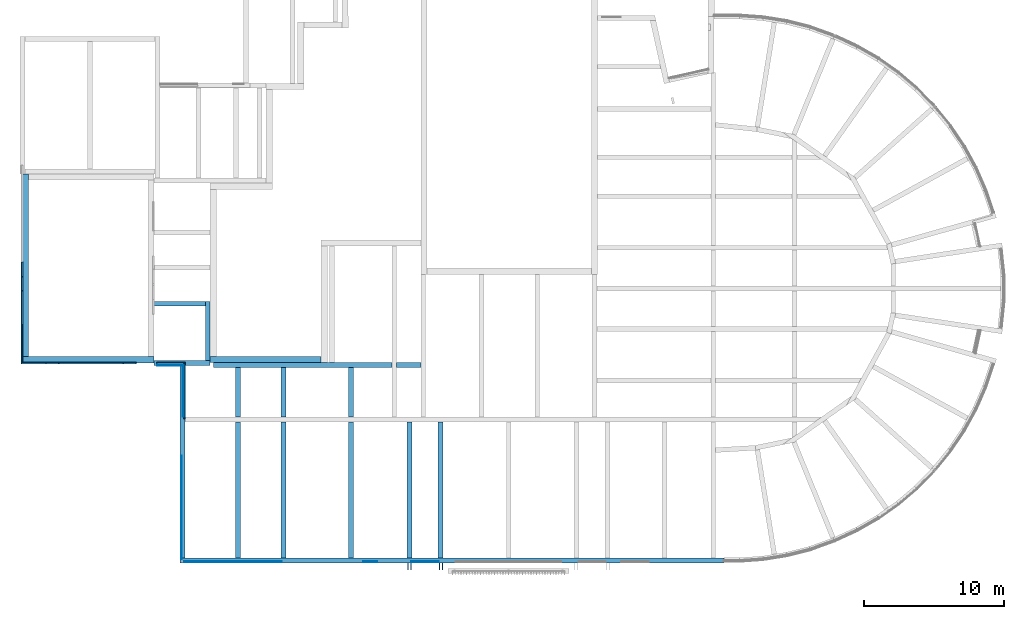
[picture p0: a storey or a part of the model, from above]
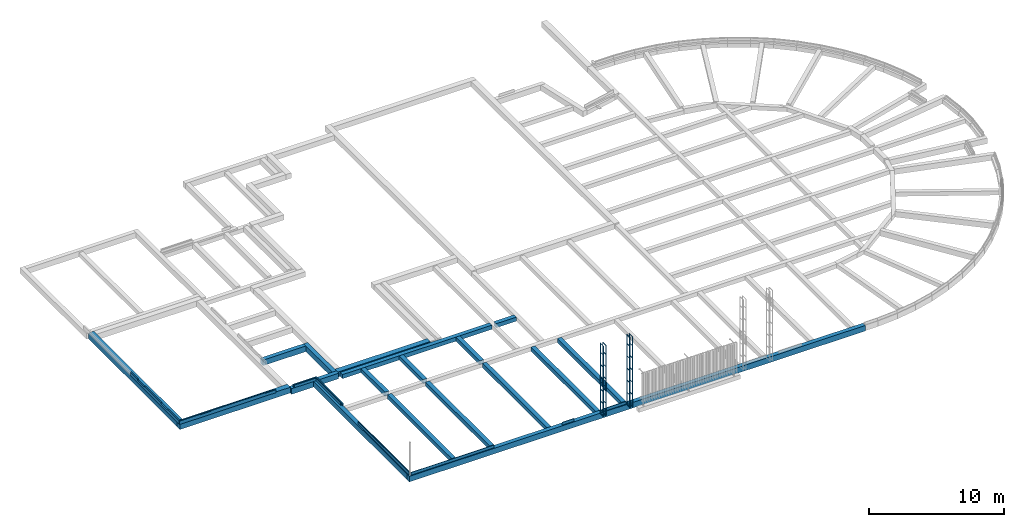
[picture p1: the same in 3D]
Properties of the parts of a building model (IFC2X3), part 1 of 13

# File
Description: ViewDefinition [CoordinationView_V2.0, QuantityTakeOffAddOnView]
File name: 6004
Time: 2023-06-22T15:44:40
Written by: The EXPRESS Data Manager Version 5.02.0100.07 : 28 Aug 2013
Made in: 21.1.70.21 - Exporter 21.1.70.21 - Alternate UI 21.1.70.21
Comment: STEP Physical File produced by: The EXPRESS Data Manager Version 5.02.0100.07 : 28 Aug 2013 * Module: EDMstepFileFactory/EDMstandAlone * Creation date: Thu Jun 22 15:44:40 2023 * Host: Erwin-HP * Database: C:\Users\hesselk\AppData\Local\Temp\bc33ba16-9f34-44f1-aad8-39bbdf71862f\c61a9778-cba0-4273-95be-3b692016d379\ifc * Database version: 5507 * Database creation date: Thu Jun 22 15:39:44 2023 * Schema: IFC2X3 * Model: DataRepository.ifc * Model creation date: Thu Jun 22 15:39:45 2023 * Header model: DataRepository.ifc_HeaderModel * Header model creation date: Thu Jun 22 15:39:45 2023 * EDMuser: sdai-user * EDMgroup: sdai-group * License ID and type: 5605 : Permanent license. Expiry date: * EDMstepFileFactory options: 020000

# IfcProject, 6004
LongName: -; Phase: -

# IfcSite, Default
RefLatitude: 42, 21, 29, 879999; RefLongitude: -71, -3, -37, -79999; RefElevation: 0 mm
Pset_ProductRequirements - Category: Project Information

# IfcBuilding, -
LongName: -
Pset_BuildingCommon - NumberOfStoreys: 6
Pset_ProductRequirements - Category: Project Information

# IfcBuildingStorey: Level:AL_Peilmaten 2.0mm (6)
In: -
Pset_ProductRequirements - Category: Levels
Name | LongName = Pset_AirSideSystemInformation, Name = Pset_ProductRequirements, Name | Elevation (mm)
ok. fundering | ok. fundering | -780
00 begane grond | 00 begane grond | -7.38712e-11
Podium | Podium | 1200
01 eerste verdieping | 01 eerste verdieping | 3070
02 tweede verdieping | 02 tweede verdieping | 6070
06 zesde verdieping | 06 zesde verdieping | 18000

# IfcSpace: Administratie voetbal 6.03:3263387, 6.03
In: 00 begane grond
LongName: Administratie voetbal; InteriorOrExteriorSpace: INTERNAL
Pset_AirSideSystemInformation - Name: Administratie voetbal
Pset_ProductRequirements - Name: Administratie voetbal; Category: Rooms
Pset_SpaceCommon - Reference: Administratie voetbal 6.03; Category: Rooms
BaseQuantities - NetFloorArea: 8.4643 m2; Height: 2438.4 mm; GrossPerimeter: 40.183 mm; GrossFloorArea: 8.4643 m2; GrossVolume: 20639.3 m3

# IfcSpace: BC A 11:6976725, 11
In: 00 begane grond
LongName: BC A; InteriorOrExteriorSpace: INTERNAL; Group: Brandveiligheid
Pset_AirSideSystemInformation - Name: BC A
Pset_ProductRequirements - Name: BC A; Category: Areas
Pset_SpaceCommon - Reference: BC A 11; Category: Areas
BaseQuantities - NetFloorArea: 449.811 m2; Height: 1200 mm; GrossPerimeter: 391.541 mm; GrossFloorArea: 449.811 m2; GrossVolume: 539773 m3

# IfcSpace: BC B 7:2298311, 7
In: 00 begane grond
LongName: BC B; InteriorOrExteriorSpace: INTERNAL; Group: Brandveiligheid
Pset_AirSideSystemInformation - Name: BC B
Pset_ProductRequirements - Name: BC B; Category: Areas
Pset_SpaceCommon - Reference: BC B 7; Category: Areas
BaseQuantities - NetFloorArea: 936.572 m2; Height: 1200 mm; GrossPerimeter: 518.34 mm; GrossFloorArea: 936.572 m2; GrossVolume: 1123886 m3

# IfcSpace: BC B 8:2298323, 8
In: 01 eerste verdieping
LongName: BC B; InteriorOrExteriorSpace: INTERNAL; Group: Brandveiligheid
Pset_AirSideSystemInformation - Name: BC B
Pset_ProductRequirements - Name: BC B; Category: Areas
Pset_SpaceCommon - Reference: BC B 8; Category: Areas
BaseQuantities - NetFloorArea: 56.1971 m2; Height: 3000 mm; GrossPerimeter: 138.341 mm; GrossFloorArea: 56.1971 m2; GrossVolume: 168591 m3

# IfcSpace: BC C 10:5124607, 10
In: 01 eerste verdieping
LongName: BC C; InteriorOrExteriorSpace: INTERNAL; Group: Brandveiligheid
Pset_AirSideSystemInformation - Name: BC C
Pset_ProductRequirements - Name: BC C; Category: Areas
Pset_SpaceCommon - Reference: BC C 10; Category: Areas
BaseQuantities - NetFloorArea: 155.31 m2; Height: 3000 mm; GrossPerimeter: 330.357 mm; GrossFloorArea: 155.31 m2; GrossVolume: 465931 m3

# IfcSpace: BC C 12:6977072, 12
In: 00 begane grond
LongName: BC C; InteriorOrExteriorSpace: INTERNAL; Group: Brandveiligheid
Pset_AirSideSystemInformation - Name: BC C
Pset_ProductRequirements - Name: BC C; Category: Areas
Pset_SpaceCommon - Reference: BC C 12; Category: Areas
BaseQuantities - NetFloorArea: 811.166 m2; Height: 1200 mm; GrossPerimeter: 441.673 mm; GrossFloorArea: 811.166 m2; GrossVolume: 973400 m3

# IfcSpace: BC D 13:6977868, 13
In: 00 begane grond
LongName: BC D; InteriorOrExteriorSpace: INTERNAL; Group: Brandveiligheid
Pset_AirSideSystemInformation - Name: BC D
Pset_ProductRequirements - Name: BC D; Category: Areas
Pset_SpaceCommon - Reference: BC D 13; Category: Areas
BaseQuantities - NetFloorArea: 117.255 m2; Height: 1200 mm; GrossPerimeter: 159.611 mm; GrossFloorArea: 117.255 m2; GrossVolume: 140705 m3

# IfcSpace: BSO 1.03:3280689, 1.03
In: 00 begane grond
LongName: BSO; InteriorOrExteriorSpace: INTERNAL
Pset_AirSideSystemInformation - Name: BSO
Pset_ProductRequirements - Name: BSO; Category: Rooms
Pset_SpaceCommon - Reference: BSO 1.03; Category: Rooms
BaseQuantities - NetFloorArea: 54.4511 m2; Height: 2438.4 mm; GrossPerimeter: 99.3768 mm; GrossFloorArea: 54.4511 m2; GrossVolume: 132774 m3

# IfcSpace: BVO 4:2298348, 4
In: 01 eerste verdieping
LongName: BVO; InteriorOrExteriorSpace: INTERNAL; Group: Brutovloeroppervlak
Pset_AirSideSystemInformation - Name: BVO
Pset_ProductRequirements - Name: BVO; Category: Areas
Pset_SpaceCommon - Reference: BVO 4; Category: Areas
BaseQuantities - NetFloorArea: 63.388 m2; Height: 3000 mm; GrossPerimeter: 143.938 mm; GrossFloorArea: 63.388 m2; GrossVolume: 190164 m3

# IfcSpace: BVO 5:2298363, 5
In: 00 begane grond
LongName: BVO; InteriorOrExteriorSpace: INTERNAL; Group: Brutovloeroppervlak
Pset_AirSideSystemInformation - Name: BVO
Pset_ProductRequirements - Name: BVO; Category: Areas
Pset_SpaceCommon - Reference: BVO 5; Category: Areas
BaseQuantities - NetFloorArea: 2433.13 m2; Height: 1200 mm; GrossPerimeter: 798.333 mm; GrossFloorArea: 2433.13 m2; GrossVolume: 2919752 m3

# IfcSpace: BVO 6:3586831, 6
In: 01 eerste verdieping
LongName: BVO; InteriorOrExteriorSpace: INTERNAL; Group: Brutovloeroppervlak
Pset_AirSideSystemInformation - Name: BVO
Pset_ProductRequirements - Name: BVO; Category: Areas
Pset_SpaceCommon - Reference: BVO 6; Category: Areas
BaseQuantities - NetFloorArea: 174.664 m2; Height: 3000 mm; GrossPerimeter: 341.474 mm; GrossFloorArea: 174.664 m2; GrossVolume: 523992 m3

# IfcSpace: Berging 11.04:3263366, 11.04
In: 00 begane grond
LongName: Berging; InteriorOrExteriorSpace: INTERNAL
Pset_AirSideSystemInformation - Name: Berging
Pset_ProductRequirements - Name: Berging; Category: Rooms
Pset_SpaceCommon - Reference: Berging 11.04; Category: Rooms
BaseQuantities - NetFloorArea: 17.4134 m2; Height: 2438.4 mm; GrossPerimeter: 57.5054 mm; GrossFloorArea: 17.4134 m2; GrossVolume: 42460.7 m3

# IfcSpace: Berging 11.05:3265393, 11.05
In: 00 begane grond
LongName: Berging; InteriorOrExteriorSpace: INTERNAL
Pset_AirSideSystemInformation - Name: Berging
Pset_ProductRequirements - Name: Berging; Category: Rooms
Pset_SpaceCommon - Reference: Berging 11.05; Category: Rooms
BaseQuantities - NetFloorArea: 8.32659 m2; Height: 2438.4 mm; GrossPerimeter: 37.8844 mm; GrossFloorArea: 8.32659 m2; GrossVolume: 20303.6 m3

# IfcSpace: Berging 11.06a:3265324, 11.06a
In: 00 begane grond
LongName: Berging; InteriorOrExteriorSpace: INTERNAL
Pset_AirSideSystemInformation - Name: Berging
Pset_ProductRequirements - Name: Berging; Category: Rooms
Pset_SpaceCommon - Reference: Berging 11.06a; Category: Rooms
BaseQuantities - NetFloorArea: 1.72208 m2; Height: 2438.4 mm; GrossPerimeter: 19.806 mm; GrossFloorArea: 1.72208 m2; GrossVolume: 4199.11 m3

# IfcSpace: Berging 11.06b:3265327, 11.06b
In: 00 begane grond
LongName: Berging; InteriorOrExteriorSpace: INTERNAL
Pset_AirSideSystemInformation - Name: Berging
Pset_ProductRequirements - Name: Berging; Category: Rooms
Pset_SpaceCommon - Reference: Berging 11.06b; Category: Rooms
BaseQuantities - NetFloorArea: 1.66091 m2; Height: 2438.4 mm; GrossPerimeter: 17.6163 mm; GrossFloorArea: 1.66091 m2; GrossVolume: 4049.96 m3

# IfcSpace: Berging 11.06c:3265330, 11.06c
In: 00 begane grond
LongName: Berging; InteriorOrExteriorSpace: INTERNAL
Pset_AirSideSystemInformation - Name: Berging
Pset_ProductRequirements - Name: Berging; Category: Rooms
Pset_SpaceCommon - Reference: Berging 11.06c; Category: Rooms
BaseQuantities - NetFloorArea: 1.66091 m2; Height: 2438.4 mm; GrossPerimeter: 17.6163 mm; GrossFloorArea: 1.66091 m2; GrossVolume: 4049.96 m3

# IfcSpace: Berging 11.06d:3265349, 11.06d
In: 00 begane grond
LongName: Berging; InteriorOrExteriorSpace: INTERNAL
Pset_AirSideSystemInformation - Name: Berging
Pset_ProductRequirements - Name: Berging; Category: Rooms
Pset_SpaceCommon - Reference: Berging 11.06d; Category: Rooms
BaseQuantities - NetFloorArea: 3.79612 m2; Height: 2438.4 mm; GrossPerimeter: 27.4507 mm; GrossFloorArea: 3.79612 m2; GrossVolume: 9256.46 m3

# IfcSpace: Berging 11.14:3268786, 11.14
In: 00 begane grond
LongName: Berging; InteriorOrExteriorSpace: INTERNAL
Pset_AirSideSystemInformation - Name: Berging
Pset_ProductRequirements - Name: Berging; Category: Rooms
Pset_SpaceCommon - Reference: Berging 11.14; Category: Rooms
BaseQuantities - NetFloorArea: 2.30979 m2; Height: 2438.4 mm; GrossPerimeter: 22.1874 mm; GrossFloorArea: 2.30979 m2; GrossVolume: 5632.2 m3

# IfcSpace: Berging 12.03:3287451, 12.03
In: 01 eerste verdieping
LongName: Berging; InteriorOrExteriorSpace: INTERNAL
Pset_AirSideSystemInformation - Name: Berging
Pset_ProductRequirements - Name: Berging; Category: Rooms
Pset_SpaceCommon - Reference: Berging 12.03; Category: Rooms
BaseQuantities - NetFloorArea: 4.04696 m2; Height: 2438.4 mm; GrossPerimeter: 30.0348 mm; GrossFloorArea: 4.04696 m2; GrossVolume: 9868.12 m3

# IfcSpace: Berging 12.04:3287454, 12.04
In: 01 eerste verdieping
LongName: Berging; InteriorOrExteriorSpace: INTERNAL
Pset_AirSideSystemInformation - Name: Berging
Pset_ProductRequirements - Name: Berging; Category: Rooms
Pset_SpaceCommon - Reference: Berging 12.04; Category: Rooms
BaseQuantities - NetFloorArea: 3.72298 m2; Height: 2438.4 mm; GrossPerimeter: 25.7972 mm; GrossFloorArea: 3.72298 m2; GrossVolume: 9078.13 m3

# IfcSpace: Berging 12.05:3287457, 12.05
In: 01 eerste verdieping
LongName: Berging; InteriorOrExteriorSpace: INTERNAL
Pset_AirSideSystemInformation - Name: Berging
Pset_ProductRequirements - Name: Berging; Category: Rooms
Pset_SpaceCommon - Reference: Berging 12.05; Category: Rooms
BaseQuantities - NetFloorArea: 3.72299 m2; Height: 2438.4 mm; GrossPerimeter: 25.7972 mm; GrossFloorArea: 3.72299 m2; GrossVolume: 9078.13 m3

# IfcSpace: Berging 4.07:3268208, 4.07
In: 00 begane grond
LongName: Berging; InteriorOrExteriorSpace: INTERNAL
Pset_AirSideSystemInformation - Name: Berging
Pset_ProductRequirements - Name: Berging; Category: Rooms
Pset_SpaceCommon - Reference: Berging 4.07; Category: Rooms
BaseQuantities - NetFloorArea: 10.9433 m2; Height: 2438.4 mm; GrossPerimeter: 43.0378 mm; GrossFloorArea: 10.9433 m2; GrossVolume: 26684.2 m3

# IfcSpace: Berging 4.08:4949645, 4.08
In: 00 begane grond
LongName: Berging; InteriorOrExteriorSpace: INTERNAL
Pset_AirSideSystemInformation - Name: Berging
Pset_ProductRequirements - Name: Berging; Category: Rooms
Pset_SpaceCommon - Reference: Berging 4.08; Category: Rooms
BaseQuantities - NetFloorArea: 2.02933 m2; Height: 2438.4 mm; GrossPerimeter: 18.7009 mm; GrossFloorArea: 2.02933 m2; GrossVolume: 4948.33 m3

# IfcSpace: Berging 5.01:3268748, 5.01
In: 00 begane grond
LongName: Berging; InteriorOrExteriorSpace: INTERNAL
Pset_AirSideSystemInformation - Name: Berging
Pset_ProductRequirements - Name: Berging; Category: Rooms
Pset_SpaceCommon - Reference: Berging 5.01; Category: Rooms
BaseQuantities - NetFloorArea: 12.0563 m2; Height: 2438.4 mm; GrossPerimeter: 50.4788 mm; GrossFloorArea: 12.0563 m2; GrossVolume: 29398 m3

# IfcSpace: Berging 7.05:3265260, 7.05
In: 00 begane grond
LongName: Berging; InteriorOrExteriorSpace: INTERNAL
Pset_AirSideSystemInformation - Name: Berging
Pset_ProductRequirements - Name: Berging; Category: Rooms
Pset_SpaceCommon - Reference: Berging 7.05; Category: Rooms
BaseQuantities - NetFloorArea: 9.78041 m2; Height: 2438.4 mm; GrossPerimeter: 46.732 mm; GrossFloorArea: 9.78041 m2; GrossVolume: 23848.6 m3

# IfcSpace: Berging 8.02b:3311547, 8.02b
In: 00 begane grond
LongName: Berging; InteriorOrExteriorSpace: INTERNAL
Pset_AirSideSystemInformation - Name: Berging
Pset_ProductRequirements - Name: Berging; Category: Rooms
Pset_SpaceCommon - Reference: Berging 8.02b; Category: Rooms
BaseQuantities - NetFloorArea: 2.63612 m2; Height: 3638.4 mm; GrossPerimeter: 21.5312 mm; GrossFloorArea: 2.63612 m2; GrossVolume: 9591.27 m3

# IfcSpace: Berging 8.02c:7828705, 8.02c
In: 00 begane grond
LongName: Berging; InteriorOrExteriorSpace: INTERNAL
Pset_AirSideSystemInformation - Name: Berging
Pset_ProductRequirements - Name: Berging; Category: Rooms
Pset_SpaceCommon - Reference: Berging 8.02c; Category: Rooms
BaseQuantities - NetFloorArea: 2.60797 m2; Height: 2438.4 mm; GrossPerimeter: 21.4609 mm; GrossFloorArea: 2.60797 m2; GrossVolume: 6359.27 m3

# IfcSpace: Berging 8.05:3380008, 8.05
In: 00 begane grond
LongName: Berging; InteriorOrExteriorSpace: INTERNAL
Pset_AirSideSystemInformation - Name: Berging
Pset_ProductRequirements - Name: Berging; Category: Rooms
Pset_SpaceCommon - Reference: Berging 8.05; Category: Rooms
BaseQuantities - NetFloorArea: 8.00827 m2; Height: 3638.4 mm; GrossPerimeter: 37.4456 mm; GrossFloorArea: 8.00827 m2; GrossVolume: 29137.3 m3

# IfcSpace: Berging 8.07:3392395, 8.07
In: 00 begane grond
LongName: Berging; InteriorOrExteriorSpace: INTERNAL
Pset_AirSideSystemInformation - Name: Berging
Pset_ProductRequirements - Name: Berging; Category: Rooms
Pset_SpaceCommon - Reference: Berging 8.07; Category: Rooms
BaseQuantities - NetFloorArea: 1.7259 m2; Height: 3638.4 mm; GrossPerimeter: 17.383 mm; GrossFloorArea: 1.7259 m2; GrossVolume: 6279.52 m3

# IfcSpace: Berging 8.08:3392398, 8.08
In: 00 begane grond
LongName: Berging; InteriorOrExteriorSpace: INTERNAL
Pset_AirSideSystemInformation - Name: Berging
Pset_ProductRequirements - Name: Berging; Category: Rooms
Pset_SpaceCommon - Reference: Berging 8.08; Category: Rooms
BaseQuantities - NetFloorArea: 4.03924 m2; Height: 3638.4 mm; GrossPerimeter: 27.6343 mm; GrossFloorArea: 4.03924 m2; GrossVolume: 14696.4 m3

# IfcSpace: Berging PSZ 14.01:11128473, 14.01
In: 00 begane grond
LongName: Berging PSZ; InteriorOrExteriorSpace: INTERNAL
Pset_AirSideSystemInformation - Name: Berging PSZ
Pset_ProductRequirements - Name: Berging PSZ; Category: Rooms
Pset_SpaceCommon - Reference: Berging PSZ 14.01; Category: Rooms
BaseQuantities - NetFloorArea: 4.39434 m2; Height: 2438.4 mm; GrossPerimeter: 28.0441 mm; GrossFloorArea: 4.39434 m2; GrossVolume: 10715.2 m3

# IfcSpace: Berging VV Jistrum 12.02:3287445, 12.02
In: 01 eerste verdieping
LongName: Berging VV Jistrum; InteriorOrExteriorSpace: INTERNAL
Pset_AirSideSystemInformation - Name: Berging VV Jistrum
Pset_ProductRequirements - Name: Berging VV Jistrum; Category: Rooms
Pset_SpaceCommon - Reference: Berging VV Jistrum 12.02; Category: Rooms
BaseQuantities - NetFloorArea: 16.7621 m2; Height: 2438.4 mm; GrossPerimeter: 62.2256 mm; GrossFloorArea: 16.7621 m2; GrossVolume: 40872.6 m3

# IfcSpace: Berging onderbouw 14.02:11859632, 14.02
In: 00 begane grond
LongName: Berging onderbouw; InteriorOrExteriorSpace: INTERNAL
Pset_AirSideSystemInformation - Name: Berging onderbouw
Pset_ProductRequirements - Name: Berging onderbouw; Category: Rooms
Pset_SpaceCommon - Reference: Berging onderbouw 14.02; Category: Rooms
BaseQuantities - NetFloorArea: 4.3973 m2; Height: 2438.4 mm; GrossPerimeter: 28.0517 mm; GrossFloorArea: 4.3973 m2; GrossVolume: 10722.4 m3

# IfcSpace: Berging voetbalvereniging 25:7525867, 25
In: 00 begane grond
LongName: Berging voetbalvereniging; InteriorOrExteriorSpace: INTERNAL; Group: Gebruiksfuncties
Pset_AirSideSystemInformation - Name: Berging voetbalvereniging
Pset_ProductRequirements - Name: Berging voetbalvereniging; Category: Areas
Pset_SpaceCommon - Reference: Berging voetbalvereniging 25; Category: Areas
BaseQuantities - NetFloorArea: 22.8241 m2; Height: 1200 mm; GrossPerimeter: 63.2824 mm; GrossFloorArea: 22.8241 m2; GrossVolume: 27389 m3

# IfcSpace: Bergingen + technische ruimtes 20:3609457, 20
In: 01 eerste verdieping
LongName: Bergingen + technische ruimtes; InteriorOrExteriorSpace: INTERNAL; Group: Gebruiksfuncties
Pset_AirSideSystemInformation - Name: Bergingen + technische ruimtes
Pset_ProductRequirements - Name: Bergingen + technische ruimtes; Category: Areas
Pset_SpaceCommon - Reference: Bergingen + technische ruimtes 20; Category: Areas
BaseQuantities - NetFloorArea: 166.087 m2; Height: 3000 mm; GrossPerimeter: 340.479 mm; GrossFloorArea: 166.087 m2; GrossVolume: 498261 m3

# IfcSpace: Bergingen 19:3606235, 19
In: 01 eerste verdieping
LongName: Bergingen; InteriorOrExteriorSpace: INTERNAL; Group: Gebruiksfuncties
Pset_AirSideSystemInformation - Name: Bergingen
Pset_ProductRequirements - Name: Bergingen; Category: Areas
Pset_SpaceCommon - Reference: Bergingen 19; Category: Areas
BaseQuantities - NetFloorArea: 54.2789 m2; Height: 3000 mm; GrossPerimeter: 153.587 mm; GrossFloorArea: 54.2789 m2; GrossVolume: 162837 m3

# IfcSpace: Bergruimte 1.04:3265390, 1.04
In: 00 begane grond
LongName: Bergruimte; InteriorOrExteriorSpace: INTERNAL
Pset_AirSideSystemInformation - Name: Bergruimte
Pset_ProductRequirements - Name: Bergruimte; Category: Rooms
Pset_SpaceCommon - Reference: Bergruimte 1.04; Category: Rooms
BaseQuantities - NetFloorArea: 5.01886 m2; Height: 2438.4 mm; GrossPerimeter: 31.8309 mm; GrossFloorArea: 5.01886 m2; GrossVolume: 12238 m3

# IfcSpace: Bergruimte 1.06:3265959, 1.06
In: 00 begane grond
LongName: Bergruimte; InteriorOrExteriorSpace: INTERNAL
Pset_AirSideSystemInformation - Name: Bergruimte
Pset_ProductRequirements - Name: Bergruimte; Category: Rooms
Pset_SpaceCommon - Reference: Bergruimte 1.06; Category: Rooms
BaseQuantities - NetFloorArea: 2.2577 m2; Height: 2438.4 mm; GrossPerimeter: 19.773 mm; GrossFloorArea: 2.2577 m2; GrossVolume: 5505.17 m3

# IfcSpace: Bergruimte muziekinstrumenten 9.01:3264976, 9.01
In: 00 begane grond
LongName: Bergruimte muziekinstrumenten; InteriorOrExteriorSpace: INTERNAL
Pset_AirSideSystemInformation - Name: Bergruimte muziekinstrumenten
Pset_ProductRequirements - Name: Bergruimte muziekinstrumenten; Category: Rooms
Pset_SpaceCommon - Reference: Bergruimte muziekinstrumenten 9.01; Category: Rooms
BaseQuantities - NetFloorArea: 20.3807 m2; Height: 2438.4 mm; GrossPerimeter: 60.1711 mm; GrossFloorArea: 20.3807 m2; GrossVolume: 49696.3 m3

# IfcSpace: Bergruimte toneelver. 10.01:3264979, 10.01
In: 00 begane grond
LongName: Bergruimte toneelver.; InteriorOrExteriorSpace: INTERNAL
Pset_AirSideSystemInformation - Name: Bergruimte toneelver.
Pset_ProductRequirements - Name: Bergruimte toneelver.; Category: Rooms
Pset_SpaceCommon - Reference: Bergruimte toneelver. 10.01; Category: Rooms
BaseQuantities - NetFloorArea: 18.8235 m2; Height: 2438.4 mm; GrossPerimeter: 57.2158 mm; GrossFloorArea: 18.8235 m2; GrossVolume: 45899.2 m3

# IfcSpace: Bestaande CV 8.06:3380005, 8.06
In: 00 begane grond
LongName: Bestaande CV; InteriorOrExteriorSpace: INTERNAL
Pset_AirSideSystemInformation - Name: Bestaande CV
Pset_ProductRequirements - Name: Bestaande CV; Category: Rooms
Pset_SpaceCommon - Reference: Bestaande CV 8.06; Category: Rooms
BaseQuantities - NetFloorArea: 5.72609 m2; Height: 3638.4 mm; GrossPerimeter: 30.5749 mm; GrossFloorArea: 5.72609 m2; GrossVolume: 20833.8 m3

# IfcSpace: Bestuurskamer / fysio 6.02:3263384, 6.02
In: 00 begane grond
LongName: Bestuurskamer / fysio; InteriorOrExteriorSpace: INTERNAL
Pset_AirSideSystemInformation - Name: Bestuurskamer / fysio
Pset_ProductRequirements - Name: Bestuurskamer / fysio; Category: Rooms
Pset_SpaceCommon - Reference: Bestuurskamer / fysio 6.02; Category: Rooms
BaseQuantities - NetFloorArea: 20.3856 m2; Height: 2438.4 mm; GrossPerimeter: 64.5981 mm; GrossFloorArea: 20.3856 m2; GrossVolume: 49708.3 m3

# IfcSpace: Bestuurskamer 7:3588425, 7
In: 00 begane grond
LongName: Bestuurskamer; InteriorOrExteriorSpace: INTERNAL; Group: Gebruiksfuncties
Pset_AirSideSystemInformation - Name: Bestuurskamer
Pset_ProductRequirements - Name: Bestuurskamer; Category: Areas
Pset_SpaceCommon - Reference: Bestuurskamer 7; Category: Areas
BaseQuantities - NetFloorArea: 47.44 m2; Height: 1200 mm; GrossPerimeter: 110.481 mm; GrossFloorArea: 47.44 m2; GrossVolume: 56928 m3

# IfcSpace: Buitenberging school 13.06:11094313, 13.06
In: 00 begane grond
LongName: Buitenberging school; InteriorOrExteriorSpace: INTERNAL
Pset_AirSideSystemInformation - Name: Buitenberging school
Pset_ProductRequirements - Name: Buitenberging school; Category: Rooms
Pset_SpaceCommon - Reference: Buitenberging school 13.06; Category: Rooms
BaseQuantities - NetFloorArea: 11.5448 m2; Height: 2438.4 mm; GrossPerimeter: 44.7064 mm; GrossFloorArea: 11.5448 m2; GrossVolume: 28150.7 m3

# IfcSpace: Centrale hal 4.01a:3309832, 4.01a
In: 00 begane grond
LongName: Centrale hal; InteriorOrExteriorSpace: INTERNAL
Pset_AirSideSystemInformation - Name: Centrale hal
Pset_ProductRequirements - Name: Centrale hal; Category: Rooms
Pset_SpaceCommon - Reference: Centrale hal 4.01a; Category: Rooms
BaseQuantities - NetFloorArea: 149.393 m2; Height: 3638.4 mm; GrossPerimeter: 235.245 mm; GrossFloorArea: 149.393 m2; GrossVolume: 543553 m3

# IfcSpace: Containerberging school 13.07:11094310, 13.07
In: 00 begane grond
LongName: Containerberging school; InteriorOrExteriorSpace: INTERNAL
Pset_AirSideSystemInformation - Name: Containerberging school
Pset_ProductRequirements - Name: Containerberging school; Category: Rooms
Pset_SpaceCommon - Reference: Containerberging school 13.07; Category: Rooms
BaseQuantities - NetFloorArea: 6.15039 m2; Height: 2438.4 mm; GrossPerimeter: 35.0148 mm; GrossFloorArea: 6.15039 m2; GrossVolume: 14997.1 m3

# IfcSpace: Directie 3.01:3269067, 3.01
In: 00 begane grond
LongName: Directie; InteriorOrExteriorSpace: INTERNAL
Pset_AirSideSystemInformation - Name: Directie
Pset_ProductRequirements - Name: Directie; Category: Rooms
Pset_SpaceCommon - Reference: Directie 3.01; Category: Rooms
BaseQuantities - NetFloorArea: 8.87652 m2; Height: 2438.4 mm; GrossPerimeter: 39.2078 mm; GrossFloorArea: 8.87652 m2; GrossVolume: 21644.5 m3

# IfcSpace: Douche 6.01a:3265178, 6.01a
In: 00 begane grond
LongName: Douche; InteriorOrExteriorSpace: INTERNAL
Pset_AirSideSystemInformation - Name: Douche
Pset_ProductRequirements - Name: Douche; Category: Rooms
Pset_SpaceCommon - Reference: Douche 6.01a; Category: Rooms
BaseQuantities - NetFloorArea: 10.0789 m2; Height: 2438.4 mm; GrossPerimeter: 50.229 mm; GrossFloorArea: 10.0789 m2; GrossVolume: 24576.4 m3

# IfcSpace: Douche 6.01b:3265175, 6.01b
In: 00 begane grond
LongName: Douche; InteriorOrExteriorSpace: INTERNAL
Pset_AirSideSystemInformation - Name: Douche
Pset_ProductRequirements - Name: Douche; Category: Rooms
Pset_SpaceCommon - Reference: Douche 6.01b; Category: Rooms
BaseQuantities - NetFloorArea: 10.0927 m2; Height: 2438.4 mm; GrossPerimeter: 50.3743 mm; GrossFloorArea: 10.0927 m2; GrossVolume: 24609.9 m3

# IfcSpace: Douche 6.01c:3264598, 6.01c
In: 00 begane grond
LongName: Douche; InteriorOrExteriorSpace: INTERNAL
Pset_AirSideSystemInformation - Name: Douche
Pset_ProductRequirements - Name: Douche; Category: Rooms
Pset_SpaceCommon - Reference: Douche 6.01c; Category: Rooms
BaseQuantities - NetFloorArea: 8.40022 m2; Height: 2438.4 mm; GrossPerimeter: 38.129 mm; GrossFloorArea: 8.40022 m2; GrossVolume: 20483.1 m3

# IfcSpace: Douche 6.01d:3264601, 6.01d
In: 00 begane grond
LongName: Douche; InteriorOrExteriorSpace: INTERNAL
Pset_AirSideSystemInformation - Name: Douche
Pset_ProductRequirements - Name: Douche; Category: Rooms
Pset_SpaceCommon - Reference: Douche 6.01d; Category: Rooms
BaseQuantities - NetFloorArea: 8.40942 m2; Height: 2438.4 mm; GrossPerimeter: 38.1579 mm; GrossFloorArea: 8.40942 m2; GrossVolume: 20505.5 m3

# IfcSpace: Entree 1.12:3392424, 1.12
In: 00 begane grond
LongName: Entree; InteriorOrExteriorSpace: INTERNAL
Pset_AirSideSystemInformation - Name: Entree
Pset_ProductRequirements - Name: Entree; Category: Rooms
Pset_SpaceCommon - Reference: Entree 1.12; Category: Rooms
BaseQuantities - NetFloorArea: 9.98155 m2; Height: 3638.4 mm; GrossPerimeter: 49.3727 mm; GrossFloorArea: 9.98155 m2; GrossVolume: 36316.9 m3

# IfcSpace: Entree 2.06:3392420, 2.06
In: 00 begane grond
LongName: Entree; InteriorOrExteriorSpace: INTERNAL
Pset_AirSideSystemInformation - Name: Entree
Pset_ProductRequirements - Name: Entree; Category: Rooms
Pset_SpaceCommon - Reference: Entree 2.06; Category: Rooms
BaseQuantities - NetFloorArea: 9.9318 m2; Height: 3638.4 mm; GrossPerimeter: 49.1059 mm; GrossFloorArea: 9.9318 m2; GrossVolume: 36135.9 m3

# IfcSpace: Entree 7.02:3302024, 7.02
In: 00 begane grond
LongName: Entree; InteriorOrExteriorSpace: INTERNAL
Pset_AirSideSystemInformation - Name: Entree
Pset_ProductRequirements - Name: Entree; Category: Rooms
Pset_SpaceCommon - Reference: Entree 7.02; Category: Rooms
BaseQuantities - NetFloorArea: 27.2496 m2; Height: 2438.4 mm; GrossPerimeter: 95.6493 mm; GrossFloorArea: 27.2496 m2; GrossVolume: 66445.4 m3

# IfcSpace: Entree 8.04:3307013, 8.04
In: 00 begane grond
LongName: Entree; InteriorOrExteriorSpace: INTERNAL
Pset_AirSideSystemInformation - Name: Entree
Pset_ProductRequirements - Name: Entree; Category: Rooms
Pset_SpaceCommon - Reference: Entree 8.04; Category: Rooms
BaseQuantities - NetFloorArea: 20.4821 m2; Height: 2438.4 mm; GrossPerimeter: 84.1245 mm; GrossFloorArea: 20.4821 m2; GrossVolume: 49943.6 m3

# IfcSpace: Expo ruimte 4.02a:4339103, 4.02a
In: 00 begane grond
LongName: Expo ruimte; InteriorOrExteriorSpace: INTERNAL
Pset_AirSideSystemInformation - Name: Expo ruimte
Pset_ProductRequirements - Name: Expo ruimte; Category: Rooms
Pset_SpaceCommon - Reference: Expo ruimte 4.02a; Category: Rooms
BaseQuantities - NetFloorArea: 1.94208 m2; Height: 2438.4 mm; GrossPerimeter: 26.6027 mm; GrossFloorArea: 1.94208 m2; GrossVolume: 4735.58 m3

# IfcSpace: Expo ruimte 4.02b:4339106, 4.02b
In: 00 begane grond
LongName: Expo ruimte; InteriorOrExteriorSpace: INTERNAL
Pset_AirSideSystemInformation - Name: Expo ruimte
Pset_ProductRequirements - Name: Expo ruimte; Category: Rooms
Pset_SpaceCommon - Reference: Expo ruimte 4.02b; Category: Rooms
BaseQuantities - NetFloorArea: 1.94125 m2; Height: 2438.4 mm; GrossPerimeter: 26.5928 mm; GrossFloorArea: 1.94125 m2; GrossVolume: 4733.55 m3

# IfcSpace: Expo ruimte 4.02d:3265968, 4.02d
In: 00 begane grond
LongName: Expo ruimte; InteriorOrExteriorSpace: INTERNAL
Pset_AirSideSystemInformation - Name: Expo ruimte
Pset_ProductRequirements - Name: Expo ruimte; Category: Rooms
Pset_SpaceCommon - Reference: Expo ruimte 4.02d; Category: Rooms
BaseQuantities - NetFloorArea: 1.79453 m2; Height: 2438.4 mm; GrossPerimeter: 24.7865 mm; GrossFloorArea: 1.79453 m2; GrossVolume: 4375.78 m3

# IfcSpace: GO Kinderdagverblijf 18:3634405, 18
In: 00 begane grond
LongName: GO Kinderdagverblijf; InteriorOrExteriorSpace: INTERNAL; Group: Gebruiksoppervlak
Pset_AirSideSystemInformation - Name: GO Kinderdagverblijf
Pset_ProductRequirements - Name: GO Kinderdagverblijf; Category: Areas
Pset_SpaceCommon - Reference: GO Kinderdagverblijf 18; Category: Areas
BaseQuantities - NetFloorArea: 86.8328 m2; Height: 1200 mm; GrossPerimeter: 136.242 mm; GrossFloorArea: 86.8328 m2; GrossVolume: 104199 m3

# IfcSpace: GO Kleedkamers 1 11:3630911, 11
In: 00 begane grond
LongName: GO Kleedkamers 1; InteriorOrExteriorSpace: INTERNAL; Group: Gebruiksoppervlak
Pset_AirSideSystemInformation - Name: GO Kleedkamers 1
Pset_ProductRequirements - Name: GO Kleedkamers 1; Category: Areas
Pset_SpaceCommon - Reference: GO Kleedkamers 1 11; Category: Areas
BaseQuantities - NetFloorArea: 48.8225 m2; Height: 1200 mm; GrossPerimeter: 94.2855 mm; GrossFloorArea: 48.8225 m2; GrossVolume: 58587 m3

# IfcSpace: GO Kleedkamers 2 14:3632022, 14
In: 00 begane grond
LongName: GO Kleedkamers 2; InteriorOrExteriorSpace: INTERNAL; Group: Gebruiksoppervlak
Pset_AirSideSystemInformation - Name: GO Kleedkamers 2
Pset_ProductRequirements - Name: GO Kleedkamers 2; Category: Areas
Pset_SpaceCommon - Reference: GO Kleedkamers 2 14; Category: Areas
BaseQuantities - NetFloorArea: 60.3817 m2; Height: 1200 mm; GrossPerimeter: 101.976 mm; GrossFloorArea: 60.3817 m2; GrossVolume: 72458 m3

# IfcSpace: GO Podium + zaal 15:3632874, 15
In: 00 begane grond
LongName: GO Podium + zaal; InteriorOrExteriorSpace: INTERNAL; Group: Gebruiksoppervlak
Pset_AirSideSystemInformation - Name: GO Podium + zaal
Pset_ProductRequirements - Name: GO Podium + zaal; Category: Areas
Pset_SpaceCommon - Reference: GO Podium + zaal 15; Category: Areas
BaseQuantities - NetFloorArea: 332.83 m2; Height: 1200 mm; GrossPerimeter: 334.996 mm; GrossFloorArea: 332.83 m2; GrossVolume: 399396 m3

# IfcSpace: GO Soosruimte 12:3631570, 12
In: 00 begane grond
LongName: GO Soosruimte; InteriorOrExteriorSpace: INTERNAL; Group: Gebruiksoppervlak
Pset_AirSideSystemInformation - Name: GO Soosruimte
Pset_ProductRequirements - Name: GO Soosruimte; Category: Areas
Pset_SpaceCommon - Reference: GO Soosruimte 12; Category: Areas
BaseQuantities - NetFloorArea: 90.2493 m2; Height: 1200 mm; GrossPerimeter: 132.764 mm; GrossFloorArea: 90.2493 m2; GrossVolume: 108299 m3

# IfcSpace: GO Sportzaal + kleedkamers 16:3633730, 16
In: 00 begane grond
LongName: GO Sportzaal + kleedkamers; InteriorOrExteriorSpace: INTERNAL; Group: Gebruiksoppervlak
Pset_AirSideSystemInformation - Name: GO Sportzaal + kleedkamers
Pset_ProductRequirements - Name: GO Sportzaal + kleedkamers; Category: Areas
Pset_SpaceCommon - Reference: GO Sportzaal + kleedkamers 16; Category: Areas
BaseQuantities - NetFloorArea: 402.83 m2; Height: 1200 mm; GrossPerimeter: 289.97 mm; GrossFloorArea: 402.83 m2; GrossVolume: 483395 m3

# IfcSpace: GO Vergaderkamer 13:3631810, 13
In: 00 begane grond
LongName: GO Vergaderkamer; InteriorOrExteriorSpace: INTERNAL; Group: Gebruiksoppervlak
Pset_AirSideSystemInformation - Name: GO Vergaderkamer
Pset_ProductRequirements - Name: GO Vergaderkamer; Category: Areas
Pset_SpaceCommon - Reference: GO Vergaderkamer 13; Category: Areas
BaseQuantities - NetFloorArea: 24.8009 m2; Height: 1200 mm; GrossPerimeter: 66.0152 mm; GrossFloorArea: 24.8009 m2; GrossVolume: 29761 m3

# IfcSpace: GO bergingen 7:3624988, 7
In: 01 eerste verdieping
LongName: GO bergingen; InteriorOrExteriorSpace: INTERNAL; Group: Gebruiksoppervlak
Pset_AirSideSystemInformation - Name: GO bergingen
Pset_ProductRequirements - Name: GO bergingen; Category: Areas
Pset_SpaceCommon - Reference: GO bergingen 7; Category: Areas
BaseQuantities - NetFloorArea: 50.2033 m2; Height: 3000 mm; GrossPerimeter: 151.056 mm; GrossFloorArea: 50.2033 m2; GrossVolume: 150610 m3

# IfcSpace: GO bergingen en technische ruimtes 8:3625776, 8
In: 01 eerste verdieping
LongName: GO bergingen en technische ruimtes; InteriorOrExteriorSpace: INTERNAL; Group: Gebruiksoppervlak
Pset_AirSideSystemInformation - Name: GO bergingen en technische ruimtes
Pset_ProductRequirements - Name: GO bergingen en technische ruimtes; Category: Areas
Pset_SpaceCommon - Reference: GO bergingen en technische ruimtes 8; Category: Areas
BaseQuantities - NetFloorArea: 156.093 m2; Height: 3000 mm; GrossPerimeter: 331.513 mm; GrossFloorArea: 156.093 m2; GrossVolume: 468279 m3

# IfcSpace: GO bestuurskamer 10:3630716, 10
In: 00 begane grond
LongName: GO bestuurskamer; InteriorOrExteriorSpace: INTERNAL; Group: Gebruiksoppervlak
Pset_AirSideSystemInformation - Name: GO bestuurskamer
Pset_ProductRequirements - Name: GO bestuurskamer; Category: Areas
Pset_SpaceCommon - Reference: GO bestuurskamer 10; Category: Areas
BaseQuantities - NetFloorArea: 64.8273 m2; Height: 1200 mm; GrossPerimeter: 151.338 mm; GrossFloorArea: 64.8273 m2; GrossVolume: 77792.8 m3

# IfcSpace: GO gang + bergingen 21:3637358, 21
In: 00 begane grond
LongName: GO gang + bergingen; InteriorOrExteriorSpace: INTERNAL; Group: Gebruiksoppervlak
Pset_AirSideSystemInformation - Name: GO gang + bergingen
Pset_ProductRequirements - Name: GO gang + bergingen; Category: Areas
Pset_SpaceCommon - Reference: GO gang + bergingen 21; Category: Areas
BaseQuantities - NetFloorArea: 142.781 m2; Height: 1200 mm; GrossPerimeter: 366.114 mm; GrossFloorArea: 142.781 m2; GrossVolume: 171337 m3

# IfcSpace: GO gang 20:3636409, 20
In: 00 begane grond
LongName: GO gang; InteriorOrExteriorSpace: INTERNAL; Group: Gebruiksoppervlak
Pset_AirSideSystemInformation - Name: GO gang
Pset_ProductRequirements - Name: GO gang; Category: Areas
Pset_SpaceCommon - Reference: GO gang 20; Category: Areas
BaseQuantities - NetFloorArea: 25.6534 m2; Height: 1200 mm; GrossPerimeter: 107.547 mm; GrossFloorArea: 25.6534 m2; GrossVolume: 30784 m3

# IfcSpace: GO school 19:3635566, 19
In: 00 begane grond
LongName: GO school; InteriorOrExteriorSpace: INTERNAL; Group: Gebruiksoppervlak
Pset_AirSideSystemInformation - Name: GO school
Pset_ProductRequirements - Name: GO school; Category: Areas
Pset_SpaceCommon - Reference: GO school 19; Category: Areas
BaseQuantities - NetFloorArea: 794.133 m2; Height: 1200 mm; GrossPerimeter: 424.925 mm; GrossFloorArea: 794.133 m2; GrossVolume: 952960 m3

# IfcSpace: GO sportkantine 5:2298405, 5
In: 00 begane grond
LongName: GO sportkantine; InteriorOrExteriorSpace: INTERNAL; Group: Gebruiksoppervlak
Pset_AirSideSystemInformation - Name: GO sportkantine
Pset_ProductRequirements - Name: GO sportkantine; Category: Areas
Pset_SpaceCommon - Reference: GO sportkantine 5; Category: Areas
BaseQuantities - NetFloorArea: 214.636 m2; Height: 1200 mm; GrossPerimeter: 204.04 mm; GrossFloorArea: 214.636 m2; GrossVolume: 257564 m3

# IfcSpace: GO technische ruimtes 17:3634043, 17
In: 00 begane grond
LongName: GO technische ruimtes; InteriorOrExteriorSpace: INTERNAL; Group: Gebruiksoppervlak
Pset_AirSideSystemInformation - Name: GO technische ruimtes
Pset_ProductRequirements - Name: GO technische ruimtes; Category: Areas
Pset_SpaceCommon - Reference: GO technische ruimtes 17; Category: Areas
BaseQuantities - NetFloorArea: 13.773 m2; Height: 1200 mm; GrossPerimeter: 52.7448 mm; GrossFloorArea: 13.773 m2; GrossVolume: 16527.6 m3

# IfcSpace: Gang + Bergingen + toilet 16:3604358, 16
In: 00 begane grond
LongName: Gang + Bergingen + toilet; InteriorOrExteriorSpace: INTERNAL; Group: Gebruiksfuncties
Pset_AirSideSystemInformation - Name: Gang + Bergingen + toilet
Pset_ProductRequirements - Name: Gang + Bergingen + toilet; Category: Areas
Pset_SpaceCommon - Reference: Gang + Bergingen + toilet 16; Category: Areas
BaseQuantities - NetFloorArea: 160.273 m2; Height: 1200 mm; GrossPerimeter: 312.356 mm; GrossFloorArea: 160.273 m2; GrossVolume: 192328 m3

# IfcSpace: Gang 1.09a:3265369, 1.09a
In: 00 begane grond
LongName: Gang; InteriorOrExteriorSpace: INTERNAL
Pset_AirSideSystemInformation - Name: Gang
Pset_ProductRequirements - Name: Gang; Category: Rooms
Pset_SpaceCommon - Reference: Gang 1.09a; Category: Rooms
BaseQuantities - NetFloorArea: 14.3951 m2; Height: 2438.4 mm; GrossPerimeter: 63.717 mm; GrossFloorArea: 14.3951 m2; GrossVolume: 35101 m3

# IfcSpace: Gang 1.09b:3265378, 1.09b
In: 00 begane grond
LongName: Gang; InteriorOrExteriorSpace: INTERNAL
Pset_AirSideSystemInformation - Name: Gang
Pset_ProductRequirements - Name: Gang; Category: Rooms
Pset_SpaceCommon - Reference: Gang 1.09b; Category: Rooms
BaseQuantities - NetFloorArea: 6.18488 m2; Height: 2438.4 mm; GrossPerimeter: 34.9854 mm; GrossFloorArea: 6.18488 m2; GrossVolume: 15081.2 m3

# IfcSpace: Gang 11.08:3263378, 11.08
In: 00 begane grond
LongName: Gang; InteriorOrExteriorSpace: INTERNAL
Pset_AirSideSystemInformation - Name: Gang
Pset_ProductRequirements - Name: Gang; Category: Rooms
Pset_SpaceCommon - Reference: Gang 11.08; Category: Rooms
BaseQuantities - NetFloorArea: 60.6761 m2; Height: 2438.4 mm; GrossPerimeter: 150.511 mm; GrossFloorArea: 60.6761 m2; GrossVolume: 147953 m3

# IfcSpace: Gang 12.01:3287448, 12.01
In: 01 eerste verdieping
LongName: Gang; InteriorOrExteriorSpace: INTERNAL
Pset_AirSideSystemInformation - Name: Gang
Pset_ProductRequirements - Name: Gang; Category: Rooms
Pset_SpaceCommon - Reference: Gang 12.01; Category: Rooms
BaseQuantities - NetFloorArea: 10.2709 m2; Height: 2438.4 mm; GrossPerimeter: 57.126 mm; GrossFloorArea: 10.2709 m2; GrossVolume: 25044.6 m3

# IfcSpace: Gang 24:3628824, 24
In: 00 begane grond
LongName: Gang; InteriorOrExteriorSpace: INTERNAL; Group: Gebruiksfuncties
Pset_AirSideSystemInformation - Name: Gang
Pset_ProductRequirements - Name: Gang; Category: Areas
Pset_SpaceCommon - Reference: Gang 24; Category: Areas
BaseQuantities - NetFloorArea: 28.2008 m2; Height: 1200 mm; GrossPerimeter: 110.242 mm; GrossFloorArea: 28.2008 m2; GrossVolume: 33840.9 m3

# IfcSpace: Gang 5.07:7151613, 5.07
In: 01 eerste verdieping
LongName: Gang; InteriorOrExteriorSpace: INTERNAL
Pset_AirSideSystemInformation - Name: Gang
Pset_ProductRequirements - Name: Gang; Category: Rooms
Pset_SpaceCommon - Reference: Gang 5.07; Category: Rooms
BaseQuantities - NetFloorArea: 9.59977 m2; Height: 2438.4 mm; GrossPerimeter: 42.5853 mm; GrossFloorArea: 9.59977 m2; GrossVolume: 23408.1 m3

# IfcSpace: Gang 5.08:7151717, 5.08
In: 01 eerste verdieping
LongName: Gang; InteriorOrExteriorSpace: INTERNAL
Pset_AirSideSystemInformation - Name: Gang
Pset_ProductRequirements - Name: Gang; Category: Rooms
Pset_SpaceCommon - Reference: Gang 5.08; Category: Rooms
BaseQuantities - NetFloorArea: 10.1216 m2; Height: 2438.4 mm; GrossPerimeter: 44.2178 mm; GrossFloorArea: 10.1216 m2; GrossVolume: 24680.5 m3

# IfcSpace: Gang 6.06:3264346, 6.06
In: 00 begane grond
LongName: Gang; InteriorOrExteriorSpace: INTERNAL
Pset_AirSideSystemInformation - Name: Gang
Pset_ProductRequirements - Name: Gang; Category: Rooms
Pset_SpaceCommon - Reference: Gang 6.06; Category: Rooms
BaseQuantities - NetFloorArea: 50.7037 m2; Height: 2438.4 mm; GrossPerimeter: 116.539 mm; GrossFloorArea: 50.7037 m2; GrossVolume: 123636 m3

# IfcSpace: Geluidskast 5.05:6102473, 5.05
In: 00 begane grond
LongName: Geluidskast; InteriorOrExteriorSpace: INTERNAL
Pset_AirSideSystemInformation - Name: Geluidskast
Pset_ProductRequirements - Name: Geluidskast; Category: Rooms
Pset_SpaceCommon - Reference: Geluidskast 5.05; Category: Rooms
BaseQuantities - NetFloorArea: 0.266119 m2; Height: 2438.4 mm; GrossPerimeter: 7.2607 mm; GrossFloorArea: 0.266119 m2; GrossVolume: 648.904 m3

# IfcSpace: Hoofdentree 11.07:3263381, 11.07
In: 00 begane grond
LongName: Hoofdentree; InteriorOrExteriorSpace: INTERNAL
Pset_AirSideSystemInformation - Name: Hoofdentree
Pset_ProductRequirements - Name: Hoofdentree; Category: Rooms
Pset_SpaceCommon - Reference: Hoofdentree 11.07; Category: Rooms
BaseQuantities - NetFloorArea: 15.4159 m2; Height: 2438.4 mm; GrossPerimeter: 48.5878 mm; GrossFloorArea: 15.4159 m2; GrossVolume: 37590.2 m3

# IfcSpace: Hoofdentree 2.04:3269089, 2.04
In: 00 begane grond
LongName: Hoofdentree; InteriorOrExteriorSpace: INTERNAL
Pset_AirSideSystemInformation - Name: Hoofdentree
Pset_ProductRequirements - Name: Hoofdentree; Category: Rooms
Pset_SpaceCommon - Reference: Hoofdentree 2.04; Category: Rooms
BaseQuantities - NetFloorArea: 14.6226 m2; Height: 2438.4 mm; GrossPerimeter: 55.8084 mm; GrossFloorArea: 14.6226 m2; GrossVolume: 35655.7 m3

# IfcSpace: IB-ruimte 3.02:3269064, 3.02
In: 00 begane grond
LongName: IB-ruimte; InteriorOrExteriorSpace: INTERNAL
Pset_AirSideSystemInformation - Name: IB-ruimte
Pset_ProductRequirements - Name: IB-ruimte; Category: Rooms
Pset_SpaceCommon - Reference: IB-ruimte 3.02; Category: Rooms
BaseQuantities - NetFloorArea: 8.78853 m2; Height: 2438.4 mm; GrossPerimeter: 39.2556 mm; GrossFloorArea: 8.78853 m2; GrossVolume: 21429.9 m3

# IfcSpace: Ingang kinderopvang 1.08:3265358, 1.08
In: 00 begane grond
LongName: Ingang kinderopvang; InteriorOrExteriorSpace: INTERNAL
Pset_AirSideSystemInformation - Name: Ingang kinderopvang
Pset_ProductRequirements - Name: Ingang kinderopvang; Category: Rooms
Pset_SpaceCommon - Reference: Ingang kinderopvang 1.08; Category: Rooms
BaseQuantities - NetFloorArea: 6.83836 m2; Height: 2438.4 mm; GrossPerimeter: 34.0845 mm; GrossFloorArea: 6.83836 m2; GrossVolume: 16674.7 m3

# IfcSpace: Instructieruimte 1.01a:3280686, 1.01a
In: 00 begane grond
LongName: Instructieruimte; InteriorOrExteriorSpace: INTERNAL
Pset_AirSideSystemInformation - Name: Instructieruimte
Pset_ProductRequirements - Name: Instructieruimte; Category: Rooms
Pset_SpaceCommon - Reference: Instructieruimte 1.01a; Category: Rooms
BaseQuantities - NetFloorArea: 53.4646 m2; Height: 2438.4 mm; GrossPerimeter: 92.9109 mm; GrossFloorArea: 53.4646 m2; GrossVolume: 130368 m3

# IfcSpace: Instructieruimte 1.01b:3280683, 1.01b
In: 00 begane grond
LongName: Instructieruimte; InteriorOrExteriorSpace: INTERNAL
Pset_AirSideSystemInformation - Name: Instructieruimte
Pset_ProductRequirements - Name: Instructieruimte; Category: Rooms
Pset_SpaceCommon - Reference: Instructieruimte 1.01b; Category: Rooms
BaseQuantities - NetFloorArea: 53.6196 m2; Height: 2438.4 mm; GrossPerimeter: 93.0502 mm; GrossFloorArea: 53.6196 m2; GrossVolume: 130746 m3

# IfcSpace: Instructieruimte 2.01:3280671, 2.01
In: 00 begane grond
LongName: Instructieruimte; InteriorOrExteriorSpace: INTERNAL
Pset_AirSideSystemInformation - Name: Instructieruimte
Pset_ProductRequirements - Name: Instructieruimte; Category: Rooms
Pset_SpaceCommon - Reference: Instructieruimte 2.01; Category: Rooms
BaseQuantities - NetFloorArea: 55.4637 m2; Height: 2438.4 mm; GrossPerimeter: 96.8524 mm; GrossFloorArea: 55.4637 m2; GrossVolume: 135243 m3

# IfcSpace: Instructieruimte 2.02a:3280674, 2.02a
In: 00 begane grond
LongName: Instructieruimte; InteriorOrExteriorSpace: INTERNAL
Pset_AirSideSystemInformation - Name: Instructieruimte
Pset_ProductRequirements - Name: Instructieruimte; Category: Rooms
Pset_SpaceCommon - Reference: Instructieruimte 2.02a; Category: Rooms
BaseQuantities - NetFloorArea: 53.4535 m2; Height: 2438.4 mm; GrossPerimeter: 92.9399 mm; GrossFloorArea: 53.4535 m2; GrossVolume: 130341 m3

# IfcSpace: Instructieruimte 2.02b:3280677, 2.02b
In: 00 begane grond
LongName: Instructieruimte; InteriorOrExteriorSpace: INTERNAL
Pset_AirSideSystemInformation - Name: Instructieruimte
Pset_ProductRequirements - Name: Instructieruimte; Category: Rooms
Pset_SpaceCommon - Reference: Instructieruimte 2.02b; Category: Rooms
BaseQuantities - NetFloorArea: 53.7708 m2; Height: 2438.4 mm; GrossPerimeter: 93.0068 mm; GrossFloorArea: 53.7708 m2; GrossVolume: 131115 m3

# IfcSpace: Keuken 11.03:3263363, 11.03
In: 00 begane grond
LongName: Keuken; InteriorOrExteriorSpace: INTERNAL
Pset_AirSideSystemInformation - Name: Keuken
Pset_ProductRequirements - Name: Keuken; Category: Rooms
Pset_SpaceCommon - Reference: Keuken 11.03; Category: Rooms
BaseQuantities - NetFloorArea: 18.4344 m2; Height: 2438.4 mm; GrossPerimeter: 58.9666 mm; GrossFloorArea: 18.4344 m2; GrossVolume: 44950.4 m3

# IfcSpace: Kinderdagverblijf 23:3628219, 23
In: 00 begane grond
LongName: Kinderdagverblijf; InteriorOrExteriorSpace: INTERNAL; Group: Gebruiksfuncties
Pset_AirSideSystemInformation - Name: Kinderdagverblijf
Pset_ProductRequirements - Name: Kinderdagverblijf; Category: Areas
Pset_SpaceCommon - Reference: Kinderdagverblijf 23; Category: Areas
BaseQuantities - NetFloorArea: 91.9164 m2; Height: 1200 mm; GrossPerimeter: 143.324 mm; GrossFloorArea: 91.9164 m2; GrossVolume: 110300 m3

# IfcSpace: Kleedkamer 6.01a:3264349, 6.01a
In: 00 begane grond
LongName: Kleedkamer; InteriorOrExteriorSpace: INTERNAL
Pset_AirSideSystemInformation - Name: Kleedkamer
Pset_ProductRequirements - Name: Kleedkamer; Category: Rooms
Pset_SpaceCommon - Reference: Kleedkamer 6.01a; Category: Rooms
BaseQuantities - NetFloorArea: 18.8076 m2; Height: 2438.4 mm; GrossPerimeter: 57.4672 mm; GrossFloorArea: 18.8076 m2; GrossVolume: 45860.3 m3

# IfcSpace: Kleedkamer 6.01b:3264352, 6.01b
In: 00 begane grond
LongName: Kleedkamer; InteriorOrExteriorSpace: INTERNAL
Pset_AirSideSystemInformation - Name: Kleedkamer
Pset_ProductRequirements - Name: Kleedkamer; Category: Rooms
Pset_SpaceCommon - Reference: Kleedkamer 6.01b; Category: Rooms
BaseQuantities - NetFloorArea: 18.8702 m2; Height: 2438.4 mm; GrossPerimeter: 57.5441 mm; GrossFloorArea: 18.8702 m2; GrossVolume: 46013.1 m3

# IfcSpace: Kleedkamer 6.01c:3264361, 6.01c
In: 00 begane grond
LongName: Kleedkamer; InteriorOrExteriorSpace: INTERNAL
Pset_AirSideSystemInformation - Name: Kleedkamer
Pset_ProductRequirements - Name: Kleedkamer; Category: Rooms
Pset_SpaceCommon - Reference: Kleedkamer 6.01c; Category: Rooms
BaseQuantities - NetFloorArea: 15.187 m2; Height: 2438.4 mm; GrossPerimeter: 69.0369 mm; GrossFloorArea: 15.187 m2; GrossVolume: 37032 m3

# IfcSpace: Kleedkamer 6.01d:3264358, 6.01d
In: 00 begane grond
LongName: Kleedkamer; InteriorOrExteriorSpace: INTERNAL
Pset_AirSideSystemInformation - Name: Kleedkamer
Pset_ProductRequirements - Name: Kleedkamer; Category: Rooms
Pset_SpaceCommon - Reference: Kleedkamer 6.01d; Category: Rooms
BaseQuantities - NetFloorArea: 15.1675 m2; Height: 2438.4 mm; GrossPerimeter: 67.8527 mm; GrossFloorArea: 15.1675 m2; GrossVolume: 36984.4 m3

# IfcSpace: Kleedkamer 8.03a:3307010, 8.03a
In: 00 begane grond
LongName: Kleedkamer; InteriorOrExteriorSpace: INTERNAL
Pset_AirSideSystemInformation - Name: Kleedkamer
Pset_ProductRequirements - Name: Kleedkamer; Category: Rooms
Pset_SpaceCommon - Reference: Kleedkamer 8.03a; Category: Rooms
BaseQuantities - NetFloorArea: 38.7485 m2; Height: 2438.4 mm; GrossPerimeter: 134.908 mm; GrossFloorArea: 38.7485 m2; GrossVolume: 94484.2 m3

# IfcSpace: Kleedkamer 8.03b:3307016, 8.03b
In: 00 begane grond
LongName: Kleedkamer; InteriorOrExteriorSpace: INTERNAL
Pset_AirSideSystemInformation - Name: Kleedkamer
Pset_ProductRequirements - Name: Kleedkamer; Category: Rooms
Pset_SpaceCommon - Reference: Kleedkamer 8.03b; Category: Rooms
BaseQuantities - NetFloorArea: 38.5325 m2; Height: 2438.4 mm; GrossPerimeter: 131.074 mm; GrossFloorArea: 38.5325 m2; GrossVolume: 93957.6 m3

# IfcSpace: Kleedkamers 1 9:3588978, 9
In: 00 begane grond
LongName: Kleedkamers 1; InteriorOrExteriorSpace: INTERNAL; Group: Gebruiksfuncties
Pset_AirSideSystemInformation - Name: Kleedkamers 1
Pset_ProductRequirements - Name: Kleedkamers 1; Category: Areas
Pset_SpaceCommon - Reference: Kleedkamers 1 9; Category: Areas
BaseQuantities - NetFloorArea: 52.4692 m2; Height: 1200 mm; GrossPerimeter: 97.7711 mm; GrossFloorArea: 52.4692 m2; GrossVolume: 62963.1 m3

# IfcSpace: Kleedkamers 2 8:3588695, 8
In: 00 begane grond
LongName: Kleedkamers 2; InteriorOrExteriorSpace: INTERNAL; Group: Gebruiksfuncties
Pset_AirSideSystemInformation - Name: Kleedkamers 2
Pset_ProductRequirements - Name: Kleedkamers 2; Category: Areas
Pset_SpaceCommon - Reference: Kleedkamers 2 8; Category: Areas
BaseQuantities - NetFloorArea: 64.4473 m2; Height: 1200 mm; GrossPerimeter: 105.355 mm; GrossFloorArea: 64.4473 m2; GrossVolume: 77336.7 m3

# IfcSpace: Koffie hoek 4.04:3268742, 4.04
In: 00 begane grond
LongName: Koffie hoek; InteriorOrExteriorSpace: INTERNAL
Pset_AirSideSystemInformation - Name: Koffie hoek
Pset_ProductRequirements - Name: Koffie hoek; Category: Rooms
Pset_SpaceCommon - Reference: Koffie hoek 4.04; Category: Rooms
BaseQuantities - NetFloorArea: 6.075 m2; Height: 2438.4 mm; GrossPerimeter: 32.4803 mm; GrossFloorArea: 6.075 m2; GrossVolume: 14813.3 m3

# IfcSpace: Leer / speelplein 1.02:3280668, 1.02
In: 00 begane grond
LongName: Leer / speelplein; InteriorOrExteriorSpace: INTERNAL
Pset_AirSideSystemInformation - Name: Leer / speelplein
Pset_ProductRequirements - Name: Leer / speelplein; Category: Rooms
Pset_SpaceCommon - Reference: Leer / speelplein 1.02; Category: Rooms
BaseQuantities - NetFloorArea: 79.1358 m2; Height: 2438.4 mm; GrossPerimeter: 144.208 mm; GrossFloorArea: 79.1358 m2; GrossVolume: 192965 m3

# IfcSpace: Leidingen 5.06:3287430, 5.06
In: 01 eerste verdieping
LongName: Leidingen; InteriorOrExteriorSpace: INTERNAL
Pset_AirSideSystemInformation - Name: Leidingen
Pset_ProductRequirements - Name: Leidingen; Category: Rooms
Pset_SpaceCommon - Reference: Leidingen 5.06; Category: Rooms
BaseQuantities - NetFloorArea: 59.0896 m2; Height: 2338.4 mm; GrossPerimeter: 189.427 mm; GrossFloorArea: 59.0896 m2; GrossVolume: 138175 m3

# IfcSpace: Lesplein 2.03:3280665, 2.03
In: 00 begane grond
LongName: Lesplein; InteriorOrExteriorSpace: INTERNAL
Pset_AirSideSystemInformation - Name: Lesplein
Pset_ProductRequirements - Name: Lesplein; Category: Rooms
Pset_SpaceCommon - Reference: Lesplein 2.03; Category: Rooms
BaseQuantities - NetFloorArea: 79.0415 m2; Height: 2438.4 mm; GrossPerimeter: 144.342 mm; GrossFloorArea: 79.0415 m2; GrossVolume: 192735 m3

# IfcSpace: MIVA toilet 11.11:3263369, 11.11
In: 00 begane grond
LongName: MIVA toilet; InteriorOrExteriorSpace: INTERNAL
Pset_AirSideSystemInformation - Name: MIVA toilet
Pset_ProductRequirements - Name: MIVA toilet; Category: Rooms
Pset_SpaceCommon - Reference: MIVA toilet 11.11; Category: Rooms
BaseQuantities - NetFloorArea: 3.56607 m2; Height: 2438.4 mm; GrossPerimeter: 25.7874 mm; GrossFloorArea: 3.56607 m2; GrossVolume: 8695.52 m3

# IfcSpace: MIVA toilet 5.04:3268745, 5.04
In: 00 begane grond
LongName: MIVA toilet; InteriorOrExteriorSpace: INTERNAL
Pset_AirSideSystemInformation - Name: MIVA toilet
Pset_ProductRequirements - Name: MIVA toilet; Category: Rooms
Pset_SpaceCommon - Reference: MIVA toilet 5.04; Category: Rooms
BaseQuantities - NetFloorArea: 3.61107 m2; Height: 2438.4 mm; GrossPerimeter: 25.9186 mm; GrossFloorArea: 3.61107 m2; GrossVolume: 8805.25 m3

# IfcSpace: MK 2.05:3269098, 2.05
In: 00 begane grond
LongName: MK; InteriorOrExteriorSpace: INTERNAL
Pset_AirSideSystemInformation - Name: MK
Pset_ProductRequirements - Name: MK; Category: Rooms
Pset_SpaceCommon - Reference: MK 2.05; Category: Rooms
BaseQuantities - NetFloorArea: 0.460591 m2; Height: 2438.4 mm; GrossPerimeter: 10.0167 mm; GrossFloorArea: 0.460591 m2; GrossVolume: 1123.1 m3

# IfcSpace: MK 6.05:4339350, 6.05
In: 00 begane grond
LongName: MK; InteriorOrExteriorSpace: INTERNAL
Pset_AirSideSystemInformation - Name: MK
Pset_ProductRequirements - Name: MK; Category: Rooms
Pset_SpaceCommon - Reference: MK 6.05; Category: Rooms
BaseQuantities - NetFloorArea: 0.772787 m2; Height: 2438.4 mm; GrossPerimeter: 14.0945 mm; GrossFloorArea: 0.772787 m2; GrossVolume: 1884.36 m3

# IfcSpace: MK 6.07:3392408, 6.07
In: 00 begane grond
LongName: MK; InteriorOrExteriorSpace: INTERNAL
Pset_AirSideSystemInformation - Name: MK
Pset_ProductRequirements - Name: MK; Category: Rooms
Pset_SpaceCommon - Reference: MK 6.07; Category: Rooms
BaseQuantities - NetFloorArea: 0.41452 m2; Height: 3638.4 mm; GrossPerimeter: 10.7662 mm; GrossFloorArea: 0.41452 m2; GrossVolume: 1508.19 m3

# IfcSpace: Mediatheek / schoolbieb 4.06:3269080, 4.06
In: 00 begane grond
LongName: Mediatheek / schoolbieb; InteriorOrExteriorSpace: INTERNAL
Pset_AirSideSystemInformation - Name: Mediatheek / schoolbieb
Pset_ProductRequirements - Name: Mediatheek / schoolbieb; Category: Rooms
Pset_SpaceCommon - Reference: Mediatheek / schoolbieb 4.06; Category: Rooms
BaseQuantities - NetFloorArea: 16.4879 m2; Height: 2438.4 mm; GrossPerimeter: 75.8586 mm; GrossFloorArea: 16.4879 m2; GrossVolume: 40204 m3

# IfcSpace: Multifuctionele zaal 1.11:3308342, 1.11
In: 00 begane grond
LongName: Multifuctionele zaal; InteriorOrExteriorSpace: INTERNAL
Pset_AirSideSystemInformation - Name: Multifuctionele zaal
Pset_ProductRequirements - Name: Multifuctionele zaal; Category: Rooms
Pset_SpaceCommon - Reference: Multifuctionele zaal 1.11; Category: Rooms
BaseQuantities - NetFloorArea: 173.008 m2; Height: 2575 mm; GrossPerimeter: 191.149 mm; GrossFloorArea: 173.008 m2; GrossVolume: 445495 m3

# IfcSpace: Multifunctionele ruimte 11.17:3264355, 11.17
In: 00 begane grond
LongName: Multifunctionele ruimte; InteriorOrExteriorSpace: INTERNAL
Pset_AirSideSystemInformation - Name: Multifunctionele ruimte
Pset_ProductRequirements - Name: Multifunctionele ruimte; Category: Rooms
Pset_SpaceCommon - Reference: Multifunctionele ruimte 11.17; Category: Rooms
BaseQuantities - NetFloorArea: 25.4351 m2; Height: 2438.4 mm; GrossPerimeter: 72.1724 mm; GrossFloorArea: 25.4351 m2; GrossVolume: 62021 m3

# IfcSpace: Muziekarchief 9.03:3265285, 9.03
In: 00 begane grond
LongName: Muziekarchief; InteriorOrExteriorSpace: INTERNAL
Pset_AirSideSystemInformation - Name: Muziekarchief
Pset_ProductRequirements - Name: Muziekarchief; Category: Rooms
Pset_SpaceCommon - Reference: Muziekarchief 9.03; Category: Rooms
BaseQuantities - NetFloorArea: 6.87558 m2; Height: 2438.4 mm; GrossPerimeter: 34.3629 mm; GrossFloorArea: 6.87558 m2; GrossVolume: 16765.4 m3

# IfcSpace: Opbergruimte slagwerk kar 9.02:3265279, 9.02
In: 00 begane grond
LongName: Opbergruimte slagwerk kar; InteriorOrExteriorSpace: INTERNAL
Pset_AirSideSystemInformation - Name: Opbergruimte slagwerk kar
Pset_ProductRequirements - Name: Opbergruimte slagwerk kar; Category: Rooms
Pset_SpaceCommon - Reference: Opbergruimte slagwerk kar 9.02; Category: Rooms
BaseQuantities - NetFloorArea: 23.3483 m2; Height: 2438.4 mm; GrossPerimeter: 67.6698 mm; GrossFloorArea: 23.3483 m2; GrossVolume: 56932.4 m3

# IfcSpace: Opslagruimte 11.13:3263390, 11.13
In: 00 begane grond
LongName: Opslagruimte; InteriorOrExteriorSpace: INTERNAL
Pset_AirSideSystemInformation - Name: Opslagruimte
Pset_ProductRequirements - Name: Opslagruimte; Category: Rooms
Pset_SpaceCommon - Reference: Opslagruimte 11.13; Category: Rooms
BaseQuantities - NetFloorArea: 21.4792 m2; Height: 2438.4 mm; GrossPerimeter: 61.6314 mm; GrossFloorArea: 21.4792 m2; GrossVolume: 52375 m3

# IfcSpace: Patchkast MFC 11.12:4339100, 11.12
In: 00 begane grond
LongName: Patchkast MFC; InteriorOrExteriorSpace: INTERNAL
Pset_AirSideSystemInformation - Name: Patchkast MFC
Pset_ProductRequirements - Name: Patchkast MFC; Category: Rooms
Pset_SpaceCommon - Reference: Patchkast MFC 11.12; Category: Rooms
BaseQuantities - NetFloorArea: 5.4 m2; Height: 2438.4 mm; GrossPerimeter: 30.5118 mm; GrossFloorArea: 5.4 m2; GrossVolume: 13167.4 m3

# IfcSpace: Podium + zaal 13:3595299, 13
In: 00 begane grond
LongName: Podium + zaal; InteriorOrExteriorSpace: INTERNAL; Group: Gebruiksfuncties
Pset_AirSideSystemInformation - Name: Podium + zaal
Pset_ProductRequirements - Name: Podium + zaal; Category: Areas
Pset_SpaceCommon - Reference: Podium + zaal 13; Category: Areas
BaseQuantities - NetFloorArea: 342.615 m2; Height: 1200 mm; GrossPerimeter: 301.347 mm; GrossFloorArea: 342.615 m2; GrossVolume: 411138 m3

# IfcSpace: Podium 11.15:3309521, 11.15
In: Podium
LongName: Podium; InteriorOrExteriorSpace: INTERNAL
Pset_AirSideSystemInformation - Name: Podium
Pset_ProductRequirements - Name: Podium; Category: Rooms
Pset_SpaceCommon - Reference: Podium 11.15; Category: Rooms
BaseQuantities - NetFloorArea: 87.615 m2; Height: 4550 mm; GrossPerimeter: 139.993 mm; GrossFloorArea: 87.615 m2; GrossVolume: 398648 m3

# IfcSpace: Podium 4.03:4339147, 4.03
In: Podium
LongName: Podium; InteriorOrExteriorSpace: INTERNAL
Pset_AirSideSystemInformation - Name: Podium
Pset_ProductRequirements - Name: Podium; Category: Rooms
Pset_SpaceCommon - Reference: Podium 4.03; Category: Rooms
BaseQuantities - NetFloorArea: 7.12285 m2; Height: 2438.4 mm; GrossPerimeter: 42.983 mm; GrossFloorArea: 7.12285 m2; GrossVolume: 17368.3 m3

# IfcSpace: RT-ruimte 3.03:3269061, 3.03
In: 00 begane grond
LongName: RT-ruimte; InteriorOrExteriorSpace: INTERNAL
Pset_AirSideSystemInformation - Name: RT-ruimte
Pset_ProductRequirements - Name: RT-ruimte; Category: Rooms
Pset_SpaceCommon - Reference: RT-ruimte 3.03; Category: Rooms
BaseQuantities - NetFloorArea: 12.9464 m2; Height: 2438.4 mm; GrossPerimeter: 47.8698 mm; GrossFloorArea: 12.9464 m2; GrossVolume: 31568.5 m3

# IfcSpace: Scheidsrechter 6.04a:3264337, 6.04a
In: 00 begane grond
LongName: Scheidsrechter; InteriorOrExteriorSpace: INTERNAL
Pset_AirSideSystemInformation - Name: Scheidsrechter
Pset_ProductRequirements - Name: Scheidsrechter; Category: Rooms
Pset_SpaceCommon - Reference: Scheidsrechter 6.04a; Category: Rooms
BaseQuantities - NetFloorArea: 7.14664 m2; Height: 2438.4 mm; GrossPerimeter: 40.8909 mm; GrossFloorArea: 7.14664 m2; GrossVolume: 17426.4 m3

# IfcSpace: Scheidsrechter 6.04b:3264340, 6.04b
In: 00 begane grond
LongName: Scheidsrechter; InteriorOrExteriorSpace: INTERNAL
Pset_AirSideSystemInformation - Name: Scheidsrechter
Pset_ProductRequirements - Name: Scheidsrechter; Category: Rooms
Pset_SpaceCommon - Reference: Scheidsrechter 6.04b; Category: Rooms
BaseQuantities - NetFloorArea: 7.20565 m2; Height: 2438.4 mm; GrossPerimeter: 40.9013 mm; GrossFloorArea: 7.20565 m2; GrossVolume: 17570.2 m3

# IfcSpace: School 12:3594566, 12
In: 00 begane grond
LongName: School; InteriorOrExteriorSpace: INTERNAL; Group: Gebruiksfuncties
Pset_AirSideSystemInformation - Name: School
Pset_ProductRequirements - Name: School; Category: Areas
Pset_SpaceCommon - Reference: School 12; Category: Areas
BaseQuantities - NetFloorArea: 806.823 m2; Height: 1200 mm; GrossPerimeter: 425.738 mm; GrossFloorArea: 806.823 m2; GrossVolume: 968187 m3

# IfcSpace: Slaapruimte 1.10a:3265384, 1.10a
In: 00 begane grond
LongName: Slaapruimte; InteriorOrExteriorSpace: INTERNAL
Pset_AirSideSystemInformation - Name: Slaapruimte
Pset_ProductRequirements - Name: Slaapruimte; Category: Rooms
Pset_SpaceCommon - Reference: Slaapruimte 1.10a; Category: Rooms
BaseQuantities - NetFloorArea: 6.63462 m2; Height: 2438.4 mm; GrossPerimeter: 34.394 mm; GrossFloorArea: 6.63462 m2; GrossVolume: 16177.8 m3

# IfcSpace: Slaapruimte 1.10b:3265381, 1.10b
In: 00 begane grond
LongName: Slaapruimte; InteriorOrExteriorSpace: INTERNAL
Pset_AirSideSystemInformation - Name: Slaapruimte
Pset_ProductRequirements - Name: Slaapruimte; Category: Rooms
Pset_SpaceCommon - Reference: Slaapruimte 1.10b; Category: Rooms
BaseQuantities - NetFloorArea: 6.63565 m2; Height: 2438.4 mm; GrossPerimeter: 34.3962 mm; GrossFloorArea: 6.63565 m2; GrossVolume: 16180.4 m3

# IfcSpace: Soosruimte 10:3589358, 10
In: 00 begane grond
LongName: Soosruimte; InteriorOrExteriorSpace: INTERNAL; Group: Gebruiksfuncties
Pset_AirSideSystemInformation - Name: Soosruimte
Pset_ProductRequirements - Name: Soosruimte; Category: Areas
Pset_SpaceCommon - Reference: Soosruimte 10; Category: Areas
BaseQuantities - NetFloorArea: 98.5341 m2; Height: 1200 mm; GrossPerimeter: 135.792 mm; GrossFloorArea: 98.5341 m2; GrossVolume: 118241 m3

# IfcSpace: Soosruimte 7.01:3265276, 7.01
In: 00 begane grond
LongName: Soosruimte; InteriorOrExteriorSpace: INTERNAL
Pset_AirSideSystemInformation - Name: Soosruimte
Pset_ProductRequirements - Name: Soosruimte; Category: Rooms
Pset_SpaceCommon - Reference: Soosruimte 7.01; Category: Rooms
BaseQuantities - NetFloorArea: 79.9105 m2; Height: 2438.4 mm; GrossPerimeter: 127.19 mm; GrossFloorArea: 79.9105 m2; GrossVolume: 194854 m3

# IfcSpace: Sportkantine / horecaruimte 11.02:3263355, 11.02
In: 00 begane grond
LongName: Sportkantine / horecaruimte; InteriorOrExteriorSpace: INTERNAL
Pset_AirSideSystemInformation - Name: Sportkantine / horecaruimte
Pset_ProductRequirements - Name: Sportkantine / horecaruimte; Category: Rooms
Pset_SpaceCommon - Reference: Sportkantine / horecaruimte 11.02; Category: Rooms
BaseQuantities - NetFloorArea: 91.4277 m2; Height: 2438.4 mm; GrossPerimeter: 132.894 mm; GrossFloorArea: 91.4277 m2; GrossVolume: 222937 m3

# IfcSpace: Sportkantine 4:2298370, 4
In: 00 begane grond
LongName: Sportkantine; InteriorOrExteriorSpace: INTERNAL; Group: Gebruiksfuncties
Pset_AirSideSystemInformation - Name: Sportkantine
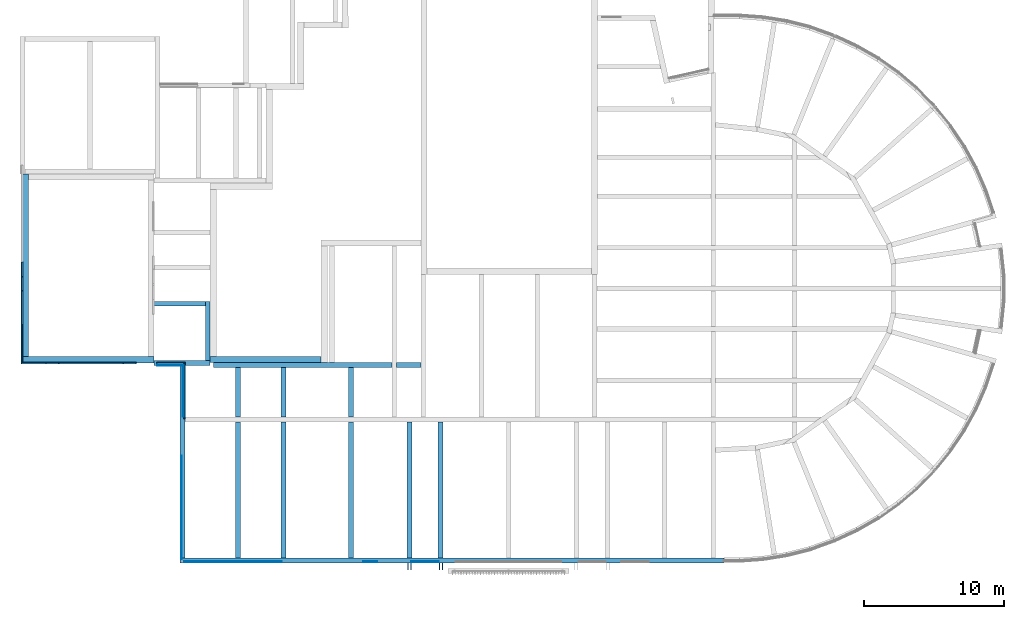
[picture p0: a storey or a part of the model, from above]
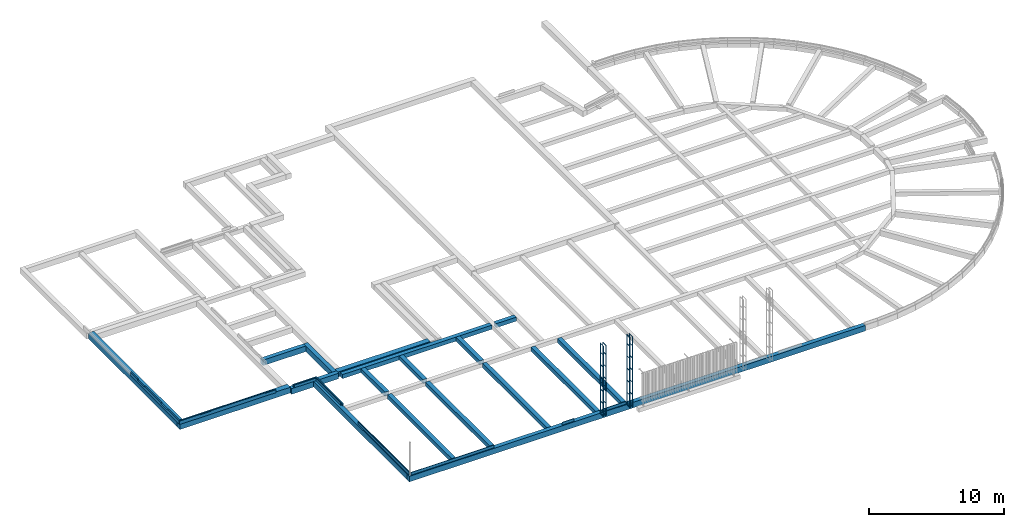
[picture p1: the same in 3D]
Properties of the parts of a building model (IFC2X3), part 2 of 13

# IfcSpace: Sportkantine 4:2298370, 4
Pset_ProductRequirements - Name: Sportkantine; Category: Areas
Pset_SpaceCommon - Reference: Sportkantine 4; Category: Areas
BaseQuantities - NetFloorArea: 222.377 m2; Height: 1200 mm; GrossPerimeter: 207.499 mm; GrossFloorArea: 222.377 m2; GrossVolume: 266853 m3

# IfcSpace: Sportzaal + kleedkamers 11:3590593, 11
In: 00 begane grond
LongName: Sportzaal + kleedkamers; InteriorOrExteriorSpace: INTERNAL; Group: Gebruiksfuncties
Pset_AirSideSystemInformation - Name: Sportzaal + kleedkamers
Pset_ProductRequirements - Name: Sportzaal + kleedkamers; Category: Areas
Pset_SpaceCommon - Reference: Sportzaal + kleedkamers 11; Category: Areas
BaseQuantities - NetFloorArea: 415.886 m2; Height: 1200 mm; GrossPerimeter: 293.277 mm; GrossFloorArea: 415.886 m2; GrossVolume: 499063 m3

# IfcSpace: Sportzaal 8.01:3311535, 8.01
In: 00 begane grond
LongName: Sportzaal; InteriorOrExteriorSpace: INTERNAL
Pset_AirSideSystemInformation - Name: Sportzaal
Pset_ProductRequirements - Name: Sportzaal; Category: Rooms
Pset_SpaceCommon - Reference: Sportzaal 8.01; Category: Rooms
BaseQuantities - NetFloorArea: 125.778 m2; Height: 3638.4 mm; GrossPerimeter: 151.56 mm; GrossFloorArea: 125.778 m2; GrossVolume: 457632 m3

# IfcSpace: Techlab / handvaardigheid 4.05:3280680, 4.05
In: 00 begane grond
LongName: Techlab / handvaardigheid; InteriorOrExteriorSpace: INTERNAL
Pset_AirSideSystemInformation - Name: Techlab / handvaardigheid
Pset_ProductRequirements - Name: Techlab / handvaardigheid; Category: Rooms
Pset_SpaceCommon - Reference: Techlab / handvaardigheid 4.05; Category: Rooms
BaseQuantities - NetFloorArea: 35.091 m2; Height: 2438.4 mm; GrossPerimeter: 78.9932 mm; GrossFloorArea: 35.091 m2; GrossVolume: 85565.8 m3

# IfcSpace: Techniek ruimte 12.06:3287460, 12.06
In: 01 eerste verdieping
LongName: Techniek ruimte; InteriorOrExteriorSpace: INTERNAL
Pset_AirSideSystemInformation - Name: Techniek ruimte
Pset_ProductRequirements - Name: Techniek ruimte; Category: Rooms
Pset_SpaceCommon - Reference: Techniek ruimte 12.06; Category: Rooms
BaseQuantities - NetFloorArea: 10.4853 m2; Height: 2438.4 mm; GrossPerimeter: 44.6161 mm; GrossFloorArea: 10.4853 m2; GrossVolume: 25567.4 m3

# IfcSpace: Techniek ruimte 5.02:3287463, 5.02
In: 01 eerste verdieping
LongName: Techniek ruimte; InteriorOrExteriorSpace: INTERNAL
Pset_AirSideSystemInformation - Name: Techniek ruimte
Pset_ProductRequirements - Name: Techniek ruimte; Category: Rooms
Pset_SpaceCommon - Reference: Techniek ruimte 5.02; Category: Rooms
BaseQuantities - NetFloorArea: 38.6152 m2; Height: 2438.4 mm; GrossPerimeter: 86.6804 mm; GrossFloorArea: 38.6152 m2; GrossVolume: 94159.2 m3

# IfcSpace: Technische ruimtes 21:3615976, 21
In: 00 begane grond
LongName: Technische ruimtes; InteriorOrExteriorSpace: INTERNAL; Group: Gebruiksfuncties
Pset_AirSideSystemInformation - Name: Technische ruimtes
Pset_ProductRequirements - Name: Technische ruimtes; Category: Areas
Pset_SpaceCommon - Reference: Technische ruimtes 21; Category: Areas
BaseQuantities - NetFloorArea: 15.4153 m2; Height: 1200 mm; GrossPerimeter: 55.2334 mm; GrossFloorArea: 15.4153 m2; GrossVolume: 18498.3 m3

# IfcSpace: Toestellen 8.02a:3311538, 8.02a
In: 00 begane grond
LongName: Toestellen; InteriorOrExteriorSpace: INTERNAL
Pset_AirSideSystemInformation - Name: Toestellen
Pset_ProductRequirements - Name: Toestellen; Category: Rooms
Pset_SpaceCommon - Reference: Toestellen 8.02a; Category: Rooms
BaseQuantities - NetFloorArea: 28.5439 m2; Height: 3638.4 mm; GrossPerimeter: 71.0781 mm; GrossFloorArea: 28.5439 m2; GrossVolume: 103854 m3

# IfcSpace: Toilet 1.05:3265387, 1.05
In: 00 begane grond
LongName: Toilet; InteriorOrExteriorSpace: INTERNAL
Pset_AirSideSystemInformation - Name: Toilet
Pset_ProductRequirements - Name: Toilet; Category: Rooms
Pset_SpaceCommon - Reference: Toilet 1.05; Category: Rooms
BaseQuantities - NetFloorArea: 7.94913 m2; Height: 2438.4 mm; GrossPerimeter: 38.2272 mm; GrossFloorArea: 7.94913 m2; GrossVolume: 19383.2 m3

# IfcSpace: Toilet 1.05a:3268751, 1.05a
In: 00 begane grond
LongName: Toilet; InteriorOrExteriorSpace: INTERNAL
Pset_AirSideSystemInformation - Name: Toilet
Pset_ProductRequirements - Name: Toilet; Category: Rooms
Pset_SpaceCommon - Reference: Toilet 1.05a; Category: Rooms
BaseQuantities - NetFloorArea: 6.78131 m2; Height: 2438.4 mm; GrossPerimeter: 42.6509 mm; GrossFloorArea: 6.78131 m2; GrossVolume: 16535.5 m3

# IfcSpace: Toilet 1.05b:3268754, 1.05b
In: 00 begane grond
LongName: Toilet; InteriorOrExteriorSpace: INTERNAL
Pset_AirSideSystemInformation - Name: Toilet
Pset_ProductRequirements - Name: Toilet; Category: Rooms
Pset_SpaceCommon - Reference: Toilet 1.05b; Category: Rooms
BaseQuantities - NetFloorArea: 6.78131 m2; Height: 2438.4 mm; GrossPerimeter: 42.6509 mm; GrossFloorArea: 6.78131 m2; GrossVolume: 16535.5 m3

# IfcSpace: Toilet 1.07:3268757, 1.07
In: 00 begane grond
LongName: Toilet; InteriorOrExteriorSpace: INTERNAL
Pset_AirSideSystemInformation - Name: Toilet
Pset_ProductRequirements - Name: Toilet; Category: Rooms
Pset_SpaceCommon - Reference: Toilet 1.07; Category: Rooms
BaseQuantities - NetFloorArea: 10.2735 m2; Height: 2438.4 mm; GrossPerimeter: 57.6444 mm; GrossFloorArea: 10.2735 m2; GrossVolume: 25050.8 m3

# IfcSpace: Toilet 11.09:3263372, 11.09
In: 00 begane grond
LongName: Toilet; InteriorOrExteriorSpace: INTERNAL
Pset_AirSideSystemInformation - Name: Toilet
Pset_ProductRequirements - Name: Toilet; Category: Rooms
Pset_SpaceCommon - Reference: Toilet 11.09; Category: Rooms
BaseQuantities - NetFloorArea: 9.12856 m2; Height: 2438.4 mm; GrossPerimeter: 56.2205 mm; GrossFloorArea: 9.12856 m2; GrossVolume: 22259.1 m3

# IfcSpace: Toilet 11.10:3263375, 11.10
In: 00 begane grond
LongName: Toilet; InteriorOrExteriorSpace: INTERNAL
Pset_AirSideSystemInformation - Name: Toilet
Pset_ProductRequirements - Name: Toilet; Category: Rooms
Pset_SpaceCommon - Reference: Toilet 11.10; Category: Rooms
BaseQuantities - NetFloorArea: 9.1477 m2; Height: 2438.4 mm; GrossPerimeter: 56.3386 mm; GrossFloorArea: 9.1477 m2; GrossVolume: 22305.8 m3

# IfcSpace: Toilet 7.03:3265249, 7.03
In: 00 begane grond
LongName: Toilet; InteriorOrExteriorSpace: INTERNAL
Pset_AirSideSystemInformation - Name: Toilet
Pset_ProductRequirements - Name: Toilet; Category: Rooms
Pset_SpaceCommon - Reference: Toilet 7.03; Category: Rooms
BaseQuantities - NetFloorArea: 8.7489 m2; Height: 2438.4 mm; GrossPerimeter: 49.5774 mm; GrossFloorArea: 8.7489 m2; GrossVolume: 21333.3 m3

# IfcSpace: Toilet 7.04:3265252, 7.04
In: 00 begane grond
LongName: Toilet; InteriorOrExteriorSpace: INTERNAL
Pset_AirSideSystemInformation - Name: Toilet
Pset_ProductRequirements - Name: Toilet; Category: Rooms
Pset_SpaceCommon - Reference: Toilet 7.04; Category: Rooms
BaseQuantities - NetFloorArea: 9.93637 m2; Height: 2438.4 mm; GrossPerimeter: 54.3033 mm; GrossFloorArea: 9.93637 m2; GrossVolume: 24228.8 m3

# IfcSpace: Trap 11.16:7568846, 11.16
In: 00 begane grond
LongName: Trap; InteriorOrExteriorSpace: INTERNAL
Pset_AirSideSystemInformation - Name: Trap
Pset_ProductRequirements - Name: Trap; Category: Rooms
Pset_SpaceCommon - Reference: Trap 11.16; Category: Rooms
BaseQuantities - NetFloorArea: 4.3432 m2; Height: 2438.4 mm; GrossPerimeter: 35.794 mm; GrossFloorArea: 4.3432 m2; GrossVolume: 10590.5 m3

# IfcSpace: VG1 3:2298416, 3
In: 00 begane grond
LongName: VG1; InteriorOrExteriorSpace: INTERNAL; Group: Verblijfsgebied
Pset_AirSideSystemInformation - Name: VG1
Pset_ProductRequirements - Name: VG1; Category: Areas
Pset_SpaceCommon - Reference: VG1 3; Category: Areas
BaseQuantities - NetFloorArea: 111.514 m2; Height: 1200 mm; GrossPerimeter: 179.93 mm; GrossFloorArea: 111.514 m2; GrossVolume: 133816 m3

# IfcSpace: VG2 7:5126295, 7
In: 00 begane grond
LongName: VG2; InteriorOrExteriorSpace: INTERNAL; Group: Verblijfsgebied
Pset_AirSideSystemInformation - Name: VG2
Pset_ProductRequirements - Name: VG2; Category: Areas
Pset_SpaceCommon - Reference: VG2 7; Category: Areas
BaseQuantities - NetFloorArea: 28.3132 m2; Height: 1200 mm; GrossPerimeter: 79.0602 mm; GrossFloorArea: 28.3132 m2; GrossVolume: 33975.9 m3

# IfcSpace: VG3 6:5125773, 6
In: 00 begane grond
LongName: VG3; InteriorOrExteriorSpace: INTERNAL; Group: Verblijfsgebied
Pset_AirSideSystemInformation - Name: VG3
Pset_ProductRequirements - Name: VG3; Category: Areas
Pset_SpaceCommon - Reference: VG3 6; Category: Areas
BaseQuantities - NetFloorArea: 64.0318 m2; Height: 1200 mm; GrossPerimeter: 117.378 mm; GrossFloorArea: 64.0318 m2; GrossVolume: 76838.2 m3

# IfcSpace: VG4 8:5127211, 8
In: 00 begane grond
LongName: VG4; InteriorOrExteriorSpace: INTERNAL; Group: Verblijfsgebied
Pset_AirSideSystemInformation - Name: VG4
Pset_ProductRequirements - Name: VG4; Category: Areas
Pset_SpaceCommon - Reference: VG4 8; Category: Areas
BaseQuantities - NetFloorArea: 109.199 m2; Height: 1200 mm; GrossPerimeter: 172.506 mm; GrossFloorArea: 109.199 m2; GrossVolume: 131039 m3

# IfcSpace: VG5 10:5129181, 10
In: 00 begane grond
LongName: VG5; InteriorOrExteriorSpace: INTERNAL; Group: Verblijfsgebied
Pset_AirSideSystemInformation - Name: VG5
Pset_ProductRequirements - Name: VG5; Category: Areas
Pset_SpaceCommon - Reference: VG5 10; Category: Areas
BaseQuantities - NetFloorArea: 305.397 m2; Height: 1200 mm; GrossPerimeter: 337.888 mm; GrossFloorArea: 305.397 m2; GrossVolume: 366477 m3

# IfcSpace: VG6 9:5128125, 9
In: 00 begane grond
LongName: VG6; InteriorOrExteriorSpace: INTERNAL; Group: Verblijfsgebied
Pset_AirSideSystemInformation - Name: VG6
Pset_ProductRequirements - Name: VG6; Category: Areas
Pset_SpaceCommon - Reference: VG6 9; Category: Areas
BaseQuantities - NetFloorArea: 258.053 m2; Height: 1200 mm; GrossPerimeter: 228.06 mm; GrossFloorArea: 258.053 m2; GrossVolume: 309664 m3

# IfcSpace: VG7 11:5132578, 11
In: 00 begane grond
LongName: VG7; InteriorOrExteriorSpace: INTERNAL; Group: Verblijfsgebied
Pset_AirSideSystemInformation - Name: VG7
Pset_ProductRequirements - Name: VG7; Category: Areas
Pset_SpaceCommon - Reference: VG7 11; Category: Areas
BaseQuantities - NetFloorArea: 661.869 m2; Height: 1200 mm; GrossPerimeter: 547.891 mm; GrossFloorArea: 661.869 m2; GrossVolume: 794243 m3

# IfcSpace: VG8 12:12788115, 12
In: 00 begane grond
LongName: VG8; InteriorOrExteriorSpace: INTERNAL; Group: Verblijfsgebied
Pset_AirSideSystemInformation - Name: VG8
Pset_ProductRequirements - Name: VG8; Category: Areas
Pset_SpaceCommon - Reference: VG8 12; Category: Areas
BaseQuantities - NetFloorArea: 68.136 m2; Height: 1200 mm; GrossPerimeter: 126.338 mm; GrossFloorArea: 68.136 m2; GrossVolume: 81763.1 m3

# IfcSpace: Verdeelkast 11.18:10293102, 11.18
In: 00 begane grond
LongName: Verdeelkast; InteriorOrExteriorSpace: INTERNAL
Pset_AirSideSystemInformation - Name: Verdeelkast
Pset_ProductRequirements - Name: Verdeelkast; Category: Rooms
Pset_SpaceCommon - Reference: Verdeelkast 11.18; Category: Rooms
BaseQuantities - NetFloorArea: 0.44 m2; Height: 2438.4 mm; GrossPerimeter: 9.84252 mm; GrossFloorArea: 0.44 m2; GrossVolume: 1072.9 m3

# IfcSpace: Vergaderkamer 17:3604592, 17
In: 00 begane grond
LongName: Vergaderkamer; InteriorOrExteriorSpace: INTERNAL; Group: Gebruiksfuncties
Pset_AirSideSystemInformation - Name: Vergaderkamer
Pset_ProductRequirements - Name: Vergaderkamer; Category: Areas
Pset_SpaceCommon - Reference: Vergaderkamer 17; Category: Areas
BaseQuantities - NetFloorArea: 28.2148 m2; Height: 1200 mm; GrossPerimeter: 70.4662 mm; GrossFloorArea: 28.2148 m2; GrossVolume: 33857.8 m3

# IfcSpace: Werkkast 5.03:3268211, 5.03
In: 00 begane grond
LongName: Werkkast; InteriorOrExteriorSpace: INTERNAL
Pset_AirSideSystemInformation - Name: Werkkast
Pset_ProductRequirements - Name: Werkkast; Category: Rooms
Pset_SpaceCommon - Reference: Werkkast 5.03; Category: Rooms
BaseQuantities - NetFloorArea: 2.4 m2; Height: 2438.4 mm; GrossPerimeter: 20.3412 mm; GrossFloorArea: 2.4 m2; GrossVolume: 5852.16 m3

# IfcSpace: toilet 8.02c:3364382, 8.02c
In: 00 begane grond
LongName: toilet; InteriorOrExteriorSpace: INTERNAL
Pset_AirSideSystemInformation - Name: toilet
Pset_ProductRequirements - Name: toilet; Category: Rooms
Pset_SpaceCommon - Reference: toilet 8.02c; Category: Rooms
BaseQuantities - NetFloorArea: 1.56538 m2; Height: 3638.4 mm; GrossPerimeter: 16.7682 mm; GrossFloorArea: 1.56538 m2; GrossVolume: 5695.49 m3

# IfcSpace: toilet 8.02d:3364379, 8.02d
In: 00 begane grond
LongName: toilet; InteriorOrExteriorSpace: INTERNAL
Pset_AirSideSystemInformation - Name: toilet
Pset_ProductRequirements - Name: toilet; Category: Rooms
Pset_SpaceCommon - Reference: toilet 8.02d; Category: Rooms
BaseQuantities - NetFloorArea: 1.58912 m2; Height: 3638.4 mm; GrossPerimeter: 16.9135 mm; GrossFloorArea: 1.58912 m2; GrossVolume: 5781.86 m3

# IfcBeam: 28_Stalen latei met bodemplaat:28_Stalen latei met bodemplaat, 28_Stalen latei met bodemplaat:28_Stalen latei met bodemplaat:9719874
In: 00 begane grond
Type - PredefinedType: BEAM; Classification: 28.10 hoofddraagconstructies; kolommen en liggers, algemeen (verzamelniveau) (Uniformat); Material: <Unnamed> (3), NLRS_h2_staal_RAL 7016
Type - Pset_BeamCommon - IsExternal: no; Reference: 28_Stalen latei met bodemplaat:28_Stalen latei met bodemplaat
Type - Pset_ManufacturerTypeInformation - Manufacturer: Halfen
Type - Pset_ProductRequirements - Category: Windows
Type - Pset_QuantityTakeOff - Reference: 28_Stalen latei met bodemplaat:28_Stalen latei met bodemplaat
Type - Pset_ReinforcementBarPitchOfBeam - Description: stalen latei; Reference: 28_Stalen latei met bodemplaat:28_Stalen latei met bodemplaat
Material: NLRS_h2_staal_RAL 7016
BaseQuantities - CrossSectionArea: 1.79345 m2; NetSurfaceArea: 3.58689 m2; NetVolume: 0.00729701 m3

# IfcBeam: NLRS_28_SF_UN_HE-profiel_gen_aly:HEA120 (24)
In: 02 tweede verdieping
Type - Pset_BeamCommon - IsExternal: no; LoadBearing: yes; Reference: NLRS_28_SF_UN_HE-profiel_gen_aly:HEA120
Type - Pset_ProductRequirements - Category: Structural Framing
Type - Pset_QuantityTakeOff - Reference: NLRS_28_SF_UN_HE-profiel_gen_aly:HEA120
Type - Pset_ReinforcementBarPitchOfBeam - Reference: NLRS_28_SF_UN_HE-profiel_gen_aly:HEA120
Classification: 28.11 hoofddraagconstructies; kolommen en liggers, kolom-/liggerconstructies (Uniformat); Material: NLRS_h3_staal_verzinkt
BaseQuantities - GrossSurfaceArea: 0 m2
Pset_QuantityTakeOff - sets with these values: 2
Name (NLRS_28_SF_UN_HE-profiel_gen_aly:HEA120:...) | GrossVolume (m3) = NetVolume (m3) | Span (mm) = Length (mm) | Slope (deg) | NetSurfaceArea (m2) | Group
2887699 | 0.0510808 | 11717.2 | 0 | 14.8686 | Model Group:Staalconstructie bestaande gymzaal:5957079
2888469 | 0.0510791 | 11600 | 0 | 14.8681 | Model Group:Staalconstructie bestaande gymzaal:5957079
5955717 | 0.00916918 | 2917.49 | 78.4092 | 2.67296 | Model Group:Staalconstructie bestaande gymzaal:5957079
5956431 | 0.00916918 | 2917.49 | 78.4092 | 2.67296 | Model Group:Staalconstructie bestaande gymzaal:5957079
5956433 | 0.00916918 | 2917.49 | 78.4092 | 2.67296 | Model Group:Staalconstructie bestaande gymzaal:5957079
5956435 | 0.00916918 | 2917.49 | 78.4092 | 2.67296 | Model Group:Staalconstructie bestaande gymzaal:5957079
5956437 | 0.00916918 | 2917.49 | 78.4092 | 2.67296 | Model Group:Staalconstructie bestaande gymzaal:5957079
5956590 | 0.00916918 | 2917.49 | 78.4092 | 2.67296 | Model Group:Staalconstructie bestaande gymzaal:5957079
5956661 | 0.00711869 | 2917.49 | 78.4092 | 2.0763 | Model Group:Staalconstructie bestaande gymzaal:5957079
5956663 | 0.00711869 | 2917.49 | 78.4092 | 2.0763 | Model Group:Staalconstructie bestaande gymzaal:5957079
5956665 | 0.00190397 | 2917.49 | 78.4092 | 0.558903 | Model Group:Staalconstructie bestaande gymzaal:5957079
5956667 | 0.00711869 | 2917.49 | 78.4092 | 2.0763 | Model Group:Staalconstructie bestaande gymzaal:5957079
5956673 | 0.00916918 | 2917.49 | 78.4092 | 2.67296 | Model Group:Staalconstructie bestaande gymzaal:5957079
5960153 | 0.00580109 | 2917.49 | 78.4092 | 1.6929 | Model Group:Staalconstructie bestaande gymzaal:5957079
5960155 | 0.00580109 | 2917.49 | 78.4092 | 1.6929 | Model Group:Staalconstructie bestaande gymzaal:5957079
5960157 | 0.00382469 | 2917.49 | 78.4092 | 1.1178 | Model Group:Staalconstructie bestaande gymzaal:5957079
5960159 | 0.00382469 | 2917.49 | 78.4092 | 1.1178 | Model Group:Staalconstructie bestaande gymzaal:5957079
5960161 | 0.00382469 | 2917.49 | 78.4092 | 1.1178 | Model Group:Staalconstructie bestaande gymzaal:5957079
5960962 | 0.00711869 | 2917.49 | 78.4092 | 2.0763 | Model Group:Staalconstructie bestaande gymzaal:5957079
5960964 | 0.00711869 | 2917.49 | 78.4092 | 2.0763 | Model Group:Staalconstructie bestaande gymzaal:5957079
10037032 | 0.00531838 | 2917.49 | 78.4092 | 1.55244
10037309 | 0.00535115 | 2917.49 | 78.4092 | 1.56198
10038488 | 0.00232728 | 2917.49 | 78.4092 | 0.68208
10038490 | 0.00239152 | 2917.49 | 78.4092 | 0.700774

# IfcBeam: NLRS_28_SF_UN_IPE-profielen_gen_aly:IPE360 (10)
In: 02 tweede verdieping
Type - Pset_BeamCommon - IsExternal: no; LoadBearing: yes; Reference: NLRS_28_SF_UN_IPE-profielen_gen_aly:IPE360
Type - Pset_ProductRequirements - Category: Structural Framing
Type - Pset_QuantityTakeOff - Reference: NLRS_28_SF_UN_IPE-profielen_gen_aly:IPE360
Type - Pset_ReinforcementBarPitchOfBeam - Reference: NLRS_28_SF_UN_IPE-profielen_gen_aly:IPE360
Classification: 28.11 hoofddraagconstructies; kolommen en liggers, kolom-/liggerconstructies (Uniformat); Material: NLRS_h3_staal_verzinkt; Group: Model Group:Staalconstructie bestaande gymzaal:5957079
BaseQuantities - GrossSurfaceArea: 0 m2
Pset_QuantityTakeOff - sets with these values: 2
Name (NLRS_28_SF_UN_IPE-profielen_gen_aly:IPE360:...) | GrossVolume (m3) = NetVolume (m3) | Span (mm) = Length (mm) | Slope (deg) | NetSurfaceArea (m2)
4942235 | 0.0419803 | 6001.65 | 0.796218 | 8.32027
4942237 | 0.0419817 | 6001.84 | 0.796026 | 8.32054
4942252 | 0.0419803 | 6001.65 | 0.796218 | 8.32027
4942254 | 0.0419817 | 6001.84 | 0.796026 | 8.32054
4942269 | 0.0419803 | 6001.65 | 0.796218 | 8.32027
4942271 | 0.0419817 | 6001.84 | 0.796026 | 8.32054
4942286 | 0.0419803 | 6001.65 | 0.796218 | 8.32027
4942288 | 0.0419817 | 6001.84 | 0.796026 | 8.32054
4942303 | 0.0419803 | 6001.65 | 0.796218 | 8.32027
4942305 | 0.0419817 | 6001.84 | 0.796026 | 8.32054

# IfcBeam: NLRS_28_SF_UN_hoeklijnen_gen_aly:L60/6 (8)
In: 02 tweede verdieping
Type - Pset_BeamCommon - IsExternal: no; LoadBearing: yes; Reference: NLRS_28_SF_UN_hoeklijnen_gen_aly:L60/6
Type - Pset_ProductRequirements - Category: Structural Framing
Type - Pset_QuantityTakeOff - Reference: NLRS_28_SF_UN_hoeklijnen_gen_aly:L60/6
Type - Pset_ReinforcementBarPitchOfBeam - Reference: NLRS_28_SF_UN_hoeklijnen_gen_aly:L60/6
Classification: 28.11 hoofddraagconstructies; kolommen en liggers, kolom-/liggerconstructies (Uniformat); Material: NLRS_h3_staal_verzinkt; Group: Model Group:Staalconstructie bestaande gymzaal:5957079
BaseQuantities - GrossSurfaceArea: 0 m2
Pset_QuantityTakeOff - sets with these values: 2
Name (NLRS_28_SF_UN_hoeklijnen_gen_aly:L60/6:...) | GrossVolume (m3) = NetVolume (m3) | Span (mm) = Length (mm) | Slope (deg) | NetSurfaceArea (m2)
7313922 | 0.00481652 | 7140.21 | 0.521592 | 1.69137
7314160 | 0.00475436 | 7085.22 | 0.52564 | 1.66956
7314191 | 0.00480529 | 7160.21 | 0.520135 | 1.68743
7314193 | 0.0047608 | 7100.21 | 0.52453 | 1.67182
7410671 | 0.00424238 | 6379.93 | 0 | 1.48992
7410950 | 0.00424238 | 6374.93 | 0 | 1.48992
7411124 | 0.004281 | 6454.42 | 0.186135 | 1.50347
7411349 | 0.004281 | 6454.42 | 0.186139 | 1.50347

# IfcBeam: NLRS_28_SF_UN_kokerprofielen_gen_aly:K100/4 (18)
In: 01 eerste verdieping
Type - Pset_BeamCommon - IsExternal: no; LoadBearing: yes; Reference: NLRS_28_SF_UN_kokerprofielen_gen_aly:K100/4
Type - Pset_ProductRequirements - Category: Structural Framing
Type - Pset_QuantityTakeOff - Reference: NLRS_28_SF_UN_kokerprofielen_gen_aly:K100/4
Type - Pset_ReinforcementBarPitchOfBeam - Reference: NLRS_28_SF_UN_kokerprofielen_gen_aly:K100/4
Classification: 28.11 hoofddraagconstructies; kolommen en liggers, kolom-/liggerconstructies (Uniformat); Material: NLRS_h3_staal_verzinkt
BaseQuantities - GrossSurfaceArea: 0 m2
Pset_BeamCommon - Slope: 0 deg
Pset_QuantityTakeOff - sets with these values: 2
Name (NLRS_28_SF_UN_kokerprofielen_gen_aly:K100/4:...) | GrossVolume (m3) = NetVolume (m3) | Span (mm) = Length (mm) | NetSurfaceArea (m2) | Group
5965918 | 0.00241167 | 1727.21 | 1.20891 | Model Group:Staalconstructie bestaande gymzaal:5957079
5966727 | 0.00592681 | 4038.13 | 2.96648 | Model Group:Staalconstructie bestaande gymzaal:5957079
5966836 | 0.00241167 | 1727.21 | 1.20891 | Model Group:Staalconstructie bestaande gymzaal:5957079
5967168 | 0.00585001 | 3900 | 2.92808 | Model Group:Staalconstructie bestaande gymzaal:5957079
5967183 | 0.00592835 | 4005 | 2.96724 | Model Group:Staalconstructie bestaande gymzaal:5957079
7314423 | 0.00585001 | 3900 | 2.92808 | Model Group:Staalconstructie bestaande gymzaal:5957079
9166374 | 0.00243542 | 1727.21 | 1.22078 | Model Group:Staalconstructie bestaande gymzaal:5957079
9166376 | 0.0059391 | 4038.13 | 2.97262 | Model Group:Staalconstructie bestaande gymzaal:5957079
9166378 | 0.00243542 | 1727.21 | 1.22078 | Model Group:Staalconstructie bestaande gymzaal:5957079
9166380 | 0.00584079 | 3900 | 2.92347 | Model Group:Staalconstructie bestaande gymzaal:5957079
9166382 | 0.00592681 | 4005 | 2.96648 | Model Group:Staalconstructie bestaande gymzaal:5957079
10037388 | 0.00784258 | 5230 | 3.92436
10037845 | 0.000494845 | 480 | 0.250494
10038066 | 0.000494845 | 480 | 0.250494
10543291 | 0.00792768 | 9120 | 3.96691
10543293 | 0.00020441 | 266.624 | 0.105277
10543295 | 0.00020441 | 266.624 | 0.105277
10544179 | 0.00617886 | 9120 | 3.0925

# IfcBeam: NLRS_28_SF_UN_ongeschaafd vuren_gen_aly:71x245, NLRS_28_SF_UN_ongeschaafd vuren_gen_aly:71x245:6499496
In: 01 eerste verdieping
Type - Pset_BeamCommon - IsExternal: no; LoadBearing: yes; Reference: NLRS_28_SF_UN_ongeschaafd vuren_gen_aly:71x245
Type - Pset_ProductRequirements - Category: Structural Framing
Type - Pset_QuantityTakeOff - Reference: NLRS_28_SF_UN_ongeschaafd vuren_gen_aly:71x245
Type - Pset_ReinforcementBarPitchOfBeam - Reference: NLRS_28_SF_UN_ongeschaafd vuren_gen_aly:71x245
Classification: 28.11 hoofddraagconstructies; kolommen en liggers, kolom-/liggerconstructies (Uniformat); Material: NLRS_h3_staal_verzinkt
BaseQuantities - GrossSurfaceArea: 0 m2; GrossVolume: 0.0241208 m3; Length: 2428.6 mm; NetSurfaceArea: 1.22604 m2; NetVolume: 0.0241208 m3
Pset_BeamCommon - Slope: 0 deg; Span: 2428.6 mm
Pset_QuantityTakeOff - sets with these values: 2

# IfcBeam: Stripstaal_staand_ITX:8x80 (6)
In: 01 eerste verdieping
Type - Pset_BeamCommon - IsExternal: no; LoadBearing: yes; Reference: Stripstaal_staand_ITX:8x80
Type - Pset_ProductRequirements - Category: Structural Framing
Type - Pset_QuantityTakeOff - Reference: Stripstaal_staand_ITX:8x80
Type - Pset_ReinforcementBarPitchOfBeam - Reference: Stripstaal_staand_ITX:8x80
Material: NLRS_h3_staal_verzinkt; Group: Model Group:Staalconstructie bestaande gymzaal:5957079
BaseQuantities - GrossSurfaceArea: 0 m2
Pset_QuantityTakeOff - sets with these values: 2
Name (Stripstaal_staand_ITX:8x80:...) | GrossVolume (m3) = NetVolume (m3) | Span (mm) = Length (mm) | Slope (deg) | NetSurfaceArea (m2)
7314494 | 0.00281202 | 4579.3 | 31.6075 | 0.774585
7314654 | 0.00284475 | 4579.3 | 31.6075 | 0.783585
7314865 | 0.00182314 | 3121.42 | 56.4034 | 0.502643
7315006 | 0.00175204 | 3121.42 | 56.4034 | 0.483091
7315172 | 0.00175204 | 3121.42 | 56.4034 | 0.483091
7315220 | 0.00192514 | 3121.42 | 56.4034 | 0.530695

# IfcBuildingElementProxy: 0.0_ALYNIA_project informatie kubus:project informatie kubus, 0.0_ALYNIA_project informatie kubus:project informatie kubus:2605124
In: 00 begane grond
Type - Classification: 0.0 (Uniformat); Material: NLRS_a_Alynia-geel_gen
Type - Pset_BuildingElementProxyCommon - Reference: 0.0_ALYNIA_project informatie kubus:project informatie kubus
Type - Pset_ProductRequirements - Category: Generic Models
Type - Pset_QuantityTakeOff - Reference: 0.0_ALYNIA_project informatie kubus:project informatie kubus
Material: NLRS_a_Alynia-geel_gen, NLRS_a_Alynia-grijs_gen, NLRS_a_Alynia_gen
Pset_BuildingElementProxyCommon - sets with these values: 2

# IfcBuildingElementProxy: 24_Vlizotrap_700x1200mm:24_Vlizotrap_700x1200mm, 24_Vlizotrap_700x1200mm:24_Vlizotrap_700x1200mm:6633618
In: 7.05
Type - Classification: 24.31 trappen en hellingen; ladders en klimijzers, ladders (Uniformat); Material: AL_31_Naaldhout (vuren)
Type - Pset_BuildingElementProxyCommon - Reference: 24_Vlizotrap_700x1200mm:24_Vlizotrap_700x1200mm
Type - Pset_ProductRequirements - Category: Generic Models
Type - Pset_QuantityTakeOff - Reference: 24_Vlizotrap_700x1200mm:24_Vlizotrap_700x1200mm
Material: AL_31_Naaldhout (vuren), AL_Spaanplaat
Pset_BuildingElementProxyCommon - sets with these values: 2

# IfcBuildingElementProxy: 30_daklichtkoepel 2:30_daklichtkoepel Houten vloer, 30_daklichtkoepel 2:30_daklichtkoepel Houten vloer:6472269
In: 01 eerste verdieping
Type - Material: Metal - Steel - 345 MPa, NLRS_n6_kunststof wit_gen, o5_glas
Type - Pset_BuildingElementProxyCommon - Reference: 30_daklichtkoepel 2:30_daklichtkoepel Houten vloer
Type - Pset_ProductRequirements - Category: Generic Models
Type - Pset_QuantityTakeOff - Reference: 30_daklichtkoepel 2:30_daklichtkoepel Houten vloer
Material: o5_glas, Default, NLRS_n6_kunststof wit_gen
Pset_BuildingElementProxyCommon - sets with these values: 2

# IfcBuildingElementProxy: 30_daklichtkoepel 2:30_daklichtkoepel Stalen dak, 30_daklichtkoepel 2:30_daklichtkoepel Stalen dak:6474987
In: 01 eerste verdieping
Type - Material: Metal - Steel - 345 MPa, o5_glas, NLRS_n6_kunststof wit_gen
Type - Pset_BuildingElementProxyCommon - Reference: 30_daklichtkoepel 2:30_daklichtkoepel Stalen dak
Type - Pset_ProductRequirements - Category: Generic Models
Type - Pset_QuantityTakeOff - Reference: 30_daklichtkoepel 2:30_daklichtkoepel Stalen dak
Material: o5_glas, Default, NLRS_n6_kunststof wit_gen
Pset_BuildingElementProxyCommon - sets with these values: 2

# IfcBuildingElementProxy: 30_daklichtkoepel 2:30_daklichtkoepel bestaande gedeelte 2, 30_daklichtkoepel 2:30_daklichtkoepel bestaande gedeelte 2:6464778
In: 01 eerste verdieping
Type - Material: Metal - Steel - 345 MPa, o5_glas, NLRS_n6_kunststof wit_gen
Type - Pset_BuildingElementProxyCommon - Reference: 30_daklichtkoepel 2:30_daklichtkoepel bestaande gedeelte 2
Type - Pset_ProductRequirements - Category: Generic Models
Type - Pset_QuantityTakeOff - Reference: 30_daklichtkoepel 2:30_daklichtkoepel bestaande gedeelte 2
Material: o5_glas, Default, NLRS_n6_kunststof wit_gen
Pset_BuildingElementProxyCommon - sets with these values: 2

# IfcBuildingElementProxy: 30_daklichtkoepel 3:30_daklichtkoepel bestaande gedeelte 2, 30_daklichtkoepel 3:30_daklichtkoepel bestaande gedeelte 2:6472470
In: 01 eerste verdieping
Type - Material: Metal - Steel - 345 MPa, NLRS_n6_kunststof wit_gen, o5_glas
Type - Pset_BuildingElementProxyCommon - Reference: 30_daklichtkoepel 3:30_daklichtkoepel bestaande gedeelte 2
Type - Pset_ProductRequirements - Category: Generic Models
Type - Pset_QuantityTakeOff - Reference: 30_daklichtkoepel 3:30_daklichtkoepel bestaande gedeelte 2
Material: o5_glas, Default, NLRS_n6_kunststof wit_gen
Pset_BuildingElementProxyCommon - sets with these values: 2

# IfcBuildingElementProxy: 30_daklichtkoepel 3:30_daklichtkoepel bestaande gedeelte 2, 30_daklichtkoepel 3:30_daklichtkoepel bestaande gedeelte 2:6472423
In: 01 eerste verdieping
Type - Material: o5_glas, NLRS_n6_kunststof wit_gen, Metal - Steel - 345 MPa
Type - Pset_BuildingElementProxyCommon - Reference: 30_daklichtkoepel 3:30_daklichtkoepel bestaande gedeelte 2
Type - Pset_ProductRequirements - Category: Generic Models
Type - Pset_QuantityTakeOff - Reference: 30_daklichtkoepel 3:30_daklichtkoepel bestaande gedeelte 2
Material: o5_glas, Default, NLRS_n6_kunststof wit_gen
Pset_BuildingElementProxyCommon - sets with these values: 2

# IfcBuildingElementProxy: 73_Keukenblok Opstelling keuken:73_Keukenblok Opstelling bnr-64, 73_Keukenblok Opstelling keuken:73_Keukenblok Opstelling bnr-64:5860218
In: 11.03
Type - Classification: 73.21 vaste keukenvoorzieningen; bijzonder, keukenmeubilering (Uniformat); Material: Wit
Type - Pset_BuildingElementProxyCommon - Reference: 73_Keukenblok Opstelling keuken:73_Keukenblok Opstelling bnr-64
Type - Pset_ManufacturerTypeInformation - Manufacturer: n.t.b.
Type - Pset_ProductRequirements - Category: Generic Models
Type - Pset_QuantityTakeOff - Reference: 73_Keukenblok Opstelling keuken:73_Keukenblok Opstelling bnr-64
Pset_BuildingElementProxyCommon - sets with these values: 2
Pset_ProvisionForVoid - Width: 700 mm; Height: 700 mm; Depth: 700 mm

# IfcBuildingElementProxy: 73_Keukenblok Opstelling koffiehoek:73_Keukenblok Opstelling bnr-64, 73_Keukenblok Opstelling koffiehoek:73_Keukenblok Opstelling bnr-64:5777965
In: 4.04
Type - Classification: 73.21 vaste keukenvoorzieningen; bijzonder, keukenmeubilering (Uniformat); Material: Wit
Type - Pset_BuildingElementProxyCommon - Reference: 73_Keukenblok Opstelling koffiehoek:73_Keukenblok Opstelling bnr-64
Type - Pset_ManufacturerTypeInformation - Manufacturer: n.t.b.
Type - Pset_ProductRequirements - Category: Generic Models
Type - Pset_QuantityTakeOff - Reference: 73_Keukenblok Opstelling koffiehoek:73_Keukenblok Opstelling bnr-64
Material: Wit, chroom
Pset_BuildingElementProxyCommon - sets with these values: 2

# IfcBuildingElementProxy: 73_Keukenblok Opstelling mf zaal:73_Keukenblok Opstelling bnr-64, 73_Keukenblok Opstelling mf zaal:73_Keukenblok Opstelling bnr-64:10152761
In: 1.11
Type - Classification: 73.21 vaste keukenvoorzieningen; bijzonder, keukenmeubilering (Uniformat); Material: Wit
Type - Pset_BuildingElementProxyCommon - Reference: 73_Keukenblok Opstelling mf zaal:73_Keukenblok Opstelling bnr-64
Type - Pset_ManufacturerTypeInformation - Manufacturer: n.t.b.
Type - Pset_ProductRequirements - Category: Generic Models
Type - Pset_QuantityTakeOff - Reference: 73_Keukenblok Opstelling mf zaal:73_Keukenblok Opstelling bnr-64
Pset_BuildingElementProxyCommon - sets with these values: 2
Pset_ProvisionForVoid - Width: 1000 mm; Height: 153 mm; Depth: 1000 mm

# IfcBuildingElementProxy: 73_Keukenblok Opstelling pantry kinderopvang:73_Keukenblok Opstelling bnr-64, 73_Keukenblok Opstelling pantry kinderopvang:73_Keukenblok Opstelling bnr-64:8039545
In: 1.03
Type - Classification: 73.21 vaste keukenvoorzieningen; bijzonder, keukenmeubilering (Uniformat); Material: Wit
Type - Pset_BuildingElementProxyCommon - Reference: 73_Keukenblok Opstelling pantry kinderopvang:73_Keukenblok Opstelling bnr-64
Type - Pset_ManufacturerTypeInformation - Manufacturer: n.t.b.
Type - Pset_ProductRequirements - Category: Generic Models
Type - Pset_QuantityTakeOff - Reference: 73_Keukenblok Opstelling pantry kinderopvang:73_Keukenblok Opstelling bnr-64
Material: Wit, chroom
Pset_BuildingElementProxyCommon - sets with these values: 2

# IfcBuildingElementProxy: 73_Keukenblok Opstelling pantry lokaal:73_Keukenblok Opstelling bnr-64, 73_Keukenblok Opstelling pantry lokaal:73_Keukenblok Opstelling bnr-64:11777534
In: 1.01a
Type - Classification: 73.21 vaste keukenvoorzieningen; bijzonder, keukenmeubilering (Uniformat); Material: Wit
Type - Pset_BuildingElementProxyCommon - Reference: 73_Keukenblok Opstelling pantry lokaal:73_Keukenblok Opstelling bnr-64
Type - Pset_ManufacturerTypeInformation - Manufacturer: n.t.b.
Type - Pset_ProductRequirements - Category: Generic Models
Type - Pset_QuantityTakeOff - Reference: 73_Keukenblok Opstelling pantry lokaal:73_Keukenblok Opstelling bnr-64
Material: Wit, chroom
Pset_BuildingElementProxyCommon - sets with these values: 2

# IfcBuildingElementProxy: 73_Keukenblok Opstelling podium zaal:73_Keukenblok Opstelling bnr-64, 73_Keukenblok Opstelling podium zaal:73_Keukenblok Opstelling bnr-64:5859547
In: 00 begane grond
Type - Classification: 73.21 vaste keukenvoorzieningen; bijzonder, keukenmeubilering (Uniformat); Material: Wit
Type - Pset_BuildingElementProxyCommon - Reference: 73_Keukenblok Opstelling podium zaal:73_Keukenblok Opstelling bnr-64
Type - Pset_ManufacturerTypeInformation - Manufacturer: n.t.b.
Type - Pset_ProductRequirements - Category: Generic Models
Type - Pset_QuantityTakeOff - Reference: 73_Keukenblok Opstelling podium zaal:73_Keukenblok Opstelling bnr-64
Pset_BuildingElementProxyCommon - sets with these values: 2
Pset_ProvisionForVoid - Width: 100 mm; Height: 300 mm; Depth: 100 mm

# IfcBuildingElementProxy: 73_Keukenblok Opstelling soosruimte:73_Keukenblok Opstelling bnr-64, 73_Keukenblok Opstelling soosruimte:73_Keukenblok Opstelling bnr-64:6635511
In: 7.01
Type - Classification: 73.21 vaste keukenvoorzieningen; bijzonder, keukenmeubilering (Uniformat); Material: Wit
Type - Pset_BuildingElementProxyCommon - Reference: 73_Keukenblok Opstelling soosruimte:73_Keukenblok Opstelling bnr-64
Type - Pset_ManufacturerTypeInformation - Manufacturer: n.t.b.
Type - Pset_ProductRequirements - Category: Generic Models
Type - Pset_QuantityTakeOff - Reference: 73_Keukenblok Opstelling soosruimte:73_Keukenblok Opstelling bnr-64
Pset_BuildingElementProxyCommon - sets with these values: 2
Pset_ProvisionForVoid - Width: 1000 mm; Height: 1000 mm; Depth: 1000 mm

# IfcBuildingElementProxy: 73_Keukenblok Opstelling sportkantine:73_Keukenblok Opstelling bnr-64, 73_Keukenblok Opstelling sportkantine:73_Keukenblok Opstelling bnr-64:4700426
In: 11.02
Type - Classification: 73.21 vaste keukenvoorzieningen; bijzonder, keukenmeubilering (Uniformat); Material: Wit
Type - Pset_BuildingElementProxyCommon - Reference: 73_Keukenblok Opstelling sportkantine:73_Keukenblok Opstelling bnr-64
Type - Pset_ManufacturerTypeInformation - Manufacturer: n.t.b.
Type - Pset_ProductRequirements - Category: Generic Models
Type - Pset_QuantityTakeOff - Reference: 73_Keukenblok Opstelling sportkantine:73_Keukenblok Opstelling bnr-64
Pset_BuildingElementProxyCommon - sets with these values: 2
Pset_ProvisionForVoid - Width: 100 mm; Height: 2135 mm; Depth: 100 mm

# IfcBuildingElementProxy: 76_Postkasten oostwoud 450mm hoog:76_Postkasten, 76_Postkasten oostwoud 450mm hoog:76_Postkasten:7653580
In: 00 begane grond
Type - Classification: 76.10 vaste opslagvoorzieningen; standaard, algemeen (verzamelniveau) (Uniformat); Material: NLRS_h2_staal_RAL 7021
Type - Pset_BuildingElementProxyCommon - Reference: 76_Postkasten oostwoud 450mm hoog:76_Postkasten
Type - Pset_ManufacturerTypeInformation - Manufacturer: Oostwoud
Type - Pset_ProductRequirements - Category: Generic Models
Type - Pset_QuantityTakeOff - Reference: 76_Postkasten oostwoud 450mm hoog:76_Postkasten
Pset_BuildingElementProxyCommon - sets with these values: 2

# IfcBuildingElementProxy: AL_85_Wasdroger:4.3 Kw, AL_85_Wasdroger:4.3 Kw:10275129
In: 5.03
Type - Classification: 85 (Uniformat); Material: NLRS_h4_aluminium RAL 9010
Type - Pset_BuildingElementProxyCommon - Reference: AL_85_Wasdroger:4.3 Kw
Type - Pset_ManufacturerTypeInformation - Manufacturer: Miele
Type - Pset_ProductRequirements - Category: Mechanical Equipment
Type - Pset_QuantityTakeOff - Reference: AL_85_Wasdroger:4.3 Kw
Material: NLRS_h4_aluminium RAL 9010, NLRS_h4_aluminium, NLRS_n6_kunststof_Zwart, NLRS_o1_glas
Pset_BuildingElementProxyCommon - sets with these values: 2

# IfcBuildingElementProxy: AL_85_Wasmachine:Miele Professional Washing Machine PW 6065 Vario, AL_85_Wasmachine:Miele Professional Washing Machine PW 6065 Vario:10273312
In: 5.03
Type - Classification: 85 (Uniformat); Material: NLRS_h4_aluminium RAL 9010
Type - Pset_BuildingElementProxyCommon - Reference: AL_85_Wasmachine:Miele Professional Washing Machine PW 6065 Vario
Type - Pset_ManufacturerTypeInformation - Manufacturer: Miele
Type - Pset_ProductRequirements - Category: Mechanical Equipment
Type - Pset_QuantityTakeOff - Reference: AL_85_Wasmachine:Miele Professional Washing Machine PW 6065 Vario
Type - Pset_ProvisionForVoid - Width: 595 mm; Height: 850 mm; Depth: 700 mm
Material: NLRS_h4_aluminium RAL 9010, NLRS_o1_glas, NLRS_n6_kunststof_Zwart, NLRS_h4_aluminium
Pset_BuildingElementProxyCommon - sets with these values: 2

# IfcBuildingElementProxy: Besvestiging luifel hoofdingang1:Besvestiging luifel hoofdingang, Besvestiging luifel hoofdingang1:Besvestiging luifel hoofdingang:9461287
In: Podium
Type - Material: NLRS_h3_staal_verzinkt
Type - Pset_BuildingElementProxyCommon - Reference: Besvestiging luifel hoofdingang1:Besvestiging luifel hoofdingang
Type - Pset_ProductRequirements - Category: Generic Models
Type - Pset_QuantityTakeOff - Reference: Besvestiging luifel hoofdingang1:Besvestiging luifel hoofdingang
Pset_BuildingElementProxyCommon - sets with these values: 2
Pset_ProvisionForVoid - Width: 250 mm; Height: 250 mm; Depth: 250 mm

# IfcBuildingElementProxy: Besvestiging luifel hoofdingang2:Besvestiging luifel hoofdingang, Besvestiging luifel hoofdingang2:Besvestiging luifel hoofdingang:9461465
In: Podium
Type - Material: NLRS_h3_staal_verzinkt
Type - Pset_BuildingElementProxyCommon - Reference: Besvestiging luifel hoofdingang2:Besvestiging luifel hoofdingang
Type - Pset_ProductRequirements - Category: Generic Models
Type - Pset_QuantityTakeOff - Reference: Besvestiging luifel hoofdingang2:Besvestiging luifel hoofdingang
Pset_BuildingElementProxyCommon - sets with these values: 2
Pset_ProvisionForVoid - Width: 250 mm; Height: 250 mm; Depth: 250 mm

# IfcBuildingElementProxy: Besvestiging luifel hoofdingang:Besvestiging luifel hoofdingang, Besvestiging luifel hoofdingang:Besvestiging luifel hoofdingang:9460495
In: Podium
Type - Material: NLRS_h3_staal_verzinkt
Type - Pset_BuildingElementProxyCommon - Reference: Besvestiging luifel hoofdingang:Besvestiging luifel hoofdingang
Type - Pset_ProductRequirements - Category: Generic Models
Type - Pset_QuantityTakeOff - Reference: Besvestiging luifel hoofdingang:Besvestiging luifel hoofdingang
Pset_BuildingElementProxyCommon - sets with these values: 2
Pset_ProvisionForVoid - Width: 250 mm; Height: 250 mm; Depth: 250 mm

# IfcBuildingElementProxy: Boekenkast rechts:Boekenkast rechts, Boekenkast rechts:Boekenkast rechts:8356335
In: 4.06
Type - Material: NLRS_i2_hout naaldhout_gen
Type - Pset_BuildingElementProxyCommon - Reference: Boekenkast rechts:Boekenkast rechts
Type - Pset_ProductRequirements - Category: Generic Models
Type - Pset_QuantityTakeOff - Reference: Boekenkast rechts:Boekenkast rechts
Material: NLRS_i2_hout naaldhout_gen, Hout RAL 8011 (boekenkast)
Pset_BuildingElementProxyCommon - sets with these values: 2
Pset_ProvisionForVoid - Width: 2999.52 mm; Height: 337.661 mm; Depth: 2999.52 mm

# IfcBuildingElementProxy: Model Text:200mm Arial, Model Text:200mm Arial:12271649
In: Podium
Type - Pset_BuildingElementProxyCommon - Reference: Model Text:200mm Arial
Type - Pset_ProductRequirements - Category: Generic Models
Type - Pset_QuantityTakeOff - Reference: Model Text:200mm Arial
Pset_BuildingElementProxyCommon - sets with these values: 2
Pset_ProvisionForVoid - Shape: Undefined; Width: 25.1141 mm; Height: 25.1141 mm; Depth: 20 mm

# IfcBuildingElementProxy: Model Text:300mm Arial (2)
In: Podium
Type - Pset_BuildingElementProxyCommon - Reference: Model Text:300mm Arial
Type - Pset_ProductRequirements - Category: Generic Models
Type - Pset_QuantityTakeOff - Reference: Model Text:300mm Arial
Pset_BuildingElementProxyCommon - sets with these values: 2
Pset_ProvisionForVoid - Shape: Undefined; Width: 37.6711 mm; Height: 37.6711 mm; Depth: 20 mm
Name (Model Text:300mm Arial:...)
12271589
12275778

# IfcBuildingElementProxy: Model Text:500mm Arial, Model Text:500mm Arial:5015402
In: 00 begane grond
Type - Pset_BuildingElementProxyCommon - Reference: Model Text:500mm Arial
Type - Pset_ProductRequirements - Category: Generic Models
Type - Pset_QuantityTakeOff - Reference: Model Text:500mm Arial
Pset_BuildingElementProxyCommon - sets with these values: 2
Pset_ProvisionForVoid - Shape: Undefined; Width: 20 mm; Depth: 20 mm

# IfcBuildingElementProxy: Model Text:800mm Arial, Model Text:800mm Arial:5015360
In: 00 begane grond
Type - Pset_BuildingElementProxyCommon - Reference: Model Text:800mm Arial
Type - Pset_ProductRequirements - Category: Generic Models
Type - Pset_QuantityTakeOff - Reference: Model Text:800mm Arial
Pset_BuildingElementProxyCommon - sets with these values: 2
Pset_ProvisionForVoid - Shape: Undefined; Width: 20 mm; Height: 799.389 mm; Depth: 20 mm

# IfcBuildingElementProxy: Tekst de Greide:Tekst de Greide, Tekst de Greide:Tekst de Greide:12272016
In: 00 begane grond
Type - Material: AL_Aluminium groen donker
Type - Pset_BuildingElementProxyCommon - Reference: Tekst de Greide:Tekst de Greide
Type - Pset_ProductRequirements - Category: Generic Models
Type - Pset_QuantityTakeOff - Reference: Tekst de Greide:Tekst de Greide
Material: AL_Aluminium groen donker, AL_Aluminium groen licht
Pset_BuildingElementProxyCommon - sets with these values: 2
Pset_ProvisionForVoid - Width: 20 mm; Depth: 20 mm

# IfcBuildingElementProxy: Tekst kinderwoud:Tekst kinderwoud, Tekst kinderwoud:Tekst kinderwoud:12277155
In: Podium
Type - Material: AL_Aluminium groen licht
Type - Pset_BuildingElementProxyCommon - Reference: Tekst kinderwoud:Tekst kinderwoud
Type - Pset_ProductRequirements - Category: Generic Models
Type - Pset_QuantityTakeOff - Reference: Tekst kinderwoud:Tekst kinderwoud
Material: AL_Aluminium groen licht, AL_Aluminium blauw, AL_Aluminium Oranje, AL_Aluminium paars
Pset_BuildingElementProxyCommon - sets with these values: 2
Pset_ProvisionForVoid - Width: 20 mm; Height: 50 mm; Depth: 20 mm

# IfcBuildingElementProxy: Tribune sportzaal:Tribune sportzaal, Tribune sportzaal:Tribune sportzaal:8394495
In: 00 begane grond
Type - Pset_BuildingElementProxyCommon - Reference: Tribune sportzaal:Tribune sportzaal
Type - Pset_ProductRequirements - Category: Generic Models
Type - Pset_QuantityTakeOff - Reference: Tribune sportzaal:Tribune sportzaal
Pset_BuildingElementProxyCommon - sets with these values: 2
Pset_ProvisionForVoid - Width: 1270 mm; Height: 18 mm; Depth: 1270 mm

# IfcColumn: Buisprofielen_ITX(c):Buis 160x5 (3)
In: 00 begane grond
Type - PredefinedType: COLUMN; Material: NLRS_h3_staal_verzinkt
Type - Pset_ColumnCommon - IsExternal: no; LoadBearing: yes; Reference: Buisprofielen_ITX(c):Buis 160x5
Type - Pset_ProductRequirements - Category: Structural Columns
Type - Pset_QuantityTakeOff - Reference: Buisprofielen_ITX(c):Buis 160x5
Type - Pset_ReinforcementBarPitchOfColumn - Reference: Buisprofielen_ITX(c):Buis 160x5
BaseQuantities - GrossSurfaceArea: 0 m2
Pset_QuantityTakeOff - sets with these values: 2
Name (Buisprofielen_ITX(c):Buis 160x5:...) | GrossVolume (m3)
3174569 | 0.00815463
3175245 | 0.00815463
9276350 | 0.00637765 | Group: Model Group:Staalconstructie bestaande gymzaal:5957079

# IfcColumn: Buisprofielen_ITX(c):Buis 20x2 (3)
In: 01 eerste verdieping
Type - PredefinedType: COLUMN; Material: NLRS_h3_staal_verzinkt
Type - Pset_ColumnCommon - IsExternal: no; LoadBearing: yes; Reference: Buisprofielen_ITX(c):Buis 20x2
Type - Pset_ProductRequirements - Category: Structural Columns
Type - Pset_QuantityTakeOff - Reference: Buisprofielen_ITX(c):Buis 20x2
Type - Pset_ReinforcementBarPitchOfColumn - Reference: Buisprofielen_ITX(c):Buis 20x2
BaseQuantities - GrossSurfaceArea: 0 m2; GrossVolume: 0.000197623 m3
Pset_QuantityTakeOff - sets with these values: 2
Name (Buisprofielen_ITX(c):Buis 20x2:...)
8382318
8382440
9829985

# IfcColumn: NLRS_28_SC_UN_HE-profielen_gen_aly:HEA160 (18)
In: 00 begane grond
Type - PredefinedType: COLUMN; Classification: 28.11 hoofddraagconstructies; kolommen en liggers, kolom-/liggerconstructies (Uniformat); Material: NLRS_h3_staal_verzinkt
Type - Pset_ColumnCommon - IsExternal: no; Reference: NLRS_28_SC_UN_HE-profielen_gen_aly:HEA160; LoadBearing: yes
Type - Pset_ProductRequirements - Category: Structural Columns
Type - Pset_QuantityTakeOff - Reference: NLRS_28_SC_UN_HE-profielen_gen_aly:HEA160
Type - Pset_ReinforcementBarPitchOfColumn - Description: HEA160; Reference: NLRS_28_SC_UN_HE-profielen_gen_aly:HEA160
BaseQuantities - GrossSurfaceArea: 0 m2
Group: Model Group:Staalconstructie bestaande gymzaal:5957079
Name (NLRS_28_SC_UN_HE-profielen_gen_aly:HEA160:...) | GrossVolume (m3)
2884652 | 0.0213083
2884815 | 0.0213083
2884839 | 0.0213083
2885079 | 0.0213083
2885110 | 0.021929
2885174 | 0.0213083
2885189 | 0.0213083
2885204 | 0.0213083
2885219 | 0.021929
2885524 | 0.0219143
2885629 | 0.0213083
2885678 | 0.0213083
2885697 | 0.0219143
2885712 | 0.0213083
2885833 | 0.0213083
2885895 | 0.0213083
2885910 | 0.0213083
2887177 | 0.0116562

# IfcCovering: 41_Cedral start-roosterprofiel35:Cedral start-roosterprofiel, 41_Cedral start-roosterprofiel35:Cedral start-roosterprofiel:11649564
In: Podium
Type - Pset_CoveringCommon - Reference: 41_Cedral start-roosterprofiel35:Cedral start-roosterprofiel
Type - Pset_ProductRequirements - Category: Generic Models
Type - Pset_QuantityTakeOff - Reference: 41_Cedral start-roosterprofiel35:Cedral start-roosterprofiel
Classification: 41.10 buitenwandafwerkingen; algemeen (verzamelniveau) (Uniformat); Material: h4_aluminium kleur Asgrijs
Pset_CoveringCommon - sets with these values: 2
BaseQuantities - GrossCeilingArea: 0.109455 m2

# IfcCovering: Akoestische panelen 16:Akoestische panelen 16, Akoestische panelen 16:Akoestische panelen 16:3886771
In: 01 eerste verdieping
Type - Pset_CoveringCommon - Reference: Akoestische panelen 16:Akoestische panelen 16
Type - Pset_ProductRequirements - Category: Ceilings
Type - Pset_QuantityTakeOff - Reference: Akoestische panelen 16:Akoestische panelen 16
Material: NLRS_m1_systeemplafond 600x600mm
Pset_CoveringCommon - sets with these values: 2
BaseQuantities - GrossCeilingArea: 74.88 m2

# IfcCovering: Akoestische panelen 17:Akoestische panelen 2, Akoestische panelen 17:Akoestische panelen 2:4307327
In: Podium
Type - Pset_CoveringCommon - Reference: Akoestische panelen 17:Akoestische panelen 2
Type - Pset_ProductRequirements - Category: Ceilings
Type - Pset_QuantityTakeOff - Reference: Akoestische panelen 17:Akoestische panelen 2
Material: NLRS_m1_systeemplafond 600x600mm
Pset_CoveringCommon - sets with these values: 2
BaseQuantities - GrossCeilingArea: 11.3551 m2

# IfcCovering: Akoestische panelen 18:Akoestische panelen 2, Akoestische panelen 18:Akoestische panelen 2:4307547
In: Podium
Type - Pset_CoveringCommon - Reference: Akoestische panelen 18:Akoestische panelen 2
Type - Pset_ProductRequirements - Category: Ceilings
Type - Pset_QuantityTakeOff - Reference: Akoestische panelen 18:Akoestische panelen 2
Material: NLRS_m1_systeemplafond 600x600mm
Pset_CoveringCommon - sets with these values: 2
BaseQuantities - GrossCeilingArea: 11.3551 m2

# IfcCovering: Akoestische panelen 19:Akoestische panelen 2, Akoestische panelen 19:Akoestische panelen 2:10289668
In: Podium
Type - Pset_CoveringCommon - Reference: Akoestische panelen 19:Akoestische panelen 2
Type - Pset_ProductRequirements - Category: Ceilings
Type - Pset_QuantityTakeOff - Reference: Akoestische panelen 19:Akoestische panelen 2
Material: NLRS_m1_systeemplafond 600x600mm
Pset_CoveringCommon - sets with these values: 2
BaseQuantities - GrossCeilingArea: 11.518 m2

# IfcCovering: Akoestische panelen 1:Akoestische panelen 2, Akoestische panelen 1:Akoestische panelen 2:6639480
In: Podium
Type - Pset_CoveringCommon - Reference: Akoestische panelen 1:Akoestische panelen 2
Type - Pset_ProductRequirements - Category: Ceilings
Type - Pset_QuantityTakeOff - Reference: Akoestische panelen 1:Akoestische panelen 2
Material: NLRS_m1_systeemplafond 600x600mm
Pset_CoveringCommon - sets with these values: 2
BaseQuantities - GrossCeilingArea: 11.3427 m2

# IfcCovering: Akoestische panelen 20:Akoestische panelen 2, Akoestische panelen 20:Akoestische panelen 2:10289678
In: Podium
Type - Pset_CoveringCommon - Reference: Akoestische panelen 20:Akoestische panelen 2
Type - Pset_ProductRequirements - Category: Ceilings
Type - Pset_QuantityTakeOff - Reference: Akoestische panelen 20:Akoestische panelen 2
Material: NLRS_m1_systeemplafond 600x600mm
Pset_CoveringCommon - sets with these values: 2
BaseQuantities - GrossCeilingArea: 11.5589 m2

# IfcCovering: Akoestische panelen 21:Akoestische panelen 2, Akoestische panelen 21:Akoestische panelen 2:10289736
In: Podium
Type - Pset_CoveringCommon - Reference: Akoestische panelen 21:Akoestische panelen 2
Type - Pset_ProductRequirements - Category: Ceilings
Type - Pset_QuantityTakeOff - Reference: Akoestische panelen 21:Akoestische panelen 2
Material: NLRS_m1_systeemplafond 600x600mm
Pset_CoveringCommon - sets with these values: 2
BaseQuantities - GrossCeilingArea: 11.5355 m2

# IfcCovering: Akoestische panelen 22:Akoestische panelen 2, Akoestische panelen 22:Akoestische panelen 2:10289746
In: Podium
Type - Pset_CoveringCommon - Reference: Akoestische panelen 22:Akoestische panelen 2
Type - Pset_ProductRequirements - Category: Ceilings
Type - Pset_QuantityTakeOff - Reference: Akoestische panelen 22:Akoestische panelen 2
Material: NLRS_m1_systeemplafond 600x600mm
Pset_CoveringCommon - sets with these values: 2
BaseQuantities - GrossCeilingArea: 11.533 m2

# IfcCovering: Akoestische panelen 23:Akoestische panelen 2, Akoestische panelen 23:Akoestische panelen 2:10289804
In: Podium
Type - Pset_CoveringCommon - Reference: Akoestische panelen 23:Akoestische panelen 2
Type - Pset_ProductRequirements - Category: Ceilings
Type - Pset_QuantityTakeOff - Reference: Akoestische panelen 23:Akoestische panelen 2
Material: NLRS_m1_systeemplafond 600x600mm
Pset_CoveringCommon - sets with these values: 2
BaseQuantities - GrossCeilingArea: 11.4686 m2

# IfcCovering: Akoestische panelen 24:Akoestische panelen 2, Akoestische panelen 24:Akoestische panelen 2:10289814
In: Podium
Type - Pset_CoveringCommon - Reference: Akoestische panelen 24:Akoestische panelen 2
Type - Pset_ProductRequirements - Category: Ceilings
Type - Pset_QuantityTakeOff - Reference: Akoestische panelen 24:Akoestische panelen 2
Material: NLRS_m1_systeemplafond 600x600mm
Pset_CoveringCommon - sets with these values: 2
BaseQuantities - GrossCeilingArea: 11.5019 m2

# IfcCovering: Akoestische panelen 2:Akoestische panelen 2, Akoestische panelen 2:Akoestische panelen 2:6639617
In: Podium
Type - Pset_CoveringCommon - Reference: Akoestische panelen 2:Akoestische panelen 2
Type - Pset_ProductRequirements - Category: Ceilings
Type - Pset_QuantityTakeOff - Reference: Akoestische panelen 2:Akoestische panelen 2
Material: NLRS_m1_systeemplafond 600x600mm
Pset_CoveringCommon - sets with these values: 2
BaseQuantities - GrossCeilingArea: 11.3427 m2

# IfcCovering: Akoestische panelen 3:Akoestische panelen 2, Akoestische panelen 3:Akoestische panelen 2:3888703
In: Podium
Type - Pset_CoveringCommon - Reference: Akoestische panelen 3:Akoestische panelen 2
Type - Pset_ProductRequirements - Category: Ceilings
Type - Pset_QuantityTakeOff - Reference: Akoestische panelen 3:Akoestische panelen 2
Material: NLRS_m1_systeemplafond 600x600mm
Pset_CoveringCommon - sets with these values: 2
BaseQuantities - GrossCeilingArea: 11.5187 m2

# IfcCovering: Akoestische panelen 4:Akoestische panelen 2, Akoestische panelen 4:Akoestische panelen 2:3974944
In: 01 eerste verdieping
Type - Pset_CoveringCommon - Reference: Akoestische panelen 4:Akoestische panelen 2
Type - Pset_ProductRequirements - Category: Ceilings
Type - Pset_QuantityTakeOff - Reference: Akoestische panelen 4:Akoestische panelen 2
Material: NLRS_m1_systeemplafond 600x600mm
Pset_CoveringCommon - sets with these values: 2
BaseQuantities - GrossCeilingArea: 14.4 m2

# IfcCovering: Akoestische panelen 5:Akoestische panelen 2, Akoestische panelen 5:Akoestische panelen 2:10289490
In: Podium
Type - Pset_CoveringCommon - Reference: Akoestische panelen 5:Akoestische panelen 2
Type - Pset_ProductRequirements - Category: Ceilings
Type - Pset_QuantityTakeOff - Reference: Akoestische panelen 5:Akoestische panelen 2
Material: NLRS_m1_systeemplafond 600x600mm
Pset_CoveringCommon - sets with these values: 2
BaseQuantities - GrossCeilingArea: 11.5187 m2

# IfcCovering: Akoestische panelen 6:Akoestische panelen 2, Akoestische panelen 6:Akoestische panelen 2:10289500
In: Podium
Type - Pset_CoveringCommon - Reference: Akoestische panelen 6:Akoestische panelen 2
Type - Pset_ProductRequirements - Category: Ceilings
Type - Pset_QuantityTakeOff - Reference: Akoestische panelen 6:Akoestische panelen 2
Material: NLRS_m1_systeemplafond 600x600mm
Pset_CoveringCommon - sets with these values: 2
BaseQuantities - GrossCeilingArea: 11.5156 m2

# IfcCovering: Akoestische panelen 7:Akoestische panelen 2, Akoestische panelen 7:Akoestische panelen 2:10289568
In: Podium
Type - Pset_CoveringCommon - Reference: Akoestische panelen 7:Akoestische panelen 2
Type - Pset_ProductRequirements - Category: Ceilings
Type - Pset_QuantityTakeOff - Reference: Akoestische panelen 7:Akoestische panelen 2
Material: NLRS_m1_systeemplafond 600x600mm
Pset_CoveringCommon - sets with these values: 2
BaseQuantities - GrossCeilingArea: 11.5426 m2

# IfcCovering: Akoestische panelen 8:Akoestische panelen 2, Akoestische panelen 8:Akoestische panelen 2:10289578
In: Podium
Type - Pset_CoveringCommon - Reference: Akoestische panelen 8:Akoestische panelen 2
Type - Pset_ProductRequirements - Category: Ceilings
Type - Pset_QuantityTakeOff - Reference: Akoestische panelen 8:Akoestische panelen 2
Material: NLRS_m1_systeemplafond 600x600mm
Pset_CoveringCommon - sets with these values: 2
BaseQuantities - GrossCeilingArea: 11.5715 m2

# IfcCovering: Akoestische panelen 9:Akoestische panelen 2, Akoestische panelen 9:Akoestische panelen 2:3979976
In: Podium
Type - Pset_CoveringCommon - Reference: Akoestische panelen 9:Akoestische panelen 2
Type - Pset_ProductRequirements - Category: Ceilings
Type - Pset_QuantityTakeOff - Reference: Akoestische panelen 9:Akoestische panelen 2
Material: NLRS_m1_systeemplafond 600x600mm
Pset_CoveringCommon - sets with these values: 2
BaseQuantities - GrossCeilingArea: 11.5203 m2

# IfcCovering: Basic Roof:47.11_2 laagse Bitumen dakbedekking (5)
Type - Pset_CoveringCommon - Reference: Basic Roof:47.11_2 laagse Bitumen dakbedekking
Type - Pset_ElementShading - Roughness: 304.8 mm
Type - Pset_ManufacturerTypeInformation - Manufacturer: -
Type - Pset_ProductRequirements - Category: Roofs
Type - Pset_QuantityTakeOff - Reference: Basic Roof:47.11_2 laagse Bitumen dakbedekking
Classification: 47.11 dakafwerkingen; afwerkingen, vlakke dakafwerkingen (Uniformat); Material: NLRS_n2_bitumen_dak bedekking 6 mm
Pset_CoveringCommon - TotalThickness: 6 mm
Name (Basic Roof:47.11_2 laagse Bitumen dakbedekking:...) | In | GrossCeilingArea (m2)
6406116 | 06 zesde verdieping | 384.771
8057000 | 01 eerste verdieping | 61.4532
9045819 | 01 eerste verdieping | 127.982
9049677 | 01 eerste verdieping | 529.668
9209427 | 01 eerste verdieping | 165.394

# IfcCovering: Basic Roof:NLRS_47_Felsdak zink (5)
In: 01 eerste verdieping
Classification: 47.12 dakafwerkingen; afwerkingen, hellende dakafwerkingen (Uniformat)
Pset_CoveringCommon - Reference: Basic Roof:NLRS_47_Felsdak zink; TotalThickness: 1 mm
Pset_ElementShading - Roughness: 304.8 mm
Pset_ProductRequirements - Category: Roofs
Pset_QuantityTakeOff - Reference: Basic Roof:NLRS_47_Felsdak zink
Name (Basic Roof:NLRS_47_Felsdak zink:...) | GrossCeilingArea (m2)
3169807 | 436.364
4229884 | 259.054
4261570 | 22.2561
4563552 | 14.0038
4563951 | 14.0057

# IfcCovering: Basic Roof:NLRS_47_Felsdak zink, Basic Roof:NLRS_47_Felsdak zink:3169802
In: 01 eerste verdieping
Type - Pset_CoveringCommon - Reference: Basic Roof:NLRS_47_Felsdak zink
Type - Pset_ElementShading - Roughness: 304.8 mm
Type - Pset_ProductRequirements - Category: Roofs
Type - Pset_QuantityTakeOff - Reference: Basic Roof:NLRS_47_Felsdak zink
Classification: 47.12 dakafwerkingen; afwerkingen, hellende dakafwerkingen (Uniformat); Material: AL_Aluminium zwart 1 mm
Pset_CoveringCommon - TotalThickness: 1 mm
BaseQuantities - GrossCeilingArea: 517.595 m2

# IfcCovering: Basic Roof:NLRS_47_PIR dakisolatie 142mm, Basic Roof:NLRS_47_PIR dakisolatie 142mm:6406103
In: 06 zesde verdieping
Type - Pset_CoveringCommon - Reference: Basic Roof:NLRS_47_PIR dakisolatie 142mm
Type - Pset_ElementShading - Roughness: 304.8 mm
Type - Pset_ProductRequirements - Category: Roofs
Type - Pset_QuantityTakeOff - Reference: Basic Roof:NLRS_47_PIR dakisolatie 142mm
Classification: 47.12 dakafwerkingen; afwerkingen, hellende dakafwerkingen (Uniformat); Material: NLRS_n7_isolatie PIR_gen 142 mm
Pset_CoveringCommon - TotalThickness: 142 mm
BaseQuantities - GrossCeilingArea: 126.335 m2

# IfcCovering: Basic Roof:NLRS_47_PIR dakisolatie 50mm, Basic Roof:NLRS_47_PIR dakisolatie 50mm:6408851
In: 06 zesde verdieping
Type - Pset_CoveringCommon - Reference: Basic Roof:NLRS_47_PIR dakisolatie 50mm
Type - Pset_ElementShading - Roughness: 304.8 mm
Type - Pset_ProductRequirements - Category: Roofs
Type - Pset_QuantityTakeOff - Reference: Basic Roof:NLRS_47_PIR dakisolatie 50mm
Classification: 47.12 dakafwerkingen; afwerkingen, hellende dakafwerkingen (Uniformat); Material: NLRS_n7_isolatie PIR_gen 50 mm
Pset_CoveringCommon - TotalThickness: 50 mm
BaseQuantities - GrossCeilingArea: 260.971 m2

# IfcCovering: Basic Roof:NLRS_47_SAB 35/1035 profiel plaat (3)
In: 01 eerste verdieping
Type - Pset_CoveringCommon - Reference: Basic Roof:NLRS_47_SAB 35/1035 profiel plaat
Type - Pset_ElementShading - Roughness: 304.8 mm
Type - Pset_ProductRequirements - Category: Roofs
Type - Pset_QuantityTakeOff - Reference: Basic Roof:NLRS_47_SAB 35/1035 profiel plaat
Classification: 47.12 dakafwerkingen; afwerkingen, hellende dakafwerkingen (Uniformat); Material: NLRS_h4_aluminium sandwichpaneel horizontaal geprofileerd zwart verticaal 1 mm, NLRS_j9_lucht_gen 33 mm, NLRS_h4_aluminium_gen 1 mm
Pset_CoveringCommon - TotalThickness: 35 mm
Name (Basic Roof:NLRS_47_SAB 35/1035 profiel plaat:...) | GrossCeilingArea (m2)
6395569 | 79.8671
6395930 | 75.0086
6396561 | 58.8512

# IfcCovering: Basic Roof:NLRS_47_Sandwichpaneel KS Slate & tile support sandwichpaneel 137mm (2)
In: 01 eerste verdieping
Type - Pset_CoveringCommon - Reference: Basic Roof:NLRS_47_Sandwichpaneel KS Slate & tile support sandwichpaneel 137mm
Type - Pset_ElementShading - Roughness: 304.8 mm
Type - Pset_ProductRequirements - Category: Roofs
Type - Pset_QuantityTakeOff - Reference: Basic Roof:NLRS_47_Sandwichpaneel KS Slate & tile support sandwichpaneel 137mm
Classification: 47.12 dakafwerkingen; afwerkingen, hellende dakafwerkingen (Uniformat); Material: NLRS_h4_aluminium sandwichpaneel horizontaal geprofileerd zwart verticaal 1 mm, NLRS_j9_lucht_gen 30 mm, NLRS_h4_aluminium_gen 5 mm, NLRS_n7_isolatie PIR_gen 127 mm, NLRS_h4_aluminium_gen 5 mm
Pset_CoveringCommon - TotalThickness: 168 mm
Name (Basic Roof:NLRS_47_Sandwichpaneel KS Slate & tile support sandwichpaneel 137mm:...) | GrossCeilingArea (m2)
6396330 | 18.1767
6396416 | 30.1922

# IfcCovering: Basic Roof:NLRS_47_Trampeziumplaat 106R/750, Basic Roof:NLRS_47_Trampeziumplaat 106R/750:6406087
In: 02 tweede verdieping
Classification: 47.12 dakafwerkingen; afwerkingen, hellende dakafwerkingen (Uniformat)
Pset_CoveringCommon - Reference: Basic Roof:NLRS_47_Trampeziumplaat 106R/750; TotalThickness: 108 mm
Pset_ElementShading - Roughness: 304.8 mm
Pset_ProductRequirements - Category: Roofs
Pset_QuantityTakeOff - Reference: Basic Roof:NLRS_47_Trampeziumplaat 106R/750
BaseQuantities - GrossCeilingArea: 129.094 m2

# IfcCovering: Basic Roof:NLRS_47_Trespa 10mm RAL 9002, Basic Roof:NLRS_47_Trespa 10mm RAL 9002:9820310
In: 01 eerste verdieping
Classification: 47.12 dakafwerkingen; afwerkingen, hellende dakafwerkingen (Uniformat)
Pset_CoveringCommon - Reference: Basic Roof:NLRS_47_Trespa 10mm RAL 9002; TotalThickness: 10 mm
Pset_ElementShading - Roughness: 304.8 mm
Pset_ProductRequirements - Category: Roofs
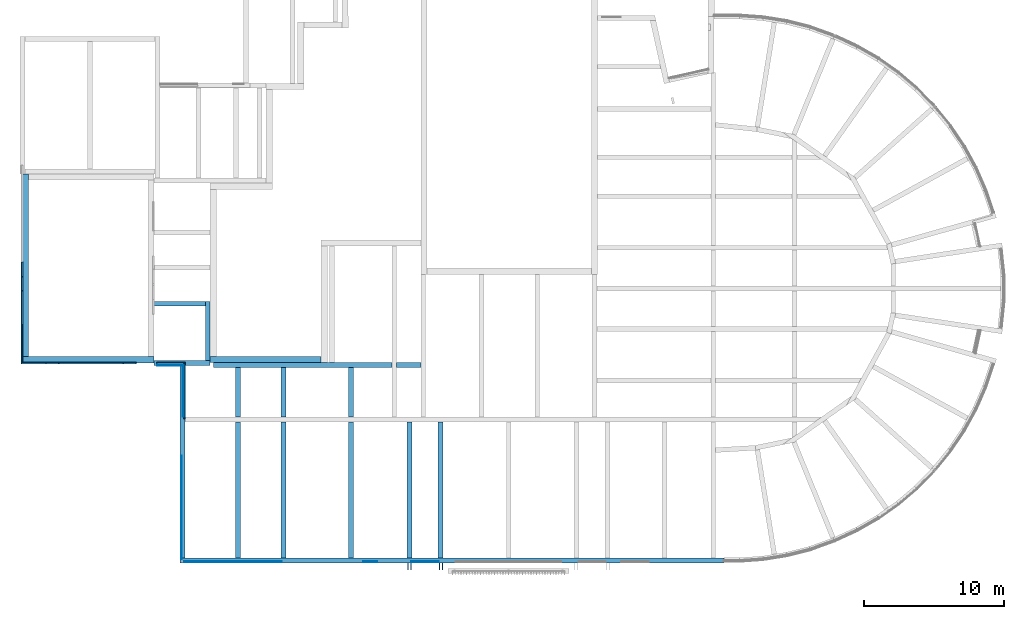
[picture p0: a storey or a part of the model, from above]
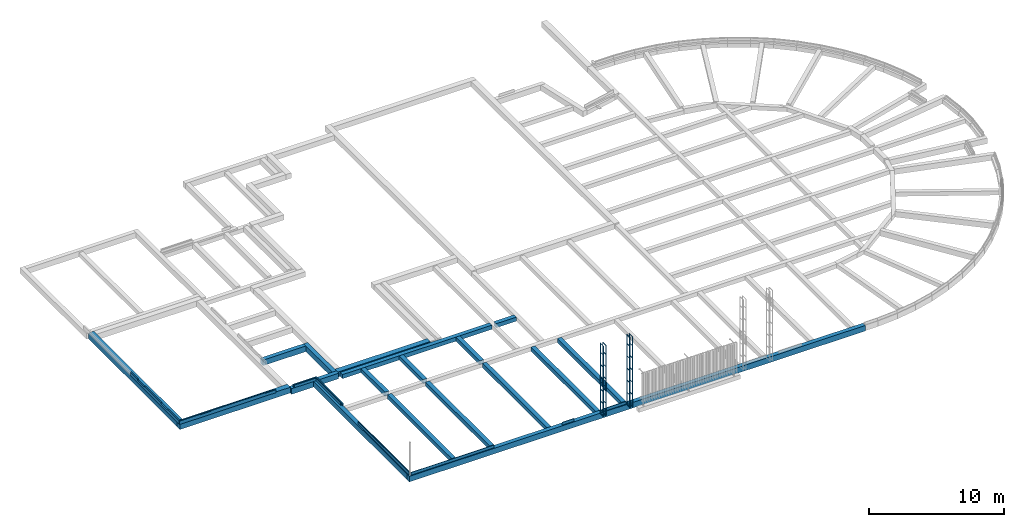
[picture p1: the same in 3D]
Properties of the parts of a building model (IFC2X3), part 3 of 13

# IfcCovering: Basic Roof:NLRS_47_Trespa 10mm RAL 9002, Basic Roof:NLRS_47_Trespa 10mm RAL 9002:9820310
Pset_QuantityTakeOff - Reference: Basic Roof:NLRS_47_Trespa 10mm RAL 9002
BaseQuantities - GrossCeilingArea: 1.60701 m2

# IfcCovering: Basic Roof:NLRS_47_Trespa 10mm zwart (4)
Classification: 47.12 dakafwerkingen; afwerkingen, hellende dakafwerkingen (Uniformat)
Pset_CoveringCommon - Reference: Basic Roof:NLRS_47_Trespa 10mm zwart; TotalThickness: 10 mm
Pset_ElementShading - Roughness: 304.8 mm
Pset_ProductRequirements - Category: Roofs
Pset_QuantityTakeOff - Reference: Basic Roof:NLRS_47_Trespa 10mm zwart
Name (Basic Roof:NLRS_47_Trespa 10mm zwart:...) | In | GrossCeilingArea (m2)
5301534 | Podium | 4.05061
5301710 | Podium | 3.74253
9926886 | 01 eerste verdieping | 18.1915
9927130 | 01 eerste verdieping | 4.18523

# IfcCovering: Basic Roof:NLRS_47_Trespa 8mm zwart (2)
In: Podium
Type - Pset_CoveringCommon - Reference: Basic Roof:NLRS_47_Trespa 8mm zwart
Type - Pset_ElementShading - Roughness: 304.8 mm
Type - Pset_ProductRequirements - Category: Roofs
Type - Pset_QuantityTakeOff - Reference: Basic Roof:NLRS_47_Trespa 8mm zwart
Classification: 47.12 dakafwerkingen; afwerkingen, hellende dakafwerkingen (Uniformat); Material: NLRS_i4_hout_multiplex zwart 8 mm
Pset_CoveringCommon - TotalThickness: 8 mm
Name (Basic Roof:NLRS_47_Trespa 8mm zwart:...) | GrossCeilingArea (m2)
11328492 | 2.85896
11861726 | 2.84297

# IfcCovering: Basic Roof:NLRS_47_multiplex betimmering (2)
In: 01 eerste verdieping
Classification: 47.12 dakafwerkingen; afwerkingen, hellende dakafwerkingen (Uniformat)
Pset_CoveringCommon - Reference: Basic Roof:NLRS_47_multiplex betimmering; TotalThickness: 15 mm
Pset_ElementShading - Roughness: 304.8 mm
Pset_ProductRequirements - Category: Roofs
Pset_QuantityTakeOff - Reference: Basic Roof:NLRS_47_multiplex betimmering
BaseQuantities - GrossCeilingArea: 0.919465 m2
Name (Basic Roof:NLRS_47_multiplex betimmering:...)
11079969
11080229

# IfcCovering: Basic Roof:NLRS_47_multiplex betimmering zwart (2)
In: 00 begane grond
Classification: 47.12 dakafwerkingen; afwerkingen, hellende dakafwerkingen (Uniformat)
Pset_CoveringCommon - Reference: Basic Roof:NLRS_47_multiplex betimmering zwart; TotalThickness: 15 mm
Pset_ElementShading - Roughness: 304.8 mm
Pset_ProductRequirements - Category: Roofs
Pset_QuantityTakeOff - Reference: Basic Roof:NLRS_47_multiplex betimmering zwart
Name (Basic Roof:NLRS_47_multiplex betimmering zwart:...) | GrossCeilingArea (m2)
5954974 | 14.6582
9448588 | 0.658753

# IfcCovering: Compound Ceiling:NLRS_45_CEI_systeemplafond 600x600mm_dikte 20mm_gen_aly (51)
Type - PredefinedType: CEILING
Type - Pset_CoveringCommon - Reference: Compound Ceiling:NLRS_45_CEI_systeemplafond 600x600mm_dikte 20mm_gen_aly; TotalThickness: 20 mm
Type - Pset_ElementShading - Roughness: 304.8 mm
Type - Pset_ManufacturerTypeInformation - Manufacturer: -
Type - Pset_ProductRequirements - Category: Ceilings
Type - Pset_QuantityTakeOff - Reference: Compound Ceiling:NLRS_45_CEI_systeemplafond 600x600mm_dikte 20mm_gen_aly
Classification: 45.12 plafondafwerkingen; verlaagd, systeem plafonds (Uniformat); Material: NLRS_m1_systeemplafond 600x600mm 20 mm
Name (Compound Ceiling:NLRS_45_CEI_systeemplafond 600x600mm_dikte 20mm_gen_aly:...) | In | GrossCeilingArea (m2)
3858190 | Podium | 74.9655
3858349 | Podium | 75.0407
3858448 | Podium | 13.8117
3858461 | Podium | 12.7497
3858473 | Podium | 8.63294
3858481 | Podium | 8.67007
3858489 | Podium | 12.8174
3858934 | Podium | 6.63617
3858942 | Podium | 6.63565
3858950 | Podium | 5.91798
3858958 | 1.05 | 8.21485
3858966 | Podium | 5.01886
3859373 | Podium | 62.0194
3859401 | 11.09 | 9.62896
3859422 | Podium | 5.69505
3859430 | 11.10 | 9.43756
3859461 | Podium | 37.2551
3861127 | Podium | 14.6376
3861307 | Podium | 48.7279
3861732 | 7.04 | 9.72567
3861750 | 7.03 | 8.53842
3862888 | Podium | 26.6771
3872182 | Podium | 7.78759
3872579 | Podium | 19.8687
3873401 | 6.04a | 2.44712
3873516 | 6.04a | 4.52615
3873549 | 6.04b | 4.54242
3873585 | 6.04b | 2.42747
3873759 | Podium | 22.4664
3874030 | Podium | 0.976261
3874069 | Podium | 0.978733
3874108 | Podium | 22.4853
4320151 | 1.07 | 1.3442
5705845 | Podium | 8.78382
6635153 | Podium | 9.59424
9110546 | Podium | 13.4923
9113377 | 11.12 | 5.4
9113524 | 4.04 | 6.075
9113541 | 01 eerste verdieping | 1.725
9113622 | 01 eerste verdieping | 1.725
9826110 | 7.01 | 10.0573
10195599 | 5.04 | 3.825
10195736 | 1.07 | 1.3442
10195754 | 1.07 | 1.3442
10195772 | 1.05a | 1.27182
10195821 | 1.05b | 1.3442
10195839 | 1.05b | 1.3442
10195857 | 1.05a | 1.3442
10195875 | 1.05a | 4.29264
10195968 | 1.05b | 4.29264
10195988 | 1.07 | 6.53796

# IfcCovering: Compound Ceiling:NLRS_45_CEI_systeemplafond afwasbaar (2)
In: Podium
Type - PredefinedType: CEILING
Type - Pset_CoveringCommon - Reference: Compound Ceiling:NLRS_45_CEI_systeemplafond afwasbaar; TotalThickness: 20 mm
Type - Pset_ElementShading - Roughness: 304.8 mm
Type - Pset_ManufacturerTypeInformation - Manufacturer: -
Type - Pset_ProductRequirements - Category: Ceilings
Type - Pset_QuantityTakeOff - Reference: Compound Ceiling:NLRS_45_CEI_systeemplafond afwasbaar
Classification: 45.12 plafondafwerkingen; verlaagd, systeem plafonds (Uniformat); Material: NLRS_m1_systeemplafond 600x600mm 20 mm
Name (Compound Ceiling:NLRS_45_CEI_systeemplafond afwasbaar:...) | GrossCeilingArea (m2)
3869390 | 18.4344
3869422 | 17.1753

# IfcCovering: Compound Ceiling:NLRS_45_CEI_systeemplafond nieuwe platen in oude constructie (5)
Type - PredefinedType: CEILING
Type - Pset_CoveringCommon - Reference: Compound Ceiling:NLRS_45_CEI_systeemplafond nieuwe platen in oude constructie; TotalThickness: 20 mm
Type - Pset_ElementShading - Roughness: 304.8 mm
Type - Pset_ManufacturerTypeInformation - Manufacturer: -
Type - Pset_ProductRequirements - Category: Ceilings
Type - Pset_QuantityTakeOff - Reference: Compound Ceiling:NLRS_45_CEI_systeemplafond nieuwe platen in oude constructie
Classification: 45.12 plafondafwerkingen; verlaagd, systeem plafonds (Uniformat); Material: NLRS_m1_systeemplafond 600x600mm 20 mm
Name (Compound Ceiling:NLRS_45_CEI_systeemplafond nieuwe platen in oude constructie:...) | In | GrossCeilingArea (m2)
3874270 | Podium | 22.2557
3874522 | 00 begane grond | 27.8113
3874661 | 00 begane grond | 27.7444
3874796 | 00 begane grond | 1.24707
3874866 | 00 begane grond | 1.24172

# IfcCovering: Floor:43_Afwerkvloer_70mm (7)
In: 00 begane grond
Type - PredefinedType: FLOORING; Material: q2_afwerkvloer 1 70 mm
Type - Pset_CoveringCommon - Reference: Floor:43_Afwerkvloer_70mm
Type - Pset_ElementShading - Roughness: 304.8 mm
Type - Pset_ProductRequirements - Category: Floors
Type - Pset_QuantityTakeOff - Reference: Floor:43_Afwerkvloer_70mm
Classification: 43.21 vloerafwerkingen; niet verhoogd, afwerklagen (Uniformat)
Pset_CoveringCommon - TotalThickness: 70 mm
Name (Floor:43_Afwerkvloer_70mm:...) | GrossCeilingArea (m2)
3905027 | 27.8951
3907459 | 14.8835
3925866 | 6.71347
3947953 | 14.5981
4093567 | 12.6719
4094048 | 8.94412
4094265 | 9.07887

# IfcCovering: Floor:43_Hetrogoen vinyl B1_70mm (33)
In: 00 begane grond
Type - PredefinedType: FLOORING; Material: q2_afwerkvloer 1 70 mm
Type - Pset_CoveringCommon - Reference: Floor:43_Hetrogoen vinyl B1_70mm
Type - Pset_ElementShading - Roughness: 304.8 mm
Type - Pset_ProductRequirements - Category: Floors
Type - Pset_QuantityTakeOff - Reference: Floor:43_Hetrogoen vinyl B1_70mm
Classification: 43.21 vloerafwerkingen; niet verhoogd, afwerklagen (Uniformat)
Pset_CoveringCommon - TotalThickness: 70 mm
Name (Floor:43_Hetrogoen vinyl B1_70mm:...) | GrossCeilingArea (m2)
3917730 | 23.2444
3918045 | 6.74186
3918445 | 18.7927
3918693:2 | 20.7896
3919345 | 90.8387
3920700 | 6.96919
3922586 | 8.53562
3924069 | 173.849
3926161 | 19.4047
3927070 | 19.8948
3927872 | 56.315
3929858 | 88.1734
3931588 | 88.2505
3933047 | 53.3859
3934635 | 52.7582
3938110 | 52.8486
3939611 | 53.3801
3940922 | 54.6675
3942620 | 2.13273
3952934 | 1.75481
3952986 | 1.75481
3953002 | 1.78523
4324143 | 3.9284
5618342 | 34.5996
5706723 | 1.92973
9111800 | 3.81063
10065086 | 5.5034
10220732 | 10.984
10221283 | 7.29124
10221446 | 7.29124
10221478 | 11.0468
10221673 | 12.1597
10221909 | 2.5034

# IfcCovering: Floor:43_Hetrogoen vinyl B1_70mm, Floor:43_Hetrogoen vinyl B1_70mm:3918693
In: 00 begane grond
Type - PredefinedType: FLOORING
Type - Pset_CoveringCommon - Reference: Floor:43_Hetrogoen vinyl B1_70mm
Type - Pset_ElementShading - Roughness: 304.8 mm
Type - Pset_ProductRequirements - Category: Floors
Type - Pset_QuantityTakeOff - Reference: Floor:43_Hetrogoen vinyl B1_70mm
Classification: 43.21 vloerafwerkingen; niet verhoogd, afwerklagen (Uniformat); Material: q2_afwerkvloer 1 70 mm
Pset_CoveringCommon - TotalThickness: 70 mm
BaseQuantities - GrossCeilingArea: 20.7896 m2

# IfcCovering: Floor:43_Hetrogoen vinyl B1_70mm (mf zaal), Floor:43_Hetrogoen vinyl B1_70mm (mf zaal):3921060
In: 00 begane grond
Type - PredefinedType: FLOORING; Material: q2_afwerkvloer 2 70 mm
Type - Pset_CoveringCommon - Reference: Floor:43_Hetrogoen vinyl B1_70mm (mf zaal)
Type - Pset_ElementShading - Roughness: 304.8 mm
Type - Pset_ProductRequirements - Category: Floors
Type - Pset_QuantityTakeOff - Reference: Floor:43_Hetrogoen vinyl B1_70mm (mf zaal)
Classification: 43.21 vloerafwerkingen; niet verhoogd, afwerklagen (Uniformat)
Pset_CoveringCommon - TotalThickness: 70 mm
BaseQuantities - GrossCeilingArea: 162.103 m2

# IfcCovering: Floor:43_Projecttapijt tegels 600x600 (5)
In: 00 begane grond
Type - PredefinedType: FLOORING; Material: NLRS_n6_tapijt vinyl_gen 5 mm
Type - Pset_CoveringCommon - Reference: Floor:43_Projecttapijt tegels 600x600
Type - Pset_ElementShading - Roughness: 304.8 mm
Type - Pset_ProductRequirements - Category: Floors
Type - Pset_QuantityTakeOff - Reference: Floor:43_Projecttapijt tegels 600x600
Classification: 43.21 vloerafwerkingen; niet verhoogd, afwerklagen (Uniformat)
Pset_CoveringCommon - TotalThickness: 5 mm
Name (Floor:43_Projecttapijt tegels 600x600:...) | GrossCeilingArea (m2)
3952262 | 8.67417
3952386 | 8.63294
3952411 | 12.9764
3993366 | 28.7828
3994990 | 25.4659

# IfcCovering: Floor:43_Schoonlooptapeit_5mm (6)
In: 00 begane grond
Type - PredefinedType: FLOORING; Material: NLRS_n6_schoonloop tapijt 5 mm
Type - Pset_CoveringCommon - Reference: Floor:43_Schoonlooptapeit_5mm
Type - Pset_ElementShading - Roughness: 304.8 mm
Type - Pset_ProductRequirements - Category: Floors
Type - Pset_QuantityTakeOff - Reference: Floor:43_Schoonlooptapeit_5mm
Classification: 43.21 vloerafwerkingen; niet verhoogd, afwerklagen (Uniformat)
Pset_CoveringCommon - TotalThickness: 5 mm
Name (Floor:43_Schoonlooptapeit_5mm:...) | GrossCeilingArea (m2)
4839853 | 9.82891
4839945 | 13.0438
4839990 | 26.7256
4840048 | 6.61015
4840126 | 14.6428
7762050 | 9.87836

# IfcCovering: Floor:43_Vloercoating_70mm (2)
In: 00 begane grond
Type - PredefinedType: FLOORING; Material: q2_afwerkvloer 4 70 mm
Type - Pset_CoveringCommon - Reference: Floor:43_Vloercoating_70mm
Type - Pset_ElementShading - Roughness: 304.8 mm
Type - Pset_ProductRequirements - Category: Floors
Type - Pset_QuantityTakeOff - Reference: Floor:43_Vloercoating_70mm
Classification: 43.21 vloerafwerkingen; niet verhoogd, afwerklagen (Uniformat)
Pset_CoveringCommon - TotalThickness: 70 mm
Name (Floor:43_Vloercoating_70mm:...) | GrossCeilingArea (m2)
3942896 | 17.5279
3943158 | 89.7726

# IfcCovering: Floor:43_gietvloer 5mm (8)
In: 00 begane grond
Type - PredefinedType: FLOORING; Material: q2_afwerkvloer 1 5 mm
Type - Pset_CoveringCommon - Reference: Floor:43_gietvloer 5mm
Type - Pset_ElementShading - Roughness: 304.8 mm
Type - Pset_ProductRequirements - Category: Floors
Type - Pset_QuantityTakeOff - Reference: Floor:43_gietvloer 5mm
Classification: 43.21 vloerafwerkingen; niet verhoogd, afwerklagen (Uniformat)
Pset_CoveringCommon - TotalThickness: 5 mm
Name (Floor:43_gietvloer 5mm:...) | GrossCeilingArea (m2)
3987020 | 23.6722
3988129 | 23.6568
3989864 | 7.05188
3991108 | 7.04685
3995848 | 29.3337
3997051 | 29.4073
3998646 | 107.136
4002562 | 7.83979

# IfcCovering: Floor:43_gietvloer polyurethaan_70mm (6)
In: 00 begane grond
Type - PredefinedType: FLOORING; Material: q2_afwerkvloer 3 70 mm
Type - Pset_CoveringCommon - Reference: Floor:43_gietvloer polyurethaan_70mm
Type - Pset_ElementShading - Roughness: 304.8 mm
Type - Pset_ProductRequirements - Category: Floors
Type - Pset_QuantityTakeOff - Reference: Floor:43_gietvloer polyurethaan_70mm
Classification: 43.21 vloerafwerkingen; niet verhoogd, afwerklagen (Uniformat)
Pset_CoveringCommon - TotalThickness: 70 mm
Name (Floor:43_gietvloer polyurethaan_70mm:...) | GrossCeilingArea (m2)
3905738 | 10.05
3906682 | 8.87427
3908043 | 121.453
3911452 | 8.51485
3918939 | 18.4344
3922890 | 50.2042

# IfcCovering: Floor:43_vloercoating 5mm (2)
In: 00 begane grond
Type - PredefinedType: FLOORING; Material: q2_afwerkvloer 1 5 mm
Type - Pset_CoveringCommon - Reference: Floor:43_vloercoating 5mm
Type - Pset_ElementShading - Roughness: 304.8 mm
Type - Pset_ProductRequirements - Category: Floors
Type - Pset_QuantityTakeOff - Reference: Floor:43_vloercoating 5mm
Classification: 43.21 vloerafwerkingen; niet verhoogd, afwerklagen (Uniformat)
Pset_CoveringCommon - TotalThickness: 5 mm
Name (Floor:43_vloercoating 5mm:...) | GrossCeilingArea (m2)
3992279 | 21.5049
3998245 | 1.8234

# IfcCovering: Floor:NLRS_44_FL_Multiplex 15mm (2)
In: 01 eerste verdieping
Classification: 44.10 trap- en hellingafwerkingen; trapafwerkingen, algemeen (verzamelniveau) (Uniformat)
Pset_CoveringCommon - Reference: Floor:NLRS_44_FL_Multiplex 15mm; TotalThickness: 15 mm
Pset_ElementShading - Roughness: 304.8 mm
Pset_ProductRequirements - Category: Floors
Pset_QuantityTakeOff - Reference: Floor:NLRS_44_FL_Multiplex 15mm
Name (Floor:NLRS_44_FL_Multiplex 15mm:...) | GrossCeilingArea (m2)
3252953 | 3.11912
4238366 | 6.87227

# IfcCovering: Floor:NLRS_44_FL_Multiplex 15mm (5)
In: 01 eerste verdieping
Type - PredefinedType: FLOORING; Material: NLRS_i4_hout_multiplex 15 mm
Type - Pset_CoveringCommon - Reference: Floor:NLRS_44_FL_Multiplex 15mm
Type - Pset_ElementShading - Roughness: 304.8 mm
Type - Pset_ProductRequirements - Category: Floors
Type - Pset_QuantityTakeOff - Reference: Floor:NLRS_44_FL_Multiplex 15mm
Classification: 44.10 trap- en hellingafwerkingen; trapafwerkingen, algemeen (verzamelniveau) (Uniformat)
Pset_CoveringCommon - TotalThickness: 15 mm
Name (Floor:NLRS_44_FL_Multiplex 15mm:...) | GrossCeilingArea (m2)
3274864 | 1.72984
3844577 | 3.233
8373971 | 0.136652
8374502 | 0.140919
9436673 | 0.53031

# IfcCovering: Floor:NLRS_44_FL_Multiplex 18mm (8)
In: 01 eerste verdieping
Type - PredefinedType: FLOORING; Material: NLRS_i4_hout_multiplex 18 mm
Type - Pset_CoveringCommon - Reference: Floor:NLRS_44_FL_Multiplex 18mm
Type - Pset_ElementShading - Roughness: 304.8 mm
Type - Pset_ProductRequirements - Category: Floors
Type - Pset_QuantityTakeOff - Reference: Floor:NLRS_44_FL_Multiplex 18mm
Classification: 44.10 trap- en hellingafwerkingen; trapafwerkingen, algemeen (verzamelniveau) (Uniformat)
Pset_CoveringCommon - TotalThickness: 18 mm
Name (Floor:NLRS_44_FL_Multiplex 18mm:...) | GrossCeilingArea (m2)
5817794 | 53.7134
5819258 | 39.2992
5846797 | 223.215
5847413 | 156.596
6677478 | 184.131
6802168 | 66.9458
9830065 | 6.58086
11246285 | 1.77289

# IfcCovering: Floor:NLRS_44_FL_Multiplex 9mm, Floor:NLRS_44_FL_Multiplex 9mm:6408877
In: 02 tweede verdieping
Type - PredefinedType: FLOORING; Material: NLRS_i4_hout_multiplex 9 mm
Type - Pset_CoveringCommon - Reference: Floor:NLRS_44_FL_Multiplex 9mm
Type - Pset_ElementShading - Roughness: 304.8 mm
Type - Pset_ProductRequirements - Category: Floors
Type - Pset_QuantityTakeOff - Reference: Floor:NLRS_44_FL_Multiplex 9mm
Classification: 44.10 trap- en hellingafwerkingen; trapafwerkingen, algemeen (verzamelniveau) (Uniformat)
Pset_CoveringCommon - TotalThickness: 9 mm
BaseQuantities - GrossCeilingArea: 19.3599 m2

# IfcCovering: Floor:NLRS_44_FL_verlaagd plafond (5)
In: 01 eerste verdieping
Type - PredefinedType: FLOORING; Material: NLRS_f7_gipsplaat_gen 15 mm
Type - Pset_CoveringCommon - Reference: Floor:NLRS_44_FL_verlaagd plafond
Type - Pset_ElementShading - Roughness: 304.8 mm
Type - Pset_ProductRequirements - Category: Floors
Type - Pset_QuantityTakeOff - Reference: Floor:NLRS_44_FL_verlaagd plafond
Classification: 44.10 trap- en hellingafwerkingen; trapafwerkingen, algemeen (verzamelniveau) (Uniformat)
Pset_CoveringCommon - TotalThickness: 15 mm
Name (Floor:NLRS_44_FL_verlaagd plafond:...) | GrossCeilingArea (m2)
3428090 | 27.9762
3428342 | 27.717
3429007 | 20.2078
3429101 | 4.03924
3429154 | 1.7259

# IfcCovering: Floor:NLRS_44_Plaat 10 mm RAL 7035 (4)
Type - PredefinedType: FLOORING; Material: n6_kunststof_RAL 7035 10 mm
Type - Pset_CoveringCommon - Reference: Floor:NLRS_44_Plaat 10 mm RAL 7035
Type - Pset_ElementShading - Roughness: 304.8 mm
Type - Pset_ProductRequirements - Category: Floors
Type - Pset_QuantityTakeOff - Reference: Floor:NLRS_44_Plaat 10 mm RAL 7035
Classification: 44.10 trap- en hellingafwerkingen; trapafwerkingen, algemeen (verzamelniveau) (Uniformat)
Pset_CoveringCommon - TotalThickness: 10 mm
Name (Floor:NLRS_44_Plaat 10 mm RAL 7035:...) | In | GrossCeilingArea (m2)
4435871 | 01 eerste verdieping | 16.088
6307561 | 00 begane grond | 1.28133
6335302 | 01 eerste verdieping | 3.68522
9442170 | 01 eerste verdieping | 6.54939

# IfcCovering: Floor:NLRS_44_Plaat 10 mm RAL 9002 (39)
Type - PredefinedType: FLOORING; Material: ZZ_00_Kleur_RAL 9002 10 mm
Type - Pset_CoveringCommon - Reference: Floor:NLRS_44_Plaat 10 mm RAL 9002
Type - Pset_ElementShading - Roughness: 304.8 mm
Type - Pset_ProductRequirements - Category: Floors
Type - Pset_QuantityTakeOff - Reference: Floor:NLRS_44_Plaat 10 mm RAL 9002
Classification: 44.10 trap- en hellingafwerkingen; trapafwerkingen, algemeen (verzamelniveau) (Uniformat)
Pset_CoveringCommon - TotalThickness: 10 mm
Name (Floor:NLRS_44_Plaat 10 mm RAL 9002:...) | In | GrossCeilingArea (m2)
7748674 | 01 eerste verdieping | 0.322402
7762111 | 01 eerste verdieping | 0.313472
7832819 | Podium | 1.18783
7833537 | Podium | 1.25561
7833990 | Podium | 1.22614
7834505 | Podium | 1.22936
7835059 | Podium | 1.23477
7835178 | Podium | 1.22303
7836127 | Podium | 0.689823
7836244 | Podium | 0.694027
7836808 | Podium | 1.28113
7836965 | Podium | 1.24367
7837637 | Podium | 1.24679
7837736 | Podium | 1.26065
7838338 | Podium | 1.27647
7838465 | Podium | 0.969391
7854835 | Podium | 0.201
7854917 | Podium | 0.201
7856443 | Podium | 0.1996
7856685 | Podium | 0.686682
7856739 | Podium | 0.827987
7859606 | Podium | 0.86525
9571445 | 00 begane grond | 0.2016
9571700 | 00 begane grond | 0.168911
9572123 | 00 begane grond | 0.204
9573307 | 00 begane grond | 0.216
9577171 | 00 begane grond | 0.45386
9578702 | 00 begane grond | 0.488213
9578943 | 00 begane grond | 1.90514
9579114 | 00 begane grond | 0.216
9579184 | 00 begane grond | 0.216
9833132 | 00 begane grond | 0.667479
9833256 | 00 begane grond | 0.275986
9833335 | 00 begane grond | 0.0877505
11025637 | 00 begane grond | 2.16562
11026540 | 00 begane grond | 1.98415
11027186 | 00 begane grond | 1.99118
11027776 | 00 begane grond | 1.41229
11029161 | 00 begane grond | 2.20156

# IfcCovering: Floor:NLRS_44_Plaat 10 mm RAL 9003 (26)
Type - PredefinedType: FLOORING; Material: NLRS_i4_hout_multiplex 10 mm
Type - Pset_CoveringCommon - Reference: Floor:NLRS_44_Plaat 10 mm RAL 9003
Type - Pset_ElementShading - Roughness: 304.8 mm
Type - Pset_ProductRequirements - Category: Floors
Type - Pset_QuantityTakeOff - Reference: Floor:NLRS_44_Plaat 10 mm RAL 9003
Classification: 44.10 trap- en hellingafwerkingen; trapafwerkingen, algemeen (verzamelniveau) (Uniformat)
Pset_CoveringCommon - TotalThickness: 10 mm
Name (Floor:NLRS_44_Plaat 10 mm RAL 9003:...) | In | GrossCeilingArea (m2)
4608790 | 00 begane grond | 0.213925
4620762 | 00 begane grond | 0.209463
4620908 | 00 begane grond | 0.198984
5012282 | 00 begane grond | 0.206761
5012416 | 00 begane grond | 0.206761
5012455 | 00 begane grond | 0.181545
5012559 | 00 begane grond | 0.18143
6367186 | Podium | 0.327747 | Group: Model Group:Bekleding kozijnen bestaande gebouw:5749187
6367260 | Podium | 0.332936 | Group: Model Group:Bekleding kozijnen bestaande gebouw:5749187
6400344 | 01 eerste verdieping | 3.90149
7796199 | 00 begane grond | 0.212
7797048 | 00 begane grond | 0.212
7797065 | 00 begane grond | 0.214
7797107 | 00 begane grond | 0.20564
7797135 | 00 begane grond | 0.20564
7797152 | 00 begane grond | 0.20758
9247839 | 00 begane grond | 0.217229
9248015 | 00 begane grond | 0.217887
10061748 | 00 begane grond | 0.213925
10358851 | 00 begane grond | 0.205766
10358915 | 00 begane grond | 0.205766
10358935 | 00 begane grond | 0.205766
10358955 | 00 begane grond | 0.205766
10359009 | 00 begane grond | 0.205766
10359049 | 00 begane grond | 0.205766
10359069 | 00 begane grond | 0.205766

# IfcCovering: Floor:NLRS_44_Plaat 10 mm wit (4)
In: 00 begane grond
Type - PredefinedType: FLOORING; Material: NLRS_i4_hout_multiplex wit 2 10 mm
Type - Pset_CoveringCommon - Reference: Floor:NLRS_44_Plaat 10 mm wit
Type - Pset_ElementShading - Roughness: 304.8 mm
Type - Pset_ProductRequirements - Category: Floors
Type - Pset_QuantityTakeOff - Reference: Floor:NLRS_44_Plaat 10 mm wit
Classification: 44.10 trap- en hellingafwerkingen; trapafwerkingen, algemeen (verzamelniveau) (Uniformat)
Pset_CoveringCommon - TotalThickness: 10 mm
Name (Floor:NLRS_44_Plaat 10 mm wit:...) | GrossCeilingArea (m2)
8944424 | 0.333154
8944531 | 0.505641
8944546 | 0.506199
9113817 | 0.896497

# IfcCovering: Floor:NLRS_44_Plaat 10 mm zwart (3)
Type - PredefinedType: FLOORING; Material: NLRS_i4_hout_multiplex zwart 10 mm
Type - Pset_CoveringCommon - Reference: Floor:NLRS_44_Plaat 10 mm zwart
Type - Pset_ElementShading - Roughness: 304.8 mm
Type - Pset_ProductRequirements - Category: Floors
Type - Pset_QuantityTakeOff - Reference: Floor:NLRS_44_Plaat 10 mm zwart
Classification: 44.10 trap- en hellingafwerkingen; trapafwerkingen, algemeen (verzamelniveau) (Uniformat)
Pset_CoveringCommon - TotalThickness: 10 mm
Name (Floor:NLRS_44_Plaat 10 mm zwart:...) | In | GrossCeilingArea (m2)
6616190 | Podium | 0.121249
9442464 | 01 eerste verdieping | 0.0511961
9442637 | 01 eerste verdieping | 0.553482

# IfcCovering: Floor:NLRS_44_Plaat 15 mm RAL 9002 (11)
Type - PredefinedType: FLOORING; Material: AL_Multiplex RAL 9002 15 mm
Type - Pset_CoveringCommon - Reference: Floor:NLRS_44_Plaat 15 mm RAL 9002
Type - Pset_ElementShading - Roughness: 304.8 mm
Type - Pset_ProductRequirements - Category: Floors
Type - Pset_QuantityTakeOff - Reference: Floor:NLRS_44_Plaat 15 mm RAL 9002
Classification: 44.10 trap- en hellingafwerkingen; trapafwerkingen, algemeen (verzamelniveau) (Uniformat)
Pset_CoveringCommon - TotalThickness: 15 mm
Name (Floor:NLRS_44_Plaat 15 mm RAL 9002:...) | In | GrossCeilingArea (m2)
7855292 | Podium | 0.4617
7859667 | Podium | 0.861976
7885062 | Podium | 2.34
8116690 | 01 eerste verdieping | 0.09108
11028181 | 00 begane grond | 1.98404
11028741 | 00 begane grond | 1.99532
11306457 | Podium | 0.32571 | Group: Model Group:Bekleding kozijnen bestaande gebouw:5749187
11352607 | Podium | 0.24605
11364375 | Podium | 0.334488
11366327 | Podium | 0.4503
11753618 | Podium | 0.759249

# IfcCovering: Floor:NLRS_44_Plaat 18 mm RAL 9002 (63)
Type - PredefinedType: FLOORING; Material: AL_Multiplex RAL 9002 18 mm
Type - Pset_CoveringCommon - Reference: Floor:NLRS_44_Plaat 18 mm RAL 9002
Type - Pset_ElementShading - Roughness: 304.8 mm
Type - Pset_ProductRequirements - Category: Floors
Type - Pset_QuantityTakeOff - Reference: Floor:NLRS_44_Plaat 18 mm RAL 9002
Classification: 44.10 trap- en hellingafwerkingen; trapafwerkingen, algemeen (verzamelniveau) (Uniformat)
Pset_CoveringCommon - TotalThickness: 18 mm
Name (Floor:NLRS_44_Plaat 18 mm RAL 9002:...) | In | GrossCeilingArea (m2)
7884988 | 00 begane grond | 2.36201
7930463 | Podium | 0.082256
7930470 | 00 begane grond | 0.075272
7930487 | Podium | 0.082256
7930494 | 00 begane grond | 0.075272
8116522 | 01 eerste verdieping | 0.09108
8116704 | 02 tweede verdieping | 0.09108
8116720 | 01 eerste verdieping | 0.09108
8116736 | 02 tweede verdieping | 0.09108
8116771 | 01 eerste verdieping | 0.102258
8116785 | 01 eerste verdieping | 0.097704
8116799 | 01 eerste verdieping | 0.097704
8116813 | 01 eerste verdieping | 0.097704
8116829 | 02 tweede verdieping | 0.097704
9114374 | 00 begane grond | 0.122958
9114688 | Podium | 0.11484
9114717 | 00 begane grond | 0.122958
9114725 | Podium | 0.11484
9114742 | 00 begane grond | 0.122958
9114750 | Podium | 0.11484
9114767 | 00 begane grond | 0.122958
9114775 | Podium | 0.11484
9114792 | 00 begane grond | 0.122958
9114800 | Podium | 0.11484
9114817 | 00 begane grond | 0.122958
9114825 | Podium | 0.11484
9114842 | 00 begane grond | 0.122958
9114850 | Podium | 0.11339
9115375 | 00 begane grond | 0.1242
9115383 | Podium | 0.12006
9312990 | Podium | 0.080316
9312997 | 00 begane grond | 0.080316
9313256 | Podium | 0.080316
9313263 | 00 begane grond | 0.080316
9313310 | Podium | 0.080316
9313317 | 00 begane grond | 0.080316
9313340 | Podium | 0.080316
9313347 | 00 begane grond | 0.080316
9453582 | 00 begane grond | 0.080316
9453623 | Podium | 0.080316
9490887 | 00 begane grond | 1.68593
9491247 | 01 eerste verdieping | 1.68593
10236017 | Podium | 0.510044
10239952 | Podium | 0.142
10269610 | 00 begane grond | 0.080316
10269923 | Podium | 0.073332
10269977 | 00 begane grond | 0.080316
10269984 | Podium | 0.073332
10270004 | 00 begane grond | 0.080316
10270011 | Podium | 0.073332
10270031 | 00 begane grond | 0.080316
10270038 | Podium | 0.073332
11306474 | Podium | 0.369038 | Group: Model Group:Bekleding kozijnen bestaande gebouw:5749187
11757832 | Podium | 0.0525
11757950 | 00 begane grond | 0.0525
11758069 | Podium | 0.0525
11758077 | 00 begane grond | 0.0525
12000224 | 00 begane grond | 0.075272
12000360 | Podium | 0.073332
12000451 | 00 begane grond | 0.075272
12000458 | Podium | 0.073332
12000481 | 00 begane grond | 0.075272
12000488 | Podium | 0.073332

# IfcCovering: Floor:NLRS_90_FL_bestrating n.t.b._gen_aly (2)
In: 01 eerste verdieping
Type - PredefinedType: FLOORING; Material: NLRS_f2_beton 300x300x60mm 60 mm
Type - Pset_CoveringCommon - Reference: Floor:NLRS_90_FL_bestrating n.t.b._gen_aly
Type - Pset_ElementShading - Roughness: 304.8 mm
Type - Pset_ManufacturerTypeInformation - Manufacturer: n.t.b.
Type - Pset_ProductRequirements - Category: Floors
Type - Pset_QuantityTakeOff - Reference: Floor:NLRS_90_FL_bestrating n.t.b._gen_aly
Classification: 90.41 terrein; terreinafwerkingen, verhardingen (Uniformat)
Pset_CoveringCommon - TotalThickness: 60 mm
Name (Floor:NLRS_90_FL_bestrating n.t.b._gen_aly:...) | GrossCeilingArea (m2)
4297587 | 36.3191
11614567 | 35.4837

# IfcCovering: Noodoverstort1:Noodoverstort, Noodoverstort1:Noodoverstort:9084768
In: 01 eerste verdieping
Type - Pset_CoveringCommon - Reference: Noodoverstort1:Noodoverstort
Type - Pset_ProductRequirements - Category: Generic Models
Type - Pset_QuantityTakeOff - Reference: Noodoverstort1:Noodoverstort
Pset_OpeningElementCommon - Reference: Noodoverstort1:Noodoverstort; sets with these values: 2
BaseQuantities - GrossCeilingArea: 0.002496 m2

# IfcCovering: Noodoverstort:Noodoverstort, Noodoverstort:Noodoverstort:9070054
In: 01 eerste verdieping
Type - Pset_CoveringCommon - Reference: Noodoverstort:Noodoverstort
Type - Pset_ProductRequirements - Category: Generic Models
Type - Pset_QuantityTakeOff - Reference: Noodoverstort:Noodoverstort
Pset_OpeningElementCommon - Reference: Noodoverstort:Noodoverstort; sets with these values: 2
BaseQuantities - GrossCeilingArea: 0.003456 m2

# IfcCurtainWall: Curtain Wall:NLRS_31_WIN_UN_houten kozijn vrij indeelbaar_gen_aly (154)
Type - Pset_CurtainWallCommon - IsExternal: no; Reference: Curtain Wall:NLRS_31_WIN_UN_houten kozijn vrij indeelbaar_gen_aly
Type - Pset_ProductRequirements - Category: Walls
Type - Pset_QuantityTakeOff - Reference: Curtain Wall:NLRS_31_WIN_UN_houten kozijn vrij indeelbaar_gen_aly
Classification: 31.0 (Uniformat)
Name (Curtain Wall:NLRS_31_WIN_UN_houten kozijn vrij indeelbaar_gen_aly:...) | In | IsExternal
2856746 | 00 begane grond | yes
2857171 | 00 begane grond | yes
2858313 | 00 begane grond | yes
2866799 | 00 begane grond | yes
2891817 | 01 eerste verdieping | yes
2980526 | 00 begane grond | yes
2980927 | 00 begane grond | yes
3004378 | 00 begane grond | yes
3006408 | 00 begane grond | yes
3019233 | 00 begane grond | yes
3019450 | 00 begane grond | yes
3019648 | 00 begane grond | yes
3019873 | 00 begane grond | yes
3020063 | 00 begane grond | yes
3020230 | 00 begane grond | yes
3020396 | 00 begane grond | yes
3020539 | 00 begane grond | yes
3020684 | 00 begane grond | yes
3020862 | 00 begane grond | yes
3025916 | 00 begane grond | yes
3036824 | 00 begane grond | yes
3079279 | 00 begane grond | yes
3103290 | 00 begane grond | yes
3105530 | 00 begane grond | yes
3105696 | 00 begane grond | yes
3105743 | 00 begane grond | yes
3131747 | 00 begane grond | yes
3136057 | 00 begane grond | yes
3136069 | 00 begane grond | yes
3216644 | 00 begane grond | Pset_OpeningElementCommon - Reference: Curtain Wall:NLRS_31_WIN_UN_houten kozijn vrij indeelbaar_gen_aly; sets with these values: 2
3216982 | 00 begane grond | yes
3217027 | 00 begane grond | Pset_OpeningElementCommon - Reference: Curtain Wall:NLRS_31_WIN_UN_houten kozijn vrij indeelbaar_gen_aly; sets with these values: 2
3260280 | 00 begane grond | Pset_OpeningElementCommon - Reference: Curtain Wall:NLRS_31_WIN_UN_houten kozijn vrij indeelbaar_gen_aly; sets with these values: 2
3260365 | 00 begane grond | yes
3261838 | 00 begane grond | yes
3424598 | 00 begane grond | Pset_OpeningElementCommon - Reference: Curtain Wall:NLRS_31_WIN_UN_houten kozijn vrij indeelbaar_gen_aly; sets with these values: 2
3650433 | 00 begane grond | Pset_OpeningElementCommon - Reference: Curtain Wall:NLRS_31_WIN_UN_houten kozijn vrij indeelbaar_gen_aly; sets with these values: 2
3668606 | 00 begane grond | yes
3668914 | 00 begane grond | yes
3720113 | 00 begane grond | yes
3720844 | 00 begane grond | yes
3720863 | 00 begane grond | yes
3721530 | 00 begane grond | yes
3721847 | 00 begane grond | yes
3722660 | 00 begane grond | Pset_OpeningElementCommon - Reference: Curtain Wall:NLRS_31_WIN_UN_houten kozijn vrij indeelbaar_gen_aly; sets with these values: 2
3722994 | 00 begane grond | Pset_OpeningElementCommon - Reference: Curtain Wall:NLRS_31_WIN_UN_houten kozijn vrij indeelbaar_gen_aly; sets with these values: 2
4093376 | 00 begane grond | yes
4200605 | 00 begane grond | yes
4201023 | 00 begane grond | yes
4221986 | 00 begane grond | yes
4257201 | 00 begane grond | yes
4259318 | 00 begane grond | yes
4259324 | 00 begane grond | Pset_OpeningElementCommon - Reference: Curtain Wall:NLRS_31_WIN_UN_houten kozijn vrij indeelbaar_gen_aly; sets with these values: 2
4259451 | 00 begane grond | yes
4285052 | 00 begane grond | yes
4438363 | 00 begane grond | yes
5009692 | Podium | yes
5202859 | 00 begane grond | yes
5203702 | 00 begane grond | yes
5206282 | 00 begane grond | yes
5254164 | 00 begane grond | yes
5459099 | 00 begane grond | yes
5565097 | 00 begane grond | yes
5565103 | 00 begane grond | yes
5565109 | 00 begane grond | yes
5565115 | 00 begane grond | yes
5567078 | 00 begane grond | yes
5567084 | 00 begane grond | yes
5567090 | 00 begane grond | yes
5567096 | 00 begane grond | yes
5567102 | 00 begane grond | yes
5567297 | 00 begane grond | yes
5567303 | 00 begane grond | yes
5567309 | 00 begane grond | yes
5567315 | 00 begane grond | yes
5567321 | 00 begane grond | yes
5567900 | 00 begane grond | yes
5567906 | 00 begane grond | yes
5567912 | 00 begane grond | yes
5567918 | 00 begane grond | yes
5567924 | 00 begane grond | yes
5580906 | 00 begane grond | yes
5587930 | 00 begane grond | yes
5598049 | 00 begane grond | yes
5634988 | 00 begane grond | yes
5637602 | 00 begane grond | yes
5638064 | 00 begane grond | yes
5649325 | 00 begane grond | yes
5649483 | 00 begane grond | yes
5762127 | 00 begane grond | yes
5762139 | 00 begane grond | yes
5837562 | 00 begane grond | yes
5837724 | 00 begane grond | yes
5882744 | 00 begane grond | yes
5903065 | 00 begane grond | yes
5973729 | 00 begane grond | yes
6267160 | 00 begane grond | yes
6660026 | 00 begane grond | Pset_OpeningElementCommon - Reference: Curtain Wall:NLRS_31_WIN_UN_houten kozijn vrij indeelbaar_gen_aly; sets with these values: 2
6971452 | 01 eerste verdieping | yes
6971458 | 01 eerste verdieping | yes
6971464 | 01 eerste verdieping | yes
6971470 | 01 eerste verdieping | yes
6971490 | 01 eerste verdieping | yes
6988575 | 00 begane grond | Pset_OpeningElementCommon - Reference: Curtain Wall:NLRS_31_WIN_UN_houten kozijn vrij indeelbaar_gen_aly; sets with these values: 2
7514267 | 00 begane grond | yes
7626448 | 00 begane grond | yes
7630317 | 00 begane grond | yes
7632402 | 00 begane grond | yes
7634411 | 00 begane grond | yes
7635237 | 00 begane grond | yes
7718453 | 00 begane grond | yes
7718458 | 00 begane grond | yes
7759056 | 00 begane grond | yes
8179644 | 00 begane grond | Pset_OpeningElementCommon - Reference: Curtain Wall:NLRS_31_WIN_UN_houten kozijn vrij indeelbaar_gen_aly; sets with these values: 2
8264865 | 00 begane grond | Pset_OpeningElementCommon - Reference: Curtain Wall:NLRS_31_WIN_UN_houten kozijn vrij indeelbaar_gen_aly; sets with these values: 2
8264871 | 00 begane grond | Pset_OpeningElementCommon - Reference: Curtain Wall:NLRS_31_WIN_UN_houten kozijn vrij indeelbaar_gen_aly; sets with these values: 2
8264877 | 00 begane grond | Pset_OpeningElementCommon - Reference: Curtain Wall:NLRS_31_WIN_UN_houten kozijn vrij indeelbaar_gen_aly; sets with these values: 2
8264883 | 00 begane grond | Pset_OpeningElementCommon - Reference: Curtain Wall:NLRS_31_WIN_UN_houten kozijn vrij indeelbaar_gen_aly; sets with these values: 2
8264889 | 00 begane grond | Pset_OpeningElementCommon - Reference: Curtain Wall:NLRS_31_WIN_UN_houten kozijn vrij indeelbaar_gen_aly; sets with these values: 2
8264895 | 00 begane grond | Pset_OpeningElementCommon - Reference: Curtain Wall:NLRS_31_WIN_UN_houten kozijn vrij indeelbaar_gen_aly; sets with these values: 2
8264901 | 00 begane grond | Pset_OpeningElementCommon - Reference: Curtain Wall:NLRS_31_WIN_UN_houten kozijn vrij indeelbaar_gen_aly; sets with these values: 2
8265070 | 00 begane grond | Pset_OpeningElementCommon - Reference: Curtain Wall:NLRS_31_WIN_UN_houten kozijn vrij indeelbaar_gen_aly; sets with these values: 2
8645763 | 00 begane grond | Pset_OpeningElementCommon - Reference: Curtain Wall:NLRS_31_WIN_UN_houten kozijn vrij indeelbaar_gen_aly; sets with these values: 2
8646239 | 00 begane grond | Pset_OpeningElementCommon - Reference: Curtain Wall:NLRS_31_WIN_UN_houten kozijn vrij indeelbaar_gen_aly; sets with these values: 2
9046940 | 01 eerste verdieping | yes
9046985 | 01 eerste verdieping | yes
9244746 | 00 begane grond | yes
9282400 | 00 begane grond | Pset_OpeningElementCommon - Reference: Curtain Wall:NLRS_31_WIN_UN_houten kozijn vrij indeelbaar_gen_aly; sets with these values: 2
9452506 | 00 begane grond | yes
9485727 | 00 begane grond | yes
9487585 | 00 begane grond | yes
9488149 | 00 begane grond | yes
9558935 | 00 begane grond | yes
10222387 | 00 begane grond | yes
10229151 | 00 begane grond | yes
10238744 | 00 begane grond | yes
10266481 | 00 begane grond | yes
10266779 | 00 begane grond | yes
10267011 | 00 begane grond | yes
10267232 | 00 begane grond | yes
11363911 | 00 begane grond | Pset_OpeningElementCommon - Reference: Curtain Wall:NLRS_31_WIN_UN_houten kozijn vrij indeelbaar_gen_aly; sets with these values: 2
11757021 | 00 begane grond | Pset_OpeningElementCommon - Reference: Curtain Wall:NLRS_31_WIN_UN_houten kozijn vrij indeelbaar_gen_aly; sets with these values: 2
11757348 | 00 begane grond | Pset_OpeningElementCommon - Reference: Curtain Wall:NLRS_31_WIN_UN_houten kozijn vrij indeelbaar_gen_aly; sets with these values: 2
11777785 | 00 begane grond | Pset_OpeningElementCommon - Reference: Curtain Wall:NLRS_31_WIN_UN_houten kozijn vrij indeelbaar_gen_aly; sets with these values: 2
11778002 | 00 begane grond | Pset_OpeningElementCommon - Reference: Curtain Wall:NLRS_31_WIN_UN_houten kozijn vrij indeelbaar_gen_aly; sets with these values: 2
11778042 | 00 begane grond | Pset_OpeningElementCommon - Reference: Curtain Wall:NLRS_31_WIN_UN_houten kozijn vrij indeelbaar_gen_aly; sets with these values: 2
11895753 | 00 begane grond | yes
12122988 | 00 begane grond | yes
12231324 | 00 begane grond | Pset_OpeningElementCommon - Reference: Curtain Wall:NLRS_31_WIN_UN_houten kozijn vrij indeelbaar_gen_aly; sets with these values: 2
12231375 | 00 begane grond | Pset_OpeningElementCommon - Reference: Curtain Wall:NLRS_31_WIN_UN_houten kozijn vrij indeelbaar_gen_aly; sets with these values: 2
12231421 | 00 begane grond | Pset_OpeningElementCommon - Reference: Curtain Wall:NLRS_31_WIN_UN_houten kozijn vrij indeelbaar_gen_aly; sets with these values: 2
12231425 | 00 begane grond | Pset_OpeningElementCommon - Reference: Curtain Wall:NLRS_31_WIN_UN_houten kozijn vrij indeelbaar_gen_aly; sets with these values: 2
12734606 | 00 begane grond | yes
12738026 | 00 begane grond | yes

# IfcDistributionPort (3)
Description: Flow; FlowDirection: SOURCEANDSINK
Name
Port_10273312
2 x Port_10275129

# IfcDoor: 31_Overheaddeur_2laags_volglas_3500 br x3500 hg_VL_MB:MB_Overheaddeur_Basis, 31_Overheaddeur_2laags_volglas_3500 br x3500 hg_VL_MB:MB_Overheaddeur_Basis:10124073
In: 00 begane grond
Type - ParameterTakesPrecedence: no; Sizeable: no; Material: 31_Glas, AL_31_KozijnHout hardhout Antraciet (2)
Type - Pset_ConcreteElementGeneral - FireRating: Geen brandwerendheid
Type - Pset_DoorCommon - IsExternal: no; Reference: 31_Overheaddeur_2laags_volglas_3500 br x3500 hg_VL_MB:MB_Overheaddeur_Basis; FireRating: Geen brandwerendheid
Type - Pset_ManufacturerTypeInformation - Manufacturer: Overheaddeur fabr:
Type - Pset_ProductRequirements - Category: Doors
Type - Pset_QuantityTakeOff - Reference: 31_Overheaddeur_2laags_volglas_3500 br x3500 hg_VL_MB:MB_Overheaddeur_Basis
OverallHeight: 2400 mm; OverallWidth: 2625 mm; Material: AL_31_KozijnHout hardhout Antraciet, MB_Hulpstaal_deuren, MB_RubberAfdichtingen
BaseQuantities - Height: 2625 mm; Width: 2400 mm; Area: 10.9446 m2

# IfcDoor: AL_32.i_Binnenkozijn-enkeledeur_Linksdraaiend in de wand:Merk a.sp, AL_32.i_Binnenkozijn-enkeledeur_Linksdraaiend in de wand:Merk a.sp:2999823
In: 00 begane grond
Type - OperationType: SINGLE_SWING_LEFT; ParameterTakesPrecedence: no; Sizeable: no; Classification: 32.31.21 (Uniformat); Material: AL_31_KozijnHout hardhout RAL 9005 (2), 31_Glas
Type - AL_32.i_Binnenkozijn-enkeledeur_Linksdraaiend in de wand:Merk a.sp:2999823 - PanelOperation: SWINGING
Type - Pset_DoorCommon - IsExternal: no; Reference: AL_32.i_Binnenkozijn-enkeledeur_Linksdraaiend in de wand:Merk a.sp
Type - Pset_ProductRequirements - Category: Doors
Type - Pset_QuantityTakeOff - Reference: AL_32.i_Binnenkozijn-enkeledeur_Linksdraaiend in de wand:Merk a.sp
OverallHeight: 2462 mm; OverallWidth: 1034 mm; Material: AL_31_KozijnHout hardhout RAL 9005
BaseQuantities - Height: 2392 mm; Width: 1034 mm; Area: 3.49322 m2

# IfcDoor: AL_32.i_Binnenkozijn-enkeledeur_Linksdraaiend in de wand:Merk a.sp, AL_32.i_Binnenkozijn-enkeledeur_Linksdraaiend in de wand:Merk a.sp:9671885
In: 00 begane grond
Type - OperationType: SINGLE_SWING_LEFT; ParameterTakesPrecedence: no; Sizeable: no; Classification: 32.31.21 (Uniformat); Material: AL_31_KozijnHout hardhout RAL 9005 (2), 31_Glas
Type - AL_32.i_Binnenkozijn-enkeledeur_Linksdraaiend in de wand:Merk a.sp:9671885 - PanelOperation: SWINGING
Type - Pset_DoorCommon - IsExternal: no; Reference: AL_32.i_Binnenkozijn-enkeledeur_Linksdraaiend in de wand:Merk a.sp
Type - Pset_ProductRequirements - Category: Doors
Type - Pset_QuantityTakeOff - Reference: AL_32.i_Binnenkozijn-enkeledeur_Linksdraaiend in de wand:Merk a.sp
OverallHeight: 2462 mm; OverallWidth: 1034 mm; Material: AL_31_KozijnHout hardhout RAL 9005
Pset_DoorCommon - IsExternal: yes
BaseQuantities - Height: 2392 mm; Width: 1034 mm; Area: 3.49322 m2

# IfcDoor: AL_32.i_Binnenkozijn-enkeledeur_Linksdraaiend met raampje:Merk a.sp, AL_32.i_Binnenkozijn-enkeledeur_Linksdraaiend met raampje:Merk a.sp:3080090
In: 00 begane grond
Type - OperationType: SINGLE_SWING_LEFT; ParameterTakesPrecedence: no; Sizeable: no; Classification: 32.31.21 (Uniformat); Material: 31_Glas, <Unnamed> (2), NLRS_i3_hout_Loofhout (hardhout) RAL 9002
Type - AL_32.i_Binnenkozijn-enkeledeur_Linksdraaiend met raampje:Merk a.sp:3080090 - PanelOperation: SWINGING
Type - Pset_DoorCommon - IsExternal: no; Reference: AL_32.i_Binnenkozijn-enkeledeur_Linksdraaiend met raampje:Merk a.sp
Type - Pset_ProductRequirements - Category: Doors
Type - Pset_QuantityTakeOff - Reference: AL_32.i_Binnenkozijn-enkeledeur_Linksdraaiend met raampje:Merk a.sp
OverallHeight: 2462 mm; OverallWidth: 1034 mm; Material: NLRS_i3_hout_Loofhout (hardhout) RAL 9002
BaseQuantities - Height: 2392 mm; Width: 1034 mm; Area: 3.5215 m2

# IfcDoor: AL_32.i_Binnenkozijn-enkeledeur_Linksdraaiend:Merk a.sp (23)
Type - OperationType: SINGLE_SWING_LEFT; ParameterTakesPrecedence: no; Sizeable: no; Classification: 32.31.21 (Uniformat); Material: 31_Glas, <Unnamed> (2), NLRS_i3_hout_Loofhout (hardhout) RAL 9002
Type - AL_32.i_Binnenkozijn-enkeledeur_Linksdraaiend:Merk a.sp:2992293 - PanelOperation: SWINGING
Type - Pset_DoorCommon - IsExternal: no; Reference: AL_32.i_Binnenkozijn-enkeledeur_Linksdraaiend:Merk a.sp
Type - Pset_ProductRequirements - Category: Doors
Type - Pset_QuantityTakeOff - Reference: AL_32.i_Binnenkozijn-enkeledeur_Linksdraaiend:Merk a.sp
OverallHeight: 2462 mm; OverallWidth: 1034 mm; Material: NLRS_i3_hout_Loofhout (hardhout) RAL 9002
BaseQuantities - Height: 2392 mm; Width: 1034 mm; Area: 3.49322 m2
Name (AL_32.i_Binnenkozijn-enkeledeur_Linksdraaiend:Merk a.sp:...) | In
2992293 | 00 begane grond
2992812 | 00 begane grond
3081175 | 00 begane grond
4226510 | 00 begane grond
4315871 | 00 begane grond
4315874 | 00 begane grond
5635728 | 00 begane grond
5636404 | 00 begane grond
5642232 | 00 begane grond
5644603 | 00 begane grond
5644685 | 00 begane grond
5743232 | 01 eerste verdieping
5855144 | 00 begane grond
5904195 | 00 begane grond
6068655 | 00 begane grond
8052795 | 01 eerste verdieping
8052840 | 01 eerste verdieping
8052867 | 01 eerste verdieping | Pset_OpeningElementCommon - Reference: AL_32.i_Binnenkozijn-enkeledeur_Linksdraaiend:Merk a.sp; sets with these values: 2
10064377 | 00 begane grond | Pset_OpeningElementCommon - Reference: AL_32.i_Binnenkozijn-enkeledeur_Linksdraaiend:Merk a.sp; sets with these values: 2
10064475 | 00 begane grond
10064669 | 00 begane grond
10065633 | 00 begane grond
12236962 | 00 begane grond

# IfcDoor: AL_32.i_Binnenkozijn-enkeledeur_Linksdraaiend:Merk a.sp, AL_32.i_Binnenkozijn-enkeledeur_Linksdraaiend:Merk a.sp:5633986
In: 00 begane grond
Type - OperationType: SINGLE_SWING_LEFT; ParameterTakesPrecedence: no; Sizeable: no; Classification: 32.31.21 (Uniformat); Material: <Unnamed> (2), 31_Glas, NLRS_i3_hout_Loofhout (hardhout) RAL 9002
Type - AL_32.i_Binnenkozijn-enkeledeur_Linksdraaiend:Merk a.sp:5633986 - PanelOperation: SWINGING
Type - Pset_DoorCommon - IsExternal: no; Reference: AL_32.i_Binnenkozijn-enkeledeur_Linksdraaiend:Merk a.sp
Type - Pset_ProductRequirements - Category: Doors
Type - Pset_QuantityTakeOff - Reference: AL_32.i_Binnenkozijn-enkeledeur_Linksdraaiend:Merk a.sp
OverallHeight: 2462 mm; OverallWidth: 1034 mm; Material: NLRS_i3_hout_Loofhout (hardhout) RAL 9002
BaseQuantities - Height: 2392 mm; Width: 1034 mm; Area: 3.49322 m2

# IfcDoor: AL_32.i_Binnenkozijn-enkeledeur_Linksdraaiend:Merk a.sp, AL_32.i_Binnenkozijn-enkeledeur_Linksdraaiend:Merk a.sp:5922921
In: 00 begane grond
Type - OperationType: SINGLE_SWING_LEFT; ParameterTakesPrecedence: no; Sizeable: no; Classification: 32.31.21 (Uniformat); Material: <Unnamed> (2), 31_Glas, NLRS_i3_hout_Loofhout (hardhout) RAL 9002
Type - AL_32.i_Binnenkozijn-enkeledeur_Linksdraaiend:Merk a.sp:5922921 - PanelOperation: SWINGING
Type - Pset_DoorCommon - IsExternal: no; Reference: AL_32.i_Binnenkozijn-enkeledeur_Linksdraaiend:Merk a.sp
Type - Pset_ProductRequirements - Category: Doors
Type - Pset_QuantityTakeOff - Reference: AL_32.i_Binnenkozijn-enkeledeur_Linksdraaiend:Merk a.sp
OverallHeight: 2462 mm; OverallWidth: 1034 mm; Material: NLRS_i3_hout_Loofhout (hardhout) RAL 9002
BaseQuantities - Height: 2392 mm; Width: 1034 mm; Area: 3.49322 m2

# IfcDoor: AL_32.i_Binnenkozijn-enkeledeur_Linksdraaiend:Merk a.sp (2000mm hoog) (4)
In: 01 eerste verdieping
Type - OperationType: SINGLE_SWING_LEFT; ParameterTakesPrecedence: no; Sizeable: no; Classification: 32.31.21 (Uniformat); Material: <Unnamed> (2), 31_Glas, NLRS_i3_hout_Loofhout (hardhout) RAL 9002
Type - AL_32.i_Binnenkozijn-enkeledeur_Linksdraaiend:Merk a.sp (2000mm hoog):11066509 - PanelOperation: SWINGING
Type - Pset_DoorCommon - IsExternal: no; Reference: AL_32.i_Binnenkozijn-enkeledeur_Linksdraaiend:Merk a.sp (2000mm hoog)
Type - Pset_ProductRequirements - Category: Doors
Type - Pset_QuantityTakeOff - Reference: AL_32.i_Binnenkozijn-enkeledeur_Linksdraaiend:Merk a.sp (2000mm hoog)
OverallHeight: 2142 mm; OverallWidth: 1034 mm; Material: NLRS_i3_hout_Loofhout (hardhout) RAL 9002
BaseQuantities - Height: 2092 mm; Width: 1034 mm; Area: 3.08822 m2
Name (AL_32.i_Binnenkozijn-enkeledeur_Linksdraaiend:Merk a.sp (2000mm hoog):...)
11066509 | Pset_OpeningElementCommon - Reference: AL_32.i_Binnenkozijn-enkeledeur_Linksdraaiend:Merk a.sp (2000mm hoog); sets with these values: 2
11066515
11066517
11066521

# IfcDoor: AL_32.i_Binnenkozijn-enkeledeur_Linksdraaiend:Merk a.sp (2000mm hoog) (2)
In: 00 begane grond
Type - OperationType: SINGLE_SWING_LEFT; ParameterTakesPrecedence: no; Sizeable: no; Classification: 32.31.21 (Uniformat); Material: <Unnamed> (2), 31_Glas, NLRS_i3_hout_Loofhout (hardhout) RAL 9002
Type - AL_32.i_Binnenkozijn-enkeledeur_Linksdraaiend:Merk a.sp (2000mm hoog):2858009 - PanelOperation: SWINGING
Type - Pset_DoorCommon - IsExternal: no; Reference: AL_32.i_Binnenkozijn-enkeledeur_Linksdraaiend:Merk a.sp (2000mm hoog)
Type - Pset_ProductRequirements - Category: Doors
Type - Pset_QuantityTakeOff - Reference: AL_32.i_Binnenkozijn-enkeledeur_Linksdraaiend:Merk a.sp (2000mm hoog)
OverallHeight: 2142 mm; OverallWidth: 1034 mm; Material: NLRS_i3_hout_Loofhout (hardhout) RAL 9002
Pset_OpeningElementCommon - Reference: AL_32.i_Binnenkozijn-enkeledeur_Linksdraaiend:Merk a.sp (2000mm hoog); sets with these values: 2
BaseQuantities - Height: 2092 mm; Width: 1034 mm; Area: 3.08822 m2
Name (AL_32.i_Binnenkozijn-enkeledeur_Linksdraaiend:Merk a.sp (2000mm hoog):...)
2858009
7472237

# IfcDoor: AL_32.i_Binnenkozijn-enkeledeur_Linksdraaiend:Merk a.sp (2100mm hoog) (2)
In: 00 begane grond
Type - OperationType: SINGLE_SWING_LEFT; ParameterTakesPrecedence: no; Sizeable: no; Classification: 32.31.21 (Uniformat); Material: <Unnamed> (2), 31_Glas, NLRS_i3_hout_Loofhout (hardhout) RAL 9002
Type - AL_32.i_Binnenkozijn-enkeledeur_Linksdraaiend:Merk a.sp (2100mm hoog):3366255 - PanelOperation: SWINGING
Type - Pset_DoorCommon - IsExternal: no; Reference: AL_32.i_Binnenkozijn-enkeledeur_Linksdraaiend:Merk a.sp (2100mm hoog)
Type - Pset_ProductRequirements - Category: Doors
Type - Pset_QuantityTakeOff - Reference: AL_32.i_Binnenkozijn-enkeledeur_Linksdraaiend:Merk a.sp (2100mm hoog)
OverallHeight: 2242 mm; OverallWidth: 1034 mm; Material: NLRS_i3_hout_Loofhout (hardhout) RAL 9002
Pset_DoorCommon - IsExternal: yes
BaseQuantities - Height: 2192 mm; Width: 1034 mm; Area: 3.22322 m2
Name (AL_32.i_Binnenkozijn-enkeledeur_Linksdraaiend:Merk a.sp (2100mm hoog):...)
3366255
3366338

# IfcDoor: AL_32.i_Binnenkozijn-enkeledeur_Linksdraaiend:Merk a.sp (2100mm hoog), AL_32.i_Binnenkozijn-enkeledeur_Linksdraaiend:Merk a.sp (2100mm hoog):6942819
In: 00 begane grond
Type - OperationType: SINGLE_SWING_LEFT; ParameterTakesPrecedence: no; Sizeable: no; Classification: 32.31.21 (Uniformat); Material: <Unnamed> (2), 31_Glas, NLRS_i3_hout_Loofhout (hardhout) RAL 9002
Type - AL_32.i_Binnenkozijn-enkeledeur_Linksdraaiend:Merk a.sp (2100mm hoog):6942819 - PanelOperation: SWINGING
Type - Pset_DoorCommon - IsExternal: no; Reference: AL_32.i_Binnenkozijn-enkeledeur_Linksdraaiend:Merk a.sp (2100mm hoog)
Type - Pset_ProductRequirements - Category: Doors
Type - Pset_QuantityTakeOff - Reference: AL_32.i_Binnenkozijn-enkeledeur_Linksdraaiend:Merk a.sp (2100mm hoog)
OverallHeight: 2242 mm; OverallWidth: 1034 mm; Material: NLRS_i3_hout_Loofhout (hardhout) RAL 9002
Pset_DoorCommon - IsExternal: yes
BaseQuantities - Height: 2192 mm; Width: 1034 mm; Area: 3.22322 m2

# IfcDoor: AL_32.i_Binnenkozijn-enkeledeur_Linksdraaiend:Merk a.sp brandwerend, AL_32.i_Binnenkozijn-enkeledeur_Linksdraaiend:Merk a.sp brandwerend:3068143
In: 01 eerste verdieping
Type - OperationType: SINGLE_SWING_LEFT; ParameterTakesPrecedence: no; Sizeable: no; Classification: 32.31.21 (Uniformat); Material: <Unnamed> (2), 31_Glas, NLRS_i3_hout_Loofhout (hardhout) RAL 9002
Type - AL_32.i_Binnenkozijn-enkeledeur_Linksdraaiend:Merk a.sp brandwerend:3068143 - PanelOperation: SWINGING
Type - Pset_DoorCommon - IsExternal: no; Reference: AL_32.i_Binnenkozijn-enkeledeur_Linksdraaiend:Merk a.sp brandwerend
Type - Pset_ProductRequirements - Category: Doors
Type - Pset_QuantityTakeOff - Reference: AL_32.i_Binnenkozijn-enkeledeur_Linksdraaiend:Merk a.sp brandwerend
OverallHeight: 2462 mm; OverallWidth: 1018 mm; Material: NLRS_i3_hout_Loofhout (hardhout) RAL 9002
BaseQuantities - Height: 2392 mm; Width: 1018 mm; Area: 3.4504 m2

# IfcDoor: AL_32.i_Binnenkozijn-enkeledeur_Linksdraaiend:Merk a.sp zwart, AL_32.i_Binnenkozijn-enkeledeur_Linksdraaiend:Merk a.sp zwart:5705137
In: 00 begane grond
Type - OperationType: SINGLE_SWING_LEFT; ParameterTakesPrecedence: no; Sizeable: no; Classification: 32.31.21 (Uniformat); Material: AL_31_KozijnHout hardhout RAL 9005 (2), 31_Glas
Type - AL_32.i_Binnenkozijn-enkeledeur_Linksdraaiend:Merk a.sp zwart:5705137 - PanelOperation: SWINGING
Type - Pset_DoorCommon - IsExternal: no; Reference: AL_32.i_Binnenkozijn-enkeledeur_Linksdraaiend:Merk a.sp zwart
Type - Pset_ProductRequirements - Category: Doors
Type - Pset_QuantityTakeOff - Reference: AL_32.i_Binnenkozijn-enkeledeur_Linksdraaiend:Merk a.sp zwart
OverallHeight: 2462 mm; OverallWidth: 1034 mm; Material: AL_31_KozijnHout hardhout RAL 9005
BaseQuantities - Height: 2392 mm; Width: 1034 mm; Area: 3.49322 m2

# IfcDoor: AL_32.i_Binnenkozijn-enkeledeur_Linksdraaiend:Merk d.sp, AL_32.i_Binnenkozijn-enkeledeur_Linksdraaiend:Merk d.sp:6664101
In: 00 begane grond
Type - OperationType: SINGLE_SWING_LEFT; ParameterTakesPrecedence: no; Sizeable: no; Classification: 32.31.21 (Uniformat); Material: <Unnamed> (2), 31_Glas, NLRS_i3_hout_Loofhout (hardhout) RAL 9002
Type - AL_32.i_Binnenkozijn-enkeledeur_Linksdraaiend:Merk d.sp:6664101 - PanelOperation: SWINGING
Type - Pset_DoorCommon - IsExternal: no; Reference: AL_32.i_Binnenkozijn-enkeledeur_Linksdraaiend:Merk d.sp
Type - Pset_ProductRequirements - Category: Doors
Type - Pset_QuantityTakeOff - Reference: AL_32.i_Binnenkozijn-enkeledeur_Linksdraaiend:Merk d.sp
OverallHeight: 2442 mm; OverallWidth: 884 mm; Material: NLRS_i3_hout_Loofhout (hardhout) RAL 9002
BaseQuantities - Height: 2392 mm; Width: 884 mm; Area: 3.09182 m2

# IfcDoor: AL_32.i_Binnenkozijn-enkeledeur_Linksdraaiend:Merk e.sp (2000mm hoog) (2)
In: 00 begane grond
Type - OperationType: SINGLE_SWING_LEFT; ParameterTakesPrecedence: no; Sizeable: no; Classification: 32.31.21 (Uniformat); Material: <Unnamed> (2), 31_Glas, NLRS_i3_hout_Loofhout (hardhout) RAL 9002
Type - AL_32.i_Binnenkozijn-enkeledeur_Linksdraaiend:Merk e.sp (2000mm hoog):5721811 - PanelOperation: SWINGING
Type - Pset_DoorCommon - IsExternal: no; Reference: AL_32.i_Binnenkozijn-enkeledeur_Linksdraaiend:Merk e.sp (2000mm hoog)
Type - Pset_ProductRequirements - Category: Doors
Type - Pset_QuantityTakeOff - Reference: AL_32.i_Binnenkozijn-enkeledeur_Linksdraaiend:Merk e.sp (2000mm hoog)
OverallHeight: 2127 mm; OverallWidth: 834 mm; Material: NLRS_i3_hout_Loofhout (hardhout) RAL 9002
BaseQuantities - Height: 2077 mm; Width: 834 mm; Area: 2.59577 m2
Name (AL_32.i_Binnenkozijn-enkeledeur_Linksdraaiend:Merk e.sp (2000mm hoog):...)
5721811 | Pset_OpeningElementCommon - Reference: AL_32.i_Binnenkozijn-enkeledeur_Linksdraaiend:Merk e.sp (2000mm hoog); sets with these values: 2
5722053 | Pset_DoorCommon - IsExternal: yes

# IfcDoor: AL_32.i_Binnenkozijn-enkeledeur_Linksdraaiend:Merk f.sp (2100mm hoog), AL_32.i_Binnenkozijn-enkeledeur_Linksdraaiend:Merk f.sp (2100mm hoog):3414985
In: 00 begane grond
Type - OperationType: SINGLE_SWING_LEFT; ParameterTakesPrecedence: no; Sizeable: no; Classification: 32.31.21 (Uniformat); Material: <Unnamed> (2), 31_Glas, NLRS_i3_hout_Loofhout (hardhout) RAL 9002
Type - AL_32.i_Binnenkozijn-enkeledeur_Linksdraaiend:Merk f.sp (2100mm hoog):3414985 - PanelOperation: SWINGING
Type - Pset_DoorCommon - IsExternal: no; Reference: AL_32.i_Binnenkozijn-enkeledeur_Linksdraaiend:Merk f.sp (2100mm hoog)
Type - Pset_ProductRequirements - Category: Doors
Type - Pset_QuantityTakeOff - Reference: AL_32.i_Binnenkozijn-enkeledeur_Linksdraaiend:Merk f.sp (2100mm hoog)
OverallHeight: 2227 mm; OverallWidth: 784 mm; Material: NLRS_i3_hout_Loofhout (hardhout) RAL 9002
Pset_OpeningElementCommon - Reference: AL_32.i_Binnenkozijn-enkeledeur_Linksdraaiend:Merk f.sp (2100mm hoog); sets with these values: 2
BaseQuantities - Height: 2177 mm; Width: 784 mm; Area: 2.58772 m2

# IfcDoor: AL_32.i_Binnenkozijn-enkeledeur_Linksdraaiend:Merk g.sp (2100mm hoog), AL_32.i_Binnenkozijn-enkeledeur_Linksdraaiend:Merk g.sp (2100mm hoog):5143078
In: 00 begane grond
Type - OperationType: SINGLE_SWING_LEFT; ParameterTakesPrecedence: no; Sizeable: no; Classification: 32.31.21 (Uniformat); Material: <Unnamed> (2), 31_Glas, NLRS_i3_hout_Loofhout (hardhout) RAL 9002
Type - AL_32.i_Binnenkozijn-enkeledeur_Linksdraaiend:Merk g.sp (2100mm hoog):5143078 - PanelOperation: SWINGING
Type - Pset_DoorCommon - IsExternal: no; Reference: AL_32.i_Binnenkozijn-enkeledeur_Linksdraaiend:Merk g.sp (2100mm hoog)
Type - Pset_ProductRequirements - Category: Doors
Type - Pset_QuantityTakeOff - Reference: AL_32.i_Binnenkozijn-enkeledeur_Linksdraaiend:Merk g.sp (2100mm hoog)
OverallHeight: 2242 mm; OverallWidth: 734 mm; Material: NLRS_i3_hout_Loofhout (hardhout) RAL 9002
Pset_OpeningElementCommon - Reference: AL_32.i_Binnenkozijn-enkeledeur_Linksdraaiend:Merk g.sp (2100mm hoog); sets with these values: 2
BaseQuantities - Height: 2192 mm; Width: 734 mm; Area: 2.48042 m2

# IfcDoor: AL_32.i_Binnenkozijn-enkeledeur_Rechtsdraaiend met raampje:Merk a, AL_32.i_Binnenkozijn-enkeledeur_Rechtsdraaiend met raampje:Merk a:8159988
In: 00 begane grond
Type - OperationType: SINGLE_SWING_RIGHT; ParameterTakesPrecedence: no; Sizeable: no; Classification: 32 (Uniformat); Material: <Unnamed> (2), 31_Glas, NLRS_i3_hout_Loofhout (hardhout) RAL 9002
Type - AL_32.i_Binnenkozijn-enkeledeur_Rechtsdraaiend met raampje:Merk a:8159988 - PanelOperation: SWINGING
Type - Pset_DoorCommon - IsExternal: no; Reference: AL_32.i_Binnenkozijn-enkeledeur_Rechtsdraaiend met raampje:Merk a
Type - Pset_ProductRequirements - Category: Doors
Type - Pset_QuantityTakeOff - Reference: AL_32.i_Binnenkozijn-enkeledeur_Rechtsdraaiend met raampje:Merk a
OverallHeight: 2462 mm; OverallWidth: 1034 mm; Material: NLRS_i3_hout_Loofhout (hardhout) RAL 9002
Pset_OpeningElementCommon - Reference: AL_32.i_Binnenkozijn-enkeledeur_Rechtsdraaiend met raampje:Merk a; sets with these values: 2
BaseQuantities - Height: 2392 mm; Width: 1034 mm; Area: 3.5215 m2

# IfcDoor: AL_32.i_Binnenkozijn-enkeledeur_Rechtsdraaiend:Merk a (17)
Type - OperationType: SINGLE_SWING_RIGHT; ParameterTakesPrecedence: no; Sizeable: no; Classification: 32 (Uniformat); Material: 31_Glas, <Unnamed> (2), NLRS_i3_hout_Loofhout (hardhout) RAL 9002
Type - AL_32.i_Binnenkozijn-enkeledeur_Rechtsdraaiend:Merk a:2992568 - PanelOperation: SWINGING
Type - Pset_DoorCommon - IsExternal: no; Reference: AL_32.i_Binnenkozijn-enkeledeur_Rechtsdraaiend:Merk a
Type - Pset_ProductRequirements - Category: Doors
Type - Pset_QuantityTakeOff - Reference: AL_32.i_Binnenkozijn-enkeledeur_Rechtsdraaiend:Merk a
OverallHeight: 2462 mm; OverallWidth: 1034 mm; Material: NLRS_i3_hout_Loofhout (hardhout) RAL 9002
BaseQuantities - Height: 2392 mm; Width: 1034 mm; Area: 3.49322 m2
Name (AL_32.i_Binnenkozijn-enkeledeur_Rechtsdraaiend:Merk a:...) | In
2992568 | 00 begane grond
4286790 | 00 begane grond
4315872 | 00 begane grond
4315873 | 00 begane grond
4315877 | 00 begane grond
4547295 | 00 begane grond
5635857 | 00 begane grond
5636405 | 00 begane grond
5642233 | 00 begane grond
5642234 | 00 begane grond
5644760 | 00 begane grond
5743084 | 01 eerste verdieping
5904196 | 00 begane grond
5928374 | 01 eerste verdieping
7798983 | 01 eerste verdieping
10270975 | 00 begane grond
12236946 | 00 begane grond

# IfcDoor: AL_32.i_Binnenkozijn-enkeledeur_Rechtsdraaiend:Merk a, AL_32.i_Binnenkozijn-enkeledeur_Rechtsdraaiend:Merk a:3146553
In: 00 begane grond
Type - OperationType: SINGLE_SWING_RIGHT; ParameterTakesPrecedence: no; Sizeable: no; Classification: 32 (Uniformat); Material: <Unnamed> (2), 31_Glas, NLRS_i3_hout_Loofhout (hardhout) RAL 9002
Type - AL_32.i_Binnenkozijn-enkeledeur_Rechtsdraaiend:Merk a:3146553 - PanelOperation: SWINGING
Type - Pset_DoorCommon - IsExternal: no; Reference: AL_32.i_Binnenkozijn-enkeledeur_Rechtsdraaiend:Merk a
Type - Pset_ProductRequirements - Category: Doors
Type - Pset_QuantityTakeOff - Reference: AL_32.i_Binnenkozijn-enkeledeur_Rechtsdraaiend:Merk a
OverallHeight: 2462 mm; OverallWidth: 1034 mm; Material: NLRS_i3_hout_Loofhout (hardhout) RAL 9002
BaseQuantities - Height: 2392 mm; Width: 1034 mm; Area: 3.49322 m2

# IfcDoor: AL_32.i_Binnenkozijn-enkeledeur_Rechtsdraaiend:Merk a, AL_32.i_Binnenkozijn-enkeledeur_Rechtsdraaiend:Merk a:5923011
In: 00 begane grond
Type - OperationType: SINGLE_SWING_RIGHT; ParameterTakesPrecedence: no; Sizeable: no; Classification: 32 (Uniformat); Material: <Unnamed> (2), 31_Glas, NLRS_i3_hout_Loofhout (hardhout) RAL 9002
Type - AL_32.i_Binnenkozijn-enkeledeur_Rechtsdraaiend:Merk a:5923011 - PanelOperation: SWINGING
Type - Pset_DoorCommon - IsExternal: no; Reference: AL_32.i_Binnenkozijn-enkeledeur_Rechtsdraaiend:Merk a
Type - Pset_ProductRequirements - Category: Doors
Type - Pset_QuantityTakeOff - Reference: AL_32.i_Binnenkozijn-enkeledeur_Rechtsdraaiend:Merk a
OverallHeight: 2462 mm; OverallWidth: 1034 mm; Material: NLRS_i3_hout_Loofhout (hardhout) RAL 9002
BaseQuantities - Height: 2392 mm; Width: 1034 mm; Area: 3.49322 m2

# IfcDoor: AL_32.i_Binnenkozijn-enkeledeur_Rechtsdraaiend:Merk a (2000mm hoog), AL_32.i_Binnenkozijn-enkeledeur_Rechtsdraaiend:Merk a (2000mm hoog):10295106
In: 00 begane grond
Type - OperationType: SINGLE_SWING_RIGHT; ParameterTakesPrecedence: no; Sizeable: no; Classification: 32 (Uniformat); Material: <Unnamed> (2), 31_Glas, NLRS_i3_hout_Loofhout (hardhout) RAL 9002
Type - AL_32.i_Binnenkozijn-enkeledeur_Rechtsdraaiend:Merk a (2000mm hoog):10295106 - PanelOperation: SWINGING
Type - Pset_DoorCommon - IsExternal: no; Reference: AL_32.i_Binnenkozijn-enkeledeur_Rechtsdraaiend:Merk a (2000mm hoog)
Type - Pset_ProductRequirements - Category: Doors
Type - Pset_QuantityTakeOff - Reference: AL_32.i_Binnenkozijn-enkeledeur_Rechtsdraaiend:Merk a (2000mm hoog)
OverallHeight: 2142 mm; OverallWidth: 1034 mm; Material: NLRS_i3_hout_Loofhout (hardhout) RAL 9002
Pset_DoorCommon - IsExternal: yes
BaseQuantities - Height: 2092 mm; Width: 1034 mm; Area: 3.08822 m2

# IfcDoor: AL_32.i_Binnenkozijn-enkeledeur_Rechtsdraaiend:Merk a (2000mm hoog) (5)
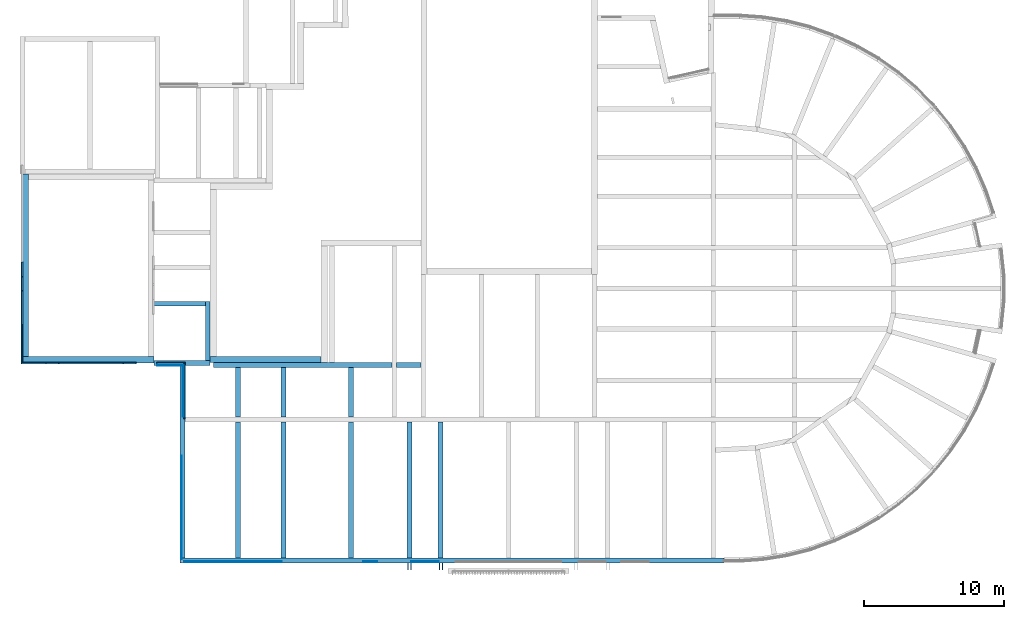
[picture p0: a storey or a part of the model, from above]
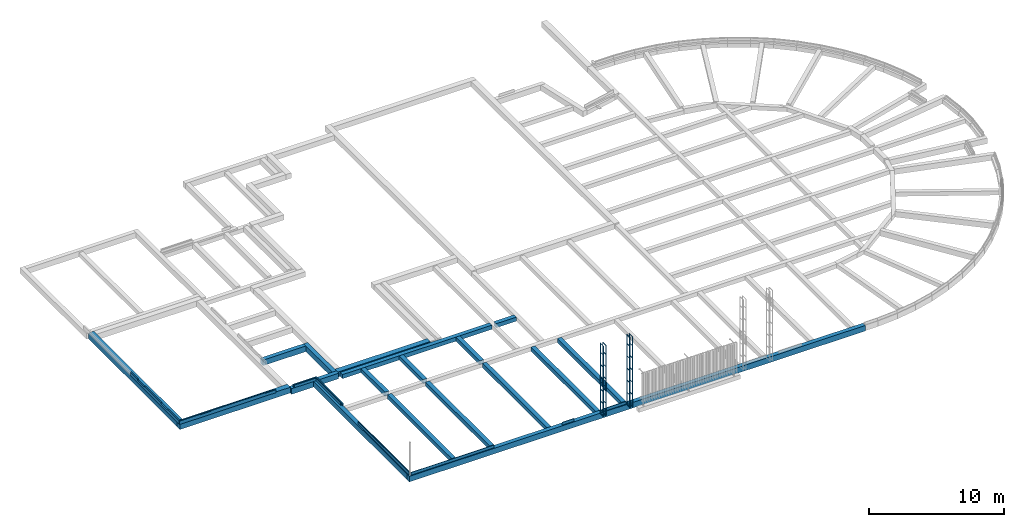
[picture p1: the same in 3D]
Properties of the parts of a building model (IFC2X3), part 4 of 13

# IfcDoor: AL_32.i_Binnenkozijn-enkeledeur_Rechtsdraaiend:Merk a (2000mm hoog) (5)
In: 01 eerste verdieping
Type - OperationType: SINGLE_SWING_RIGHT; ParameterTakesPrecedence: no; Sizeable: no; Classification: 32 (Uniformat); Material: <Unnamed> (2), 31_Glas, NLRS_i3_hout_Loofhout (hardhout) RAL 9002
Type - AL_32.i_Binnenkozijn-enkeledeur_Rechtsdraaiend:Merk a (2000mm hoog):11066411 - PanelOperation: SWINGING
Type - Pset_DoorCommon - IsExternal: no; Reference: AL_32.i_Binnenkozijn-enkeledeur_Rechtsdraaiend:Merk a (2000mm hoog)
Type - Pset_ProductRequirements - Category: Doors
Type - Pset_QuantityTakeOff - Reference: AL_32.i_Binnenkozijn-enkeledeur_Rechtsdraaiend:Merk a (2000mm hoog)
OverallHeight: 2142 mm; OverallWidth: 1034 mm; Material: NLRS_i3_hout_Loofhout (hardhout) RAL 9002
BaseQuantities - Height: 2092 mm; Width: 1034 mm; Area: 3.08822 m2
Name (AL_32.i_Binnenkozijn-enkeledeur_Rechtsdraaiend:Merk a (2000mm hoog):...)
11066411
11066472
11066474
11066478
11066505

# IfcDoor: AL_32.i_Binnenkozijn-enkeledeur_Rechtsdraaiend:Merk a (2000mm hoog) (3)
In: 00 begane grond
Type - OperationType: SINGLE_SWING_RIGHT; ParameterTakesPrecedence: no; Sizeable: no; Classification: 32 (Uniformat); Material: <Unnamed> (2), 31_Glas, NLRS_i3_hout_Loofhout (hardhout) RAL 9002
Type - AL_32.i_Binnenkozijn-enkeledeur_Rechtsdraaiend:Merk a (2000mm hoog):2858045 - PanelOperation: SWINGING
Type - Pset_DoorCommon - IsExternal: no; Reference: AL_32.i_Binnenkozijn-enkeledeur_Rechtsdraaiend:Merk a (2000mm hoog)
Type - Pset_ProductRequirements - Category: Doors
Type - Pset_QuantityTakeOff - Reference: AL_32.i_Binnenkozijn-enkeledeur_Rechtsdraaiend:Merk a (2000mm hoog)
OverallHeight: 2142 mm; OverallWidth: 1034 mm; Material: NLRS_i3_hout_Loofhout (hardhout) RAL 9002
BaseQuantities - Height: 2092 mm; Width: 1034 mm; Area: 3.08822 m2
Name (AL_32.i_Binnenkozijn-enkeledeur_Rechtsdraaiend:Merk a (2000mm hoog):...) | Reference | sets with these values
2858045 | AL_32.i_Binnenkozijn-enkeledeur_Rechtsdraaiend:Merk a (2000mm hoog) | 2
7472318 | AL_32.i_Binnenkozijn-enkeledeur_Rechtsdraaiend:Merk a (2000mm hoog) | 2
7473260 | Pset_DoorCommon - IsExternal: yes

# IfcDoor: AL_32.i_Binnenkozijn-enkeledeur_Rechtsdraaiend:Merk a (2100mm hog) (3)
In: 00 begane grond
Type - OperationType: SINGLE_SWING_RIGHT; ParameterTakesPrecedence: no; Sizeable: no; Classification: 32 (Uniformat); Material: <Unnamed> (2), 31_Glas, NLRS_i3_hout_Loofhout (hardhout) RAL 9002
Type - AL_32.i_Binnenkozijn-enkeledeur_Rechtsdraaiend:Merk a (2100mm hog):2858938 - PanelOperation: SWINGING
Type - Pset_DoorCommon - IsExternal: no; Reference: AL_32.i_Binnenkozijn-enkeledeur_Rechtsdraaiend:Merk a (2100mm hog)
Type - Pset_ProductRequirements - Category: Doors
Type - Pset_QuantityTakeOff - Reference: AL_32.i_Binnenkozijn-enkeledeur_Rechtsdraaiend:Merk a (2100mm hog)
OverallHeight: 2242 mm; OverallWidth: 1034 mm; Material: NLRS_i3_hout_Loofhout (hardhout) RAL 9002
Pset_DoorCommon - IsExternal: yes
BaseQuantities - Height: 2192 mm; Width: 1034 mm; Area: 3.22322 m2
Name (AL_32.i_Binnenkozijn-enkeledeur_Rechtsdraaiend:Merk a (2100mm hog):...)
2858938
3304326
3364924

# IfcDoor: AL_32.i_Binnenkozijn-enkeledeur_Rechtsdraaiend:Merk a (2100mm hog), AL_32.i_Binnenkozijn-enkeledeur_Rechtsdraaiend:Merk a (2100mm hog):6942818
In: 00 begane grond
Type - OperationType: SINGLE_SWING_RIGHT; ParameterTakesPrecedence: no; Sizeable: no; Classification: 32 (Uniformat); Material: <Unnamed> (2), 31_Glas, NLRS_i3_hout_Loofhout (hardhout) RAL 9002
Type - AL_32.i_Binnenkozijn-enkeledeur_Rechtsdraaiend:Merk a (2100mm hog):6942818 - PanelOperation: SWINGING
Type - Pset_DoorCommon - IsExternal: no; Reference: AL_32.i_Binnenkozijn-enkeledeur_Rechtsdraaiend:Merk a (2100mm hog)
Type - Pset_ProductRequirements - Category: Doors
Type - Pset_QuantityTakeOff - Reference: AL_32.i_Binnenkozijn-enkeledeur_Rechtsdraaiend:Merk a (2100mm hog)
OverallHeight: 2242 mm; OverallWidth: 1034 mm; Material: NLRS_i3_hout_Loofhout (hardhout) RAL 9002
Pset_DoorCommon - IsExternal: yes
BaseQuantities - Height: 2192 mm; Width: 1034 mm; Area: 3.22322 m2

# IfcDoor: AL_32.i_Binnenkozijn-enkeledeur_Rechtsdraaiend:Merk a (2100mm hoog) brandwerend, AL_32.i_Binnenkozijn-enkeledeur_Rechtsdraaiend:Merk a (2100mm hoog) brandwerend:4329975
In: 01 eerste verdieping
Type - OperationType: SINGLE_SWING_LEFT; ParameterTakesPrecedence: no; Sizeable: no; Classification: 32 (Uniformat); Material: <Unnamed> (2), 31_Glas, NLRS_i3_hout_Loofhout (hardhout) RAL 9002
Type - AL_32.i_Binnenkozijn-enkeledeur_Rechtsdraaiend:Merk a (2100mm hoog) brandwerend:4329975 - PanelOperation: SWINGING
Type - Pset_DoorCommon - IsExternal: no; Reference: AL_32.i_Binnenkozijn-enkeledeur_Rechtsdraaiend:Merk a (2100mm hoog) brandwerend
Type - Pset_ProductRequirements - Category: Doors
Type - Pset_QuantityTakeOff - Reference: AL_32.i_Binnenkozijn-enkeledeur_Rechtsdraaiend:Merk a (2100mm hoog) brandwerend
OverallHeight: 2242 mm; OverallWidth: 1018 mm; Material: NLRS_i3_hout_Loofhout (hardhout) RAL 9002
BaseQuantities - Height: 2192 mm; Width: 1018 mm; Area: 3.1836 m2

# IfcDoor: AL_32.i_Binnenkozijn-enkeledeur_Rechtsdraaiend:Merk b (2)
In: 00 begane grond
Type - OperationType: SINGLE_SWING_RIGHT; ParameterTakesPrecedence: no; Sizeable: no; Classification: 32 (Uniformat); Material: <Unnamed> (2), 31_Glas, NLRS_i3_hout_Loofhout (hardhout) RAL 9002
Type - AL_32.i_Binnenkozijn-enkeledeur_Rechtsdraaiend:Merk b:8032625 - PanelOperation: SWINGING
Type - Pset_DoorCommon - IsExternal: no; Reference: AL_32.i_Binnenkozijn-enkeledeur_Rechtsdraaiend:Merk b
Type - Pset_ProductRequirements - Category: Doors
Type - Pset_QuantityTakeOff - Reference: AL_32.i_Binnenkozijn-enkeledeur_Rechtsdraaiend:Merk b
OverallHeight: 2462 mm; OverallWidth: 984 mm; Material: NLRS_i3_hout_Loofhout (hardhout) RAL 9002
BaseQuantities - Height: 2392 mm; Width: 984 mm; Area: 3.35942 m2
Name (AL_32.i_Binnenkozijn-enkeledeur_Rechtsdraaiend:Merk b:...)
8032625
8032679

# IfcDoor: AL_32.i_Binnenkozijn-enkeledeur_Rechtsdraaiend:Merk b (2000mm hoog), AL_32.i_Binnenkozijn-enkeledeur_Rechtsdraaiend:Merk b (2000mm hoog):4998107
In: 00 begane grond
Type - OperationType: SINGLE_SWING_RIGHT; ParameterTakesPrecedence: no; Sizeable: no; Classification: 32 (Uniformat); Material: <Unnamed> (2), 31_Glas, NLRS_i3_hout_Loofhout (hardhout) RAL 9002
Type - AL_32.i_Binnenkozijn-enkeledeur_Rechtsdraaiend:Merk b (2000mm hoog):4998107 - PanelOperation: SWINGING
Type - Pset_DoorCommon - IsExternal: no; Reference: AL_32.i_Binnenkozijn-enkeledeur_Rechtsdraaiend:Merk b (2000mm hoog)
Type - Pset_ProductRequirements - Category: Doors
Type - Pset_QuantityTakeOff - Reference: AL_32.i_Binnenkozijn-enkeledeur_Rechtsdraaiend:Merk b (2000mm hoog)
OverallHeight: 2147 mm; OverallWidth: 984 mm; Material: NLRS_i3_hout_Loofhout (hardhout) RAL 9002
Pset_DoorCommon - IsExternal: yes
BaseQuantities - Height: 2077 mm; Width: 984 mm; Area: 2.94992 m2

# IfcDoor: AL_32.i_Binnenkozijn-enkeledeur_Rechtsdraaiend:Merk e (2000mm hoog), AL_32.i_Binnenkozijn-enkeledeur_Rechtsdraaiend:Merk e (2000mm hoog):2853173
In: 00 begane grond
Type - OperationType: SINGLE_SWING_RIGHT; ParameterTakesPrecedence: no; Sizeable: no; Classification: 32 (Uniformat); Material: <Unnamed> (2), 31_Glas, NLRS_i3_hout_Loofhout (hardhout) RAL 9002
Type - AL_32.i_Binnenkozijn-enkeledeur_Rechtsdraaiend:Merk e (2000mm hoog):2853173 - PanelOperation: SWINGING
Type - Pset_DoorCommon - IsExternal: no; Reference: AL_32.i_Binnenkozijn-enkeledeur_Rechtsdraaiend:Merk e (2000mm hoog)
Type - Pset_ProductRequirements - Category: Doors
Type - Pset_QuantityTakeOff - Reference: AL_32.i_Binnenkozijn-enkeledeur_Rechtsdraaiend:Merk e (2000mm hoog)
OverallHeight: 2127 mm; OverallWidth: 834 mm; Material: NLRS_i3_hout_Loofhout (hardhout) RAL 9002
Pset_DoorCommon - IsExternal: yes
BaseQuantities - Height: 2077 mm; Width: 834 mm; Area: 2.59577 m2

# IfcDoor: AL_32.i_Binnenkozijn-enkeledeur_Rechtsdraaiend:Merk e (2100mm hoog), AL_32.i_Binnenkozijn-enkeledeur_Rechtsdraaiend:Merk e (2100mm hoog):6942820
In: 00 begane grond
Type - OperationType: SINGLE_SWING_RIGHT; ParameterTakesPrecedence: no; Sizeable: no; Classification: 32 (Uniformat); Material: 31_Glas, <Unnamed> (2), NLRS_i3_hout_Loofhout (hardhout) RAL 9002
Type - AL_32.i_Binnenkozijn-enkeledeur_Rechtsdraaiend:Merk e (2100mm hoog):6942820 - PanelOperation: SWINGING
Type - Pset_DoorCommon - IsExternal: no; Reference: AL_32.i_Binnenkozijn-enkeledeur_Rechtsdraaiend:Merk e (2100mm hoog)
Type - Pset_ProductRequirements - Category: Doors
Type - Pset_QuantityTakeOff - Reference: AL_32.i_Binnenkozijn-enkeledeur_Rechtsdraaiend:Merk e (2100mm hoog)
OverallHeight: 2227 mm; OverallWidth: 834 mm; Material: NLRS_i3_hout_Loofhout (hardhout) RAL 9002
Pset_DoorCommon - IsExternal: yes
BaseQuantities - Height: 2177 mm; Width: 834 mm; Area: 2.71077 m2

# IfcDoor: AL_32.i_Binnenkozijn-enkeledeur_Rechtsdraaiend:Merk f (2100mm hoog), AL_32.i_Binnenkozijn-enkeledeur_Rechtsdraaiend:Merk f (2100mm hoog):3303502
In: 00 begane grond
Type - OperationType: SINGLE_SWING_RIGHT; ParameterTakesPrecedence: no; Sizeable: no; Classification: 32 (Uniformat); Material: 31_Glas, <Unnamed> (2), NLRS_i3_hout_Loofhout (hardhout) RAL 9002
Type - AL_32.i_Binnenkozijn-enkeledeur_Rechtsdraaiend:Merk f (2100mm hoog):3303502 - PanelOperation: SWINGING
Type - Pset_DoorCommon - IsExternal: no; Reference: AL_32.i_Binnenkozijn-enkeledeur_Rechtsdraaiend:Merk f (2100mm hoog)
Type - Pset_ProductRequirements - Category: Doors
Type - Pset_QuantityTakeOff - Reference: AL_32.i_Binnenkozijn-enkeledeur_Rechtsdraaiend:Merk f (2100mm hoog)
OverallHeight: 2227 mm; OverallWidth: 784 mm; Material: NLRS_i3_hout_Loofhout (hardhout) RAL 9002
Pset_OpeningElementCommon - Reference: AL_32.i_Binnenkozijn-enkeledeur_Rechtsdraaiend:Merk f (2100mm hoog); sets with these values: 2
BaseQuantities - Height: 2177 mm; Width: 784 mm; Area: 2.58772 m2

# IfcDoor: AL_32.i_Binnenkozijn-enkeledeur_Rechtsdraaiend:Merk g (2000mm hoog), AL_32.i_Binnenkozijn-enkeledeur_Rechtsdraaiend:Merk g (2000mm hoog):3262618
In: 00 begane grond
Type - OperationType: SINGLE_SWING_RIGHT; ParameterTakesPrecedence: no; Sizeable: no; Classification: 32 (Uniformat); Material: <Unnamed> (2), 31_Glas, NLRS_i3_hout_Loofhout (hardhout) RAL 9002
Type - AL_32.i_Binnenkozijn-enkeledeur_Rechtsdraaiend:Merk g (2000mm hoog):3262618 - PanelOperation: SWINGING
Type - Pset_DoorCommon - IsExternal: no; Reference: AL_32.i_Binnenkozijn-enkeledeur_Rechtsdraaiend:Merk g (2000mm hoog)
Type - Pset_ProductRequirements - Category: Doors
Type - Pset_QuantityTakeOff - Reference: AL_32.i_Binnenkozijn-enkeledeur_Rechtsdraaiend:Merk g (2000mm hoog)
OverallHeight: 2127 mm; OverallWidth: 734 mm; Material: NLRS_i3_hout_Loofhout (hardhout) RAL 9002
Pset_DoorCommon - IsExternal: yes
BaseQuantities - Height: 2077 mm; Width: 734 mm; Area: 2.35967 m2

# IfcDoor: AL_32.i_Binnenkozijn-enkeledeur_Rechtsdraaiend:Merk g (2100mm hoog), AL_32.i_Binnenkozijn-enkeledeur_Rechtsdraaiend:Merk g (2100mm hoog):5142247
In: 00 begane grond
Type - OperationType: SINGLE_SWING_RIGHT; ParameterTakesPrecedence: no; Sizeable: no; Classification: 32 (Uniformat); Material: 31_Glas, <Unnamed> (2), NLRS_i3_hout_Loofhout (hardhout) RAL 9002
Type - AL_32.i_Binnenkozijn-enkeledeur_Rechtsdraaiend:Merk g (2100mm hoog):5142247 - PanelOperation: SWINGING
Type - Pset_DoorCommon - IsExternal: no; Reference: AL_32.i_Binnenkozijn-enkeledeur_Rechtsdraaiend:Merk g (2100mm hoog)
Type - Pset_ProductRequirements - Category: Doors
Type - Pset_QuantityTakeOff - Reference: AL_32.i_Binnenkozijn-enkeledeur_Rechtsdraaiend:Merk g (2100mm hoog)
OverallHeight: 2242 mm; OverallWidth: 734 mm; Material: NLRS_i3_hout_Loofhout (hardhout) RAL 9002
Pset_DoorCommon - IsExternal: yes
BaseQuantities - Height: 2192 mm; Width: 734 mm; Area: 2.48042 m2

# IfcDoor: AL_32.i_Binnenkozijn-enkeledeur_Rechtsdraaiend:Merk g zwart, AL_32.i_Binnenkozijn-enkeledeur_Rechtsdraaiend:Merk g zwart:2999632
In: 00 begane grond
Type - OperationType: SINGLE_SWING_RIGHT; ParameterTakesPrecedence: no; Sizeable: no; Classification: 32 (Uniformat); Material: AL_31_KozijnHout hardhout RAL 9005 (2), 31_Glas
Type - AL_32.i_Binnenkozijn-enkeledeur_Rechtsdraaiend:Merk g zwart:2999632 - PanelOperation: SWINGING
Type - Pset_DoorCommon - IsExternal: no; Reference: AL_32.i_Binnenkozijn-enkeledeur_Rechtsdraaiend:Merk g zwart
Type - Pset_ProductRequirements - Category: Doors
Type - Pset_QuantityTakeOff - Reference: AL_32.i_Binnenkozijn-enkeledeur_Rechtsdraaiend:Merk g zwart
OverallHeight: 2442 mm; OverallWidth: 734 mm; Material: AL_31_KozijnHout hardhout RAL 9005
BaseQuantities - Height: 2392 mm; Width: 734 mm; Area: 2.69042 m2

# IfcDoor: AL_32.i_Binnenkozijn-enkeledeur_Rechtsdraaiend:Merk h, AL_32.i_Binnenkozijn-enkeledeur_Rechtsdraaiend:Merk h:10125875
In: 00 begane grond
Type - OperationType: SINGLE_SWING_RIGHT; ParameterTakesPrecedence: no; Sizeable: no; Classification: 32 (Uniformat); Material: <Unnamed> (2), 31_Glas, NLRS_i3_hout_Loofhout (hardhout) RAL 9002
Type - AL_32.i_Binnenkozijn-enkeledeur_Rechtsdraaiend:Merk h:10125875 - PanelOperation: SWINGING
Type - Pset_DoorCommon - IsExternal: no; Reference: AL_32.i_Binnenkozijn-enkeledeur_Rechtsdraaiend:Merk h
Type - Pset_ProductRequirements - Category: Doors
Type - Pset_QuantityTakeOff - Reference: AL_32.i_Binnenkozijn-enkeledeur_Rechtsdraaiend:Merk h
OverallHeight: 2462 mm; OverallWidth: 1234 mm; Material: NLRS_i3_hout_Loofhout (hardhout) RAL 9002
Pset_DoorCommon - IsExternal: yes
BaseQuantities - Height: 2392 mm; Width: 1234 mm; Area: 4.02842 m2

# IfcDoor: AL_32_Binnendeur-schuifdeur in de wand met raampje:2392x2000, AL_32_Binnendeur-schuifdeur in de wand met raampje:2392x2000:10686886
In: 00 begane grond
Type - ParameterTakesPrecedence: no; Sizeable: no; Classification: 32 (Uniformat); Material: <Unnamed> (3), NLRS_f7_gipsplaat_gen, 31_Glas, AL_Aluminium RAL 9002, NLRS_h4_aluminium
Type - Pset_DoorCommon - IsExternal: no; Reference: AL_32_Binnendeur-schuifdeur in de wand met raampje:2392x2000
Type - Pset_ProductRequirements - Category: Doors
Type - Pset_QuantityTakeOff - Reference: AL_32_Binnendeur-schuifdeur in de wand met raampje:2392x2000
OverallHeight: 2452 mm; OverallWidth: 2000 mm; Material: NLRS_h4_aluminium, NLRS_i3_hout_Loofhout (hardhout) RAL 9002, ZZ_Default Wall, NLRS_f7_gipsplaat_gen, AL_Aluminium RAL 9002
BaseQuantities - Height: 2382 mm; Width: 2000 mm; Area: 11.828 m2

# IfcDoor: AL_32_Binnendeur-schuifdeur in de wand:2700x3400 (3)
In: 00 begane grond
Type - ParameterTakesPrecedence: no; Sizeable: no; Classification: 32 (Uniformat); Material: <Unnamed> (3), AL_Aluminium RAL 9002, NLRS_f7_gipsplaat_gen, 31_Glas, NLRS_h4_aluminium
Type - Pset_DoorCommon - IsExternal: no; Reference: AL_32_Binnendeur-schuifdeur in de wand:2700x3400
Type - Pset_ProductRequirements - Category: Doors
Type - Pset_QuantityTakeOff - Reference: AL_32_Binnendeur-schuifdeur in de wand:2700x3400
OverallHeight: 2760 mm; OverallWidth: 3400 mm; Material: NLRS_h4_aluminium, NLRS_i3_hout_Loofhout (hardhout) RAL 9002, ZZ_Default Wall, NLRS_f7_gipsplaat_gen, AL_Aluminium RAL 9002
BaseQuantities - Height: 2690 mm; Width: 3400 mm; Area: 19.7916 m2
Name (AL_32_Binnendeur-schuifdeur in de wand:2700x3400:...)
10578640
10600282
10600332

# IfcDoor: AL_32_Binnendeur-schuifdeur in de wand:2700x3400.sp, AL_32_Binnendeur-schuifdeur in de wand:2700x3400.sp:10599847
In: 00 begane grond
Type - ParameterTakesPrecedence: no; Sizeable: no; Classification: 32 (Uniformat); Material: NLRS_f7_gipsplaat_gen, <Unnamed> (3), 31_Glas, AL_Aluminium RAL 9002, NLRS_h4_aluminium
Type - Pset_DoorCommon - IsExternal: no; Reference: AL_32_Binnendeur-schuifdeur in de wand:2700x3400.sp
Type - Pset_ProductRequirements - Category: Doors
Type - Pset_QuantityTakeOff - Reference: AL_32_Binnendeur-schuifdeur in de wand:2700x3400.sp
OverallHeight: 2740 mm; OverallWidth: 3400 mm; Material: NLRS_h4_aluminium, NLRS_i3_hout_Loofhout (hardhout) RAL 9002, ZZ_Default Wall, NLRS_f7_gipsplaat_gen, AL_Aluminium RAL 9002
BaseQuantities - Height: 2690 mm; Width: 3400 mm; Area: 19.7916 m2

# IfcDoor: Bevestiging deur in bestaande wand:Bevestiging deur in bestaande wand, Bevestiging deur in bestaande wand:Bevestiging deur in bestaande wand:5703005
In: Podium
Type - ParameterTakesPrecedence: no; Sizeable: no; Material: AL_31_Naaldhout (vuren)
Type - Pset_DoorCommon - IsExternal: no; Reference: Bevestiging deur in bestaande wand:Bevestiging deur in bestaande wand
Type - Pset_ProductRequirements - Category: Doors
Type - Pset_QuantityTakeOff - Reference: Bevestiging deur in bestaande wand:Bevestiging deur in bestaande wand
OverallHeight: 38 mm; OverallWidth: 320 mm
BaseQuantities - Area: 0.01216 m2

# IfcDoor: skygate-Enkele panelen en deuren (enkele richting draaibaar):Enkel taatsdeur model 1850mm, skygate-Enkele panelen en deuren (enkele richting draaibaar):Enkel taatsdeur model 1850mm:7799846
In: 00 begane grond
Type - OperationType: DOUBLE_SWING_RIGHT; ParameterTakesPrecedence: no; Sizeable: no; Material: ZZ_00_Kleur_RAL 9002, <Unnamed>, ZZ_massa_lichtrood_transparant
Type - skygate-Enkele panelen en deuren (enkele richting draaibaar):Enkel taatsdeur model 1850mm:7799846 - PanelOperation: DOUBLE_ACTING
Type - Pset_DoorCommon - IsExternal: no; Reference: skygate-Enkele panelen en deuren (enkele richting draaibaar):Enkel taatsdeur model 1850mm
Type - Pset_ProductRequirements - Category: Doors
Type - Pset_QuantityTakeOff - Reference: skygate-Enkele panelen en deuren (enkele richting draaibaar):Enkel taatsdeur model 1850mm
OverallHeight: 2776 mm; OverallWidth: 1862 mm; Material: ZZ_00_Kleur_RAL 9002, ZZ_massa_lichtrood_transparant
Pset_OpeningElementCommon - Reference: skygate-Enkele panelen en deuren (enkele richting draaibaar):Enkel taatsdeur model 1850mm; sets with these values: 2
BaseQuantities - Height: 2694 mm; Width: 1850 mm; Area: 14.7824 m2

# IfcDoor: skygate-Enkele panelen en deuren:Vast paneel model 2315, skygate-Enkele panelen en deuren:Vast paneel model 2315:3148724
In: 00 begane grond
Type - OperationType: DOUBLE_SWING_LEFT; ParameterTakesPrecedence: no; Sizeable: no; Material: ZZ_massa_lichtrood_transparant, <Unnamed>, Skygate Matzwart
Type - skygate-Enkele panelen en deuren:Vast paneel model 2315:3148724 - PanelOperation: DOUBLE_ACTING
Type - Pset_DoorCommon - IsExternal: no; Reference: skygate-Enkele panelen en deuren:Vast paneel model 2315
Type - Pset_ProductRequirements - Category: Doors
Type - Pset_QuantityTakeOff - Reference: skygate-Enkele panelen en deuren:Vast paneel model 2315
OverallHeight: 2776 mm; OverallWidth: 1012 mm; Material: Skygate Matzwart, ZZ_massa_lichtrood_transparant
BaseQuantities - Height: 2694 mm; Width: 1000 mm; Area: 13.0163 m2

# IfcDoor: skygate-Enkele panelen en deuren:Vast paneel model 2315 RAL 9002, skygate-Enkele panelen en deuren:Vast paneel model 2315 RAL 9002:4325212
In: 00 begane grond
Type - OperationType: DOUBLE_SWING_LEFT; ParameterTakesPrecedence: no; Sizeable: no; Material: ZZ_massa_lichtrood_transparant, NLRS_h2_staal_RAL 7021, <Unnamed>
Type - skygate-Enkele panelen en deuren:Vast paneel model 2315 RAL 9002:4325212 - PanelOperation: DOUBLE_ACTING
Type - Pset_DoorCommon - IsExternal: no; Reference: skygate-Enkele panelen en deuren:Vast paneel model 2315 RAL 9002
Type - Pset_ProductRequirements - Category: Doors
Type - Pset_QuantityTakeOff - Reference: skygate-Enkele panelen en deuren:Vast paneel model 2315 RAL 9002
OverallHeight: 2776 mm; OverallWidth: 1012 mm; Material: NLRS_h2_staal_RAL 7021, ZZ_massa_lichtrood_transparant
BaseQuantities - Height: 2694 mm; Width: 1000 mm; Area: 13.0163 m2

# IfcFlowTerminal: 52.12_HWA_hoek_ITX1:52.12_HWA_zink 2 (8)
Type - Classification: 52.12 afvoeren; regenwater, afvoerinstallatie; buiten het gebouw (Uniformat); Material: h7_zink
Type - Pset_ManufacturerTypeInformation - Manufacturer: -
Type - Pset_ProductRequirements - Category: Generic Models
Type - Pset_QuantityTakeOff - Reference: 52.12_HWA_hoek_ITX1:52.12_HWA_zink 2
Classification: - (Default Classification); 52.12 afvoeren; regenwater, afvoerinstallatie; buiten het gebouw (Uniformat)
Pset_DistributionFlowElementCommon - Reference: 52.12_HWA_hoek_ITX1:52.12_HWA_zink 2; sets with these values: 3
Pset_ManufacturerTypeInformation - sets with these values: 2
Pset_ProductRequirements - sets with these values: 2
Name (52.12_HWA_hoek_ITX1:52.12_HWA_zink 2:...) | In
9053115 | 00 begane grond
9054313 | 00 begane grond
9054345 | 00 begane grond
9084551 | 4.06
9671428 | 5.01
9671646 | 5.01
9673631 | 00 begane grond
9788743 | 4.07

# IfcFlowTerminal: 74.11_VWN_douchekraan met glijstang en kop:74.11_VWN_douchekraan met glijstang en kop (2)
Type - Classification: 74.11 vaste sanitaire voorzieningen; standaard, sanitaire toestellen; normaal (Uniformat); Material: Color RGB 200-200-200
Type - Pset_ProductRequirements - Category: Plumbing Fixtures
Type - Pset_QuantityTakeOff - Reference: 74.11_VWN_douchekraan met glijstang en kop:74.11_VWN_douchekraan met glijstang en kop
Pset_DistributionFlowElementCommon - Reference: 74.11_VWN_douchekraan met glijstang en kop:74.11_VWN_douchekraan met glijstang en kop; sets with these values: 3
Pset_ProductRequirements - sets with these values: 2
Name (74.11_VWN_douchekraan met glijstang en kop:74.11_VWN_douchekraan met glijstang en kop:...) | In
9037832 | 6.04b
9037948 | 6.04a

# IfcFlowTerminal: 74.11_VWN_douchekraan zonder glijstang:74.11_VWN_douchekraan zonder glijstang (2)
In: 00 begane grond
Type - Classification: 74.11 vaste sanitaire voorzieningen; standaard, sanitaire toestellen; normaal (Uniformat); Material: Color RGB 200-200-200
Type - Pset_ProductRequirements - Category: Plumbing Fixtures
Type - Pset_QuantityTakeOff - Reference: 74.11_VWN_douchekraan zonder glijstang:74.11_VWN_douchekraan zonder glijstang
Pset_DistributionFlowElementCommon - Reference: 74.11_VWN_douchekraan zonder glijstang:74.11_VWN_douchekraan zonder glijstang; sets with these values: 3
Pset_ProductRequirements - sets with these values: 2
Name (74.11_VWN_douchekraan zonder glijstang:74.11_VWN_douchekraan zonder glijstang:...)
9777958
9778110

# IfcFlowTerminal: AL_74_Stortgootsteen Sphinx:AL_74_Stortgootsteen Sphinx (3)
Type - Classification: (74.1) (Uniformat); Material: <Unnamed>, AL_Chroom
Type - Pset_ManufacturerTypeInformation - Manufacturer: Sphinx
Type - Pset_ProductRequirements - Category: Plumbing Fixtures
Type - Pset_QuantityTakeOff - Reference: AL_74_Stortgootsteen Sphinx:AL_74_Stortgootsteen Sphinx
Material: AL_Chroom, AL_Sanitair porselein
Pset_DistributionFlowElementCommon - Reference: AL_74_Stortgootsteen Sphinx:AL_74_Stortgootsteen Sphinx; sets with these values: 3
Pset_ManufacturerTypeInformation - sets with these values: 2
Pset_ProductRequirements - sets with these values: 2
Name (AL_74_Stortgootsteen Sphinx:AL_74_Stortgootsteen Sphinx:...) | In
7446648 | 00 begane grond
7446658 | 11.14
10065822 | 5.03

# IfcFlowTerminal: AL_74_zwevend_Miva-toilet_ITX:470mm x 370mm (2)
Type - Material: Métal - Aluminium brossé, Porcelaine - Blanche
Type - Pset_ManufacturerTypeInformation - Manufacturer: Revit
Type - Pset_ProductRequirements - Category: Plumbing Fixtures
Type - Pset_QuantityTakeOff - Reference: AL_74_zwevend_Miva-toilet_ITX:470mm x 370mm
Material: Porcelaine - Blanche, Métal - Aluminium brossé
Pset_DistributionFlowElementCommon - Reference: AL_74_zwevend_Miva-toilet_ITX:470mm x 370mm
Name (AL_74_zwevend_Miva-toilet_ITX:470mm x 370mm:...) | In | Pset_DistributionFlowElementCommon, sets with these values
4839725 | 11.11 | 2
10061754 | 5.04 | 3 | Pset_ManufacturerTypeInformation - sets with these values: 2; Pset_ProductRequirements - sets with these values: 2

# IfcFlowTerminal: NL_74_urinoir:NL_74_urinoir (3)
In: 7.04
Type - Pset_ProductRequirements - Category: Plumbing Fixtures
Type - Pset_QuantityTakeOff - Reference: NL_74_urinoir:NL_74_urinoir
Pset_DistributionFlowElementCommon - Reference: NL_74_urinoir:NL_74_urinoir; sets with these values: 3
Pset_ProductRequirements - sets with these values: 2
Name (NL_74_urinoir:NL_74_urinoir:...)
4993700
4993881
4993927

# IfcFurnishingElement: AL_Vaste bank kleedruimte:Vaste bank kleedruimte (13)
Type - Pset_FurnitureTypeCommon - Description: Vaste bank kleedkamer
Type - Pset_ProductRequirements - Category: Furniture
Type - Pset_QuantityTakeOff - Reference: AL_Vaste bank kleedruimte:Vaste bank kleedruimte
Name (AL_Vaste bank kleedruimte:Vaste bank kleedruimte:...) | In
4611050 | 6.01d
4611234 | 6.01c
4611294 | 6.01c
4611414 | 6.01d
4611541 | 6.01a
4611679 | 6.01b
4611751 | 6.01b
4611880 | 6.01a
4612009 | 8.03a
4612224 | 8.03a
4612377 | 8.03a
4612597 | 8.03b
4612866 | 8.03b

# IfcFurnishingElement: Kapstokken1:Kapstokken, Kapstokken1:Kapstokken:12743738
In: 1.12
Type - Pset_ProductRequirements - Category: Furniture
Type - Pset_QuantityTakeOff - Reference: Kapstokken1:Kapstokken

# IfcFurnishingElement: Kapstokken3:Kapstokken, Kapstokken3:Kapstokken:12284143
In: 1.09a
Type - Pset_ProductRequirements - Category: Furniture
Type - Pset_QuantityTakeOff - Reference: Kapstokken3:Kapstokken

# IfcFurnishingElement: Kapstokken4:Kapstokken, Kapstokken4:Kapstokken:12684255
In: 2.06
Type - Pset_ProductRequirements - Category: Furniture
Type - Pset_QuantityTakeOff - Reference: Kapstokken4:Kapstokken

# IfcFurnishingElement: Kapstokken:Kapstokken, Kapstokken:Kapstokken:12279805
In: 2.04
Type - Pset_ProductRequirements - Category: Furniture
Type - Pset_QuantityTakeOff - Reference: Kapstokken:Kapstokken

# IfcFurnishingElement: NLRS_74_PF_UN_fontein_gen_rsf:fontein (2)
Type - Classification: 74.10 vaste sanitaire voorzieningen; standaard, algemeen (verzamelniveau) (Uniformat)
Type - Pset_ProductRequirements - Category: Plumbing Fixtures
Type - Pset_QuantityTakeOff - Reference: NLRS_74_PF_UN_fontein_gen_rsf:fontein
Pset_FurnitureTypeCommon - Description: fontein
Name (NLRS_74_PF_UN_fontein_gen_rsf:fontein:...) | In
9247642 | 8.02c
9247693 | 8.02d

# IfcFurnishingElement: NLRS_74_PF_UN_hangend toilet_gen_rsf:hangend toilet (25)
Type - Classification: 74.10 vaste sanitaire voorzieningen; standaard, algemeen (verzamelniveau) (Uniformat); Material: NLRS_g3_keramisch_wit (2)
Type - Pset_ProductRequirements - Category: Plumbing Fixtures
Type - Pset_QuantityTakeOff - Reference: NLRS_74_PF_UN_hangend toilet_gen_rsf:hangend toilet
Material: NLRS_h3_chroom, NLRS_g3_keramisch_wit, NLRS_n6_toilet bril
Pset_FurnitureTypeCommon - Description: Hang toilet
Name (NLRS_74_PF_UN_hangend toilet_gen_rsf:hangend toilet:...) | In
4332714 | 1.07
4332715 | 1.07
4333828 | 6.01b
4333930 | 6.01a
4334728 | 11.09
4573929 | 1.05
4574008 | 1.05
4603193 | 7.04
4603723 | 7.04
4603767 | 7.03
4603812 | 7.03
5012727 | 6.01d
5012766 | 6.01c
5643367 | 11.09
5643750 | 11.09
5859145 | 11.10
5859146 | 11.10
5859147 | 11.10
9247845 | 8.02d
9248252 | 8.02c
9671202 | 1.05b
9671239 | 1.05a
9671312 | 1.07
9671324 | 1.05a
9671368 | 1.05b

# IfcFurnishingElement: NLRS_74_PF_UN_wastafel_gen_rsf:wastafel (12)
Type - Classification: 74.10 vaste sanitaire voorzieningen; standaard, algemeen (verzamelniveau) (Uniformat)
Type - Pset_ProductRequirements - Category: Plumbing Fixtures
Type - Pset_QuantityTakeOff - Reference: NLRS_74_PF_UN_wastafel_gen_rsf:wastafel
Pset_FurnitureTypeCommon - Description: wastafel
Name (NLRS_74_PF_UN_wastafel_gen_rsf:wastafel:...) | In
4333481 | 7.03
4333535 | 7.04
4602508 | 6.04b
4602546 | 6.04a
5643854 | 11.09
5752543 | 11.11
5752544 | 11.10
10061828 | 5.04
10063651 | 1.05a
10063688 | 1.05b
10063935 | 1.07
10271727 | 1.05

# IfcFurnishingElement: Tribune schoolhal:Tribune schoolhal, Tribune schoolhal:Tribune schoolhal:6053097
In: 4.01a
Type - Material: NLRS_i4_hout_multiplex
Type - Pset_ProductRequirements - Category: Furniture
Type - Pset_QuantityTakeOff - Reference: Tribune schoolhal:Tribune schoolhal
Material: NLRS_i4_hout_multiplex, AL_31_Naaldhout (vuren)

# IfcFurnishingElement: uitstort goodsteen techniek lokaal:uitstort goodsteen techniek lokaal, uitstort goodsteen techniek lokaal:uitstort goodsteen techniek lokaal:11763001
In: 4.05
Type - Pset_ProductRequirements - Category: Furniture
Type - Pset_QuantityTakeOff - Reference: uitstort goodsteen techniek lokaal:uitstort goodsteen techniek lokaal

# IfcMember: Rectangular Mullion:22x84 (12)
In: 00 begane grond
Type - PredefinedType: MULLION; Material: NLRS_i3_hout_Loofhout (hardhout) RAL 9002
Type - Pset_MemberCommon - IsExternal: no; Reference: Rectangular Mullion:22x84
Type - Pset_ProductRequirements - Category: Curtain Wall Mullions
Type - Pset_QuantityTakeOff - Reference: Rectangular Mullion:22x84
Classification: 31.0 (Uniformat)
Pset_MemberCommon - IsExternal: yes
Name (Rectangular Mullion:22x84:...) | Span (mm) = Length (mm) | CrossSectionArea (m2) | NetSurfaceArea (m2) | NetVolume (m3)
7642096 | 897.5 | 0.096983 | 0.192118 | 0.00165858
12116018 | 827.5 | 0.089563 | 0.17543 | 0.00152922
12116110 | 827.5 | 0.089563 | 0.17543 | 0.00152922
12116235 | 897.5 | 0.096983 | 0.192118 | 0.00165858
12117567 | 862.5 | 0.093273 | 0.18285 | 0.0015939
12117646 | 862.5 | 0.093273 | 0.18285 | 0.0015939
12117736 | 862.5 | 0.093273 | 0.184698 | 0.0015939
12117821 | 862.5 | 0.093273 | 0.184698 | 0.0015939
12122991 | 848.5 | 0.091789 | 0.18173 | 0.00156803
12122995 | 779 | 0.084422 | 0.165148 | 0.00143959
12122999 | 848.5 | 0.091789 | 0.18173 | 0.00156803
12123003 | 779 | 0.084422 | 0.165148 | 0.00143959

# IfcMember: Rectangular Mullion:45x114 (5)
In: 00 begane grond
Type - PredefinedType: MULLION; Material: NLRS_i3_hout_Loofhout (hardhout) RAL 9002
Type - Pset_MemberCommon - IsExternal: no; Reference: Rectangular Mullion:45x114
Type - Pset_ProductRequirements - Category: Curtain Wall Mullions
Type - Pset_QuantityTakeOff - Reference: Rectangular Mullion:45x114
Classification: 31.0 (Uniformat)
Pset_MemberCommon - IsExternal: yes
Name (Rectangular Mullion:45x114:...) | Span (mm) = Length (mm) | CrossSectionArea (m2) | NetSurfaceArea (m2) | NetVolume (m3)
8645769 | 1733 | 0.280677 | 0.561354 | 0.00889029
9801542 | 1733 | 0.280677 | 0.561354 | 0.00889029
8646243 | 1755 | 0.284175 | 0.56835 | 0.00900315
10003658 | 1800 | 0.29133 | 0.58266 | 0.009234
10003661 | 2111.51 | 0.34086 | 0.68172 | 0.010832

# IfcMember: Rectangular Mullion:45x120 (8)
In: 00 begane grond
Type - PredefinedType: MULLION; Material: n6_kunststof_RAL 7035
Type - Pset_MemberCommon - IsExternal: no; Reference: Rectangular Mullion:45x120
Type - Pset_ProductRequirements - Category: Curtain Wall Mullions
Type - Pset_QuantityTakeOff - Reference: Rectangular Mullion:45x120
Classification: 31.0 (Uniformat)
Pset_MemberCommon - IsExternal: yes
Name (Rectangular Mullion:45x120:...) | Span (mm) = Length (mm) | CrossSectionArea (m2) | NetSurfaceArea (m2) | NetVolume (m3)
3131872 | 672 | 0.11628 | 0.22716 | 0.0036288
3132246 | 1927 | 0.323355 | 0.64131 | 0.0104058
7492563 | 672 | 0.11628 | 0.22716 | 0.0036288
7492564 | 1927 | 0.323355 | 0.64131 | 0.0104058
5837572 | 908.994 | 0.155384 | 0.305368 | 0.00490857
5837584 | 909.006 | 0.155386 | 0.305372 | 0.00490863
9324835 | 908.994 | 0.155384 | 0.305368 | 0.00490857
9324836 | 909.006 | 0.155386 | 0.305372 | 0.00490863

# IfcMember: Rectangular Mullion:52x114 DTS (7)
Type - PredefinedType: MULLION; Material: NLRS_n6_kunststof_DTS-basis black
Type - Pset_MemberCommon - IsExternal: no; Reference: Rectangular Mullion:52x114 DTS
Type - Pset_ProductRequirements - Category: Curtain Wall Mullions
Type - Pset_QuantityTakeOff - Reference: Rectangular Mullion:52x114 DTS
Classification: 31.0 (Uniformat)
Pset_MemberCommon - IsExternal: yes
Name (Rectangular Mullion:52x114 DTS:...) | In | Span (mm) = Length (mm) | CrossSectionArea (m2) | NetSurfaceArea (m2) | NetVolume (m3)
3650436 | 00 begane grond | 1034 | 0.177572 | 0.355144 | 0.00612955
9319668 | 01 eerste verdieping | 413.937 | 0.0746416 | 0.143355 | 0.00245382
9319669 | 01 eerste verdieping | 206.125 | 0.0401448 | 0.0684337 | 0.00122191
9319670 | 01 eerste verdieping | 413.937 | 0.0746416 | 0.143355 | 0.00245382
9046988 | 01 eerste verdieping | 1033.41 | 0.177474 | 0.354948 | 0.00612605
9282403 | 00 begane grond | 997.5 | 0.171513 | 0.337098 | 0.00591318
9282409 | 00 begane grond | 997.5 | 0.171513 | 0.337098 | 0.00591318

# IfcMember: Rectangular Mullion:60x120 DTS (111)
In: 00 begane grond
Type - PredefinedType: MULLION; Material: NLRS_n6_kunststof_DTS-basis black
Type - Pset_MemberCommon - IsExternal: no; Reference: Rectangular Mullion:60x120 DTS
Type - Pset_ProductRequirements - Category: Curtain Wall Mullions
Type - Pset_QuantityTakeOff - Reference: Rectangular Mullion:60x120 DTS
Classification: 31.0 (Uniformat)
Pset_MemberCommon - IsExternal: yes
Name (Rectangular Mullion:60x120 DTS:...) | Span (mm) = Length (mm) | CrossSectionArea (m2) | NetSurfaceArea (m2) | NetVolume (m3)
3004382 | 488.598 | 0.0951476 | 0.183095 | 0.0035179
3029716 | 1943 | 0.35694 | 0.69948 | 0.0139896
3029810 | 488.402 | 0.0951124 | 0.183025 | 0.0035165
3019239 | 840.077 | 0.158414 | 0.309628 | 0.00604855
3039435 | 842.5 | 0.15885 | 0.3105 | 0.006066
3019456 | 842.5 | 0.15885 | 0.3105 | 0.006066
3039661 | 842.5 | 0.15885 | 0.3105 | 0.006066
3019654 | 1685 | 0.3105 | 0.621 | 0.012132
3019880 | 842.5 | 0.15885 | 0.3105 | 0.006066
3039893 | 842.5 | 0.15885 | 0.3105 | 0.006066
3020069 | 842.5 | 0.15885 | 0.3105 | 0.006066
3040115 | 851.263 | 0.160427 | 0.313655 | 0.0061291
3020236 | 838.861 | 0.158195 | 0.30919 | 0.0060398
3041967 | 844.239 | 0.159163 | 0.311126 | 0.00607852
3020402 | 833.486 | 0.157228 | 0.307255 | 0.0060011
3042201 | 833.486 | 0.157228 | 0.307255 | 0.0060011
3020545 | 1669.37 | 0.307687 | 0.615375 | 0.0120195
3020690 | 833.313 | 0.157196 | 0.307193 | 0.00599985
3042449 | 834.687 | 0.157444 | 0.307687 | 0.00600975
3020868 | 1051.07 | 0.196392 | 0.392784 | 0.00756769
3025922 | 1000.94 | 0.18737 | 0.367539 | 0.00720678
3037853 | 908.9 | 0.170802 | 0.334404 | 0.00654408
3036831 | 269.04 | 0.0556273 | 0.104055 | 0.00193709
12606267 | 354.336 | 0.0709805 | 0.134761 | 0.00255122
12606338 | 986 | 0.18468 | 0.35496 | 0.0070992
3131751 | 968.054 | 0.18145 | 0.355699 | 0.00696999
3131871 | 45 | 0.0153 | 0.0162 | 0.000324
3132018 | 929.916 | 0.174585 | 0.33477 | 0.0066954
3132372 | 929.916 | 0.174585 | 0.33477 | 0.0066954
3132414 | 910.751 | 0.171135 | 0.32787 | 0.00655741
3132452 | 929.679 | 0.174542 | 0.334684 | 0.00669369
3132486 | 967.9 | 0.181422 | 0.355644 | 0.00696888
3132650 | 929.916 | 0.174585 | 0.33477 | 0.0066954
7492560 | 911.051 | 0.171189 | 0.327978 | 0.00655957
4093379 | 1894 | 0.34812 | 0.69624 | 0.0136368
4200608 | 797.922 | 0.150826 | 0.294452 | 0.00574504
4200648 | 1942.76 | 0.356896 | 0.699392 | 0.0139878
4200653 | 83.5 | 0.02223 | 0.03006 | 0.0006012
7508911 | 1985.97 | 0.364675 | 0.722151 | 0.014299
7508976 | 757.855 | 0.143614 | 0.272828 | 0.00545656
9428018 | 758.855 | 0.143794 | 0.273188 | 0.00546376
9428162 | 760.322 | 0.144058 | 0.273716 | 0.00547432
4201025 | 957.545 | 0.179558 | 0.351916 | 0.00689433
4201029 | 81 | 0.02178 | 0.02916 | 0.0005832
4201033 | 917.9 | 0.172422 | 0.330444 | 0.00660888
4201036 | 918.1 | 0.172458 | 0.330516 | 0.00661032
4201053 | 918.3 | 0.172494 | 0.330588 | 0.00661176
4201059 | 957.452 | 0.179541 | 0.351883 | 0.00689365
4201118 | 916.9 | 0.172242 | 0.330084 | 0.00660168
4201127 | 917.9 | 0.172422 | 0.330444 | 0.00660888
7496945 | 916.7 | 0.172206 | 0.330012 | 0.00660024
5203705 | 674.594 | 0.128627 | 0.250054 | 0.00485708
5203710 | 1985.5 | 0.36459 | 0.72198 | 0.0142956
5254167 | 1072 | 0.20016 | 0.40032 | 0.0077184
5459102 | 834.002 | 0.15732 | 0.307441 | 0.00600481
5459508 | 834.002 | 0.15732 | 0.307441 | 0.00600481
5565100 | 852.447 | 0.160641 | 0.314081 | 0.00613762
5565130 | 842.5 | 0.15885 | 0.3105 | 0.006066
5565106 | 842.5 | 0.15885 | 0.3105 | 0.006066
5565145 | 842.5 | 0.15885 | 0.3105 | 0.006066
5565112 | 1599 | 0.29502 | 0.59004 | 0.0115128
5565118 | 842.5 | 0.15885 | 0.3105 | 0.006066
5565160 | 842.5 | 0.15885 | 0.3105 | 0.006066
5567081 | 841.492 | 0.158669 | 0.310137 | 0.00605874
5567111 | 844.508 | 0.159211 | 0.311223 | 0.00608046
5567087 | 843 | 0.15894 | 0.31068 | 0.0060696
5567126 | 843 | 0.15894 | 0.31068 | 0.0060696
5567093 | 1686 | 0.31068 | 0.62136 | 0.0121392
5567099 | 843 | 0.15894 | 0.31068 | 0.0060696
5567141 | 843 | 0.15894 | 0.31068 | 0.0060696
5567105 | 843 | 0.15894 | 0.31068 | 0.0060696
5567156 | 843 | 0.15894 | 0.31068 | 0.0060696
5567300 | 845.5 | 0.15939 | 0.31158 | 0.0060876
5567330 | 840.5 | 0.15849 | 0.30978 | 0.0060516
5567306 | 843 | 0.15894 | 0.31068 | 0.0060696
5567345 | 843 | 0.15894 | 0.31068 | 0.0060696
5567312 | 1686 | 0.31068 | 0.62136 | 0.0121392
5567318 | 843 | 0.15894 | 0.31068 | 0.0060696
5567360 | 843 | 0.15894 | 0.31068 | 0.0060696
5567324 | 826.9 | 0.156042 | 0.304884 | 0.00595368
5567375 | 826.523 | 0.155974 | 0.304748 | 0.00595097
5567903 | 840.308 | 0.158455 | 0.309711 | 0.00605022
5567933 | 845.692 | 0.159425 | 0.311649 | 0.00608898
5567909 | 843 | 0.15894 | 0.31068 | 0.0060696
5567948 | 843 | 0.15894 | 0.31068 | 0.0060696
5567915 | 1686 | 0.31068 | 0.62136 | 0.0121392
5567921 | 842.313 | 0.158816 | 0.310433 | 0.00606465
5567963 | 843.687 | 0.159064 | 0.310927 | 0.00607455
5567927 | 863.125 | 0.162563 | 0.317925 | 0.0062145
5567978 | 863.125 | 0.162563 | 0.317925 | 0.0062145
5583364 | 1029.31 | 0.192476 | 0.377751 | 0.00741103
5583365 | 880.69 | 0.165724 | 0.324249 | 0.00634097
5598052 | 847.49 | 0.159748 | 0.312296 | 0.00610192
5598058 | 796.372 | 0.150547 | 0.293894 | 0.00573388
5637605 | 876.304 | 0.164935 | 0.322669 | 0.00630939
5637611 | 1943 | 0.35694 | 0.69948 | 0.0139896
5637616 | 876.268 | 0.164928 | 0.322657 | 0.00630913
5638067 | 1834 | 0.33732 | 0.67464 | 0.0132048
5649328 | 959.964 | 0.179994 | 0.359987 | 0.00691174
5649486 | 959.964 | 0.179994 | 0.359987 | 0.00691174
5837565 | 989.994 | 0.185399 | 0.363598 | 0.00712795
5837583 | 990.006 | 0.185401 | 0.363602 | 0.00712805
5837727 | 989.994 | 0.185399 | 0.363598 | 0.00712795
5837745 | 990.006 | 0.185401 | 0.363602 | 0.00712805
5903068 | 659.961 | 0.125993 | 0.244786 | 0.00475172
5903086 | 660.039 | 0.126007 | 0.244814 | 0.00475228
6988578 | 1034 | 0.19332 | 0.38664 | 0.0074448
7759059 | 277.148 | 0.0570867 | 0.106973 | 0.00199547
12606027 | 986 | 0.18468 | 0.35496 | 0.0070992
12606117 | 358.175 | 0.0716716 | 0.136143 | 0.00257886
10238748 | 736 | 0.13968 | 0.27936 | 0.0052992

# IfcMember: Rectangular Mullion:67x114 (262)
In: 00 begane grond
Type - PredefinedType: MULLION; Material: NLRS_i3_hout_Loofhout (hardhout) RAL 9002
Type - Pset_MemberCommon - IsExternal: no; Reference: Rectangular Mullion:67x114
Type - Pset_ProductRequirements - Category: Curtain Wall Mullions
Type - Pset_QuantityTakeOff - Reference: Rectangular Mullion:67x114
Classification: 31.0 (Uniformat)
Pset_MemberCommon - IsExternal: yes
Name (Rectangular Mullion:67x114:...) | Span (mm) = Length (mm) | CrossSectionArea (m2) | NetSurfaceArea (m2) | NetVolume (m3)
2856749 | 389.5 | 0.0781375 | 0.156275 | 0.002975
2856750 | 953 | 0.180131 | 0.352624 | 0.00727901
2856751 | 653 | 0.125831 | 0.244024 | 0.00498761
2856752 | 348.974 | 0.0708023 | 0.133967 | 0.00266546
2857108 | 986.5 | 0.186195 | 0.372389 | 0.00753489
2857109 | 490 | 0.096328 | 0.185018 | 0.00374262
2857110 | 653 | 0.125831 | 0.244024 | 0.00498761
3425246 | 415.974 | 0.0829293 | 0.158221 | 0.00317721
3425247 | 1441.03 | 0.268464 | 0.521651 | 0.0110066
3425248 | 919.5 | 0.174068 | 0.348135 | 0.00702314
3425250 | 415.974 | 0.0829293 | 0.158221 | 0.00317721
7310945 | 1441.03 | 0.268464 | 0.521651 | 0.0110066
7310946 | 720 | 0.137958 | 0.268278 | 0.00549936
7310948 | 389.5 | 0.0781375 | 0.156275 | 0.002975
7310949 | 1441.03 | 0.268464 | 0.521651 | 0.0110066
2857173 | 399.5 | 0.0799475 | 0.159895 | 0.00305138
2857174 | 951.223 | 0.179809 | 0.351981 | 0.00726544
2857175 | 653 | 0.125831 | 0.244024 | 0.00498761
2857176 | 348.974 | 0.0708023 | 0.133967 | 0.00266546
2857289 | 984.723 | 0.185873 | 0.371746 | 0.00752132
2857290 | 500 | 0.098138 | 0.188638 | 0.003819
2857291 | 653 | 0.125831 | 0.244024 | 0.00498761
3425027 | 415.974 | 0.0829293 | 0.158221 | 0.00317721
3425028 | 1441.03 | 0.268464 | 0.521651 | 0.0110066
3425029 | 917.723 | 0.173746 | 0.347492 | 0.00700957
3425031 | 415.974 | 0.0829293 | 0.158221 | 0.00317721
7311211 | 1441.03 | 0.268464 | 0.521651 | 0.0110066
7311212 | 720 | 0.137958 | 0.268278 | 0.00549936
7311214 | 399.5 | 0.0799475 | 0.159895 | 0.00305138
7311215 | 1441.03 | 0.268464 | 0.521651 | 0.0110066
2980529 | 1691 | 0.313709 | 0.627418 | 0.0129159
2980531 | 2325 | 0.428463 | 0.856926 | 0.0177583
2980532 | 2325 | 0.428463 | 0.856926 | 0.0177583
2980930 | 947.36 | 0.17911 | 0.350582 | 0.00723594
2980931 | 919.304 | 0.174032 | 0.348064 | 0.00702164
2980932 | 621.5 | 0.120129 | 0.232621 | 0.00474702
2980933 | 1944.5 | 0.359593 | 0.711547 | 0.0148521
2981903 | 874.304 | 0.165887 | 0.324136 | 0.00667793
2981967 | 1947 | 0.360045 | 0.704814 | 0.0148712
2981968 | 992.36 | 0.187255 | 0.37451 | 0.00757965
7644449 | 1944.5 | 0.359593 | 0.711547 | 0.0148521
7644450 | 621.5 | 0.120129 | 0.232621 | 0.00474702
3079283 | 688.064 | 0.132177 | 0.256717 | 0.00525543
3079285 | 621.5 | 0.120129 | 0.232621 | 0.00474702
3079286 | 1944.5 | 0.359593 | 0.711547 | 0.0148521
3079518 | 1011.94 | 0.190799 | 0.373959 | 0.00772917
3079519 | 733.064 | 0.140322 | 0.280645 | 0.00559914
7645511 | 1944.5 | 0.359593 | 0.711547 | 0.0148521
7645512 | 688.5 | 0.132256 | 0.256875 | 0.00525876
3103294 | 1990 | 0.367828 | 0.735656 | 0.0151996
3103296 | 2666.5 | 0.490275 | 0.972911 | 0.0203667
3103297 | 1086.5 | 0.204295 | 0.400951 | 0.00829869
5170989 | 1086.5 | 0.204295 | 0.400951 | 0.00829869
5170990 | 2666.5 | 0.490275 | 0.972911 | 0.0203667
5170991 | 1856 | 0.343574 | 0.687148 | 0.0141761
3260283 | 1991 | 0.368009 | 0.736018 | 0.0152073
3260285 | 2325 | 0.428463 | 0.856926 | 0.0177583
3260286 | 2325 | 0.428463 | 0.856926 | 0.0177583
3260367 | 1857 | 0.343755 | 0.68751 | 0.0141838
3260369 | 2700 | 0.496338 | 0.992676 | 0.0206226
3260370 | 2700 | 0.496338 | 0.992676 | 0.0206226
3261842 | 1968.97 | 0.364022 | 0.720407 | 0.015039
3261844 | 2633 | 0.484211 | 0.968422 | 0.0201109
3261845 | 2633 | 0.484211 | 0.968422 | 0.0201109
3311324 | 1968.5 | 0.363937 | 0.720235 | 0.0150354
3424603 | 1062.89 | 0.200022 | 0.400044 | 0.00811839
3424604 | 1062.89 | 0.200022 | 0.400044 | 0.00811839
3424605 | 2094.03 | 0.386657 | 0.765675 | 0.0159942
3424606 | 348.974 | 0.0708023 | 0.133967 | 0.00266546
5722505 | 348.974 | 0.0708023 | 0.133967 | 0.00266546
5722506 | 2094.03 | 0.386657 | 0.765675 | 0.0159942
5722507 | 928.895 | 0.175768 | 0.351536 | 0.0070949
3668609 | 1012 | 0.19081 | 0.373982 | 0.00772966
3668610 | 870 | 0.165108 | 0.322578 | 0.00664506
3668611 | 688.5 | 0.132256 | 0.256875 | 0.00525876
3668612 | 1944.5 | 0.359593 | 0.711547 | 0.0148521
3669645 | 847.575 | 0.161049 | 0.306822 | 0.00647377
3669771 | 870 | 0.165108 | 0.322578 | 0.00664506
3669772 | 892.575 | 0.169194 | 0.33075 | 0.00681748
3669966 | 1944.5 | 0.359593 | 0.711547 | 0.0148521
3669967 | 621.5 | 0.120129 | 0.232621 | 0.00474702
3668916 | 1291.5 | 0.241399 | 0.475161 | 0.00986448
3668918 | 621.5 | 0.120129 | 0.232621 | 0.00474702
3668919 | 1944.5 | 0.359593 | 0.711547 | 0.0148521
3669236 | 1011.94 | 0.190799 | 0.373959 | 0.00772917
3669237 | 1291.5 | 0.241399 | 0.475161 | 0.00986448
3669312 | 1246.5 | 0.233255 | 0.451233 | 0.00952077
3669313 | 1291.5 | 0.241399 | 0.475161 | 0.00986448
3669547 | 1944.5 | 0.359593 | 0.711547 | 0.0148521
3669548 | 688.5 | 0.132256 | 0.256875 | 0.00525876
3720116 | 450 | 0.089088 | 0.178176 | 0.0034371
3720117 | 316 | 0.064834 | 0.129668 | 0.00241361
3720118 | 720 | 0.137958 | 0.268278 | 0.00549936
3720119 | 1790 | 0.331628 | 0.655618 | 0.013672
9723190 | 1790 | 0.331628 | 0.655618 | 0.013672
9723191 | 720 | 0.137958 | 0.268278 | 0.00549936
9723192 | 316 | 0.064834 | 0.129668 | 0.00241361
3720846 | 450 | 0.089088 | 0.178176 | 0.0034371
3720847 | 450 | 0.089088 | 0.178176 | 0.0034371
3720848 | 641.5 | 0.12375 | 0.239861 | 0.00489978
3720849 | 1801.5 | 0.33371 | 0.659781 | 0.0137599
9723239 | 1801.5 | 0.33371 | 0.659781 | 0.0137599
9723240 | 641.5 | 0.12375 | 0.239861 | 0.00489978
3720865 | 450 | 0.089088 | 0.178176 | 0.0034371
3720866 | 383 | 0.076961 | 0.153922 | 0.00292535
3720867 | 653 | 0.125831 | 0.244024 | 0.00498761
3720868 | 1790 | 0.331628 | 0.655618 | 0.013672
9723293 | 1790 | 0.331628 | 0.655618 | 0.013672
9723294 | 720 | 0.137958 | 0.268278 | 0.00549936
9723295 | 316 | 0.064834 | 0.129668 | 0.00241361
3721537 | 2633 | 0.484211 | 0.968422 | 0.0201109
5604578 | 1991 | 0.368009 | 0.736018 | 0.0152073
5604644 | 2633 | 0.484211 | 0.968422 | 0.0201109
3721851 | 1968.97 | 0.364022 | 0.720407 | 0.015039
3721852 | 996.025 | 0.187919 | 0.375837 | 0.00760764
3721853 | 688.5 | 0.132256 | 0.256875 | 0.00525876
3721854 | 1944.5 | 0.359593 | 0.711547 | 0.0148521
4326218 | 951.025 | 0.179774 | 0.351909 | 0.00726393
7644787 | 1944.5 | 0.359593 | 0.711547 | 0.0148521
7644788 | 621.5 | 0.120129 | 0.232621 | 0.00474702
3722664 | 1591 | 0.295609 | 0.591218 | 0.0121521
3722666 | 2195 | 0.404933 | 0.809866 | 0.0167654
3722667 | 2195 | 0.404933 | 0.809866 | 0.0167654
3722997 | 817 | 0.155515 | 0.31103 | 0.00624025
3722999 | 2262 | 0.41706 | 0.83412 | 0.0172772
3723000 | 2195 | 0.404933 | 0.809866 | 0.0167654
11987794 | 85.1741 | 0.0230545 | 0.046109 | 0.00065056
4221988 | 1991 | 0.368009 | 0.736018 | 0.0152073
4221990 | 2633 | 0.484211 | 0.968422 | 0.0201109
4221991 | 2633 | 0.484211 | 0.968422 | 0.0201109
4257203 | 1691 | 0.313709 | 0.627418 | 0.0129159
4257205 | 2633 | 0.484211 | 0.968422 | 0.0201109
4257206 | 2633 | 0.484211 | 0.968422 | 0.0201109
5202861 | 942.603 | 0.178249 | 0.34886 | 0.00719961
5202862 | 790.897 | 0.15079 | 0.301581 | 0.00604087
5202863 | 700 | 0.134338 | 0.261038 | 0.0053466
5202864 | 1933 | 0.357511 | 0.707384 | 0.0147643
5202867 | 757.397 | 0.144727 | 0.281816 | 0.00578499
5202869 | 633 | 0.122211 | 0.236784 | 0.00483485
7645007 | 1933 | 0.357511 | 0.707384 | 0.0147643
7645008 | 633 | 0.122211 | 0.236784 | 0.00483485
7645009 | 656.897 | 0.126536 | 0.253073 | 0.00501738
7645011 | 1933 | 0.357511 | 0.707384 | 0.0147643
5634990 | 900 | 0.170538 | 0.341076 | 0.0068742
5634992 | 2192 | 0.40439 | 0.80878 | 0.0167425
5634993 | 2192 | 0.40439 | 0.80878 | 0.0167425
5762129 | 2557.5 | 0.470546 | 0.933453 | 0.0195342
5762130 | 913 | 0.172891 | 0.338144 | 0.00697349
5762131 | 700 | 0.134338 | 0.261038 | 0.0053466
5762132 | 1933 | 0.357511 | 0.707384 | 0.0147643
5762135 | 879.5 | 0.166827 | 0.318379 | 0.00671762
5762137 | 633 | 0.122211 | 0.236784 | 0.00483485
7643587 | 1933 | 0.357511 | 0.707384 | 0.0147643
7643588 | 633 | 0.122211 | 0.236784 | 0.00483485
7643589 | 846 | 0.160764 | 0.31389 | 0.00646175
7643591 | 1933 | 0.357511 | 0.707384 | 0.0147643
10301941 | 913 | 0.172891 | 0.338144 | 0.00697349
10301942 | 913 | 0.172891 | 0.338144 | 0.00697349
10301943 | 846 | 0.160764 | 0.31389 | 0.00646175
10301944 | 599.5 | 0.116147 | 0.232295 | 0.00457898
5762141 | 2569 | 0.472627 | 0.937616 | 0.019622
5762142 | 902 | 0.1709 | 0.334162 | 0.00688948
5762143 | 688.5 | 0.132256 | 0.256875 | 0.00525876
5762144 | 1944.5 | 0.359593 | 0.711547 | 0.0148521
5762147 | 879 | 0.166737 | 0.318198 | 0.0067138
7643281 | 1944.5 | 0.359593 | 0.711547 | 0.0148521
7643282 | 621.5 | 0.120129 | 0.232621 | 0.00474702
10302094 | 902 | 0.1709 | 0.334162 | 0.00688948
10302095 | 924 | 0.174882 | 0.342126 | 0.00705751
5638066 | 1834.5 | 0.339682 | 0.679365 | 0.0140119
5638068 | 2633 | 0.484211 | 0.968422 | 0.0201109
5882833 | 2633 | 0.484211 | 0.968422 | 0.0201109
5973731 | 1775 | 0.328913 | 0.657826 | 0.0135575
5973733 | 2633 | 0.484211 | 0.968422 | 0.0201109
5973734 | 2633 | 0.484211 | 0.968422 | 0.0201109
6267162 | 1997.95 | 0.369267 | 0.738535 | 0.0152604
6267163 | 1997.95 | 0.369267 | 0.738535 | 0.0152604
6267656 | 1997.95 | 0.369267 | 0.738535 | 0.0152604
6267740 | 1997.95 | 0.369267 | 0.738535 | 0.0152604
7477630 | 992.553 | 0.18729 | 0.37458 | 0.00758112
7477632 | 996.365 | 0.18798 | 0.37596 | 0.00761024
6660028 | 1975 | 0.365113 | 0.730226 | 0.015085
6660030 | 2633 | 0.484211 | 0.968422 | 0.0201109
7701594 | 2633 | 0.484211 | 0.968422 | 0.0201109
7514269 | 1123 | 0.210901 | 0.414164 | 0.00857747
7514271 | 621.5 | 0.120129 | 0.232621 | 0.00474702
7514272 | 1944.5 | 0.359593 | 0.711547 | 0.0148521
7514286 | 1944.5 | 0.359593 | 0.711547 | 0.0148521
7514287 | 688.5 | 0.132256 | 0.256875 | 0.00525876
7768094 | 1012.5 | 0.1909 | 0.374163 | 0.00773347
7768095 | 1146.97 | 0.21524 | 0.422843 | 0.00876059
7768344 | 1101.97 | 0.207095 | 0.398915 | 0.00841688
7768345 | 1123 | 0.210901 | 0.414164 | 0.00857747
7718455 | 1975 | 0.365113 | 0.730226 | 0.015085
7718456 | 2633 | 0.484211 | 0.968422 | 0.0201109
7718457 | 2633 | 0.484211 | 0.968422 | 0.0201109
7718460 | 1908 | 0.352986 | 0.705972 | 0.0145733
7718461 | 2633 | 0.484211 | 0.968422 | 0.0201109
7718462 | 2700 | 0.496338 | 0.992676 | 0.0206226
9801540 | 2156.51 | 0.397966 | 0.795932 | 0.0164714
9244748 | 1974.21 | 0.364969 | 0.7223 | 0.015079
9244749 | 2670 | 0.490908 | 0.981816 | 0.0203935
9244750 | 2670 | 0.490908 | 0.981816 | 0.0203935
9244753 | 1974.97 | 0.365108 | 0.722579 | 0.0150849
9485730 | 1666 | 0.309184 | 0.618368 | 0.0127249
9485731 | 1666 | 0.309184 | 0.618368 | 0.0127249
9485732 | 3245 | 0.594983 | 1.18997 | 0.0247853
9485733 | 3245 | 0.594983 | 1.18997 | 0.0247853
9487587 | 1894.35 | 0.350515 | 0.693392 | 0.014469
9487588 | 1894.35 | 0.350515 | 0.693392 | 0.014469
9487589 | 3111 | 0.570729 | 1.14146 | 0.0237618
9487590 | 3111 | 0.570729 | 1.14146 | 0.0237618
9530500 | 1894.35 | 0.350515 | 0.693392 | 0.014469
9530501 | 1894.35 | 0.350515 | 0.693392 | 0.014469
9488151 | 1666 | 0.309184 | 0.618368 | 0.0127249
9488152 | 1666 | 0.309184 | 0.618368 | 0.0127249
9488153 | 3245 | 0.594983 | 1.18997 | 0.0247853
9488154 | 3245 | 0.594983 | 1.18997 | 0.0247853
10222390 | 899.5 | 0.170448 | 0.340895 | 0.00687038
10222392 | 2700 | 0.496338 | 0.992676 | 0.0206226
10222393 | 2700 | 0.496338 | 0.992676 | 0.0206226
10229153 | 899.5 | 0.170448 | 0.340895 | 0.00687038
10229154 | 2700 | 0.496338 | 0.992676 | 0.0206226
10229155 | 2700 | 0.496338 | 0.992676 | 0.0206226
10229160 | 899.5 | 0.170448 | 0.340895 | 0.00687038
11363913 | 1991 | 0.368009 | 0.736018 | 0.0152073
11363914 | 2633 | 0.484211 | 0.968422 | 0.0201109
11363915 | 2633 | 0.484211 | 0.968422 | 0.0201109
11757025 | 350 | 0.070988 | 0.141976 | 0.0026733
11757026 | 350 | 0.070988 | 0.141976 | 0.0026733
11757027 | 1066.07 | 0.200596 | 0.401193 | 0.00814263
11757028 | 1066 | 0.200584 | 0.401168 | 0.00814211
11757350 | 216 | 0.046734 | 0.093468 | 0.00164981
11757351 | 216 | 0.046734 | 0.093468 | 0.00164981
11757352 | 1200 | 0.224838 | 0.449676 | 0.0091656
11757353 | 1200 | 0.224838 | 0.449676 | 0.0091656
11777787 | 900 | 0.170538 | 0.341076 | 0.0068742
11777788 | 2392 | 0.44059 | 0.88118 | 0.0182701
11777789 | 2392 | 0.44059 | 0.88118 | 0.0182701
11777790 | 900 | 0.170538 | 0.341076 | 0.0068742
11778004 | 1034 | 0.194792 | 0.389584 | 0.00789769
11778005 | 2325 | 0.428463 | 0.856926 | 0.0177583
11778006 | 2325 | 0.428463 | 0.856926 | 0.0177583
11778044 | 900 | 0.170538 | 0.341076 | 0.0068742
11778045 | 2392 | 0.44059 | 0.88118 | 0.0182701
11778046 | 2392 | 0.44059 | 0.88118 | 0.0182701
11778047 | 900 | 0.170538 | 0.341076 | 0.0068742
12734609 | 185.32 | 0.041181 | 0.074724 | 0.00141548
12734611 | 621.5 | 0.120129 | 0.232621 | 0.00474702
12734612 | 1944.5 | 0.359593 | 0.711547 | 0.0148521
12734902 | 1011.94 | 0.190799 | 0.373959 | 0.00772917
12734903 | 297.32 | 0.061453 | 0.122906 | 0.00227093
12738653 | 2011.5 | 0.37172 | 0.735801 | 0.0153638
12738654 | 688.5 | 0.132256 | 0.256875 | 0.00525876
12738030 | 900 | 0.170538 | 0.341076 | 0.0068742
12738031 | 222.78 | 0.0479611 | 0.0959222 | 0.00170159
12738032 | 720 | 0.137958 | 0.268278 | 0.00549936
12738033 | 1913 | 0.353891 | 0.700144 | 0.0146115
12738232 | 199.78 | 0.0437981 | 0.0875962 | 0.00152592
12738760 | 1980 | 0.366018 | 0.724398 | 0.0151232
12738761 | 720 | 0.137958 | 0.268278 | 0.00549936
12738762 | 132.78 | 0.0316711 | 0.0633422 | 0.00101417

# IfcMember: Rectangular Mullion:67x114 Bruin (16)
Type - PredefinedType: MULLION; Material: AL Kozijnhout bruin
Type - Pset_MemberCommon - IsExternal: no; Reference: Rectangular Mullion:67x114 Bruin
Type - Pset_ProductRequirements - Category: Curtain Wall Mullions
Type - Pset_QuantityTakeOff - Reference: Rectangular Mullion:67x114 Bruin
Classification: 31.0 (Uniformat)
Pset_MemberCommon - IsExternal: yes
Name (Rectangular Mullion:67x114 Bruin:...) | In | Span (mm) = Length (mm) | CrossSectionArea (m2) | NetSurfaceArea (m2) | NetVolume (m3)
9319665 | 01 eerste verdieping | 413.937 | 0.0825606 | 0.157483 | 0.00316165
9319666 | 01 eerste verdieping | 413.937 | 0.0825606 | 0.157483 | 0.00316165
9319667 | 01 eerste verdieping | 206.125 | 0.0449467 | 0.0746174 | 0.00157439
9319671 | 01 eerste verdieping | 2303 | 0.424481 | 0.848962 | 0.0175903
9319672 | 01 eerste verdieping | 2303 | 0.424481 | 0.848962 | 0.0175903
9046987 | 01 eerste verdieping | 1033.41 | 0.194685 | 0.38937 | 0.00789318
9046989 | 01 eerste verdieping | 2303 | 0.424481 | 0.848962 | 0.0175903
9046990 | 01 eerste verdieping | 2303 | 0.424481 | 0.848962 | 0.0175903
12231326 | 00 begane grond | 1012 | 0.19081 | 0.38162 | 0.00772966
12231327 | 00 begane grond | 1012 | 0.19081 | 0.38162 | 0.00772966
12231377 | 00 begane grond | 1012 | 0.19081 | 0.38162 | 0.00772966
12231378 | 00 begane grond | 1012 | 0.19081 | 0.38162 | 0.00772966
12231423 | 00 begane grond | 1012 | 0.19081 | 0.38162 | 0.00772966
12231424 | 00 begane grond | 1012 | 0.19081 | 0.38162 | 0.00772966
12231427 | 00 begane grond | 1012 | 0.19081 | 0.38162 | 0.00772966
12231428 | 00 begane grond | 1012 | 0.19081 | 0.38162 | 0.00772966

# IfcMember: Rectangular Mullion:67x114 antraciet (4)
In: 00 begane grond
Type - PredefinedType: MULLION; Material: AL_31_KozijnHout hardhout Antraciet
Type - Pset_MemberCommon - IsExternal: no; Reference: Rectangular Mullion:67x114 antraciet
Type - Pset_ProductRequirements - Category: Curtain Wall Mullions
Type - Pset_QuantityTakeOff - Reference: Rectangular Mullion:67x114 antraciet
Classification: 31.0 (Uniformat)
Pset_MemberCommon - IsExternal: yes
Name (Rectangular Mullion:67x114 antraciet:...) | Span (mm) = Length (mm) | CrossSectionArea (m2) | NetSurfaceArea (m2) | NetVolume (m3)
9282402 | 997.5 | 0.188186 | 0.368733 | 0.0076189
9282404 | 2131.01 | 0.39335 | 0.786701 | 0.0162766
9282405 | 2131.01 | 0.39335 | 0.786701 | 0.0162766
9282408 | 997.5 | 0.188186 | 0.368733 | 0.0076189

# IfcMember: Rectangular Mullion:67x114 zwart (88)
Type - PredefinedType: MULLION; Material: NLRS_i3_hout_Loofhout (hardhout) RAL 9005
Type - Pset_MemberCommon - IsExternal: no; Reference: Rectangular Mullion:67x114 zwart
Type - Pset_ProductRequirements - Category: Curtain Wall Mullions
Type - Pset_QuantityTakeOff - Reference: Rectangular Mullion:67x114 zwart
Classification: 31.0 (Uniformat)
Pset_MemberCommon - IsExternal: yes
Name (Rectangular Mullion:67x114 zwart:...) | In | Span (mm) = Length (mm) | CrossSectionArea (m2) | NetSurfaceArea (m2) | NetVolume (m3)
2858316 | 00 begane grond | 890 | 0.168728 | 0.329818 | 0.00679782
2858317 | 00 begane grond | 453.5 | 0.0897215 | 0.179443 | 0.00346383
2858318 | 00 begane grond | 791.333 | 0.150869 | 0.294101 | 0.0060442
2858319 | 00 begane grond | 791.333 | 0.150869 | 0.294101 | 0.0060442
2858533 | 00 begane grond | 420 | 0.083658 | 0.159678 | 0.00320796
2858535 | 00 begane grond | 791.333 | 0.150869 | 0.294101 | 0.0060442
2858581 | 00 begane grond | 999.238 | 0.1885 | 0.361724 | 0.00763218
2858582 | 00 begane grond | 923.5 | 0.174791 | 0.349583 | 0.00705369
2858583 | 00 begane grond | 791.333 | 0.150869 | 0.294101 | 0.0060442
2865552 | 00 begane grond | 791.333 | 0.150869 | 0.294101 | 0.0060442
2865553 | 00 begane grond | 858.333 | 0.162996 | 0.310717 | 0.00655595
2865556 | 00 begane grond | 789.5 | 0.150537 | 0.301075 | 0.0060302
2865557 | 00 begane grond | 791.333 | 0.150869 | 0.294101 | 0.0060442
2865558 | 00 begane grond | 791.333 | 0.150869 | 0.294101 | 0.0060442
2865804 | 00 begane grond | 858.333 | 0.162996 | 0.310717 | 0.00655595
2865805 | 00 begane grond | 791.333 | 0.150869 | 0.294101 | 0.0060442
2865808 | 00 begane grond | 789.5 | 0.150537 | 0.301075 | 0.0060302
2865809 | 00 begane grond | 858.333 | 0.162996 | 0.310717 | 0.00655595
2865810 | 00 begane grond | 858.333 | 0.162996 | 0.310717 | 0.00655595
2866802 | 00 begane grond | 900 | 0.170538 | 0.341076 | 0.0068742
2866804 | 00 begane grond | 2188.56 | 0.403768 | 0.807536 | 0.0167163
2866805 | 00 begane grond | 2188.56 | 0.403768 | 0.807536 | 0.0167163
2891821 | 01 eerste verdieping | 813 | 0.154791 | 0.301944 | 0.00620969
2891822 | 01 eerste verdieping | 801.693 | 0.152744 | 0.297851 | 0.00612333
2891823 | 01 eerste verdieping | 822.972 | 0.156596 | 0.305554 | 0.00628586
2891824 | 01 eerste verdieping | 802.972 | 0.152976 | 0.298314 | 0.0061331
2892286 | 01 eerste verdieping | 869.972 | 0.165103 | 0.322568 | 0.00664485
2892287 | 01 eerste verdieping | 889.972 | 0.168723 | 0.329808 | 0.00679761
2892288 | 01 eerste verdieping | 768.193 | 0.146681 | 0.293362 | 0.00586746
2892390 | 01 eerste verdieping | 880 | 0.166918 | 0.31856 | 0.00672144
2892391 | 01 eerste verdieping | 880 | 0.166918 | 0.326198 | 0.00672144
2892392 | 01 eerste verdieping | 779.5 | 0.148728 | 0.297455 | 0.00595382
2892393 | 01 eerste verdieping | 822.972 | 0.156596 | 0.305554 | 0.00628586
2892394 | 01 eerste verdieping | 802.972 | 0.152976 | 0.298314 | 0.0061331
2892441 | 01 eerste verdieping | 920 | 0.174158 | 0.33304 | 0.00702696
2892442 | 01 eerste verdieping | 880 | 0.166918 | 0.31856 | 0.00672144
2892443 | 01 eerste verdieping | 813 | 0.154791 | 0.309582 | 0.00620969
2892444 | 01 eerste verdieping | 822.972 | 0.156596 | 0.305554 | 0.00628586
2892445 | 01 eerste verdieping | 802.972 | 0.152976 | 0.298314 | 0.0061331
2892499 | 01 eerste verdieping | 880 | 0.166918 | 0.31856 | 0.00672144
2892500 | 01 eerste verdieping | 920 | 0.174158 | 0.33304 | 0.00702696
2892502 | 01 eerste verdieping | 822.972 | 0.156596 | 0.305554 | 0.00628586
2892503 | 01 eerste verdieping | 802.972 | 0.152976 | 0.298314 | 0.0061331
2892553 | 01 eerste verdieping | 880 | 0.166918 | 0.31856 | 0.00672144
2892554 | 01 eerste verdieping | 880 | 0.166918 | 0.31856 | 0.00672144
2892555 | 01 eerste verdieping | 813 | 0.154791 | 0.309582 | 0.00620969
2892556 | 01 eerste verdieping | 822.972 | 0.156596 | 0.305554 | 0.00628586
2892557 | 01 eerste verdieping | 802.972 | 0.152976 | 0.298314 | 0.0061331
2892590 | 01 eerste verdieping | 940 | 0.177778 | 0.34028 | 0.00717972
2892591 | 01 eerste verdieping | 880 | 0.166918 | 0.31856 | 0.00672144
2892592 | 01 eerste verdieping | 813 | 0.154791 | 0.309582 | 0.00620969
2892593 | 01 eerste verdieping | 822.972 | 0.156596 | 0.305554 | 0.00628586
2892594 | 01 eerste verdieping | 802.972 | 0.152976 | 0.298314 | 0.0061331
2892633 | 01 eerste verdieping | 880 | 0.166918 | 0.31856 | 0.00672144
2892634 | 01 eerste verdieping | 940 | 0.177778 | 0.34028 | 0.00717972
2892636 | 01 eerste verdieping | 822.972 | 0.156596 | 0.305554 | 0.00628586
2892637 | 01 eerste verdieping | 802.972 | 0.152976 | 0.298314 | 0.0061331
2892683 | 01 eerste verdieping | 880 | 0.166918 | 0.31856 | 0.00672144
2892684 | 01 eerste verdieping | 880 | 0.166918 | 0.31856 | 0.00672144
2892685 | 01 eerste verdieping | 813 | 0.154791 | 0.309582 | 0.00620969
2892686 | 01 eerste verdieping | 822.972 | 0.156596 | 0.305554 | 0.00628586
2892687 | 01 eerste verdieping | 802.972 | 0.152976 | 0.298314 | 0.0061331
2892724 | 01 eerste verdieping | 891.693 | 0.169034 | 0.322793 | 0.00681075
2892725 | 01 eerste verdieping | 880 | 0.166918 | 0.31856 | 0.00672144
2892726 | 01 eerste verdieping | 813 | 0.154791 | 0.309582 | 0.00620969
2892727 | 01 eerste verdieping | 822.972 | 0.156596 | 0.305554 | 0.00628586
2892728 | 01 eerste verdieping | 802.972 | 0.152976 | 0.298314 | 0.0061331
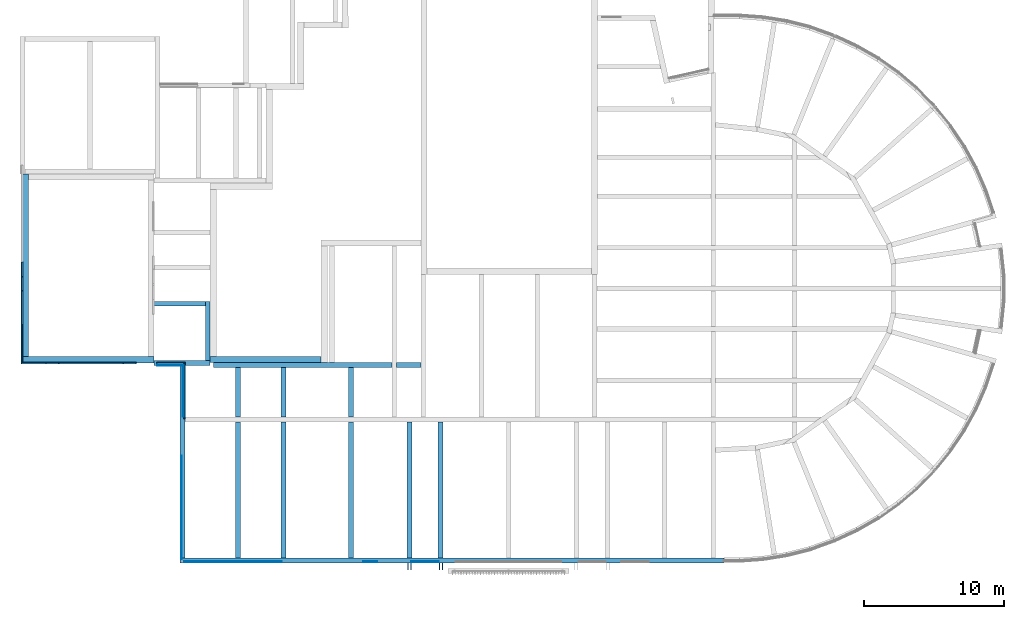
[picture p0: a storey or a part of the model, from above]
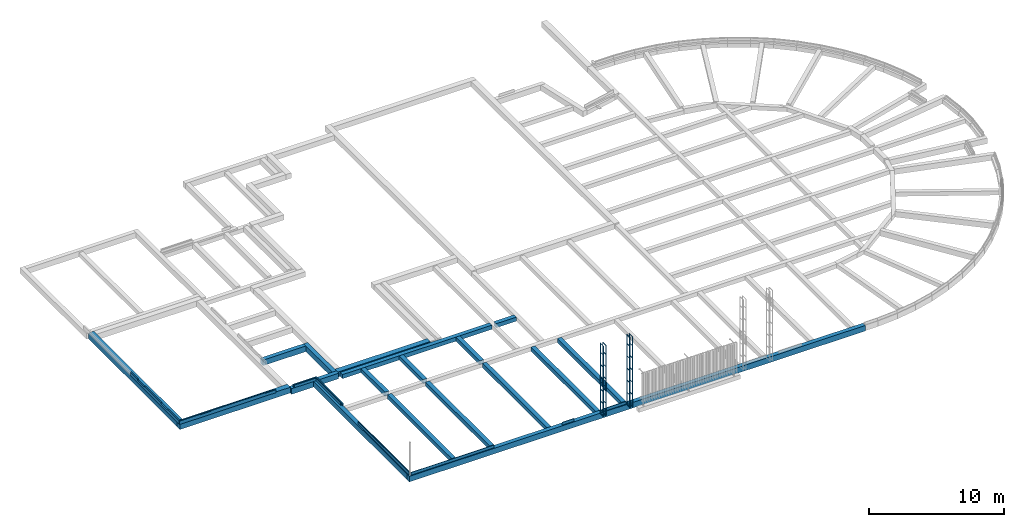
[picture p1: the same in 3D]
Properties of the parts of a building model (IFC2X3), part 5 of 13

# IfcMember: Rectangular Mullion:67x114 zwart (88)
Name (Rectangular Mullion:67x114 zwart:...) | In | Span (mm) = Length (mm) | CrossSectionArea (m2) | NetSurfaceArea (m2) | NetVolume (m3)
2892791 | 01 eerste verdieping | 914.693 | 0.173197 | 0.331119 | 0.00698642
2892792 | 01 eerste verdieping | 891.693 | 0.169034 | 0.322793 | 0.00681075
2892794 | 01 eerste verdieping | 822.972 | 0.156596 | 0.305554 | 0.00628586
2892795 | 01 eerste verdieping | 802.972 | 0.152976 | 0.298314 | 0.0061331
2892842 | 01 eerste verdieping | 868.693 | 0.164871 | 0.322105 | 0.00663508
2892843 | 01 eerste verdieping | 914.693 | 0.173197 | 0.331119 | 0.00698642
2892844 | 01 eerste verdieping | 847.693 | 0.16107 | 0.322141 | 0.00647468
2892845 | 01 eerste verdieping | 822.972 | 0.156596 | 0.305554 | 0.00628586
2892846 | 01 eerste verdieping | 802.972 | 0.152976 | 0.298314 | 0.0061331
3105533 | 00 begane grond | 1690 | 0.313528 | 0.627056 | 0.0129082
3105535 | 00 begane grond | 2325 | 0.428463 | 0.856926 | 0.0177583
3105536 | 00 begane grond | 2325 | 0.428463 | 0.856926 | 0.0177583
3105698 | 00 begane grond | 1690 | 0.313528 | 0.627056 | 0.0129082
3105700 | 00 begane grond | 2325 | 0.428463 | 0.856926 | 0.0177583
3105701 | 00 begane grond | 2325 | 0.428463 | 0.856926 | 0.0177583
3105745 | 00 begane grond | 1690 | 0.313528 | 0.627056 | 0.0129082
3105747 | 00 begane grond | 2325 | 0.428463 | 0.856926 | 0.0177583
3105748 | 00 begane grond | 2325 | 0.428463 | 0.856926 | 0.0177583
3650435 | 00 begane grond | 1034 | 0.194792 | 0.389584 | 0.00789768
3650437 | 00 begane grond | 2341 | 0.431359 | 0.862718 | 0.0178806
3650438 | 00 begane grond | 2341 | 0.431359 | 0.862718 | 0.0178806

# IfcMember: Rectangular Mullion:67x158 (21)
In: 00 begane grond
Type - PredefinedType: MULLION; Material: NLRS_i3_hout_Loofhout (hardhout) RAL 9002
Type - Pset_MemberCommon - IsExternal: no; Reference: Rectangular Mullion:67x158
Type - Pset_ProductRequirements - Category: Curtain Wall Mullions
Type - Pset_QuantityTakeOff - Reference: Rectangular Mullion:67x158
Classification: 31.0 (Uniformat)
Pset_MemberCommon - IsExternal: yes
Name (Rectangular Mullion:67x158:...) | Span (mm) = Length (mm) | CrossSectionArea (m2) | NetSurfaceArea (m2) | NetVolume (m3)
3006416 | 2633 | 0.603011 | 1.20602 | 0.0278729
7628767 | 5060 | 1.14909 | 2.29817 | 0.0535652
5587932 | 3433 | 0.783011 | 1.56602 | 0.0363417
5587934 | 2770 | 0.633836 | 1.26767 | 0.0293232
7626444 | 3880 | 0.883586 | 1.76717 | 0.0410737
7626445 | 2633 | 0.603011 | 1.20602 | 0.0278729
7626449 | 2633 | 0.603011 | 1.20602 | 0.0278729
7741308 | 2633 | 0.603011 | 1.20602 | 0.0278729
7962711 | 5060 | 1.14909 | 2.29817 | 0.0535652
7632404 | 2633 | 0.603011 | 1.20602 | 0.0278729
7632405 | 5060 | 1.14909 | 2.29817 | 0.0535652
7634413 | 2633 | 0.603011 | 1.20602 | 0.0278729
7634415 | 5060 | 1.14909 | 2.29817 | 0.0535652
7634416 | 2633 | 0.603011 | 1.20602 | 0.0278729
7635239 | 2633 | 0.603011 | 1.20602 | 0.0278729
7635241 | 2896.21 | 0.662234 | 1.32447 | 0.0306593
8179647 | 2600 | 0.595586 | 1.19117 | 0.0275236
8179649 | 2633 | 0.603011 | 1.20602 | 0.0278729
8179650 | 2633 | 0.603011 | 1.20602 | 0.0278729
11895757 | 900 | 0.213086 | 0.426172 | 0.0095274
11895759 | 2700 | 0.618086 | 1.23617 | 0.0285822

# IfcMember: Rectangular Mullion:70x158 (8)
In: 00 begane grond
Type - PredefinedType: MULLION; Material: NLRS_i3_hout_Loofhout (hardhout) RAL 9002
Type - Pset_MemberCommon - IsExternal: no; Reference: Rectangular Mullion:70x158
Type - Pset_ProductRequirements - Category: Curtain Wall Mullions
Type - Pset_QuantityTakeOff - Reference: Rectangular Mullion:70x158
Classification: 31.0 (Uniformat)
Pset_MemberCommon - IsExternal: yes
Name (Rectangular Mullion:70x158:...) | Span (mm) = Length (mm) | CrossSectionArea (m2) | NetSurfaceArea (m2) | NetVolume (m3)
7629317 | 5060 | 1.16474 | 2.32948 | 0.0559636
10223748 | 3433 | 0.793784 | 1.58757 | 0.037969
7626450 | 3880 | 0.8957 | 1.7914 | 0.0429128
8573793 | 5060 | 1.16474 | 2.32948 | 0.0559636
7632407 | 5060 | 1.16474 | 2.32948 | 0.0559636
7634575 | 5060 | 1.16474 | 2.32948 | 0.0559636
7635570 | 2896.21 | 0.671397 | 1.34279 | 0.0320321
8179648 | 2600 | 0.60386 | 1.20772 | 0.028756

# IfcMember: Rectangular Mullion:70x84 (18)
In: 00 begane grond
Type - PredefinedType: MULLION; Material: NLRS_i3_hout_Loofhout (hardhout) RAL 9002
Type - Pset_MemberCommon - IsExternal: no; Reference: Rectangular Mullion:70x84
Type - Pset_ProductRequirements - Category: Curtain Wall Mullions
Type - Pset_QuantityTakeOff - Reference: Rectangular Mullion:70x84
Classification: 31.0 (Uniformat)
Pset_MemberCommon - IsExternal: yes
Name (Rectangular Mullion:70x84:...) | Span (mm) = Length (mm) | CrossSectionArea (m2) | NetSurfaceArea (m2) | NetVolume (m3)
4285056 | 897.5 | 0.144095 | 0.28231 | 0.0052773
12116017 | 827.5 | 0.133315 | 0.25487 | 0.0048657
12116109 | 897.5 | 0.144095 | 0.28231 | 0.0052773
12116234 | 827.5 | 0.133315 | 0.25487 | 0.0048657
12121215 | 2508 | 0.392112 | 0.784224 | 0.014747
12121220 | 2508 | 0.392112 | 0.784224 | 0.014747
9558937 | 862.5 | 0.138705 | 0.27153 | 0.0050715
12117566 | 862.5 | 0.138705 | 0.26565 | 0.0050715
12117645 | 862.5 | 0.138705 | 0.27153 | 0.0050715
12117735 | 862.5 | 0.138705 | 0.26565 | 0.0050715
12203949 | 2508 | 0.392112 | 0.784224 | 0.014747
12203954 | 2508 | 0.392112 | 0.784224 | 0.014747
12122990 | 848.5 | 0.136549 | 0.267218 | 0.00498918
12122994 | 779 | 0.125846 | 0.239932 | 0.00458052
12122998 | 779 | 0.125846 | 0.239932 | 0.00458052
12123002 | 848.5 | 0.136549 | 0.267218 | 0.00498918
12123004 | 2608 | 0.407512 | 0.815024 | 0.015335
12123005 | 2608 | 0.407512 | 0.815024 | 0.015335

# IfcMember: Rectangular Mullion:81x120 (502)
Type - PredefinedType: MULLION; Material: n6_kunststof_RAL 7035
Type - Pset_MemberCommon - IsExternal: no; Reference: Rectangular Mullion:81x120
Type - Pset_ProductRequirements - Category: Curtain Wall Mullions
Type - Pset_QuantityTakeOff - Reference: Rectangular Mullion:81x120
Classification: 31.0 (Uniformat)
Pset_MemberCommon - IsExternal: yes
Name (Rectangular Mullion:81x120:...) | In | Span (mm) = Length (mm) | CrossSectionArea (m2) | NetSurfaceArea (m2) | NetVolume (m3)
3004381 | 00 begane grond | 488.402 | 0.107889 | 0.206058 | 0.00474727
3004383 | 00 begane grond | 672 | 0.144792 | 0.279864 | 0.00653184
3004384 | 00 begane grond | 206 | 0.051126 | 0.092532 | 0.00200232
3029715 | 00 begane grond | 488.598 | 0.107928 | 0.206136 | 0.00474917
3029809 | 00 begane grond | 1943 | 0.400263 | 0.781086 | 0.018886
3137499 | 00 begane grond | 1721 | 0.355641 | 0.691842 | 0.0167281
3137500 | 00 begane grond | 672 | 0.144792 | 0.279864 | 0.00653184
12812930 | 00 begane grond | 206 | 0.051126 | 0.092532 | 0.00200232
12812931 | 00 begane grond | 1721 | 0.355641 | 0.691842 | 0.0167281
3019238 | 00 begane grond | 842.5 | 0.179063 | 0.348405 | 0.0081891
3019240 | 00 begane grond | 680 | 0.1464 | 0.28308 | 0.0066096
3019241 | 00 begane grond | 1919 | 0.395439 | 0.781158 | 0.0186527
3039434 | 00 begane grond | 840.077 | 0.178575 | 0.347431 | 0.00816555
3039436 | 00 begane grond | 639.5 | 0.138259 | 0.276519 | 0.00621594
3040849 | 00 begane grond | 1919 | 0.395439 | 0.781158 | 0.0186527
3040850 | 00 begane grond | 680 | 0.1464 | 0.28308 | 0.0066096
3040851 | 00 begane grond | 759.077 | 0.162294 | 0.314869 | 0.00737823
3040853 | 00 begane grond | 761.5 | 0.162782 | 0.315843 | 0.00740178
3019455 | 00 begane grond | 842.5 | 0.179063 | 0.348405 | 0.0081891
3019457 | 00 begane grond | 680 | 0.1464 | 0.28308 | 0.0066096
3019458 | 00 begane grond | 1919 | 0.395439 | 0.781158 | 0.0186527
3039660 | 00 begane grond | 842.5 | 0.179063 | 0.348405 | 0.0081891
3039662 | 00 begane grond | 639.5 | 0.138259 | 0.276519 | 0.00621594
3040939 | 00 begane grond | 1919 | 0.395439 | 0.781158 | 0.0186527
3040940 | 00 begane grond | 680 | 0.1464 | 0.28308 | 0.0066096
3040941 | 00 begane grond | 761.5 | 0.162781 | 0.315843 | 0.00740178
3040943 | 00 begane grond | 761.5 | 0.162782 | 0.315843 | 0.00740178
3019653 | 00 begane grond | 1599 | 0.331119 | 0.662238 | 0.0155423
3019879 | 00 begane grond | 842.5 | 0.179063 | 0.348405 | 0.0081891
3019881 | 00 begane grond | 680 | 0.1464 | 0.28308 | 0.0066096
3019882 | 00 begane grond | 1919 | 0.395439 | 0.781158 | 0.0186527
3039892 | 00 begane grond | 842.5 | 0.179063 | 0.348405 | 0.0081891
3039894 | 00 begane grond | 639.5 | 0.138259 | 0.276519 | 0.00621594
3041055 | 00 begane grond | 1919 | 0.395439 | 0.781158 | 0.0186527
3041056 | 00 begane grond | 680 | 0.1464 | 0.28308 | 0.0066096
3041057 | 00 begane grond | 761.5 | 0.162781 | 0.315843 | 0.00740178
3041059 | 00 begane grond | 761.5 | 0.162782 | 0.315843 | 0.00740178
3020068 | 00 begane grond | 851.263 | 0.180824 | 0.351928 | 0.00827428
3020070 | 00 begane grond | 680 | 0.1464 | 0.28308 | 0.0066096
3020071 | 00 begane grond | 1919 | 0.395439 | 0.781158 | 0.0186527
3040114 | 00 begane grond | 842.5 | 0.179063 | 0.348405 | 0.0081891
3040116 | 00 begane grond | 639.5 | 0.138259 | 0.276519 | 0.00621594
3041145 | 00 begane grond | 1919 | 0.395439 | 0.781158 | 0.0186527
3041146 | 00 begane grond | 680 | 0.1464 | 0.28308 | 0.0066096
3041147 | 00 begane grond | 761.5 | 0.162781 | 0.315843 | 0.00740178
3041149 | 00 begane grond | 770.263 | 0.164543 | 0.319366 | 0.00748696
3020235 | 00 begane grond | 844.239 | 0.179412 | 0.349104 | 0.008206
3020237 | 00 begane grond | 680 | 0.1464 | 0.28308 | 0.0066096
3020238 | 00 begane grond | 1919 | 0.395439 | 0.781158 | 0.0186527
3041966 | 00 begane grond | 838.861 | 0.178331 | 0.346942 | 0.00815373
3041968 | 00 begane grond | 639.5 | 0.138259 | 0.276519 | 0.00621594
3042993 | 00 begane grond | 1919 | 0.395439 | 0.781158 | 0.0186527
3042994 | 00 begane grond | 680 | 0.1464 | 0.28308 | 0.0066096
3042995 | 00 begane grond | 757.861 | 0.16205 | 0.31438 | 0.00736641
3042997 | 00 begane grond | 763.239 | 0.163131 | 0.316542 | 0.00741868
3020401 | 00 begane grond | 833.486 | 0.177251 | 0.344782 | 0.00810149
3020403 | 00 begane grond | 680 | 0.1464 | 0.28308 | 0.0066096
3020404 | 00 begane grond | 1919 | 0.395439 | 0.781158 | 0.0186527
3042200 | 00 begane grond | 833.486 | 0.177251 | 0.344782 | 0.00810149
3042202 | 00 begane grond | 639.5 | 0.138259 | 0.276519 | 0.00621594
3043084 | 00 begane grond | 1919 | 0.395439 | 0.781158 | 0.0186527
3043085 | 00 begane grond | 680 | 0.1464 | 0.28308 | 0.0066096
3043086 | 00 begane grond | 752.486 | 0.16097 | 0.31222 | 0.00731417
3043088 | 00 begane grond | 752.486 | 0.16097 | 0.31222 | 0.00731417
3020544 | 00 begane grond | 1583.37 | 0.327978 | 0.655956 | 0.0153904
3020689 | 00 begane grond | 834.687 | 0.177492 | 0.345264 | 0.00811316
3020691 | 00 begane grond | 680 | 0.1464 | 0.28308 | 0.0066096
3020692 | 00 begane grond | 1919 | 0.395439 | 0.781158 | 0.0186527
3042448 | 00 begane grond | 833.313 | 0.177216 | 0.344712 | 0.0080998
3042450 | 00 begane grond | 639.5 | 0.138259 | 0.276519 | 0.00621594
3043171 | 00 begane grond | 1919 | 0.395439 | 0.781158 | 0.0186527
3043172 | 00 begane grond | 680 | 0.1464 | 0.28308 | 0.0066096
3043173 | 00 begane grond | 752.313 | 0.160935 | 0.31215 | 0.00731248
3043175 | 00 begane grond | 753.687 | 0.161211 | 0.312702 | 0.00732584
3020867 | 00 begane grond | 1051.07 | 0.220985 | 0.441969 | 0.0102164
3020869 | 00 begane grond | 672 | 0.144792 | 0.279864 | 0.00653184
3020870 | 00 begane grond | 1927 | 0.397047 | 0.784374 | 0.0187304
3043264 | 00 begane grond | 1927 | 0.397047 | 0.784374 | 0.0187304
3043265 | 00 begane grond | 672 | 0.144792 | 0.279864 | 0.00653184
3025921 | 00 begane grond | 785.058 | 0.167517 | 0.335033 | 0.00763077
3025923 | 00 begane grond | 680 | 0.1464 | 0.28308 | 0.0066096
3025924 | 00 begane grond | 206 | 0.051126 | 0.092532 | 0.00200232
3037852 | 00 begane grond | 957.942 | 0.202266 | 0.404533 | 0.00931119
3038146 | 00 begane grond | 1713 | 0.354033 | 0.688626 | 0.0166504
3038147 | 00 begane grond | 680 | 0.1464 | 0.28308 | 0.0066096
3038150 | 00 begane grond | 785.058 | 0.167517 | 0.335033 | 0.00763077
12819078 | 00 begane grond | 287 | 0.067407 | 0.125094 | 0.00278964
12819079 | 00 begane grond | 1713 | 0.354033 | 0.688626 | 0.0166504
3036830 | 00 begane grond | 354.336 | 0.0809416 | 0.152163 | 0.00344415
3036832 | 00 begane grond | 672 | 0.144792 | 0.279864 | 0.00653184
3036833 | 00 begane grond | 766 | 0.163686 | 0.317652 | 0.00744552
5719171 | 00 begane grond | 766 | 0.163686 | 0.317652 | 0.00744552
5719172 | 00 begane grond | 1721 | 0.355641 | 0.691842 | 0.0167281
12606266 | 00 begane grond | 986 | 0.207906 | 0.396372 | 0.00958392
12606337 | 00 begane grond | 350.04 | 0.0800781 | 0.150436 | 0.00340239
12606860 | 00 begane grond | 1721 | 0.355641 | 0.691842 | 0.0167281
12606861 | 00 begane grond | 732 | 0.156852 | 0.303984 | 0.00711504
3131750 | 00 begane grond | 967.9 | 0.204268 | 0.398816 | 0.00940799
3131752 | 00 begane grond | 672 | 0.144792 | 0.279864 | 0.00653184
3131753 | 00 begane grond | 1927 | 0.397047 | 0.784374 | 0.0187304
3131870 | 00 begane grond | 910.751 | 0.192781 | 0.366122 | 0.0088525
3132017 | 00 begane grond | 929.916 | 0.196633 | 0.373826 | 0.00903878
3132239 | 00 begane grond | 1927 | 0.397047 | 0.784374 | 0.0187304
3132240 | 00 begane grond | 672 | 0.144792 | 0.279864 | 0.00653184
3132371 | 00 begane grond | 968.054 | 0.204299 | 0.398878 | 0.00940948
3132413 | 00 begane grond | 930.07 | 0.196664 | 0.373888 | 0.00904028
3132451 | 00 begane grond | 910.939 | 0.192819 | 0.366197 | 0.00885433
3132485 | 00 begane grond | 930.07 | 0.196664 | 0.373888 | 0.00904028
3132649 | 00 begane grond | 929.916 | 0.196633 | 0.373826 | 0.00903878
7492562 | 00 begane grond | 45 | 0.018765 | 0.01809 | 0.0004374
3136059 | 00 begane grond | 440 | 0.09816 | 0.19632 | 0.0042768
3136060 | 00 begane grond | 440 | 0.09816 | 0.19632 | 0.0042768
3136061 | 00 begane grond | 1077 | 0.226197 | 0.452394 | 0.0104684
3136062 | 00 begane grond | 1077 | 0.226197 | 0.452394 | 0.0104684
3136071 | 00 begane grond | 440 | 0.09816 | 0.19632 | 0.0042768
3136072 | 00 begane grond | 440 | 0.09816 | 0.19632 | 0.0042768
3136073 | 00 begane grond | 1077 | 0.226197 | 0.452394 | 0.0104684
3136074 | 00 begane grond | 1077 | 0.226197 | 0.452394 | 0.0104684
3216648 | 00 begane grond | 440 | 0.09816 | 0.19632 | 0.0042768
3216649 | 00 begane grond | 440 | 0.09816 | 0.19632 | 0.0042768
3216650 | 00 begane grond | 1077 | 0.226197 | 0.452394 | 0.0104684
3216651 | 00 begane grond | 1077 | 0.226197 | 0.452394 | 0.0104684
3216984 | 00 begane grond | 440 | 0.09816 | 0.19632 | 0.0042768
3216985 | 00 begane grond | 440 | 0.09816 | 0.19632 | 0.0042768
3216986 | 00 begane grond | 1077 | 0.226197 | 0.452394 | 0.0104684
3216987 | 00 begane grond | 1077 | 0.226197 | 0.452394 | 0.0104684
3217029 | 00 begane grond | 440 | 0.09816 | 0.19632 | 0.0042768
3217030 | 00 begane grond | 440 | 0.09816 | 0.19632 | 0.0042768
3217031 | 00 begane grond | 1077 | 0.226197 | 0.452394 | 0.0104684
3217032 | 00 begane grond | 1077 | 0.226197 | 0.452394 | 0.0104684
4093378 | 00 begane grond | 1980 | 0.4077 | 0.8154 | 0.0192456
4200607 | 00 begane grond | 1985.97 | 0.408901 | 0.808082 | 0.0193037
4200610 | 00 begane grond | 206 | 0.051126 | 0.092532 | 0.00200232
4200631 | 00 begane grond | 672.451 | 0.144883 | 0.280045 | 0.00653622
4200647 | 00 begane grond | 760.322 | 0.162545 | 0.30565 | 0.00739033
4200652 | 00 begane grond | 1985.76 | 0.408857 | 0.807994 | 0.0193015
7508913 | 00 begane grond | 758.855 | 0.16225 | 0.30506 | 0.00737607
7508977 | 00 begane grond | 672.451 | 0.144883 | 0.280045 | 0.00653622
7508978 | 00 begane grond | 1720.55 | 0.35555 | 0.691661 | 0.0167237
9428017 | 00 begane grond | 798.355 | 0.170189 | 0.330659 | 0.00776001
9428161 | 00 begane grond | 797.922 | 0.170102 | 0.330485 | 0.0077558
12815832 | 00 begane grond | 1720.55 | 0.35555 | 0.691661 | 0.0167237
12815842 | 00 begane grond | 206 | 0.051126 | 0.092532 | 0.00200232
4201026 | 00 begane grond | 672 | 0.144792 | 0.279864 | 0.00653184
4201027 | 00 begane grond | 2398.08 | 0.483936 | 0.958152 | 0.0227674
4201030 | 00 begane grond | 672 | 0.144792 | 0.279864 | 0.00653184
4201043 | 00 begane grond | 1927.5 | 0.397148 | 0.784575 | 0.0187353
4201044 | 00 begane grond | 672 | 0.144792 | 0.279864 | 0.00653184
4201048 | 00 begane grond | 1968 | 0.405288 | 0.791136 | 0.019129
4201094 | 00 begane grond | 1968 | 0.405288 | 0.791136 | 0.019129
4201095 | 00 begane grond | 876.545 | 0.185906 | 0.362091 | 0.00852002
4201096 | 00 begane grond | 876.3 | 0.185856 | 0.361993 | 0.00851764
4201097 | 00 begane grond | 876.1 | 0.185816 | 0.361912 | 0.00851569
4201099 | 00 begane grond | 875.9 | 0.185776 | 0.361832 | 0.00851375
4201100 | 00 begane grond | 957.452 | 0.202168 | 0.394616 | 0.00930643
4201102 | 00 begane grond | 81 | 0.026001 | 0.032562 | 0.00078732
4201120 | 00 begane grond | 876.3 | 0.185856 | 0.361993 | 0.00851764
4201129 | 00 begane grond | 875.9 | 0.185776 | 0.361832 | 0.00851375
7496946 | 00 begane grond | 876.1 | 0.185816 | 0.361912 | 0.00851569
7496949 | 00 begane grond | 672 | 0.144792 | 0.279864 | 0.00653184
7496950 | 00 begane grond | 1968 | 0.405288 | 0.791136 | 0.019129
7496951 | 00 begane grond | 81 | 0.026001 | 0.032562 | 0.00078732
11898380 | 00 begane grond | 81 | 0.026001 | 0.032562 | 0.00078732
11898382 | 00 begane grond | 1191.51 | 0.249214 | 0.488708 | 0.0115815
11898384 | 00 begane grond | 1165.18 | 0.24392 | 0.478121 | 0.0113255
11898386 | 00 begane grond | 876.545 | 0.185906 | 0.362091 | 0.00852002
11898387 | 00 begane grond | 876.3 | 0.185856 | 0.361993 | 0.00851764
11898388 | 00 begane grond | 876.1 | 0.185816 | 0.361912 | 0.00851569
11898389 | 00 begane grond | 876.3 | 0.185856 | 0.361993 | 0.00851764
11898391 | 00 begane grond | 876.1 | 0.185816 | 0.361912 | 0.00851569
11898392 | 00 begane grond | 875.9 | 0.185776 | 0.361832 | 0.00851375
11898393 | 00 begane grond | 875.9 | 0.185776 | 0.361832 | 0.00851375
11898394 | 00 begane grond | 831.058 | 0.134967 | 0.260213 | 0.00553166
11987790 | 00 begane grond | 1006.89 | 0.204307 | 0.408615 | 0.00924502
11987791 | 00 begane grond | 965.622 | 0.20381 | 0.40762 | 0.00938584
11987792 | 00 begane grond | 965.411 | 0.203768 | 0.407535 | 0.0093838
11987793 | 00 begane grond | 964.15 | 0.203514 | 0.407028 | 0.00937153
11987795 | 00 begane grond | 963.939 | 0.203472 | 0.406944 | 0.00936949
11987796 | 00 begane grond | 965.201 | 0.203725 | 0.407451 | 0.00938175
11987797 | 00 begane grond | 965.201 | 0.203725 | 0.407451 | 0.00938175
11987798 | 00 begane grond | 873.883 | 0.185371 | 0.370741 | 0.00849415
12575163 | 00 begane grond | 132.907 | 0.0364344 | 0.0728688 | 0.00129186
4259320 | 00 begane grond | 440 | 0.09816 | 0.19632 | 0.0042768
4259321 | 00 begane grond | 440 | 0.09816 | 0.19632 | 0.0042768
4259322 | 00 begane grond | 1323 | 0.275643 | 0.551286 | 0.0128596
4259323 | 00 begane grond | 1323 | 0.275643 | 0.551286 | 0.0128596
4259326 | 00 begane grond | 440 | 0.09816 | 0.19632 | 0.0042768
4259327 | 00 begane grond | 440 | 0.09816 | 0.19632 | 0.0042768
4259328 | 00 begane grond | 1323 | 0.275643 | 0.551286 | 0.0128596
4259329 | 00 begane grond | 1323 | 0.275643 | 0.551286 | 0.0128596
4259453 | 00 begane grond | 440 | 0.09816 | 0.19632 | 0.0042768
4259454 | 00 begane grond | 440 | 0.09816 | 0.19632 | 0.0042768
4259455 | 00 begane grond | 1323 | 0.275643 | 0.551286 | 0.0128596
4259456 | 00 begane grond | 1323 | 0.275643 | 0.551286 | 0.0128596
4438365 | 00 begane grond | 3554.25 | 0.724124 | 1.44825 | 0.0345473
4438366 | 00 begane grond | 3554.25 | 0.724124 | 1.44825 | 0.0345473
4438367 | 00 begane grond | 1007 | 0.212127 | 0.424254 | 0.00978804
4438368 | 00 begane grond | 1007 | 0.212127 | 0.424254 | 0.00978804
5203704 | 00 begane grond | 1985.5 | 0.408805 | 0.807891 | 0.0192991
5203707 | 00 begane grond | 206 | 0.051126 | 0.092532 | 0.00200232
5203709 | 00 begane grond | 674.594 | 0.145313 | 0.280907 | 0.00655705
5203716 | 00 begane grond | 671.5 | 0.144692 | 0.279663 | 0.00652698
12812519 | 00 begane grond | 1721.5 | 0.355742 | 0.692043 | 0.016733
5206284 | 00 begane grond | 440 | 0.09816 | 0.19632 | 0.0042768
5206285 | 00 begane grond | 440 | 0.09816 | 0.19632 | 0.0042768
5206286 | 00 begane grond | 1323 | 0.275643 | 0.551286 | 0.0128596
5206287 | 00 begane grond | 1323 | 0.275643 | 0.551286 | 0.0128596
5459101 | 00 begane grond | 834.002 | 0.177354 | 0.344989 | 0.0081065
5459103 | 00 begane grond | 680 | 0.1464 | 0.28308 | 0.0066096
5459104 | 00 begane grond | 1919 | 0.395439 | 0.781158 | 0.0186527
5459125 | 00 begane grond | 1919 | 0.395439 | 0.781158 | 0.0186527
5459126 | 00 begane grond | 680 | 0.1464 | 0.28308 | 0.0066096
5459240 | 00 begane grond | 753.002 | 0.161073 | 0.312427 | 0.00731918
5459507 | 00 begane grond | 834.002 | 0.177354 | 0.344989 | 0.0081065
5459509 | 00 begane grond | 753.002 | 0.161073 | 0.312427 | 0.00731918
5459510 | 00 begane grond | 639.5 | 0.138259 | 0.276519 | 0.00621594
5565099 | 00 begane grond | 842.5 | 0.179063 | 0.348405 | 0.0081891
5565101 | 00 begane grond | 680 | 0.1464 | 0.28308 | 0.0066096
5565102 | 00 begane grond | 1919 | 0.395439 | 0.781158 | 0.0186527
5565129 | 00 begane grond | 852.447 | 0.181062 | 0.352404 | 0.00828579
5565131 | 00 begane grond | 639.5 | 0.138259 | 0.276519 | 0.00621594
5565192 | 00 begane grond | 1919 | 0.395439 | 0.781158 | 0.0186527
5565193 | 00 begane grond | 680 | 0.1464 | 0.28308 | 0.0066096
5565194 | 00 begane grond | 771.447 | 0.164781 | 0.319842 | 0.00749847
5565196 | 00 begane grond | 761.5 | 0.162782 | 0.315843 | 0.00740178
5565105 | 00 begane grond | 842.5 | 0.179063 | 0.348405 | 0.0081891
5565107 | 00 begane grond | 680 | 0.1464 | 0.28308 | 0.0066096
5565108 | 00 begane grond | 1919 | 0.395439 | 0.781158 | 0.0186527
5565144 | 00 begane grond | 842.5 | 0.179062 | 0.348405 | 0.0081891
5565146 | 00 begane grond | 639.5 | 0.138259 | 0.276519 | 0.00621594
5565204 | 00 begane grond | 1919 | 0.395439 | 0.781158 | 0.0186527
5565205 | 00 begane grond | 680 | 0.1464 | 0.28308 | 0.0066096
5565206 | 00 begane grond | 761.5 | 0.162781 | 0.315843 | 0.00740178
5565208 | 00 begane grond | 761.5 | 0.162782 | 0.315843 | 0.00740178
5565111 | 00 begane grond | 1599 | 0.331119 | 0.662238 | 0.0155423
5565117 | 00 begane grond | 842.5 | 0.179063 | 0.348405 | 0.0081891
5565119 | 00 begane grond | 680 | 0.1464 | 0.28308 | 0.0066096
5565120 | 00 begane grond | 1919 | 0.395439 | 0.781158 | 0.0186527
5565159 | 00 begane grond | 842.5 | 0.179062 | 0.348405 | 0.0081891
5565161 | 00 begane grond | 639.5 | 0.138259 | 0.276519 | 0.00621594
5565216 | 00 begane grond | 1919 | 0.395439 | 0.781158 | 0.0186527
5565217 | 00 begane grond | 680 | 0.1464 | 0.28308 | 0.0066096
5565218 | 00 begane grond | 761.5 | 0.162781 | 0.315843 | 0.00740178
5565220 | 00 begane grond | 761.5 | 0.162782 | 0.315843 | 0.00740178
5567080 | 00 begane grond | 844.508 | 0.179466 | 0.349212 | 0.00820862
5567082 | 00 begane grond | 680 | 0.1464 | 0.28308 | 0.0066096
5567083 | 00 begane grond | 1919 | 0.395439 | 0.781158 | 0.0186527
5567110 | 00 begane grond | 841.492 | 0.17886 | 0.348 | 0.0081793
5567112 | 00 begane grond | 639.5 | 0.138259 | 0.276519 | 0.00621594
5567173 | 00 begane grond | 1919 | 0.395439 | 0.781158 | 0.0186527
5567174 | 00 begane grond | 680 | 0.1464 | 0.28308 | 0.0066096
5567175 | 00 begane grond | 760.492 | 0.162579 | 0.315438 | 0.00739198
5567177 | 00 begane grond | 763.508 | 0.163185 | 0.31665 | 0.0074213
5567086 | 00 begane grond | 843 | 0.179163 | 0.348606 | 0.00819396
5567088 | 00 begane grond | 680 | 0.1464 | 0.28308 | 0.0066096
5567089 | 00 begane grond | 1919 | 0.395439 | 0.781158 | 0.0186527
5567125 | 00 begane grond | 843 | 0.179163 | 0.348606 | 0.00819396
5567127 | 00 begane grond | 639.5 | 0.138259 | 0.276519 | 0.00621594
5567185 | 00 begane grond | 1919 | 0.395439 | 0.781158 | 0.0186527
5567186 | 00 begane grond | 680 | 0.1464 | 0.28308 | 0.0066096
5567187 | 00 begane grond | 762 | 0.162882 | 0.316044 | 0.00740664
5567189 | 00 begane grond | 762 | 0.162882 | 0.316044 | 0.00740664
5567092 | 00 begane grond | 1600 | 0.33132 | 0.66264 | 0.015552
5567098 | 00 begane grond | 843 | 0.179163 | 0.348606 | 0.00819396
5567100 | 00 begane grond | 680 | 0.1464 | 0.28308 | 0.0066096
5567101 | 00 begane grond | 1919 | 0.395439 | 0.781158 | 0.0186527
5567140 | 00 begane grond | 843 | 0.179163 | 0.348606 | 0.00819396
5567142 | 00 begane grond | 639.5 | 0.138259 | 0.276519 | 0.00621594
5567197 | 00 begane grond | 1919 | 0.395439 | 0.781158 | 0.0186527
5567198 | 00 begane grond | 680 | 0.1464 | 0.28308 | 0.0066096
5567199 | 00 begane grond | 762 | 0.162882 | 0.316044 | 0.00740664
5567201 | 00 begane grond | 762 | 0.162882 | 0.316044 | 0.00740664
5567104 | 00 begane grond | 843 | 0.179163 | 0.348606 | 0.00819396
5567106 | 00 begane grond | 672 | 0.144792 | 0.279864 | 0.00653184
5567107 | 00 begane grond | 1927 | 0.397047 | 0.784374 | 0.0187304
5567155 | 00 begane grond | 843 | 0.179163 | 0.348606 | 0.00819396
5567209 | 00 begane grond | 1927 | 0.397047 | 0.784374 | 0.0187304
5567210 | 00 begane grond | 672 | 0.144792 | 0.279864 | 0.00653184
5567299 | 00 begane grond | 840.5 | 0.178661 | 0.347601 | 0.00816966
5567301 | 00 begane grond | 680 | 0.1464 | 0.28308 | 0.0066096
5567302 | 00 begane grond | 1919 | 0.395439 | 0.781158 | 0.0186527
5567329 | 00 begane grond | 845.5 | 0.179665 | 0.349611 | 0.00821826
5567331 | 00 begane grond | 639.5 | 0.138259 | 0.276519 | 0.00621594
5567392 | 00 begane grond | 1919 | 0.395439 | 0.781158 | 0.0186527
5567393 | 00 begane grond | 680 | 0.1464 | 0.28308 | 0.0066096
5567394 | 00 begane grond | 764.5 | 0.163384 | 0.317049 | 0.00743094
5567396 | 00 begane grond | 759.523 | 0.162384 | 0.315048 | 0.00738257
5567305 | 00 begane grond | 843 | 0.179163 | 0.348606 | 0.00819396
5567307 | 00 begane grond | 680 | 0.1464 | 0.28308 | 0.0066096
5567308 | 00 begane grond | 1919 | 0.395439 | 0.781158 | 0.0186527
5567344 | 00 begane grond | 843 | 0.179163 | 0.348606 | 0.00819396
5567346 | 00 begane grond | 639.5 | 0.138259 | 0.276519 | 0.00621594
5567404 | 00 begane grond | 1919 | 0.395439 | 0.781158 | 0.0186527
5567405 | 00 begane grond | 680 | 0.1464 | 0.28308 | 0.0066096
5567406 | 00 begane grond | 762 | 0.162882 | 0.316044 | 0.00740664
5567408 | 00 begane grond | 762 | 0.162882 | 0.316044 | 0.00740664
5567311 | 00 begane grond | 1600 | 0.33132 | 0.66264 | 0.015552
5567317 | 00 begane grond | 843 | 0.179163 | 0.348606 | 0.00819396
5567319 | 00 begane grond | 680 | 0.1464 | 0.28308 | 0.0066096
5567320 | 00 begane grond | 1919 | 0.395439 | 0.781158 | 0.0186527
5567359 | 00 begane grond | 843 | 0.179163 | 0.348606 | 0.00819396
5567361 | 00 begane grond | 639.5 | 0.138259 | 0.276519 | 0.00621594
5567416 | 00 begane grond | 1919 | 0.395439 | 0.781158 | 0.0186527
5567417 | 00 begane grond | 680 | 0.1464 | 0.28308 | 0.0066096
5567418 | 00 begane grond | 762 | 0.162882 | 0.316044 | 0.00740664
5567420 | 00 begane grond | 762 | 0.162882 | 0.316044 | 0.00740664
5567323 | 00 begane grond | 826.523 | 0.175851 | 0.341982 | 0.00803381
5567325 | 00 begane grond | 672 | 0.144792 | 0.279864 | 0.00653184
5567326 | 00 begane grond | 1927 | 0.397047 | 0.784374 | 0.0187304
5567374 | 00 begane grond | 826.9 | 0.175927 | 0.342134 | 0.00803747
5567428 | 00 begane grond | 1927 | 0.397047 | 0.784374 | 0.0187304
5567429 | 00 begane grond | 672 | 0.144792 | 0.279864 | 0.00653184
5567902 | 00 begane grond | 845.692 | 0.179704 | 0.349688 | 0.00822013
5567904 | 00 begane grond | 680 | 0.1464 | 0.28308 | 0.0066096
5567905 | 00 begane grond | 1878.5 | 0.387299 | 0.774597 | 0.018259
5567932 | 00 begane grond | 840.308 | 0.178622 | 0.347524 | 0.00816779
5567934 | 00 begane grond | 639.5 | 0.138259 | 0.276519 | 0.00621594
5567995 | 00 begane grond | 1919 | 0.395439 | 0.781158 | 0.0186527
5567996 | 00 begane grond | 639.5 | 0.138259 | 0.276519 | 0.00621594
5567997 | 00 begane grond | 840.308 | 0.178622 | 0.347524 | 0.00816779
5567999 | 00 begane grond | 764.692 | 0.163423 | 0.317126 | 0.00743281
5567908 | 00 begane grond | 843 | 0.179163 | 0.348606 | 0.00819396
5567910 | 00 begane grond | 680 | 0.1464 | 0.28308 | 0.0066096
5567911 | 00 begane grond | 1919 | 0.395439 | 0.781158 | 0.0186527
5567947 | 00 begane grond | 843 | 0.179163 | 0.348606 | 0.00819396
5567949 | 00 begane grond | 720.5 | 0.15454 | 0.309081 | 0.00700326
5568007 | 00 begane grond | 1919 | 0.395439 | 0.781158 | 0.0186527
5568008 | 00 begane grond | 680 | 0.1464 | 0.28308 | 0.0066096
5568009 | 00 begane grond | 721.5 | 0.154742 | 0.309483 | 0.00701298
5568011 | 00 begane grond | 721.5 | 0.154742 | 0.309483 | 0.00701298
5567914 | 00 begane grond | 1686 | 0.348606 | 0.697212 | 0.0163879
5567920 | 00 begane grond | 843.687 | 0.179301 | 0.348882 | 0.00820064
5567922 | 00 begane grond | 680 | 0.1464 | 0.28308 | 0.0066096
5567923 | 00 begane grond | 1919 | 0.395439 | 0.781158 | 0.0186527
5567962 | 00 begane grond | 842.313 | 0.179025 | 0.34833 | 0.00818728
5567964 | 00 begane grond | 639.5 | 0.138259 | 0.276519 | 0.00621594
5568019 | 00 begane grond | 1919 | 0.395439 | 0.781158 | 0.0186527
5568020 | 00 begane grond | 680 | 0.1464 | 0.28308 | 0.0066096
5568021 | 00 begane grond | 761.313 | 0.162744 | 0.315768 | 0.00739996
5568023 | 00 begane grond | 762.687 | 0.16302 | 0.31632 | 0.00741332
5567926 | 00 begane grond | 863.125 | 0.183208 | 0.356696 | 0.00838958
5567928 | 00 begane grond | 672 | 0.144792 | 0.279864 | 0.00653184
5567929 | 00 begane grond | 1927 | 0.397047 | 0.784374 | 0.0187304
5567977 | 00 begane grond | 863.125 | 0.183208 | 0.356696 | 0.00838958
5568031 | 00 begane grond | 1927 | 0.397047 | 0.784374 | 0.0187304
5568032 | 00 begane grond | 672 | 0.144792 | 0.279864 | 0.00653184
5580910 | 00 begane grond | 672 | 0.144792 | 0.279864 | 0.00653184
5580926 | 00 begane grond | 1721 | 0.355641 | 0.691842 | 0.0167281
5583361 | 00 begane grond | 880.69 | 0.186739 | 0.363758 | 0.00856031
5583362 | 00 begane grond | 1029.31 | 0.216611 | 0.423502 | 0.0100049
12813794 | 00 begane grond | 206 | 0.051126 | 0.092532 | 0.00200232
5598051 | 00 begane grond | 796.372 | 0.169791 | 0.329861 | 0.00774073
5598053 | 00 begane grond | 680 | 0.1464 | 0.28308 | 0.0066096
5598054 | 00 begane grond | 1919 | 0.395439 | 0.781158 | 0.0186527
5598057 | 00 begane grond | 847.49 | 0.180065 | 0.350411 | 0.0082376
5598059 | 00 begane grond | 639.5 | 0.138259 | 0.276519 | 0.00621594
5598075 | 00 begane grond | 1919 | 0.395439 | 0.781158 | 0.0186527
5598076 | 00 begane grond | 680 | 0.1464 | 0.28308 | 0.0066096
5598077 | 00 begane grond | 766.49 | 0.163784 | 0.317849 | 0.00745028
5598079 | 00 begane grond | 715.372 | 0.15351 | 0.297299 | 0.00695341
5637604 | 00 begane grond | 876.268 | 0.18585 | 0.36198 | 0.00851733
5637606 | 00 begane grond | 672 | 0.144792 | 0.279864 | 0.00653184
5637607 | 00 begane grond | 206 | 0.051126 | 0.092532 | 0.00200232
5637610 | 00 begane grond | 876.304 | 0.185857 | 0.361994 | 0.00851767
5637615 | 00 begane grond | 1943 | 0.400263 | 0.781086 | 0.018886
5637633 | 00 begane grond | 1721 | 0.355641 | 0.691842 | 0.0167281
5637634 | 00 begane grond | 672 | 0.144792 | 0.279864 | 0.00653184
12816514 | 00 begane grond | 206 | 0.051126 | 0.092532 | 0.00200232
12816515 | 00 begane grond | 1721 | 0.355641 | 0.691842 | 0.0167281
5882917 | 00 begane grond | 1834 | 0.378354 | 0.756708 | 0.0178265
5649327 | 00 begane grond | 959.964 | 0.202673 | 0.405346 | 0.00933085
5649329 | 00 begane grond | 672 | 0.144792 | 0.279864 | 0.00653184
5649330 | 00 begane grond | 1927 | 0.397047 | 0.784374 | 0.0187304
5649333 | 00 begane grond | 1927 | 0.397047 | 0.784374 | 0.0187304
5649334 | 00 begane grond | 672 | 0.144792 | 0.279864 | 0.00653184
5649485 | 00 begane grond | 959.964 | 0.202673 | 0.405346 | 0.00933085
5649487 | 00 begane grond | 680 | 0.1464 | 0.28308 | 0.0066096
5649488 | 00 begane grond | 1919 | 0.395439 | 0.781158 | 0.0186527
5649491 | 00 begane grond | 1919 | 0.395439 | 0.781158 | 0.0186527
5649492 | 00 begane grond | 680 | 0.1464 | 0.28308 | 0.0066096
5649493 | 00 begane grond | 797.964 | 0.170111 | 0.340222 | 0.00775621
5837564 | 00 begane grond | 909.006 | 0.19243 | 0.375141 | 0.00883554
5837566 | 00 begane grond | 2372.5 | 0.486592 | 0.963465 | 0.0230607
5837567 | 00 begane grond | 1675 | 0.346395 | 0.68307 | 0.016281
5837570 | 00 begane grond | 45 | 0.018765 | 0.01809 | 0.0004374
5837571 | 00 begane grond | 2372.5 | 0.486592 | 0.963465 | 0.0230607
5837575 | 00 begane grond | 1756 | 0.362676 | 0.715632 | 0.0170683
5837576 | 00 begane grond | 1771.5 | 0.365792 | 0.712143 | 0.017219
5837577 | 00 begane grond | 868.494 | 0.184287 | 0.368574 | 0.00844176
5837582 | 00 begane grond | 989.994 | 0.208709 | 0.407697 | 0.00962274
5837585 | 00 begane grond | 868.494 | 0.184287 | 0.368574 | 0.00844176
5837587 | 00 begane grond | 1675 | 0.346395 | 0.68307 | 0.016281
9324833 | 00 begane grond | 1771.5 | 0.365792 | 0.712143 | 0.017219
9324834 | 00 begane grond | 45 | 0.018765 | 0.01809 | 0.0004374
9324837 | 00 begane grond | 1749 | 0.361269 | 0.712818 | 0.0170003
5837726 | 00 begane grond | 990.006 | 0.208711 | 0.407703 | 0.00962286
5837729 | 00 begane grond | 1673.5 | 0.346093 | 0.682467 | 0.0162664
5837732 | 00 begane grond | 83.5 | 0.0265035 | 0.043287 | 0.00081162
5837737 | 00 begane grond | 1673.5 | 0.346093 | 0.682467 | 0.0162664
5837738 | 00 begane grond | 1714.5 | 0.354334 | 0.689229 | 0.0166649
5837744 | 00 begane grond | 989.994 | 0.208709 | 0.407697 | 0.00962274
9318847 | 00 begane grond | 1714.5 | 0.354334 | 0.689229 | 0.0166649
9318848 | 00 begane grond | 83.5 | 0.0265035 | 0.043287 | 0.00081162
9318849 | 00 begane grond | 909 | 0.192429 | 0.375138 | 0.00883548
9318850 | 00 begane grond | 909.006 | 0.19243 | 0.375141 | 0.00883554
5903067 | 00 begane grond | 660.039 | 0.142388 | 0.275056 | 0.00641557
5903069 | 00 begane grond | 672 | 0.144792 | 0.279864 | 0.00653184
5903070 | 00 begane grond | 1927 | 0.397047 | 0.784374 | 0.0187304
5903078 | 00 begane grond | 1927 | 0.397047 | 0.784374 | 0.0187304
5903079 | 00 begane grond | 672 | 0.144792 | 0.279864 | 0.00653184
5903085 | 00 begane grond | 659.961 | 0.142372 | 0.275024 | 0.00641483
6971454 | 01 eerste verdieping | 440 | 0.09816 | 0.19632 | 0.0042768
6971455 | 01 eerste verdieping | 440 | 0.09816 | 0.19632 | 0.0042768
6971456 | 01 eerste verdieping | 1077 | 0.226197 | 0.452394 | 0.0104684
6971457 | 01 eerste verdieping | 1077 | 0.226197 | 0.452394 | 0.0104684
6971460 | 01 eerste verdieping | 440 | 0.09816 | 0.19632 | 0.0042768
6971461 | 01 eerste verdieping | 440 | 0.09816 | 0.19632 | 0.0042768
6971462 | 01 eerste verdieping | 1077 | 0.226197 | 0.452394 | 0.0104684
6971463 | 01 eerste verdieping | 1077 | 0.226197 | 0.452394 | 0.0104684
6971466 | 01 eerste verdieping | 440 | 0.09816 | 0.19632 | 0.0042768
6971467 | 01 eerste verdieping | 440 | 0.09816 | 0.19632 | 0.0042768
6971468 | 01 eerste verdieping | 1496 | 0.310416 | 0.620832 | 0.0145411
6971469 | 01 eerste verdieping | 1496 | 0.310416 | 0.620832 | 0.0145411
6971472 | 01 eerste verdieping | 440 | 0.09816 | 0.19632 | 0.0042768
6971473 | 01 eerste verdieping | 440 | 0.09816 | 0.19632 | 0.0042768
6971474 | 01 eerste verdieping | 1077 | 0.226197 | 0.452394 | 0.0104684
6971475 | 01 eerste verdieping | 1077 | 0.226197 | 0.452394 | 0.0104684
6971492 | 01 eerste verdieping | 440 | 0.09816 | 0.19632 | 0.0042768
6971493 | 01 eerste verdieping | 440 | 0.09816 | 0.19632 | 0.0042768
6971494 | 01 eerste verdieping | 1077 | 0.226197 | 0.452394 | 0.0104684
6971495 | 01 eerste verdieping | 1077 | 0.226197 | 0.452394 | 0.0104684
6988577 | 00 begane grond | 1034 | 0.217554 | 0.435108 | 0.0100505
6988579 | 00 begane grond | 672 | 0.144792 | 0.279864 | 0.00653184
6988580 | 00 begane grond | 1927 | 0.397047 | 0.784374 | 0.0187304
6988583 | 00 begane grond | 1927 | 0.397047 | 0.784374 | 0.0187304
6988584 | 00 begane grond | 672 | 0.144792 | 0.279864 | 0.00653184
7759058 | 00 begane grond | 358.175 | 0.0817133 | 0.153707 | 0.00348147
7759060 | 00 begane grond | 672 | 0.144792 | 0.279864 | 0.00653184
7759061 | 00 begane grond | 766 | 0.163686 | 0.317652 | 0.00744552
7759064 | 00 begane grond | 766 | 0.163686 | 0.317652 | 0.00744552
7759065 | 00 begane grond | 1721 | 0.355641 | 0.691842 | 0.0167281
12606026 | 00 begane grond | 358.148 | 0.0817078 | 0.153696 | 0.0034812
12606116 | 00 begane grond | 986 | 0.207906 | 0.396372 | 0.00958392
12611437 | 00 begane grond | 1721 | 0.355641 | 0.691842 | 0.0167281
12611438 | 00 begane grond | 732 | 0.156852 | 0.303984 | 0.00711504
8264867 | 00 begane grond | 440 | 0.09816 | 0.19632 | 0.0042768
8264868 | 00 begane grond | 440 | 0.09816 | 0.19632 | 0.0042768
8264869 | 00 begane grond | 1077 | 0.226197 | 0.452394 | 0.0104684
8264870 | 00 begane grond | 1077 | 0.226197 | 0.452394 | 0.0104684
8264873 | 00 begane grond | 440 | 0.09816 | 0.19632 | 0.0042768
8264874 | 00 begane grond | 440 | 0.09816 | 0.19632 | 0.0042768
8264875 | 00 begane grond | 1496 | 0.310416 | 0.620832 | 0.0145411
8264876 | 00 begane grond | 1496 | 0.310416 | 0.620832 | 0.0145411
8264879 | 00 begane grond | 440 | 0.09816 | 0.19632 | 0.0042768
8264880 | 00 begane grond | 440 | 0.09816 | 0.19632 | 0.0042768
8264881 | 00 begane grond | 1496 | 0.310416 | 0.620832 | 0.0145411
8264882 | 00 begane grond | 1496 | 0.310416 | 0.620832 | 0.0145411
8264885 | 00 begane grond | 440 | 0.09816 | 0.19632 | 0.0042768
8264886 | 00 begane grond | 440 | 0.09816 | 0.19632 | 0.0042768
8264887 | 00 begane grond | 1077 | 0.226197 | 0.452394 | 0.0104684
8264888 | 00 begane grond | 1077 | 0.226197 | 0.452394 | 0.0104684
8264891 | 00 begane grond | 440 | 0.09816 | 0.19632 | 0.0042768
8264892 | 00 begane grond | 440 | 0.09816 | 0.19632 | 0.0042768
8264893 | 00 begane grond | 1496 | 0.310416 | 0.620832 | 0.0145411
8264894 | 00 begane grond | 1496 | 0.310416 | 0.620832 | 0.0145411
8264897 | 00 begane grond | 440 | 0.09816 | 0.19632 | 0.0042768
8264898 | 00 begane grond | 440 | 0.09816 | 0.19632 | 0.0042768
8264899 | 00 begane grond | 1077 | 0.226197 | 0.452394 | 0.0104684
8264900 | 00 begane grond | 1077 | 0.226197 | 0.452394 | 0.0104684
8264903 | 00 begane grond | 440 | 0.09816 | 0.19632 | 0.0042768
8264904 | 00 begane grond | 440 | 0.09816 | 0.19632 | 0.0042768
8264905 | 00 begane grond | 538 | 0.117858 | 0.235716 | 0.00522936
8264906 | 00 begane grond | 538 | 0.117858 | 0.235716 | 0.00522936
8265072 | 00 begane grond | 440 | 0.09816 | 0.19632 | 0.0042768
8265073 | 00 begane grond | 440 | 0.09816 | 0.19632 | 0.0042768
8265074 | 00 begane grond | 538 | 0.117858 | 0.235716 | 0.00522936
8265075 | 00 begane grond | 538 | 0.117858 | 0.235716 | 0.00522936
9452508 | 00 begane grond | 440 | 0.09816 | 0.19632 | 0.0042768
9452509 | 00 begane grond | 440 | 0.09816 | 0.19632 | 0.0042768
9452510 | 00 begane grond | 1323.6 | 0.275764 | 0.551527 | 0.0128654
9452511 | 00 begane grond | 1323.6 | 0.275764 | 0.551527 | 0.0128654
10238747 | 00 begane grond | 736 | 0.157656 | 0.315312 | 0.00715392
10238749 | 00 begane grond | 672 | 0.144792 | 0.279864 | 0.00653184
10238750 | 00 begane grond | 1927 | 0.397047 | 0.784374 | 0.0187304
10241001 | 00 begane grond | 1927 | 0.397047 | 0.784374 | 0.0187304
10241002 | 00 begane grond | 672 | 0.144792 | 0.279864 | 0.00653184
10266483 | 00 begane grond | 440 | 0.09816 | 0.19632 | 0.0042768
10266484 | 00 begane grond | 440 | 0.09816 | 0.19632 | 0.0042768
10266485 | 00 begane grond | 1077 | 0.226197 | 0.452394 | 0.0104684
10266486 | 00 begane grond | 1077 | 0.226197 | 0.452394 | 0.0104684
10266781 | 00 begane grond | 440 | 0.09816 | 0.19632 | 0.0042768
10266782 | 00 begane grond | 440 | 0.09816 | 0.19632 | 0.0042768
10266783 | 00 begane grond | 1077 | 0.226197 | 0.452394 | 0.0104684
10266784 | 00 begane grond | 1077 | 0.226197 | 0.452394 | 0.0104684
10267013 | 00 begane grond | 440 | 0.09816 | 0.19632 | 0.0042768
10267014 | 00 begane grond | 440 | 0.09816 | 0.19632 | 0.0042768
10267015 | 00 begane grond | 1077 | 0.226197 | 0.452394 | 0.0104684
10267016 | 00 begane grond | 1077 | 0.226197 | 0.452394 | 0.0104684
10267234 | 00 begane grond | 440 | 0.09816 | 0.19632 | 0.0042768
10267235 | 00 begane grond | 440 | 0.09816 | 0.19632 | 0.0042768
10267236 | 00 begane grond | 1077 | 0.226197 | 0.452394 | 0.0104684
10267237 | 00 begane grond | 1077 | 0.226197 | 0.452394 | 0.0104684

# IfcMember: Rectangular Mullion:84x120 (72)
In: 00 begane grond
Type - PredefinedType: MULLION; Material: n6_kunststof_RAL 7035
Type - Pset_MemberCommon - IsExternal: no; Reference: Rectangular Mullion:84x120
Type - Pset_ProductRequirements - Category: Curtain Wall Mullions
Type - Pset_QuantityTakeOff - Reference: Rectangular Mullion:84x120
Classification: 31.0 (Uniformat)
Pset_MemberCommon - IsExternal: yes
Name (Rectangular Mullion:84x120:...) | Span (mm) = Length (mm) | CrossSectionArea (m2) | NetSurfaceArea (m2) | NetVolume (m3)
3137501 | 364.598 | 0.084458 | 0.168916 | 0.00367515
3137503 | 364.402 | 0.084418 | 0.168836 | 0.00367317
3043266 | 889.068 | 0.19145 | 0.3829 | 0.0089618
12606862 | 226.04 | 0.0561922 | 0.112384 | 0.00227849
12606864 | 230.336 | 0.0570686 | 0.114137 | 0.00232179
3132019 | 672 | 0.147168 | 0.284256 | 0.00677376
3132241 | 887.054 | 0.191039 | 0.371998 | 0.0089415
3132244 | 888.07 | 0.191246 | 0.372412 | 0.00895174
3132247 | 1927 | 0.403188 | 0.796296 | 0.0194242
3132373 | 887.916 | 0.191215 | 0.37235 | 0.00895019
3132374 | 630 | 0.1386 | 0.2772 | 0.0063504
3132415 | 888.251 | 0.191283 | 0.372486 | 0.00895357
3132416 | 630 | 0.1386 | 0.2772 | 0.0063504
3132453 | 887.916 | 0.191215 | 0.37235 | 0.00895019
3132454 | 630 | 0.1386 | 0.2772 | 0.0063504
3132487 | 886.9 | 0.191008 | 0.371935 | 0.00893995
3132488 | 630 | 0.1386 | 0.2772 | 0.0063504
3132651 | 888.07 | 0.191246 | 0.372412 | 0.00895174
3132652 | 672 | 0.147168 | 0.284256 | 0.00677376
3132653 | 1927 | 0.403188 | 0.796296 | 0.0194242
7492561 | 888.439 | 0.191322 | 0.372563 | 0.00895546
4201192 | 716.922 | 0.156332 | 0.302584 | 0.00722658
9427949 | 717.355 | 0.15642 | 0.302761 | 0.00723094
9428019 | 715.855 | 0.156114 | 0.302149 | 0.00721582
9428020 | 630.451 | 0.138692 | 0.277384 | 0.00635494
9428163 | 717.322 | 0.156414 | 0.302747 | 0.00723061
9428164 | 630.451 | 0.138692 | 0.277384 | 0.00635494
4201034 | 672 | 0.147168 | 0.284256 | 0.00677376
4201037 | 672 | 0.147168 | 0.284256 | 0.00677376
4201045 | 876.545 | 0.188895 | 0.36771 | 0.00883558
4201046 | 875.9 | 0.188764 | 0.367447 | 0.00882907
4201047 | 1968 | 0.411552 | 0.802944 | 0.0198374
4201049 | 1968 | 0.411552 | 0.802944 | 0.0198374
4201054 | 876.3 | 0.188845 | 0.36761 | 0.0088331
4201055 | 630 | 0.1386 | 0.2772 | 0.0063504
4201060 | 876.3 | 0.188845 | 0.36761 | 0.0088331
4201061 | 630 | 0.1386 | 0.2772 | 0.0063504
4201101 | 81 | 0.026604 | 0.033048 | 0.00081648
4201103 | 81 | 0.026604 | 0.033048 | 0.00081648
4201119 | 876.3 | 0.188845 | 0.36761 | 0.0088331
4201121 | 630 | 0.1386 | 0.2772 | 0.0063504
4201128 | 875.9 | 0.188764 | 0.367447 | 0.00882907
4201130 | 630 | 0.1386 | 0.2772 | 0.0063504
7496947 | 876.1 | 0.188804 | 0.367529 | 0.00883109
11898028 | 876.1 | 0.188804 | 0.367529 | 0.00883109
11898381 | 1788.15 | 0.357748 | 0.705415 | 0.017166
11990430 | 568.665 | 0.108972 | 0.207864 | 0.00487359
5203717 | 550.594 | 0.122401 | 0.244802 | 0.00554999
5567157 | 630 | 0.1386 | 0.2772 | 0.0063504
5567211 | 762 | 0.165528 | 0.320976 | 0.00768096
5567213 | 762 | 0.165528 | 0.320976 | 0.00768096
5567376 | 630 | 0.1386 | 0.2772 | 0.0063504
5567430 | 745.9 | 0.162244 | 0.314407 | 0.00751867
5567432 | 745.523 | 0.162167 | 0.314254 | 0.00751488
5567979 | 630 | 0.1386 | 0.2772 | 0.0063504
5568033 | 782.125 | 0.169634 | 0.329187 | 0.00788382
5568035 | 782.125 | 0.169634 | 0.329187 | 0.00788382
5580928 | 756.69 | 0.164445 | 0.32889 | 0.00762744
5637635 | 752.304 | 0.16355 | 0.3271 | 0.00758322
5637636 | 752.304 | 0.16355 | 0.3271 | 0.00758322
5649335 | 797.964 | 0.172865 | 0.345729 | 0.00804348
5837739 | 867 | 0.186948 | 0.373896 | 0.00873936
5837747 | 867 | 0.186948 | 0.373896 | 0.00873936
5837749 | 1673.5 | 0.351474 | 0.692868 | 0.0168689
9318851 | 1674 | 0.351576 | 0.693072 | 0.0168739
5903080 | 578.961 | 0.128188 | 0.246296 | 0.00583593
5903087 | 579.039 | 0.128204 | 0.246328 | 0.00583671
5903089 | 630 | 0.1386 | 0.2772 | 0.0063504
6988585 | 872 | 0.187968 | 0.375936 | 0.00878976
12611439 | 234.148 | 0.0578463 | 0.115693 | 0.00236022
12611441 | 234.148 | 0.0578463 | 0.115693 | 0.00236022
10241003 | 574 | 0.127176 | 0.254352 | 0.00578592

# IfcMember: Rectangular Mullion:86x120 (104)
In: 00 begane grond
Type - PredefinedType: MULLION; Material: n6_kunststof_RAL 7035
Type - Pset_MemberCommon - IsExternal: no; Reference: Rectangular Mullion:86x120
Type - Pset_ProductRequirements - Category: Curtain Wall Mullions
Type - Pset_QuantityTakeOff - Reference: Rectangular Mullion:86x120
Classification: 31.0 (Uniformat)
Pset_MemberCommon - IsExternal: yes
Name (Rectangular Mullion:86x120:...) | Span (mm) = Length (mm) | CrossSectionArea (m2) | NetSurfaceArea (m2) | NetVolume (m3)
3029717 | 672 | 0.148752 | 0.287184 | 0.00693504
3029811 | 672 | 0.148752 | 0.287184 | 0.00693504
3137504 | 1721 | 0.364846 | 0.709052 | 0.0177607
3137505 | 1721 | 0.364846 | 0.709052 | 0.0177607
12812933 | 1857 | 0.392862 | 0.785724 | 0.0191642
12812935 | 206 | 0.052756 | 0.095192 | 0.00212592
12812936 | 206 | 0.052756 | 0.095192 | 0.00212592
3019655 | 2393 | 0.503278 | 0.996236 | 0.0246958
3019656 | 206 | 0.052756 | 0.095192 | 0.00212592
12818584 | 287 | 0.069442 | 0.128564 | 0.00296184
12818585 | 2393 | 0.503278 | 0.996236 | 0.0246958
12818586 | 1513 | 0.321998 | 0.643996 | 0.0156142
3020546 | 2393 | 0.503278 | 0.996236 | 0.0246958
3020547 | 206 | 0.052756 | 0.095192 | 0.00212592
12818243 | 287 | 0.069442 | 0.128564 | 0.00296184
12818244 | 2393 | 0.503278 | 0.996236 | 0.0246958
12818245 | 1497.37 | 0.318779 | 0.637558 | 0.0154529
3037854 | 680 | 0.1504 | 0.29048 | 0.0070176
3038153 | 1713 | 0.363198 | 0.705756 | 0.0176782
12819080 | 876.942 | 0.19097 | 0.38194 | 0.00905004
12819082 | 287 | 0.069442 | 0.128564 | 0.00296184
5719173 | 269.04 | 0.0657423 | 0.121165 | 0.0027765
12606268 | 273.336 | 0.0666273 | 0.122935 | 0.00282083
12606269 | 672 | 0.148752 | 0.287184 | 0.00693504
12606339 | 986 | 0.213436 | 0.406232 | 0.0101755
12606340 | 672 | 0.148752 | 0.287184 | 0.00693504
12606865 | 1678 | 0.355988 | 0.701656 | 0.017317
12606866 | 1678 | 0.355988 | 0.701656 | 0.017317
4093380 | 2393 | 0.503278 | 0.996236 | 0.0246958
4093381 | 206 | 0.052756 | 0.095192 | 0.00212592
12814721 | 206 | 0.052756 | 0.095192 | 0.00212592
12814722 | 2453 | 0.515638 | 1.02096 | 0.025315
12814723 | 1808 | 0.382768 | 0.765536 | 0.0186586
4200609 | 672.451 | 0.148845 | 0.28737 | 0.00693969
4200615 | 672.451 | 0.148845 | 0.28737 | 0.00693969
4200620 | 672.451 | 0.148845 | 0.28737 | 0.00693969
4200630 | 1720.55 | 0.364753 | 0.708866 | 0.0177561
4200634 | 1720.55 | 0.364753 | 0.708866 | 0.0177561
4200635 | 1720.55 | 0.364753 | 0.708866 | 0.0177561
7508914 | 672.451 | 0.148845 | 0.28737 | 0.00693969
7508915 | 1720.55 | 0.364753 | 0.708866 | 0.0177561
12815831 | 206 | 0.052756 | 0.095192 | 0.00212592
12815835 | 1856.76 | 0.392812 | 0.785623 | 0.0191617
12815839 | 1857 | 0.392862 | 0.785724 | 0.0191642
12815840 | 206 | 0.052756 | 0.095192 | 0.00212592
12815841 | 206 | 0.052756 | 0.095192 | 0.00212592
12815843 | 206 | 0.052756 | 0.095192 | 0.00212592
5203706 | 671.5 | 0.148649 | 0.286978 | 0.00692988
5203711 | 671.5 | 0.148649 | 0.286978 | 0.00692988
5203715 | 1721.5 | 0.364949 | 0.709258 | 0.0177659
5203718 | 1721.5 | 0.364949 | 0.709258 | 0.0177659
12812518 | 206 | 0.052756 | 0.095192 | 0.00212592
12812521 | 1856.5 | 0.392759 | 0.785518 | 0.0191591
12812522 | 206 | 0.052756 | 0.095192 | 0.00212592
5565113 | 2393 | 0.503278 | 0.996236 | 0.0246958
5565114 | 206 | 0.052756 | 0.095192 | 0.00212592
12818807 | 287 | 0.069442 | 0.128564 | 0.00296184
12818808 | 2453 | 0.515638 | 1.02096 | 0.025315
12818809 | 1513 | 0.321998 | 0.643996 | 0.0156142
5567094 | 2393 | 0.503278 | 0.996236 | 0.0246958
5567095 | 206 | 0.052756 | 0.095192 | 0.00212592
12819636 | 287 | 0.069442 | 0.128564 | 0.00296184
12819637 | 2393 | 0.503278 | 0.996236 | 0.0246958
12819638 | 1514 | 0.322204 | 0.644408 | 0.0156245
5567313 | 2393 | 0.503278 | 0.996236 | 0.0246958
5567314 | 206 | 0.052756 | 0.095192 | 0.00212592
12819388 | 287 | 0.069442 | 0.128564 | 0.00296184
12819389 | 2393 | 0.503278 | 0.996236 | 0.0246958
12819390 | 1514 | 0.322204 | 0.644408 | 0.0156245
5567916 | 2393 | 0.503278 | 0.996236 | 0.0246958
5567917 | 206 | 0.052756 | 0.095192 | 0.00212592
12814180 | 206 | 0.052756 | 0.095192 | 0.00212592
12814181 | 2393 | 0.503278 | 0.996236 | 0.0246958
12814182 | 1514 | 0.322204 | 0.644408 | 0.0156245
5580916 | 672 | 0.148752 | 0.287184 | 0.00693504
5580930 | 1721 | 0.364846 | 0.709052 | 0.0177607
5583367 | 206 | 0.052756 | 0.095192 | 0.00212592
5583368 | 672 | 0.148752 | 0.287184 | 0.00693504
12813795 | 1721 | 0.364846 | 0.709052 | 0.0177607
12813796 | 900.31 | 0.195784 | 0.391568 | 0.0092912
12813798 | 206 | 0.052756 | 0.095192 | 0.00212592
5637612 | 672 | 0.148752 | 0.287184 | 0.00693504
5637617 | 672 | 0.148752 | 0.287184 | 0.00693504
5637637 | 1721 | 0.364846 | 0.709052 | 0.0177607
5637638 | 1721 | 0.364846 | 0.709052 | 0.0177607
12816517 | 1857 | 0.392862 | 0.785724 | 0.0191642
12816519 | 206 | 0.052756 | 0.095192 | 0.00212592
12816520 | 206 | 0.052756 | 0.095192 | 0.00212592
5638069 | 206 | 0.052756 | 0.095192 | 0.00212592
5882831 | 2393 | 0.503278 | 0.996236 | 0.0246958
12816947 | 206 | 0.052756 | 0.095192 | 0.00212592
12816948 | 2393 | 0.503278 | 0.996236 | 0.0246958
12816949 | 1662 | 0.352692 | 0.705384 | 0.0171518
5837728 | 2392.5 | 0.503175 | 1.00635 | 0.0246906
5837733 | 2392.5 | 0.503175 | 1.00635 | 0.0246906
5837734 | 904 | 0.196544 | 0.382768 | 0.00932928
5837746 | 904.006 | 0.196545 | 0.382771 | 0.00932935
7759066 | 277.148 | 0.0674126 | 0.124505 | 0.00286017
12606028 | 986 | 0.213436 | 0.406232 | 0.0101755
12606029 | 672 | 0.148752 | 0.287184 | 0.00693504
12606118 | 277.175 | 0.0674181 | 0.124516 | 0.00286045
12606119 | 672 | 0.148752 | 0.287184 | 0.00693504
12611442 | 1678 | 0.355988 | 0.701656 | 0.017317
12611443 | 1678 | 0.355988 | 0.701656 | 0.017317

# IfcMember: Rectangular Mullion:86x120 RAL 7021 (3)
In: 00 begane grond
Type - PredefinedType: MULLION; Material: ZZ_00_Kleur_RAL 7021
Type - Pset_MemberCommon - IsExternal: no; Reference: Rectangular Mullion:86x120 RAL 7021
Type - Pset_ProductRequirements - Category: Curtain Wall Mullions
Type - Pset_QuantityTakeOff - Reference: Rectangular Mullion:86x120 RAL 7021
Classification: 31.0 (Uniformat)
Pset_MemberCommon - IsExternal: yes
Name (Rectangular Mullion:86x120 RAL 7021:...) | Span (mm) = Length (mm) | CrossSectionArea (m2) | NetSurfaceArea (m2) | NetVolume (m3)
5254166 | 1072 | 0.231152 | 0.462304 | 0.011063
5254168 | 2314 | 0.487004 | 0.974008 | 0.0238805
5254169 | 2314 | 0.487004 | 0.974008 | 0.0238805

# IfcMember: Rectangular Mullion:90x114 (41)
In: 00 begane grond
Type - PredefinedType: MULLION; Material: NLRS_i3_hout_Loofhout (hardhout) RAL 9002
Type - Pset_MemberCommon - IsExternal: no; Reference: Rectangular Mullion:90x114
Type - Pset_ProductRequirements - Category: Curtain Wall Mullions
Type - Pset_QuantityTakeOff - Reference: Rectangular Mullion:90x114
Classification: 31.0 (Uniformat)
Pset_MemberCommon - IsExternal: yes
Name (Rectangular Mullion:90x114:...) | Span (mm) = Length (mm) | CrossSectionArea (m2) | NetSurfaceArea (m2) | NetVolume (m3)
2981905 | 621.5 | 0.137046 | 0.263832 | 0.00637659
2981969 | 621.5 | 0.137046 | 0.263832 | 0.00637659
7644451 | 762.304 | 0.16577 | 0.33154 | 0.00782124
7644453 | 835.36 | 0.180673 | 0.361347 | 0.0085708
7644454 | 1944.5 | 0.406938 | 0.803616 | 0.0199506
7644455 | 1944.5 | 0.406938 | 0.803616 | 0.0199506
3079520 | 621.5 | 0.137046 | 0.263832 | 0.00637659
7645514 | 576.064 | 0.127777 | 0.255554 | 0.00591041
7645515 | 1944.5 | 0.406938 | 0.803616 | 0.0199506
3311326 | 2633 | 0.547392 | 1.09478 | 0.0270146
3669647 | 621.5 | 0.137046 | 0.263832 | 0.00637659
3669773 | 576.5 | 0.127866 | 0.255732 | 0.00591489
3669968 | 803 | 0.174072 | 0.337884 | 0.00823878
3669969 | 802.575 | 0.173985 | 0.33771 | 0.00823442
3669972 | 1944.5 | 0.406938 | 0.803616 | 0.0199506
3669238 | 621.5 | 0.137046 | 0.263832 | 0.00637659
3669314 | 576.5 | 0.127866 | 0.255732 | 0.00591489
3669550 | 1201.5 | 0.255366 | 0.500472 | 0.0123274
3669551 | 1224.5 | 0.260058 | 0.509856 | 0.0125634
3669552 | 1944.5 | 0.406938 | 0.803616 | 0.0199506
9723241 | 316 | 0.074724 | 0.149448 | 0.00324216
4326220 | 621.5 | 0.137046 | 0.263832 | 0.00637659
7644789 | 839.025 | 0.181421 | 0.362842 | 0.0086084
7644791 | 1944.5 | 0.406938 | 0.803616 | 0.0199506
5762149 | 621.5 | 0.137046 | 0.263832 | 0.00637659
7643283 | 835 | 0.1806 | 0.35094 | 0.0085671
7643285 | 1944.5 | 0.406938 | 0.803616 | 0.0199506
10302096 | 834 | 0.180396 | 0.350532 | 0.00855684
10302097 | 576.5 | 0.127866 | 0.255732 | 0.00591489
7768096 | 1056.97 | 0.225883 | 0.441506 | 0.0108446
7768097 | 621.5 | 0.137046 | 0.263832 | 0.00637659
7768098 | 1944.5 | 0.406938 | 0.803616 | 0.0199506
7768346 | 1056 | 0.225684 | 0.441108 | 0.0108346
7768347 | 576.5 | 0.127866 | 0.255732 | 0.00591489
9244754 | 2670 | 0.55494 | 1.10988 | 0.0273942
9530502 | 3111 | 0.644904 | 1.28981 | 0.0319189
12734904 | 621.5 | 0.137046 | 0.263832 | 0.00637659
12738656 | 140.32 | 0.0388854 | 0.0777707 | 0.00143969
12738657 | 1944.5 | 0.406938 | 0.803616 | 0.0199506
12738234 | 653 | 0.143472 | 0.276684 | 0.00669978
12738764 | 1980 | 0.41418 | 0.8181 | 0.0203148

# IfcMember: Rectangular Mullion:90x158 (4)
In: 00 begane grond
Type - PredefinedType: MULLION; Material: NLRS_i3_hout_Loofhout (hardhout) RAL 9002
Type - Pset_MemberCommon - IsExternal: no; Reference: Rectangular Mullion:90x158
Type - Pset_ProductRequirements - Category: Curtain Wall Mullions
Type - Pset_QuantityTakeOff - Reference: Rectangular Mullion:90x158
Classification: 31.0 (Uniformat)
Pset_MemberCommon - IsExternal: yes; Span: 2633 mm
BaseQuantities - Length: 2633 mm; CrossSectionArea: 0.667204 m2; NetSurfaceArea: 1.33441 m2; NetVolume: 0.0374413 m3
Name (Rectangular Mullion:90x158:...)
7628903
7630322
7632406
7635242

# IfcMember: Stringer:Stringer - 50 mm Width (2) (18)
Type - PredefinedType: STRINGER
Classification: 24.1 trappen en hellingen; trappen (Uniformat); Material: AL_31_Naaldhout Trap boom
Pset_MemberCommon - IsExternal: no; Reference: Stringer:Stringer - 50 mm Width (2)
Pset_ProductRequirements - Category: Supports
Pset_QuantityTakeOff - Reference: Stringer:Stringer - 50 mm Width (2)
Name (Assembled Stair:Stair:...) | In | Slope (deg) | Length (mm) | CrossSectionArea (m2) | OuterSurfaceArea (m2) | GrossSurfaceArea (m2) | NetSurfaceArea (m2) | GrossVolume (m3) | NetVolume (m3)
5926983 Stringer 1 | 00 begane grond | 90 | 50 | 0.731401 | 229751 | 229752 | 1.69255 | 36.5701 | 0.0365701
5926983 Stringer 2 | 00 begane grond | 90 | 50 | 0.788791 | 237182 | 237184 | 1.81477 | 39.4396 | 0.0394396
5926983 Stringer 3 | 00 begane grond | 45.6607 | 50 | 0.686788 | 228929 | 228931 | 1.6025 | 34.3394 | 0.0343394
5926983 Stringer 4 | 00 begane grond | 90 | 50 | 0.772478 | 243436 | 243437 | 1.78839 | 38.6239 | 0.0386239
5926983 Stringer 5 | 00 begane grond | 0 | 400 | 0.0082 | 171200 | 171200 | 0.1876 | 3.28 | 0.00328
5926983 Stringer 6 | 00 begane grond | 0 |  |  |  |  | 0.792236 |  | 0.0164945
5926983 Stringer 7 | 00 begane grond | 0 | 400 | 0.0982 | 1627769 | 1627769 | 1.82417 | 39.28 | 0.03928
5926983 Stringer 8 | 00 begane grond | 0 |  |  |  |  | 0.702733 |  | 0.0145055
6459863 Stringer 1 | 01 eerste verdieping | 45.0221 | 50 | 0.58684 | 193292 | 193293 | 1.36697 | 29.342 | 0.029342
6459863 Stringer 2 | 01 eerste verdieping | 45.0221 | 50 | 0.58684 | 193292 | 193293 | 1.36697 | 29.342 | 0.029342
6460690 Stringer 1 | 01 eerste verdieping | 45.0221 | 50 | 0.58684 | 193292 | 193293 | 1.36697 | 29.342 | 0.029342
6460690 Stringer 2 | 01 eerste verdieping | 45.0221 | 50 | 0.58684 | 193292 | 193293 | 1.36697 | 29.342 | 0.029342
9385217 Stringer 1 | 00 begane grond | 47.2312 | 50 | 0.503767 | 173701 | 173702 | 1.18123 | 25.1883 | 0.0251883
9385217 Stringer 2 | 00 begane grond | 47.2312 | 50 | 0.503767 | 173701 | 173702 | 1.18123 | 25.1883 | 0.0251883
9386611 Stringer 1 | 00 begane grond | 47.2312 | 50 | 0.503767 | 173701 | 173702 | 1.18123 | 25.1883 | 0.0251883
9386611 Stringer 2 | 00 begane grond | 47.2312 | 50 | 0.503767 | 173701 | 173702 | 1.18123 | 25.1883 | 0.0251883
9386774 Stringer 1 | 00 begane grond | 47.2312 | 50 | 0.503767 | 173701 | 173702 | 1.18123 | 25.1883 | 0.0251883
9386774 Stringer 2 | 00 begane grond | 47.2312 | 50 | 0.503767 | 173701 | 173702 | 1.18123 | 25.1883 | 0.0251883

# IfcOpeningElement: Opening (433)
Name | In | Classification | Height (mm) | Width (mm) | Pset_OpeningElementCommon, Reference | sets with these values | Category | Roughness (mm)
Basic Wall:NLRS_21_WA_kalkzandsteen_130mm:2833725 | 00 begane grond | 21.12 buitenwanden; niet constructief, spouwwanden (Uniformat) | 2127 | 834 | AL_32.i_Binnenkozijn-enkeledeur_Linksdraaiend:Merk e.sp (2000mm hoog) | 2 | Doors | BaseQuantities - Depth: 3048 mm
Basic Wall:NLRS_21_WA_kalkzandsteen_100mm_gen_aly:2544692 | 00 begane grond | 21.22 buitenwanden; constructief, spouwwanden (Uniformat) | 1967.73 | 984 | Basic Wall:Model Lines | 2 | <Sketch> | 304.8 | Pset_ManufacturerTypeInformation - Manufacturer: De RuwBouw Groep
Basic Wall:NLRS_21_WA_kalkzandsteen_120mm_CS20_gen_aly:589376 | 00 begane grond | 21.22 buitenwanden; constructief, spouwwanden (Uniformat) | 50 | 552 | Basic Wall:Model Lines | 2 | <Sketch> | 304.8 | Pset_ManufacturerTypeInformation - Manufacturer: De RuwBouw Groep
Basic Wall:NLRS_20_WA_Metselwerk-100mm:2837406 | 00 begane grond | 21.11 buitenwanden; niet constructief, massieve wanden (Uniformat) | 2142 | 100 | AL_32.i_Binnenkozijn-enkeledeur_Linksdraaiend:Merk a.sp (2000mm hoog) | 2 | Doors | BaseQuantities - Depth: 1034 mm
Basic Wall:NLRS_20_WA_Metselwerk-100mm:2837406 | 00 begane grond | 21.11 buitenwanden; niet constructief, massieve wanden (Uniformat) | 2142 | 100 | AL_32.i_Binnenkozijn-enkeledeur_Rechtsdraaiend:Merk a (2000mm hoog) | 2 | Doors | BaseQuantities - Depth: 1034 mm
Basic Wall:NLRS_20_WA_Metselwerk-100mm:2837573:1 | 00 begane grond | 21.11 buitenwanden; niet constructief, massieve wanden (Uniformat) |  |  | Basic Wall:NLRS_20_WA_Metselwerk-100mm | 2 | Walls | 304.8
2 x Basic Wall:NLRS_20_WA_Metselwerk-100mm:2881791 | 00 begane grond | 21.11 buitenwanden; niet constructief, massieve wanden (Uniformat) | 1600 | 734 | Basic Wall:Model Lines | 2 | <Sketch> | 304.8
Basic Wall:NLRS_20_WA_Metselwerk-100mm:2841094 | 00 begane grond | 21.11 buitenwanden; niet constructief, massieve wanden (Uniformat) | 2227 | 100 | AL_32.i_Binnenkozijn-enkeledeur_Linksdraaiend:Merk f.sp (2100mm hoog) | 2 | Doors | BaseQuantities - Depth: 784 mm
Basic Wall:NLRS_20_WA_Metselwerk-100mm:2841094 | 00 begane grond | 21.11 buitenwanden; niet constructief, massieve wanden (Uniformat) | 2227 | 100 | AL_32.i_Binnenkozijn-enkeledeur_Rechtsdraaiend:Merk f (2100mm hoog) | 2 | Doors | BaseQuantities - Depth: 784 mm
Basic Wall:NLRS_20_WA_Metselwerk-100mm:2841310 | 00 begane grond | 21.11 buitenwanden; niet constructief, massieve wanden (Uniformat) | 2242 | 100 | AL_32.i_Binnenkozijn-enkeledeur_Linksdraaiend:Merk g.sp (2100mm hoog) | 2 | Doors | BaseQuantities - Depth: 734 mm
AL_32.i_Binnenkozijn-enkeledeur_Rechtsdraaiend:Merk a:12236946:1 | 00 begane grond |  | 1034 | 2462 | BaseQuantities - Depth: 192.159 mm
AL_32.i_Binnenkozijn-enkeledeur_Linksdraaiend:Merk a.sp:12236962:1 | 00 begane grond |  | 1034 | 2462 | BaseQuantities - Depth: 192.159 mm
AL_32.i_Binnenkozijn-enkeledeur_Linksdraaiend:Merk a.sp (2000mm hoog):11066521:1 | 01 eerste verdieping |  | 1034 | 2142 | BaseQuantities - Depth: 100 mm
AL_32.i_Binnenkozijn-enkeledeur_Linksdraaiend:Merk a.sp (2000mm hoog):11066517:1 | 01 eerste verdieping |  | 1034 | 2142 | BaseQuantities - Depth: 100 mm
AL_32.i_Binnenkozijn-enkeledeur_Linksdraaiend:Merk a.sp (2000mm hoog):11066515:1 | 01 eerste verdieping |  | 1034 | 2142 | BaseQuantities - Depth: 100 mm
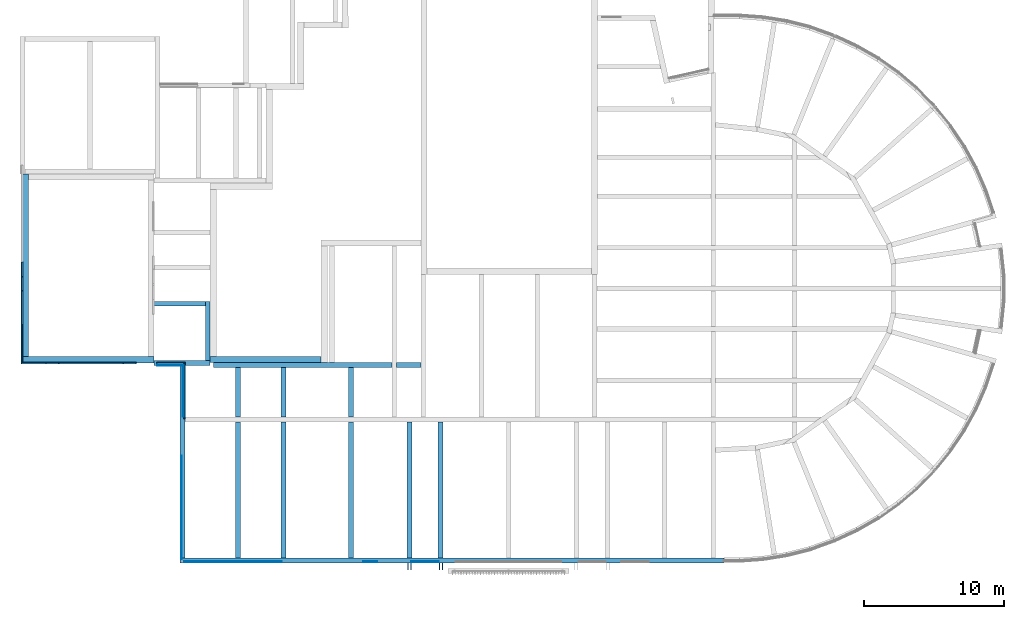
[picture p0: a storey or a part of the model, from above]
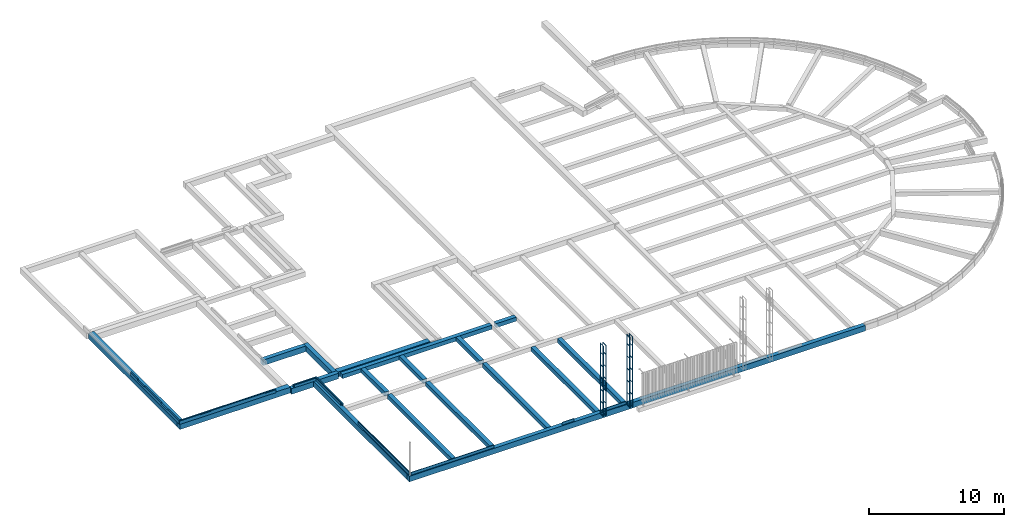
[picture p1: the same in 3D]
Properties of the parts of a building model (IFC2X3), part 6 of 13

# IfcOpeningElement: Opening (433)
Name | In | Classification | Height (mm) | Width (mm) | Pset_OpeningElementCommon, Reference | sets with these values | Category | Roughness (mm)
2 x Basic Wall:NLRS_20_WA_Metselwerk-100mm:2881791 | 00 begane grond | 21.11 buitenwanden; niet constructief, massieve wanden (Uniformat) | 1600 | 1034 | Basic Wall:Model Lines | 2 | <Sketch> | 304.8
AL_32.i_Binnenkozijn-enkeledeur_Linksdraaiend:Merk a.sp (2000mm hoog):11066509:1 | 01 eerste verdieping |  | 1034 | 2142 | BaseQuantities - Depth: 100 mm
AL_32.i_Binnenkozijn-enkeledeur_Rechtsdraaiend:Merk a (2000mm hoog):11066505:1 | 01 eerste verdieping |  | 1034 | 2142 | BaseQuantities - Depth: 100 mm
AL_32.i_Binnenkozijn-enkeledeur_Rechtsdraaiend:Merk a (2000mm hoog):11066478:1 | 01 eerste verdieping |  | 1034 | 2142 | BaseQuantities - Depth: 100 mm
AL_32.i_Binnenkozijn-enkeledeur_Rechtsdraaiend:Merk a (2000mm hoog):11066474:1 | 01 eerste verdieping |  | 1034 | 2142 | BaseQuantities - Depth: 100 mm
AL_32.i_Binnenkozijn-enkeledeur_Rechtsdraaiend:Merk a (2000mm hoog):11066472:1 | 01 eerste verdieping |  | 1034 | 2142 | BaseQuantities - Depth: 100 mm
AL_32_Binnendeur-schuifdeur in de wand met raampje:2392x2000:10686886:1 | 00 begane grond |  | 2000 | 2452 | BaseQuantities - Depth: 150 mm
AL_32.i_Binnenkozijn-enkeledeur_Rechtsdraaiend:Merk h:10125875:1 | 00 begane grond |  | 1234 | 2462 | BaseQuantities - Depth: 120 mm
AL_32.i_Binnenkozijn-enkeledeur_Linksdraaiend:Merk a.sp:10065633:1 | 00 begane grond |  | 1034 | 2462 | BaseQuantities - Depth: 100 mm
Basic Wall:NLRS_21_WA_Metalstud 100mm:2991235 | 00 begane grond | 21.23 buitenwanden; constructief, systeemwanden (Uniformat) | 2156.51 | 1800 | Curtain Wall:NLRS_31_WIN_UN_houten kozijn vrij indeelbaar_gen_aly | 2 | Walls | BaseQuantities - Depth: 404.8 mm
Basic Wall:NLRS_21_WA_Metalstud 100mm:3671798 | 00 begane grond | 21.23 buitenwanden; constructief, systeemwanden (Uniformat) | 1844.51 | 1415 | Basic Wall:Model Lines | 2 | <Sketch> | 304.8
Basic Wall:NLRS_21_WA_Metalstud 100mm:3671798 | 00 begane grond | 21.23 buitenwanden; constructief, systeemwanden (Uniformat) |  |  | Basic Wall:Model Lines | 2 | <Sketch> | 304.8 | BaseQuantities - Area: 0.669908 m2
Basic Wall:NLRS_21_WA_Metalstud 100mm:2995243 | 00 begane grond | 21.23 buitenwanden; constructief, systeemwanden (Uniformat) | 2392 | 1991 | Curtain Wall:NLRS_31_WIN_UN_houten kozijn vrij indeelbaar_gen_aly | 2 | Walls | BaseQuantities - Depth: 404.8 mm
AL_32.i_Binnenkozijn-enkeledeur_Rechtsdraaiend met raampje:Merk a:8159988:1 | 00 begane grond |  | 1034 | 2462 | BaseQuantities - Depth: 165 mm
AL_32.i_Binnenkozijn-enkeledeur_Linksdraaiend:Merk a.sp:8052867:1 | 01 eerste verdieping |  | 1034 | 2462 | BaseQuantities - Depth: 100 mm
AL_32.i_Binnenkozijn-enkeledeur_Linksdraaiend:Merk a.sp:8052840:1 | 01 eerste verdieping |  | 1034 | 2462 | BaseQuantities - Depth: 100 mm
Basic Wall:NLRS_21_WA_Metalstud 235mm:12616997 | 00 begane grond | 21.23 buitenwanden; constructief, systeemwanden (Uniformat) |  |  | Basic Wall:Model Lines | 2 | <Sketch> | 304.8 | BaseQuantities - Area: 0.330328 m2
Basic Wall:NLRS_21_WA_Metalstud 235mm:12616997 | 00 begane grond | 21.23 buitenwanden; constructief, systeemwanden (Uniformat) |  |  | Basic Wall:Model Lines | 2 | <Sketch> | 304.8 | BaseQuantities - Area: 0.331325 m2
Basic Wall:NLRS_21_WA_Metalstud 235mm:12616997 | 00 begane grond | 21.23 buitenwanden; constructief, systeemwanden (Uniformat) |  |  | Basic Wall:Model Lines | 2 | <Sketch> | 304.8 | BaseQuantities - Area: 0.331864 m2
Basic Wall:NLRS_21_WA_Metalstud 235mm:12616997 | 00 begane grond | 21.23 buitenwanden; constructief, systeemwanden (Uniformat) |  |  | Basic Wall:Model Lines | 2 | <Sketch> | 304.8 | BaseQuantities - Area: 0.330732 m2
Basic Wall:NLRS_21_WA_Metalstud 100mm:3671798 | 00 begane grond | 21.23 buitenwanden; constructief, systeemwanden (Uniformat) | 1007.5 | 207.25 | Basic Wall:Model Lines | 2 | <Sketch> | 304.8
AL_32.i_Binnenkozijn-enkeledeur_Linksdraaiend:Merk a.sp:8052795:1 | 01 eerste verdieping |  | 1034 | 2462 | BaseQuantities - Depth: 100 mm
AL_32.i_Binnenkozijn-enkeledeur_Rechtsdraaiend:Merk b:8032679:1 | 00 begane grond |  | 984 | 2462 | BaseQuantities - Depth: 165 mm
AL_32.i_Binnenkozijn-enkeledeur_Rechtsdraaiend:Merk b:8032625:1 | 00 begane grond |  | 984 | 2462 | BaseQuantities - Depth: 165 mm
skygate-Enkele panelen en deuren (enkele richting draaibaar):Enkel taatsdeur model 1850mm:7799846:1 | 00 begane grond |  | 1862 | 2776 | BaseQuantities - Depth: 100 mm
AL_32.i_Binnenkozijn-enkeledeur_Rechtsdraaiend:Merk a:7798983:1 | 01 eerste verdieping |  | 1034 | 2462 | BaseQuantities - Depth: 100 mm
AL_32.i_Binnenkozijn-enkeledeur_Rechtsdraaiend:Merk a (2000mm hoog):7473260:1 | 00 begane grond |  | 1034 | 2142 | BaseQuantities - Depth: 100 mm
AL_32.i_Binnenkozijn-enkeledeur_Rechtsdraaiend:Merk a (2100mm hog):6942818:1 | 00 begane grond |  | 1034 | 2242 | BaseQuantities - Depth: 100 mm
AL_32.i_Binnenkozijn-enkeledeur_Linksdraaiend:Merk a.sp (2100mm hoog):6942819:1 | 00 begane grond |  | 1034 | 2242 | BaseQuantities - Depth: 100 mm
AL_32.i_Binnenkozijn-enkeledeur_Rechtsdraaiend:Merk e (2100mm hoog):6942820:1 | 00 begane grond |  | 834 | 2227 | BaseQuantities - Depth: 100 mm
AL_32.i_Binnenkozijn-enkeledeur_Rechtsdraaiend:Merk a (2000mm hoog):7472318:1 | 00 begane grond |  | 1034 | 2142 | BaseQuantities - Depth: 100 mm
AL_32.i_Binnenkozijn-enkeledeur_Linksdraaiend:Merk a.sp (2000mm hoog):7472237:1 | 00 begane grond |  | 1034 | 2142 | BaseQuantities - Depth: 100 mm
AL_32.i_Binnenkozijn-enkeledeur_Rechtsdraaiend:Merk a:5928374:1 | 01 eerste verdieping |  | 1034 | 2462 | BaseQuantities - Depth: 100 mm
AL_32.i_Binnenkozijn-enkeledeur_Rechtsdraaiend:Merk a (2000mm hoog):11066411:1 | 01 eerste verdieping |  | 1034 | 2142 | BaseQuantities - Depth: 100 mm
AL_32.i_Binnenkozijn-enkeledeur_Linksdraaiend:Merk a.sp:5855144:1 | 00 begane grond |  | 1034 | 2462 | BaseQuantities - Depth: 100 mm
AL_32.i_Binnenkozijn-enkeledeur_Linksdraaiend:Merk a.sp:10064475:1 | 00 begane grond |  | 1034 | 2462 | BaseQuantities - Depth: 100 mm
Basic Wall:NLRS_20_WA_Metselwerk 100mm, Eems wf-p-0081-25:7060662 | 00 begane grond | 21.11 buitenwanden; niet constructief, massieve wanden (Uniformat) | 2462 | 3258.58 | Basic Wall:Model Lines | 2 | <Sketch> | 304.8
Basic Wall:NLRS_21_WA_Metalstud 100mm:3067136 | 01 eerste verdieping | 21.23 buitenwanden; constructief, systeemwanden (Uniformat) | 2462 | 100 | AL_32.i_Binnenkozijn-enkeledeur_Linksdraaiend:Merk a.sp | 2 | Doors | BaseQuantities - Depth: 1034 mm
Basic Wall:NLRS_21_WA_Metalstud 100mm:3671798 | 01 eerste verdieping | 21.23 buitenwanden; constructief, systeemwanden (Uniformat) | 6723.77 | 290 | Basic Wall:Model Lines | 2 | <Sketch> | 304.8
Basic Wall:NLRS_21_WA_Metalstud 100mm:3078199 | 00 begane grond | 21.23 buitenwanden; constructief, systeemwanden (Uniformat) | 2462 | 165 | AL_32.i_Binnenkozijn-enkeledeur_Rechtsdraaiend met raampje:Merk a | 2 | Doors | BaseQuantities - Depth: 1034 mm
AL_32.i_Binnenkozijn-enkeledeur_Linksdraaiend:Merk a.sp:5743232:1 | 01 eerste verdieping |  | 1034 | 2462 | BaseQuantities - Depth: 100 mm
Basic Wall:NLRS_21_WA_Metalstud 100mm:3671798 | 01 eerste verdieping | 21.23 buitenwanden; constructief, systeemwanden (Uniformat) | 154 | 100 | Basic Wall:Model Lines | 2 | <Sketch> | 304.8
AL_32.i_Binnenkozijn-enkeledeur_Rechtsdraaiend:Merk a:5743084:1 | 01 eerste verdieping |  | 1034 | 2462 | BaseQuantities - Depth: 100 mm
AL_32.i_Binnenkozijn-enkeledeur_Linksdraaiend:Merk a.sp zwart:5705137:1 | 00 begane grond |  | 1034 | 2462 | BaseQuantities - Depth: 123 mm
AL_32.i_Binnenkozijn-enkeledeur_Linksdraaiend:Merk a.sp:10064377:1 | 00 begane grond |  | 1034 | 2462 | BaseQuantities - Depth: 100 mm
AL_32.i_Binnenkozijn-enkeledeur_Linksdraaiend:Merk a.sp:5922921:1 | 00 begane grond |  | 1034 | 2462 | BaseQuantities - Depth: 123 mm
AL_32.i_Binnenkozijn-enkeledeur_Rechtsdraaiend:Merk a:5923011:1 | 00 begane grond |  | 1034 | 2462 | BaseQuantities - Depth: 123 mm
Basic Wall:NLRS_21_WA_kalkzandsteen_120mm_CS20_gen_aly:5631826 | 00 begane grond |  | 2400 | 2625 | BaseQuantities - Depth: 1215.49 mm
AL_32.i_Binnenkozijn-enkeledeur_Linksdraaiend:Merk a.sp:6068655:1 | 00 begane grond |  | 1034 | 2462 | BaseQuantities - Depth: 100 mm
4 x Basic Wall:NLRS_42_WA_Houten gevelbekleding staand 20mm:12431875 | 01 eerste verdieping | 42.12 binnenwandafwerkingen; bekledingen (Uniformat) | 1289 | 450 | Basic Wall:Model Lines | 2 | <Sketch> | 304.8 | Pset_ManufacturerTypeInformation - Manufacturer: NTB
Basic Wall:NLRS_42_WA_Houten gevelbekleding staand 20mm:12431875 | 01 eerste verdieping | 42.12 binnenwandafwerkingen; bekledingen (Uniformat) | 1708 | 450 | Basic Wall:Model Lines | 2 | <Sketch> | 304.8 | Pset_ManufacturerTypeInformation - Manufacturer: NTB
2 x Basic Wall:NLRS_42_WA_Houten gevelbekleding staand 20mm:12431875 | 01 eerste verdieping | 42.12 binnenwandafwerkingen; bekledingen (Uniformat) | 3078.36 | 1928 | Basic Wall:Model Lines | 2 | <Sketch> | 304.8 | Pset_ManufacturerTypeInformation - Manufacturer: NTB
3 x Basic Wall:NLRS_42_WA_Houten gevelbekleding liggend 26mm:3178170 | 00 begane grond | 42.12 binnenwandafwerkingen; bekledingen (Uniformat) | 1658 | 440 | Curtain Wall:NLRS_31_WIN_UN_houten kozijn vrij indeelbaar_gen_aly | 2 | Walls | BaseQuantities - Depth: 330.8 mm
3 x Basic Wall:NLRS_42_WA_Houten gevelbekleding liggend 26mm:3178170 | 00 begane grond | 42.12 binnenwandafwerkingen; bekledingen (Uniformat) | 1239 | 440 | Curtain Wall:NLRS_31_WIN_UN_houten kozijn vrij indeelbaar_gen_aly | 2 | Walls | BaseQuantities - Depth: 330.8 mm
AL_32.i_Binnenkozijn-enkeledeur_Rechtsdraaiend:Merk a:4547295:1 | 00 begane grond |  | 1034 | 2462 | BaseQuantities - Depth: 100 mm
2 x Basic Wall:NLRS_42_WA_Houten gevelbekleding liggend 26mm:3178170 | 00 begane grond | 42.12 binnenwandafwerkingen; bekledingen (Uniformat) | 700 | 440 | Curtain Wall:NLRS_31_WIN_UN_houten kozijn vrij indeelbaar_gen_aly | 2 | Walls | BaseQuantities - Depth: 330.8 mm
3 x Basic Wall:NLRS_42_WA_Houten gevelbekleding liggend 26mm:12431171 | 00 begane grond | 42.12 binnenwandafwerkingen; bekledingen (Uniformat) | 81 | 440 | Basic Wall:Model Lines | 2 | <Sketch> | 304.8 | Pset_ManufacturerTypeInformation - Manufacturer: NTB
7 x Basic Wall:NLRS_20_WA_Metselwerk 100mm, Eems wf-p-0081-25:7060662 | 00 begane grond | 21.11 buitenwanden; niet constructief, massieve wanden (Uniformat) | 1307.4 | 450 | Basic Wall:Model Lines | 2 | <Sketch> | 304.8
Basic Wall:NLRS_20_WA_Metselwerk 100mm, Eems wf-p-0081-25:7060662 | 00 begane grond | 21.11 buitenwanden; niet constructief, massieve wanden (Uniformat) | 379 | 1248.82 | Basic Wall:Model Lines | 2 | <Sketch> | 304.8
5 x Basic Wall:NLRS_21_WA_kalkzandsteen_120mm_CS20_gen_aly:589376 | 00 begane grond | 21.22 buitenwanden; constructief, spouwwanden (Uniformat) | 1210 | 414 | Basic Wall:Model Lines | 2 | <Sketch> | 304.8 | Pset_ManufacturerTypeInformation - Manufacturer: De RuwBouw Groep
2 x Basic Wall:NLRS_22_WA_LB_isolatie Kooltherm K8 105mm_Kingspan_BO:3214729 | 00 begane grond | 21.12 buitenwanden; niet constructief, spouwwanden (Uniformat) | 440 | 1239 | Curtain Wall:NLRS_31_WIN_UN_houten kozijn vrij indeelbaar_gen_aly | 2 | Walls | BaseQuantities - Depth: 409.8 mm
5 x Basic Wall:NLRS_22_WA_LB_isolatie Kooltherm K8 105mm_Kingspan_BO:5198351 | 00 begane grond | 21.12 buitenwanden; niet constructief, spouwwanden (Uniformat) | 506 | 1302 | Basic Wall:Model Lines | 2 | <Sketch> | 304.8 | Pset_ManufacturerTypeInformation - Manufacturer: Kingspan
AL_32.i_Binnenkozijn-enkeledeur_Rechtsdraaiend:Merk a:4315873:1 | 00 begane grond |  | 1034 | 2462 | BaseQuantities - Depth: 100 mm
Basic Wall:NLRS_21_WA_HSB-wand_98mm:3250677 | 01 eerste verdieping | 21.23 buitenwanden; constructief, systeemwanden (Uniformat) | 60 | 160 | Noodoverstort:Noodoverstort | 2 | Generic Models | BaseQuantities - Depth: 854.719 mm
Basic Wall:NLRS_21_WA_HSB-wand_98mm:3254027 | 01 eerste verdieping | 21.23 buitenwanden; constructief, systeemwanden (Uniformat) | 60 | 100 | Noodoverstort1:Noodoverstort | 2 | Generic Models | BaseQuantities - Depth: 801.605 mm
AL_32.i_Binnenkozijn-enkeledeur_Rechtsdraaiend:Merk a:4315872:1 | 00 begane grond |  | 1034 | 2462 | BaseQuantities - Depth: 100 mm
Floor:NLRS_23_FL_Trampeziumplaat 106R/750:3272956:2 | 01 eerste verdieping | 23.20 vloeren; constructief, algemeen (verzamelniveau) (Uniformat) |  |  | Floor:NLRS_23_FL_Trampeziumplaat 106R/750 | 2 | Floors | 304.8 | BaseQuantities - Depth: 108 mm; Area: 2.54466 m2
Basic Wall:NLRS_42_WA_Houten gevelbekleding staand 20mm:3274684 | 01 eerste verdieping | 42.12 binnenwandafwerkingen; bekledingen (Uniformat) | 60 | 100 | Noodoverstort1:Noodoverstort | 2 | Generic Models | BaseQuantities - Depth: 801.605 mm
Basic Wall:NLRS_42_WA_Houten gevelbekleding staand 20mm:12431875 | 01 eerste verdieping | 42.12 binnenwandafwerkingen; bekledingen (Uniformat) | 1305.67 | 7170.41 | Basic Wall:Model Lines | 2 | <Sketch> | 304.8 | Pset_ManufacturerTypeInformation - Manufacturer: NTB
Basic Wall:NLRS_21_WA_HSB-wand_149 (conform opgaaf constructeur):3275035 | 01 eerste verdieping | 21.23 buitenwanden; constructief, systeemwanden (Uniformat) | 60 | 100 | Noodoverstort1:Noodoverstort | 2 | Generic Models | BaseQuantities - Depth: 801.605 mm
Basic Wall:NLRS_20_WA_Metselwerk-100mm:3370089 | 00 begane grond | 21.11 buitenwanden; niet constructief, massieve wanden (Uniformat) | 2740 | 1034 | Curtain Wall:NLRS_31_WIN_UN_houten kozijn vrij indeelbaar_gen_aly | 2 | Walls | BaseQuantities - Depth: 404.8 mm
Basic Wall:NLRS_20_WA_Metselwerk-100mm:3370089 | 00 begane grond | 21.11 buitenwanden; niet constructief, massieve wanden (Uniformat) | 2460 | 1034 | Curtain Wall:NLRS_31_WIN_UN_houten kozijn vrij indeelbaar_gen_aly | 2 | Walls | BaseQuantities - Depth: 404.8 mm
Basic Wall:NLRS_20_WA_Metselwerk-100mm:3370089 | 00 begane grond | 21.11 buitenwanden; niet constructief, massieve wanden (Uniformat) | 2532 | 2091.03 | Curtain Wall:NLRS_31_WIN_UN_houten kozijn vrij indeelbaar_gen_aly | 2 | Walls | BaseQuantities - Depth: 404.8 mm
Basic Wall:NLRS_20_WA_Metselwerk-100mm:3375358 | 00 begane grond | 21.11 buitenwanden; niet constructief, massieve wanden (Uniformat) | 1034 | 2740 | Curtain Wall:NLRS_31_WIN_UN_houten kozijn vrij indeelbaar_gen_aly | 2 | Walls | BaseQuantities - Depth: 404.8 mm
Basic Wall:NLRS_20_WA_Metselwerk-100mm:3375358 | 00 begane grond | 21.11 buitenwanden; niet constructief, massieve wanden (Uniformat) | 1034 | 2460 | Curtain Wall:NLRS_31_WIN_UN_houten kozijn vrij indeelbaar_gen_aly | 2 | Walls | BaseQuantities - Depth: 404.8 mm
Basic Wall:NLRS_20_WA_Metselwerk-100mm:3376864 | 00 begane grond | 21.11 buitenwanden; niet constructief, massieve wanden (Uniformat) | 1034 | 2460 | Curtain Wall:NLRS_31_WIN_UN_houten kozijn vrij indeelbaar_gen_aly | 2 | Walls | BaseQuantities - Depth: 404.8 mm
Basic Wall:NLRS_20_WA_Metselwerk-100mm:3376864 | 00 begane grond | 21.11 buitenwanden; niet constructief, massieve wanden (Uniformat) | 1034 | 2740 | Curtain Wall:NLRS_31_WIN_UN_houten kozijn vrij indeelbaar_gen_aly | 2 | Walls | BaseQuantities - Depth: 404.8 mm
Basic Wall:NLRS_20_WA_Metselwerk-100mm:3376864 | 00 begane grond | 21.11 buitenwanden; niet constructief, massieve wanden (Uniformat) | 2091.03 | 2532 | Curtain Wall:NLRS_31_WIN_UN_houten kozijn vrij indeelbaar_gen_aly | 2 | Walls | BaseQuantities - Depth: 404.8 mm
Basic Wall:NLRS_21_WA_HSB-wand_110mm:3108389 | 01 eerste verdieping | 21.23 buitenwanden; constructief, systeemwanden (Uniformat) | 955 | 2450.74 | Basic Wall:Model Lines | 2 | <Sketch> | 304.8
Basic Wall:NLRS_21_WA_HSB-wand boven podium:7942589 | 01 eerste verdieping | 21.23 buitenwanden; constructief, systeemwanden (Uniformat) | 2860 | 28.7635 | Basic Wall:Model Lines | 2 | <Sketch> | 304.8
Basic Wall:NLRS_21_WA_HSB-wand boven podium:7942589 | 01 eerste verdieping | 21.23 buitenwanden; constructief, systeemwanden (Uniformat) | 245 | 108 | Basic Wall:Model Lines | 2 | <Sketch> | 304.8
Basic Wall:NLRS_20_WA_Metselwerk-100mm:3406380 | 00 begane grond | 21.11 buitenwanden; niet constructief, massieve wanden (Uniformat) | 2577 | 1510 | Curtain Wall:NLRS_31_WIN_UN_houten kozijn vrij indeelbaar_gen_aly | 2 | Walls | BaseQuantities - Depth: 404.8 mm
Basic Wall:NLRS_20_WA_Metselwerk-100mm:3407359 | 00 begane grond | 21.11 buitenwanden; niet constructief, massieve wanden (Uniformat) | 1062.89 | 2577 | Curtain Wall:NLRS_31_WIN_UN_houten kozijn vrij indeelbaar_gen_aly | 2 | Walls | BaseQuantities - Depth: 404.8 mm
AL_32.i_Binnenkozijn-enkeledeur_Linksdraaiend:Merk a.sp:4315871:1 | 00 begane grond |  | 1034 | 2462 | BaseQuantities - Depth: 100 mm
Basic Wall:NLRS_20_WA_Metselwerk-100mm:3407359 | 00 begane grond | 21.11 buitenwanden; niet constructief, massieve wanden (Uniformat) | 1518.22 | 2577 | Curtain Wall:NLRS_31_WIN_UN_houten kozijn vrij indeelbaar_gen_aly | 2 | Walls | BaseQuantities - Depth: 404.8 mm
Basic Wall:NLRS_20_WA_Metselwerk-100mm:3407439 | 00 begane grond | 21.11 buitenwanden; niet constructief, massieve wanden (Uniformat) | 1518.22 | 2577 | Curtain Wall:NLRS_31_WIN_UN_houten kozijn vrij indeelbaar_gen_aly | 2 | Walls | BaseQuantities - Depth: 404.8 mm
Basic Wall:NLRS_20_WA_Metselwerk-100mm:3407916:1 | 00 begane grond | 21.11 buitenwanden; niet constructief, massieve wanden (Uniformat) |  |  | Basic Wall:NLRS_20_WA_Metselwerk-100mm | 2 | Walls | 304.8 | BaseQuantities - Depth: 3186 mm; Area: 0.293032 m2
Basic Wall:NLRS_20_WA_Metselwerk-100mm:3407916:2 | 00 begane grond | 21.11 buitenwanden; niet constructief, massieve wanden (Uniformat) |  |  | Basic Wall:NLRS_20_WA_Metselwerk-100mm | 2 | Walls | 304.8 | BaseQuantities - Depth: 3186 mm; Area: 0.293032 m2
Basic Wall:NLRS_20_WA_Metselwerk-100mm:3407916:3 | 00 begane grond | 21.11 buitenwanden; niet constructief, massieve wanden (Uniformat) |  |  | Basic Wall:NLRS_20_WA_Metselwerk-100mm | 2 | Walls | 304.8 | BaseQuantities - Depth: 3186 mm; Area: 0.293032 m2
Basic Wall:NLRS_20_WA_Metselwerk-100mm:3412338 | 00 begane grond | 21.11 buitenwanden; niet constructief, massieve wanden (Uniformat) | 1591 | 2262 | Curtain Wall:NLRS_31_WIN_UN_houten kozijn vrij indeelbaar_gen_aly | 2 | Walls | BaseQuantities - Depth: 404.8 mm
Basic Wall:NLRS_20_WA_Metselwerk-100mm:2881791 | 00 begane grond | 21.11 buitenwanden; niet constructief, massieve wanden (Uniformat) | 2332 | 1595 | Basic Wall:Model Lines | 2 | <Sketch> | 304.8
Basic Wall:NLRS_20_WA_Metselwerk-100mm:2881791 | 00 begane grond | 21.11 buitenwanden; niet constructief, massieve wanden (Uniformat) | 934 | 2332 | Basic Wall:Model Lines | 2 | <Sketch> | 304.8
Basic Wall:NLRS_20_WA_Metselwerk-100mm:3412688 | 00 begane grond | 21.11 buitenwanden; niet constructief, massieve wanden (Uniformat) | 884 | 2262 | Curtain Wall:NLRS_31_WIN_UN_houten kozijn vrij indeelbaar_gen_aly | 2 | Walls | BaseQuantities - Depth: 404.8 mm
Basic Wall:NLRS_20_WA_Metselwerk-100mm:2881791 | 00 begane grond | 21.11 buitenwanden; niet constructief, massieve wanden (Uniformat) | 2192 | 884 | Basic Wall:Model Lines | 2 | <Sketch> | 304.8
Basic Wall:NLRS_20_WA_Metselwerk-100mm:2881791 | 00 begane grond | 21.11 buitenwanden; niet constructief, massieve wanden (Uniformat) | 2192 | 1034 | Basic Wall:Model Lines | 2 | <Sketch> | 304.8
AL_32.i_Binnenkozijn-enkeledeur_Linksdraaiend:Merk a.sp:5904195:1 | 00 begane grond |  | 1034 | 2462 | BaseQuantities - Depth: 100 mm
Floor:NLRS_23_FL_Houten balk laag 245mm met multiplex:3427480:2 | 01 eerste verdieping | 23.20 vloeren; constructief, algemeen (verzamelniveau) (Uniformat) |  |  | Floor:NLRS_23_FL_Houten balk laag 245mm met multiplex | 2 | Floors | 304.8 | BaseQuantities - Depth: 263 mm; Area: 2.54466 m2
2 x Basic Wall:NLRS_20_WA_Metselwerk 100mm, Gekeimd:3432280 | 00 begane grond | 21.11 buitenwanden; niet constructief, massieve wanden (Uniformat) | 2250.01 | 1995 | Curtain Wall:NLRS_31_WIN_UN_houten kozijn vrij indeelbaar_gen_aly | 2 | Walls | BaseQuantities - Depth: 404.8 mm
Basic Wall:NLRS_20_WA_Metselwerk 100mm, Gekeimd:7061500 | 00 begane grond | 21.11 buitenwanden; niet constructief, massieve wanden (Uniformat) | 2560 | 1995 | Basic Wall:Model Lines | 2 | <Sketch> | 304.8
Basic Wall:NLRS_20_WA_Metselwerk-100mm:3473679 | 00 begane grond | 21.11 buitenwanden; niet constructief, massieve wanden (Uniformat) | 2460 | 1034 | Curtain Wall:NLRS_31_WIN_UN_houten kozijn vrij indeelbaar_gen_aly | 2 | Walls | BaseQuantities - Depth: 404.8 mm
Basic Wall:NLRS_20_WA_Metselwerk-100mm:3473679 | 00 begane grond | 21.11 buitenwanden; niet constructief, massieve wanden (Uniformat) | 2740 | 1034 | Curtain Wall:NLRS_31_WIN_UN_houten kozijn vrij indeelbaar_gen_aly | 2 | Walls | BaseQuantities - Depth: 404.8 mm
Basic Wall:NLRS_21_WA_Metalstud 240mm:3532119:1 | 00 begane grond | 21.23 buitenwanden; constructief, systeemwanden (Uniformat) |  |  | Basic Wall:NLRS_21_WA_Metalstud 240mm | 2 | Walls | 304.8
Basic Wall:NLRS_21_WA_Metalstud 240mm:3532119 | 00 begane grond | 21.23 buitenwanden; constructief, systeemwanden (Uniformat) | 2776 | 100 | skygate-Enkele panelen en deuren (enkele richting draaibaar):Enkel taatsdeur model 1850mm | 2 | Doors | BaseQuantities - Depth: 1862 mm
Basic Wall:NLRS_21_WA_Metalstud 240mm:3532119 | 00 begane grond | 21.23 buitenwanden; constructief, systeemwanden (Uniformat) | 1991 | 2700 | Curtain Wall:NLRS_31_WIN_UN_houten kozijn vrij indeelbaar_gen_aly | 2 | Walls | BaseQuantities - Depth: 544.8 mm
Basic Wall:NLRS_21_WA_Metalstud 240mm:3700768 | 00 begane grond | 21.23 buitenwanden; constructief, systeemwanden (Uniformat) | 406.204 | 1974.5 | Basic Wall:Model Lines | 2 | <Sketch> | 304.8
Basic Wall:NLRS_21_WA_isolatie glaswol_160mm_gen_aly:3652084 | 00 begane grond | 21.10 buitenwanden; niet constructief, algemeen (verzamelniveau) (Uniformat) | 941.414 | 2650 | Basic Wall:Model Lines | 2 | <Sketch> | 304.8
AL_32.i_Binnenkozijn-enkeledeur_Rechtsdraaiend:Merk a:4315877:1 | 00 begane grond |  | 1034 | 2462 | BaseQuantities - Depth: 100 mm
AL_32.i_Binnenkozijn-enkeledeur_Rechtsdraaiend:Merk a:5904196:1 | 00 begane grond |  | 1034 | 2462 | BaseQuantities - Depth: 100 mm
AL_32.i_Binnenkozijn-enkeledeur_Linksdraaiend:Merk a.sp:4315874:1 | 00 begane grond |  | 1034 | 2462 | BaseQuantities - Depth: 100 mm
AL_32.i_Binnenkozijn-enkeledeur_Rechtsdraaiend:Merk a:4286790:1 | 00 begane grond |  | 1034 | 2462 | BaseQuantities - Depth: 100 mm
Basic Wall:NLRS_20_WA_Metselwerk 100mm, Eems wf-p-0081-25:3670986 | 00 begane grond | 21.11 buitenwanden; niet constructief, massieve wanden (Uniformat) | 440 | 1485 | Curtain Wall:NLRS_31_WIN_UN_houten kozijn vrij indeelbaar_gen_aly | 2 | Walls | BaseQuantities - Depth: 404.8 mm
Basic Wall:NLRS_20_WA_Metselwerk 100mm, Eems wf-p-0081-25:7060662 | 00 begane grond | 21.11 buitenwanden; niet constructief, massieve wanden (Uniformat) | 1545.04 | 450 | Basic Wall:Model Lines | 2 | <Sketch> | 304.8
Basic Wall:NLRS_20_WA_Metselwerk 100mm, Eems wf-p-0081-25:7060662 | 00 begane grond | 21.11 buitenwanden; niet constructief, massieve wanden (Uniformat) | 1541.9 | 450 | Basic Wall:Model Lines | 2 | <Sketch> | 304.8
AL_32.i_Binnenkozijn-enkeledeur_Linksdraaiend:Merk d.sp:6664101:1 | 00 begane grond |  | 884 | 2442 | BaseQuantities - Depth: 240 mm
AL_32.i_Binnenkozijn-enkeledeur_Linksdraaiend:Merk f.sp (2100mm hoog):3414985:1 | 00 begane grond |  | 784 | 2227 | BaseQuantities - Depth: 100 mm
AL_32.i_Binnenkozijn-enkeledeur_Linksdraaiend:Merk a.sp (2100mm hoog):3366338:1 | 00 begane grond |  | 1034 | 2242 | BaseQuantities - Depth: 100 mm
AL_32.i_Binnenkozijn-enkeledeur_Linksdraaiend:Merk a.sp (2100mm hoog):3366255:1 | 00 begane grond |  | 1034 | 2242 | BaseQuantities - Depth: 100 mm
Floor:43_Hetrogoen vinyl B1_70mm:3918445:2 | 00 begane grond | 43.21 vloerafwerkingen; niet verhoogd, afwerklagen (Uniformat) | 140 | 133 | Floor:43_Hetrogoen vinyl B1_70mm | 2 | Floors | 304.8 | BaseQuantities - Depth: 70 mm
Floor:43_gietvloer 5mm:3998646:2 | 00 begane grond | 43.21 vloerafwerkingen; niet verhoogd, afwerklagen (Uniformat) |  |  | Floor:43_gietvloer 5mm | 2 | Floors | 304.8 | BaseQuantities - Depth: 5 mm; Area: 1.78162 m2
 | 01 eerste verdieping
Floor:NLRS_23_FL_Pir dakisolatie 140mm:4039732:2 | 01 eerste verdieping | 23.11 vloeren; niet constructief, vrijdragende Vloeren (Uniformat) |  |  | Floor:NLRS_23_FL_Pir dakisolatie 140mm | 2 | Floors | 304.8 | BaseQuantities - Depth: 140 mm; Area: 2.95592 m2
AL_32.i_Binnenkozijn-enkeledeur_Rechtsdraaiend:Merk a (2100mm hog):3304326:1 | 00 begane grond |  | 1034 | 2242 | BaseQuantities - Depth: 100 mm
AL_32.i_Binnenkozijn-enkeledeur_Rechtsdraaiend:Merk f (2100mm hoog):3303502:1 | 00 begane grond |  | 784 | 2227 | BaseQuantities - Depth: 100 mm
AL_32.i_Binnenkozijn-enkeledeur_Rechtsdraaiend:Merk a (2000mm hoog):10295106:1 | 00 begane grond |  | 1034 | 2142 | BaseQuantities - Depth: 100 mm
skygate-Enkele panelen en deuren:Vast paneel model 2315:3148724:1 | 00 begane grond |  | 1012 | 2776 | BaseQuantities - Depth: 100 mm
AL_32.i_Binnenkozijn-enkeledeur_Linksdraaiend:Merk a.sp:3081175:1 | 00 begane grond |  | 1034 | 2462 | BaseQuantities - Depth: 100 mm
AL_32.i_Binnenkozijn-enkeledeur_Linksdraaiend met raampje:Merk a.sp:3080090:1 | 00 begane grond |  | 1034 | 2462 | BaseQuantities - Depth: 165 mm
AL_32.i_Binnenkozijn-enkeledeur_Rechtsdraaiend:Merk a (2100mm hoog) brandwerend:4329975:1 | 01 eerste verdieping |  | 1018 | 2242 | BaseQuantities - Depth: 100 mm
AL_32.i_Binnenkozijn-enkeledeur_Linksdraaiend:Merk a.sp brandwerend:3068143:1 | 01 eerste verdieping |  | 1018 | 2462 | BaseQuantities - Depth: 100 mm
AL_32.i_Binnenkozijn-enkeledeur_Linksdraaiend in de wand:Merk a.sp:9671885:1 | 00 begane grond |  | 1034 | 2462 | BaseQuantities - Depth: 100 mm
AL_32.i_Binnenkozijn-enkeledeur_Rechtsdraaiend:Merk a:10270975:1 | 00 begane grond |  | 1034 | 2462 | BaseQuantities - Depth: 100 mm
AL_32_Binnendeur-schuifdeur in de wand:2700x3400.sp:10599847:1 | 00 begane grond |  | 3400 | 2740 | BaseQuantities - Depth: 235 mm
AL_32_Binnendeur-schuifdeur in de wand:2700x3400:10578640:1 | 00 begane grond |  | 3400 | 2760 | BaseQuantities - Depth: 235 mm
AL_32_Binnendeur-schuifdeur in de wand:2700x3400:10600282:1 | 00 begane grond |  | 3400 | 2760 | BaseQuantities - Depth: 235 mm
AL_32_Binnendeur-schuifdeur in de wand:2700x3400:10600332:1 | 00 begane grond |  | 3400 | 2760 | BaseQuantities - Depth: 235 mm
AL_32.i_Binnenkozijn-enkeledeur_Linksdraaiend in de wand:Merk a.sp:2999823:1 | 00 begane grond |  | 1034 | 2462 | BaseQuantities - Depth: 100 mm
Basic Wall:NLRS_42_WA_Houten gevelbekleding staand 20mm:12431875 | 01 eerste verdieping | 42.12 binnenwandafwerkingen; bekledingen (Uniformat) | 1564 | 1838.25 | Basic Wall:Model Lines | 2 | <Sketch> | 304.8 | Pset_ManufacturerTypeInformation - Manufacturer: NTB
AL_32.i_Binnenkozijn-enkeledeur_Rechtsdraaiend:Merk g zwart:2999632:1 | 00 begane grond |  | 734 | 2442 | BaseQuantities - Depth: 100 mm
AL_32.i_Binnenkozijn-enkeledeur_Linksdraaiend:Merk a.sp:10064669:1 | 00 begane grond |  | 1034 | 2462 | BaseQuantities - Depth: 100 mm
Basic Wall:NLRS_21_WA_Metalstud 205mm:12617814 | 00 begane grond | 21.23 buitenwanden; constructief, systeemwanden (Uniformat) |  |  | Basic Wall:Model Lines | 2 | <Sketch> | 304.8 | BaseQuantities - Area: 0.241746 m2
AL_32.i_Binnenkozijn-enkeledeur_Linksdraaiend:Merk a.sp:2992812:1 | 00 begane grond |  | 1034 | 2462 | BaseQuantities - Depth: 100 mm
Basic Wall:NLRS_42_WA_Houten gevelbekleding staand 18mm:3155416 | 00 begane grond | 42.12 binnenwandafwerkingen; bekledingen (Uniformat) | 1043.86 | 2680 | Basic Wall:Model Lines | 2 | <Sketch> | 304.8 | Pset_ManufacturerTypeInformation - Manufacturer: NTB
Basic Wall:NLRS_21_WA_Metalstud 240mm:4450865 | 00 begane grond | 21.23 buitenwanden; constructief, systeemwanden (Uniformat) | 2600 | 2770 | Curtain Wall:NLRS_31_WIN_UN_houten kozijn vrij indeelbaar_gen_aly | 2 | Walls | BaseQuantities - Depth: 544.8 mm
Basic Wall:NLRS_21_WA_Metalstud 240mm:4450865 | 00 begane grond | 21.23 buitenwanden; constructief, systeemwanden (Uniformat) | 1691 | 2700 | Curtain Wall:NLRS_31_WIN_UN_houten kozijn vrij indeelbaar_gen_aly | 2 | Walls | BaseQuantities - Depth: 544.8 mm
Basic Wall:NLRS_20_WA_Metselwerk 100mm, Eems wf-p-0081-25:4556660:1 | 00 begane grond | 21.11 buitenwanden; niet constructief, massieve wanden (Uniformat) |  |  | Basic Wall:NLRS_20_WA_Metselwerk 100mm, Eems wf-p-0081-25 | 2 | Walls | 304.8
skygate-Enkele panelen en deuren:Vast paneel model 2315 RAL 9002:4325212:1 | 00 begane grond |  | 1012 | 2776 | BaseQuantities - Depth: 100 mm
AL_32.i_Binnenkozijn-enkeledeur_Rechtsdraaiend:Merk a:3146553:1 | 00 begane grond |  | 1034 | 2462 | BaseQuantities - Depth: 165 mm
2 x Basic Wall:NLRS_21_WA_HSB-wand onder podium 2:4622349 | 00 begane grond | 21.23 buitenwanden; constructief, systeemwanden (Uniformat) | 1886 | 1012 | Curtain Wall:NLRS_31_WIN_UN_houten kozijn vrij indeelbaar_gen_aly | 2 | Walls | BaseQuantities - Depth: 414.8 mm
2 x Basic Wall:NLRS_21_WA_HSB-wand onder podium 2:4622349 | 00 begane grond | 21.23 buitenwanden; constructief, systeemwanden (Uniformat) | 1886.41 | 1012 | Curtain Wall:NLRS_31_WIN_UN_houten kozijn vrij indeelbaar_gen_aly | 2 | Walls | BaseQuantities - Depth: 414.8 mm
2 x Basic Wall:NLRS_21_WA_HSB-wand onder podium 2:8994559 | 00 begane grond | 21.23 buitenwanden; constructief, systeemwanden (Uniformat) | 338.311 | 1886 | Basic Wall:Model Lines | 2 | <Sketch> | 304.8
Basic Wall:NLRS_21_WA_HSB-wand onder podium 2:8994559 | 00 begane grond | 21.23 buitenwanden; constructief, systeemwanden (Uniformat) | 338.311 | 1886.41 | Basic Wall:Model Lines | 2 | <Sketch> | 304.8
Basic Wall:NLRS_21_WA_HSB-wand onder podium 2:8994559 | 00 begane grond | 21.23 buitenwanden; constructief, systeemwanden (Uniformat) | 338.311 | 1887 | Basic Wall:Model Lines | 2 | <Sketch> | 304.8
Basic Wall:NLRS_21_WA_HSB werk 90mm:4886076 | 01 eerste verdieping | 21.23 buitenwanden; constructief, systeemwanden (Uniformat) |  |  | Basic Wall:Model Lines | 2 | <Sketch> | 304.8 | BaseQuantities - Area: 0.500447 m2
Basic Wall:NLRS_42_WA_beplating_zijkant hellend dak:4945661 | 01 eerste verdieping | 41.12 buitenwandafwerkingen; bekledingen (Uniformat) |  |  | Void roof soosruimte:Void roof soosruimte | 2 | Roofs | BaseQuantities - Depth: 30117.1 mm; Area: 18.722 m2
Basic Wall:NLRS_42_WA_beplating_zijkant hellend dak:3156557 | 01 eerste verdieping | 41.12 buitenwandafwerkingen; bekledingen (Uniformat) |  |  | Basic Wall:Model Lines | 2 | <Sketch> | 304.8 | Pset_ManufacturerTypeInformation - Manufacturer: NTB; BaseQuantities - Area: 6.33757 m2
Basic Wall:NLRS_42_WA_beplating_zijkant hellend dak:3156557 | 01 eerste verdieping | 41.12 buitenwandafwerkingen; bekledingen (Uniformat) | 186.5 | 940.813 | Basic Wall:Model Lines | 2 | <Sketch> | 304.8 | Pset_ManufacturerTypeInformation - Manufacturer: NTB
AL_32.i_Binnenkozijn-enkeledeur_Linksdraaiend:Merk a.sp:5642232:1 | 00 begane grond |  | 1034 | 2462 | BaseQuantities - Depth: 100 mm
AL_32.i_Binnenkozijn-enkeledeur_Rechtsdraaiend:Merk a:5642233:1 | 00 begane grond |  | 1034 | 2462 | BaseQuantities - Depth: 100 mm
Basic Wall:NLRS_22_WA_LB_isolatie Kooltherm K8 105mm_Kingspan_BO:5198351 | 00 begane grond | 21.12 buitenwanden; niet constructief, spouwwanden (Uniformat) | 2811 | 802 | Basic Wall:Model Lines | 2 | <Sketch> | 304.8 | Pset_ManufacturerTypeInformation - Manufacturer: Kingspan
AL_32.i_Binnenkozijn-enkeledeur_Rechtsdraaiend:Merk a:5642234:1 | 00 begane grond |  | 1034 | 2462 | BaseQuantities - Depth: 100 mm
AL_32.i_Binnenkozijn-enkeledeur_Rechtsdraaiend:Merk a:2992568:1 | 00 begane grond |  | 1034 | 2462 | BaseQuantities - Depth: 100 mm
2 x Basic Wall:NLRS_20_WA_Metselwerk 100mm, Eems wf-p-0081-25:5205086 | 00 begane grond | 21.11 buitenwanden; niet constructief, massieve wanden (Uniformat) | 440 | 1239 | Curtain Wall:NLRS_31_WIN_UN_houten kozijn vrij indeelbaar_gen_aly | 2 | Walls | BaseQuantities - Depth: 404.8 mm
Basic Wall:NLRS_20_WA_Metselwerk 100mm, Eems wf-p-0081-25:5205086 | 00 begane grond | 21.11 buitenwanden; niet constructief, massieve wanden (Uniformat) | 60 | 160 | Noodoverstort:Noodoverstort | 2 | Generic Models | BaseQuantities - Depth: 854.719 mm
2 x Basic Wall:NLRS_20_WA_Metselwerk 100mm, Eems wf-p-0081-25:7060662 | 00 begane grond | 21.11 buitenwanden; niet constructief, massieve wanden (Uniformat) | 1307.23 | 450 | Basic Wall:Model Lines | 2 | <Sketch> | 304.8
Basic Wall:NLRS_20_WA_Metselwerk 100mm, Eems wf-p-0081-25:7060662 | 00 begane grond | 21.11 buitenwanden; niet constructief, massieve wanden (Uniformat) | 2905 | 2500 | Basic Wall:Model Lines | 2 | <Sketch> | 304.8
AL_32.i_Binnenkozijn-enkeledeur_Linksdraaiend:Merk a.sp:5644603:1 | 00 begane grond |  | 1034 | 2462 | BaseQuantities - Depth: 100 mm
Basic Wall:NLRS_42_WA_Houten gevelbekleding staand 20mm:5329845 | 01 eerste verdieping | 42.12 binnenwandafwerkingen; bekledingen (Uniformat) |  |  | Void deur dakterras:Void deur dakterras | 2 | Walls | BaseQuantities - Depth: 664 mm; Area: 0.129861 m2
Basic Wall:NLRS_42_WA_Houten gevelbekleding staand 20mm:5329845 | 01 eerste verdieping | 42.12 binnenwandafwerkingen; bekledingen (Uniformat) | 450 | 1034 | Void deur naar dak:Void deur naar dak | 2 | Walls | BaseQuantities - Depth: 2422 mm
AL_32.i_Binnenkozijn-enkeledeur_Linksdraaiend:Merk a.sp:5644685:1 | 00 begane grond |  | 1034 | 2462 | BaseQuantities - Depth: 100 mm
AL_32.i_Binnenkozijn-enkeledeur_Rechtsdraaiend:Merk a:5644760:1 | 00 begane grond |  | 1034 | 2462 | BaseQuantities - Depth: 100 mm
AL_32.i_Binnenkozijn-enkeledeur_Linksdraaiend:Merk a.sp:2992293:1 | 00 begane grond |  | 1034 | 2462 | BaseQuantities - Depth: 100 mm
AL_32.i_Binnenkozijn-enkeledeur_Linksdraaiend:Merk a.sp:5633986:1 | 00 begane grond |  | 1034 | 2462 | BaseQuantities - Depth: 174 mm
AL_32.i_Binnenkozijn-enkeledeur_Linksdraaiend:Merk a.sp:5636404:1 | 00 begane grond |  | 1034 | 2462 | BaseQuantities - Depth: 100 mm
AL_32.i_Binnenkozijn-enkeledeur_Rechtsdraaiend:Merk a:5635857:1 | 00 begane grond |  | 1034 | 2462 | BaseQuantities - Depth: 100 mm
AL_32.i_Binnenkozijn-enkeledeur_Rechtsdraaiend:Merk a:5636405:1 | 00 begane grond |  | 1034 | 2462 | BaseQuantities - Depth: 100 mm
AL_32.i_Binnenkozijn-enkeledeur_Linksdraaiend:Merk a.sp:5635728:1 | 00 begane grond |  | 1034 | 2462 | BaseQuantities - Depth: 100 mm
AL_32.i_Binnenkozijn-enkeledeur_Linksdraaiend:Merk a.sp:4226510:1 | 00 begane grond |  | 1034 | 2462 | BaseQuantities - Depth: 100 mm
AL_32.i_Binnenkozijn-enkeledeur_Rechtsdraaiend:Merk a (2100mm hog):2858938:1 | 00 begane grond |  | 1034 | 2242 | BaseQuantities - Depth: 100 mm
AL_32.i_Binnenkozijn-enkeledeur_Linksdraaiend:Merk a.sp (2000mm hoog):2858009:1 | 00 begane grond |  | 1034 | 2142 | BaseQuantities - Depth: 100 mm
AL_32.i_Binnenkozijn-enkeledeur_Rechtsdraaiend:Merk a (2000mm hoog):2858045:1 | 00 begane grond |  | 1034 | 2142 | BaseQuantities - Depth: 100 mm
AL_32.i_Binnenkozijn-enkeledeur_Linksdraaiend:Merk e.sp (2000mm hoog):5722053:1 | 00 begane grond |  | 834 | 2127 | BaseQuantities - Depth: 100 mm
AL_32.i_Binnenkozijn-enkeledeur_Rechtsdraaiend:Merk e (2000mm hoog):2853173:1 | 00 begane grond |  | 834 | 2127 | BaseQuantities - Depth: 100 mm
AL_32.i_Binnenkozijn-enkeledeur_Linksdraaiend:Merk e.sp (2000mm hoog):5721811:1 | 00 begane grond |  | 834 | 2127 | BaseQuantities - Depth: 100 mm
AL_32.i_Binnenkozijn-enkeledeur_Rechtsdraaiend:Merk a (2100mm hog):3364924:1 | 00 begane grond |  | 1034 | 2242 | BaseQuantities - Depth: 100 mm
AL_32.i_Binnenkozijn-enkeledeur_Rechtsdraaiend:Merk g (2100mm hoog):5142247:1 | 00 begane grond |  | 734 | 2242 | BaseQuantities - Depth: 100 mm
AL_32.i_Binnenkozijn-enkeledeur_Linksdraaiend:Merk g.sp (2100mm hoog):5143078:1 | 00 begane grond |  | 734 | 2242 | BaseQuantities - Depth: 100 mm
AL_32.i_Binnenkozijn-enkeledeur_Rechtsdraaiend:Merk b (2000mm hoog):4998107:1 | 00 begane grond |  | 984 | 2147 | BaseQuantities - Depth: 100 mm
AL_32.i_Binnenkozijn-enkeledeur_Rechtsdraaiend:Merk g (2000mm hoog):3262618:1 | 00 begane grond |  | 734 | 2127 | BaseQuantities - Depth: 100 mm
Basic Wall:NLRS_21_WA_kalkzandsteen_100mm_gen_aly:2835225 | 00 begane grond |  | 2127 | 834 | BaseQuantities - Depth: 3048 mm
Basic Wall:NLRS_21_WA_Metalstud 100mm:5603887 | 00 begane grond | 21.23 buitenwanden; constructief, systeemwanden (Uniformat) | 1800 | 2156.51 | Curtain Wall:NLRS_31_WIN_UN_houten kozijn vrij indeelbaar_gen_aly | 2 | Walls | BaseQuantities - Depth: 404.8 mm
Basic Wall:NLRS_21_WA_Metalstud 100mm:3671798 | 00 begane grond | 21.23 buitenwanden; constructief, systeemwanden (Uniformat) | 1421 | 1838.51 | Basic Wall:Model Lines | 2 | <Sketch> | 304.8
Basic Wall:NLRS_21_WA_kalkzandsteen_120mm_CS20_gen_aly:589376 | 00 begane grond | 21.22 buitenwanden; constructief, spouwwanden (Uniformat) | 2462 | 1064 | Basic Wall:Model Lines | 2 | <Sketch> | 304.8 | Pset_ManufacturerTypeInformation - Manufacturer: De RuwBouw Groep
Basic Wall:NLRS_21_WA_Metalstud 100mm:5605097 | 00 begane grond | 21.23 buitenwanden; constructief, systeemwanden (Uniformat) | 2700 | 1991 | Curtain Wall:NLRS_31_WIN_UN_houten kozijn vrij indeelbaar_gen_aly | 2 | Walls | BaseQuantities - Depth: 404.8 mm
Basic Wall:NLRS_21_WA_Metalstud 100mm:5605097 | 00 begane grond | 21.23 buitenwanden; constructief, systeemwanden (Uniformat) | 2776 | 100 | skygate-Enkele panelen en deuren (enkele richting draaibaar):Enkel taatsdeur model 1850mm | 2 | Doors | BaseQuantities - Depth: 1862 mm
3 x Basic Wall:NLRS_21_WA_kalkzandsteen_120mm_CS20_gen_aly:589376 | 00 begane grond | 21.22 buitenwanden; constructief, spouwwanden (Uniformat) | 1226 | 414 | Basic Wall:Model Lines | 2 | <Sketch> | 304.8 | Pset_ManufacturerTypeInformation - Manufacturer: De RuwBouw Groep
Basic Wall:NLRS_21_WA_kalkzandsteen_120mm_CS20_gen_aly:589376 | 00 begane grond | 21.22 buitenwanden; constructief, spouwwanden (Uniformat) | 1225.9 | 414 | Basic Wall:Model Lines | 2 | <Sketch> | 304.8 | Pset_ManufacturerTypeInformation - Manufacturer: De RuwBouw Groep
Basic Wall:NLRS_21_WA_Metalstud 100mm:3671798 | 00 begane grond | 21.23 buitenwanden; constructief, systeemwanden (Uniformat) |  |  | Basic Wall:Model Lines | 2 | <Sketch> | 304.8 | BaseQuantities - Area: 0.435729 m2
Basic Wall:NLRS_22_WA_LB_isolatie Kooltherm K8 105mm_Kingspan_BO:5198351 | 00 begane grond | 21.12 buitenwanden; niet constructief, spouwwanden (Uniformat) | 3589.53 | 4.01692 | Basic Wall:Model Lines | 2 | <Sketch> | 304.8 | Pset_ManufacturerTypeInformation - Manufacturer: Kingspan
Basic Wall:NLRS_21_WA_kalkzandsteen_120mm_CS20_gen_aly:589376 | 00 begane grond | 21.22 buitenwanden; constructief, spouwwanden (Uniformat) | 289.958 | 2686 | Basic Wall:Model Lines | 2 | <Sketch> | 304.8 | Pset_ManufacturerTypeInformation - Manufacturer: De RuwBouw Groep
Basic Wall:NLRS_21_WA_kalkzandsteen_120mm_CS20_gen_aly:589376 | 00 begane grond | 21.22 buitenwanden; constructief, spouwwanden (Uniformat) | 2536.04 | 2686 | Basic Wall:Model Lines | 2 | <Sketch> | 304.8 | Pset_ManufacturerTypeInformation - Manufacturer: De RuwBouw Groep
Basic Wall:NLRS_21_WA_HSB-wand_123mm (conform opgaaf constructeur):5636550:1 | 00 begane grond | 21.23 buitenwanden; constructief, systeemwanden (Uniformat) |  |  | Basic Wall:NLRS_21_WA_HSB-wand_123mm (conform opgaaf constructeur) | 2 | Walls | 304.8
Basic Wall:NLRS_21_WA_HSB-wand_123mm (conform opgaaf constructeur):5636550 | 00 begane grond | 21.23 buitenwanden; constructief, systeemwanden (Uniformat) | 170 | 360.014 | Void dak soosruimte:Void dak soosruimte | 2 | Roofs | BaseQuantities - Depth: 12000 mm
Basic Wall:NLRS_20_WA_Metselwerk 100mm, Eems wf-p-0081-25:7060662 | 00 begane grond | 21.11 buitenwanden; niet constructief, massieve wanden (Uniformat) | 7822.53 | 2105.6 | Basic Wall:Model Lines | 2 | <Sketch> | 304.8
Floor:NLRS_23_FL_Houten balk laag 196mm:5663625:2 | 01 eerste verdieping | 23.20 vloeren; constructief, algemeen (verzamelniveau) (Uniformat) | 1190 | 690 | Floor:NLRS_23_FL_Houten balk laag 196mm | 2 | Floors | 304.8 | BaseQuantities - Depth: 196 mm
2 x Basic Wall:NLRS_21_WA_kalkzandsteen_120mm_CS20_gen_aly:589376 | 00 begane grond | 21.22 buitenwanden; constructief, spouwwanden (Uniformat) | 414 | 1451 | Basic Wall:Model Lines | 2 | <Sketch> | 304.8 | Pset_ManufacturerTypeInformation - Manufacturer: De RuwBouw Groep
Basic Wall:NLRS_21_WA_kalkzandsteen_120mm_CS20_gen_aly:589376 | 00 begane grond | 21.22 buitenwanden; constructief, spouwwanden (Uniformat) | 1451.8 | 414 | Basic Wall:Model Lines | 2 | <Sketch> | 304.8 | Pset_ManufacturerTypeInformation - Manufacturer: De RuwBouw Groep
Basic Wall:NLRS_21_WA_kalkzandsteen_120mm_CS20_gen_aly:589376 | 00 begane grond | 21.22 buitenwanden; constructief, spouwwanden (Uniformat) | 1450.9 | 414 | Basic Wall:Model Lines | 2 | <Sketch> | 304.8 | Pset_ManufacturerTypeInformation - Manufacturer: De RuwBouw Groep
Basic Wall:NLRS_21_WA_kalkzandsteen_120mm_CS20_gen_aly:589376 | 00 begane grond | 21.22 buitenwanden; constructief, spouwwanden (Uniformat) | 1451 | 414 | Basic Wall:Model Lines | 2 | <Sketch> | 304.8 | Pset_ManufacturerTypeInformation - Manufacturer: De RuwBouw Groep
Basic Wall:NLRS_21_WA_HSB-wand_268mm:5675717 | 01 eerste verdieping | 21.23 buitenwanden; constructief, systeemwanden (Uniformat) | 450 | 1034 | Void deur naar dak:Void deur naar dak | 2 | Walls | BaseQuantities - Depth: 2422 mm
Basic Wall:NLRS_21_WA_HSB-wand_268mm:5677948 | 01 eerste verdieping | 21.23 buitenwanden; constructief, systeemwanden (Uniformat) | 450 | 1034 | Void deur naar dak:Void deur naar dak | 2 | Walls | BaseQuantities - Depth: 2422 mm
Floor:NLRS_23_FL_Houten balk laag 196mm:5682992:2 | 01 eerste verdieping | 23.20 vloeren; constructief, algemeen (verzamelniveau) (Uniformat) |  |  | Floor:NLRS_23_FL_Houten balk laag 196mm | 2 | Floors | 304.8 | BaseQuantities - Depth: 196 mm; Area: 2.54466 m2
Basic Wall:47.11_2 laagse APP dakbedekking:5739595 | Podium | 47.11 dakafwerkingen; afwerkingen, vlakke dakafwerkingen (Uniformat) | 160 | 60 | Noodoverstort:Noodoverstort | 2 | Generic Models | BaseQuantities - Depth: 854.719 mm
3 x Basic Wall:NLRS_21_WA_HSB-wand_268mm (zonder gips):7911681 | 01 eerste verdieping | 21.23 buitenwanden; constructief, systeemwanden (Uniformat) | 414 | 1210 | Basic Wall:Model Lines | 2 | <Sketch> | 304.8
Basic Wall:NLRS_21_WA_HSB-wand_268mm (zonder gips):7911681 | 01 eerste verdieping | 21.23 buitenwanden; constructief, systeemwanden (Uniformat) | 414 | 1629 | Basic Wall:Model Lines | 2 | <Sketch> | 304.8
Basic Wall:NLRS_21_WA_HSB-wand_268mm (zonder gips):7911681 | 01 eerste verdieping | 21.23 buitenwanden; constructief, systeemwanden (Uniformat) | 414 | 1213 | Basic Wall:Model Lines | 2 | <Sketch> | 304.8
Basic Wall:47.11_2 laagse APP dakbedekking:5746478 | 01 eerste verdieping | 47.11 dakafwerkingen; afwerkingen, vlakke dakafwerkingen (Uniformat) | 100 | 60 | Noodoverstort1:Noodoverstort | 2 | Generic Models | BaseQuantities - Depth: 801.605 mm
2 x Basic Wall:NLRS_21_WA_Metalstud 240mm:5760074 | 00 begane grond | 21.23 buitenwanden; constructief, systeemwanden (Uniformat) | 1200 | 350 | Curtain Wall:NLRS_31_WIN_UN_houten kozijn vrij indeelbaar_gen_aly | 2 | Walls | BaseQuantities - Depth: 544.8 mm
Basic Wall:NLRS_21_WA_Metalstud 100mm:5762138 | 00 begane grond | 21.23 buitenwanden; constructief, systeemwanden (Uniformat) | 4350 | 2700 | Curtain Wall:NLRS_31_WIN_UN_houten kozijn vrij indeelbaar_gen_aly | 2 | Walls | BaseQuantities - Depth: 404.8 mm
Basic Wall:NLRS_21_WA_Metalstud 100mm:5762150 | 00 begane grond | 21.23 buitenwanden; constructief, systeemwanden (Uniformat) | 4350 | 2700 | Curtain Wall:NLRS_31_WIN_UN_houten kozijn vrij indeelbaar_gen_aly | 2 | Walls | BaseQuantities - Depth: 404.8 mm
Basic Wall:NLRS_21_WA_Metalstud 215:5762153 | 00 begane grond | 21.23 buitenwanden; constructief, systeemwanden (Uniformat) | 2462 | 100 |  |  | Doors | BaseQuantities - Depth: 1034 mm; Pset_DoorCommon - IsExternal: no; Reference: AL_32.i_Binnenkozijn-enkeledeur_Linksdraaiend:Merk a.sp; Pset_QuantityTakeOff - Reference: AL_32.i_Binnenkozijn-enkeledeur_Linksdraaiend:Merk a.sp
Basic Wall:NLRS_21_WA_Metalstud 100mm:5764710 | 00 begane grond | 21.23 buitenwanden; constructief, systeemwanden (Uniformat) | 1034 | 2462 | AL_32.i_Binnenkozijn-enkeledeur_Linksdraaiend:Merk a.sp | 2 | Doors | BaseQuantities - Depth: 3048 mm
Basic Wall:NLRS_21_WA_Metalstud 100mm:5764710 | 00 begane grond | 21.23 buitenwanden; constructief, systeemwanden (Uniformat) | 1034 | 2392 | Curtain Wall:NLRS_31_WIN_UN_houten kozijn vrij indeelbaar_gen_aly | 2 | Walls | BaseQuantities - Depth: 404.8 mm
Basic Wall:NLRS_21_WA_Metalstud 100mm:5765120 | 00 begane grond | 21.23 buitenwanden; constructief, systeemwanden (Uniformat) | 2392 | 1034 | Curtain Wall:NLRS_31_WIN_UN_houten kozijn vrij indeelbaar_gen_aly | 2 | Walls | BaseQuantities - Depth: 404.8 mm
Basic Wall:NLRS_21_WA_Metalstud 100mm:5765120 | 00 begane grond | 21.23 buitenwanden; constructief, systeemwanden (Uniformat) | 1034 | 2392 | Curtain Wall:NLRS_31_WIN_UN_houten kozijn vrij indeelbaar_gen_aly | 2 | Walls | BaseQuantities - Depth: 404.8 mm
2 x Basic Wall:NLRS_21_WA_Metalstud 100mm:3671798 | 00 begane grond | 21.23 buitenwanden; constructief, systeemwanden (Uniformat) | 1470 | 708 | Basic Wall:Model Lines | 2 | <Sketch> | 304.8
Basic Wall:NLRS_21_WA_Metalstud 100mm:3671798 | 00 begane grond | 21.23 buitenwanden; constructief, systeemwanden (Uniformat) | 2462 | 1000 | Basic Wall:Model Lines | 2 | <Sketch> | 304.8
Basic Wall:NLRS_20_WA_Metselwerk 100mm, Eems wf-p-0081-25:7060662 | 00 begane grond | 21.11 buitenwanden; niet constructief, massieve wanden (Uniformat) | 2672 | 1082 | Basic Wall:Model Lines | 2 | <Sketch> | 304.8
Basic Wall:NLRS_42_WA_Houten gevelbekleding staand 20mm:12431875 | 01 eerste verdieping | 42.12 binnenwandafwerkingen; bekledingen (Uniformat) | 927 | 23258.2 | Basic Wall:Model Lines | 2 | <Sketch> | 304.8 | Pset_ManufacturerTypeInformation - Manufacturer: NTB
Basic Wall:NLRS_42_WA_Houten gevelbekleding staand 20mm:12431875 | 01 eerste verdieping | 42.12 binnenwandafwerkingen; bekledingen (Uniformat) | 48.6316 | 237.829 | Basic Wall:Model Lines | 2 | <Sketch> | 304.8 | Pset_ManufacturerTypeInformation - Manufacturer: NTB
Basic Wall:NLRS_42_WA_Houten gevelbekleding staand 20mm:12431875 | 01 eerste verdieping | 42.12 binnenwandafwerkingen; bekledingen (Uniformat) | 237.829 | 50.3184 | Basic Wall:Model Lines | 2 | <Sketch> | 304.8 | Pset_ManufacturerTypeInformation - Manufacturer: NTB
Basic Wall:NLRS_42_WA_beplating_zijkant hellend dak:5844555 | 01 eerste verdieping | 41.12 buitenwandafwerkingen; bekledingen (Uniformat) |  |  | Void roof soosruimte:Void roof soosruimte | 2 | Roofs | BaseQuantities - Depth: 30117.1 mm; Area: 18.722 m2
Basic Wall:NLRS_42_WA_beplating_zijkant hellend dak:3156557 | 01 eerste verdieping | 41.12 buitenwandafwerkingen; bekledingen (Uniformat) | 550.219 | 32.9528 | Basic Wall:Model Lines | 2 | <Sketch> | 304.8 | Pset_ManufacturerTypeInformation - Manufacturer: NTB
Floor:NLRS_44_FL_Multiplex 18mm:5846797:2 | 01 eerste verdieping | 44.10 trap- en hellingafwerkingen; trapafwerkingen, algemeen (verzamelniveau) (Uniformat) | 1190 | 690 | Floor:NLRS_44_FL_Multiplex 18mm | 2 | Floors | 304.8 | BaseQuantities - Depth: 18 mm
Basic Wall:NLRS_42_WA_Houten gevelbekleding staand 20mm:12431875 | 01 eerste verdieping | 42.12 binnenwandafwerkingen; bekledingen (Uniformat) |  |  | Basic Wall:Model Lines | 2 | <Sketch> | 304.8 | Pset_ManufacturerTypeInformation - Manufacturer: NTB; BaseQuantities - Area: 0.140293 m2
Basic Wall:NLRS_42_WA_Houten gevelbekleding staand 20mm:12431875 | 01 eerste verdieping | 42.12 binnenwandafwerkingen; bekledingen (Uniformat) |  |  | Basic Wall:Model Lines | 2 | <Sketch> | 304.8 | Pset_ManufacturerTypeInformation - Manufacturer: NTB; BaseQuantities - Area: 0.271127 m2
Basic Wall:NLRS_42_WA_Houten gevelbekleding staand 20mm:12431875 | 01 eerste verdieping | 42.12 binnenwandafwerkingen; bekledingen (Uniformat) |  |  | Basic Wall:Model Lines | 2 | <Sketch> | 304.8 | Pset_ManufacturerTypeInformation - Manufacturer: NTB; BaseQuantities - Area: 0.236307 m2
Basic Wall:NLRS_42_WA_Houten gevelbekleding staand 20mm:12431875 | 01 eerste verdieping | 42.12 binnenwandafwerkingen; bekledingen (Uniformat) |  |  | Basic Wall:Model Lines | 2 | <Sketch> | 304.8 | Pset_ManufacturerTypeInformation - Manufacturer: NTB; BaseQuantities - Area: 0.232107 m2
Basic Wall:NLRS_22_WA_LB_isolatie Kooltherm K8 105mm_Kingspan_BO:5198351 | 01 eerste verdieping | 21.12 buitenwanden; niet constructief, spouwwanden (Uniformat) |  |  | Basic Wall:Model Lines | 2 | <Sketch> | 304.8 | Pset_ManufacturerTypeInformation - Manufacturer: Kingspan; BaseQuantities - Area: 0.0868194 m2
Basic Wall:NLRS_21_WA_Metalstud 100mm:5904193:1 | 00 begane grond | 21.23 buitenwanden; constructief, systeemwanden (Uniformat) |  |  | Basic Wall:NLRS_21_WA_Metalstud 100mm | 2 | Walls | 304.8
Basic Wall:NLRS_21_WA_Metalstud 300mm:5946912 | 00 begane grond | 21.23 buitenwanden; constructief, systeemwanden (Uniformat) | 1975 | 2700 | Curtain Wall:NLRS_31_WIN_UN_houten kozijn vrij indeelbaar_gen_aly | 2 | Walls | BaseQuantities - Depth: 604.8 mm
Basic Wall:NLRS_21_WA_Metalstud 300mm:5915343 | 00 begane grond | 21.23 buitenwanden; constructief, systeemwanden (Uniformat) | 348.92 | 1958.5 | Basic Wall:Model Lines | 2 | <Sketch> | 304.8
Basic Wall:NLRS_21_WA_Metalstud 300mm:5915343 | 00 begane grond | 21.23 buitenwanden; constructief, systeemwanden (Uniformat) | 3806.5 | 1270 | Basic Wall:Model Lines | 2 | <Sketch> | 304.8
Basic Wall:NLRS_21_WA_HSB-wand_110mm:3108389 | 01 eerste verdieping | 21.23 buitenwanden; constructief, systeemwanden (Uniformat) | 476.736 | 615 | Basic Wall:Model Lines | 2 | <Sketch> | 304.8
Basic Wall:NLRS_21_WA_HSB-wand_110mm:3108389 | 01 eerste verdieping | 21.23 buitenwanden; constructief, systeemwanden (Uniformat) | 615 | 1672 | Basic Wall:Model Lines | 2 | <Sketch> | 304.8
Basic Wall:47.11_2 laagse APP dakbedekking:5739501 | 01 eerste verdieping | 47.11 dakafwerkingen; afwerkingen, vlakke dakafwerkingen (Uniformat) |  |  | Basic Wall:Model Lines | 2 | <Sketch> | 304.8 | Pset_ManufacturerTypeInformation - Manufacturer: 2 laagse APP 460P60 onderlaag met 446K14 toplaag; BaseQuantities - Area: 0.00858706 m2
2 x Basic Wall:NLRS_21_WA_HSB-wand_110mm:3108389 | 01 eerste verdieping | 21.23 buitenwanden; constructief, systeemwanden (Uniformat) |  |  | Basic Wall:Model Lines | 2 | <Sketch> | 304.8 | BaseQuantities - Area: 0.00267659 m2
Basic Wall:47.11_2 laagse APP dakbedekking:5739501 | 01 eerste verdieping | 47.11 dakafwerkingen; afwerkingen, vlakke dakafwerkingen (Uniformat) |  |  | Basic Wall:Model Lines | 2 | <Sketch> | 304.8 | Pset_ManufacturerTypeInformation - Manufacturer: 2 laagse APP 460P60 onderlaag met 446K14 toplaag; BaseQuantities - Area: 0.0287086 m2
Basic Wall:47.11_2 laagse APP dakbedekking:5739501 | 01 eerste verdieping | 47.11 dakafwerkingen; afwerkingen, vlakke dakafwerkingen (Uniformat) | 97.474 | 3319.19 | Basic Wall:Model Lines | 2 | <Sketch> | 304.8 | Pset_ManufacturerTypeInformation - Manufacturer: 2 laagse APP 460P60 onderlaag met 446K14 toplaag
Basic Wall:47.11_2 laagse APP dakbedekking:5739501 | 01 eerste verdieping | 47.11 dakafwerkingen; afwerkingen, vlakke dakafwerkingen (Uniformat) |  |  | Basic Wall:Model Lines | 2 | <Sketch> | 304.8 | Pset_ManufacturerTypeInformation - Manufacturer: 2 laagse APP 460P60 onderlaag met 446K14 toplaag; BaseQuantities - Area: 0.522302 m2
Basic Wall:NLRS_41_WA_plaatmateriaal 18mm zwart:10004068 | 01 eerste verdieping | 41.12 buitenwandafwerkingen; bekledingen (Uniformat) | 3810.35 | 2168 | Basic Wall:Model Lines | 2 | <Sketch> | 304.8 | Pset_ManufacturerTypeInformation - Manufacturer: NTB
Basic Wall:NLRS_41_WA_plaatmateriaal 18mm zwart:10004068 | 01 eerste verdieping | 41.12 buitenwandafwerkingen; bekledingen (Uniformat) | 2168 | 2913.63 | Basic Wall:Model Lines | 2 | <Sketch> | 304.8 | Pset_ManufacturerTypeInformation - Manufacturer: NTB
Basic Wall:NLRS_41_WA_Bekleding kolommen:6197132 | 01 eerste verdieping | 41.12 buitenwandafwerkingen; bekledingen (Uniformat) | 212 | 6706.55 | Basic Wall:Model Lines | 2 | <Sketch> | 304.8 | Pset_ManufacturerTypeInformation - Manufacturer: NTB
Basic Wall:NLRS_41_WA_Bekleding kolommen:6197132 | 01 eerste verdieping | 41.12 buitenwandafwerkingen; bekledingen (Uniformat) | 288.411 | 166 | Basic Wall:Model Lines | 2 | <Sketch> | 304.8 | Pset_ManufacturerTypeInformation - Manufacturer: NTB
Basic Wall:NLRS_41_WA_Bekleding kolommen:6197132 | 01 eerste verdieping | 41.12 buitenwandafwerkingen; bekledingen (Uniformat) | 1120 | 8148.55 | Basic Wall:Model Lines | 2 | <Sketch> | 304.8 | Pset_ManufacturerTypeInformation - Manufacturer: NTB
Basic Wall:NLRS_20_WA_Metselwerk-100mm:6266200 | ok. fundering | 21.11 buitenwanden; niet constructief, massieve wanden (Uniformat) | 2142 | 1034 | AL_32.i_Binnenkozijn-enkeledeur_Linksdraaiend:Merk a.sp (2000mm hoog) | 2 | Doors | BaseQuantities - Depth: 3048 mm
Basic Wall:NLRS_20_WA_Metselwerk-100mm:6266200 | ok. fundering | 21.11 buitenwanden; niet constructief, massieve wanden (Uniformat) | 2142 | 1034 | AL_32.i_Binnenkozijn-enkeledeur_Rechtsdraaiend:Merk a (2000mm hoog) | 2 | Doors | BaseQuantities - Depth: 3048 mm
Basic Wall:NLRS_41_WA_Bekleding kolommen:6197132 | 01 eerste verdieping | 41.12 buitenwandafwerkingen; bekledingen (Uniformat) | 80 | 80 | Basic Wall:Model Lines | 2 | <Sketch> | 304.8 | Pset_ManufacturerTypeInformation - Manufacturer: NTB
Basic Wall:NLRS_41_WA_Bekleding kolommen:6197132 | 01 eerste verdieping | 41.12 buitenwandafwerkingen; bekledingen (Uniformat) |  |  | Basic Wall:Model Lines | 2 | <Sketch> | 304.8 | Pset_ManufacturerTypeInformation - Manufacturer: NTB; BaseQuantities - Area: 0.0834581 m2
Basic Wall:NLRS_41_WA_Bekleding kolommen:6197132 | 01 eerste verdieping | 41.12 buitenwandafwerkingen; bekledingen (Uniformat) | 140 | 2620 | Basic Wall:Model Lines | 2 | <Sketch> | 304.8 | Pset_ManufacturerTypeInformation - Manufacturer: NTB
Basic Wall:NLRS_41_WA_Bekleding kolommen:6197132 | 01 eerste verdieping | 41.12 buitenwandafwerkingen; bekledingen (Uniformat) |  |  | Basic Wall:Model Lines | 2 | <Sketch> | 304.8 | Pset_ManufacturerTypeInformation - Manufacturer: NTB; BaseQuantities - Area: 25.9543 m2
Basic Wall:NLRS_21_WA_HSB-wand_114mm:5914580 | Podium | 21.23 buitenwanden; constructief, systeemwanden (Uniformat) | 231 | 27.4706 | Basic Wall:Model Lines | 2 | <Sketch> | 304.8
Basic Wall:NLRS_21_WA_HSB-wand_110mm:3108389 | Podium | 21.23 buitenwanden; constructief, systeemwanden (Uniformat) | 168 | 916 | Basic Wall:Model Lines | 2 | <Sketch> | 304.8
Basic Wall:NLRS_21_WA_HSB-wand_110mm:3108389 | Podium | 21.23 buitenwanden; constructief, systeemwanden (Uniformat) | 168 | 929.706 | Basic Wall:Model Lines | 2 | <Sketch> | 304.8
Basic Wall:47.11_2 laagse APP dakbedekking:6409693:1 | 02 tweede verdieping | 47.11 dakafwerkingen; afwerkingen, vlakke dakafwerkingen (Uniformat) |  |  | Basic Wall:47.11_2 laagse APP dakbedekking | 2 | Walls | 304.8 | Pset_ManufacturerTypeInformation - Manufacturer: 2 laagse APP 460P60 onderlaag met 446K14 toplaag
Basic Wall:47.11_2 laagse APP dakbedekking:6409693:2 | 02 tweede verdieping | 47.11 dakafwerkingen; afwerkingen, vlakke dakafwerkingen (Uniformat) |  |  | Basic Wall:47.11_2 laagse APP dakbedekking | 2 | Walls | 304.8 | Pset_ManufacturerTypeInformation - Manufacturer: 2 laagse APP 460P60 onderlaag met 446K14 toplaag
Basic Wall:47.11_2 laagse APP dakbedekking:5739501 | Podium | 47.11 dakafwerkingen; afwerkingen, vlakke dakafwerkingen (Uniformat) | 180.044 | 132.5 | Basic Wall:Model Lines | 2 | <Sketch> | 304.8 | Pset_ManufacturerTypeInformation - Manufacturer: 2 laagse APP 460P60 onderlaag met 446K14 toplaag
Basic Wall:NLRS_21_WA_HSB-wand_114mm:6514039 | 00 begane grond | 21.23 buitenwanden; constructief, systeemwanden (Uniformat) | 1691 | 2700 | Curtain Wall:NLRS_31_WIN_UN_houten kozijn vrij indeelbaar_gen_aly | 2 | Walls | BaseQuantities - Depth: 418.8 mm
Basic Wall:NLRS_21_WA_Metalstud 63mm (eenzijdig):6520510:1 | 01 eerste verdieping | 21.23 buitenwanden; constructief, systeemwanden (Uniformat) |  |  | Basic Wall:NLRS_21_WA_Metalstud 63mm (eenzijdig) | 2 | Walls | 304.8
Basic Wall:NLRS_21_WA_HSB-wand_217mm:3944083 | 01 eerste verdieping | 21.23 buitenwanden; constructief, systeemwanden (Uniformat) |  |  | Basic Wall:Model Lines | 2 | <Sketch> | 304.8 | BaseQuantities - Area: 0.0125621 m2
Basic Wall:NLRS_41_WA_Bekleding kolommen:6197132 | 01 eerste verdieping | 41.12 buitenwandafwerkingen; bekledingen (Uniformat) |  |  | Basic Wall:Model Lines | 2 | <Sketch> | 304.8 | Pset_ManufacturerTypeInformation - Manufacturer: NTB; BaseQuantities - Area: 1.19095 m2
Basic Wall:NLRS_41_WA_Bekleding kolommen:6197132 | 01 eerste verdieping | 41.12 buitenwandafwerkingen; bekledingen (Uniformat) |  |  | Basic Wall:Model Lines | 2 | <Sketch> | 304.8 | Pset_ManufacturerTypeInformation - Manufacturer: NTB; BaseQuantities - Area: 0.97402 m2
Basic Wall:NLRS_41_WA_Bekleding kolommen:6197132 | 01 eerste verdieping | 41.12 buitenwandafwerkingen; bekledingen (Uniformat) | 1060 | 50 | Basic Wall:Model Lines | 2 | <Sketch> | 304.8 | Pset_ManufacturerTypeInformation - Manufacturer: NTB
Basic Wall:NLRS_41_WA_Bekleding kolommen:6197132 | 01 eerste verdieping | 41.12 buitenwandafwerkingen; bekledingen (Uniformat) | 1182 | 880 | Basic Wall:Model Lines | 2 | <Sketch> | 304.8 | Pset_ManufacturerTypeInformation - Manufacturer: NTB
Basic Wall:NLRS_41_WA_Bekleding kolommen:6197132 | 01 eerste verdieping | 41.12 buitenwandafwerkingen; bekledingen (Uniformat) | 880 | 61 | Basic Wall:Model Lines | 2 | <Sketch> | 304.8 | Pset_ManufacturerTypeInformation - Manufacturer: NTB
Basic Wall:NLRS_22_WA_LB_isolatie Kooltherm K8 105mm_Kingspan_BO:6614048:1 | 00 begane grond | 21.12 buitenwanden; niet constructief, spouwwanden (Uniformat) |  |  | Basic Wall:NLRS_22_WA_LB_isolatie Kooltherm K8 105mm_Kingspan_BO | 2 | Walls | 304.8 | Pset_ManufacturerTypeInformation - Manufacturer: Kingspan
Basic Wall:NLRS_22_WA_LB_isolatie Kooltherm K8 105mm_Kingspan_BO:5198351 | 00 begane grond | 21.12 buitenwanden; niet constructief, spouwwanden (Uniformat) | 3252 | 114.5 | Basic Wall:Model Lines | 2 | <Sketch> | 304.8 | Pset_ManufacturerTypeInformation - Manufacturer: Kingspan
Basic Wall:NLRS_20_WA_Metselwerk 100mm, Eems wf-p-0081-25:7060662 | 01 eerste verdieping | 21.11 buitenwanden; niet constructief, massieve wanden (Uniformat) | 725 | 183.49 | Basic Wall:Model Lines | 2 | <Sketch> | 304.8
Basic Wall:NLRS_41_WA_Bekleding kolommen:6197132 | 01 eerste verdieping | 41.12 buitenwandafwerkingen; bekledingen (Uniformat) | 41 | 1032.5 | Basic Wall:Model Lines | 2 | <Sketch> | 304.8 | Pset_ManufacturerTypeInformation - Manufacturer: NTB
Basic Wall:NLRS_41_WA_Bekleding kolommen:6197132 | 01 eerste verdieping | 41.12 buitenwandafwerkingen; bekledingen (Uniformat) | 935 | 1100 | Basic Wall:Model Lines | 2 | <Sketch> | 304.8 | Pset_ManufacturerTypeInformation - Manufacturer: NTB
3 x Basic Wall:NLRS_21_WA_HSB-wand_98mm:5197356 | 01 eerste verdieping | 21.23 buitenwanden; constructief, systeemwanden (Uniformat) | 1034 | 2177 | Basic Wall:Model Lines | 2 | <Sketch> | 304.8
Basic Wall:NLRS_16_WA_funderingsbalk 350x...mm_gen_aly:6646691:1 | ok. fundering | 16.12 funderingsconstructies; voeten en balken, fundatie balken (Uniformat) |  |  | Basic Wall:NLRS_16_WA_funderingsbalk 350x...mm_gen_aly | 2 | Walls | 304.8 | Group: Model Group:Nieuwe fundering:6653684
Basic Wall:NLRS_21_WA_kalkzandsteen_120mm_CS20_gen_aly:589376 | 00 begane grond | 21.22 buitenwanden; constructief, spouwwanden (Uniformat) | 1239 | 414 | Basic Wall:Model Lines | 2 | <Sketch> | 304.8 | Pset_ManufacturerTypeInformation - Manufacturer: De RuwBouw Groep
Basic Wall:NLRS_21_WA_kalkzandsteen_120mm_CS20_gen_aly:589376 | 00 begane grond | 21.22 buitenwanden; constructief, spouwwanden (Uniformat) | 700 | 396 | Basic Wall:Model Lines | 2 | <Sketch> | 304.8 | Pset_ManufacturerTypeInformation - Manufacturer: De RuwBouw Groep
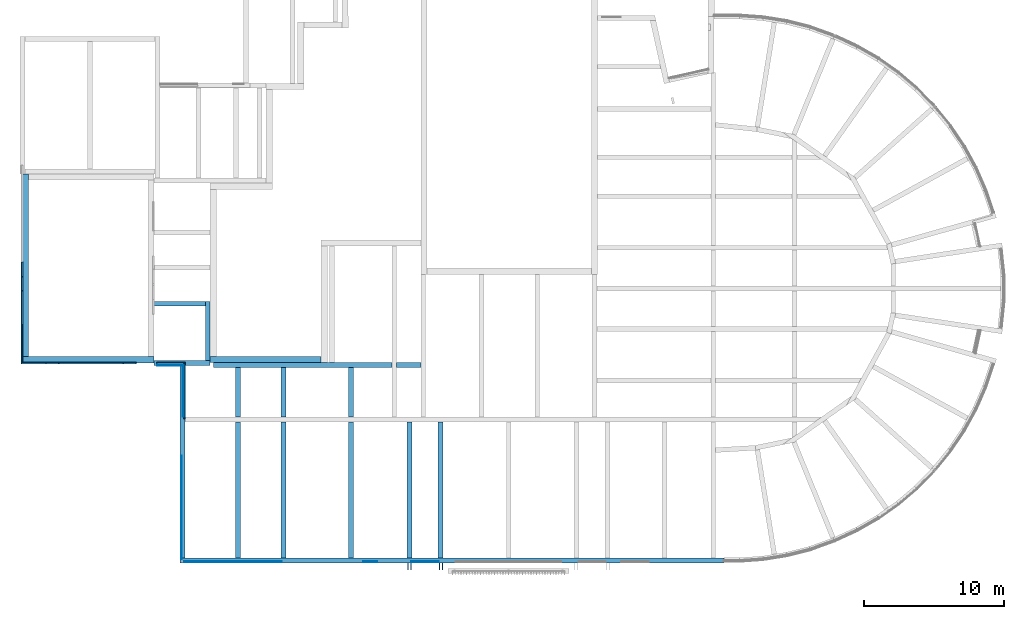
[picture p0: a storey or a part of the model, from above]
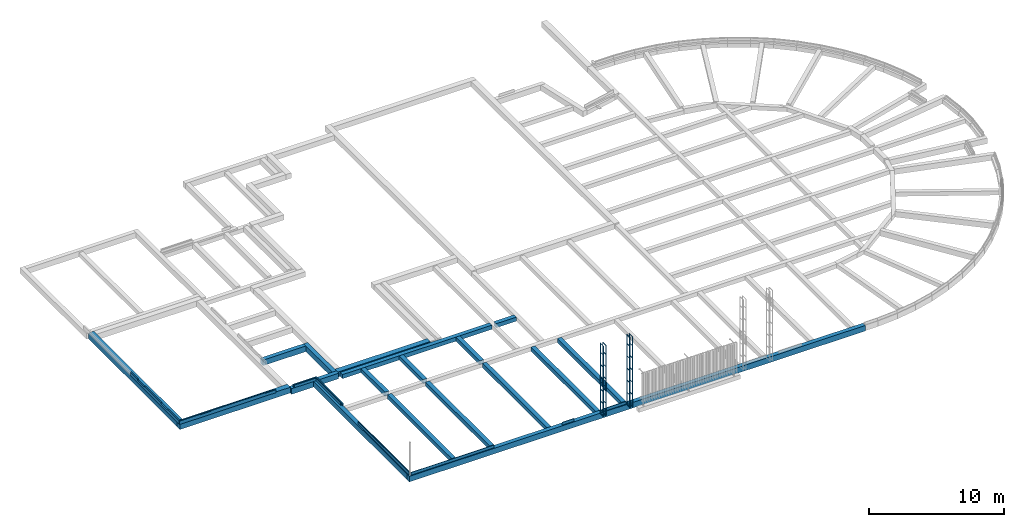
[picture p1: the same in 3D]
Properties of the parts of a building model (IFC2X3), part 7 of 13

# IfcOpeningElement: Opening (433)
Name | In | Classification | Height (mm) | Width (mm) | Pset_OpeningElementCommon, Reference | sets with these values | Category | Roughness (mm)
Basic Wall:NLRS_21_WA_kalkzandsteen_120mm_CS20_gen_aly:589376 | 00 begane grond | 21.22 buitenwanden; constructief, spouwwanden (Uniformat) | 700 | 414 | Basic Wall:Model Lines | 2 | <Sketch> | 304.8 | Pset_ManufacturerTypeInformation - Manufacturer: De RuwBouw Groep
Basic Wall:NLRS_21_WA_kalkzandsteen_120mm_CS20_gen_aly:589376 | 00 begane grond | 21.22 buitenwanden; constructief, spouwwanden (Uniformat) | 1233 | 414 | Basic Wall:Model Lines | 2 | <Sketch> | 304.8 | Pset_ManufacturerTypeInformation - Manufacturer: De RuwBouw Groep
Floor:NLRS_44_FL_Multiplex 18mm:6677478:2 | 01 eerste verdieping | 44.10 trap- en hellingafwerkingen; trapafwerkingen, algemeen (verzamelniveau) (Uniformat) |  |  | Floor:NLRS_44_FL_Multiplex 18mm | 2 | Floors | 304.8 | BaseQuantities - Depth: 18 mm; Area: 2.60152 m2
Basic Wall:NLRS_22_WA_LB_isolatie PIR 100mm:6176205 | ok. fundering | 21.12 buitenwanden; niet constructief, spouwwanden (Uniformat) | 50 | 927.977 | Basic Wall:Model Lines | 2 | <Sketch> | 304.8 | Pset_ManufacturerTypeInformation - Manufacturer: Kingspan
Basic Wall:NLRS_22_WA_LB_isolatie PIR 100mm:6176205 | ok. fundering | 21.12 buitenwanden; niet constructief, spouwwanden (Uniformat) | 50 | 926.485 | Basic Wall:Model Lines | 2 | <Sketch> | 304.8 | Pset_ManufacturerTypeInformation - Manufacturer: Kingspan
2 x Basic Wall:NLRS_20_WA_Metselwerk-100mm licht grijs gekeimd:6942828 | 00 begane grond | 21.11 buitenwanden; niet constructief, massieve wanden (Uniformat) | 2250.01 | 1995 | Curtain Wall:NLRS_31_WIN_UN_houten kozijn vrij indeelbaar_gen_aly | 2 | Walls | BaseQuantities - Depth: 404.8 mm
Basic Wall:NLRS_20_WA_Metselwerk-100mm licht grijs gekeimd:6940287 | 00 begane grond | 21.11 buitenwanden; niet constructief, massieve wanden (Uniformat) | 2180 | 2095 | Basic Wall:Model Lines | 2 | <Sketch> | 304.8
Basic Wall:NLRS_20_WA_Metselwerk-100mm licht grijs gekeimd:6940287 | 00 begane grond | 21.11 buitenwanden; niet constructief, massieve wanden (Uniformat) | 2262 | 1596.5 | Basic Wall:Model Lines | 2 | <Sketch> | 304.8
3 x Basic Wall:NLRS_21_WA_kalkzandsteen_120mm_CS20_gen_aly:589376 | 00 begane grond | 21.22 buitenwanden; constructief, spouwwanden (Uniformat) | 1658 | 414 | Basic Wall:Model Lines | 2 | <Sketch> | 304.8 | Pset_ManufacturerTypeInformation - Manufacturer: De RuwBouw Groep
Basic Wall:NLRS_21_WA_kalkzandsteen_120mm_CS20_gen_aly:589376 | 00 begane grond | 21.22 buitenwanden; constructief, spouwwanden (Uniformat) | 1254 | 414 | Basic Wall:Model Lines | 2 | <Sketch> | 304.8 | Pset_ManufacturerTypeInformation - Manufacturer: De RuwBouw Groep
2 x Basic Wall:NLRS_22_WA_LB_isolatie Kooltherm K8 105mm_Kingspan_BO:7372341 | 00 begane grond | 21.12 buitenwanden; niet constructief, spouwwanden (Uniformat) | 1239 | 440 | Curtain Wall:NLRS_31_WIN_UN_houten kozijn vrij indeelbaar_gen_aly | 2 | Walls | BaseQuantities - Depth: 409.8 mm
Basic Wall:NLRS_22_WA_LB_isolatie Kooltherm K8 105mm_Kingspan_BO:7372341 | 00 begane grond | 21.12 buitenwanden; niet constructief, spouwwanden (Uniformat) | 160 | 60 | Noodoverstort:Noodoverstort | 2 | Generic Models | BaseQuantities - Depth: 854.719 mm
Basic Wall:NLRS_22_WA_LB_isolatie Kooltherm K8 105mm_Kingspan_BO:5198351 | 00 begane grond | 21.12 buitenwanden; niet constructief, spouwwanden (Uniformat) | 2880 | 2500 | Basic Wall:Model Lines | 2 | <Sketch> | 304.8 | Pset_ManufacturerTypeInformation - Manufacturer: Kingspan
Basic Wall:NLRS_20_WA_Metselwerk-100mm:2881791 | 00 begane grond | 21.11 buitenwanden; niet constructief, massieve wanden (Uniformat) | 97 | 1071.5 | Basic Wall:Model Lines | 2 | <Sketch> | 304.8
Basic Wall:NLRS_20_WA_Metselwerk-100mm:2881791 | 00 begane grond | 21.11 buitenwanden; niet constructief, massieve wanden (Uniformat) | 84.953 | 2091.94 | Basic Wall:Model Lines | 2 | <Sketch> | 304.8
Basic Wall:NLRS_21_WA_Metalstud 63mm (eenzijdig):6662219 | 00 begane grond | 21.23 buitenwanden; constructief, systeemwanden (Uniformat) | 112 | 971.19 | Basic Wall:Model Lines | 2 | <Sketch> | 304.8
Basic Wall:NLRS_21_WA_Metalstud 200mm (gang school):7750672 | 00 begane grond | 21.23 buitenwanden; constructief, systeemwanden (Uniformat) | 2142 | 100 | AL_32.i_Binnenkozijn-enkeledeur_Linksdraaiend:Merk a.sp (2000mm hoog) | 2 | Doors | BaseQuantities - Depth: 1034 mm
Basic Wall:NLRS_21_WA_Metalstud 200mm (gang school):12688013 | 00 begane grond | 21.23 buitenwanden; constructief, systeemwanden (Uniformat) |  |  | Basic Wall:Model Lines | 2 | <Sketch> | 304.8 | BaseQuantities - Area: 0.264382 m2
Basic Wall:NLRS_21_WA_Metalstud 200mm (gang school):7751134 | 00 begane grond | 21.23 buitenwanden; constructief, systeemwanden (Uniformat) | 2142 | 100 | AL_32.i_Binnenkozijn-enkeledeur_Linksdraaiend:Merk a.sp (2000mm hoog) | 2 | Doors | BaseQuantities - Depth: 1034 mm
Basic Wall:NLRS_21_WA_Metalstud 200mm (gang school):12688013 | 00 begane grond | 21.23 buitenwanden; constructief, systeemwanden (Uniformat) |  |  | Basic Wall:Model Lines | 2 | <Sketch> | 304.8 | BaseQuantities - Area: 0.409695 m2
Basic Wall:NLRS_21_WA_Metalstud 205mm:12617814 | 00 begane grond | 21.23 buitenwanden; constructief, systeemwanden (Uniformat) |  |  | Basic Wall:Model Lines | 2 | <Sketch> | 304.8 | BaseQuantities - Area: 0.408321 m2
Basic Wall:NLRS_21_WA_Metalstud 63mm (eenzijdig):6662219 | 00 begane grond | 21.23 buitenwanden; constructief, systeemwanden (Uniformat) | 1054.12 | 2134.95 | Basic Wall:Model Lines | 2 | <Sketch> | 304.8
Basic Wall:NLRS_21_WA_Metalstud 63mm (eenzijdig):6662219 | 00 begane grond | 21.23 buitenwanden; constructief, systeemwanden (Uniformat) | 2134.95 | 1075.3 | Basic Wall:Model Lines | 2 | <Sketch> | 304.8
Basic Wall:NLRS_21_WA_Metalstud 63mm (eenzijdig):6662219 | 00 begane grond | 21.23 buitenwanden; constructief, systeemwanden (Uniformat) | 1120 | 2162 | Basic Wall:Model Lines | 2 | <Sketch> | 304.8
Basic Wall:NLRS_21_WA_Metalstud 63mm (eenzijdig):6662219 | 00 begane grond | 21.23 buitenwanden; constructief, systeemwanden (Uniformat) | 2162 | 1110.5 | Basic Wall:Model Lines | 2 | <Sketch> | 304.8
Basic Wall:NLRS_21_WA_Metalstud 63mm (eenzijdig):6662219 | 00 begane grond | 21.23 buitenwanden; constructief, systeemwanden (Uniformat) | 523.25 | 2147 | Basic Wall:Model Lines | 2 | <Sketch> | 304.8
Basic Wall:NLRS_21_WA_Metalstud 63mm (eenzijdig):6662219 | 00 begane grond | 21.23 buitenwanden; constructief, systeemwanden (Uniformat) | 2077 | 548.25 | Basic Wall:Model Lines | 2 | <Sketch> | 304.8
Basic Wall:47.11_2 laagse APP dakbedekking:5739501 | 01 eerste verdieping | 47.11 dakafwerkingen; afwerkingen, vlakke dakafwerkingen (Uniformat) | 226.339 | 393 | Basic Wall:Model Lines | 2 | <Sketch> | 304.8 | Pset_ManufacturerTypeInformation - Manufacturer: 2 laagse APP 460P60 onderlaag met 446K14 toplaag
Basic Wall:NLRS_21_WA_Metalstud 165:7969953 | 00 begane grond | 21.23 buitenwanden; constructief, systeemwanden (Uniformat) | 2462 | 100 |  |  | Doors | BaseQuantities - Depth: 1034 mm; Pset_DoorCommon - IsExternal: no; Reference: AL_32.i_Binnenkozijn-enkeledeur_Linksdraaiend:Merk a.sp; Pset_QuantityTakeOff - Reference: AL_32.i_Binnenkozijn-enkeledeur_Linksdraaiend:Merk a.sp
Basic Wall:47.11_2 laagse APP dakbedekking:5739501 | 01 eerste verdieping | 47.11 dakafwerkingen; afwerkingen, vlakke dakafwerkingen (Uniformat) |  |  | Basic Wall:Model Lines | 2 | <Sketch> | 304.8 | Pset_ManufacturerTypeInformation - Manufacturer: 2 laagse APP 460P60 onderlaag met 446K14 toplaag; BaseQuantities - Area: 0.0144532 m2
Basic Wall:NLRS_21_WA_HSB-wand_110mm:3108389 | 02 tweede verdieping | 21.23 buitenwanden; constructief, systeemwanden (Uniformat) |  |  | Basic Wall:Model Lines | 2 | <Sketch> | 304.8 | BaseQuantities - Area: 1.37897 m2
Basic Wall:NLRS_21_WA_Gipsplaat 12.5mm:6637965 | 01 eerste verdieping | 21.23 buitenwanden; constructief, systeemwanden (Uniformat) | 60 | 9560.78 | Basic Wall:Model Lines | 2 | <Sketch> | 304.8
Basic Wall:NLRS_41_WA_plaatmateriaal 9mm_gen_aly:7251882 | 00 begane grond | 41.12 buitenwandafwerkingen; bekledingen (Uniformat) | 2700 | 4142.81 | Basic Wall:Model Lines | 2 | <Sketch> | 304.8 | Pset_ManufacturerTypeInformation - Manufacturer: NTB
Basic Wall:NLRS_41_WA_plaatmateriaal 9mm_gen_aly:7251882 | 00 begane grond | 41.12 buitenwandafwerkingen; bekledingen (Uniformat) |  |  | Basic Wall:Model Lines | 2 | <Sketch> | 304.8 | Pset_ManufacturerTypeInformation - Manufacturer: NTB; BaseQuantities - Area: 20.2541 m2
Basic Wall:NLRS_41_WA_plaatmateriaal 9mm_gen_aly:7251882 | 00 begane grond | 41.12 buitenwandafwerkingen; bekledingen (Uniformat) | 2700 | 1990 | Basic Wall:Model Lines | 2 | <Sketch> | 304.8 | Pset_ManufacturerTypeInformation - Manufacturer: NTB
Basic Wall:NLRS_41_WA_plaatmateriaal 9mm_gen_aly:7251882 | 00 begane grond | 41.12 buitenwandafwerkingen; bekledingen (Uniformat) | 6313.84 | 160 | Basic Wall:Model Lines | 2 | <Sketch> | 304.8 | Pset_ManufacturerTypeInformation - Manufacturer: NTB
Basic Wall:NLRS_21_WA_Metalstud 100mm:3671798 | 00 begane grond | 21.23 buitenwanden; constructief, systeemwanden (Uniformat) | 207.25 | 1115 | Basic Wall:Model Lines | 2 | <Sketch> | 304.8
Basic Wall:NLRS_42_WA_Trespa RAL 7035 - 10mm:9006755 | 00 begane grond | 42.12 binnenwandafwerkingen; bekledingen (Uniformat) | 60 | 100 | Noodoverstort1:Noodoverstort | 2 | Generic Models | BaseQuantities - Depth: 801.605 mm
Noodoverstort:Noodoverstort:9070054:1 | 01 eerste verdieping |  | 160 | 565.297 | Noodoverstort:Noodoverstort | 2 | Generic Models | BaseQuantities - Depth: 60 mm
Noodoverstort:Noodoverstort:9070054:2 | 01 eerste verdieping |  | 160 | 565.297 | Noodoverstort:Noodoverstort | 2 | Generic Models | BaseQuantities - Depth: 60 mm
Noodoverstort:Noodoverstort:9070054:3 | 01 eerste verdieping |  | 160 | 565.297 | Noodoverstort:Noodoverstort | 2 | Generic Models | BaseQuantities - Depth: 60 mm
Noodoverstort:Noodoverstort:9070054:4 | 01 eerste verdieping |  | 160 | 565.297 | Noodoverstort:Noodoverstort | 2 | Generic Models | BaseQuantities - Depth: 60 mm
Noodoverstort1:Noodoverstort:9084768:1 | 01 eerste verdieping |  | 100 | 423.197 | Noodoverstort1:Noodoverstort | 2 | Generic Models | BaseQuantities - Depth: 60 mm
Noodoverstort1:Noodoverstort:9084768:2 | 01 eerste verdieping |  | 100 | 423.197 | Noodoverstort1:Noodoverstort | 2 | Generic Models | BaseQuantities - Depth: 60 mm
Noodoverstort1:Noodoverstort:9084768:3 | 01 eerste verdieping |  | 100 | 423.197 | Noodoverstort1:Noodoverstort | 2 | Generic Models | BaseQuantities - Depth: 60 mm
Noodoverstort1:Noodoverstort:9084768:4 | 01 eerste verdieping |  | 100 | 423.197 | Noodoverstort1:Noodoverstort | 2 | Generic Models | BaseQuantities - Depth: 60 mm
Basic Wall:47.11_2 laagse APP dakbedekking:5739501 | 01 eerste verdieping | 47.11 dakafwerkingen; afwerkingen, vlakke dakafwerkingen (Uniformat) | 18697.6 | 63.5899 | Basic Wall:Model Lines | 2 | <Sketch> | 304.8 | Pset_ManufacturerTypeInformation - Manufacturer: 2 laagse APP 460P60 onderlaag met 446K14 toplaag
Basic Wall:NLRS_21_WA_isolatie glaswol_200mm_gen_aly:9176637 | 00 begane grond | 21.10 buitenwanden; niet constructief, algemeen (verzamelniveau) (Uniformat) | 60 | 100 | Noodoverstort1:Noodoverstort | 2 | Generic Models | BaseQuantities - Depth: 801.605 mm
Basic Wall:NLRS_42_WA_Houten gevelbekleding staand 20mm:12431875 | 00 begane grond | 42.12 binnenwandafwerkingen; bekledingen (Uniformat) | 899.999 | 2333 | Basic Wall:Model Lines | 2 | <Sketch> | 304.8 | Pset_ManufacturerTypeInformation - Manufacturer: NTB
Basic Wall:NLRS_42_WA_Houten gevelbekleding staand 20mm:12431875 | 00 begane grond | 42.12 binnenwandafwerkingen; bekledingen (Uniformat) | 9182 | 2372 | Basic Wall:Model Lines | 2 | <Sketch> | 304.8 | Pset_ManufacturerTypeInformation - Manufacturer: NTB
Basic Wall:NLRS_41_WA_Kantplank:6934078 | 00 begane grond | 41.12 buitenwandafwerkingen; bekledingen (Uniformat) | 933.985 | 90 | Basic Wall:Model Lines | 2 | <Sketch> | 304.8 | Pset_ManufacturerTypeInformation - Manufacturer: NTB
Basic Wall:NLRS_41_WA_Kantplank:6934078 | 00 begane grond | 41.12 buitenwandafwerkingen; bekledingen (Uniformat) | 90 | 936.449 | Basic Wall:Model Lines | 2 | <Sketch> | 304.8 | Pset_ManufacturerTypeInformation - Manufacturer: NTB
Basic Wall:NLRS_22_WA_LB_isolatie PIR 100mm:6176205 | ok. fundering | 21.12 buitenwanden; niet constructief, spouwwanden (Uniformat) | 80 | 1024.92 | Basic Wall:Model Lines | 2 | <Sketch> | 304.8 | Pset_ManufacturerTypeInformation - Manufacturer: Kingspan
Basic Wall:NLRS_22_WA_LB_isolatie PIR 100mm:6176205 | ok. fundering | 21.12 buitenwanden; niet constructief, spouwwanden (Uniformat) | 80 | 1025.71 | Basic Wall:Model Lines | 2 | <Sketch> | 304.8 | Pset_ManufacturerTypeInformation - Manufacturer: Kingspan
Basic Wall:NLRS_22_WA_LB_isolatie PIR 100mm:6176205 | ok. fundering | 21.12 buitenwanden; niet constructief, spouwwanden (Uniformat) | 20 | 6294.98 | Basic Wall:Model Lines | 2 | <Sketch> | 304.8 | Pset_ManufacturerTypeInformation - Manufacturer: Kingspan
Basic Wall:NLRS_41_WA_Kantplank:6934078 | 00 begane grond | 41.12 buitenwandafwerkingen; bekledingen (Uniformat) | 90 | 1035.05 | Basic Wall:Model Lines | 2 | <Sketch> | 304.8 | Pset_ManufacturerTypeInformation - Manufacturer: NTB
Basic Wall:NLRS_41_WA_Kantplank:6934078 | 00 begane grond | 41.12 buitenwandafwerkingen; bekledingen (Uniformat) | 90 | 1034.73 | Basic Wall:Model Lines | 2 | <Sketch> | 304.8 | Pset_ManufacturerTypeInformation - Manufacturer: NTB
Basic Wall:NLRS_41_WA_Kantplank:6934078 | 00 begane grond | 41.12 buitenwandafwerkingen; bekledingen (Uniformat) | 20 | 6294.76 | Basic Wall:Model Lines | 2 | <Sketch> | 304.8 | Pset_ManufacturerTypeInformation - Manufacturer: NTB
Basic Wall:NLRS_22_WA_LB_isolatie PIR 70mm:5546022 | 00 begane grond | 21.12 buitenwanden; niet constructief, spouwwanden (Uniformat) | 2510 | 2095 | Basic Wall:Model Lines | 2 | <Sketch> | 304.8 | Pset_ManufacturerTypeInformation - Manufacturer: Kingspan
Basic Wall:NLRS_42_WA_Houten gevelbekleding staand 20mm:12431875 | 00 begane grond | 42.12 binnenwandafwerkingen; bekledingen (Uniformat) |  |  | Basic Wall:Model Lines | 2 | <Sketch> | 304.8 | Pset_ManufacturerTypeInformation - Manufacturer: NTB; BaseQuantities - Area: 0.00447697 m2
2 x Basic Wall:NLRS_42_WA_Houten gevelbekleding staand 20mm:12431875 | 01 eerste verdieping | 42.12 binnenwandafwerkingen; bekledingen (Uniformat) |  |  | Basic Wall:Model Lines | 2 | <Sketch> | 304.8 | Pset_ManufacturerTypeInformation - Manufacturer: NTB; BaseQuantities - Area: 0.00196323 m2
3 x Basic Wall:NLRS_41_WA_Geperforeerde plaat:9495851 | 01 eerste verdieping | 41.12 buitenwandafwerkingen; bekledingen (Uniformat) | 180 | 495.365 | Basic Wall:Model Lines | 2 | <Sketch> | 304.8 | Pset_ManufacturerTypeInformation - Manufacturer: NTB
Basic Wall:NLRS_41_WA_Geperforeerde plaat:9495851 | 01 eerste verdieping | 41.12 buitenwandafwerkingen; bekledingen (Uniformat) | 615 | 13436 | Basic Wall:Model Lines | 2 | <Sketch> | 304.8 | Pset_ManufacturerTypeInformation - Manufacturer: NTB
Basic Wall:NLRS_41_WA_Geperforeerde plaat:9495851 | 01 eerste verdieping | 41.12 buitenwandafwerkingen; bekledingen (Uniformat) | 3403.5 | 615 | Basic Wall:Model Lines | 2 | <Sketch> | 304.8 | Pset_ManufacturerTypeInformation - Manufacturer: NTB
Basic Wall:NLRS_41_WA_Geperforeerde plaat:9495851 | 01 eerste verdieping | 41.12 buitenwandafwerkingen; bekledingen (Uniformat) | 1860.3 | 9815.08 | Basic Wall:Model Lines | 2 | <Sketch> | 304.8 | Pset_ManufacturerTypeInformation - Manufacturer: NTB
3 x Basic Wall:NLRS_41_WA_Geperforeerde plaat:9495851 | 01 eerste verdieping | 41.12 buitenwandafwerkingen; bekledingen (Uniformat) | 495.348 | 180 | Basic Wall:Model Lines | 2 | <Sketch> | 304.8 | Pset_ManufacturerTypeInformation - Manufacturer: NTB
Basic Wall:NLRS_41_WA_plaatmateriaal 18mm RAL 9002:7855681 | 00 begane grond | 41.12 buitenwandafwerkingen; bekledingen (Uniformat) | 122 | 1793.83 | Basic Wall:Model Lines | 2 | <Sketch> | 304.8 | Pset_ManufacturerTypeInformation - Manufacturer: NTB
Basic Wall:NLRS_41_WA_plaatmateriaal 18mm zwart:10004068 | 01 eerste verdieping | 41.12 buitenwandafwerkingen; bekledingen (Uniformat) |  |  | Basic Wall:Model Lines | 2 | <Sketch> | 304.8 | Pset_ManufacturerTypeInformation - Manufacturer: NTB; BaseQuantities - Area: 0.931281 m2
Basic Wall:NLRS_41_WA_plaatmateriaal 18mm zwart:10004068 | 01 eerste verdieping | 41.12 buitenwandafwerkingen; bekledingen (Uniformat) | 6279.11 | 122.582 | Basic Wall:Model Lines | 2 | <Sketch> | 304.8 | Pset_ManufacturerTypeInformation - Manufacturer: NTB
Basic Wall:NLRS_41_WA_plaatmateriaal 18mm zwart:10004068 | 01 eerste verdieping | 41.12 buitenwandafwerkingen; bekledingen (Uniformat) |  |  | Basic Wall:Model Lines | 2 | <Sketch> | 304.8 | Pset_ManufacturerTypeInformation - Manufacturer: NTB; BaseQuantities - Area: 6.29304 m2
Basic Wall:NLRS_21_WA_Metalstud 100mm:10062329 | 00 begane grond | 21.23 buitenwanden; constructief, systeemwanden (Uniformat) | 2462 | 100 |  |  | Doors | BaseQuantities - Depth: 1034 mm; Pset_DoorCommon - IsExternal: no; Reference: AL_32.i_Binnenkozijn-enkeledeur_Linksdraaiend:Merk a.sp; Pset_QuantityTakeOff - Reference: AL_32.i_Binnenkozijn-enkeledeur_Linksdraaiend:Merk a.sp
Basic Wall:NLRS_22_WA_LB_isolatie Kooltherm K8 105mm_Kingspan_BO:5198351 | 00 begane grond | 21.12 buitenwanden; niet constructief, spouwwanden (Uniformat) | 2909.87 | 354 | Basic Wall:Model Lines | 2 | <Sketch> | 304.8 | Pset_ManufacturerTypeInformation - Manufacturer: Kingspan
Basic Wall:NLRS_20_WA_Metselwerk 100mm, Eems wf-p-0081-25:7060662 | 00 begane grond | 21.11 buitenwanden; niet constructief, massieve wanden (Uniformat) | 758.1 | 2769.87 | Basic Wall:Model Lines | 2 | <Sketch> | 304.8
Basic Wall:NLRS_21_WA_kalkzandsteen_120mm_CS20_gen_aly:589376 | 00 begane grond | 21.22 buitenwanden; constructief, spouwwanden (Uniformat) | 2770 | 710 | Basic Wall:Model Lines | 2 | <Sketch> | 304.8 | Pset_ManufacturerTypeInformation - Manufacturer: De RuwBouw Groep
Basic Wall:NLRS_21_WA_Metalstud 240mm:10357999:1 | 00 begane grond | 21.23 buitenwanden; constructief, systeemwanden (Uniformat) |  |  | Basic Wall:NLRS_21_WA_Metalstud 240mm | 2 | Walls | 304.8
Basic Wall:NLRS_21_WA_Metalstud 240mm:10357999:2 | 00 begane grond | 21.23 buitenwanden; constructief, systeemwanden (Uniformat) |  |  | Basic Wall:NLRS_21_WA_Metalstud 240mm | 2 | Walls | 304.8
Basic Wall:NLRS_41_WA_Bekleding kolommen:6197132 | 01 eerste verdieping | 41.12 buitenwandafwerkingen; bekledingen (Uniformat) | 26.3381 | 100 | Basic Wall:Model Lines | 2 | <Sketch> | 304.8 | Pset_ManufacturerTypeInformation - Manufacturer: NTB
Basic Wall:NLRS_21_WA_isolatie glaswol_200mm_gen_aly:3181683 | 00 begane grond | 21.10 buitenwanden; niet constructief, algemeen (verzamelniveau) (Uniformat) | 1615 | 3986 | Basic Wall:Model Lines | 2 | <Sketch> | 304.8
Basic Wall:NLRS_20_WA_Metselwerk-100mm:12474738 | 00 begane grond | 21.11 buitenwanden; niet constructief, massieve wanden (Uniformat) | 1034 | 2460 | Curtain Wall:NLRS_31_WIN_UN_houten kozijn vrij indeelbaar_gen_aly | 2 | Walls | BaseQuantities - Depth: 404.8 mm
Basic Wall:NLRS_20_WA_Metselwerk-100mm:12474738 | 00 begane grond | 21.11 buitenwanden; niet constructief, massieve wanden (Uniformat) | 1034 | 2740 | Curtain Wall:NLRS_31_WIN_UN_houten kozijn vrij indeelbaar_gen_aly | 2 | Walls | BaseQuantities - Depth: 404.8 mm
Basic Wall:NLRS_21_WA_HSB-wand_110mm:12781466 | 00 begane grond | 21.23 buitenwanden; constructief, systeemwanden (Uniformat) | 2700 | 1264.32 | Curtain Wall:NLRS_31_WIN_UN_houten kozijn vrij indeelbaar_gen_aly | 2 | Walls | BaseQuantities - Depth: 411.8 mm
Basic Wall:NLRS_21_WA_HSB-wand_110mm:12781557 | 00 begane grond | 21.23 buitenwanden; constructief, systeemwanden (Uniformat) | 2700 | 1256.78 | Curtain Wall:NLRS_31_WIN_UN_houten kozijn vrij indeelbaar_gen_aly | 2 | Walls | BaseQuantities - Depth: 411.8 mm

# IfcPlate: AL_Glaspaneel vitrine:AL_Glaspaneel vitrine (12)
In: 00 begane grond
Type - PredefinedType: CURTAIN_PANEL; Material: NLRS_o5_glas, ZZ_00_Kleur_RAL 9002
Type - Pset_PlateCommon - IsExternal: no; Reference: AL_Glaspaneel vitrine:AL_Glaspaneel vitrine
Type - Pset_ProductRequirements - Category: Curtain Panels
Type - Pset_QuantityTakeOff - Reference: AL_Glaspaneel vitrine:AL_Glaspaneel vitrine
Classification: 31.0 (Uniformat)
Pset_PlateCommon - IsExternal: yes
Name (AL_Glaspaneel vitrine:AL_Glaspaneel vitrine:...)
4285053
12116103
12116012
12116228
9558936
12117641
12117562
12117730
12122989
12123001
12122993
12122997

# IfcPlate: AL_schuifdeur glazen pui:AL_schuifdeur glazen pui, AL_schuifdeur glazen pui:AL_schuifdeur glazen pui:5587931
In: 00 begane grond
Type - PredefinedType: CURTAIN_PANEL; Material: NLRS_h4_aluminium, ZZ_00_Kleur_RAL 9002, NLRS_o5_glas
Type - Pset_PlateCommon - IsExternal: no; Reference: AL_schuifdeur glazen pui:AL_schuifdeur glazen pui
Type - Pset_ProductRequirements - Category: Curtain Panels
Type - Pset_QuantityTakeOff - Reference: AL_schuifdeur glazen pui:AL_schuifdeur glazen pui
Classification: 31.0 (Uniformat)
Pset_PlateCommon - IsExternal: yes

# IfcPlate: NLRS_31_CWP_Achterdeur met glas en lage borstwering en regel:31_Achterdeur met glas en lage borstwering RAL 7021 (4)
In: 00 begane grond
Type - PredefinedType: CURTAIN_PANEL; Material: NLRS_h4_aluminium, NLRS_o5_glas, ZZ_00_Kleur_RAL 7021
Type - Pset_PlateCommon - IsExternal: no; Reference: NLRS_31_CWP_Achterdeur met glas en lage borstwering en regel:31_Achterdeur met glas en lage borstwering RAL 7021
Type - Pset_ProductRequirements - Category: Curtain Panels
Type - Pset_QuantityTakeOff - Reference: NLRS_31_CWP_Achterdeur met glas en lage borstwering en regel:31_Achterdeur met glas en lage borstwering RAL 7021
Classification: 31.0 (Uniformat)
Pset_PlateCommon - IsExternal: yes
Name (NLRS_31_CWP_Achterdeur met glas en lage borstwering en regel:31_Achterdeur met glas en lage borstwering RAL 7021:...)
12819241
12606965
12813916
12606002

# IfcPlate: NLRS_31_CWP_Achterdeur met glas en lage borstwering en regel:31_Achterdeur met glas en lage borstwering RAL 9002 (13)
In: 00 begane grond
Type - PredefinedType: CURTAIN_PANEL; Material: NLRS_h4_aluminium, NLRS_o5_glas, ZZ_00_Kleur_RAL 9002
Type - Pset_PlateCommon - IsExternal: no; Reference: NLRS_31_CWP_Achterdeur met glas en lage borstwering en regel:31_Achterdeur met glas en lage borstwering RAL 9002
Type - Pset_ProductRequirements - Category: Curtain Panels
Type - Pset_QuantityTakeOff - Reference: NLRS_31_CWP_Achterdeur met glas en lage borstwering en regel:31_Achterdeur met glas en lage borstwering RAL 9002
Classification: 31.0 (Uniformat)
Pset_PlateCommon - IsExternal: yes
Name (NLRS_31_CWP_Achterdeur met glas en lage borstwering en regel:31_Achterdeur met glas en lage borstwering RAL 9002:...)
3079280
3669638
4574746
5202866
7514268
10222388
10229152
11777786
11778003
11778043
11895754
12738887
12738839

# IfcPlate: NLRS_31_CWP_Achterdeur met glas en lage borstwering_gen_aly:31_Achterdeur met glas en lage borstwering RAL 9002, NLRS_31_CWP_Achterdeur met glas en lage borstwering_gen_aly:31_Achterdeur met glas en lage borstwering RAL 9002:2858526
In: 00 begane grond
Type - PredefinedType: CURTAIN_PANEL; Material: NLRS_h4_aluminium, NLRS_o5_glas, ZZ_00_Kleur_RAL 9002
Type - Pset_PlateCommon - IsExternal: no; Reference: NLRS_31_CWP_Achterdeur met glas en lage borstwering_gen_aly:31_Achterdeur met glas en lage borstwering RAL 9002
Type - Pset_ProductRequirements - Category: Curtain Panels
Type - Pset_QuantityTakeOff - Reference: NLRS_31_CWP_Achterdeur met glas en lage borstwering_gen_aly:31_Achterdeur met glas en lage borstwering RAL 9002
Classification: 31.0 (Uniformat)
Pset_PlateCommon - IsExternal: yes

# IfcPlate: NLRS_31_CWP_achterdeur zonder glas_gen_aly:31_Achterdeur zonder glas (2)
In: 00 begane grond
Type - PredefinedType: CURTAIN_PANEL; Material: NLRS_h4_aluminium, AL_31_KozijnHout hardhout Antraciet
Type - Pset_PlateCommon - IsExternal: no; Reference: NLRS_31_CWP_achterdeur zonder glas_gen_aly:31_Achterdeur zonder glas
Type - Pset_ProductRequirements - Category: Curtain Panels
Type - Pset_QuantityTakeOff - Reference: NLRS_31_CWP_achterdeur zonder glas_gen_aly:31_Achterdeur zonder glas
Classification: 31.0 (Uniformat)
Pset_PlateCommon - IsExternal: yes
Name (NLRS_31_CWP_achterdeur zonder glas_gen_aly:31_Achterdeur zonder glas:...)
2866800
9282401

# IfcPlate: NLRS_31_CWP_achterdeur zonder glas_gen_aly:31_Achterdeur zonder glas RAL 9002 (2)
In: 00 begane grond
Type - PredefinedType: CURTAIN_PANEL; Material: NLRS_h4_aluminium, NLRS_i3_hout_Loofhout (hardhout) RAL 9002
Type - Pset_PlateCommon - IsExternal: no; Reference: NLRS_31_CWP_achterdeur zonder glas_gen_aly:31_Achterdeur zonder glas RAL 9002
Type - Pset_ProductRequirements - Category: Curtain Panels
Type - Pset_QuantityTakeOff - Reference: NLRS_31_CWP_achterdeur zonder glas_gen_aly:31_Achterdeur zonder glas RAL 9002
Classification: 31.0 (Uniformat)
Pset_PlateCommon - IsExternal: yes
Name (NLRS_31_CWP_achterdeur zonder glas_gen_aly:31_Achterdeur zonder glas RAL 9002:...)
3722995
5634989

# IfcPlate: NLRS_31_CWP_achterdeur zonder glas_gen_aly:31_Achterdeur zonder glas antraciet (3)
Type - PredefinedType: CURTAIN_PANEL; Material: NLRS_h4_aluminium, AL_31_KozijnHout hardhout Antraciet
Type - Pset_PlateCommon - IsExternal: no; Reference: NLRS_31_CWP_achterdeur zonder glas_gen_aly:31_Achterdeur zonder glas antraciet
Type - Pset_ProductRequirements - Category: Curtain Panels
Type - Pset_QuantityTakeOff - Reference: NLRS_31_CWP_achterdeur zonder glas_gen_aly:31_Achterdeur zonder glas antraciet
Classification: 31.0 (Uniformat)
Pset_PlateCommon - IsExternal: yes
Name (NLRS_31_CWP_achterdeur zonder glas_gen_aly:31_Achterdeur zonder glas antraciet:...) | In
9321373 | 01 eerste verdieping
9046986 | 01 eerste verdieping
9282407 | 00 begane grond

# IfcPlate: NLRS_31_CWP_achterdeur zonder glas_gen_aly:31_Achterdeur zonder glas, RAL 6009 (5)
In: 00 begane grond
Type - PredefinedType: CURTAIN_PANEL; Material: NLRS_h4_aluminium, ZZ_00_Kleur_RAL 6009
Type - Pset_PlateCommon - IsExternal: no; Reference: NLRS_31_CWP_achterdeur zonder glas_gen_aly:31_Achterdeur zonder glas, RAL 6009
Type - Pset_ProductRequirements - Category: Curtain Panels
Type - Pset_QuantityTakeOff - Reference: NLRS_31_CWP_achterdeur zonder glas_gen_aly:31_Achterdeur zonder glas, RAL 6009
Classification: 31.0 (Uniformat)
Pset_PlateCommon - IsExternal: yes
Name (NLRS_31_CWP_achterdeur zonder glas_gen_aly:31_Achterdeur zonder glas, RAL 6009:...)
2856747
2857172
3424599
6267161
6267648

# IfcPlate: NLRS_31_CWP_achterdeur zonder glas_gen_aly:31_Achterdeur zonder glas, RAL 7021 (2)
In: 00 begane grond
Type - PredefinedType: CURTAIN_PANEL; Material: NLRS_h4_aluminium, ZZ_00_Kleur_RAL 7021
Type - Pset_PlateCommon - IsExternal: no; Reference: NLRS_31_CWP_achterdeur zonder glas_gen_aly:31_Achterdeur zonder glas, RAL 7021
Type - Pset_ProductRequirements - Category: Curtain Panels
Type - Pset_QuantityTakeOff - Reference: NLRS_31_CWP_achterdeur zonder glas_gen_aly:31_Achterdeur zonder glas, RAL 7021
Classification: 31.0 (Uniformat)
Pset_PlateCommon - IsExternal: yes
Name (NLRS_31_CWP_achterdeur zonder glas_gen_aly:31_Achterdeur zonder glas, RAL 7021:...)
3650434
5254165

# IfcPlate: NLRS_31_CWP_dubbele deur met glas en regel:31_Dubbele deur met glas RAL 7021 (15)
In: 00 begane grond
Type - PredefinedType: CURTAIN_PANEL; Material: NLRS_h4_aluminium, NLRS_o5_glas, ZZ_00_Kleur_RAL 7021
Type - Pset_PlateCommon - IsExternal: no; Reference: NLRS_31_CWP_dubbele deur met glas en regel:31_Dubbele deur met glas RAL 7021
Type - Pset_ProductRequirements - Category: Curtain Panels
Type - Pset_QuantityTakeOff - Reference: NLRS_31_CWP_dubbele deur met glas en regel:31_Dubbele deur met glas RAL 7021
Classification: 31.0 (Uniformat)
Pset_PlateCommon - IsExternal: yes
Name (NLRS_31_CWP_dubbele deur met glas en regel:31_Dubbele deur met glas RAL 7021:...)
3029708
3019649
3020540
4093377
7459422
7508899
5203738
5565110
5567091
5567310
5567913
5637609
5638065
5837563
9318886

# IfcPlate: NLRS_31_CWP_dubbele deur met glas en regel:31_Dubbele deur met glas RAL 9002 (14)
In: 00 begane grond
Type - PredefinedType: CURTAIN_PANEL; Material: NLRS_h4_aluminium, NLRS_o5_glas, ZZ_00_Kleur_RAL 9002
Type - Pset_PlateCommon - IsExternal: no; Reference: NLRS_31_CWP_dubbele deur met glas en regel:31_Dubbele deur met glas RAL 9002
Type - Pset_ProductRequirements - Category: Curtain Panels
Type - Pset_QuantityTakeOff - Reference: NLRS_31_CWP_dubbele deur met glas en regel:31_Dubbele deur met glas RAL 9002
Classification: 31.0 (Uniformat)
Pset_PlateCommon - IsExternal: yes
Name (NLRS_31_CWP_dubbele deur met glas en regel:31_Dubbele deur met glas RAL 9002:...)
2981896
3103291
3721531
4326203
4221987
4257202
5762134
5762146
5882724
5973730
6660027
7718454
7718459
11363912

# IfcPlate: NLRS_31_CWP_dubbele deur zonder glas_gen_aly:31_Dubbele deur zonder glas (2)
In: 00 begane grond
Type - PredefinedType: CURTAIN_PANEL; Material: NLRS_h4_aluminium, NLRS_dichte deur grijs
Type - Pset_PlateCommon - IsExternal: no; Reference: NLRS_31_CWP_dubbele deur zonder glas_gen_aly:31_Dubbele deur zonder glas
Type - Pset_ProductRequirements - Category: Curtain Panels
Type - Pset_QuantityTakeOff - Reference: NLRS_31_CWP_dubbele deur zonder glas_gen_aly:31_Dubbele deur zonder glas
Classification: 31.0 (Uniformat)
Pset_PlateCommon - IsExternal: yes
Name (NLRS_31_CWP_dubbele deur zonder glas_gen_aly:31_Dubbele deur zonder glas:...)
9244747
9244752

# IfcPlate: NLRS_31_CWP_dubbele deur zonder glas_gen_aly:31_Dubbele deur zonder glas RAL 9002 (6)
In: 00 begane grond
Type - PredefinedType: CURTAIN_PANEL; Material: NLRS_h4_aluminium, NLRS_i3_hout_Loofhout (hardhout) RAL 9002
Type - Pset_PlateCommon - IsExternal: no; Reference: NLRS_31_CWP_dubbele deur zonder glas_gen_aly:31_Dubbele deur zonder glas RAL 9002
Type - Pset_ProductRequirements - Category: Curtain Panels
Type - Pset_QuantityTakeOff - Reference: NLRS_31_CWP_dubbele deur zonder glas_gen_aly:31_Dubbele deur zonder glas RAL 9002
Classification: 31.0 (Uniformat)
Pset_PlateCommon - IsExternal: yes
Name (NLRS_31_CWP_dubbele deur zonder glas_gen_aly:31_Dubbele deur zonder glas RAL 9002:...)
2980527
3260281
3260366
3261839
3311309
3722661

# IfcPlate: NLRS_31_CWP_dubbele deur zonder glas_gen_aly:31_Dubbele deur zonder glas onder podium (4)
In: 00 begane grond
Type - PredefinedType: CURTAIN_PANEL; Material: NLRS_dichte deur zwart
Type - Pset_PlateCommon - IsExternal: no; Reference: NLRS_31_CWP_dubbele deur zonder glas_gen_aly:31_Dubbele deur zonder glas onder podium
Type - Pset_ProductRequirements - Category: Curtain Panels
Type - Pset_QuantityTakeOff - Reference: NLRS_31_CWP_dubbele deur zonder glas_gen_aly:31_Dubbele deur zonder glas onder podium
Classification: 31.0 (Uniformat)
Pset_PlateCommon - IsExternal: yes
Name (NLRS_31_CWP_dubbele deur zonder glas_gen_aly:31_Dubbele deur zonder glas onder podium:...)
12231325
12231376
12231422
12231426

# IfcPlate: NLRS_31_CWP_dubbele deur zonder glas_gen_aly:31_Dubbele deur zonder glas zwart (3)
In: 00 begane grond
Type - PredefinedType: CURTAIN_PANEL; Material: NLRS_h4_aluminium, AL_31_KozijnHout hardhout RAL 9005
Type - Pset_PlateCommon - IsExternal: no; Reference: NLRS_31_CWP_dubbele deur zonder glas_gen_aly:31_Dubbele deur zonder glas zwart
Type - Pset_ProductRequirements - Category: Curtain Panels
Type - Pset_QuantityTakeOff - Reference: NLRS_31_CWP_dubbele deur zonder glas_gen_aly:31_Dubbele deur zonder glas zwart
Classification: 31.0 (Uniformat)
Pset_PlateCommon - IsExternal: yes
Name (NLRS_31_CWP_dubbele deur zonder glas_gen_aly:31_Dubbele deur zonder glas zwart:...)
3105531
3105697
3105744

# IfcPlate: NLRS_31_CWP_dubbele schuifdeur met gla (deur kan niet open):31_Dubbele schuifdeur met glas RAL 9002, NLRS_31_CWP_dubbele schuifdeur met gla (deur kan niet open):31_Dubbele schuifdeur met glas RAL 9002:7635238
In: 00 begane grond
Type - PredefinedType: CURTAIN_PANEL; Material: NLRS_o5_glas, NLRS_i3_hout_Loofhout (hardhout) RAL 9002
Type - Pset_PlateCommon - IsExternal: no; Reference: NLRS_31_CWP_dubbele schuifdeur met gla (deur kan niet open):31_Dubbele schuifdeur met glas RAL 9002
Type - Pset_ProductRequirements - Category: Curtain Panels
Type - Pset_QuantityTakeOff - Reference: NLRS_31_CWP_dubbele schuifdeur met gla (deur kan niet open):31_Dubbele schuifdeur met glas RAL 9002
Classification: 31.0 (Uniformat)
Pset_PlateCommon - IsExternal: yes

# IfcPlate: NLRS_31_CWP_dubbele schuifdeur met glas_gen_aly:31_Dubbele schuifdeur met glas RAL 9002 (6)
In: 00 begane grond
Type - PredefinedType: CURTAIN_PANEL; Material: NLRS_h4_aluminium, NLRS_o5_glas, NLRS_i3_hout_Loofhout (hardhout) RAL 9002
Type - Pset_PlateCommon - IsExternal: no; Reference: NLRS_31_CWP_dubbele schuifdeur met glas_gen_aly:31_Dubbele schuifdeur met glas RAL 9002
Type - Pset_ProductRequirements - Category: Curtain Panels
Type - Pset_QuantityTakeOff - Reference: NLRS_31_CWP_dubbele schuifdeur met glas_gen_aly:31_Dubbele schuifdeur met glas RAL 9002
Classification: 31.0 (Uniformat)
Pset_PlateCommon - IsExternal: yes
Name (NLRS_31_CWP_dubbele schuifdeur met glas_gen_aly:31_Dubbele schuifdeur met glas RAL 9002:...)
3006409
7626447
7630318
7632403
7634412
8179645

# IfcPlate: NLRS_31_CWP_raam-draai-kiep_gen_aly:31_Raam-kiep (2)
In: 00 begane grond
Type - PredefinedType: CURTAIN_PANEL; Classification: 31.2 buitenwandopeningen; gevuld met ramen (Uniformat); Material: NLRS_a_bounding box_gen, NLRS_i3_hout_Loofhout (hardhout) RAL 9002, NLRS_o5_glas
Type - Pset_PlateCommon - IsExternal: no; Reference: NLRS_31_CWP_raam-draai-kiep_gen_aly:31_Raam-kiep
Type - Pset_ProductRequirements - Category: Curtain Panels
Type - Pset_QuantityTakeOff - Reference: NLRS_31_CWP_raam-draai-kiep_gen_aly:31_Raam-kiep
Classification: 31.0 (Uniformat)
Pset_PlateCommon - IsExternal: yes
Name (NLRS_31_CWP_raam-draai-kiep_gen_aly:31_Raam-kiep:...)
3425226
3425007

# IfcPlate: System Panel:31_Geïsoleerd glas 25mm (264)
Type - PredefinedType: CURTAIN_PANEL; Material: NLRS_o5_glas
Type - Pset_PlateCommon - IsExternal: no; Reference: System Panel:31_Geïsoleerd glas 25mm
Type - Pset_ProductRequirements - Category: Curtain Panels
Type - Pset_QuantityTakeOff - Reference: System Panel:31_Geïsoleerd glas 25mm
Classification: 31.0 (Uniformat)
Pset_PlateCommon - IsExternal: yes
Name (System Panel:31_Geïsoleerd glas 25mm:...) | In
2857101 | 00 begane grond
7310926 | 00 begane grond
2857282 | 00 begane grond
7311192 | 00 begane grond
2858314 | 00 begane grond
2858574 | 00 begane grond
2865783 | 00 begane grond
2865530 | 00 begane grond
2891818 | 01 eerste verdieping
2892832 | 01 eerste verdieping
2892780 | 01 eerste verdieping
2892713 | 01 eerste verdieping
2892672 | 01 eerste verdieping
2892622 | 01 eerste verdieping
2892579 | 01 eerste verdieping
2892542 | 01 eerste verdieping
2892488 | 01 eerste verdieping
2892430 | 01 eerste verdieping
2892378 | 01 eerste verdieping
2892280 | 01 eerste verdieping
2892833 | 01 eerste verdieping
2892714 | 01 eerste verdieping
2892673 | 01 eerste verdieping
2892580 | 01 eerste verdieping
2892543 | 01 eerste verdieping
2892431 | 01 eerste verdieping
2892379 | 01 eerste verdieping
2980928 | 00 begane grond
2981960 | 00 begane grond
7644426 | 00 begane grond
7644428 | 00 begane grond
3004379 | 00 begane grond
3029802 | 00 begane grond
3137475 | 00 begane grond
3137477 | 00 begane grond
12812907 | 00 begane grond
3019234 | 00 begane grond
3039428 | 00 begane grond
3040834 | 00 begane grond
3019451 | 00 begane grond
3039654 | 00 begane grond
3040924 | 00 begane grond
12818569 | 00 begane grond
3019874 | 00 begane grond
3039886 | 00 begane grond
3041040 | 00 begane grond
3020064 | 00 begane grond
3040108 | 00 begane grond
3041130 | 00 begane grond
3020231 | 00 begane grond
3041960 | 00 begane grond
3042978 | 00 begane grond
3020397 | 00 begane grond
3042194 | 00 begane grond
3043069 | 00 begane grond
12818228 | 00 begane grond
3020685 | 00 begane grond
3042442 | 00 begane grond
3043156 | 00 begane grond
3020863 | 00 begane grond
3043249 | 00 begane grond
3037846 | 00 begane grond
3038132 | 00 begane grond
12819066 | 00 begane grond
3036825 | 00 begane grond
12606246 | 00 begane grond
12606835 | 00 begane grond
12606837 | 00 begane grond
5719156 | 00 begane grond
3079512 | 00 begane grond
7645493 | 00 begane grond
5170974 | 00 begane grond
3131748 | 00 begane grond
3132360 | 00 begane grond
3132638 | 00 begane grond
3132403 | 00 begane grond
7492548 | 00 begane grond
3132441 | 00 begane grond
3132010 | 00 begane grond
3132474 | 00 begane grond
3132223 | 00 begane grond
3132639 | 00 begane grond
7492549 | 00 begane grond
3132226 | 00 begane grond
3136058 | 00 begane grond
3136070 | 00 begane grond
3216645 | 00 begane grond
3216983 | 00 begane grond
3217028 | 00 begane grond
5722490 | 00 begane grond
3668607 | 00 begane grond
3669764 | 00 begane grond
3669950 | 00 begane grond
3669229 | 00 begane grond
3669305 | 00 begane grond
3669533 | 00 begane grond
3720114 | 00 begane grond
9723183 | 00 begane grond
3720845 | 00 begane grond
9723232 | 00 begane grond
3720864 | 00 begane grond
9723286 | 00 begane grond
3721848 | 00 begane grond
7644766 | 00 begane grond
12814706 | 00 begane grond
4200606 | 00 begane grond
9428150 | 00 begane grond
7508959 | 00 begane grond
9428006 | 00 begane grond
4200627 | 00 begane grond
7508960 | 00 begane grond
12815793 | 00 begane grond
12815797 | 00 begane grond
4201024 | 00 begane grond
4201051 | 00 begane grond
4201086 | 00 begane grond
4201114 | 00 begane grond
7496927 | 00 begane grond
4201123 | 00 begane grond
4201032 | 00 begane grond
4201057 | 00 begane grond
4201039 | 00 begane grond
4201040 | 00 begane grond
7496928 | 00 begane grond
4201042 | 00 begane grond
11898356 | 00 begane grond
11898358 | 00 begane grond
11898361 | 00 begane grond
11898363 | 00 begane grond
4259319 | 00 begane grond
4259325 | 00 begane grond
4259452 | 00 begane grond
4438364 | 00 begane grond
5202860 | 00 begane grond
7644986 | 00 begane grond
5203703 | 00 begane grond
5203713 | 00 begane grond
12812499 | 00 begane grond
5206283 | 00 begane grond
5459100 | 00 begane grond
5459495 | 00 begane grond
5459121 | 00 begane grond
5565098 | 00 begane grond
5565128 | 00 begane grond
5565188 | 00 begane grond
5565104 | 00 begane grond
5565143 | 00 begane grond
5565200 | 00 begane grond
12818792 | 00 begane grond
5565116 | 00 begane grond
5565158 | 00 begane grond
5565212 | 00 begane grond
5567079 | 00 begane grond
5567109 | 00 begane grond
5567169 | 00 begane grond
5567085 | 00 begane grond
5567124 | 00 begane grond
5567181 | 00 begane grond
12819621 | 00 begane grond
5567097 | 00 begane grond
5567139 | 00 begane grond
5567193 | 00 begane grond
5567103 | 00 begane grond
5567154 | 00 begane grond
5567205 | 00 begane grond
5567298 | 00 begane grond
5567328 | 00 begane grond
5567388 | 00 begane grond
5567304 | 00 begane grond
5567343 | 00 begane grond
5567400 | 00 begane grond
12819373 | 00 begane grond
5567316 | 00 begane grond
5567358 | 00 begane grond
5567412 | 00 begane grond
5567322 | 00 begane grond
5567373 | 00 begane grond
5567424 | 00 begane grond
5567901 | 00 begane grond
5567931 | 00 begane grond
5567991 | 00 begane grond
5567907 | 00 begane grond
5567946 | 00 begane grond
5568003 | 00 begane grond
12814165 | 00 begane grond
5567919 | 00 begane grond
5567961 | 00 begane grond
5568015 | 00 begane grond
5567925 | 00 begane grond
5567976 | 00 begane grond
5568027 | 00 begane grond
5580913 | 00 begane grond
5580924 | 00 begane grond
12813782 | 00 begane grond
5598050 | 00 begane grond
5598056 | 00 begane grond
5598071 | 00 begane grond
5637603 | 00 begane grond
5637614 | 00 begane grond
5637630 | 00 begane grond
5637632 | 00 begane grond
12816491 | 00 begane grond
12816932 | 00 begane grond
5649326 | 00 begane grond
5649332 | 00 begane grond
5649484 | 00 begane grond
5649490 | 00 begane grond
5762128 | 00 begane grond
10301929 | 00 begane grond
7643567 | 00 begane grond
5762140 | 00 begane grond
10302082 | 00 begane grond
7643261 | 00 begane grond
9324822 | 00 begane grond
9324823 | 00 begane grond
5837574 | 00 begane grond
5837581 | 00 begane grond
9318836 | 00 begane grond
9318837 | 00 begane grond
5837736 | 00 begane grond
5837743 | 00 begane grond
5903066 | 00 begane grond
5903082 | 00 begane grond
5903077 | 00 begane grond
6971453 | 01 eerste verdieping
6971459 | 01 eerste verdieping
6971465 | 01 eerste verdieping
6971471 | 01 eerste verdieping
6971491 | 01 eerste verdieping
6988576 | 00 begane grond
6988582 | 00 begane grond
7768084 | 00 begane grond
7768334 | 00 begane grond
7768085 | 00 begane grond
7759057 | 00 begane grond
12606092 | 00 begane grond
12611412 | 00 begane grond
12611414 | 00 begane grond
7759063 | 00 begane grond
8264866 | 00 begane grond
8264872 | 00 begane grond
8264878 | 00 begane grond
8264884 | 00 begane grond
8264890 | 00 begane grond
8264896 | 00 begane grond
8264902 | 00 begane grond
8265071 | 00 begane grond
9452507 | 00 begane grond
9485728 | 00 begane grond
9487586 | 00 begane grond
9530494 | 00 begane grond
9488150 | 00 begane grond
10238745 | 00 begane grond
10240994 | 00 begane grond
10266482 | 00 begane grond
10266780 | 00 begane grond
10267012 | 00 begane grond
10267233 | 00 begane grond
11757022 | 00 begane grond
11757349 | 00 begane grond
12734888 | 00 begane grond
12738634 | 00 begane grond
12738027 | 00 begane grond
12738741 | 00 begane grond

# IfcPlate: System Panel:31_Rolluik (2)
In: 00 begane grond
Type - PredefinedType: CURTAIN_PANEL; Material: AL_Aluminium
Type - Pset_PlateCommon - IsExternal: no; Reference: System Panel:31_Rolluik
Type - Pset_ProductRequirements - Category: Curtain Panels
Type - Pset_QuantityTakeOff - Reference: System Panel:31_Rolluik
Classification: 31.0 (Uniformat)
Pset_PlateCommon - IsExternal: yes
Name (System Panel:31_Rolluik:...)
8645764
8646240

# IfcPlate: System Panel:31_SW paneel 60mm (9)
Type - PredefinedType: CURTAIN_PANEL; Material: ZZ_00_Kleur_RAL 9003
Type - Pset_PlateCommon - IsExternal: no; Reference: System Panel:31_SW paneel 60mm
Type - Pset_ProductRequirements - Category: Curtain Panels
Type - Pset_QuantityTakeOff - Reference: System Panel:31_SW paneel 60mm
Classification: 31.0 (Uniformat)
Pset_PlateCommon - IsExternal: yes
Name (System Panel:31_SW paneel 60mm:...) | In
5009693 | Podium
5010023 | Podium
5010076 | Podium
5010140 | Podium
5010179 | Podium
5010244 | Podium
5010291 | Podium
5010334 | Podium
6267731 | 00 begane grond

# IfcRailing: Leuning voor trap op dak1:Leuning voor trap op dak, Leuning voor trap op dak1:Leuning voor trap op dak:9507352
In: 01 eerste verdieping
Type - Material: AL_Aluminium antraciet
Type - Pset_ProductRequirements - Category: Railings
Type - Pset_QuantityTakeOff - Reference: Leuning voor trap op dak1:Leuning voor trap op dak
Type - Pset_RailingCommon - IsExternal: no; Reference: Leuning voor trap op dak1:Leuning voor trap op dak
Pset_RailingCommon - Height: 40 mm

# IfcRailing: Leuning voor trap op dak2:Leuning voor trap op dak, Leuning voor trap op dak2:Leuning voor trap op dak:9507527
In: 01 eerste verdieping
Type - Material: AL_Aluminium antraciet
Type - Pset_ProductRequirements - Category: Railings
Type - Pset_QuantityTakeOff - Reference: Leuning voor trap op dak2:Leuning voor trap op dak
Type - Pset_RailingCommon - IsExternal: no; Reference: Leuning voor trap op dak2:Leuning voor trap op dak
Pset_RailingCommon - Height: 40 mm

# IfcRailing: Leuning voor trap op dak3:Leuning voor trap op dak, Leuning voor trap op dak3:Leuning voor trap op dak:9507675
In: 01 eerste verdieping
Type - Material: AL_Aluminium antraciet
Type - Pset_ProductRequirements - Category: Railings
Type - Pset_QuantityTakeOff - Reference: Leuning voor trap op dak3:Leuning voor trap op dak
Type - Pset_RailingCommon - IsExternal: no; Reference: Leuning voor trap op dak3:Leuning voor trap op dak
Pset_RailingCommon - Height: 40 mm

# IfcRailing: Leuning voor trap op dak:Leuning voor trap op dak, Leuning voor trap op dak:Leuning voor trap op dak:9505370
In: 01 eerste verdieping
Type - Material: AL_Aluminium antraciet
Type - Pset_ProductRequirements - Category: Railings
Type - Pset_QuantityTakeOff - Reference: Leuning voor trap op dak:Leuning voor trap op dak
Type - Pset_RailingCommon - IsExternal: no; Reference: Leuning voor trap op dak:Leuning voor trap op dak
Pset_RailingCommon - Height: 40 mm

# IfcRailing: Railing:NLRS_34_RAI_UN_leuning rond 40_gen_aly (6)
In: 00 begane grond
Classification: 34.10 balustrades en leuningen; balustrades, algemeen (verzamelniveau) (Uniformat)
Pset_ProductRequirements - Category: Railings
Pset_QuantityTakeOff - Reference: Railing:NLRS_34_RAI_UN_leuning rond 40_gen_aly
Pset_RailingCommon - IsExternal: no; Reference: Railing:NLRS_34_RAI_UN_leuning rond 40_gen_aly; Height: 1219.2 mm
Name (Railing:NLRS_34_RAI_UN_leuning rond 40_gen_aly:...) | Length (mm)
5927540 | 7318.66
5927544 | 4057.59
6433349 | 5530.24
6433353 | 3869.4
6433433 | 3869.4
6433437 | 5530.24

# IfcRailing: Railing:NLRS_34_RAI_UN_podium (3)
In: 00 begane grond
Classification: 34.10 balustrades en leuningen; balustrades, algemeen (verzamelniveau) (Uniformat); Material: AL_Aluminium antraciet, AL_Aluminium RAL 7021
Pset_ProductRequirements - Category: Railings
Pset_QuantityTakeOff - Reference: Railing:NLRS_34_RAI_UN_podium
Pset_RailingCommon - IsExternal: no; Reference: Railing:NLRS_34_RAI_UN_podium; Height: 1219.2 mm
Name (Railing:NLRS_34_RAI_UN_podium:...) | Length (mm)
11600991 | 1994.15
11601364 | 1768
11894049 | 914.5

# IfcRailing: Railing:NLRS_34_RAI_UN_spijlen 2 (2)
In: 01 eerste verdieping
Classification: 34.10 balustrades en leuningen; balustrades, algemeen (verzamelniveau) (Uniformat); Material: AL_Aluminium antraciet, AL_Aluminium RAL 7021
Pset_ProductRequirements - Category: Railings
Pset_QuantityTakeOff - Reference: Railing:NLRS_34_RAI_UN_spijlen 2
Pset_RailingCommon - IsExternal: no; Reference: Railing:NLRS_34_RAI_UN_spijlen 2; Height: 1219.2 mm
Name (Railing:NLRS_34_RAI_UN_spijlen 2:...) | Length (mm)
8375650 | 2536.49
8375763 | 2551.49

# IfcRailing: Railing:NLRS_34_RAI_UN_spijlen binnen (2)
In: 01 eerste verdieping
Classification: 34.10 balustrades en leuningen; balustrades, algemeen (verzamelniveau) (Uniformat); Material: AL_Aluminium antraciet
Pset_ProductRequirements - Category: Railings
Pset_QuantityTakeOff - Reference: Railing:NLRS_34_RAI_UN_spijlen binnen
Pset_RailingCommon - IsExternal: no; Reference: Railing:NLRS_34_RAI_UN_spijlen binnen; Height: 1219.2 mm
Name (Railing:NLRS_34_RAI_UN_spijlen binnen:...) | Length (mm)
5971112 | 1925
5971178 | 1920

# IfcRailing: Railing:NLRS_34_RAI_UN_spijlen_gen_aly (4)
In: 01 eerste verdieping
Classification: 34.10 balustrades en leuningen; balustrades, algemeen (verzamelniveau) (Uniformat); Material: AL_Aluminium antraciet, AL_Aluminium RAL 7021
Pset_ProductRequirements - Category: Railings
Pset_QuantityTakeOff - Reference: Railing:NLRS_34_RAI_UN_spijlen_gen_aly
Pset_RailingCommon - IsExternal: no; Reference: Railing:NLRS_34_RAI_UN_spijlen_gen_aly; Height: 1219.2 mm
Name (Railing:NLRS_34_RAI_UN_spijlen_gen_aly:...) | Length (mm)
3228281 | 6960
3844569 | 15099.2
8374956 | 568.727
8374976 | 588.853

# IfcRoof: Basic Roof:27_Dakelement Derako lineair base line plafond, Basic Roof:27_Dakelement Derako lineair base line plafond:3857910
In: 06 zesde verdieping
Classification: 27.22 daken; constructief, hellende daken (Uniformat); Material: NLRS_i4_hout_underlayment 18 mm, NLRS_i1_hardboard_gen 15 mm
Pset_ElementShading - Roughness: 304.8 mm
Pset_ManufacturerTypeInformation - Manufacturer: Topvorm
Pset_ProductRequirements - Category: Roofs
Pset_QuantityTakeOff - Reference: Basic Roof:27_Dakelement Derako lineair base line plafond
Pset_RoofCommon - IsExternal: yes; Reference: Basic Roof:27_Dakelement Derako lineair base line plafond; ProjectedArea: 133.294 m2; TotalArea: 136.775 m2

# IfcRoof: Basic Roof:27_Dakelement Rc 6,0m²K/W, aftimmerpakket (6)
In: 01 eerste verdieping
Classification: 27.22 daken; constructief, hellende daken (Uniformat)
Pset_ElementShading - Roughness: 304.8 mm
Pset_ManufacturerTypeInformation - Manufacturer: Topvorm
Pset_ProductRequirements - Category: Roofs
Pset_QuantityTakeOff - Reference: Basic Roof:27_Dakelement Rc 6,0m²K/W, aftimmerpakket
Pset_RoofCommon - IsExternal: yes; Reference: Basic Roof:27_Dakelement Rc 6,0m²K/W, aftimmerpakket
Name (Basic Roof:27_Dakelement Rc 6,0m²K/W, aftimmerpakket:...) | Material | ProjectedArea (m2) | TotalArea (m2)
3045948 | AL_Multiplex 18 mm, NLRS_m1_isolatie 271 mm, j7_hout_spaanplaat 10 mm | 469.599 | 493.761
3073223 |  | 11.164 | 11.7385
4229870 | AL_Multiplex 18 mm, NLRS_m1_isolatie 271 mm, j7_hout_spaanplaat 10 mm | 240.741 | 253.13
4261380 | AL_Multiplex 18 mm, NLRS_m1_isolatie 271 mm, j7_hout_spaanplaat 10 mm | 20.3996 | 21.4494
5884278 |  | 11.0595 | 11.6286
9892940 | AL_Multiplex 18 mm, NLRS_m1_isolatie 271 mm, j7_hout_spaanplaat 10 mm | 399.151 | 419.692

# IfcRoof: Basic Roof:NLRS_27_Plafond bekleding mf zaal (9)
Classification: 27.22 daken; constructief, hellende daken (Uniformat)
Pset_ElementShading - Roughness: 304.8 mm
Pset_ProductRequirements - Category: Roofs
Pset_QuantityTakeOff - Reference: Basic Roof:NLRS_27_Plafond bekleding mf zaal
Pset_RoofCommon - IsExternal: yes; Reference: Basic Roof:NLRS_27_Plafond bekleding mf zaal
Name (Basic Roof:NLRS_27_Plafond bekleding mf zaal:...) | In | ProjectedArea (m2) | TotalArea (m2)
8839677 | 01 eerste verdieping | 27.8695 | 29.3038
8840051 | 02 tweede verdieping | 32.5373 | 34.2118
8840127 | 02 tweede verdieping | 32.5194 | 34.1929
8840174 | 06 zesde verdieping | 3.60989 | 3.79566
8840334 | 06 zesde verdieping | 9.08592 | 9.5535
8840698 | 06 zesde verdieping | 3.80405 | 3.99982
8840887 | 06 zesde verdieping | 9.09533 | 9.5634
8840958 | 06 zesde verdieping | 4.38476 | 4.61041
8841128 | 06 zesde verdieping | 3.68305 | 3.87259

# IfcRoof: Basic Roof:NLRS_27_RO_Bestaande dak gymzaal, Basic Roof:NLRS_27_RO_Bestaande dak gymzaal:3088271
In: 01 eerste verdieping
Classification: 27.22 daken; constructief, hellende daken (Uniformat); Material: NLRS_h4_aluminium sandwichpaneel verticaal geprofileerd bestaand 180 mm
Pset_ElementShading - Roughness: 304.8 mm
Pset_ProductRequirements - Category: Roofs
Pset_QuantityTakeOff - Reference: Basic Roof:NLRS_27_RO_Bestaande dak gymzaal
Pset_RoofCommon - IsExternal: yes; Reference: Basic Roof:NLRS_27_RO_Bestaande dak gymzaal; ProjectedArea: 30.2834 m2; TotalArea: 150.605 m2

# IfcRoof: Dakrand 1:Dakrand 3, Dakrand 1:Dakrand 3:9374866
In: 02 tweede verdieping
Material: AL_Multiplex, AL_Aluminium, h7_zink zwart, AL_Aluminium zwart 2
Pset_ProductRequirements - Category: Roofs
Pset_QuantityTakeOff - Reference: Dakrand 1:Dakrand 3
Pset_RoofCommon - IsExternal: yes; Reference: Dakrand 1:Dakrand 3; TotalArea: 21.0096 m2

# IfcRoof: Dakrand 2:Dakrand 3, Dakrand 2:Dakrand 3:9525476
In: 02 tweede verdieping
Material: NLRS_i2_hout naaldhout_gen, AL_Aluminium zwart 2
Pset_ProductRequirements - Category: Roofs
Pset_QuantityTakeOff - Reference: Dakrand 2:Dakrand 3
Pset_RoofCommon - IsExternal: yes; Reference: Dakrand 2:Dakrand 3; TotalArea: 0.786588 m2

# IfcRoof: Dakrand 3:Dakrand 3, Dakrand 3:Dakrand 3:5234522
In: 02 tweede verdieping
Material: AL_Multiplex, AL_Aluminium zwart
Pset_ProductRequirements - Category: Roofs
Pset_QuantityTakeOff - Reference: Dakrand 3:Dakrand 3
Pset_RoofCommon - IsExternal: yes; Reference: Dakrand 3:Dakrand 3; TotalArea: 52.8827 m2

# IfcRoof: Dakrand 4:Dakrand 3, Dakrand 4:Dakrand 3:9527638
In: 02 tweede verdieping
Material: NLRS_i2_hout naaldhout_gen, AL_Aluminium zwart 2
Pset_ProductRequirements - Category: Roofs
Pset_QuantityTakeOff - Reference: Dakrand 4:Dakrand 3
Pset_RoofCommon - IsExternal: yes; Reference: Dakrand 4:Dakrand 3; TotalArea: 0.786482 m2

# IfcRoof: Dakrand gymzaal:Dakrand gymzaal, Dakrand gymzaal:Dakrand gymzaal:6411671
In: 02 tweede verdieping
Material: h7_zink zwart
Pset_ProductRequirements - Category: Roofs
Pset_QuantityTakeOff - Reference: Dakrand gymzaal:Dakrand gymzaal
Pset_RoofCommon - IsExternal: yes; Reference: Dakrand gymzaal:Dakrand gymzaal; TotalArea: 7.03833 m2

# IfcRoof: Dakrand zijkant dak1:Dakrand zijkant dak, Dakrand zijkant dak1:Dakrand zijkant dak:8414208
In: 01 eerste verdieping
Material: AL_Aluminium, AL_31_Naaldhout (vuren), h7_zink zwart
Pset_ProductRequirements - Category: Roofs
Pset_QuantityTakeOff - Reference: Dakrand zijkant dak1:Dakrand zijkant dak
Pset_RoofCommon - IsExternal: yes; Reference: Dakrand zijkant dak1:Dakrand zijkant dak; TotalArea: 2.71205 m2

# IfcRoof: Dakrand zijkant dak2:Dakrand zijkant dak, Dakrand zijkant dak2:Dakrand zijkant dak:8414510
In: 01 eerste verdieping
Material: h7_zink zwart, AL_31_Naaldhout (vuren), AL_Aluminium
Pset_ProductRequirements - Category: Roofs
Pset_QuantityTakeOff - Reference: Dakrand zijkant dak2:Dakrand zijkant dak
Pset_RoofCommon - IsExternal: yes; Reference: Dakrand zijkant dak2:Dakrand zijkant dak; TotalArea: 2.80898 m2

# IfcRoof: Dakrand zijkant dak3:Dakrand zijkant dak, Dakrand zijkant dak3:Dakrand zijkant dak:8415280
In: 01 eerste verdieping
Material: AL_Aluminium, AL_31_Naaldhout (vuren), h7_zink zwart
Pset_ProductRequirements - Category: Roofs
Pset_QuantityTakeOff - Reference: Dakrand zijkant dak3:Dakrand zijkant dak
Pset_RoofCommon - IsExternal: yes; Reference: Dakrand zijkant dak3:Dakrand zijkant dak; TotalArea: 2.81143 m2

# IfcRoof: Dakrand zijkant dak4:Dakrand zijkant dak, Dakrand zijkant dak4:Dakrand zijkant dak:8416727
In: 01 eerste verdieping
Material: AL_Aluminium, AL_31_Naaldhout (vuren), h7_zink zwart
Pset_ProductRequirements - Category: Roofs
Pset_QuantityTakeOff - Reference: Dakrand zijkant dak4:Dakrand zijkant dak
Pset_RoofCommon - IsExternal: yes; Reference: Dakrand zijkant dak4:Dakrand zijkant dak; TotalArea: 1.36553 m2

# IfcRoof: Dakrand zijkant dak5:Dakrand zijkant dak, Dakrand zijkant dak5:Dakrand zijkant dak:8417066
In: 01 eerste verdieping
Material: AL_Aluminium, AL_31_Naaldhout (vuren), h7_zink zwart
Pset_ProductRequirements - Category: Roofs
Pset_QuantityTakeOff - Reference: Dakrand zijkant dak5:Dakrand zijkant dak
Pset_RoofCommon - IsExternal: yes; Reference: Dakrand zijkant dak5:Dakrand zijkant dak; TotalArea: 1.36653 m2

# IfcRoof: Dakrand zijkant dak6:Dakrand zijkant dak, Dakrand zijkant dak6:Dakrand zijkant dak:8417160
In: 01 eerste verdieping
Material: AL_Aluminium, AL_31_Naaldhout (vuren), h7_zink zwart
Pset_ProductRequirements - Category: Roofs
Pset_QuantityTakeOff - Reference: Dakrand zijkant dak6:Dakrand zijkant dak
Pset_RoofCommon - IsExternal: yes; Reference: Dakrand zijkant dak6:Dakrand zijkant dak; TotalArea: 1.36798 m2

# IfcRoof: Dakrand zijkant dak7:Dakrand zijkant dak, Dakrand zijkant dak7:Dakrand zijkant dak:8417232
In: 01 eerste verdieping
Material: AL_Aluminium, AL_31_Naaldhout (vuren), h7_zink zwart
Pset_ProductRequirements - Category: Roofs
Pset_QuantityTakeOff - Reference: Dakrand zijkant dak7:Dakrand zijkant dak
Pset_RoofCommon - IsExternal: yes; Reference: Dakrand zijkant dak7:Dakrand zijkant dak; TotalArea: 1.36305 m2

# IfcRoof: Dakrand zijkant dak:Dakrand zijkant dak, Dakrand zijkant dak:Dakrand zijkant dak:6678455
In: 00 begane grond
Material: AL_Aluminium, AL_31_Naaldhout (vuren), h7_zink zwart
Pset_ProductRequirements - Category: Roofs
Pset_QuantityTakeOff - Reference: Dakrand zijkant dak:Dakrand zijkant dak
Pset_RoofCommon - IsExternal: yes; Reference: Dakrand zijkant dak:Dakrand zijkant dak; TotalArea: 7.57358 m2

# IfcRoof: Plafond erkers mf zaal1:Plafond erkers mf zaal, Plafond erkers mf zaal1:Plafond erkers mf zaal:9283742
In: 01 eerste verdieping
Material: AL Houten gevelbekleding liggend
Pset_ProductRequirements - Category: Roofs
Pset_QuantityTakeOff - Reference: Plafond erkers mf zaal1:Plafond erkers mf zaal
Pset_RoofCommon - IsExternal: yes; Reference: Plafond erkers mf zaal1:Plafond erkers mf zaal; TotalArea: 0.011259 m2

# IfcRoof: Plafond erkers mf zaal:Plafond erkers mf zaal, Plafond erkers mf zaal:Plafond erkers mf zaal:9283606
In: 01 eerste verdieping
Material: AL Houten gevelbekleding liggend
Pset_ProductRequirements - Category: Roofs
Pset_QuantityTakeOff - Reference: Plafond erkers mf zaal:Plafond erkers mf zaal
Pset_RoofCommon - IsExternal: yes; Reference: Plafond erkers mf zaal:Plafond erkers mf zaal; TotalArea: 0.0121935 m2

# IfcRoof: Profiel onderkant gymzaal dak bestaand1:Profiel onderkant gymzaal dak bestaand, Profiel onderkant gymzaal dak bestaand1:Profiel onderkant gymzaal dak bestaand:5955166
In: Podium
Material: AL_Aluminium zwart
Pset_ProductRequirements - Category: Roofs
Pset_QuantityTakeOff - Reference: Profiel onderkant gymzaal dak bestaand1:Profiel onderkant gymzaal dak bestaand
Pset_RoofCommon - IsExternal: yes; Reference: Profiel onderkant gymzaal dak bestaand1:Profiel onderkant gymzaal dak bestaand; TotalArea: 0.524799 m2

# IfcRoof: Zinken beplating dakgoot1:Zinken beplating dakgoot, Zinken beplating dakgoot1:Zinken beplating dakgoot:5226448
In: Podium
Material: NLRS_i4_hout_multiplex zwart, h7_zink zwart, j7_hout_spaanplaat, NLRS_j7_hout_spaanplaat, AL_31_Naaldhout (vuren)
Pset_ProductRequirements - Category: Roofs
Pset_QuantityTakeOff - Reference: Zinken beplating dakgoot1:Zinken beplating dakgoot
Pset_RoofCommon - IsExternal: yes; Reference: Zinken beplating dakgoot1:Zinken beplating dakgoot; TotalArea: 24.3721 m2

# IfcRoof: Zinken beplating dakgoot2:Zinken beplating dakgoot, Zinken beplating dakgoot2:Zinken beplating dakgoot:5227441
In: Podium
Material: NLRS_i4_hout_multiplex zwart, h7_zink zwart, j7_hout_spaanplaat, NLRS_j7_hout_spaanplaat, AL_31_Naaldhout (vuren)
Pset_ProductRequirements - Category: Roofs
Pset_QuantityTakeOff - Reference: Zinken beplating dakgoot2:Zinken beplating dakgoot
Pset_RoofCommon - IsExternal: yes; Reference: Zinken beplating dakgoot2:Zinken beplating dakgoot; TotalArea: 46.9843 m2

# IfcRoof: Zinken beplating dakgoot3:Zinken beplating dakgoot, Zinken beplating dakgoot3:Zinken beplating dakgoot:4906028
In: Podium
Material: NLRS_i4_hout_multiplex zwart, h7_zink zwart, NLRS_i4_beplating multiplex_gen, NLRS_i4_beplating multiplex wit_gen, AL_31_Naaldhout (vuren)
Pset_ProductRequirements - Category: Roofs
Pset_QuantityTakeOff - Reference: Zinken beplating dakgoot3:Zinken beplating dakgoot
Pset_RoofCommon - IsExternal: yes; Reference: Zinken beplating dakgoot3:Zinken beplating dakgoot; TotalArea: 201.774 m2

# IfcRoof: Zinken beplating dakgoot4:Zinken beplating dakgoot, Zinken beplating dakgoot4:Zinken beplating dakgoot:9918800
In: Podium
Material: NLRS_i4_hout_multiplex zwart, h7_zink zwart, j7_hout_spaanplaat, NLRS_j7_hout_spaanplaat, AL_31_Naaldhout (vuren)
Pset_ProductRequirements - Category: Roofs
Pset_QuantityTakeOff - Reference: Zinken beplating dakgoot4:Zinken beplating dakgoot
Pset_RoofCommon - IsExternal: yes; Reference: Zinken beplating dakgoot4:Zinken beplating dakgoot; TotalArea: 62.347 m2

# IfcRoof: balklaag luifel:balklaag luifel, balklaag luifel:balklaag luifel:3171619
In: Podium
Classification: 27.23 daken; constructief, luifels (Uniformat); Material: AL Houten beplating gevel erker sportkantine
Pset_ProductRequirements - Category: Structural Framing
Pset_QuantityTakeOff - Reference: balklaag luifel:balklaag luifel
Pset_RoofCommon - IsExternal: no; Reference: balklaag luifel:balklaag luifel

# IfcSlab: Basic Roof:27_Dakelement Rc 6,0m²K/W, aftimmerpakket (2)
In: 01 eerste verdieping
Type - PredefinedType: ROOF
Type - Pset_ElementShading - Roughness: 304.8 mm
Type - Pset_ManufacturerTypeInformation - Manufacturer: Topvorm
Type - Pset_ProductRequirements - Category: Roofs
Type - Pset_QuantityTakeOff - Reference: Basic Roof:27_Dakelement Rc 6,0m²K/W, aftimmerpakket
Type - Pset_ReinforcementBarPitchOfSlab - Description: Dakelement Rc 6,0m²K/W, aftimmerpakket; Reference: Basic Roof:27_Dakelement Rc 6,0m²K/W, aftimmerpakket
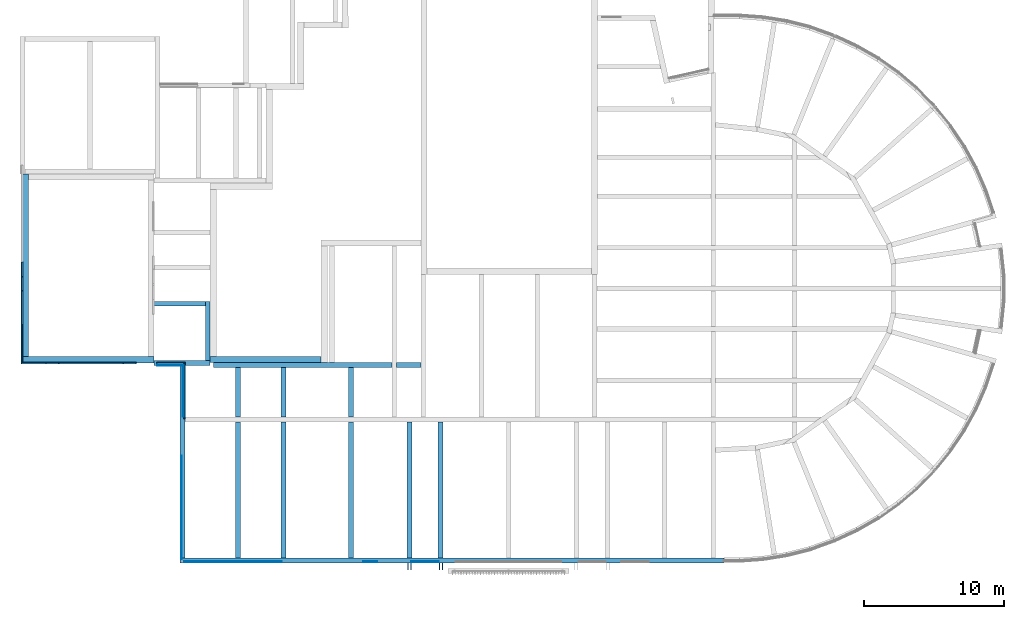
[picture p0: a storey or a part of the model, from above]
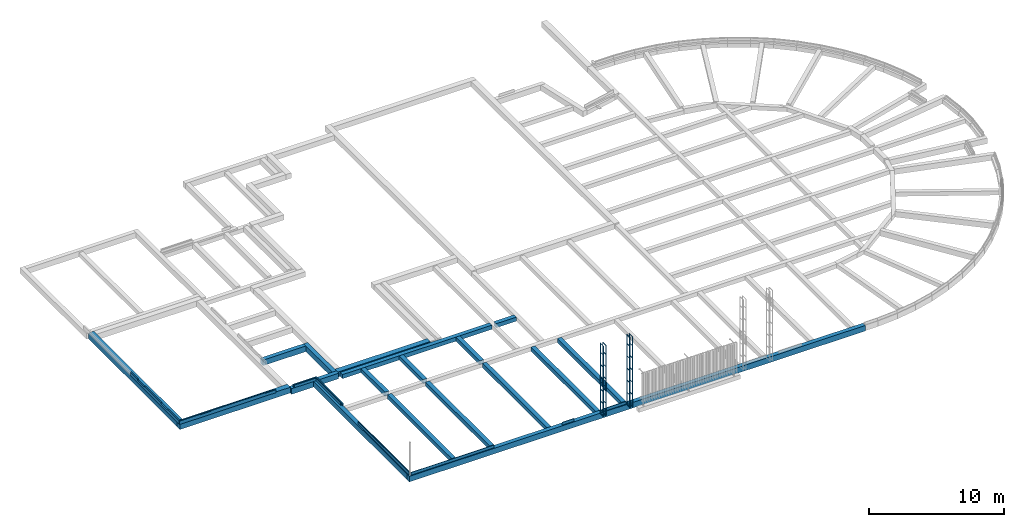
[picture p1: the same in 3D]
Properties of the parts of a building model (IFC2X3), part 8 of 13

# IfcSlab: Basic Roof:27_Dakelement Rc 6,0m²K/W, aftimmerpakket (2)
Type - Pset_SlabCommon - IsExternal: yes; Reference: Basic Roof:27_Dakelement Rc 6,0m²K/W, aftimmerpakket
Classification: 27.22 daken; constructief, hellende daken (Uniformat); Material: AL_Multiplex 18 mm, NLRS_m1_isolatie 271 mm, j7_hout_spaanplaat 10 mm; AL_Multiplex
Pset_SlabCommon - PitchAngle: 18.6165 deg
BaseQuantities - Width: 299 mm
Name (Basic Roof:27_Dakelement Rc 6,0m²K/W, aftimmerpakket:...) | GrossArea (m2) | NetArea (m2) | GrossVolume (m3) | NetVolume (m3) | Perimeter (mm)
3073223 | 1.09055 | 28.131 | 326.073 | 3.50982 | 15347.7
5884278 | 1.08033 | 27.8989 | 323.02 | 3.47696 | 15308.8

# IfcSlab: Basic Roof:NLRS_27_Plafond bekleding mf zaal (9)
Type - PredefinedType: ROOF
Type - Pset_ElementShading - Roughness: 304.8 mm
Type - Pset_ProductRequirements - Category: Roofs
Type - Pset_QuantityTakeOff - Reference: Basic Roof:NLRS_27_Plafond bekleding mf zaal
Type - Pset_ReinforcementBarPitchOfSlab - Description: Dakopbouw met dakpannen; Reference: Basic Roof:NLRS_27_Plafond bekleding mf zaal
Type - Pset_SlabCommon - IsExternal: yes; Reference: Basic Roof:NLRS_27_Plafond bekleding mf zaal
Classification: 27.22 daken; constructief, hellende daken (Uniformat); Material: NLRS_i3_hout_Loofhout (hardhout) RAL 9005; NLRS_i3_hout_Loofhout (hardhout) RAL 9005 12 mm
Pset_SlabCommon - PitchAngle: 18.6165 deg
BaseQuantities - Width: 12 mm
Name (Basic Roof:NLRS_27_Plafond bekleding mf zaal:...) | In | GrossArea (m2) | NetArea (m2) | GrossVolume (m3) | NetVolume (m3) | Perimeter (mm)
8839677 | 01 eerste verdieping | 2.72241 | 58.9235 | 32.6689 | 0.351645 | 25337.1
8840051 | 02 tweede verdieping | 3.17838 | 68.7517 | 38.1405 | 0.410541 | 26357.1
8840127 | 02 tweede verdieping | 3.17663 | 68.714 | 38.1195 | 0.410315 | 26353.2
8840174 | 06 zesde verdieping | 0.352628 | 7.70636 | 4.23154 | 0.0455479 | 9481.83
8840334 | 06 zesde verdieping | 0.887549 | 19.2728 | 10.6506 | 0.114642 | 13610
8840698 | 06 zesde verdieping | 0.371595 | 8.09818 | 4.45914 | 0.0479978 | 8001.71
8840887 | 06 zesde verdieping | 0.888469 | 19.2927 | 10.6616 | 0.114761 | 13620
8840958 | 06 zesde verdieping | 0.428321 | 9.32653 | 5.13985 | 0.0553249 | 8599.17
8841128 | 06 zesde verdieping | 0.359775 | 7.8559 | 4.3173 | 0.046471 | 9111.36

# IfcSlab: Basic Roof:NLRS_47_Felsdak zink (5)
In: 01 eerste verdieping
Type - PredefinedType: ROOF
Type - Pset_ElementShading - Roughness: 304.8 mm
Type - Pset_ProductRequirements - Category: Roofs
Type - Pset_QuantityTakeOff - Reference: Basic Roof:NLRS_47_Felsdak zink
Type - Pset_ReinforcementBarPitchOfSlab - Reference: Basic Roof:NLRS_47_Felsdak zink
Type - Pset_SlabCommon - IsExternal: yes; Reference: Basic Roof:NLRS_47_Felsdak zink; ThermalTransmittance: 230000 kg/K/s3
Classification: 47.12 dakafwerkingen; afwerkingen, hellende dakafwerkingen (Uniformat); Material: AL_Aluminium zwart; AL_Aluminium zwart 1 mm
Pset_QuantityTakeOff - sets with these values: 2
Pset_SlabCommon - PitchAngle: 18.6165 deg
BaseQuantities - Width: 1 mm
Name (Basic Roof:NLRS_47_Felsdak zink:...) | GrossArea (m2) = GrossVolume (m3) | NetArea (m2) | NetVolume (m3) | Perimeter (mm)
3169807 | 40.5395 | 872.858 | 0.436364 | 125979
4229884 | 24.0669 | 518.18 | 0.259054 | 69808.5
4261570 | 2.06766 | 44.5388 | 0.0222561 | 26523.2
4563552 | 1.30099 | 28.0239 | 0.0140038 | 16089
4563951 | 1.30117 | 28.0277 | 0.0140057 | 16090.5

# IfcSlab: Basic Roof:NLRS_47_Trampeziumplaat 106R/750 (2)
In: 02 tweede verdieping
Type - PredefinedType: ROOF
Type - Pset_ElementShading - Roughness: 304.8 mm
Type - Pset_ProductRequirements - Category: Roofs
Type - Pset_QuantityTakeOff - Reference: Basic Roof:NLRS_47_Trampeziumplaat 106R/750
Type - Pset_ReinforcementBarPitchOfSlab - Reference: Basic Roof:NLRS_47_Trampeziumplaat 106R/750
Type - Pset_SlabCommon - IsExternal: yes; Reference: Basic Roof:NLRS_47_Trampeziumplaat 106R/750; ThermalTransmittance: 416.667 kg/K/s3
Classification: 47.12 dakafwerkingen; afwerkingen, hellende dakafwerkingen (Uniformat); Material: NLRS_h3_staal_verzinkt; NLRS_h3_staal_verzinkt 108 mm
Pset_QuantityTakeOff - sets with these values: 2
Pset_SlabCommon - PitchAngle: 0.793829 deg
BaseQuantities - NetArea: 263.11 m2; NetVolume: 13.9421 m3; Width: 108 mm
Name (Basic Roof:NLRS_47_Trampeziumplaat 106R/750:...) | GrossArea (m2) | GrossVolume (m3) | Perimeter (mm)
6406087 | 5.99161 | 647.094 | 33302.1
6406087 | 6.00158 | 648.17 | 33322.5

# IfcSlab: Basic Roof:NLRS_47_Trespa 10mm RAL 9002, Basic Roof:NLRS_47_Trespa 10mm RAL 9002:9820310
In: 01 eerste verdieping
Type - PredefinedType: ROOF
Type - Pset_ElementShading - Roughness: 304.8 mm
Type - Pset_ProductRequirements - Category: Roofs
Type - Pset_QuantityTakeOff - Reference: Basic Roof:NLRS_47_Trespa 10mm RAL 9002
Type - Pset_ReinforcementBarPitchOfSlab - Description: Dakpannen; Reference: Basic Roof:NLRS_47_Trespa 10mm RAL 9002
Type - Pset_SlabCommon - IsExternal: yes; Reference: Basic Roof:NLRS_47_Trespa 10mm RAL 9002
Classification: 47.12 dakafwerkingen; afwerkingen, hellende dakafwerkingen (Uniformat); Material: ZZ_00_Kleur_RAL 9002; ZZ_00_Kleur_RAL 9002 10 mm
Pset_SlabCommon - PitchAngle: 18.6165 deg
BaseQuantities - GrossArea: 0.149296 m2; NetArea: 3.37148 m2; GrossVolume: 1.49296 m3; NetVolume: 0.0160701 m3; Perimeter: 15724.9 mm; Width: 10 mm

# IfcSlab: Basic Roof:NLRS_47_Trespa 10mm zwart (4)
Type - PredefinedType: ROOF
Type - Pset_ElementShading - Roughness: 304.8 mm
Type - Pset_ProductRequirements - Category: Roofs
Type - Pset_QuantityTakeOff - Reference: Basic Roof:NLRS_47_Trespa 10mm zwart
Type - Pset_ReinforcementBarPitchOfSlab - Description: Dakpannen; Reference: Basic Roof:NLRS_47_Trespa 10mm zwart
Type - Pset_SlabCommon - IsExternal: yes; Reference: Basic Roof:NLRS_47_Trespa 10mm zwart
Classification: 47.12 dakafwerkingen; afwerkingen, hellende dakafwerkingen (Uniformat); Material: NLRS_i4_hout_multiplex zwart; NLRS_i4_hout_multiplex zwart 10 mm
BaseQuantities - Width: 10 mm
Name (Basic Roof:NLRS_47_Trespa 10mm zwart:...) | In | PitchAngle (deg) | GrossArea (m2) | NetArea (m2) | GrossVolume (m3) | NetVolume (m3) | Perimeter (mm)
5301534 | Podium | 18.6165 | 0.376314 | 8.31922 | 3.76314 | 0.0405061 | 21759.5
5301710 | Podium | 18.6165 | 0.347692 | 7.70249 | 3.47692 | 0.0374253 | 21706.7
9926886 | 01 eerste verdieping | 18.6149 | 1.69005 | 36.6304 | 16.9005 | 0.181915 | 24557
9927130 | 01 eerste verdieping | 18.6165 | 0.388821 | 8.5894 | 3.88821 | 0.0418523 | 21852.8

# IfcSlab: Basic Roof:NLRS_47_multiplex betimmering (2)
In: 01 eerste verdieping
Type - PredefinedType: ROOF
Type - Pset_ElementShading - Roughness: 304.8 mm
Type - Pset_ProductRequirements - Category: Roofs
Type - Pset_QuantityTakeOff - Reference: Basic Roof:NLRS_47_multiplex betimmering
Type - Pset_ReinforcementBarPitchOfSlab - Description: Dakpannen; Reference: Basic Roof:NLRS_47_multiplex betimmering
Type - Pset_SlabCommon - IsExternal: yes; Reference: Basic Roof:NLRS_47_multiplex betimmering
Classification: 47.12 dakafwerkingen; afwerkingen, hellende dakafwerkingen (Uniformat); Material: NLRS_i4_hout_multiplex; NLRS_i4_hout_multiplex 15 mm
Pset_SlabCommon - PitchAngle: 18.6165 deg
BaseQuantities - GrossArea: 0.0854211 m2; NetArea: 1.98416 m2; GrossVolume: 1.28132 m3; NetVolume: 0.013792 m3; Perimeter: 9661.42 mm; Width: 15 mm
Name (Basic Roof:NLRS_47_multiplex betimmering:...)
11079969
11080229

# IfcSlab: Basic Roof:NLRS_47_multiplex betimmering zwart (2)
In: 00 begane grond
Type - PredefinedType: ROOF
Type - Pset_ElementShading - Roughness: 304.8 mm
Type - Pset_ProductRequirements - Category: Roofs
Type - Pset_QuantityTakeOff - Reference: Basic Roof:NLRS_47_multiplex betimmering zwart
Type - Pset_ReinforcementBarPitchOfSlab - Description: Dakpannen; Reference: Basic Roof:NLRS_47_multiplex betimmering zwart
Type - Pset_SlabCommon - IsExternal: yes; Reference: Basic Roof:NLRS_47_multiplex betimmering zwart
Classification: 47.12 dakafwerkingen; afwerkingen, hellende dakafwerkingen (Uniformat); Material: NLRS_i4_hout_multiplex zwart; NLRS_i4_hout_multiplex zwart 15 mm
Pset_SlabCommon - PitchAngle: 0 deg
BaseQuantities - Width: 15 mm
Name (Basic Roof:NLRS_47_multiplex betimmering zwart:...) | GrossArea (m2) | NetArea (m2) | GrossVolume (m3) | NetVolume (m3) | Perimeter (mm)
5954974 | 1.36179 | 29.8656 | 20.4269 | 0.219873 | 36612
9448588 | 0.0612002 | 1.36759 | 0.918003 | 0.0098813 | 3338.97

# IfcSlab: Dakrand 1:Dakrand 3, Dakrand 1:Dakrand 3:9374866:1
In: 02 tweede verdieping
Type - PredefinedType: ROOF
Type - Pset_ProductRequirements - Category: Roofs
Type - Pset_QuantityTakeOff - Reference: Dakrand 1:Dakrand 3
Type - Pset_ReinforcementBarPitchOfSlab - Reference: Dakrand 1:Dakrand 3
Type - Pset_SlabCommon - IsExternal: yes; Reference: Dakrand 1:Dakrand 3
Material: AL_Multiplex, AL_Aluminium, h7_zink zwart, AL_Aluminium zwart 2
Pset_QuantityTakeOff - sets with these values: 2
BaseQuantities - GrossArea: 0.000270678 m2; NetArea: 51.1953 m2; GrossVolume: 6.54414 m3; NetVolume: 0.242085 m3; Perimeter: 543.363 mm; Width: 24176.8 mm

# IfcSlab: Dakrand 2:Dakrand 3, Dakrand 2:Dakrand 3:9525476:1
In: 02 tweede verdieping
Type - PredefinedType: ROOF
Type - Pset_ProductRequirements - Category: Roofs
Type - Pset_QuantityTakeOff - Reference: Dakrand 2:Dakrand 3
Type - Pset_ReinforcementBarPitchOfSlab - Reference: Dakrand 2:Dakrand 3
Type - Pset_SlabCommon - IsExternal: yes; Reference: Dakrand 2:Dakrand 3
Material: NLRS_i2_hout naaldhout_gen, AL_Aluminium zwart 2
Pset_QuantityTakeOff - sets with these values: 2
BaseQuantities - GrossArea: 0.000281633 m2; NetArea: 2.22798 m2; GrossVolume: 0.749161 m3; NetVolume: 0.00666789 m3; Perimeter: 565.413 mm; Width: 2660.06 mm

# IfcSlab: Dakrand 4:Dakrand 3, Dakrand 4:Dakrand 3:9527638:1
In: 02 tweede verdieping
Type - PredefinedType: ROOF
Type - Pset_ProductRequirements - Category: Roofs
Type - Pset_QuantityTakeOff - Reference: Dakrand 4:Dakrand 3
Type - Pset_ReinforcementBarPitchOfSlab - Reference: Dakrand 4:Dakrand 3
Type - Pset_SlabCommon - IsExternal: yes; Reference: Dakrand 4:Dakrand 3
Material: NLRS_i2_hout naaldhout_gen, AL_Aluminium zwart 2
Pset_QuantityTakeOff - sets with these values: 2
BaseQuantities - GrossArea: 0.000281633 m2; NetArea: 2.22764 m2; GrossVolume: 0.749012 m3; NetVolume: 0.00666772 m3; Perimeter: 565.413 mm; Width: 2659.53 mm

# IfcSlab: Dakrand zijkant dak1:Dakrand zijkant dak, Dakrand zijkant dak1:Dakrand zijkant dak:8414208:1
In: 01 eerste verdieping
Type - PredefinedType: ROOF
Type - Pset_ProductRequirements - Category: Roofs
Type - Pset_QuantityTakeOff - Reference: Dakrand zijkant dak1:Dakrand zijkant dak
Type - Pset_ReinforcementBarPitchOfSlab - Reference: Dakrand zijkant dak1:Dakrand zijkant dak
Type - Pset_SlabCommon - IsExternal: yes; Reference: Dakrand zijkant dak1:Dakrand zijkant dak
Material: AL_Aluminium, AL_31_Naaldhout (vuren), h7_zink zwart
Pset_QuantityTakeOff - sets with these values: 2
Pset_SlabCommon - PitchAngle: 18 deg
BaseQuantities - GrossArea: 0.000218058 m2; NetArea: 10.8671 m2; GrossVolume: 2.41172 m3; NetVolume: 0.0282492 m3; Perimeter: 438.121 mm; Width: 11060 mm

# IfcSlab: Dakrand zijkant dak2:Dakrand zijkant dak, Dakrand zijkant dak2:Dakrand zijkant dak:8414510:1
In: 01 eerste verdieping
Type - PredefinedType: ROOF
Type - Pset_ProductRequirements - Category: Roofs
Type - Pset_QuantityTakeOff - Reference: Dakrand zijkant dak2:Dakrand zijkant dak
Type - Pset_ReinforcementBarPitchOfSlab - Reference: Dakrand zijkant dak2:Dakrand zijkant dak
Type - Pset_SlabCommon - IsExternal: yes; Reference: Dakrand zijkant dak2:Dakrand zijkant dak
Material: h7_zink zwart, AL_31_Naaldhout (vuren), AL_Aluminium
Pset_QuantityTakeOff - sets with these values: 2
Pset_SlabCommon - PitchAngle: 18 deg
BaseQuantities - GrossArea: 0.000180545 m2; NetArea: 11.2548 m2; GrossVolume: 2.02842 m3; NetVolume: 0.029296 m3; Perimeter: 363.094 mm; Width: 11235 mm

# IfcSlab: Dakrand zijkant dak3:Dakrand zijkant dak, Dakrand zijkant dak3:Dakrand zijkant dak:8415280:1
In: 01 eerste verdieping
Type - PredefinedType: ROOF
Type - Pset_ProductRequirements - Category: Roofs
Type - Pset_QuantityTakeOff - Reference: Dakrand zijkant dak3:Dakrand zijkant dak
Type - Pset_ReinforcementBarPitchOfSlab - Reference: Dakrand zijkant dak3:Dakrand zijkant dak
Type - Pset_SlabCommon - IsExternal: yes; Reference: Dakrand zijkant dak3:Dakrand zijkant dak
Material: AL_Aluminium, AL_31_Naaldhout (vuren), h7_zink zwart
Pset_QuantityTakeOff - sets with these values: 2
Pset_SlabCommon - PitchAngle: 18 deg
BaseQuantities - GrossArea: 0.000218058 m2; NetArea: 11.2645 m2; GrossVolume: 2.50767 m3; NetVolume: 0.0292587 m3; Perimeter: 438.121 mm; Width: 11500 mm

# IfcSlab: Dakrand zijkant dak4:Dakrand zijkant dak, Dakrand zijkant dak4:Dakrand zijkant dak:8416727:1
In: 01 eerste verdieping
Type - PredefinedType: ROOF
Type - Pset_ProductRequirements - Category: Roofs
Type - Pset_QuantityTakeOff - Reference: Dakrand zijkant dak4:Dakrand zijkant dak
Type - Pset_ReinforcementBarPitchOfSlab - Reference: Dakrand zijkant dak4:Dakrand zijkant dak
Type - Pset_SlabCommon - IsExternal: yes; Reference: Dakrand zijkant dak4:Dakrand zijkant dak
Material: AL_Aluminium, AL_31_Naaldhout (vuren), h7_zink zwart
Pset_QuantityTakeOff - sets with these values: 2
Pset_SlabCommon - PitchAngle: 18 deg
BaseQuantities - GrossArea: 0.000218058 m2; NetArea: 5.47399 m2; GrossVolume: 1.23312 m3; NetVolume: 0.0141171 m3; Perimeter: 438.121 mm; Width: 5655 mm

# IfcSlab: Dakrand zijkant dak5:Dakrand zijkant dak, Dakrand zijkant dak5:Dakrand zijkant dak:8417066:1
In: 01 eerste verdieping
Type - PredefinedType: ROOF
Type - Pset_ProductRequirements - Category: Roofs
Type - Pset_QuantityTakeOff - Reference: Dakrand zijkant dak5:Dakrand zijkant dak
Type - Pset_ReinforcementBarPitchOfSlab - Reference: Dakrand zijkant dak5:Dakrand zijkant dak
Type - Pset_SlabCommon - IsExternal: yes; Reference: Dakrand zijkant dak5:Dakrand zijkant dak
Material: AL_Aluminium, AL_31_Naaldhout (vuren), h7_zink zwart
Pset_QuantityTakeOff - sets with these values: 2
Pset_SlabCommon - PitchAngle: 18 deg
BaseQuantities - GrossArea: 0.000218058 m2; NetArea: 5.47891 m2; GrossVolume: 1.23748 m3; NetVolume: 0.0140774 m3; Perimeter: 438.121 mm; Width: 5675 mm

# IfcSlab: Dakrand zijkant dak6:Dakrand zijkant dak, Dakrand zijkant dak6:Dakrand zijkant dak:8417160:1
In: 01 eerste verdieping
Type - PredefinedType: ROOF
Type - Pset_ProductRequirements - Category: Roofs
Type - Pset_QuantityTakeOff - Reference: Dakrand zijkant dak6:Dakrand zijkant dak
Type - Pset_ReinforcementBarPitchOfSlab - Reference: Dakrand zijkant dak6:Dakrand zijkant dak
Type - Pset_SlabCommon - IsExternal: yes; Reference: Dakrand zijkant dak6:Dakrand zijkant dak
Material: AL_Aluminium, AL_31_Naaldhout (vuren), h7_zink zwart
Pset_QuantityTakeOff - sets with these values: 2
Pset_SlabCommon - PitchAngle: 18 deg
BaseQuantities - GrossArea: 0.000218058 m2; NetArea: 5.48371 m2; GrossVolume: 1.23748 m3; NetVolume: 0.0141325 m3; Perimeter: 438.121 mm; Width: 5675 mm

# IfcSlab: Dakrand zijkant dak7:Dakrand zijkant dak, Dakrand zijkant dak7:Dakrand zijkant dak:8417232:1
In: 01 eerste verdieping
Type - PredefinedType: ROOF
Type - Pset_ProductRequirements - Category: Roofs
Type - Pset_QuantityTakeOff - Reference: Dakrand zijkant dak7:Dakrand zijkant dak
Type - Pset_ReinforcementBarPitchOfSlab - Reference: Dakrand zijkant dak7:Dakrand zijkant dak
Type - Pset_SlabCommon - IsExternal: yes; Reference: Dakrand zijkant dak7:Dakrand zijkant dak
Material: AL_Aluminium, AL_31_Naaldhout (vuren), h7_zink zwart
Pset_QuantityTakeOff - sets with these values: 2
Pset_SlabCommon - PitchAngle: 18 deg
BaseQuantities - GrossArea: 0.000218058 m2; NetArea: 5.46241 m2; GrossVolume: 1.23639 m3; NetVolume: 0.0141113 m3; Perimeter: 438.121 mm; Width: 5670 mm

# IfcSlab: Dakrand zijkant dak:Dakrand zijkant dak, Dakrand zijkant dak:Dakrand zijkant dak:6678455:1
In: 00 begane grond
Type - PredefinedType: ROOF
Type - Pset_ProductRequirements - Category: Roofs
Type - Pset_QuantityTakeOff - Reference: Dakrand zijkant dak:Dakrand zijkant dak
Type - Pset_ReinforcementBarPitchOfSlab - Reference: Dakrand zijkant dak:Dakrand zijkant dak
Type - Pset_SlabCommon - IsExternal: yes; Reference: Dakrand zijkant dak:Dakrand zijkant dak
Material: AL_Aluminium, AL_31_Naaldhout (vuren), h7_zink zwart
Pset_QuantityTakeOff - sets with these values: 2
Pset_SlabCommon - PitchAngle: 18 deg
BaseQuantities - GrossArea: 0.000218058 m2; NetArea: 20.6037 m2; GrossVolume: 2.42372 m3; NetVolume: 0.0378187 m3; Perimeter: 438.121 mm; Width: 11115 mm

# IfcSlab: Dorpel roldeur:Dorpel roldeur, Dorpel roldeur:Dorpel roldeur:7014085
In: 00 begane grond
Type - PredefinedType: FLOOR
Type - Pset_ProductRequirements - Category: Floors
Type - Pset_QuantityTakeOff - Reference: Dorpel roldeur:Dorpel roldeur
Type - Pset_ReinforcementBarPitchOfSlab - Reference: Dorpel roldeur:Dorpel roldeur
Type - Pset_SlabCommon - IsExternal: no; Reference: Dorpel roldeur:Dorpel roldeur
Pset_QuantityTakeOff - sets with these values: 2
BaseQuantities - GrossArea: 0.0914123 m2; NetArea: 3.40149 m2; GrossVolume: 220.304 m3; NetVolume: 0.220304 m3; Perimeter: 1335.55 mm; Width: 2410 mm

# IfcSlab: Floor:NLRS_23_FL_Bestaand dak isolatie 90mm, Floor:NLRS_23_FL_Bestaand dak isolatie 90mm:4940471
In: 02 tweede verdieping
Classification: 23.21 vloeren; constructief, vrijdragende vloeren (Uniformat)
Pset_ElementShading - Roughness: 304.8 mm
Pset_ProductRequirements - Category: Floors
Pset_QuantityTakeOff - Reference: Floor:NLRS_23_FL_Bestaand dak isolatie 90mm
Pset_ReinforcementBarPitchOfSlab - Description: VBI kanaalplaatvloer 320mm; Reference: Floor:NLRS_23_FL_Bestaand dak isolatie 90mm
Pset_SlabCommon - IsExternal: no; LoadBearing: no; Reference: Floor:NLRS_23_FL_Bestaand dak isolatie 90mm; PitchAngle: 0.793778 deg
BaseQuantities - NetArea: 528.214 m2; NetVolume: 23.4957 m3; Perimeter: 67093 mm

# IfcSlab: Floor:NLRS_23_FL_Bestaand dak isolatie 90mm (2)
In: 02 tweede verdieping
Type - PredefinedType: ROOF
Type - Pset_ElementShading - Roughness: 304.8 mm
Type - Pset_ProductRequirements - Category: Floors
Type - Pset_QuantityTakeOff - Reference: Floor:NLRS_23_FL_Bestaand dak isolatie 90mm
Type - Pset_ReinforcementBarPitchOfSlab - Description: VBI kanaalplaatvloer 320mm; Reference: Floor:NLRS_23_FL_Bestaand dak isolatie 90mm
Type - Pset_SlabCommon - IsExternal: no; Reference: Floor:NLRS_23_FL_Bestaand dak isolatie 90mm
Classification: 23.21 vloeren; constructief, vrijdragende vloeren (Uniformat); Material: NLRS_m1_isolatie
Pset_SlabCommon - LoadBearing: no; PitchAngle: 0.793778 deg
BaseQuantities - GrossArea: 12.1279 m2; NetArea: 528.214 m2; GrossVolume: 1091.41 m3; NetVolume: 23.4957 m3; Perimeter: 67093 mm; Width: 89.9914 mm

# IfcSlab: Floor:NLRS_23_FL_Bitumen dakbedekking (2)
In: 01 eerste verdieping
Classification: 47.10 dakafwerkingen; afwerkingen, algemeen (verzamelniveau) (Uniformat)
Pset_ElementShading - Roughness: 304.8 mm
Pset_ProductRequirements - Category: Floors
Pset_QuantityTakeOff - Reference: Floor:NLRS_23_FL_Bitumen dakbedekking
Pset_ReinforcementBarPitchOfSlab - Description: VBI kanaalplaatvloer 320mm; Reference: Floor:NLRS_23_FL_Bitumen dakbedekking
Pset_SlabCommon - IsExternal: no; LoadBearing: no; Reference: Floor:NLRS_23_FL_Bitumen dakbedekking
Name (Floor:NLRS_23_FL_Bitumen dakbedekking:...) | PitchAngle (deg) | NetArea (m2) | NetVolume (m3) | Perimeter (mm)
4111941 | 1.53571 | 6.36392 | 0.0187032 | 20947.1
4238778 | 1.66996 | 13.9828 | 0.0411015 | 45534

# IfcSlab: Floor:NLRS_23_FL_Bitumen dakbedekking (6)
Type - PredefinedType: FLOOR; Material: NLRS_n2_bitumen_dak bedekking 6 mm
Type - Pset_ElementShading - Roughness: 304.8 mm
Type - Pset_ProductRequirements - Category: Floors
Type - Pset_QuantityTakeOff - Reference: Floor:NLRS_23_FL_Bitumen dakbedekking
Type - Pset_ReinforcementBarPitchOfSlab - Description: VBI kanaalplaatvloer 320mm; Reference: Floor:NLRS_23_FL_Bitumen dakbedekking
Type - Pset_SlabCommon - IsExternal: no; Reference: Floor:NLRS_23_FL_Bitumen dakbedekking
Classification: 47.10 dakafwerkingen; afwerkingen, algemeen (verzamelniveau) (Uniformat)
Pset_SlabCommon - LoadBearing: no
BaseQuantities - Width: 6 mm
Name (Floor:NLRS_23_FL_Bitumen dakbedekking:...) | In | PitchAngle (deg) | GrossArea (m2) | NetArea (m2) | GrossVolume (m3) | NetVolume (m3) | Perimeter (mm)
4114392 | 01 eerste verdieping | 2.38594 | 1.72743 | 3.54405 | 10.3646 | 0.0103556 | 14862.8
4114711 | 01 eerste verdieping | 0 | 3.233 | 6.65154 | 19.398 | 0.019398 | 30924
6410002 | 02 tweede verdieping | 0 | 19.3599 | 39.6317 | 116.159 | 0.116159 | 151981
8373878 | 01 eerste verdieping | 0 | 0.150599 | 0.312266 | 0.903594 | 0.000903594 | 1844.75
8374495 | 01 eerste verdieping | 0 | 0.156138 | 0.323657 | 0.936826 | 0.000936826 | 1897
9436767 | 01 eerste verdieping | 3.60362 | 0.53031 | 1.10252 | 3.18186 | 0.00317557 | 6983.96

# IfcSlab: Floor:NLRS_23_FL_Bitumen dakbedekking (7)
In: 01 eerste verdieping
Type - PredefinedType: ROOF
Type - Pset_ElementShading - Roughness: 304.8 mm
Type - Pset_ProductRequirements - Category: Floors
Type - Pset_QuantityTakeOff - Reference: Floor:NLRS_23_FL_Bitumen dakbedekking
Type - Pset_ReinforcementBarPitchOfSlab - Description: VBI kanaalplaatvloer 320mm; Reference: Floor:NLRS_23_FL_Bitumen dakbedekking
Type - Pset_SlabCommon - IsExternal: no; Reference: Floor:NLRS_23_FL_Bitumen dakbedekking
Classification: 47.10 dakafwerkingen; afwerkingen, algemeen (verzamelniveau) (Uniformat); Material: NLRS_n2_bitumen_dak bedekking
Pset_SlabCommon - LoadBearing: no
Name (Floor:NLRS_23_FL_Bitumen dakbedekking:...) | PitchAngle (deg) | GrossArea (m2) | NetArea (m2) | GrossVolume (m3) | NetVolume (m3) | Perimeter (mm) | Width (mm)
4111941 | 1.53571 | 0.125696 | 6.36392 | 0.753903 | 0.0187032 | 20947.1 | 5.99784
4111941 | 1.53571 | 0.112377 | 6.36392 | 0.674022 | 0.0187032 | 20947.1 | 5.99784
4111941 | 3.41988 | 0.0272752 | 6.36392 | 0.163359 | 0.0187032 | 20947.1 | 5.98932
4111941 | 3.45202 | 0.0244275 | 6.36392 | 0.146299 | 0.0187032 | 20947.1 | 5.98911
4238778 | 1.66996 | 0.387254 | 13.9828 | 2.32253 | 0.0411015 | 45534 | 5.99745
4238778 | 1.29314 | 0.170564 | 13.9828 | 1.02312 | 0.0411015 | 45534 | 5.99847
4238778 | 4.20536 | 0.0790129 | 13.9828 | 0.472801 | 0.0411015 | 45534 | 5.98385

# IfcSlab: Floor:NLRS_23_FL_Dak gymzaal trampeziumplaat, Floor:NLRS_23_FL_Dak gymzaal trampeziumplaat:2889030
In: 02 tweede verdieping
Classification: 23.21 vloeren; constructief, vrijdragende vloeren (Uniformat)
Pset_ElementShading - Roughness: 304.8 mm
Pset_ProductRequirements - Category: Floors
Pset_QuantityTakeOff - Reference: Floor:NLRS_23_FL_Dak gymzaal trampeziumplaat; sets with these values: 2
Pset_SlabCommon - IsExternal: no; LoadBearing: no; Reference: Floor:NLRS_23_FL_Dak gymzaal trampeziumplaat; ThermalTransmittance: 409.091 kg/K/s3; PitchAngle: 0.793778 deg
BaseQuantities - NetArea: 529.556 m2; NetVolume: 28.7169 m3; Perimeter: 67093 mm

# IfcSlab: Floor:NLRS_23_FL_Dak gymzaal trampeziumplaat (2)
In: 02 tweede verdieping
Type - PredefinedType: ROOF
Type - Pset_ElementShading - Roughness: 304.8 mm
Type - Pset_ProductRequirements - Category: Floors
Type - Pset_QuantityTakeOff - Reference: Floor:NLRS_23_FL_Dak gymzaal trampeziumplaat
Type - Pset_ReinforcementBarPitchOfSlab - Reference: Floor:NLRS_23_FL_Dak gymzaal trampeziumplaat
Type - Pset_SlabCommon - IsExternal: no; Reference: Floor:NLRS_23_FL_Dak gymzaal trampeziumplaat; ThermalTransmittance: 409.091 kg/K/s3
Classification: 23.21 vloeren; constructief, vrijdragende vloeren (Uniformat); Material: NLRS_h3_staal_verzinkt
Pset_QuantityTakeOff - sets with these values: 2
Pset_SlabCommon - LoadBearing: no; PitchAngle: 0.793778 deg
BaseQuantities - GrossArea: 12.1279 m2; NetArea: 529.556 m2; GrossVolume: 1333.94 m3; NetVolume: 28.7169 m3; Perimeter: 67093 mm; Width: 109.989 mm

# IfcSlab: Floor:NLRS_23_FL_EPS vloerisolatie 130mm, Floor:NLRS_23_FL_EPS vloerisolatie 130mm:4046994
In: 00 begane grond
Type - PredefinedType: FLOOR; Material: NLRS_n7_isolatie EPS_gen 130 mm
Type - Pset_ElementShading - Roughness: 304.8 mm
Type - Pset_ProductRequirements - Category: Floors
Type - Pset_QuantityTakeOff - Reference: Floor:NLRS_23_FL_EPS vloerisolatie 130mm
Type - Pset_ReinforcementBarPitchOfSlab - Description: VBI kanaalplaatvloer 320mm; Reference: Floor:NLRS_23_FL_EPS vloerisolatie 130mm
Type - Pset_SlabCommon - IsExternal: no; Reference: Floor:NLRS_23_FL_EPS vloerisolatie 130mm
Classification: 23.11 vloeren; niet constructief, vrijdragende Vloeren (Uniformat)
Pset_SlabCommon - LoadBearing: no; PitchAngle: 0 deg
BaseQuantities - GrossArea: 1708.54 m2; NetArea: 3455.63 m2; GrossVolume: 222110 m3; NetVolume: 222.11 m3; Perimeter: 296517 mm; Width: 130 mm

# IfcSlab: Floor:NLRS_23_FL_Houten balk laag 120mm, Floor:NLRS_23_FL_Houten balk laag 120mm:5710414
In: 00 begane grond
Type - PredefinedType: FLOOR; Material: NLRS_i4_hout_multiplex 18 mm, NLRS_i2_hout naaldhout vuren_gen 120 mm
Type - Pset_ElementShading - Roughness: 304.8 mm
Type - Pset_ProductRequirements - Category: Floors
Type - Pset_QuantityTakeOff - Reference: Floor:NLRS_23_FL_Houten balk laag 120mm
Type - Pset_ReinforcementBarPitchOfSlab - Description: VBI kanaalplaatvloer 320mm; Reference: Floor:NLRS_23_FL_Houten balk laag 120mm
Type - Pset_SlabCommon - IsExternal: no; Reference: Floor:NLRS_23_FL_Houten balk laag 120mm
Classification: 23.20 vloeren; constructief, algemeen (verzamelniveau) (Uniformat)
Pset_SlabCommon - LoadBearing: no; PitchAngle: 0 deg
BaseQuantities - GrossArea: 5.25928 m2; NetArea: 12.7012 m2; GrossVolume: 725.78 m3; NetVolume: 0.72578 m3; Perimeter: 15816 mm; Width: 138 mm

# IfcSlab: Floor:NLRS_23_FL_Houten balk laag 171mm (5)
In: 01 eerste verdieping
Type - PredefinedType: FLOOR; Material: NLRS_i2_hout naaldhout vuren_gen 171 mm
Type - Pset_ElementShading - Roughness: 304.8 mm
Type - Pset_ProductRequirements - Category: Floors
Type - Pset_QuantityTakeOff - Reference: Floor:NLRS_23_FL_Houten balk laag 171mm
Type - Pset_ReinforcementBarPitchOfSlab - Description: VBI kanaalplaatvloer 320mm; Reference: Floor:NLRS_23_FL_Houten balk laag 171mm
Type - Pset_SlabCommon - IsExternal: no; Reference: Floor:NLRS_23_FL_Houten balk laag 171mm
Classification: 23.20 vloeren; constructief, algemeen (verzamelniveau) (Uniformat)
Pset_SlabCommon - LoadBearing: no; PitchAngle: 0 deg
BaseQuantities - Width: 171 mm
Name (Floor:NLRS_23_FL_Houten balk laag 171mm:...) | GrossArea (m2) | NetArea (m2) | GrossVolume (m3) | NetVolume (m3) | Perimeter (mm)
3454284 | 124.95 | 257.417 | 21366.5 | 21.355 | 45533.1
5683048 | 3.23932 | 9.51668 | 553.924 | 0.553924 | 17766.3
5747350 | 15.164 | 33.8457 | 2593.04 | 2.59304 | 20571.4
11014740 | 3.88256 | 9.92944 | 663.918 | 0.663918 | 12656.8
11016608 | 3.17979 | 8.34534 | 543.744 | 0.543744 | 11612.6

# IfcSlab: Floor:NLRS_23_FL_Houten balk laag 196mm (5)
In: 01 eerste verdieping
Type - PredefinedType: FLOOR; Material: NLRS_i2_hout naaldhout vuren_gen 196 mm
Type - Pset_ElementShading - Roughness: 304.8 mm
Type - Pset_ProductRequirements - Category: Floors
Type - Pset_QuantityTakeOff - Reference: Floor:NLRS_23_FL_Houten balk laag 196mm
Type - Pset_ReinforcementBarPitchOfSlab - Description: VBI kanaalplaatvloer 320mm; Reference: Floor:NLRS_23_FL_Houten balk laag 196mm
Type - Pset_SlabCommon - IsExternal: no; Reference: Floor:NLRS_23_FL_Houten balk laag 196mm
Classification: 23.20 vloeren; constructief, algemeen (verzamelniveau) (Uniformat)
Pset_SlabCommon - LoadBearing: no; PitchAngle: 0 deg
Name (Floor:NLRS_23_FL_Houten balk laag 196mm:...) | GrossArea (m2) | NetArea (m2) | NetVolume (m3) | Perimeter (mm) | GrossVolume (m3) | Width (mm)
5663625 | 15.2655 | 33.8994 | 2.83111 | 25563.9
5682892 | 81.1702 | 171.784 | 15.9094 | 48179.7 | 15909.4 | 196
5682908 | 7.56375 | 17.2997 | 1.48249 | 11082.5 | 1482.49 | 196
5682992 | 121.781 | 253.554 | 23.3702 | 76953
5683034 | 36.8751 | 78.7831 | 7.22751 | 25678.6 | 7227.51 | 196

# IfcSlab: Floor:NLRS_23_FL_Houten balk laag 221mm (40)
In: 01 eerste verdieping
Type - PredefinedType: FLOOR; Material: NLRS_i2_hout naaldhout vuren_gen 221 mm
Type - Pset_ElementShading - Roughness: 304.8 mm
Type - Pset_ProductRequirements - Category: Floors
Type - Pset_QuantityTakeOff - Reference: Floor:NLRS_23_FL_Houten balk laag 221mm
Type - Pset_ReinforcementBarPitchOfSlab - Description: VBI kanaalplaatvloer 320mm; Reference: Floor:NLRS_23_FL_Houten balk laag 221mm
Type - Pset_SlabCommon - IsExternal: no; Reference: Floor:NLRS_23_FL_Houten balk laag 221mm
Classification: 23.20 vloeren; constructief, algemeen (verzamelniveau) (Uniformat)
Pset_SlabCommon - LoadBearing: no; PitchAngle: 0 deg
BaseQuantities - Width: 221 mm
Name (Floor:NLRS_23_FL_Houten balk laag 221mm:...) | GrossArea (m2) | NetArea (m2) | GrossVolume (m3) | NetVolume (m3) | Perimeter (mm)
5679599 | 4.07134 | 10.4114 | 899.767 | 0.899767 | 10265.5
5679704 | 5.44421 | 12.9723 | 1203.17 | 1.20317 | 9429.28
5679718 | 3.0487 | 7.73529 | 673.763 | 0.673763 | 7411.25
5679732 | 3.62844 | 9.7002 | 801.885 | 0.801855 | 11058.7
5679746 | 9.95522 | 23.3079 | 2200.1 | 2.2001 | 15373.2
5679762 | 10.9762 | 25.6117 | 2425.75 | 2.42575 | 16557.7
5679776 | 6.21413 | 14.6269 | 1373.32 | 1.37332 | 9948.64
5679790 | 6.17601 | 14.5492 | 1364.9 | 1.3649 | 9941.95
5679804 | 11.0876 | 25.8539 | 2450.36 | 2.45036 | 16645.8
5679818 | 10.0618 | 23.5404 | 2223.65 | 2.22365 | 15460.8
5679832 | 3.64101 | 9.72252 | 804.663 | 0.804728 | 11043.2
5679846 | 3.04105 | 7.71773 | 672.073 | 0.672073 | 7401.01
5679860 | 5.45634 | 13.0004 | 1205.85 | 1.20585 | 9446.58
5679874 | 3.77984 | 9.73848 | 835.344 | 0.835344 | 9858.85
5680673 | 11.9419 | 26.9629 | 2639.17 | 2.63917 | 13932.2
5680713 | 12.8918 | 28.9928 | 2849.09 | 2.84909 | 14521.1
5680727 | 13.6637 | 30.7063 | 3019.67 | 3.01967 | 15289.8
5680741 | 26.6341 | 58.2759 | 5886.14 | 5.88614 | 22659.2
5681327 | 8.40104 | 19.3918 | 1856.63 | 1.85663 | 11718.1
5681341 | 7.00094 | 16.4071 | 1547.21 | 1.54721 | 10883.5
5681383 | 18.3725 | 40.5481 | 4060.33 | 4.06033 | 17208.5
5681399 | 2.84986 | 7.48348 | 629.82 | 0.62982 | 8071.28
5683006 | 8.64653 | 19.9598 | 1910.88 | 1.91088 | 12066.5
5683020 | 7.25489 | 16.914 | 1603.33 | 1.60333 | 10878.7
5683062 | 16.049 | 35.6394 | 3546.83 | 3.54683 | 16024.5
5683076 | 9.79632 | 22.4458 | 2164.99 | 2.16499 | 12910.2
5690576 | 2.58047 | 6.65618 | 570.284 | 0.570284 | 6765.79
5893074 | 3.4637 | 8.90767 | 765.478 | 0.765478 | 8960.49
6222951 | 8.39295 | 19.6606 | 1854.84 | 1.85484 | 13007.5
6223047 | 8.39772 | 19.6712 | 1855.9 | 1.8559 | 13012.5
6571865 | 1.02281 | 3.18688 | 226.04 | 0.22604 | 5164.12
9256174 | 4.27199 | 10.3844 | 944.111 | 0.944111 | 8327.68
9256457 | 4.27191 | 10.3845 | 944.093 | 0.944093 | 8328.84
11017047 | 3.20998 | 8.99676 | 709.406 | 0.709406 | 11659.7
11017643 | 0.710534 | 2.23739 | 157.028 | 0.157028 | 3693.76
11017952 | 1.43086 | 4.4302 | 316.221 | 0.316221 | 7097.19
11018351 | 0.719324 | 2.25685 | 158.971 | 0.158971 | 3702.29
11018572 | 3.12235 | 8.81278 | 690.039 | 0.690039 | 11620.3
11018962 | 3.18366 | 8.93498 | 703.589 | 0.703589 | 11618.4
11019332 | 3.83828 | 10.4915 | 848.26 | 0.84826 | 12737.4

# IfcSlab: Floor:NLRS_23_FL_Houten balk laag 245mm met multiplex (2)
In: 01 eerste verdieping
Type - PredefinedType: FLOOR; Material: NLRS_i4_hout_multiplex 18 mm, NLRS_i2_hout naaldhout vuren_gen 245 mm
Type - Pset_ElementShading - Roughness: 304.8 mm
Type - Pset_ProductRequirements - Category: Floors
Type - Pset_QuantityTakeOff - Reference: Floor:NLRS_23_FL_Houten balk laag 245mm met multiplex
Type - Pset_ReinforcementBarPitchOfSlab - Description: VBI kanaalplaatvloer 320mm; Reference: Floor:NLRS_23_FL_Houten balk laag 245mm met multiplex
Type - Pset_SlabCommon - IsExternal: no; Reference: Floor:NLRS_23_FL_Houten balk laag 245mm met multiplex
Classification: 23.20 vloeren; constructief, algemeen (verzamelniveau) (Uniformat)
Pset_SlabCommon - LoadBearing: no; PitchAngle: 0 deg
Name (Floor:NLRS_23_FL_Houten balk laag 245mm met multiplex:...) | GrossArea (m2) | NetArea (m2) | NetVolume (m3) | Perimeter (mm)
2847334 | 172.726 | 361.184 | 45.427 | 59813.2 | BaseQuantities - GrossVolume: 45427 m3; Width: 263 mm
3427480 | 94.6465 | 196.686 | 24.2227 | 47465.9

# IfcSlab: Floor:NLRS_23_FL_Houten balk laag 271mm met multiplex (3)
In: 01 eerste verdieping
Type - PredefinedType: FLOOR; Material: NLRS_i4_hout_multiplex 18 mm, NLRS_i2_hout naaldhout vuren_gen 271 mm
Type - Pset_ElementShading - Roughness: 304.8 mm
Type - Pset_ProductRequirements - Category: Floors
Type - Pset_QuantityTakeOff - Reference: Floor:NLRS_23_FL_Houten balk laag 271mm met multiplex
Type - Pset_ReinforcementBarPitchOfSlab - Description: VBI kanaalplaatvloer 320mm; Reference: Floor:NLRS_23_FL_Houten balk laag 271mm met multiplex
Type - Pset_SlabCommon - IsExternal: no; Reference: Floor:NLRS_23_FL_Houten balk laag 271mm met multiplex
Classification: 23.20 vloeren; constructief, algemeen (verzamelniveau) (Uniformat)
Pset_SlabCommon - LoadBearing: no; PitchAngle: 0 deg
BaseQuantities - Width: 289 mm
Name (Floor:NLRS_23_FL_Houten balk laag 271mm met multiplex:...) | GrossArea (m2) | NetArea (m2) | GrossVolume (m3) | NetVolume (m3) | Perimeter (mm)
5679316 | 37.593 | 83.0442 | 10864.4 | 10.8645 | 27189.3
5679888 | 37.6784 | 83.232 | 10889.1 | 10.8891 | 27249
6564898 | 18.1286 | 41.6033 | 5239.16 | 5.23916 | 18498.7

# IfcSlab: Floor:NLRS_23_FL_PIR isolatie 100mm (3)
In: 02 tweede verdieping
Type - PredefinedType: FLOOR; Material: NLRS_n7_isolatie PIR_gen 100 mm
Type - Pset_ElementShading - Roughness: 304.8 mm
Type - Pset_ProductRequirements - Category: Floors
Type - Pset_QuantityTakeOff - Reference: Floor:NLRS_23_FL_PIR isolatie 100mm
Type - Pset_ReinforcementBarPitchOfSlab - Description: VBI kanaalplaatvloer 320mm; Reference: Floor:NLRS_23_FL_PIR isolatie 100mm
Type - Pset_SlabCommon - IsExternal: no; Reference: Floor:NLRS_23_FL_PIR isolatie 100mm
Classification: 23.10 vloeren; niet constructief, algemeen (verzamelniveau) (Uniformat)
Pset_SlabCommon - LoadBearing: no; PitchAngle: 0 deg
BaseQuantities - Width: 100 mm
Name (Floor:NLRS_23_FL_PIR isolatie 100mm:...) | GrossArea (m2) | NetArea (m2) | GrossVolume (m3) | NetVolume (m3) | Perimeter (mm)
6523095 | 5.81646 | 18.1051 | 581.646 | 0.581408 | 64721.8
6528939 | 5.71312 | 19.0272 | 571.312 | 0.571312 | 76009.1
6566961 | 2.29905 | 6.5507 | 229.905 | 0.229905 | 19525.9

# IfcSlab: Floor:NLRS_23_FL_Pir dakisolatie 140mm (2)
In: 01 eerste verdieping
Type - PredefinedType: FLOOR; Material: NLRS_n7_isolatie PIR_gen 140 mm
Type - Pset_ElementShading - Roughness: 304.8 mm
Type - Pset_ProductRequirements - Category: Floors
Type - Pset_QuantityTakeOff - Reference: Floor:NLRS_23_FL_Pir dakisolatie 140mm
Type - Pset_ReinforcementBarPitchOfSlab - Description: VBI kanaalplaatvloer 320mm; Reference: Floor:NLRS_23_FL_Pir dakisolatie 140mm
Type - Pset_SlabCommon - IsExternal: no; Reference: Floor:NLRS_23_FL_Pir dakisolatie 140mm
Classification: 23.11 vloeren; niet constructief, vrijdragende Vloeren (Uniformat)
Pset_SlabCommon - LoadBearing: no; PitchAngle: 0 deg
Name (Floor:NLRS_23_FL_Pir dakisolatie 140mm:...) | GrossArea (m2) | NetArea (m2) | NetVolume (m3) | Perimeter (mm)
3342465 | 61.4345 | 127.684 | 8.60082 | 34392.2 | BaseQuantities - GrossVolume: 8600.82 m3; Width: 140 mm
4039732 | 168.654 | 339.815 | 23.1798 | 61964.8

# IfcSlab: Floor:NLRS_23_FL_Pir dakisolatie 200mm, Floor:NLRS_23_FL_Pir dakisolatie 200mm:9204631
In: 01 eerste verdieping
Type - PredefinedType: FLOOR
Type - Pset_ElementShading - Roughness: 304.8 mm
Type - Pset_ProductRequirements - Category: Floors
Type - Pset_QuantityTakeOff - Reference: Floor:NLRS_23_FL_Pir dakisolatie 200mm
Type - Pset_ReinforcementBarPitchOfSlab - Description: VBI kanaalplaatvloer 320mm; Reference: Floor:NLRS_23_FL_Pir dakisolatie 200mm
Type - Pset_SlabCommon - IsExternal: no; Reference: Floor:NLRS_23_FL_Pir dakisolatie 200mm
Classification: 23.11 vloeren; niet constructief, vrijdragende Vloeren (Uniformat); Material: NLRS_n7_isolatie PIR_gen
Pset_SlabCommon - LoadBearing: no; PitchAngle: 0.916654 deg
BaseQuantities - NetArea: 327.877 m2; NetVolume: 5.85216 m3; Perimeter: 61964.8 mm

# IfcSlab: Floor:NLRS_23_FL_Pir dakisolatie afschot (3)
In: 01 eerste verdieping
Type - PredefinedType: FLOOR
Type - Pset_ElementShading - Roughness: 304.8 mm
Type - Pset_ProductRequirements - Category: Floors
Type - Pset_QuantityTakeOff - Reference: Floor:NLRS_23_FL_Pir dakisolatie afschot
Type - Pset_ReinforcementBarPitchOfSlab - Description: VBI kanaalplaatvloer 320mm; Reference: Floor:NLRS_23_FL_Pir dakisolatie afschot
Type - Pset_SlabCommon - IsExternal: no; Reference: Floor:NLRS_23_FL_Pir dakisolatie afschot
Classification: 23.11 vloeren; niet constructief, vrijdragende Vloeren (Uniformat)
Pset_SlabCommon - LoadBearing: no; PitchAngle: 0.916654 deg
Name (Floor:NLRS_23_FL_Pir dakisolatie afschot:...) | NetArea (m2) | NetVolume (m3) | Perimeter (mm)
3893016 | 1084.58 | 102.351 | 110762 | Material: NLRS_n7_isolatie PIR_gen
4044219 | 270.811 | 25.4568 | 65518.6
8056303 | 120.856 | 3.18145 | 34392.2

# IfcSlab: Floor:NLRS_23_FL_Trampeziumplaat 106R/750, Floor:NLRS_23_FL_Trampeziumplaat 106R/750:3272956
In: 01 eerste verdieping
Type - PredefinedType: FLOOR; Material: NLRS_h3_staal_verzinkt 108 mm
Type - Pset_ElementShading - Roughness: 304.8 mm
Type - Pset_ProductRequirements - Category: Floors
Type - Pset_QuantityTakeOff - Reference: Floor:NLRS_23_FL_Trampeziumplaat 106R/750
Type - Pset_ReinforcementBarPitchOfSlab - Description: VBI kanaalplaatvloer 320mm; Reference: Floor:NLRS_23_FL_Trampeziumplaat 106R/750
Type - Pset_SlabCommon - IsExternal: no; Reference: Floor:NLRS_23_FL_Trampeziumplaat 106R/750; ThermalTransmittance: 416.667 kg/K/s3
Classification: 23.20 vloeren; constructief, algemeen (verzamelniveau) (Uniformat)
Pset_SlabCommon - LoadBearing: no; PitchAngle: 0 deg
BaseQuantities - GrossArea: 179.856 m2; NetArea: 361.35 m2; NetVolume: 19.1496 m3; Perimeter: 62311.4 mm

# IfcSlab: Floor:NLRS_23_FL_VBI PS-isolatievloer 210mm, Floor:NLRS_23_FL_VBI PS-isolatievloer 210mm:2974161
In: 00 begane grond
Type - PredefinedType: FLOOR; Material: NLRS_f2_beton 210 mm
Type - Pset_ElementShading - Roughness: 304.8 mm
Type - Pset_ProductRequirements - Category: Floors
Type - Pset_QuantityTakeOff - Reference: Floor:NLRS_23_FL_VBI PS-isolatievloer 210mm
Type - Pset_ReinforcementBarPitchOfSlab - Description: VBI kanaalplaatvloer 200mm; Reference: Floor:NLRS_23_FL_VBI PS-isolatievloer 210mm
Type - Pset_SlabCommon - IsExternal: no; Reference: Floor:NLRS_23_FL_VBI PS-isolatievloer 210mm
Classification: 23.21 vloeren; constructief, vrijdragende vloeren (Uniformat)
Pset_SlabCommon - LoadBearing: no; PitchAngle: 0 deg
BaseQuantities - GrossArea: 1722.14 m2; NetArea: 3507.12 m2; GrossVolume: 361649 m3; NetVolume: 361.649 m3; Perimeter: 299223 mm; Width: 210 mm

# IfcSlab: Floor:NLRS_23_FL_basisvloer 180mm_gen_aly, Floor:NLRS_23_FL_basisvloer 180mm_gen_aly:3382696
In: 01 eerste verdieping
Type - PredefinedType: FLOOR
Type - Pset_ElementShading - Roughness: 304.8 mm
Type - Pset_ProductRequirements - Category: Floors
Type - Pset_QuantityTakeOff - Reference: Floor:NLRS_23_FL_basisvloer 180mm_gen_aly
Type - Pset_ReinforcementBarPitchOfSlab - Reference: Floor:NLRS_23_FL_basisvloer 180mm_gen_aly
Type - Pset_SlabCommon - IsExternal: no; Reference: Floor:NLRS_23_FL_basisvloer 180mm_gen_aly
Classification: 23.21 vloeren; constructief, vrijdragende vloeren (Uniformat)
Pset_QuantityTakeOff - sets with these values: 2
Pset_SlabCommon - LoadBearing: no; PitchAngle: 0 deg
BaseQuantities - NetArea: 19.7454 m2; NetVolume: 1.22953 m3; Perimeter: 33958.2 mm

# IfcSlab: Floor:NLRS_23_FL_basisvloer 260mm_gen_al, Floor:NLRS_23_FL_basisvloer 260mm_gen_al:2872386
In: 00 begane grond
Type - PredefinedType: FLOOR; Material: NLRS_f2_beton 260 mm
Type - Pset_ElementShading - Roughness: 304.8 mm
Type - Pset_ProductRequirements - Category: Floors
Type - Pset_QuantityTakeOff - Reference: Floor:NLRS_23_FL_basisvloer 260mm_gen_al
Type - Pset_ReinforcementBarPitchOfSlab - Reference: Floor:NLRS_23_FL_basisvloer 260mm_gen_al
Type - Pset_SlabCommon - IsExternal: no; Reference: Floor:NLRS_23_FL_basisvloer 260mm_gen_al
Classification: 23.21 vloeren; constructief, vrijdragende vloeren (Uniformat)
Pset_QuantityTakeOff - sets with these values: 2
Pset_SlabCommon - LoadBearing: no; PitchAngle: 0 deg
BaseQuantities - GrossArea: 120.354 m2; NetArea: 252.34 m2; GrossVolume: 31292 m3; NetVolume: 31.292 m3; Perimeter: 44739.8 mm; Width: 260 mm

# IfcSlab: Floor:NLRS_23_FL_basisvloer 330mm_gen_aly, Floor:NLRS_23_FL_basisvloer 330mm_gen_aly:2872693
In: 00 begane grond
Type - PredefinedType: FLOOR
Type - Pset_ElementShading - Roughness: 304.8 mm
Type - Pset_ProductRequirements - Category: Floors
Type - Pset_QuantityTakeOff - Reference: Floor:NLRS_23_FL_basisvloer 330mm_gen_aly
Type - Pset_ReinforcementBarPitchOfSlab - Reference: Floor:NLRS_23_FL_basisvloer 330mm_gen_aly
Type - Pset_SlabCommon - IsExternal: no; Reference: Floor:NLRS_23_FL_basisvloer 330mm_gen_aly
Classification: 23.21 vloeren; constructief, vrijdragende vloeren (Uniformat)
Pset_QuantityTakeOff - sets with these values: 2
Pset_SlabCommon - LoadBearing: no; PitchAngle: 0 deg
BaseQuantities - GrossArea: 92.0802 m2; NetArea: 197.738 m2; GrossVolume: 30386.5 m3; NetVolume: 30.3865 m3; Perimeter: 41143.3 mm; Width: 330 mm

# IfcSlab: Floor:NLRS_23_FL_basisvloer 380mm (vloer sportzaal), Floor:NLRS_23_FL_basisvloer 380mm (vloer sportzaal):2872893
In: 00 begane grond
Type - PredefinedType: FLOOR; Material: NLRS_f2_beton (bestaande vloer sportzaal) 380 mm
Type - Pset_ElementShading - Roughness: 304.8 mm
Type - Pset_ProductRequirements - Category: Floors
Type - Pset_QuantityTakeOff - Reference: Floor:NLRS_23_FL_basisvloer 380mm (vloer sportzaal)
Type - Pset_ReinforcementBarPitchOfSlab - Reference: Floor:NLRS_23_FL_basisvloer 380mm (vloer sportzaal)
Type - Pset_SlabCommon - IsExternal: no; Reference: Floor:NLRS_23_FL_basisvloer 380mm (vloer sportzaal)
Classification: 23.21 vloeren; constructief, vrijdragende vloeren (Uniformat)
Pset_QuantityTakeOff - sets with these values: 2
Pset_SlabCommon - LoadBearing: no; PitchAngle: 0 deg
BaseQuantities - GrossArea: 425.804 m2; NetArea: 885.527 m2; GrossVolume: 161805 m3; NetVolume: 161.805 m3; Perimeter: 89262 mm; Width: 380 mm

# IfcSlab: Floor:NLRS_27_FL_houtenvloer_170-18_gen_aly (2)
Type - PredefinedType: FLOOR; Material: NLRS_i4_hout_underlayment 18 mm, NLRS_i2_hout_naaldhout (vuren) 170 mm
Type - Pset_ElementShading - Roughness: 304.8 mm
Type - Pset_ProductRequirements - Category: Floors
Type - Pset_QuantityTakeOff - Reference: Floor:NLRS_27_FL_houtenvloer_170-18_gen_aly
Type - Pset_ReinforcementBarPitchOfSlab - Description: Houten vloer; Reference: Floor:NLRS_27_FL_houtenvloer_170-18_gen_aly
Type - Pset_SlabCommon - IsExternal: no; Reference: Floor:NLRS_27_FL_houtenvloer_170-18_gen_aly
Classification: 23.21 vloeren; constructief, vrijdragende vloeren (Uniformat)
Pset_SlabCommon - LoadBearing: no; PitchAngle: 0 deg
BaseQuantities - Width: 188 mm
Name (Floor:NLRS_27_FL_houtenvloer_170-18_gen_aly:...) | In | GrossArea (m2) | NetArea (m2) | GrossVolume (m3) | NetVolume (m3) | Perimeter (mm)
3269538 | 00 begane grond | 68.7951 | 145.211 | 12933.5 | 12.9335 | 40537.5
4288535 | Podium | 7.81234 | 18.2065 | 1468.72 | 1.46872 | 13733

# IfcSlab: Floor:NLRS_27_FL_houtwerk erkerkozijn boven, Floor:NLRS_27_FL_houtwerk erkerkozijn boven:6305875
In: Podium
Type - PredefinedType: FLOOR; Material: NLRS_i4_hout_underlayment 18 mm, NLRS_i2_hout_naaldhout (vuren) 184 mm
Type - Pset_ElementShading - Roughness: 304.8 mm
Type - Pset_ProductRequirements - Category: Floors
Type - Pset_QuantityTakeOff - Reference: Floor:NLRS_27_FL_houtwerk erkerkozijn boven
Type - Pset_ReinforcementBarPitchOfSlab - Description: Houten vloer; Reference: Floor:NLRS_27_FL_houtwerk erkerkozijn boven
Type - Pset_SlabCommon - IsExternal: no; Reference: Floor:NLRS_27_FL_houtwerk erkerkozijn boven
Classification: 23.20 vloeren; constructief, algemeen (verzamelniveau) (Uniformat)
Pset_SlabCommon - LoadBearing: no; PitchAngle: 0 deg
BaseQuantities - GrossArea: 2.37366 m2; NetArea: 6.59825 m2; GrossVolume: 479.48 m3; NetVolume: 0.47948 m3; Perimeter: 9163 mm; Width: 202 mm

# IfcSlab: Floor:NLRS_27_FL_houtwerk erkerkozijn onder, Floor:NLRS_27_FL_houtwerk erkerkozijn onder:6305352
In: 00 begane grond
Type - PredefinedType: FLOOR; Material: NLRS_i2_hout_naaldhout (vuren) 184 mm, NLRS_i4_hout_underlayment 9 mm
Type - Pset_ElementShading - Roughness: 304.8 mm
Type - Pset_ProductRequirements - Category: Floors
Type - Pset_QuantityTakeOff - Reference: Floor:NLRS_27_FL_houtwerk erkerkozijn onder
Type - Pset_ReinforcementBarPitchOfSlab - Description: Houten vloer; Reference: Floor:NLRS_27_FL_houtwerk erkerkozijn onder
Type - Pset_SlabCommon - IsExternal: no; Reference: Floor:NLRS_27_FL_houtwerk erkerkozijn onder
Classification: 23.20 vloeren; constructief, algemeen (verzamelniveau) (Uniformat)
Pset_SlabCommon - LoadBearing: no; PitchAngle: 0 deg
BaseQuantities - GrossArea: 2.31188 m2; NetArea: 6.38624 m2; GrossVolume: 446.193 m3; NetVolume: 0.446193 m3; Perimeter: 9132 mm; Width: 193 mm

# IfcSlab: Floor:NLRS_44_FL_Multiplex 15mm (7)
In: 01 eerste verdieping
Type - PredefinedType: ROOF
Type - Pset_ElementShading - Roughness: 304.8 mm
Type - Pset_ProductRequirements - Category: Floors
Type - Pset_QuantityTakeOff - Reference: Floor:NLRS_44_FL_Multiplex 15mm
Type - Pset_ReinforcementBarPitchOfSlab - Reference: Floor:NLRS_44_FL_Multiplex 15mm
Type - Pset_SlabCommon - IsExternal: no; Reference: Floor:NLRS_44_FL_Multiplex 15mm
Classification: 44.10 trap- en hellingafwerkingen; trapafwerkingen, algemeen (verzamelniveau) (Uniformat); Material: NLRS_i4_hout_multiplex
Pset_QuantityTakeOff - sets with these values: 2
Pset_SlabCommon - LoadBearing: no
Name (Floor:NLRS_44_FL_Multiplex 15mm:...) | PitchAngle (deg) | GrossArea (m2) | NetArea (m2) | GrossVolume (m3) | NetVolume (m3) | Perimeter (mm) | Width (mm)
3252953 | 3.41988 | 0.0272752 | 6.55244 | 0.408399 | 0.046758 | 20947.1 | 14.9733
3252953 | 1.53571 | 0.112377 | 6.55244 | 1.68505 | 0.046758 | 20947.1 | 14.9946
3252953 | 3.45202 | 0.0244275 | 6.55244 | 0.365747 | 0.046758 | 20947.1 | 14.9728
3252953 | 1.53571 | 0.125696 | 6.55244 | 1.88476 | 0.046758 | 20947.1 | 14.9946
4238366 | 1.66996 | 0.387254 | 14.4314 | 5.80634 | 0.103015 | 45790.5 | 14.9936
4238366 | 1.29314 | 0.170564 | 14.4314 | 2.55781 | 0.103015 | 45790.5 | 14.9962
4238366 | 4.20536 | 0.0806373 | 14.4314 | 1.2063 | 0.103015 | 45790.5 | 14.9596

# IfcSlab: Houten balklaag soosruimte:Houten balklaag soosruimte, Houten balklaag soosruimte:Houten balklaag soosruimte:9829411
In: 01 eerste verdieping
Type - PredefinedType: FLOOR; Material: NLRS_i2_hout_naaldhout (vuren)
Type - Pset_ProductRequirements - Category: Floors
Type - Pset_QuantityTakeOff - Reference: Houten balklaag soosruimte:Houten balklaag soosruimte
Type - Pset_ReinforcementBarPitchOfSlab - Reference: Houten balklaag soosruimte:Houten balklaag soosruimte
Type - Pset_SlabCommon - IsExternal: no; Reference: Houten balklaag soosruimte:Houten balklaag soosruimte
Pset_QuantityTakeOff - sets with these values: 2
BaseQuantities - GrossArea: 0.320175 m2; NetArea: 9.69803 m2; GrossVolume: 62.7542 m3; NetVolume: 0.245477 m3; Perimeter: 9161 mm; Width: 196 mm

# IfcSlab: Non-Monolithic Landing:Non-Monolithic Landing (3)
In: 00 begane grond
Type - PredefinedType: LANDING
Type - Pset_ProductRequirements - Category: Landings
Type - Pset_QuantityTakeOff - Reference: Non-Monolithic Landing:Non-Monolithic Landing
Type - Pset_ReinforcementBarPitchOfSlab - Reference: Non-Monolithic Landing:Non-Monolithic Landing
Type - Pset_SlabCommon - IsExternal: no; Reference: Non-Monolithic Landing:Non-Monolithic Landing
Classification: 24.1 trappen en hellingen; trappen (Uniformat); Material: AL_31_Naaldhout Trap treden
Pset_QuantityTakeOff - sets with these values: 2
Name (Assembled Stair:Stair:...) | NetArea (m2) | NetVolume (m3)
5926983 Landing 1 | 3.5409 | 0.0814785
6433297 Landing 1 | 1.6257 | 0.0362585
6433383 Landing 1 | 1.6257 | 0.0362586

# IfcSlab: Plafond erkers mf zaal1:Plafond erkers mf zaal, Plafond erkers mf zaal1:Plafond erkers mf zaal:9283742:1
In: 01 eerste verdieping
Type - PredefinedType: ROOF
Type - Pset_ProductRequirements - Category: Roofs
Type - Pset_QuantityTakeOff - Reference: Plafond erkers mf zaal1:Plafond erkers mf zaal
Type - Pset_ReinforcementBarPitchOfSlab - Reference: Plafond erkers mf zaal1:Plafond erkers mf zaal
Type - Pset_SlabCommon - IsExternal: yes; Reference: Plafond erkers mf zaal1:Plafond erkers mf zaal
Material: AL Houten gevelbekleding liggend
Pset_QuantityTakeOff - sets with these values: 2
BaseQuantities - GrossArea: 0.011259 m2; NetArea: 2.47134 m2; GrossVolume: 21.3921 m3; NetVolume: 0.0213921 m3; Perimeter: 1288.85 mm; Width: 1900 mm

# IfcSlab: Plafond erkers mf zaal:Plafond erkers mf zaal, Plafond erkers mf zaal:Plafond erkers mf zaal:9283606:1
In: 01 eerste verdieping
Type - PredefinedType: ROOF
Type - Pset_ProductRequirements - Category: Roofs
Type - Pset_QuantityTakeOff - Reference: Plafond erkers mf zaal:Plafond erkers mf zaal
Type - Pset_ReinforcementBarPitchOfSlab - Reference: Plafond erkers mf zaal:Plafond erkers mf zaal
Type - Pset_SlabCommon - IsExternal: yes; Reference: Plafond erkers mf zaal:Plafond erkers mf zaal
Material: AL Houten gevelbekleding liggend
Pset_QuantityTakeOff - sets with these values: 2
BaseQuantities - GrossArea: 0.0121935 m2; NetArea: 2.42107 m2; GrossVolume: 23.1677 m3; NetVolume: 0.0231677 m3; Perimeter: 1261.41 mm; Width: 1900 mm

# IfcSlab: Poeren onder kolommen1:Poeren onder kolommen, Poeren onder kolommen1:Poeren onder kolommen:3863966
In: 00 begane grond
Type - PredefinedType: FLOOR; Material: NLRS_f2_beton
Type - Pset_ProductRequirements - Category: Floors
Type - Pset_QuantityTakeOff - Reference: Poeren onder kolommen1:Poeren onder kolommen
Type - Pset_ReinforcementBarPitchOfSlab - Reference: Poeren onder kolommen1:Poeren onder kolommen
Type - Pset_SlabCommon - IsExternal: no; Reference: Poeren onder kolommen1:Poeren onder kolommen
Pset_QuantityTakeOff - sets with these values: 2
BaseQuantities - GrossArea: 0.64 m2; NetArea: 2.944 m2; GrossVolume: 332.8 m3; NetVolume: 0.3328 m3; Perimeter: 3200 mm; Width: 520 mm

# IfcSlab: Poeren onder kolommen3:Poeren onder kolommen, Poeren onder kolommen3:Poeren onder kolommen:3863997
In: 00 begane grond
Type - PredefinedType: FLOOR; Material: NLRS_f2_beton
Type - Pset_ProductRequirements - Category: Floors
Type - Pset_QuantityTakeOff - Reference: Poeren onder kolommen3:Poeren onder kolommen
Type - Pset_ReinforcementBarPitchOfSlab - Reference: Poeren onder kolommen3:Poeren onder kolommen
Type - Pset_SlabCommon - IsExternal: no; Reference: Poeren onder kolommen3:Poeren onder kolommen
Pset_QuantityTakeOff - sets with these values: 2
BaseQuantities - GrossArea: 0.64 m2; NetArea: 2.944 m2; GrossVolume: 332.8 m3; NetVolume: 0.3328 m3; Perimeter: 3200 mm; Width: 520 mm

# IfcSlab: Zinken beplating dakgoot1:Zinken beplating dakgoot, Zinken beplating dakgoot1:Zinken beplating dakgoot:5226448:1
In: Podium
Type - PredefinedType: ROOF
Type - Pset_ProductRequirements - Category: Roofs
Type - Pset_QuantityTakeOff - Reference: Zinken beplating dakgoot1:Zinken beplating dakgoot
Type - Pset_ReinforcementBarPitchOfSlab - Reference: Zinken beplating dakgoot1:Zinken beplating dakgoot
Type - Pset_SlabCommon - IsExternal: yes; Reference: Zinken beplating dakgoot1:Zinken beplating dakgoot
Material: NLRS_i4_hout_multiplex zwart, h7_zink zwart, j7_hout_spaanplaat, NLRS_j7_hout_spaanplaat, AL_31_Naaldhout (vuren)
Pset_QuantityTakeOff - sets with these values: 2
BaseQuantities - GrossArea: 0.000368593 m2; NetArea: 49.0789 m2; GrossVolume: 3.42575 m3; NetVolume: 0.259681 m3; Perimeter: 739.187 mm; Width: 9294.13 mm

# IfcSlab: Zinken beplating dakgoot2:Zinken beplating dakgoot, Zinken beplating dakgoot2:Zinken beplating dakgoot:5227441:1
In: Podium
Type - PredefinedType: ROOF
Type - Pset_ProductRequirements - Category: Roofs
Type - Pset_QuantityTakeOff - Reference: Zinken beplating dakgoot2:Zinken beplating dakgoot
Type - Pset_ReinforcementBarPitchOfSlab - Reference: Zinken beplating dakgoot2:Zinken beplating dakgoot
Type - Pset_SlabCommon - IsExternal: yes; Reference: Zinken beplating dakgoot2:Zinken beplating dakgoot
Material: NLRS_i4_hout_multiplex zwart, h7_zink zwart, j7_hout_spaanplaat, NLRS_j7_hout_spaanplaat, AL_31_Naaldhout (vuren)
Pset_QuantityTakeOff - sets with these values: 2
BaseQuantities - GrossArea: 0.000368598 m2; NetArea: 94.562 m2; GrossVolume: 6.61056 m3; NetVolume: 0.500532 m3; Perimeter: 739.195 mm; Width: 17934.3 mm

# IfcSlab: Zinken beplating dakgoot4:Zinken beplating dakgoot, Zinken beplating dakgoot4:Zinken beplating dakgoot:9918800:1
In: Podium
Type - PredefinedType: ROOF
Type - Pset_ProductRequirements - Category: Roofs
Type - Pset_QuantityTakeOff - Reference: Zinken beplating dakgoot4:Zinken beplating dakgoot
Type - Pset_ReinforcementBarPitchOfSlab - Reference: Zinken beplating dakgoot4:Zinken beplating dakgoot
Type - Pset_SlabCommon - IsExternal: yes; Reference: Zinken beplating dakgoot4:Zinken beplating dakgoot
Material: NLRS_i4_hout_multiplex zwart, h7_zink zwart, j7_hout_spaanplaat, NLRS_j7_hout_spaanplaat, AL_31_Naaldhout (vuren)
Pset_QuantityTakeOff - sets with these values: 2
BaseQuantities - GrossArea: 0.000368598 m2; NetArea: 125.477 m2; GrossVolume: 8.9491 m3; NetVolume: 0.667612 m3; Perimeter: 739.195 mm; Width: 24278.8 mm

# IfcSlab: balklaag luifel:balklaag luifel, balklaag luifel:balklaag luifel:3171619:1
In: Podium
Type - PredefinedType: ROOF
Type - Pset_ProductRequirements - Category: Structural Framing
Type - Pset_QuantityTakeOff - Reference: balklaag luifel:balklaag luifel
Type - Pset_ReinforcementBarPitchOfSlab - Reference: balklaag luifel:balklaag luifel
Type - Pset_SlabCommon - IsExternal: no; LoadBearing: yes; Reference: balklaag luifel:balklaag luifel
Classification: 27.23 daken; constructief, luifels (Uniformat); Material: AL Houten beplating gevel erker sportkantine
Pset_QuantityTakeOff - sets with these values: 2
BaseQuantities - GrossArea: 0.4669 m2; NetArea: 26.1341 m2; GrossVolume: 140.07 m3; NetVolume: 0.730915 m3; Perimeter: 13480 mm; Width: 300 mm

# IfcStair: Assembled Stair:27_woningbouw (10)
Classification: 24.1 trappen en hellingen; trappen (Uniformat)
Pset_ProductRequirements - Category: Stairs
Pset_QuantityTakeOff - Reference: Assembled Stair:Stair
Pset_StairCommon - IsExternal: no; Reference: Assembled Stair:Stair
Name (Assembled Stair:Stair:...) | In | ShapeType | NumberOfRiser | NumberOfTreads | RiserHeight (mm) | TreadLength (mm)
3285954 | 00 begane grond | STRAIGHT_RUN_STAIR | 3 | 2 | 400 | 230
3286874 | 00 begane grond | STRAIGHT_RUN_STAIR | 3 | 2 | 400 | 230
5926983 | 00 begane grond | HALF_TURN_STAIR | 15 | 13 | 204.667 | 200
6433297 | 00 begane grond | QUARTER_TURN_STAIR | 16 | 14 | 198.125 | 185
6433383 | 00 begane grond | QUARTER_TURN_STAIR | 16 | 14 | 198.125 | 185
6459863 | 01 eerste verdieping | STRAIGHT_RUN_STAIR | 7 | 6 | 185.143 | 185
6460690 | 01 eerste verdieping | STRAIGHT_RUN_STAIR | 7 | 6 | 185.143 | 185
9385217 | 00 begane grond | STRAIGHT_RUN_STAIR | 6 | 5 | 200 | 185
9386611 | 00 begane grond | STRAIGHT_RUN_STAIR | 6 | 5 | 200 | 185
9386774 | 00 begane grond | STRAIGHT_RUN_STAIR | 6 | 5 | 200 | 185

# IfcStair: Ondersteuning trap 1e verdieping buiten1:Ondersteuning trap 1e verdieping buiten (2)
In: 01 eerste verdieping
Name (Ondersteuning trap 1e verdieping buiten1:Ondersteuning trap 1e verdieping buiten:...)
4305369
4305369 | Pset_ProductRequirements - Category: Stairs; Pset_QuantityTakeOff - Reference: Ondersteuning trap 1e verdieping buiten1:Ondersteuning trap 1e verdieping buiten; Pset_StairCommon - IsExternal: no; Reference: Ondersteuning trap 1e verdieping buiten1:Ondersteuning trap 1e verdieping buiten

# IfcStair: Ondersteuning trap 1e verdieping buiten:Ondersteuning trap 1e verdieping buiten (2)
In: 01 eerste verdieping
Name (Ondersteuning trap 1e verdieping buiten:Ondersteuning trap 1e verdieping buiten:...)
4303455
4303455 | Pset_ProductRequirements - Category: Stairs; Pset_QuantityTakeOff - Reference: Ondersteuning trap 1e verdieping buiten:Ondersteuning trap 1e verdieping buiten; Pset_StairCommon - IsExternal: no; Reference: Ondersteuning trap 1e verdieping buiten:Ondersteuning trap 1e verdieping buiten

# IfcStair: Treden podium school:Treden podium school (2)
In: 00 begane grond
Name (Treden podium school:Treden podium school:...)
7830156
7830156 | Pset_ProductRequirements - Category: Stairs; Pset_QuantityTakeOff - Reference: Treden podium school:Treden podium school; Pset_StairCommon - IsExternal: no; Reference: Treden podium school:Treden podium school

# IfcStairFlight: Non-Monolithic Run:50 mm Tread 10 mm Nosing 13 mm Riser (11)
Type - PredefinedType: STRAIGHT
Type - Pset_ProductRequirements - Category: Runs
Type - Pset_QuantityTakeOff - Reference: Non-Monolithic Run:50 mm Tread 10 mm Nosing 13 mm Riser
Type - Pset_StairFlightCommon - Reference: Non-Monolithic Run:50 mm Tread 10 mm Nosing 13 mm Riser; NosingLength: 10 mm
Classification: 24.1 trappen en hellingen; trappen (Uniformat); Material: AL_31_Naaldhout Trap treden
Name (Assembled Stair:Stair:...) | In | NumberOfRiser = Pset_StairFlightCommon, NumberOfRiser | NumberOfTreads = Pset_StairFlightCommon, NumberOfTreads | RiserHeight (mm) | TreadLength (mm) | Pset_StairFlightCommon, RiserHeight (mm) | Pset_StairFlightCommon, TreadLength (mm) = TreadLengthAtOffset (mm) = TreadLengthAtInnerSide (mm) | WalkingLineOffset (mm) | Length (mm) | NetVolume (m3) | GrossVolume (m3)
5926983 Run 1 | 00 begane grond | 8 | 7 | 0.671479 | 0.656168 | 204.667 | 200 | 1.39436 | 1400 | 0.0773001
5926983 Run 2 | 00 begane grond | 7 | 6 | 0.671479 | 0.656168 | 204.667 | 200 | 1.39436 | 1200 | 0.0670233 | 8.6335
6433297 Run 1 | 00 begane grond | 9 | 8 | 0.650016 | 0.606955 | 198.125 | 185 | 1.39436 | 1480 | 0.0823827
6433297 Run 2 | 00 begane grond | 7 | 6 | 0.650016 | 0.606955 | 198.125 | 185 | 1.39436 | 1110 | 0.0627117 | 7.996
6433383 Run 1 | 00 begane grond | 9 | 8 | 0.650016 | 0.606955 | 198.125 | 185 | 1.39436 | 1480 | 0.0823827
6433383 Run 2 | 00 begane grond | 7 | 6 | 0.650016 | 0.606955 | 198.125 | 185 | 1.39436 | 1110 | 0.0627117 | 7.996
6459863 Run 1 | 01 eerste verdieping | 7 | 6 | 0.607424 | 0.606955 | 185.143 | 185 | 1.39436 | 1110 | 0.0612149 | 7.996
6460690 Run 1 | 01 eerste verdieping | 7 | 6 | 0.607424 | 0.606955 | 185.143 | 185 | 1.39436 | 1110 | 0.0612149 | 7.996
9385217 Run 1 | 00 begane grond | 6 | 5 | 0.656168 | 0.606955 | 200 | 185 | 1.31234 | 925 | 0.0491284 | 7.52564
9386611 Run 1 | 00 begane grond | 6 | 5 | 0.656168 | 0.606955 | 200 | 185 | 1.31234 | 925 | 0.0491284 | 7.52564
9386774 Run 1 | 00 begane grond | 6 | 5 | 0.656168 | 0.606955 | 200 | 185 | 1.31234 | 925 | 0.0491284 | 7.52564

# IfcWall: Basic Wall:47.11_2 laagse APP dakbedekking (2)
In: Podium
Type - PredefinedType: STANDARD; Material: n2_bitumen_dak bedekking 6 mm
Type - Pset_ElementShading - Roughness: 304.8 mm
Type - Pset_ManufacturerTypeInformation - Manufacturer: 2 laagse APP 460P60 onderlaag met 446K14 toplaag
Type - Pset_ProductRequirements - Category: Walls
Type - Pset_QuantityTakeOff - Reference: Basic Wall:47.11_2 laagse APP dakbedekking
Type - Pset_ReinforcementBarPitchOfWall - Description: 2 laagse Bitumen APP dakbedekking; Reference: Basic Wall:47.11_2 laagse APP dakbedekking
Type - Pset_WallCommon - IsExternal: no; Reference: Basic Wall:47.11_2 laagse APP dakbedekking
Classification: 47.11 dakafwerkingen; afwerkingen, vlakke dakafwerkingen (Uniformat)
Pset_WallCommon - IsExternal: yes; ExtendToStructure: no; LoadBearing: no
Name (Basic Wall:47.11_2 laagse APP dakbedekking:...)
5800500
5901020

# IfcWall: Basic Wall:NLRS_16_WA_funderingsbalk 350x...mm_gen_aly (19)
In: ok. fundering
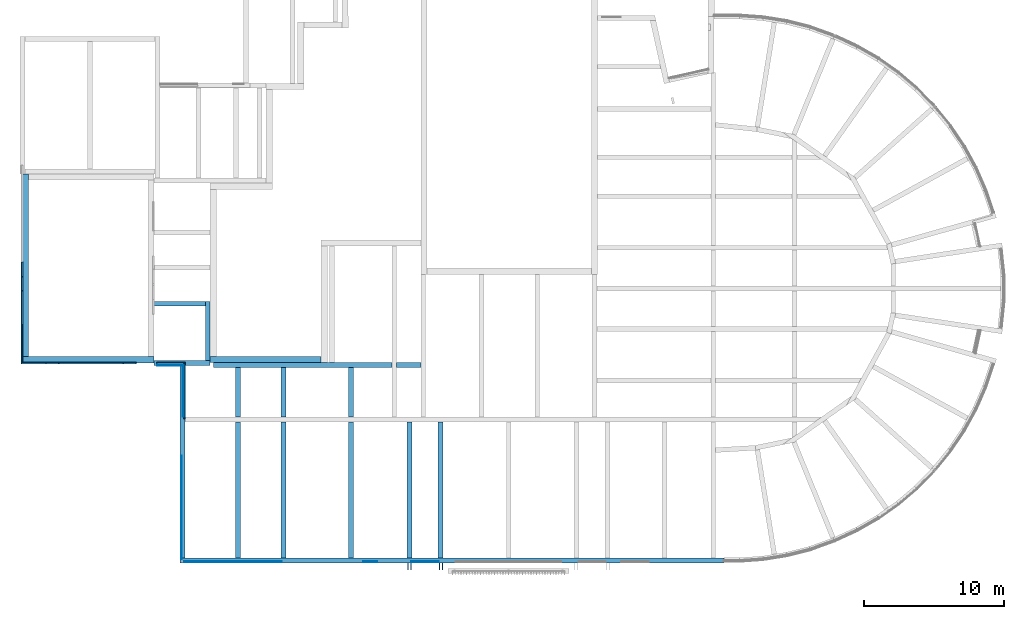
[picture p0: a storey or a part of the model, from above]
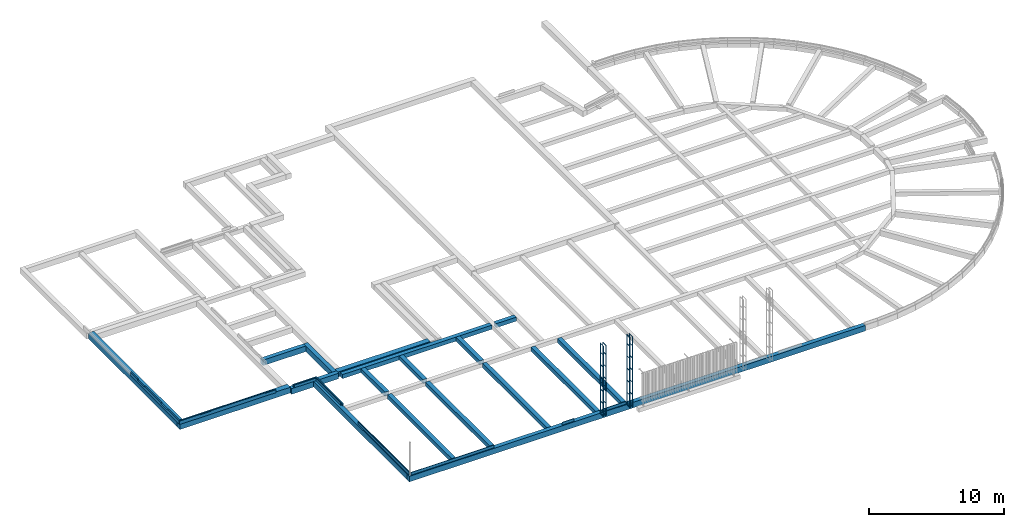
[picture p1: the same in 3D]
Properties of the parts of a building model (IFC2X3), part 9 of 13

# IfcWall: Basic Wall:NLRS_16_WA_funderingsbalk 350x...mm_gen_aly (19)
Type - PredefinedType: STANDARD; Material: NLRS_f2_beton 350 mm
Type - Pset_ConcreteElementGeneral - FireRating: -
Type - Pset_ElementShading - Roughness: 304.8 mm
Type - Pset_ProductRequirements - Category: Walls
Type - Pset_QuantityTakeOff - Reference: Basic Wall:NLRS_16_WA_funderingsbalk 350x...mm_gen_aly
Type - Pset_ReinforcementBarPitchOfWall - Description: Funderingsbalk 350x...mm; Reference: Basic Wall:NLRS_16_WA_funderingsbalk 350x...mm_gen_aly
Type - Pset_WallCommon - IsExternal: no; Reference: Basic Wall:NLRS_16_WA_funderingsbalk 350x...mm_gen_aly; FireRating: -
Classification: 16.12 funderingsconstructies; voeten en balken, fundatie balken (Uniformat); Group: Model Group:Nieuwe fundering:6653684
Pset_WallCommon - IsExternal: yes; ExtendToStructure: no; LoadBearing: no
Name (Basic Wall:NLRS_16_WA_funderingsbalk 350x...mm_gen_aly:...)
5531581
5729469
5729511
5729662
5731963
5731972
5843122
5855921
5855963
6649006
6649251
6649313
6649381
6649945
6652423
6652528
6652744
6652798
9468333

# IfcWall: Basic Wall:NLRS_20_WA_Metselwerk 100mm, Eems wf-p-0081-25 (2)
In: 00 begane grond
Type - PredefinedType: STANDARD; Material: NLRS_g2_baksteen hf-225x105x42-10mm voeg halfsteens rood genuanceerd_gen 100 mm
Type - Pset_ConcreteElementGeneral - FireRating: -
Type - Pset_ElementShading - Roughness: 304.8 mm
Type - Pset_ProductRequirements - Category: Walls
Type - Pset_QuantityTakeOff - Reference: Basic Wall:NLRS_20_WA_Metselwerk 100mm, Eems wf-p-0081-25
Type - Pset_ReinforcementBarPitchOfWall - Reference: Basic Wall:NLRS_20_WA_Metselwerk 100mm, Eems wf-p-0081-25
Type - Pset_WallCommon - IsExternal: no; Reference: Basic Wall:NLRS_20_WA_Metselwerk 100mm, Eems wf-p-0081-25; FireRating: -
Classification: 21.11 buitenwanden; niet constructief, massieve wanden (Uniformat)
Pset_QuantityTakeOff - sets with these values: 2
Pset_WallCommon - IsExternal: yes; ExtendToStructure: no; LoadBearing: no
Name (Basic Wall:NLRS_20_WA_Metselwerk 100mm, Eems wf-p-0081-25:...)
5205664
5206181

# IfcWall: Basic Wall:NLRS_20_WA_Metselwerk-100mm (6)
In: 00 begane grond
Type - PredefinedType: STANDARD; Material: AL_metselwerk 210x100x50 halfsteens geel 100 mm
Type - Pset_ConcreteElementGeneral - FireRating: -
Type - Pset_ElementShading - Roughness: 304.8 mm
Type - Pset_ProductRequirements - Category: Walls
Type - Pset_QuantityTakeOff - Reference: Basic Wall:NLRS_20_WA_Metselwerk-100mm
Type - Pset_ReinforcementBarPitchOfWall - Reference: Basic Wall:NLRS_20_WA_Metselwerk-100mm
Type - Pset_WallCommon - IsExternal: no; Reference: Basic Wall:NLRS_20_WA_Metselwerk-100mm; FireRating: -
Classification: 21.11 buitenwanden; niet constructief, massieve wanden (Uniformat)
Pset_QuantityTakeOff - sets with these values: 2
Pset_WallCommon - IsExternal: yes; ExtendToStructure: no; LoadBearing: no
Name (Basic Wall:NLRS_20_WA_Metselwerk-100mm:...)
2857856
3373606
3406420
3407971
3410630
3413285

# IfcWall: Basic Wall:NLRS_20_WA_Metselwerk-100mm zwart (2)
In: 00 begane grond
Type - PredefinedType: STANDARD; Material: AL_metselwerk 210x100x50 halfsteens zwart 100 mm
Type - Pset_ConcreteElementGeneral - FireRating: -
Type - Pset_ElementShading - Roughness: 304.8 mm
Type - Pset_ProductRequirements - Category: Walls
Type - Pset_QuantityTakeOff - Reference: Basic Wall:NLRS_20_WA_Metselwerk-100mm zwart
Type - Pset_ReinforcementBarPitchOfWall - Reference: Basic Wall:NLRS_20_WA_Metselwerk-100mm zwart
Type - Pset_WallCommon - IsExternal: no; Reference: Basic Wall:NLRS_20_WA_Metselwerk-100mm zwart; FireRating: -
Classification: 21.11 buitenwanden; niet constructief, massieve wanden (Uniformat)
Pset_QuantityTakeOff - sets with these values: 2
Pset_WallCommon - IsExternal: yes; ExtendToStructure: no; LoadBearing: no
Name (Basic Wall:NLRS_20_WA_Metselwerk-100mm zwart:...)
3410694
9260105

# IfcWall: Basic Wall:NLRS_21_WA_Gipsplaat 12.5mm (2)
In: 00 begane grond
Type - PredefinedType: STANDARD; Material: NLRS_f7_gipsplaat_gen 12.5 mm
Type - Pset_ConcreteElementGeneral - FireRating: -
Type - Pset_ElementShading - Roughness: 304.8 mm
Type - Pset_ProductRequirements - Category: Walls
Type - Pset_QuantityTakeOff - Reference: Basic Wall:NLRS_21_WA_Gipsplaat 12.5mm
Type - Pset_ReinforcementBarPitchOfWall - Description: Hsb-wand Rc=2,8m²K/W; Reference: Basic Wall:NLRS_21_WA_Gipsplaat 12.5mm
Type - Pset_WallCommon - IsExternal: no; Reference: Basic Wall:NLRS_21_WA_Gipsplaat 12.5mm; FireRating: -
Classification: 21.23 buitenwanden; constructief, systeemwanden (Uniformat)
Pset_WallCommon - LoadBearing: no
Name (Basic Wall:NLRS_21_WA_Gipsplaat 12.5mm:...) | ExtendToStructure
9942024 | yes
9942916 | no

# IfcWall: Basic Wall:NLRS_21_WA_HSB-wand_101mm ongeisoleert (3)
In: 00 begane grond
Type - PredefinedType: STANDARD; Material: NLRS_m1_isolatie 89 mm, NLRS_f7_gipsplaat_gen 12.5 mm
Type - Pset_ConcreteElementGeneral - FireRating: -
Type - Pset_ElementShading - Roughness: 304.8 mm
Type - Pset_ProductRequirements - Category: Walls
Type - Pset_QuantityTakeOff - Reference: Basic Wall:NLRS_21_WA_HSB-wand_101mm ongeisoleert
Type - Pset_ReinforcementBarPitchOfWall - Description: Hsb-wand Rc=2,8m²K/W; Reference: Basic Wall:NLRS_21_WA_HSB-wand_101mm ongeisoleert
Type - Pset_WallCommon - IsExternal: no; Reference: Basic Wall:NLRS_21_WA_HSB-wand_101mm ongeisoleert; FireRating: -
Classification: 21.23 buitenwanden; constructief, systeemwanden (Uniformat)
Pset_WallCommon - ExtendToStructure: no; LoadBearing: no
Name (Basic Wall:NLRS_21_WA_HSB-wand_101mm ongeisoleert:...)
5712792 | Material: NLRS_m1_isolatie, NLRS_f7_gipsplaat_gen
7784201
7784295

# IfcWall: Basic Wall:NLRS_21_WA_HSB-wand_110mm (8)
In: 01 eerste verdieping
Type - PredefinedType: STANDARD; Material: NLRS_i4_hout_multiplex 9 mm, NLRS_m1_isolatie 89 mm, NLRS_i4_hout_multiplex 9 mm
Type - Pset_ConcreteElementGeneral - FireRating: -
Type - Pset_ElementShading - Roughness: 304.8 mm
Type - Pset_ProductRequirements - Category: Walls
Type - Pset_QuantityTakeOff - Reference: Basic Wall:NLRS_21_WA_HSB-wand_110mm
Type - Pset_ReinforcementBarPitchOfWall - Description: Hsb-wand Rc=2,8m²K/W; Reference: Basic Wall:NLRS_21_WA_HSB-wand_110mm
Type - Pset_WallCommon - IsExternal: no; Reference: Basic Wall:NLRS_21_WA_HSB-wand_110mm; FireRating: -
Classification: 21.23 buitenwanden; constructief, systeemwanden (Uniformat)
Pset_WallCommon - LoadBearing: no
Name (Basic Wall:NLRS_21_WA_HSB-wand_110mm:...) | ExtendToStructure
3332369 | no
5735304 | yes
5964015 | no
6425778 | no
6427060 | no
9102716 | no
12706549 | no
12706915 | no

# IfcWall: Basic Wall:NLRS_21_WA_HSB-wand_114mm (12)
Type - PredefinedType: STANDARD; Material: NLRS_f7_gipsplaat_gen 12.5 mm, NLRS_m1_isolatie 89 mm, NLRS_f7_gipsplaat_gen 12.5 mm
Type - Pset_ConcreteElementGeneral - FireRating: -
Type - Pset_ElementShading - Roughness: 304.8 mm
Type - Pset_ProductRequirements - Category: Walls
Type - Pset_QuantityTakeOff - Reference: Basic Wall:NLRS_21_WA_HSB-wand_114mm
Type - Pset_ReinforcementBarPitchOfWall - Description: Hsb-wand Rc=2,8m²K/W; Reference: Basic Wall:NLRS_21_WA_HSB-wand_114mm
Type - Pset_WallCommon - IsExternal: no; Reference: Basic Wall:NLRS_21_WA_HSB-wand_114mm; FireRating: -
Classification: 21.23 buitenwanden; constructief, systeemwanden (Uniformat)
Pset_WallCommon - ExtendToStructure: no; LoadBearing: no
Name (Basic Wall:NLRS_21_WA_HSB-wand_114mm:...) | In
5753160 | 00 begane grond
11012145 | 01 eerste verdieping
11012592 | 01 eerste verdieping
11012936 | 01 eerste verdieping
11013141 | 01 eerste verdieping
11013509 | 01 eerste verdieping
11013569 | 01 eerste verdieping
11013859 | 01 eerste verdieping
11014049 | 01 eerste verdieping
11014224 | 01 eerste verdieping
11014509 | 01 eerste verdieping
11014563 | 01 eerste verdieping | BaseQuantities - Height: 2470 mm; Length: 1933.81 mm; Width: 114 mm; GrossFootprintArea: 0.220845 m2; NetVolume: 544522459 m3; NetSideArea: 4776513 m2

# IfcWall: Basic Wall:NLRS_21_WA_HSB-wand_123mm (conform opgaaf constructeur), Basic Wall:NLRS_21_WA_HSB-wand_123mm (conform opgaaf constructeur):4863712
In: 00 begane grond
Type - PredefinedType: STANDARD; Material: NLRS_f7_gipsplaat_gen 12.5 mm, NLRS_i4_hout_underlayment 9 mm, NLRS_m1_isolatie 89 mm, NLRS_f7_gipsplaat_gen 12.5 mm
Type - Pset_ConcreteElementGeneral - FireRating: -
Type - Pset_ElementShading - Roughness: 304.8 mm
Type - Pset_ProductRequirements - Category: Walls
Type - Pset_QuantityTakeOff - Reference: Basic Wall:NLRS_21_WA_HSB-wand_123mm (conform opgaaf constructeur)
Type - Pset_ReinforcementBarPitchOfWall - Description: Hsb-wand Rc=2,8m²K/W; Reference: Basic Wall:NLRS_21_WA_HSB-wand_123mm (conform opgaaf constructeur)
Type - Pset_WallCommon - IsExternal: no; Reference: Basic Wall:NLRS_21_WA_HSB-wand_123mm (conform opgaaf constructeur); FireRating: -
Classification: 21.23 buitenwanden; constructief, systeemwanden (Uniformat)
Pset_WallCommon - ExtendToStructure: no; LoadBearing: no

# IfcWall: Basic Wall:NLRS_21_WA_HSB-wand_268mm (3)
In: 01 eerste verdieping
Type - PredefinedType: STANDARD; Material: NLRS_i4_hout_multiplex 10 mm, NLRS_m1_isolatie 235 mm, NLRS_i4_hout_multiplex 10 mm, NLRS_f7_gipsplaat_gen 12.5 mm
Type - Pset_ConcreteElementGeneral - FireRating: -
Type - Pset_ElementShading - Roughness: 304.8 mm
Type - Pset_ProductRequirements - Category: Walls
Type - Pset_QuantityTakeOff - Reference: Basic Wall:NLRS_21_WA_HSB-wand_268mm
Type - Pset_ReinforcementBarPitchOfWall - Description: Hsb-wand Rc=4,4m²K/W; Reference: Basic Wall:NLRS_21_WA_HSB-wand_268mm
Type - Pset_WallCommon - IsExternal: no; Reference: Basic Wall:NLRS_21_WA_HSB-wand_268mm; FireRating: -
Classification: 21.23 buitenwanden; constructief, systeemwanden (Uniformat)
Pset_WallCommon - ExtendToStructure: no; LoadBearing: no
Name (Basic Wall:NLRS_21_WA_HSB-wand_268mm:...)
3844538
4260410
5674969

# IfcWall: Basic Wall:NLRS_21_WA_HSB-wand_268mm (zonder gips) (3)
In: 01 eerste verdieping
Type - PredefinedType: STANDARD; Material: NLRS_i4_hout_multiplex 10 mm, NLRS_m1_isolatie 235 mm, NLRS_i4_hout_multiplex 10 mm
Type - Pset_ConcreteElementGeneral - FireRating: -
Type - Pset_ElementShading - Roughness: 304.8 mm
Type - Pset_ProductRequirements - Category: Walls
Type - Pset_QuantityTakeOff - Reference: Basic Wall:NLRS_21_WA_HSB-wand_268mm (zonder gips)
Type - Pset_ReinforcementBarPitchOfWall - Description: Hsb-wand Rc=4,4m²K/W; Reference: Basic Wall:NLRS_21_WA_HSB-wand_268mm (zonder gips)
Type - Pset_WallCommon - IsExternal: no; Reference: Basic Wall:NLRS_21_WA_HSB-wand_268mm (zonder gips); FireRating: -
Classification: 21.23 buitenwanden; constructief, systeemwanden (Uniformat)
Pset_WallCommon - ExtendToStructure: no; LoadBearing: no
Name (Basic Wall:NLRS_21_WA_HSB-wand_268mm (zonder gips):...)
3679055
5741317
9638880

# IfcWall: Basic Wall:NLRS_21_WA_HSB-wand_78mm, Basic Wall:NLRS_21_WA_HSB-wand_78mm:9094026
In: 02 tweede verdieping
Type - PredefinedType: STANDARD; Material: NLRS_i4_hout_multiplex 10 mm, NLRS_m1_isolatie 58 mm, NLRS_i4_hout_multiplex 10 mm
Type - Pset_ConcreteElementGeneral - FireRating: -
Type - Pset_ElementShading - Roughness: 304.8 mm
Type - Pset_ProductRequirements - Category: Walls
Type - Pset_QuantityTakeOff - Reference: Basic Wall:NLRS_21_WA_HSB-wand_78mm
Type - Pset_ReinforcementBarPitchOfWall - Description: Hsb-wand Rc=2,8m²K/W; Reference: Basic Wall:NLRS_21_WA_HSB-wand_78mm
Type - Pset_WallCommon - IsExternal: no; Reference: Basic Wall:NLRS_21_WA_HSB-wand_78mm; FireRating: -
Classification: 21.23 buitenwanden; constructief, systeemwanden (Uniformat)
Pset_WallCommon - ExtendToStructure: no; LoadBearing: no

# IfcWall: Basic Wall:NLRS_21_WA_HSB-wand_98mm (3)
In: 00 begane grond
Type - PredefinedType: STANDARD; Material: NLRS_m1_isolatie 89 mm, NLRS_i4_hout_multiplex 9 mm
Type - Pset_ConcreteElementGeneral - FireRating: -
Type - Pset_ElementShading - Roughness: 304.8 mm
Type - Pset_ProductRequirements - Category: Walls
Type - Pset_QuantityTakeOff - Reference: Basic Wall:NLRS_21_WA_HSB-wand_98mm
Type - Pset_ReinforcementBarPitchOfWall - Description: Hsb-wand Rc=2,8m²K/W; Reference: Basic Wall:NLRS_21_WA_HSB-wand_98mm
Type - Pset_WallCommon - IsExternal: no; Reference: Basic Wall:NLRS_21_WA_HSB-wand_98mm; FireRating: -
Classification: 21.23 buitenwanden; constructief, systeemwanden (Uniformat)
Pset_WallCommon - ExtendToStructure: no; LoadBearing: no
Name (Basic Wall:NLRS_21_WA_HSB-wand_98mm:...)
7317781
7740516
7758256

# IfcWall: Basic Wall:NLRS_21_WA_Metalstud 100mm (19)
Type - PredefinedType: STANDARD; Material: NLRS_f7_gipsplaat_gen 12.5 mm, NLRS_m1_isolatie 75 mm, NLRS_f7_gipsplaat_gen 12.5 mm
Type - Pset_ConcreteElementGeneral - FireRating: -
Type - Pset_ElementShading - Roughness: 304.8 mm
Type - Pset_ProductRequirements - Category: Walls
Type - Pset_QuantityTakeOff - Reference: Basic Wall:NLRS_21_WA_Metalstud 100mm
Type - Pset_ReinforcementBarPitchOfWall - Description: Hsb-wand Rc=2,8m²K/W; Reference: Basic Wall:NLRS_21_WA_Metalstud 100mm
Type - Pset_WallCommon - IsExternal: no; Reference: Basic Wall:NLRS_21_WA_Metalstud 100mm; FireRating: -
Classification: 21.23 buitenwanden; constructief, systeemwanden (Uniformat)
Pset_WallCommon - ExtendToStructure: no; LoadBearing: no
Name (Basic Wall:NLRS_21_WA_Metalstud 100mm:...) | In
2996791 | 00 begane grond
2997226 | 00 begane grond
3062087 | 01 eerste verdieping
3082839 | 01 eerste verdieping
5743020 | 01 eerste verdieping
5743166 | 01 eerste verdieping
5848721 | 01 eerste verdieping
5849107 | 01 eerste verdieping
5849155 | 01 eerste verdieping
5849212 | 01 eerste verdieping
5849273 | 01 eerste verdieping
5850369 | 01 eerste verdieping
5850404 | 01 eerste verdieping
5850431 | 01 eerste verdieping
6640793 | 01 eerste verdieping
6640837 | 01 eerste verdieping
8052605 | 01 eerste verdieping
8156040 | 00 begane grond
9572249 | 00 begane grond

# IfcWall: Basic Wall:NLRS_21_WA_Metalstud 100mm (achter sierbekleding), Basic Wall:NLRS_21_WA_Metalstud 100mm (achter sierbekleding):4547695
In: 01 eerste verdieping
Type - PredefinedType: STANDARD; Material: NLRS_i4_hout_multiplex zwart 15 mm, NLRS_m1_isolatie 75 mm, NLRS_f7_gipsplaat_gen 12.5 mm
Type - Pset_ConcreteElementGeneral - FireRating: -
Type - Pset_ElementShading - Roughness: 304.8 mm
Type - Pset_ProductRequirements - Category: Walls
Type - Pset_QuantityTakeOff - Reference: Basic Wall:NLRS_21_WA_Metalstud 100mm (achter sierbekleding)
Type - Pset_ReinforcementBarPitchOfWall - Description: Hsb-wand Rc=2,8m²K/W; Reference: Basic Wall:NLRS_21_WA_Metalstud 100mm (achter sierbekleding)
Type - Pset_WallCommon - IsExternal: no; Reference: Basic Wall:NLRS_21_WA_Metalstud 100mm (achter sierbekleding); FireRating: -
Classification: 21.23 buitenwanden; constructief, systeemwanden (Uniformat)
Pset_WallCommon - ExtendToStructure: no; LoadBearing: no

# IfcWall: Basic Wall:NLRS_21_WA_Metalstud 165 (2)
In: 00 begane grond
Type - PredefinedType: STANDARD; Material: NLRS_f7_gipsplaat_gen 12.5 mm, NLRS_m1_isolatie 50 mm, NLRS_j9_lucht_gen 40 mm, NLRS_m1_isolatie 50 mm, NLRS_f7_gipsplaat_gen 12.5 mm
Type - Pset_ConcreteElementGeneral - FireRating: -
Type - Pset_ElementShading - Roughness: 304.8 mm
Type - Pset_ProductRequirements - Category: Walls
Type - Pset_QuantityTakeOff - Reference: Basic Wall:NLRS_21_WA_Metalstud 165
Type - Pset_ReinforcementBarPitchOfWall - Description: Hsb-wand Rc=2,8m²K/W; Reference: Basic Wall:NLRS_21_WA_Metalstud 165
Type - Pset_WallCommon - IsExternal: no; Reference: Basic Wall:NLRS_21_WA_Metalstud 165; FireRating: -
Classification: 21.23 buitenwanden; constructief, systeemwanden (Uniformat)
Pset_WallCommon - ExtendToStructure: no; LoadBearing: no
Name (Basic Wall:NLRS_21_WA_Metalstud 165:...)
5672654
8159181

# IfcWall: Basic Wall:NLRS_21_WA_Metalstud 215, Basic Wall:NLRS_21_WA_Metalstud 215:7785020
In: 00 begane grond
Type - PredefinedType: STANDARD; Material: NLRS_f7_gipsplaat_gen 12.5 mm, NLRS_m1_isolatie 75 mm, NLRS_j9_lucht_gen 40 mm, NLRS_m1_isolatie 75 mm, NLRS_f7_gipsplaat_gen 12.5 mm
Type - Pset_ConcreteElementGeneral - FireRating: -
Type - Pset_ElementShading - Roughness: 304.8 mm
Type - Pset_ProductRequirements - Category: Walls
Type - Pset_QuantityTakeOff - Reference: Basic Wall:NLRS_21_WA_Metalstud 215
Type - Pset_ReinforcementBarPitchOfWall - Description: Hsb-wand Rc=2,8m²K/W; Reference: Basic Wall:NLRS_21_WA_Metalstud 215
Type - Pset_WallCommon - IsExternal: no; Reference: Basic Wall:NLRS_21_WA_Metalstud 215; FireRating: -
Classification: 21.23 buitenwanden; constructief, systeemwanden (Uniformat)
Pset_WallCommon - ExtendToStructure: no; LoadBearing: no

# IfcWall: Basic Wall:NLRS_21_WA_Metalstud 63mm (eenzijdig) (4)
In: 00 begane grond
Type - PredefinedType: STANDARD; Material: NLRS_m1_isolatie 50 mm, NLRS_f7_gipsplaat_gen 12.5 mm
Type - Pset_ConcreteElementGeneral - FireRating: -
Type - Pset_ElementShading - Roughness: 304.8 mm
Type - Pset_ProductRequirements - Category: Walls
Type - Pset_QuantityTakeOff - Reference: Basic Wall:NLRS_21_WA_Metalstud 63mm (eenzijdig)
Type - Pset_ReinforcementBarPitchOfWall - Description: Hsb-wand Rc=2,8m²K/W; Reference: Basic Wall:NLRS_21_WA_Metalstud 63mm (eenzijdig)
Type - Pset_WallCommon - IsExternal: no; Reference: Basic Wall:NLRS_21_WA_Metalstud 63mm (eenzijdig); FireRating: -
Classification: 21.23 buitenwanden; constructief, systeemwanden (Uniformat)
Pset_WallCommon - ExtendToStructure: no; LoadBearing: no
Name (Basic Wall:NLRS_21_WA_Metalstud 63mm (eenzijdig):...)
7814557
7814846
7815274
7815368

# IfcWall: Basic Wall:NLRS_21_WA_isolatie glaswol_160mm_gen_aly (2)
In: 00 begane grond
Type - PredefinedType: STANDARD; Material: NLRS_m1_isolatie 160 mm
Type - Pset_ConcreteElementGeneral - FireRating: -
Type - Pset_ElementShading - Roughness: 304.8 mm
Type - Pset_ProductRequirements - Category: Walls
Type - Pset_QuantityTakeOff - Reference: Basic Wall:NLRS_21_WA_isolatie glaswol_160mm_gen_aly
Type - Pset_ReinforcementBarPitchOfWall - Description: Glaswol isolatie 140mm; Reference: Basic Wall:NLRS_21_WA_isolatie glaswol_160mm_gen_aly
Type - Pset_WallCommon - IsExternal: no; Reference: Basic Wall:NLRS_21_WA_isolatie glaswol_160mm_gen_aly; FireRating: -
Classification: 21.10 buitenwanden; niet constructief, algemeen (verzamelniveau) (Uniformat)
Pset_WallCommon - IsExternal: yes; ExtendToStructure: no; LoadBearing: no
Name (Basic Wall:NLRS_21_WA_isolatie glaswol_160mm_gen_aly:...)
3651934 | Material: NLRS_m1_isolatie
11301853

# IfcWall: Basic Wall:NLRS_21_WA_isolatie glaswol_200mm_gen_aly, Basic Wall:NLRS_21_WA_isolatie glaswol_200mm_gen_aly:4542854
In: 00 begane grond
Type - PredefinedType: STANDARD; Material: NLRS_m1_isolatie 200 mm
Type - Pset_ConcreteElementGeneral - FireRating: -
Type - Pset_ElementShading - Roughness: 304.8 mm
Type - Pset_ProductRequirements - Category: Walls
Type - Pset_QuantityTakeOff - Reference: Basic Wall:NLRS_21_WA_isolatie glaswol_200mm_gen_aly
Type - Pset_ReinforcementBarPitchOfWall - Description: Glaswol isolatie 140mm; Reference: Basic Wall:NLRS_21_WA_isolatie glaswol_200mm_gen_aly
Type - Pset_WallCommon - IsExternal: no; Reference: Basic Wall:NLRS_21_WA_isolatie glaswol_200mm_gen_aly; FireRating: -
Classification: 21.10 buitenwanden; niet constructief, algemeen (verzamelniveau) (Uniformat); Material: NLRS_m1_isolatie
Pset_WallCommon - IsExternal: yes; ExtendToStructure: no; LoadBearing: no

# IfcWall: Basic Wall:NLRS_21_WA_kalkzandsteen_100mm_gen_aly (6)
In: 00 begane grond
Type - PredefinedType: STANDARD; Material: NLRS_f1_kalkzandsteen_CS20 100 mm
Type - Pset_ConcreteElementGeneral - FireRating: -
Type - Pset_ElementShading - Roughness: 304.8 mm
Type - Pset_ManufacturerTypeInformation - Manufacturer: De RuwBouw Groep
Type - Pset_ProductRequirements - Category: Walls
Type - Pset_QuantityTakeOff - Reference: Basic Wall:NLRS_21_WA_kalkzandsteen_100mm_gen_aly
Type - Pset_ReinforcementBarPitchOfWall - Description: Kalkzandsteen 120mm CS20; Reference: Basic Wall:NLRS_21_WA_kalkzandsteen_100mm_gen_aly
Type - Pset_WallCommon - Reference: Basic Wall:NLRS_21_WA_kalkzandsteen_100mm_gen_aly; FireRating: -; IsExternal: no
Classification: 21.22 buitenwanden; constructief, spouwwanden (Uniformat)
Pset_WallCommon - IsExternal: yes; ExtendToStructure: no; LoadBearing: no
Name (Basic Wall:NLRS_21_WA_kalkzandsteen_100mm_gen_aly:...)
2831851 | Material: NLRS_f1_kalkzandsteen_CS20
2834775
3372582
3373544
3833762
3833764

# IfcWall: Basic Wall:NLRS_21_WA_kalkzandsteen_120mm_CS20_gen_aly, Basic Wall:NLRS_21_WA_kalkzandsteen_120mm_CS20_gen_aly:6508713
In: 00 begane grond
Type - PredefinedType: STANDARD; Material: NLRS_f1_kalkzandsteen_CS20 120 mm
Type - Pset_ConcreteElementGeneral - FireRating: -
Type - Pset_ElementShading - Roughness: 304.8 mm
Type - Pset_ManufacturerTypeInformation - Manufacturer: De RuwBouw Groep
Type - Pset_ProductRequirements - Category: Walls
Type - Pset_QuantityTakeOff - Reference: Basic Wall:NLRS_21_WA_kalkzandsteen_120mm_CS20_gen_aly
Type - Pset_ReinforcementBarPitchOfWall - Description: Kalkzandsteen 120mm CS20; Reference: Basic Wall:NLRS_21_WA_kalkzandsteen_120mm_CS20_gen_aly
Type - Pset_WallCommon - IsExternal: no; Reference: Basic Wall:NLRS_21_WA_kalkzandsteen_120mm_CS20_gen_aly; FireRating: -
Classification: 21.22 buitenwanden; constructief, spouwwanden (Uniformat)
Pset_WallCommon - IsExternal: yes; ExtendToStructure: no; LoadBearing: no

# IfcWall: Basic Wall:NLRS_22_WA_LB_isolatie Kooltherm K8 105mm_Kingspan_BO (9)
In: 00 begane grond
Type - PredefinedType: STANDARD; Material: NLRS_n7_Kooltherm Resol hardschuim 0.02 (0.1)_Kingspan 105 mm
Type - Pset_ElementShading - Roughness: 304.8 mm
Type - Pset_ManufacturerTypeInformation - Manufacturer: Kingspan
Type - Pset_ProductRequirements - Category: Walls
Type - Pset_QuantityTakeOff - Reference: Basic Wall:NLRS_22_WA_LB_isolatie Kooltherm K8 105mm_Kingspan_BO
Type - Pset_ReinforcementBarPitchOfWall - Description: Hoogwaardige isolatie voor spouwmuren.; Reference: Basic Wall:NLRS_22_WA_LB_isolatie Kooltherm K8 105mm_Kingspan_BO
Type - Pset_WallCommon - IsExternal: no; Reference: Basic Wall:NLRS_22_WA_LB_isolatie Kooltherm K8 105mm_Kingspan_BO; ThermalTransmittance: 0.190476 kg/K/s3
Classification: 21.12 buitenwanden; niet constructief, spouwwanden (Uniformat)
Pset_WallCommon - IsExternal: yes; ExtendToStructure: no; LoadBearing: no
Name (Basic Wall:NLRS_22_WA_LB_isolatie Kooltherm K8 105mm_Kingspan_BO:...)
5205538
5206019
5209880
5213799
5837917
7741590
7744321
7753623
7756402

# IfcWall: Basic Wall:NLRS_22_WA_LB_isolatie PIR 60mm (2)
In: 01 eerste verdieping
Type - PredefinedType: STANDARD; Material: NLRS_n7_isolatie PIR_gen 60 mm
Type - Pset_ElementShading - Roughness: 304.8 mm
Type - Pset_ManufacturerTypeInformation - Manufacturer: Kingspan
Type - Pset_ProductRequirements - Category: Walls
Type - Pset_QuantityTakeOff - Reference: Basic Wall:NLRS_22_WA_LB_isolatie PIR 60mm
Type - Pset_ReinforcementBarPitchOfWall - Description: Hoogwaardige isolatie voor spouwmuren.; Reference: Basic Wall:NLRS_22_WA_LB_isolatie PIR 60mm
Type - Pset_WallCommon - IsExternal: no; Reference: Basic Wall:NLRS_22_WA_LB_isolatie PIR 60mm
Classification: 21.12 buitenwanden; niet constructief, spouwwanden (Uniformat)
Pset_WallCommon - IsExternal: yes; ExtendToStructure: no; LoadBearing: no
Name (Basic Wall:NLRS_22_WA_LB_isolatie PIR 60mm:...)
6527665
6527674

# IfcWall: Basic Wall:NLRS_41_WA_Bekleding kolommen (3)
Type - PredefinedType: STANDARD; Material: NLRS_f7_gipsplaat_gen 12.5 mm, NLRS_i4_hout_multiplex 10 mm
Type - Pset_ConcreteElementGeneral - FireRating: -
Type - Pset_ElementShading - Roughness: 304.8 mm
Type - Pset_ManufacturerTypeInformation - Manufacturer: NTB
Type - Pset_ProductRequirements - Category: Walls
Type - Pset_QuantityTakeOff - Reference: Basic Wall:NLRS_41_WA_Bekleding kolommen
Type - Pset_ReinforcementBarPitchOfWall - Description: Plaatmateriaal 18mm; Reference: Basic Wall:NLRS_41_WA_Bekleding kolommen
Type - Pset_WallCommon - IsExternal: no; Reference: Basic Wall:NLRS_41_WA_Bekleding kolommen; FireRating: -
Classification: 41.12 buitenwandafwerkingen; bekledingen (Uniformat)
Pset_WallCommon - IsExternal: yes; ExtendToStructure: no; LoadBearing: no
Name (Basic Wall:NLRS_41_WA_Bekleding kolommen:...) | In
6281819 | 00 begane grond
7433958 | 01 eerste verdieping
7434373 | 01 eerste verdieping

# IfcWall: Basic Wall:NLRS_41_WA_plaatmateriaal 15mm RAL 9002 (2)
In: 01 eerste verdieping
Type - PredefinedType: STANDARD; Material: AL_Multiplex RAL 9002 15 mm
Type - Pset_ConcreteElementGeneral - FireRating: -
Type - Pset_ElementShading - Roughness: 304.8 mm
Type - Pset_ManufacturerTypeInformation - Manufacturer: NTB
Type - Pset_ProductRequirements - Category: Walls
Type - Pset_QuantityTakeOff - Reference: Basic Wall:NLRS_41_WA_plaatmateriaal 15mm RAL 9002
Type - Pset_ReinforcementBarPitchOfWall - Description: Plaatmateriaal 18mm; Reference: Basic Wall:NLRS_41_WA_plaatmateriaal 15mm RAL 9002
Type - Pset_WallCommon - IsExternal: no; Reference: Basic Wall:NLRS_41_WA_plaatmateriaal 15mm RAL 9002; FireRating: -
Classification: 41.12 buitenwandafwerkingen; bekledingen (Uniformat)
Pset_WallCommon - IsExternal: yes; ExtendToStructure: no; LoadBearing: no
Name (Basic Wall:NLRS_41_WA_plaatmateriaal 15mm RAL 9002:...)
7747612
7760778

# IfcWall: Basic Wall:NLRS_41_WA_plaatmateriaal 15mm zwart, Basic Wall:NLRS_41_WA_plaatmateriaal 15mm zwart:6233055
In: 00 begane grond
Type - PredefinedType: STANDARD; Material: NLRS_i4_hout_multiplex zwart 15 mm
Type - Pset_ConcreteElementGeneral - FireRating: -
Type - Pset_ElementShading - Roughness: 304.8 mm
Type - Pset_ManufacturerTypeInformation - Manufacturer: NTB
Type - Pset_ProductRequirements - Category: Walls
Type - Pset_QuantityTakeOff - Reference: Basic Wall:NLRS_41_WA_plaatmateriaal 15mm zwart
Type - Pset_ReinforcementBarPitchOfWall - Description: Plaatmateriaal 18mm; Reference: Basic Wall:NLRS_41_WA_plaatmateriaal 15mm zwart
Type - Pset_WallCommon - IsExternal: no; Reference: Basic Wall:NLRS_41_WA_plaatmateriaal 15mm zwart; FireRating: -
Classification: 41.12 buitenwandafwerkingen; bekledingen (Uniformat)
Pset_WallCommon - IsExternal: yes; ExtendToStructure: no; LoadBearing: no

# IfcWall: Basic Wall:NLRS_41_WA_plaatmateriaal 9mm RAL 9002 (14)
In: Podium
Type - PredefinedType: STANDARD; Material: ZZ_00_Kleur_RAL 9002 9 mm
Type - Pset_ConcreteElementGeneral - FireRating: -
Type - Pset_ElementShading - Roughness: 304.8 mm
Type - Pset_ManufacturerTypeInformation - Manufacturer: NTB
Type - Pset_ProductRequirements - Category: Walls
Type - Pset_QuantityTakeOff - Reference: Basic Wall:NLRS_41_WA_plaatmateriaal 9mm RAL 9002
Type - Pset_ReinforcementBarPitchOfWall - Description: Plaatmateriaal 18mm; Reference: Basic Wall:NLRS_41_WA_plaatmateriaal 9mm RAL 9002
Type - Pset_WallCommon - IsExternal: no; Reference: Basic Wall:NLRS_41_WA_plaatmateriaal 9mm RAL 9002; FireRating: -
Classification: 41.12 buitenwandafwerkingen; bekledingen (Uniformat)
Pset_WallCommon - IsExternal: yes; LoadBearing: no
Name (Basic Wall:NLRS_41_WA_plaatmateriaal 9mm RAL 9002:...) | ExtendToStructure
7833155 | yes | Material: ZZ_00_Kleur_RAL 9002
7833674 | no
7834175 | no
7834689 | no
7835408 | no
7835444 | no
7836374 | no
7836411 | no
7837129 | no
7837157 | no
7837854 | no
7837880 | no
7838618 | no
7838646 | no

# IfcWall: Basic Wall:NLRS_42_WA_Akoestische panelen (11)
In: 01 eerste verdieping
Type - PredefinedType: STANDARD; Material: NLRS_Akoestisch paneel RAL 9010 18 mm
Type - Pset_ConcreteElementGeneral - FireRating: -
Type - Pset_ElementShading - Roughness: 304.8 mm
Type - Pset_ManufacturerTypeInformation - Manufacturer: NTB
Type - Pset_ProductRequirements - Category: Walls
Type - Pset_QuantityTakeOff - Reference: Basic Wall:NLRS_42_WA_Akoestische panelen
Type - Pset_ReinforcementBarPitchOfWall - Description: Plaatmateriaal 18mm; Reference: Basic Wall:NLRS_42_WA_Akoestische panelen
Type - Pset_WallCommon - IsExternal: no; Reference: Basic Wall:NLRS_42_WA_Akoestische panelen; FireRating: -
Classification: 42.12 binnenwandafwerkingen; bekledingen (Uniformat)
Pset_WallCommon - ExtendToStructure: no; LoadBearing: no
Name (Basic Wall:NLRS_42_WA_Akoestische panelen:...)
9293896 | Material: NLRS_Akoestisch paneel RAL 9010
9294348
11020405
11020850
11021485
11022213
11023111
11023588
11024220
11024516
11024831 | BaseQuantities - Height: 2520 mm; Length: 1937.54 mm; Width: 18 mm; GrossFootprintArea: 0.0350094 m2; NetVolume: 87886713 m3; NetSideArea: 4882595 m2

# IfcWall: Basic Wall:NLRS_42_WA_Houten gevelbekleding staand 20mm, Basic Wall:NLRS_42_WA_Houten gevelbekleding staand 20mm:3657037
In: 00 begane grond
Type - PredefinedType: STANDARD; Material: AL Houten gevelbekleding staand 20 mm
Type - Pset_ConcreteElementGeneral - FireRating: -
Type - Pset_ElementShading - Roughness: 304.8 mm
Type - Pset_ManufacturerTypeInformation - Manufacturer: NTB
Type - Pset_ProductRequirements - Category: Walls
Type - Pset_QuantityTakeOff - Reference: Basic Wall:NLRS_42_WA_Houten gevelbekleding staand 20mm
Type - Pset_ReinforcementBarPitchOfWall - Description: Plaatmateriaal 18mm; Reference: Basic Wall:NLRS_42_WA_Houten gevelbekleding staand 20mm
Type - Pset_WallCommon - IsExternal: no; Reference: Basic Wall:NLRS_42_WA_Houten gevelbekleding staand 20mm; FireRating: -
Classification: 42.12 binnenwandafwerkingen; bekledingen (Uniformat)
Pset_WallCommon - ExtendToStructure: no; LoadBearing: no

# IfcWall: Basic Wall:NLRS_42_WA_beplating_zijkant hellend dak, Basic Wall:NLRS_42_WA_beplating_zijkant hellend dak:4945776
In: 01 eerste verdieping
Type - PredefinedType: STANDARD; Material: h7_zink zwart 3 mm
Type - Pset_ConcreteElementGeneral - FireRating: -
Type - Pset_ElementShading - Roughness: 304.8 mm
Type - Pset_ManufacturerTypeInformation - Manufacturer: NTB
Type - Pset_ProductRequirements - Category: Walls
Type - Pset_QuantityTakeOff - Reference: Basic Wall:NLRS_42_WA_beplating_zijkant hellend dak
Type - Pset_ReinforcementBarPitchOfWall - Description: Plaatmateriaal 18mm; Reference: Basic Wall:NLRS_42_WA_beplating_zijkant hellend dak
Type - Pset_WallCommon - IsExternal: no; Reference: Basic Wall:NLRS_42_WA_beplating_zijkant hellend dak; FireRating: -; ThermalTransmittance: 37666.7 kg/K/s3
Classification: 41.12 buitenwandafwerkingen; bekledingen (Uniformat)
Pset_WallCommon - ExtendToStructure: no; LoadBearing: no

# IfcWall: Bevestiging zinken kader dak10:Bevestiging zinken kader dak, Bevestiging zinken kader dak10:Bevestiging zinken kader dak:11078164
In: ok. fundering
Type - Material: AL_31_Naaldhout (vuren)
Type - Pset_ProductRequirements - Category: Walls
Type - Pset_QuantityTakeOff - Reference: Bevestiging zinken kader dak10:Bevestiging zinken kader dak
Type - Pset_ReinforcementBarPitchOfWall - Reference: Bevestiging zinken kader dak10:Bevestiging zinken kader dak
Type - Pset_WallCommon - IsExternal: no; Reference: Bevestiging zinken kader dak10:Bevestiging zinken kader dak
Pset_QuantityTakeOff - sets with these values: 2

# IfcWall: Bevestiging zinken kader dak11:Bevestiging zinken kader dak, Bevestiging zinken kader dak11:Bevestiging zinken kader dak:11078240
In: ok. fundering
Type - Material: AL_31_Naaldhout (vuren)
Type - Pset_ProductRequirements - Category: Walls
Type - Pset_QuantityTakeOff - Reference: Bevestiging zinken kader dak11:Bevestiging zinken kader dak
Type - Pset_ReinforcementBarPitchOfWall - Reference: Bevestiging zinken kader dak11:Bevestiging zinken kader dak
Type - Pset_WallCommon - IsExternal: no; Reference: Bevestiging zinken kader dak11:Bevestiging zinken kader dak
Pset_QuantityTakeOff - sets with these values: 2

# IfcWall: Bevestiging zinken kader dak12:Bevestiging zinken kader dak, Bevestiging zinken kader dak12:Bevestiging zinken kader dak:11078310
In: ok. fundering
Type - Material: AL_31_Naaldhout (vuren)
Type - Pset_ProductRequirements - Category: Walls
Type - Pset_QuantityTakeOff - Reference: Bevestiging zinken kader dak12:Bevestiging zinken kader dak
Type - Pset_ReinforcementBarPitchOfWall - Reference: Bevestiging zinken kader dak12:Bevestiging zinken kader dak
Type - Pset_WallCommon - IsExternal: no; Reference: Bevestiging zinken kader dak12:Bevestiging zinken kader dak
Pset_QuantityTakeOff - sets with these values: 2

# IfcWall: Bevestiging zinken kader dak14:Bevestiging zinken kader dak, Bevestiging zinken kader dak14:Bevestiging zinken kader dak:9446273
In: 01 eerste verdieping
Type - Material: AL_31_Naaldhout (vuren)
Type - Pset_ProductRequirements - Category: Walls
Type - Pset_QuantityTakeOff - Reference: Bevestiging zinken kader dak14:Bevestiging zinken kader dak
Type - Pset_ReinforcementBarPitchOfWall - Reference: Bevestiging zinken kader dak14:Bevestiging zinken kader dak
Type - Pset_WallCommon - IsExternal: no; Reference: Bevestiging zinken kader dak14:Bevestiging zinken kader dak
Pset_QuantityTakeOff - sets with these values: 2

# IfcWall: Bevestiging zinken kader dak1:Bevestiging zinken kader dak, Bevestiging zinken kader dak1:Bevestiging zinken kader dak:4212834
In: Podium
Type - Material: AL_31_Naaldhout (vuren)
Type - Pset_ProductRequirements - Category: Walls
Type - Pset_QuantityTakeOff - Reference: Bevestiging zinken kader dak1:Bevestiging zinken kader dak
Type - Pset_ReinforcementBarPitchOfWall - Reference: Bevestiging zinken kader dak1:Bevestiging zinken kader dak
Type - Pset_WallCommon - IsExternal: no; Reference: Bevestiging zinken kader dak1:Bevestiging zinken kader dak
Pset_QuantityTakeOff - sets with these values: 2

# IfcWall: Bevestiging zinken kader dak2:Bevestiging zinken kader dak, Bevestiging zinken kader dak2:Bevestiging zinken kader dak:11077821
In: ok. fundering
Type - Material: AL_31_Naaldhout (vuren)
Type - Pset_ProductRequirements - Category: Walls
Type - Pset_QuantityTakeOff - Reference: Bevestiging zinken kader dak2:Bevestiging zinken kader dak
Type - Pset_ReinforcementBarPitchOfWall - Reference: Bevestiging zinken kader dak2:Bevestiging zinken kader dak
Type - Pset_WallCommon - IsExternal: no; Reference: Bevestiging zinken kader dak2:Bevestiging zinken kader dak
Pset_QuantityTakeOff - sets with these values: 2

# IfcWall: Bevestiging zinken kader dak3:Bevestiging zinken kader dak, Bevestiging zinken kader dak3:Bevestiging zinken kader dak:4847530
In: Podium
Type - Material: AL_31_Naaldhout (vuren)
Type - Pset_ProductRequirements - Category: Walls
Type - Pset_QuantityTakeOff - Reference: Bevestiging zinken kader dak3:Bevestiging zinken kader dak
Type - Pset_ReinforcementBarPitchOfWall - Reference: Bevestiging zinken kader dak3:Bevestiging zinken kader dak
Type - Pset_WallCommon - IsExternal: no; Reference: Bevestiging zinken kader dak3:Bevestiging zinken kader dak
Pset_QuantityTakeOff - sets with these values: 2

# IfcWall: Bevestiging zinken kader dak4:Bevestiging zinken kader dak, Bevestiging zinken kader dak4:Bevestiging zinken kader dak:5844427
In: Podium
Type - Material: AL_31_Naaldhout (vuren)
Type - Pset_ProductRequirements - Category: Walls
Type - Pset_QuantityTakeOff - Reference: Bevestiging zinken kader dak4:Bevestiging zinken kader dak
Type - Pset_ReinforcementBarPitchOfWall - Reference: Bevestiging zinken kader dak4:Bevestiging zinken kader dak
Type - Pset_WallCommon - IsExternal: no; Reference: Bevestiging zinken kader dak4:Bevestiging zinken kader dak
Pset_QuantityTakeOff - sets with these values: 2

# IfcWall: Bevestiging zinken kader dak5:Bevestiging zinken kader dak, Bevestiging zinken kader dak5:Bevestiging zinken kader dak:5844469
In: Podium
Type - Material: AL_31_Naaldhout (vuren)
Type - Pset_ProductRequirements - Category: Walls
Type - Pset_QuantityTakeOff - Reference: Bevestiging zinken kader dak5:Bevestiging zinken kader dak
Type - Pset_ReinforcementBarPitchOfWall - Reference: Bevestiging zinken kader dak5:Bevestiging zinken kader dak
Type - Pset_WallCommon - IsExternal: no; Reference: Bevestiging zinken kader dak5:Bevestiging zinken kader dak
Pset_QuantityTakeOff - sets with these values: 2

# IfcWall: Bevestiging zinken kader dak6:Bevestiging zinken kader dak, Bevestiging zinken kader dak6:Bevestiging zinken kader dak:11077948
In: ok. fundering
Type - Material: AL_31_Naaldhout (vuren)
Type - Pset_ProductRequirements - Category: Walls
Type - Pset_QuantityTakeOff - Reference: Bevestiging zinken kader dak6:Bevestiging zinken kader dak
Type - Pset_ReinforcementBarPitchOfWall - Reference: Bevestiging zinken kader dak6:Bevestiging zinken kader dak
Type - Pset_WallCommon - IsExternal: no; Reference: Bevestiging zinken kader dak6:Bevestiging zinken kader dak
Pset_QuantityTakeOff - sets with these values: 2

# IfcWall: Bevestiging zinken kader dak7:Bevestiging zinken kader dak, Bevestiging zinken kader dak7:Bevestiging zinken kader dak:11078018
In: ok. fundering
Type - Material: AL_31_Naaldhout (vuren)
Type - Pset_ProductRequirements - Category: Walls
Type - Pset_QuantityTakeOff - Reference: Bevestiging zinken kader dak7:Bevestiging zinken kader dak
Type - Pset_ReinforcementBarPitchOfWall - Reference: Bevestiging zinken kader dak7:Bevestiging zinken kader dak
Type - Pset_WallCommon - IsExternal: no; Reference: Bevestiging zinken kader dak7:Bevestiging zinken kader dak
Pset_QuantityTakeOff - sets with these values: 2

# IfcWall: Bevestiging zinken kader dak8:Bevestiging zinken kader dak, Bevestiging zinken kader dak8:Bevestiging zinken kader dak:6643526
In: ok. fundering
Type - Material: AL_31_Naaldhout (vuren)
Type - Pset_ProductRequirements - Category: Walls
Type - Pset_QuantityTakeOff - Reference: Bevestiging zinken kader dak8:Bevestiging zinken kader dak
Type - Pset_ReinforcementBarPitchOfWall - Reference: Bevestiging zinken kader dak8:Bevestiging zinken kader dak
Type - Pset_WallCommon - IsExternal: no; Reference: Bevestiging zinken kader dak8:Bevestiging zinken kader dak
Pset_QuantityTakeOff - sets with these values: 2

# IfcWall: Bevestiging zinken kader dak9:Bevestiging zinken kader dak, Bevestiging zinken kader dak9:Bevestiging zinken kader dak:11078094
In: ok. fundering
Type - Material: AL_31_Naaldhout (vuren)
Type - Pset_ProductRequirements - Category: Walls
Type - Pset_QuantityTakeOff - Reference: Bevestiging zinken kader dak9:Bevestiging zinken kader dak
Type - Pset_ReinforcementBarPitchOfWall - Reference: Bevestiging zinken kader dak9:Bevestiging zinken kader dak
Type - Pset_WallCommon - IsExternal: no; Reference: Bevestiging zinken kader dak9:Bevestiging zinken kader dak
Pset_QuantityTakeOff - sets with these values: 2

# IfcWall: Bevestiging zinken kader dak:Bevestiging zinken kader dak, Bevestiging zinken kader dak:Bevestiging zinken kader dak:3196797
In: Podium
Type - Material: AL_31_Naaldhout (vuren)
Type - Pset_ProductRequirements - Category: Walls
Type - Pset_QuantityTakeOff - Reference: Bevestiging zinken kader dak:Bevestiging zinken kader dak
Type - Pset_ReinforcementBarPitchOfWall - Reference: Bevestiging zinken kader dak:Bevestiging zinken kader dak
Type - Pset_WallCommon - IsExternal: no; Reference: Bevestiging zinken kader dak:Bevestiging zinken kader dak
Pset_QuantityTakeOff - sets with these values: 2

# IfcWall: Daktrim1:Daktrim, Daktrim1:Daktrim:4114940
In: 01 eerste verdieping
Type - Material: AL_Aluminium zwart 2
Type - Pset_ProductRequirements - Category: Walls
Type - Pset_QuantityTakeOff - Reference: Daktrim1:Daktrim
Type - Pset_ReinforcementBarPitchOfWall - Reference: Daktrim1:Daktrim
Type - Pset_WallCommon - IsExternal: no; Reference: Daktrim1:Daktrim
Pset_QuantityTakeOff - sets with these values: 2

# IfcWall: Daktrim2:Daktrim, Daktrim2:Daktrim:4135422
In: 01 eerste verdieping
Type - Material: ZZ_Default Wall
Type - Pset_ProductRequirements - Category: Walls
Type - Pset_QuantityTakeOff - Reference: Daktrim2:Daktrim
Type - Pset_ReinforcementBarPitchOfWall - Reference: Daktrim2:Daktrim
Type - Pset_WallCommon - IsExternal: no; Reference: Daktrim2:Daktrim
Pset_QuantityTakeOff - sets with these values: 2

# IfcWall: Daktrim3:Daktrim, Daktrim3:Daktrim:8374269
In: 01 eerste verdieping
Type - Material: ZZ_Default Wall
Type - Pset_ProductRequirements - Category: Walls
Type - Pset_QuantityTakeOff - Reference: Daktrim3:Daktrim
Type - Pset_ReinforcementBarPitchOfWall - Reference: Daktrim3:Daktrim
Type - Pset_WallCommon - IsExternal: no; Reference: Daktrim3:Daktrim
Pset_QuantityTakeOff - sets with these values: 2

# IfcWall: Daktrim4:Daktrim, Daktrim4:Daktrim:8374519
In: 01 eerste verdieping
Type - Material: ZZ_Default Wall
Type - Pset_ProductRequirements - Category: Walls
Type - Pset_QuantityTakeOff - Reference: Daktrim4:Daktrim
Type - Pset_ReinforcementBarPitchOfWall - Reference: Daktrim4:Daktrim
Type - Pset_WallCommon - IsExternal: no; Reference: Daktrim4:Daktrim
Pset_QuantityTakeOff - sets with these values: 2

# IfcWall: Daktrim5:Daktrim, Daktrim5:Daktrim:9436849
In: 01 eerste verdieping
Type - Material: AL_Aluminium zwart 2
Type - Pset_ProductRequirements - Category: Walls
Type - Pset_QuantityTakeOff - Reference: Daktrim5:Daktrim
Type - Pset_ReinforcementBarPitchOfWall - Reference: Daktrim5:Daktrim
Type - Pset_WallCommon - IsExternal: no; Reference: Daktrim5:Daktrim
Pset_QuantityTakeOff - sets with these values: 2

# IfcWall: Daktrim7:Daktrim, Daktrim7:Daktrim:4239147
In: 01 eerste verdieping
Type - Material: h7_zink zwart
Type - Pset_ProductRequirements - Category: Walls
Type - Pset_QuantityTakeOff - Reference: Daktrim7:Daktrim
Type - Pset_ReinforcementBarPitchOfWall - Reference: Daktrim7:Daktrim
Type - Pset_WallCommon - IsExternal: no; Reference: Daktrim7:Daktrim
Pset_QuantityTakeOff - sets with these values: 2

# IfcWall: Daktrim:Daktrim, Daktrim:Daktrim:4111649
In: 01 eerste verdieping
Type - Material: AL_Aluminium zwart 2
Type - Pset_ProductRequirements - Category: Walls
Type - Pset_QuantityTakeOff - Reference: Daktrim:Daktrim
Type - Pset_ReinforcementBarPitchOfWall - Reference: Daktrim:Daktrim
Type - Pset_WallCommon - IsExternal: no; Reference: Daktrim:Daktrim
Pset_QuantityTakeOff - sets with these values: 2

# IfcWall: Sierbekleding MF zaal:Sierbekleding MF zaal, Sierbekleding MF zaal:Sierbekleding MF zaal:6711523
In: 00 begane grond
Type - Material: AL_31_Naaldhout (vuren)
Type - Pset_ProductRequirements - Category: Walls
Type - Pset_QuantityTakeOff - Reference: Sierbekleding MF zaal:Sierbekleding MF zaal
Type - Pset_ReinforcementBarPitchOfWall - Reference: Sierbekleding MF zaal:Sierbekleding MF zaal
Type - Pset_WallCommon - IsExternal: no; Reference: Sierbekleding MF zaal:Sierbekleding MF zaal
Pset_QuantityTakeOff - sets with these values: 2

# IfcWall: Sierbekleding soosruimte:Sierbekleding soosruimte, Sierbekleding soosruimte:Sierbekleding soosruimte:6836587
In: 00 begane grond
Type - Material: AL_31_Naaldhout (vuren)
Type - Pset_ProductRequirements - Category: Walls
Type - Pset_QuantityTakeOff - Reference: Sierbekleding soosruimte:Sierbekleding soosruimte
Type - Pset_ReinforcementBarPitchOfWall - Reference: Sierbekleding soosruimte:Sierbekleding soosruimte
Type - Pset_WallCommon - IsExternal: no; Reference: Sierbekleding soosruimte:Sierbekleding soosruimte
Pset_QuantityTakeOff - sets with these values: 2

# IfcWall: Sierbelkeding sportkantine:Sierbelkeding sportkantine, Sierbelkeding sportkantine:Sierbelkeding sportkantine:6809235
In: Podium
Type - Material: AL_31_Naaldhout (vuren)
Type - Pset_ProductRequirements - Category: Walls
Type - Pset_QuantityTakeOff - Reference: Sierbelkeding sportkantine:Sierbelkeding sportkantine
Type - Pset_ReinforcementBarPitchOfWall - Reference: Sierbelkeding sportkantine:Sierbelkeding sportkantine
Type - Pset_WallCommon - IsExternal: no; Reference: Sierbelkeding sportkantine:Sierbelkeding sportkantine
Pset_QuantityTakeOff - sets with these values: 2

# IfcWall: Uiteinde muur glazen pui1:Uiteinde muur glazen pui, Uiteinde muur glazen pui1:Uiteinde muur glazen pui:6030378
In: 00 begane grond
Type - Material: NLRS_n6_kunststof_DTS-basis black
Type - Pset_ProductRequirements - Category: Walls
Type - Pset_QuantityTakeOff - Reference: Uiteinde muur glazen pui1:Uiteinde muur glazen pui
Type - Pset_ReinforcementBarPitchOfWall - Reference: Uiteinde muur glazen pui1:Uiteinde muur glazen pui
Type - Pset_WallCommon - IsExternal: no; Reference: Uiteinde muur glazen pui1:Uiteinde muur glazen pui
Pset_QuantityTakeOff - sets with these values: 2

# IfcWall: Uiteinde muur glazen pui2:Uiteinde muur glazen pui, Uiteinde muur glazen pui2:Uiteinde muur glazen pui:3153762
In: 00 begane grond
Type - Material: NLRS_n6_kunststof_DTS-basis black
Type - Pset_ProductRequirements - Category: Walls
Type - Pset_QuantityTakeOff - Reference: Uiteinde muur glazen pui2:Uiteinde muur glazen pui
Type - Pset_ReinforcementBarPitchOfWall - Reference: Uiteinde muur glazen pui2:Uiteinde muur glazen pui
Type - Pset_WallCommon - IsExternal: no; Reference: Uiteinde muur glazen pui2:Uiteinde muur glazen pui
Pset_QuantityTakeOff - sets with these values: 2

# IfcWall: Uiteinde muur glazen pui3:Uiteinde muur glazen pui, Uiteinde muur glazen pui3:Uiteinde muur glazen pui:3154081
In: 00 begane grond
Type - Material: NLRS_n6_kunststof_DTS-basis black
Type - Pset_ProductRequirements - Category: Walls
Type - Pset_QuantityTakeOff - Reference: Uiteinde muur glazen pui3:Uiteinde muur glazen pui
Type - Pset_ReinforcementBarPitchOfWall - Reference: Uiteinde muur glazen pui3:Uiteinde muur glazen pui
Type - Pset_WallCommon - IsExternal: no; Reference: Uiteinde muur glazen pui3:Uiteinde muur glazen pui
Pset_QuantityTakeOff - sets with these values: 2

# IfcWall: Uiteinde muur glazen pui:Uiteinde muur glazen pui, Uiteinde muur glazen pui:Uiteinde muur glazen pui:6030690
In: 00 begane grond
Type - Material: NLRS_n6_kunststof_DTS-basis black
Type - Pset_ProductRequirements - Category: Walls
Type - Pset_QuantityTakeOff - Reference: Uiteinde muur glazen pui:Uiteinde muur glazen pui
Type - Pset_ReinforcementBarPitchOfWall - Reference: Uiteinde muur glazen pui:Uiteinde muur glazen pui
Type - Pset_WallCommon - IsExternal: no; Reference: Uiteinde muur glazen pui:Uiteinde muur glazen pui
Pset_QuantityTakeOff - sets with these values: 2

# IfcWall: Verzonken liggers in schuin dak:Verzonken liggers in schuin dak, Verzonken liggers in schuin dak:Verzonken liggers in schuin dak:6338409
In: Podium
Type - Material: NLRS_j7_hout_spaanplaat
Type - Pset_ProductRequirements - Category: Walls
Type - Pset_QuantityTakeOff - Reference: Verzonken liggers in schuin dak:Verzonken liggers in schuin dak
Type - Pset_ReinforcementBarPitchOfWall - Reference: Verzonken liggers in schuin dak:Verzonken liggers in schuin dak
Type - Pset_WallCommon - IsExternal: no; Reference: Verzonken liggers in schuin dak:Verzonken liggers in schuin dak
Pset_QuantityTakeOff - sets with these values: 2

# IfcWall: Zetwerk tussen hout en metselwerk:Zetwerk tussen hout en metselwerk, Zetwerk tussen hout en metselwerk:Zetwerk tussen hout en metselwerk:6092735
In: 00 begane grond
Type - Material: ZZ_Default Wall
Type - Pset_ProductRequirements - Category: Walls
Type - Pset_QuantityTakeOff - Reference: Zetwerk tussen hout en metselwerk:Zetwerk tussen hout en metselwerk
Type - Pset_ReinforcementBarPitchOfWall - Reference: Zetwerk tussen hout en metselwerk:Zetwerk tussen hout en metselwerk
Type - Pset_WallCommon - IsExternal: no; Reference: Zetwerk tussen hout en metselwerk:Zetwerk tussen hout en metselwerk
Pset_QuantityTakeOff - sets with these values: 2

# IfcWallStandardCase: Basic Wall:47.11_2 laagse APP dakbedekking (34)
Type - PredefinedType: STANDARD; Material: n2_bitumen_dak bedekking 6 mm
Type - Pset_ElementShading - Roughness: 304.8 mm
Type - Pset_ManufacturerTypeInformation - Manufacturer: 2 laagse APP 460P60 onderlaag met 446K14 toplaag
Type - Pset_ProductRequirements - Category: Walls
Type - Pset_QuantityTakeOff - Reference: Basic Wall:47.11_2 laagse APP dakbedekking
Type - Pset_ReinforcementBarPitchOfWall - Description: 2 laagse Bitumen APP dakbedekking; Reference: Basic Wall:47.11_2 laagse APP dakbedekking
Type - Pset_WallCommon - IsExternal: no; Reference: Basic Wall:47.11_2 laagse APP dakbedekking
Classification: 47.11 dakafwerkingen; afwerkingen, vlakke dakafwerkingen (Uniformat)
BaseQuantities - Width: 6 mm
Pset_WallCommon - IsExternal: yes; ExtendToStructure: no; LoadBearing: no
Name (Basic Wall:47.11_2 laagse APP dakbedekking:...) | In | Height (mm) | Length (mm) | GrossFootprintArea (m2) | NetVolume (m3) | NetSideArea (m2)
5739595 | Podium | 361.989 | 11923.2 | 0.0715394 | 25896464 | 4316077
5740023 | Podium | 313.263 | 4039.77 | 0.0242386 | 7593064 | 1265511
5745980 | 01 eerste verdieping | 146.625 | 15250 | 0.0915 | 13416149 | 2236025
5746478 | 01 eerste verdieping | 214.154 | 7497.06 | 0.0449824 | 9633159 | 1605526
5800716 | Podium | 195.224 | 3168.71 | 0.0190123 | 3711657 | 618610
6066486 | 01 eerste verdieping | 150 | 1653.24 | 0.00991947 | 1487918 | 247986
6068659 | 01 eerste verdieping | 465 | 18418.5 | 0.110511 | 51387514 | 8564586
6068660 | 01 eerste verdieping | 150 | 117.442 | 0.000704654 | 105698 | 17616.3
6068665 | 01 eerste verdieping | 261.897 | 18312.6 | 0.109876 | 28776079 | 4796013
6068725 | 01 eerste verdieping | 312.474 | 26587.9 | 0.159527 | 49848099 | 8308017
6068898 | Podium | 313.359 | 6458 | 0.038748 | 12142044 | 2023674
6148619 | 01 eerste verdieping | 286.227 | 8101.7 | 0.0486102 | 13913575 | 2318929
6148635 | Podium | 341 | 7455.41 | 0.0447325 | 15253777 | 2542296
6148636 | 01 eerste verdieping | 219.393 | 1932.56 | 0.0115953 | 2543941 | 423990
6153758 | Podium | 77.2058 | 9779.08 | 0.0586745 | 4530007 | 755001
6173642 | 01 eerste verdieping | 289.983 | 12279.7 | 0.0736784 | 21365490 | 3560915
6318582 | 01 eerste verdieping | 37.8478 | 1126.48 | 0.0067589 | 255810 | 42634.9
6320097 | 01 eerste verdieping | 84.1308 | 1126.48 | 0.0067589 | 568632 | 94771.9
6408873 | 02 tweede verdieping | 221.195 | 31675.3 | 0.190052 | 42038511 | 7006419
6409611 | 02 tweede verdieping | 221.195 | 31675.3 | 0.190052 | 42038511 | 7006419
6409693 | 02 tweede verdieping | 221.195 | 12279.5 | 0.0736773 | 16297056 | 2716176
6482469 | Podium | 346.5 | 9763.86 | 0.0585832 | 20299072 | 3383179
7947748 | 01 eerste verdieping | 398.621 | 4996.7 | 0.0299802 | 11950736 | 1991789
8060478 | Podium | 228.757 | 7271.12 | 0.0436267 | 9979919 | 1663320
8069249 | 01 eerste verdieping | 229.157 | 1220.82 | 0.00732494 | 1678563 | 279760
8266934 | 01 eerste verdieping | 219.622 | 139.211 | 0.000835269 | 183443 | 30573.9
8374186 | 01 eerste verdieping | 146.625 | 710.373 | 0.00426224 | 624948 | 104158
8374509 | 01 eerste verdieping | 147.698 | 730.499 | 0.00438299 | 647359 | 107893
9044816 | 01 eerste verdieping | 63 | 1034.19 | 0.00620515 | 390924 | 65154
9044823 | 01 eerste verdieping | 150 | 1657.41 | 0.00994449 | 1491671 | 248612
9045122 | 01 eerste verdieping | 297 | 23518.7 | 0.141116 | 41910297 | 6985050
9045145 | 01 eerste verdieping | 63 | 1034.21 | 0.00620524 | 390930 | 65155.1
9103056 | 01 eerste verdieping | 249.366 | 18738.6 | 0.112431 | 28036640 | 4672773
10041237 | 01 eerste verdieping | 371.668 | 16065.9 | 0.0963951 | 35827015 | 5971169

# IfcWallStandardCase: Basic Wall:NLRS_16_WA_funderingsbalk 350x...mm_gen_aly (92)
In: ok. fundering
Type - PredefinedType: STANDARD; Material: NLRS_f2_beton 350 mm
Type - Pset_ConcreteElementGeneral - FireRating: -
Type - Pset_ElementShading - Roughness: 304.8 mm
Type - Pset_ProductRequirements - Category: Walls
Type - Pset_QuantityTakeOff - Reference: Basic Wall:NLRS_16_WA_funderingsbalk 350x...mm_gen_aly
Type - Pset_ReinforcementBarPitchOfWall - Description: Funderingsbalk 350x...mm; Reference: Basic Wall:NLRS_16_WA_funderingsbalk 350x...mm_gen_aly
Type - Pset_WallCommon - IsExternal: no; Reference: Basic Wall:NLRS_16_WA_funderingsbalk 350x...mm_gen_aly; FireRating: -
Classification: 16.12 funderingsconstructies; voeten en balken, fundatie balken (Uniformat); Group: Model Group:Nieuwe fundering:6653684
BaseQuantities - Width: 350 mm
Pset_WallCommon - IsExternal: yes; ExtendToStructure: no; LoadBearing: no
Name (Basic Wall:NLRS_16_WA_funderingsbalk 350x...mm_gen_aly:...) | Height (mm) | Length (mm) | GrossFootprintArea (m2) | NetVolume (m3) | NetSideArea (m2)
5517412 | 500 | 4165.89 | 1.44446 | 729030784 | 2082945
5522823 | 500 | 38875 | 13.6062 | 6803125000 | 19437500
5530341 | 500 | 13767.3 | 4.81854 | 2409272462 | 6883636
5530692 | 500 | 4009.97 | 1.40349 | 701744703 | 2004985
5531077 | 500 | 7022.48 | 2.45787 | 1228934801 | 3511242
5531642 | 500 | 10119.8 | 3.54193 | 1770964627 | 5059899
5630511 | 500 | 9810.01 | 3.4335 | 1716751929 | 4905006
5640165 | 500 | 9316.18 | 3.26066 | 1630331123 | 4658089
5729480 | 500 | 1718.75 | 0.596649 | 300781095 | 859375
5729491 | 500 | 1725.09 | 0.59837 | 301891615 | 862547
5729502 | 500 | 1726.37 | 0.598511 | 302114517 | 863184
5729522 | 500 | 1824.56 | 0.633178 | 319297617 | 912279
5729531 | 500 | 1740.37 | 0.603564 | 304564190 | 870183
5729540 | 500 | 1737.93 | 0.60271 | 304137167 | 868963
5729549 | 500 | 1737.93 | 0.602713 | 304137612 | 868965
5729558 | 500 | 1840.22 | 0.638516 | 322037914 | 920108
5729613 | 500 | 1840.22 | 0.638516 | 322037914 | 920108
5729635 | 500 | 1737.93 | 0.602713 | 304137612 | 868965
5729644 | 500 | 1737.93 | 0.60271 | 304137167 | 868963
5729653 | 500 | 1737.86 | 0.602687 | 304125917 | 868931
5730415 | 500 | 1723.24 | 0.596713 | 301566445 | 861618
5730467 | 500 | 1740.37 | 0.603564 | 304564190 | 870183
5730476 | 500 | 1737.93 | 0.60271 | 304137167 | 868963
5730485 | 500 | 1737.93 | 0.602713 | 304137612 | 868965
5730494 | 500 | 1840.22 | 0.638516 | 322037914 | 920108
5730503 | 500 | 1840.22 | 0.638516 | 322037914 | 920108
5730512 | 500 | 1737.93 | 0.602713 | 304137612 | 868965
5730521 | 500 | 1737.93 | 0.60271 | 304137167 | 868963
5730530 | 500 | 1740.37 | 0.603564 | 304564190 | 870183
5730539 | 500 | 1824.56 | 0.633178 | 319297617 | 912279
5730548 | 500 | 1852.96 | 0.642892 | 324267664 | 926479
5730559 | 500 | 1728.31 | 0.599189 | 302453883 | 864154
5730568 | 500 | 1725.1 | 0.598367 | 301892101 | 862549
5730579 | 500 | 1718.75 | 0.596649 | 300781095 | 859375
5730592 | 500 | 1838 | 0.641092 | 321649597 | 918999
5731910 | 500 | 1647.44 | 0.568924 | 288302534 | 823722
5731921 | 500 | 7752.44 | 2.70685 | 1356676488 | 3876219
5731954 | 500 | 7751.39 | 2.70642 | 1356493872 | 3875697
5731981 | 500 | 7752.69 | 2.70665 | 1356720201 | 3876343
6645886 | 370 | 28854.1 | 10.0989 | 3736607885 | 10676023
6646427 | 500 | 7562.98 | 2.64522 | 1323521811 | 3781491
6646474 | 370 | 7399.64 | 2.58378 | 958253656 | 2737868
6646536 | 500 | 7660.14 | 2.68105 | 1340525343 | 3830072
6646575 | 500 | 7402.75 | 2.58496 | 1295482034 | 3701377
6646625 | 370 | 7662.55 | 2.68188 | 992299857 | 2835142
6646691 | 500 | 3560.47 | 1.23291 | 623082847 | 1780237
6646755 | 370 | 1507.76 | 0.512243 | 195255094 | 557872
6646845 | 370 | 6041.94 | 1.98035 | 782431620 | 2235519
6646930 | 370 | 6078.77 | 1.86181 | 787201128 | 2249146
6647037 | 370 | 2718.58 | 0.806729 | 352055978 | 1005874
6647138 | 370 | 2870.66 | 0.996734 | 371750172 | 1062143
6647202 | 500 | 1510.68 | 0.513251 | 264368973 | 755340
6647273 | 370 | 6050.5 | 1.98318 | 783540132 | 2238686
6647302 | 370 | 6056.1 | 1.85426 | 784264796 | 2240757
6647334 | 500 | 2611.64 | 0.771484 | 457037297 | 1305821
6647347 | 370 | 2991.02 | 1.03742 | 387337563 | 1106679
6647789 | 370 | 10187.7 | 3.56569 | 1319306652 | 3769448
6647901 | 370 | 7554.31 | 2.64169 | 978283395 | 2795095
6647961 | 370 | 7398.78 | 2.58303 | 958141705 | 2737548
6648093 | 500 | 7658.37 | 2.6804 | 1340214723 | 3829185
6648141 | 500 | 7398.37 | 2.58298 | 1294714283 | 3699184
6648181 | 370 | 7655.55 | 2.67943 | 991394202 | 2832555
6648465 | 370 | 20739 | 7.24511 | 2685700825 | 7673431
6648591 | 370 | 20793.6 | 7.2645 | 2692777563 | 7693650
6648767 | 500 | 45487.4 | 15.8337 | 7960297559 | 22743707
6648862 | 370 | 9732.5 | 3.40638 | 1260359122 | 3601026
6648917 | 370 | 9732.5 | 3.40638 | 1260359122 | 3601026
6649438 | 370 | 9732.5 | 3.40638 | 1260359122 | 3601026
6649493 | 370 | 9732.5 | 3.40638 | 1260359122 | 3601026
6649561 | 370 | 9732.5 | 3.40638 | 1260359122 | 3601026
6649741 | 500 | 8328.89 | 2.91511 | 1457555158 | 4164443
6649801 | 370 | 12217.2 | 4.276 | 1582121094 | 4520346
6649881 | 370 | 10187.7 | 3.56569 | 1319306652 | 3769448
6650408 | 500 | 4234.93 | 1.48222 | 741112368 | 2117464
6650450 | 500 | 3659.97 | 1.28099 | 640494703 | 1829985
6650496 | 500 | 4009.97 | 1.40349 | 701744703 | 2004985
6650529 | 500 | 4009.97 | 1.40349 | 701744703 | 2004985
6650703 | 500 | 6450.92 | 2.25782 | 1128911816 | 3225462
6650735 | 500 | 6591.64 | 2.30707 | 1153537137 | 3295820
6651091 | 370 | 8004.61 | 2.80161 | 1036597263 | 2961706
6651290 | 500 | 6450.92 | 2.25782 | 1128911816 | 3225462
6651563 | 500 | 9316.18 | 3.26066 | 1630331123 | 4658089
6651728 | 370 | 9110 | 3.1885 | 1179745000 | 3370700
6651817 | 500 | 6450.92 | 2.25782 | 1128911816 | 3225462
6651959 | 370 | 9732.5 | 3.40638 | 1260359122 | 3601026
6652046 | 370 | 10187.7 | 3.56569 | 1319306652 | 3769448
6652110 | 370 | 10187.7 | 3.56569 | 1319306652 | 3769448
6653022 | 370 | 8093.55 | 2.83274 | 1048115189 | 2994615
6653093 | 370 | 4527.69 | 1.57109 | 586335654 | 1675245
6653492 | 370 | 6626.62 | 2.31932 | 858147676 | 2451851
6653524 | 500 | 2230.39 | 0.780636 | 390318018 | 1115194
6803463 | 370 | 8650.05 | 3.02752 | 1120181600 | 3200519

# IfcWallStandardCase: Basic Wall:NLRS_16_WA_funderingsbalk 400x...mm_gen_aly (2)
In: ok. fundering
Type - PredefinedType: STANDARD; Material: NLRS_f2_beton 400 mm
Type - Pset_ConcreteElementGeneral - FireRating: -
Type - Pset_ElementShading - Roughness: 304.8 mm
Type - Pset_ProductRequirements - Category: Walls
Type - Pset_QuantityTakeOff - Reference: Basic Wall:NLRS_16_WA_funderingsbalk 400x...mm_gen_aly
Type - Pset_ReinforcementBarPitchOfWall - Description: Funderingsbalk 450x...mm; Reference: Basic Wall:NLRS_16_WA_funderingsbalk 400x...mm_gen_aly
Type - Pset_WallCommon - IsExternal: no; Reference: Basic Wall:NLRS_16_WA_funderingsbalk 400x...mm_gen_aly; FireRating: -
Classification: 16.12 funderingsconstructies; voeten en balken, fundatie balken (Uniformat); Group: Model Group:Nieuwe fundering:6653684
BaseQuantities - Height: 500 mm; Width: 400 mm
Pset_WallCommon - IsExternal: yes; ExtendToStructure: no; LoadBearing: no
Name (Basic Wall:NLRS_16_WA_funderingsbalk 400x...mm_gen_aly:...) | Length (mm) | GrossFootprintArea (m2) | NetVolume (m3) | NetSideArea (m2)
5519526 | 4623.14 | 1.83149 | 924627575 | 2311569
5519809 | 4105.52 | 1.62445 | 821104141 | 2052760

# IfcWallStandardCase: Basic Wall:NLRS_16_WA_funderingsbalk 450x...mm_gen_aly (20)
In: ok. fundering
Type - PredefinedType: STANDARD; Material: NLRS_f2_beton 450 mm
Type - Pset_ConcreteElementGeneral - FireRating: -
Type - Pset_ElementShading - Roughness: 304.8 mm
Type - Pset_ProductRequirements - Category: Walls
Type - Pset_QuantityTakeOff - Reference: Basic Wall:NLRS_16_WA_funderingsbalk 450x...mm_gen_aly
Type - Pset_ReinforcementBarPitchOfWall - Description: Funderingsbalk 450x...mm; Reference: Basic Wall:NLRS_16_WA_funderingsbalk 450x...mm_gen_aly
Type - Pset_WallCommon - IsExternal: no; Reference: Basic Wall:NLRS_16_WA_funderingsbalk 450x...mm_gen_aly; FireRating: -
Classification: 16.12 funderingsconstructies; voeten en balken, fundatie balken (Uniformat)
BaseQuantities - Width: 450 mm
Pset_WallCommon - IsExternal: yes; ExtendToStructure: no; LoadBearing: no
Name (Basic Wall:NLRS_16_WA_funderingsbalk 450x...mm_gen_aly:...) | Height (mm) | Length (mm) | GrossFootprintArea (m2) | NetVolume (m3) | NetSideArea (m2)
3846825 | 470 | 3033.37 | 1.3637 | 641557813 | 1425684
3847144 | 470 | 5197.64 | 2.33828 | 1099301008 | 2442891
3847269 | 470 | 21619 | 9.72855 | 4572418500 | 10160930
3847374 | 470 | 12189.1 | 5.48508 | 2577987630 | 5728861
3847496 | 470 | 21169 | 9.52605 | 4477243500 | 9949430
3847724 | 470 | 11739.1 | 5.28258 | 2482812630 | 5517361
3849589 | 520 | 9414.05 | 4.23632 | 2202888696 | 4895308
3849694 | 520 | 13061.2 | 5.87756 | 3056331669 | 6791848
3851665 | 520 | 8964.05 | 4.03382 | 2097588696 | 4661308
3851795 | 520 | 12611.2 | 5.67506 | 2951031669 | 6557848
3851945 | 470 | 7115 | 3.20175 | 1504822500 | 3344050
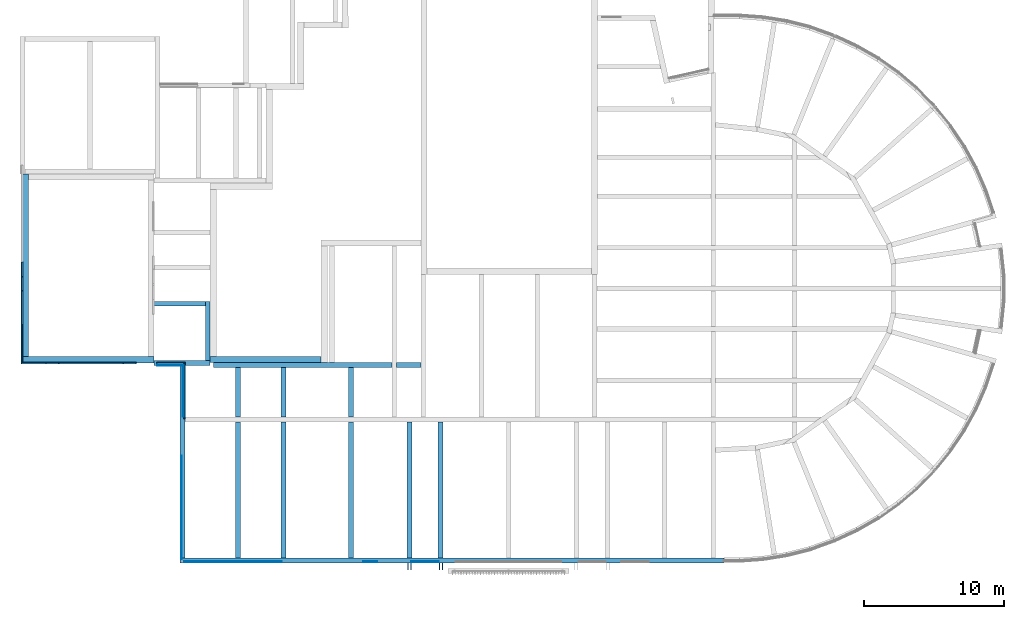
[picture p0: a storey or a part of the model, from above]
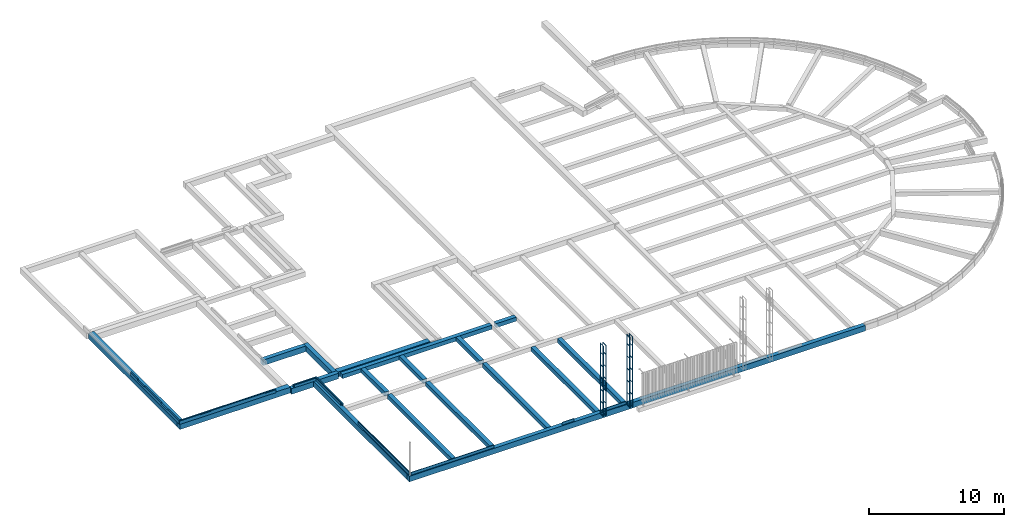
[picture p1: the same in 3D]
Properties of the parts of a building model (IFC2X3), part 10 of 13

# IfcWallStandardCase: Basic Wall:NLRS_16_WA_funderingsbalk 450x...mm_gen_aly (20)
Name (Basic Wall:NLRS_16_WA_funderingsbalk 450x...mm_gen_aly:...) | Height (mm) | Length (mm) | GrossFootprintArea (m2) | NetVolume (m3) | NetSideArea (m2)
3852113 | 450 | 8328.89 | 3.748 | 1686599539 | 3747999
3852214 | 450 | 7939 | 3.57255 | 1607647500 | 3572550
3852320 | 450 | 4444.64 | 2.00009 | 900040074 | 2000089
3852418 | 450 | 11939.3 | 5.37268 | 2417708235 | 5372685
3852521 | 470 | 6665.94 | 2.99967 | 1409846832 | 3132993
3852562 | 470 | 2715.36 | 1.22191 | 574298145 | 1276218
3852596 | 470 | 4396.23 | 1.97831 | 929803555 | 2066230
3852881 | 470 | 2716 | 1.22154 | 574433898 | 1276520
5898843 | 500 | 6734.37 | 3.03047 | 1515233412 | 3367185 | Group: Model Group:Nieuwe fundering:6653684

# IfcWallStandardCase: Basic Wall:NLRS_20_WA_Metselwerk 100mm, Eems wf-p-0081-25 (34)
Type - PredefinedType: STANDARD; Material: NLRS_g2_baksteen hf-225x105x42-10mm voeg halfsteens rood genuanceerd_gen 100 mm
Type - Pset_ConcreteElementGeneral - FireRating: -
Type - Pset_ElementShading - Roughness: 304.8 mm
Type - Pset_ProductRequirements - Category: Walls
Type - Pset_QuantityTakeOff - Reference: Basic Wall:NLRS_20_WA_Metselwerk 100mm, Eems wf-p-0081-25
Type - Pset_ReinforcementBarPitchOfWall - Reference: Basic Wall:NLRS_20_WA_Metselwerk 100mm, Eems wf-p-0081-25
Type - Pset_WallCommon - IsExternal: no; Reference: Basic Wall:NLRS_20_WA_Metselwerk 100mm, Eems wf-p-0081-25; FireRating: -
Classification: 21.11 buitenwanden; niet constructief, massieve wanden (Uniformat)
BaseQuantities - Width: 100 mm
Pset_QuantityTakeOff - sets with these values: 2
Pset_WallCommon - IsExternal: yes; ExtendToStructure: no; LoadBearing: no
Name (Basic Wall:NLRS_20_WA_Metselwerk 100mm, Eems wf-p-0081-25:...) | In | Height (mm) | Length (mm) | GrossFootprintArea (m2) | NetVolume (m3) | NetSideArea (m2)
3051243 | 00 begane grond | 3001 | 6155.9 | 0.61559 | 1847386829 | 18473868
3214727 | 00 begane grond | 3590 | 3770.59 | 0.377059 | 1353642731 | 13536427
3667087 | 00 begane grond | 3175.64 | 6733.35 | 0.673335 | 2138271436 | 21382714
3667135 | 00 begane grond | 3144.34 | 6636.97 | 0.663697 | 2086891231 | 20868912
3667366 | 00 begane grond | 987.76 | 202 | 0.0202 | 19952747 | 199527
3670986 | 00 begane grond | 2977 | 2252.53 | 0.225253 | 670576729 | 6705767
4203401 | 00 begane grond | 3400 | 2646.7 | 0.26467 | 899877670 | 8998777
4204238 | 01 eerste verdieping | 3174.85 | 2712.5 | 0.27125 | 861178620 | 8611786
4310737 | 00 begane grond | 3707.18 | 1571.03 | 0.157103 | 582408028 | 5824080
4310781 | 00 begane grond | 3165.43 | 330 | 0.033 | 104459305 | 1044593
4311593 | 00 begane grond | 3156.89 | 330 | 0.033 | 104177286 | 1041773
4396212 | 00 begane grond | 1037 | 8250.89 | 0.825089 | 855616933 | 8556169
4556660 | 00 begane grond | 3350 | 1487.31 | 0.148731 | 498248376 | 4982484
5202593 | 00 begane grond | 3136 | 3428.87 | 0.342887 | 1075294637 | 10752946
5205086 | 00 begane grond | 3819.1 | 12659 | 1.2659 | 4834598690 | 48345987
5630397 | 00 begane grond | 981.4 | 9190 | 0.919 | 901906600 | 9019066
5640108 | 00 begane grond | 3087 | 9846.18 | 0.984618 | 3039515101 | 30395151
5640125 | 01 eerste verdieping | 3359.25 | 2173.65 | 0.217365 | 730183118 | 7301831
5797260 | 00 begane grond | 3140 | 1200 | 0.12 | 376800000 | 3768000
5797399 | 00 begane grond | 3140 | 1200 | 0.12 | 376800000 | 3768000
5797563 | 00 begane grond | 3140 | 1090 | 0.109 | 342260011 | 3422600
5797769 | 00 begane grond | 3140 | 5380 | 0.538 | 1689320000 | 16893200
5798143 | 00 begane grond | 3140 | 3492 | 0.3492 | 1096488000 | 10964880
5798440 | 00 begane grond | 3140 | 5739.15 | 0.573915 | 1802093537 | 18020935
5897579 | 01 eerste verdieping | 2904.93 | 8940.46 | 0.894046 | 2597142678 | 25971427
6481548 | 00 begane grond | 347.5 | 1266.29 | 0.126629 | 44003494 | 440035
6614181 | 01 eerste verdieping | 3073.61 | 1700.81 | 0.170081 | 522762651 | 5227627
7741573 | 00 begane grond | 3712.9 | 1588.18 | 0.158818 | 589674472 | 5896745
7742197 | 00 begane grond | 3178.08 | 330 | 0.033 | 104876663 | 1048767
7744308 | 00 begane grond | 3713.36 | 1587.8 | 0.15878 | 589607972 | 5896080
7756369 | 00 begane grond | 3707.63 | 1571.86 | 0.157186 | 582785895 | 5827859
7756513 | 00 begane grond | 3158.68 | 330 | 0.033 | 104236484 | 1042365
10122158 | 00 begane grond | 3819.1 | 6921.64 | 0.692164 | 2643443832 | 26434438
10125431 | 00 begane grond | 3061 | 2553.91 | 0.255391 | 781750672 | 7817507

# IfcWallStandardCase: Basic Wall:NLRS_20_WA_Metselwerk 100mm, Gekeimd (3)
In: 00 begane grond
Type - PredefinedType: STANDARD; Material: NLRS_g2_baksteen hf-225x105x42-10mm voeg halfsteens rood genuanceerd_gen 100 mm
Type - Pset_ConcreteElementGeneral - FireRating: -
Type - Pset_ElementShading - Roughness: 304.8 mm
Type - Pset_ProductRequirements - Category: Walls
Type - Pset_QuantityTakeOff - Reference: Basic Wall:NLRS_20_WA_Metselwerk 100mm, Gekeimd
Type - Pset_ReinforcementBarPitchOfWall - Reference: Basic Wall:NLRS_20_WA_Metselwerk 100mm, Gekeimd
Type - Pset_WallCommon - IsExternal: no; Reference: Basic Wall:NLRS_20_WA_Metselwerk 100mm, Gekeimd; FireRating: -
Classification: 21.11 buitenwanden; niet constructief, massieve wanden (Uniformat)
BaseQuantities - Width: 100 mm
Pset_QuantityTakeOff - sets with these values: 2
Pset_WallCommon - IsExternal: yes; ExtendToStructure: no; LoadBearing: no
Name (Basic Wall:NLRS_20_WA_Metselwerk 100mm, Gekeimd:...) | Height (mm) | Length (mm) | GrossFootprintArea (m2) | NetVolume (m3) | NetSideArea (m2)
3431995 | 3625 | 3223.25 | 0.322325 | 1168428233 | 11684282
3432280 | 3625 | 12539.1 | 1.25391 | 4545411719 | 45454117
3432436 | 3615 | 986.566 | 0.0986566 | 356643643 | 3566436

# IfcWallStandardCase: Basic Wall:NLRS_20_WA_Metselwerk klamp, Eems wf-p-0081-25 (52)
Type - PredefinedType: STANDARD; Material: NLRS_g2_baksteen rood genuanceerd Klamp 50 mm
Type - Pset_ConcreteElementGeneral - FireRating: -
Type - Pset_ElementShading - Roughness: 304.8 mm
Type - Pset_ProductRequirements - Category: Walls
Type - Pset_QuantityTakeOff - Reference: Basic Wall:NLRS_20_WA_Metselwerk klamp, Eems wf-p-0081-25
Type - Pset_ReinforcementBarPitchOfWall - Reference: Basic Wall:NLRS_20_WA_Metselwerk klamp, Eems wf-p-0081-25
Type - Pset_WallCommon - IsExternal: no; Reference: Basic Wall:NLRS_20_WA_Metselwerk klamp, Eems wf-p-0081-25; FireRating: -
Classification: 21.11 buitenwanden; niet constructief, massieve wanden (Uniformat)
BaseQuantities - Width: 50 mm
Pset_QuantityTakeOff - sets with these values: 2
Pset_WallCommon - IsExternal: yes; ExtendToStructure: no; LoadBearing: no
Name (Basic Wall:NLRS_20_WA_Metselwerk klamp, Eems wf-p-0081-25:...) | In | Height (mm) | Length (mm) | GrossFootprintArea (m2) | NetVolume (m3) | NetSideArea (m2)
3468788 | ok. fundering | 240 | 1029 | 0.05145 | 12348000 | 246960
3469093 | ok. fundering | 240 | 1980 | 0.099 | 23760000 | 475200
4006830 | ok. fundering | 240 | 1095.53 | 0.0547315 | 13146368 | 262927
4006998 | ok. fundering | 240 | 1714.74 | 0.0856366 | 20576857 | 411537
4007094 | ok. fundering | 240 | 1720.68 | 0.0859232 | 20648111 | 412962
4007219 | ok. fundering | 240 | 1723.64 | 0.0860653 | 20683679 | 413674
4011946 | ok. fundering | 240 | 2920 | 0.146 | 35040000 | 700800
4012276 | ok. fundering | 240 | 1837 | 0.09185 | 22044000 | 440880
4012577 | ok. fundering | 250 | 7495 | 0.37475 | 93687500 | 1873750
4012718 | ok. fundering | 240 | 7080.18 | 0.354009 | 84962213 | 1699244
4031803 | ok. fundering | 240 | 1330 | 0.0665 | 15960000 | 319200
4032196 | 00 begane grond | 310 | 1995 | 0.09975 | 30922500 | 618450
4037794 | ok. fundering | 240 | 1713.27 | 0.0856634 | 20559224 | 411184
4093500 | ok. fundering | 240 | 1980 | 0.099 | 23760000 | 475200
4358091 | ok. fundering | 240 | 2665.09 | 0.133255 | 31981126 | 639623
4384575 | ok. fundering | 240 | 7552.44 | 0.377622 | 90629276 | 1812586
5638864 | ok. fundering | 240 | 3695.57 | 0.184779 | 44346866 | 886937
5724783 | ok. fundering | 240 | 1848.35 | 0.0923024 | 22180212 | 443604
5724794 | ok. fundering | 240 | 1820.14 | 0.0908962 | 21841631 | 436833
5724805 | ok. fundering | 240 | 1735.82 | 0.0866777 | 20829894 | 416598
5724814 | ok. fundering | 240 | 1733.38 | 0.0865557 | 20800612 | 416012
5724823 | ok. fundering | 240 | 1733.39 | 0.0865559 | 20800659 | 416013
5724832 | ok. fundering | 240 | 1721.5 | 0.0859902 | 20658059 | 413161
5724841 | ok. fundering | 240 | 1721.5 | 0.0859902 | 20658059 | 413161
5724850 | ok. fundering | 240 | 1733.39 | 0.0865559 | 20800659 | 416013
5724859 | ok. fundering | 240 | 1733.38 | 0.0865557 | 20800612 | 416012
5724870 | ok. fundering | 240 | 1733.32 | 0.0865524 | 20799841 | 415997
5724879 | ok. fundering | 240 | 1731.09 | 0.0864977 | 20773068 | 415461
5724888 | ok. fundering | 240 | 1979.75 | 0.0976411 | 23756963 | 475139
5724897 | ok. fundering | 240 | 1718 | 0.0857688 | 20615953 | 412319
5725034 | ok. fundering | 240 | 1980.56 | 0.0978163 | 23766740 | 475335
5725043 | ok. fundering | 240 | 1716.92 | 0.085789 | 20602989 | 412060
5725054 | ok. fundering | 240 | 1735.82 | 0.0866777 | 20829894 | 416598
5725063 | ok. fundering | 240 | 1733.38 | 0.0865557 | 20800612 | 416012
5725072 | ok. fundering | 240 | 1733.39 | 0.0865559 | 20800659 | 416013
5725081 | ok. fundering | 240 | 1721.35 | 0.0859824 | 20656180 | 413124
5725090 | ok. fundering | 240 | 1721.67 | 0.0859983 | 20660017 | 413200
5725099 | ok. fundering | 240 | 1733.39 | 0.0865559 | 20800659 | 416013
5725108 | ok. fundering | 240 | 1733.38 | 0.0865557 | 20800612 | 416012
5725117 | ok. fundering | 240 | 1735.82 | 0.0866777 | 20829894 | 416598
5725126 | ok. fundering | 240 | 1714.45 | 0.0856372 | 20573360 | 411467
5725137 | ok. fundering | 240 | 1734.16 | 0.0866214 | 20809967 | 416199
5725146 | ok. fundering | 240 | 1716.11 | 0.0856889 | 20593345 | 411867
5725159 | ok. fundering | 240 | 1724.65 | 0.0861221 | 20695829 | 413917
5725168 | ok. fundering | 240 | 1714.74 | 0.0856366 | 20576857 | 411537
5725179 | ok. fundering | 240 | 1806.2 | 0.0902648 | 21674355 | 433487
5725948 | ok. fundering | 240 | 223.254 | 0.011109 | 2679053 | 53581.1
5726172 | ok. fundering | 240 | 228.106 | 0.0113486 | 2737271 | 54745.4
5726971 | ok. fundering | 240 | 228.112 | 0.011349 | 2737350 | 54747
5727398 | ok. fundering | 240 | 1703.68 | 0.085028 | 20444209 | 408884
5838130 | ok. fundering | 240 | 1959.23 | 0.0979613 | 23510706 | 470214
10239866 | ok. fundering | 240 | 741 | 0.03705 | 8892000 | 177840

# IfcWallStandardCase: Basic Wall:NLRS_20_WA_Metselwerk rood 100mm (3)
In: 00 begane grond
Type - PredefinedType: STANDARD; Material: NLRS_g2_baksteen hf-225x105x42-10mm voeg halfsteens rood genuanceerd_gen 100 mm
Type - Pset_ConcreteElementGeneral - FireRating: -
Type - Pset_ElementShading - Roughness: 304.8 mm
Type - Pset_ProductRequirements - Category: Walls
Type - Pset_QuantityTakeOff - Reference: Basic Wall:NLRS_20_WA_Metselwerk rood 100mm
Type - Pset_ReinforcementBarPitchOfWall - Reference: Basic Wall:NLRS_20_WA_Metselwerk rood 100mm
Type - Pset_WallCommon - IsExternal: no; Reference: Basic Wall:NLRS_20_WA_Metselwerk rood 100mm; FireRating: -
Classification: 21.11 buitenwanden; niet constructief, massieve wanden (Uniformat)
BaseQuantities - Width: 100 mm
Pset_QuantityTakeOff - sets with these values: 2
Pset_WallCommon - IsExternal: yes; ExtendToStructure: no; LoadBearing: no
Name (Basic Wall:NLRS_20_WA_Metselwerk rood 100mm:...) | Height (mm) | Length (mm) | GrossFootprintArea (m2) | NetVolume (m3) | NetSideArea (m2)
7794939 | 3136 | 195 | 0.0195 | 61152000 | 611520
10122638 | 2900 | 265 | 0.0265 | 76850000 | 768500
10122639 | 2900 | 265 | 0.0265 | 76850000 | 768500

# IfcWallStandardCase: Basic Wall:NLRS_20_WA_Metselwerk-100mm (96)
Type - PredefinedType: STANDARD; Material: AL_metselwerk 210x100x50 halfsteens geel 100 mm
Type - Pset_ConcreteElementGeneral - FireRating: -
Type - Pset_ElementShading - Roughness: 304.8 mm
Type - Pset_ProductRequirements - Category: Walls
Type - Pset_QuantityTakeOff - Reference: Basic Wall:NLRS_20_WA_Metselwerk-100mm
Type - Pset_ReinforcementBarPitchOfWall - Reference: Basic Wall:NLRS_20_WA_Metselwerk-100mm
Type - Pset_WallCommon - IsExternal: no; Reference: Basic Wall:NLRS_20_WA_Metselwerk-100mm; FireRating: -
Classification: 21.11 buitenwanden; niet constructief, massieve wanden (Uniformat)
BaseQuantities - Width: 100 mm
Pset_QuantityTakeOff - sets with these values: 2
Pset_WallCommon - IsExternal: yes; ExtendToStructure: no; LoadBearing: no
Name (Basic Wall:NLRS_20_WA_Metselwerk-100mm:...) | In | Height (mm) | Length (mm) | GrossFootprintArea (m2) | NetVolume (m3) | NetSideArea (m2)
2836777 | 00 begane grond | 2807 | 7869 | 0.7869 | 2208828300 | 22088283
2837406 | 00 begane grond | 2807 | 2701.46 | 0.270017 | 758298725 | 7582987
2837507 | 00 begane grond | 2807 | 2691.32 | 0.269031 | 755453583 | 7554536
2837573 | 00 begane grond | 2807 | 2689 | 0.2689 | 754802300 | 7548023
2837730 | 00 begane grond | 2807 | 1423.96 | 0.142396 | 399704211 | 3997042
2838746 | 00 begane grond | 2737 | 1495.71 | 0.14943 | 409376287 | 4093763
2839417 | 00 begane grond | 2737 | 5552.15 | 0.555215 | 1519622293 | 15196223
2840314 | 00 begane grond | 2737 | 1278.58 | 0.127858 | 349947702 | 3499477
2840353 | 00 begane grond | 2737 | 1685.3 | 0.16853 | 461265802 | 4612658
2840409 | 00 begane grond | 2737 | 9996.66 | 0.999666 | 2736085855 | 27360859
2840558 | 00 begane grond | 2737 | 1175.32 | 0.117532 | 321685465 | 3216855
2840664 | 00 begane grond | 2737 | 1610.7 | 0.16107 | 440847786 | 4408478
2840737 | 00 begane grond | 2737 | 1175.32 | 0.117532 | 321685465 | 3216855
2840867 | 00 begane grond | 2737 | 1244.61 | 0.124434 | 340648815 | 3406488
2840985 | 00 begane grond | 2737 | 4821.89 | 0.48212 | 1319752279 | 13197523
2841094 | 00 begane grond | 2737 | 9070 | 0.907 | 2482459000 | 24824590
2841310 | 00 begane grond | 2737 | 1078.58 | 0.107858 | 295207702 | 2952077
2841667 | 00 begane grond | 2737 | 877.957 | 0.0877755 | 240296856 | 2402969
2841721 | 00 begane grond | 2737 | 1125.41 | 0.112501 | 308025362 | 3080254
2841861 | 00 begane grond | 2737 | 3270.55 | 0.327055 | 895150124 | 8951501
2843599 | 00 begane grond | 2737 | 3936.4 | 0.393571 | 1077392250 | 10773923
2844285 | 00 begane grond | 2807 | 1432.55 | 0.143235 | 402117353 | 4021174
2857539 | 00 begane grond | 2807 | 1040.56 | 0.103911 | 292085191 | 2920852
2858695 | 00 begane grond | 2737 | 1530.79 | 0.153079 | 418977660 | 4189777
3304212 | 00 begane grond | 2737 | 1840.79 | 0.184079 | 503824660 | 5038247
3304571 | 00 begane grond | 2737 | 793.262 | 0.0793262 | 217115779 | 2171158
3305066 | 00 begane grond | 2737 | 776.509 | 0.0776509 | 212530552 | 2125306
3365087 | 00 begane grond | 2737 | 4417.69 | 0.441682 | 1209123011 | 12091230
3367667 | 00 begane grond | 2230 | 1240.26 | 0.124011 | 276577396 | 2765774
3368781 | 00 begane grond | 2792 | 9378.43 | 0.93784 | 2618456731 | 26184567
3370089 | 00 begane grond | 2220 | 6194.99 | 0.619499 | 1375288807 | 13752888
3372710 | 00 begane grond | 2230 | 1782.91 | 0.178285 | 397588873 | 3975889
3372907 | 00 begane grond | 2230 | 476.009 | 0.0475793 | 106149925 | 1061499
3373206 | 00 begane grond | 2532 | 1273.78 | 0.127378 | 322521923 | 3225219
3374571 | 00 begane grond | 2782 | 1562.54 | 0.156217 | 434697424 | 4346974
3375358 | 00 begane grond | 2782 | 270.853 | 0.0270492 | 75351434 | 753514
3375724 | 00 begane grond | 2532 | 4575.26 | 0.457526 | 1158454773 | 11584548
3376864 | 00 begane grond | 2210 | 1615.64 | 0.161564 | 357056349 | 3570563
3379561 | 00 begane grond | 2737 | 2487.67 | 0.248767 | 680875831 | 6808758
3384299 | 00 begane grond | 572 | 260 | 0.026 | 14872000 | 148720
3406096 | 00 begane grond | 3127 | 8389.47 | 0.838907 | 2623386105 | 26233861
3406163 | 00 begane grond | 2807 | 7969.46 | 0.796906 | 2237028244 | 22370282
3406380 | 00 begane grond | 3176 | 3900.62 | 0.390042 | 1238836744 | 12388367
3406670 | 00 begane grond | 2841.5 | 110 | 0.011 | 31256500 | 312565
3406968 | 00 begane grond | 2807 | 7756.62 | 0.775642 | 2177282830 | 21772828
3407068 | 00 begane grond | 3127 | 8295.78 | 0.829558 | 2594090889 | 25940909
3407359 | 00 begane grond | 3176 | 5501.12 | 0.550112 | 1747155111 | 17471551
3407439 | 00 begane grond | 2807 | 4338.22 | 0.433822 | 1217739304 | 12177393
3407657 | 00 begane grond | 2807 | 210 | 0.021 | 58947000 | 589470
3407777 | 00 begane grond | 2807 | 110 | 0.011 | 30877000 | 308770
3407916 | 00 begane grond | 3186 | 2930.47 | 0.293032 | 933648932 | 9336489
3408141 | 00 begane grond | 2807 | 5740.33 | 0.574003 | 1611311164 | 16113112
3408192 | 00 begane grond | 3186 | 3992.36 | 0.399215 | 1271966213 | 12719662
3408503 | 00 begane grond | 2737 | 4185.45 | 0.418457 | 1145556507 | 11455565
3408777 | 00 begane grond | 2737 | 2370.63 | 0.236947 | 648842219 | 6488422
3409227 | 00 begane grond | 2737 | 311.186 | 0.0310021 | 85171722 | 851717
3409456 | 00 begane grond | 2737 | 3193.07 | 0.319286 | 873943060 | 8739431
3409987 | 00 begane grond | 2737 | 3147.15 | 0.314694 | 861376065 | 8613761
3410934 | 00 begane grond | 2737 | 5546.28 | 0.554596 | 1518017700 | 15180177
3411080 | 00 begane grond | 3107 | 210.652 | 0.0210003 | 65449464 | 654495
3412030 | 00 begane grond | 3615 | 2409.65 | 0.240965 | 871089380 | 8710894
3412338 | 00 begane grond | 3615 | 2029.46 | 0.202946 | 733648037 | 7336480
3412654 | 00 begane grond | 3107 | 6681.69 | 0.668169 | 2076002585 | 20760026
3412688 | 00 begane grond | 2737 | 8810.69 | 0.881069 | 2411487176 | 24114872
3413362 | 00 begane grond | 2737 | 3074.04 | 0.307404 | 841366076 | 8413661
3413465 | 00 begane grond | 2807 | 970 | 0.097 | 272279000 | 2722790
3413946 | 00 begane grond | 2737 | 1499.4 | 0.149931 | 410386593 | 4103866
3414260 | 00 begane grond | 2737 | 1493.71 | 0.149205 | 408827185 | 4088272
3414540 | 00 begane grond | 2230 | 160.001 | 0.0159785 | 35680333 | 356803
3414802 | 00 begane grond | 2240 | 160.094 | 0.0160064 | 35861149 | 358611
3415105 | 00 begane grond | 2807 | 110 | 0.011 | 30877000 | 308770
3423500 | 00 begane grond | 3176 | 407.088 | 0.0407088 | 129291090 | 1292911
3423650 | 00 begane grond | 2807 | 207.088 | 0.0207088 | 58129549 | 581295
3423704 | 00 begane grond | 2807 | 210 | 0.021 | 58947000 | 589470
3423838 | 00 begane grond | 2807 | 210 | 0.021 | 58947000 | 589470
3473361 | 00 begane grond | 3067 | 805.236 | 0.0805236 | 246965971 | 2469660
3473679 | 00 begane grond | 3067 | 1056.54 | 0.105654 | 324039361 | 3240394
4446257 | 00 begane grond | 3067 | 1366.72 | 0.136672 | 419171927 | 4191719
5111229 | 00 begane grond | 2807 | 320 | 0.032 | 89824000 | 898240
5144932 | 00 begane grond | 3107 | 110 | 0.011 | 34177000 | 341770
5145123 | 00 begane grond | 3107 | 110 | 0.011 | 34177000 | 341770
5145407 | 00 begane grond | 3107 | 87.3052 | 0.00873052 | 27125715 | 271257
5145542 | 00 begane grond | 3107 | 87.3052 | 0.00873052 | 27125715 | 271257
5635061 | 00 begane grond | 2807 | 320 | 0.032 | 89824000 | 898240
6265088 | ok. fundering | 260 | 2091.92 | 0.209192 | 54389870 | 543899
6266200 | ok. fundering | 250 | 4145.56 | 0.414556 | 103639010 | 1036390
6268657 | 00 begane grond | 552 | 165 | 0.0165 | 9108004 | 91080
6272662 | 00 begane grond | 2807 | 4025.51 | 0.402551 | 1129961483 | 11299615
7335363 | 00 begane grond | 3117 | 310.654 | 0.0310005 | 96830771 | 968308
7473057 | 00 begane grond | 18.8683 | 1034 | 0.1034 | 1950982 | 19509.8
7473696 | 00 begane grond | 827 | 3249.7 | 0.32497 | 268749872 | 2687499
7473931 | 00 begane grond | 827 | 5625.65 | 0.562565 | 465241617 | 4652416
8391146 | 00 begane grond | 3615 | 2312.72 | 0.231272 | 836048090 | 8360481
9698492 | 00 begane grond | 2737 | 882.493 | 0.0882493 | 241538396 | 2415384
9698783 | 00 begane grond | 2737 | 881.686 | 0.0881686 | 241317430 | 2413174
12474738 | 00 begane grond | 1960 | 0.495601 | 0.0000495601 | 97137.7 | 971.377

# IfcWallStandardCase: Basic Wall:NLRS_20_WA_Metselwerk-100mm licht grijs gekeimd (21)
In: 00 begane grond
Type - PredefinedType: STANDARD; Material: NLRS_g2_baksteen ijf-160x78x41-10mm voeg halfsteens Licht grijs 100 mm
Type - Pset_ConcreteElementGeneral - FireRating: -
Type - Pset_ElementShading - Roughness: 304.8 mm
Type - Pset_ProductRequirements - Category: Walls
Type - Pset_QuantityTakeOff - Reference: Basic Wall:NLRS_20_WA_Metselwerk-100mm licht grijs gekeimd
Type - Pset_ReinforcementBarPitchOfWall - Reference: Basic Wall:NLRS_20_WA_Metselwerk-100mm licht grijs gekeimd
Type - Pset_WallCommon - IsExternal: no; Reference: Basic Wall:NLRS_20_WA_Metselwerk-100mm licht grijs gekeimd; FireRating: -
Classification: 21.11 buitenwanden; niet constructief, massieve wanden (Uniformat)
BaseQuantities - Width: 100 mm
Pset_QuantityTakeOff - sets with these values: 2
Pset_WallCommon - IsExternal: yes; ExtendToStructure: no; LoadBearing: no
Name (Basic Wall:NLRS_20_WA_Metselwerk-100mm licht grijs gekeimd:...) | Height (mm) | Length (mm) | GrossFootprintArea (m2) | NetVolume (m3) | NetSideArea (m2)
6942815 | 3245 | 1862.7 | 0.18627 | 604446707 | 6044467
6942816 | 3245 | 1948.01 | 0.194801 | 632127941 | 6321279
6942817 | 3245 | 1247.18 | 0.124718 | 404709402 | 4047094
6942821 | 3245 | 1687.96 | 0.168796 | 547743892 | 5477439
6942822 | 3245 | 1672.96 | 0.167296 | 542876392 | 5428764
6942823 | 3245 | 2139.35 | 0.213935 | 694218211 | 6942182
6942824 | 2180 | 210 | 0.021 | 45780000 | 457800
6942825 | 2180 | 210 | 0.021 | 45780000 | 457800
6942826 | 3245 | 4046 | 0.4046 | 1312927000 | 13129270
6942827 | 3245 | 3982 | 0.3982 | 1292159000 | 12921590
6942828 | 3245 | 4038 | 0.4038 | 1310331000 | 13103310
6942829 | 3245 | 1837.77 | 0.183777 | 596357028 | 5963570
6942830 | 3245 | 3448.86 | 0.344886 | 1119155776 | 11191558
6942831 | 3245 | 351.213 | 0.0350955 | 113968761 | 1139688
6942833 | 3245 | 2137.65 | 0.213765 | 693668289 | 6936683
6942834 | 3245 | 4984 | 0.4984 | 1617308000 | 16173080
6942835 | 3245 | 3801.04 | 0.380104 | 1233436608 | 12334366
6942870 | 3245 | 1673.4 | 0.16734 | 543017216 | 5430172
6942871 | 3245 | 1729.69 | 0.172969 | 561285921 | 5612859
6942889 | 3245 | 2915 | 0.2915 | 945917500 | 9459175
6943641 | 3315 | 1674 | 0.1674 | 554931000 | 5549310

# IfcWallStandardCase: Basic Wall:NLRS_20_WA_Metselwerk-100mm zwart (8)
In: 00 begane grond
Type - PredefinedType: STANDARD; Material: AL_metselwerk 210x100x50 halfsteens zwart 100 mm
Type - Pset_ConcreteElementGeneral - FireRating: -
Type - Pset_ElementShading - Roughness: 304.8 mm
Type - Pset_ProductRequirements - Category: Walls
Type - Pset_QuantityTakeOff - Reference: Basic Wall:NLRS_20_WA_Metselwerk-100mm zwart
Type - Pset_ReinforcementBarPitchOfWall - Reference: Basic Wall:NLRS_20_WA_Metselwerk-100mm zwart
Type - Pset_WallCommon - IsExternal: no; Reference: Basic Wall:NLRS_20_WA_Metselwerk-100mm zwart; FireRating: -
Classification: 21.11 buitenwanden; niet constructief, massieve wanden (Uniformat)
BaseQuantities - Width: 100 mm
Pset_QuantityTakeOff - sets with these values: 2
Pset_WallCommon - IsExternal: yes; ExtendToStructure: no; LoadBearing: no
Name (Basic Wall:NLRS_20_WA_Metselwerk-100mm zwart:...) | Height (mm) | Length (mm) | GrossFootprintArea (m2) | NetVolume (m3) | NetSideArea (m2)
3408447 | 3166 | 4509.33 | 0.450848 | 1427652775 | 14276528
3408740 | 3117 | 2370.63 | 0.236947 | 738926268 | 7389263
3409086 | 3117 | 311.186 | 0.0310021 | 96996806 | 969968
3409762 | 3117 | 3403.81 | 0.340374 | 1060967574 | 10609676
3410056 | 3117 | 3163.66 | 0.316334 | 986112795 | 9861128
3414375 | 2737 | 1705.52 | 0.170387 | 466800838 | 4668008
3530530 | 2841.5 | 926.325 | 0.0926325 | 263215190 | 2632152
3530768 | 2841.5 | 928.772 | 0.0928772 | 263910582 | 2639106

# IfcWallStandardCase: Basic Wall:NLRS_20_WA_Metselwerk-210mm (3)
In: 00 begane grond
Type - PredefinedType: STANDARD; Material: AL_metselwerk 210x100x50 halfsteens geel 210 mm
Type - Pset_ConcreteElementGeneral - FireRating: -
Type - Pset_ElementShading - Roughness: 304.8 mm
Type - Pset_ProductRequirements - Category: Walls
Type - Pset_QuantityTakeOff - Reference: Basic Wall:NLRS_20_WA_Metselwerk-210mm
Type - Pset_ReinforcementBarPitchOfWall - Reference: Basic Wall:NLRS_20_WA_Metselwerk-210mm
Type - Pset_WallCommon - IsExternal: no; Reference: Basic Wall:NLRS_20_WA_Metselwerk-210mm; FireRating: -
Classification: 21.10 buitenwanden; niet constructief, algemeen (verzamelniveau) (Uniformat)
BaseQuantities - Width: 210 mm
Pset_QuantityTakeOff - sets with these values: 2
Pset_WallCommon - IsExternal: yes; ExtendToStructure: no; LoadBearing: no
Name (Basic Wall:NLRS_20_WA_Metselwerk-210mm:...) | Height (mm) | Length (mm) | GrossFootprintArea (m2) | NetVolume (m3) | NetSideArea (m2)
2837201 | 2807 | 4980 | 1.0458 | 2935560600 | 13978860
3304717 | 2737 | 210 | 0.0441 | 120701807 | 574771
3304926 | 2737 | 202.755 | 0.0425786 | 116537645 | 554941

# IfcWallStandardCase: Basic Wall:NLRS_20_WA_Metselwerk-310mm, Basic Wall:NLRS_20_WA_Metselwerk-310mm:3366484
In: 00 begane grond
Type - PredefinedType: STANDARD; Material: AL_metselwerk 210x100x50 halfsteens geel 310 mm
Type - Pset_ConcreteElementGeneral - FireRating: -
Type - Pset_ElementShading - Roughness: 304.8 mm
Type - Pset_ProductRequirements - Category: Walls
Type - Pset_QuantityTakeOff - Reference: Basic Wall:NLRS_20_WA_Metselwerk-310mm
Type - Pset_ReinforcementBarPitchOfWall - Reference: Basic Wall:NLRS_20_WA_Metselwerk-310mm
Type - Pset_WallCommon - IsExternal: no; Reference: Basic Wall:NLRS_20_WA_Metselwerk-310mm; FireRating: -
Classification: 21.10 buitenwanden; niet constructief, algemeen (verzamelniveau) (Uniformat)
BaseQuantities - Height: 2737 mm; Length: 672.008 mm; Width: 310 mm; GrossFootprintArea: 0.208322 m2; NetVolume: 570178543 m3; NetSideArea: 1839286 m2
Pset_QuantityTakeOff - sets with these values: 2
Pset_WallCommon - IsExternal: yes; ExtendToStructure: no; LoadBearing: no

# IfcWallStandardCase: Basic Wall:NLRS_20_WA_Scheidingsnet, Basic Wall:NLRS_20_WA_Scheidingsnet:3311490
In: 00 begane grond
Type - PredefinedType: STANDARD; Material: Scheidingsnet 100 mm
Type - Pset_ConcreteElementGeneral - FireRating: -
Type - Pset_ElementShading - Roughness: 304.8 mm
Type - Pset_ProductRequirements - Category: Walls
Type - Pset_QuantityTakeOff - Reference: Basic Wall:NLRS_20_WA_Scheidingsnet
Type - Pset_ReinforcementBarPitchOfWall - Reference: Basic Wall:NLRS_20_WA_Scheidingsnet
Type - Pset_WallCommon - IsExternal: no; Reference: Basic Wall:NLRS_20_WA_Scheidingsnet; FireRating: -
Classification: 21.10 buitenwanden; niet constructief, algemeen (verzamelniveau) (Uniformat)
BaseQuantities - Height: 5727.97 mm; Length: 11944 mm; Width: 100 mm; GrossFootprintArea: 1.1944 m2; NetVolume: 6841481688 m3; NetSideArea: 68414817 m2
Pset_QuantityTakeOff - sets with these values: 2
Pset_WallCommon - IsExternal: yes; ExtendToStructure: no; LoadBearing: no

# IfcWallStandardCase: Basic Wall:NLRS_20_WA_ontwerpwand-200mm_gen_aly, Basic Wall:NLRS_20_WA_ontwerpwand-200mm_gen_aly:3304461
In: 00 begane grond
Type - PredefinedType: STANDARD; Material: ZZ_Default Wall 200 mm
Type - Pset_ConcreteElementGeneral - FireRating: -
Type - Pset_ElementShading - Roughness: 304.8 mm
Type - Pset_ProductRequirements - Category: Walls
Type - Pset_QuantityTakeOff - Reference: Basic Wall:NLRS_20_WA_ontwerpwand-200mm_gen_aly
Type - Pset_ReinforcementBarPitchOfWall - Reference: Basic Wall:NLRS_20_WA_ontwerpwand-200mm_gen_aly
Type - Pset_WallCommon - IsExternal: no; Reference: Basic Wall:NLRS_20_WA_ontwerpwand-200mm_gen_aly; FireRating: -
Classification: 21.10 buitenwanden; niet constructief, algemeen (verzamelniveau) (Uniformat)
BaseQuantities - Height: 2737 mm; Length: 430 mm; Width: 200 mm; GrossFootprintArea: 0.086 m2; NetVolume: 235382000 m3; NetSideArea: 1176910 m2
Pset_QuantityTakeOff - sets with these values: 2
Pset_WallCommon - IsExternal: yes; ExtendToStructure: no; LoadBearing: no

# IfcWallStandardCase: Basic Wall:NLRS_21_WA_Gipsplaat 12.5mm (31)
Type - PredefinedType: STANDARD; Material: NLRS_f7_gipsplaat_gen 12.5 mm
Type - Pset_ConcreteElementGeneral - FireRating: -
Type - Pset_ElementShading - Roughness: 304.8 mm
Type - Pset_ProductRequirements - Category: Walls
Type - Pset_QuantityTakeOff - Reference: Basic Wall:NLRS_21_WA_Gipsplaat 12.5mm
Type - Pset_ReinforcementBarPitchOfWall - Description: Hsb-wand Rc=2,8m²K/W; Reference: Basic Wall:NLRS_21_WA_Gipsplaat 12.5mm
Type - Pset_WallCommon - IsExternal: no; Reference: Basic Wall:NLRS_21_WA_Gipsplaat 12.5mm; FireRating: -
Classification: 21.23 buitenwanden; constructief, systeemwanden (Uniformat)
BaseQuantities - Width: 12.5 mm
Pset_WallCommon - ExtendToStructure: no; LoadBearing: no
Name (Basic Wall:NLRS_21_WA_Gipsplaat 12.5mm:...) | In | Height (mm) | Length (mm) | GrossFootprintArea (m2) | NetVolume (m3) | NetSideArea (m2)
7816632 | 00 begane grond | 2730 | 178.732 | 0.00223415 | 6099218 | 487937
8796620 | 00 begane grond | 2931 | 235 | 0.0029375 | 8609813 | 688785
8796805 | 00 begane grond | 2931 | 235 | 0.0029375 | 8609813 | 688785
8796881 | 00 begane grond | 2931 | 205 | 0.0025625 | 7510688 | 600855
8797110 | 00 begane grond | 3001 | 205 | 0.0025625 | 7690063 | 615205
8797258 | 00 begane grond | 2931 | 205 | 0.0025625 | 7510688 | 600855
8797396 | 00 begane grond | 2931 | 205 | 0.0025625 | 7510688 | 600855
8797470 | 00 begane grond | 2931 | 235 | 0.0029375 | 8609813 | 688785
8797569 | 00 begane grond | 2931 | 235 | 0.0029375 | 8609812 | 688785
8841539 | 01 eerste verdieping | 1457.97 | 12012.4 | 0.150155 | 218920812 | 17513665
8944800 | 00 begane grond | 2082 | 100 | 0.00125 | 2602500 | 208200
8944863 | 00 begane grond | 2054.95 | 103 | 0.0012875 | 2645752 | 211660
11269664 | 00 begane grond | 2677.08 | 77.8809 | 0.000973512 | 2606171 | 208494
11272399 | 00 begane grond | 374.098 | 1980 | 0.02475 | 9258930 | 740714
11327391 | Podium | 368.481 | 7552.44 | 0.0944055 | 34786659 | 2782933
11751603 | 00 begane grond | 2760 | 1744 | 0.0218 | 60168000 | 4813440
11751604 | 00 begane grond | 2760 | 1744 | 0.0218 | 60168000 | 4813440
11764387 | 00 begane grond | 2760 | 1744 | 0.0218 | 60168000 | 4813440
11764388 | 00 begane grond | 2760 | 1744 | 0.0218 | 60168000 | 4813440
11765220 | 00 begane grond | 2697 | 20 | 0.00025 | 674250 | 53940
11766304 | 00 begane grond | 2697 | 20.0028 | 0.000250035 | 674344 | 53947.5
11766481 | 00 begane grond | 2697 | 20 | 0.00025 | 674250 | 53940
11766569 | 00 begane grond | 2697 | 20 | 0.00025 | 674250 | 53940
12620799 | 00 begane grond | 2760 | 1744 | 0.0218 | 60168000 | 4813440
12620800 | 00 begane grond | 2760 | 1744 | 0.0218 | 60168000 | 4813440
12620801 | 00 begane grond | 2697 | 20 | 0.00025 | 674250 | 53940
12620802 | 00 begane grond | 2697 | 20 | 0.00025 | 674250 | 53940
12620837 | 00 begane grond | 2760 | 1744 | 0.0218 | 60168000 | 4813440
12620838 | 00 begane grond | 2760 | 1744 | 0.0218 | 60168000 | 4813440
12620839 | 00 begane grond | 2697 | 20 | 0.00025 | 674250 | 53940
12620840 | 00 begane grond | 2697 | 20 | 0.00025 | 674250 | 53940

# IfcWallStandardCase: Basic Wall:NLRS_21_WA_HSB werk 90mm, Basic Wall:NLRS_21_WA_HSB werk 90mm:4885828
In: 01 eerste verdieping
Type - PredefinedType: STANDARD; Material: AL_31_Naaldhout (vuren) 70 mm, NLRS_i4_hout_multiplex 10 mm, NLRS_f7_gipsplaten 12.5 mm
Type - Pset_ConcreteElementGeneral - FireRating: -
Type - Pset_ElementShading - Roughness: 304.8 mm
Type - Pset_ProductRequirements - Category: Walls
Type - Pset_QuantityTakeOff - Reference: Basic Wall:NLRS_21_WA_HSB werk 90mm
Type - Pset_ReinforcementBarPitchOfWall - Description: Hsb-wand Rc=2,8m²K/W; Reference: Basic Wall:NLRS_21_WA_HSB werk 90mm
Type - Pset_WallCommon - IsExternal: no; Reference: Basic Wall:NLRS_21_WA_HSB werk 90mm; FireRating: -
Classification: 21.23 buitenwanden; constructief, systeemwanden (Uniformat)
BaseQuantities - Height: 435.366 mm; Length: 12012.4 mm; Width: 92.5 mm; GrossFootprintArea: 1.11114 m2; NetVolume: 483754412 m3; NetSideArea: 5229777 m2
Pset_WallCommon - ExtendToStructure: no; LoadBearing: no

# IfcWallStandardCase: Basic Wall:NLRS_21_WA_HSB-wand boven podium, Basic Wall:NLRS_21_WA_HSB-wand boven podium:3398891
In: 01 eerste verdieping
Type - PredefinedType: STANDARD; Material: AL_Multiplex 10 mm, NLRS_m1_isolatie 89 mm, AL_Multiplex 10 mm
Type - Pset_ConcreteElementGeneral - FireRating: -
Type - Pset_ElementShading - Roughness: 304.8 mm
Type - Pset_ProductRequirements - Category: Walls
Type - Pset_QuantityTakeOff - Reference: Basic Wall:NLRS_21_WA_HSB-wand boven podium
Type - Pset_ReinforcementBarPitchOfWall - Description: Hsb-wand Rc=2,8m²K/W; Reference: Basic Wall:NLRS_21_WA_HSB-wand boven podium
Type - Pset_WallCommon - IsExternal: no; Reference: Basic Wall:NLRS_21_WA_HSB-wand boven podium; FireRating: -
Classification: 21.23 buitenwanden; constructief, systeemwanden (Uniformat)
BaseQuantities - Height: 3230 mm; Length: 10407.6 mm; Width: 109 mm; GrossFootprintArea: 1.13443 m2; NetVolume: 3664200876 m3; NetSideArea: 33616522 m2
Pset_WallCommon - ExtendToStructure: no; LoadBearing: no

# IfcWallStandardCase: Basic Wall:NLRS_21_WA_HSB-wand onder podium (14)
In: 00 begane grond
Type - PredefinedType: STANDARD; Material: NLRS_i4_hout_underlayment 12 mm, NLRS_m1_isolatie 89 mm, NLRS_i4_hout_underlayment 12 mm
Type - Pset_ConcreteElementGeneral - FireRating: -
Type - Pset_ElementShading - Roughness: 304.8 mm
Type - Pset_ProductRequirements - Category: Walls
Type - Pset_QuantityTakeOff - Reference: Basic Wall:NLRS_21_WA_HSB-wand onder podium
Type - Pset_ReinforcementBarPitchOfWall - Description: Hsb-wand Rc=2,8m²K/W; Reference: Basic Wall:NLRS_21_WA_HSB-wand onder podium
Type - Pset_WallCommon - IsExternal: no; Reference: Basic Wall:NLRS_21_WA_HSB-wand onder podium; FireRating: -
Classification: 21.23 buitenwanden; constructief, systeemwanden (Uniformat)
BaseQuantities - Height: 1082 mm; Width: 113 mm
Pset_WallCommon - ExtendToStructure: no; LoadBearing: no
Name (Basic Wall:NLRS_21_WA_HSB-wand onder podium:...) | Length (mm) | GrossFootprintArea (m2) | NetVolume (m3) | NetSideArea (m2)
3271944 | 910 | 0.10283 | 111262060 | 984620
4622401 | 12012.4 | 1.3574 | 1468704672 | 12997386
6046975 | 705.071 | 0.079673 | 86206211 | 762887
6047286 | 322.894 | 0.0334817 | 39478918 | 349371
6047365 | 3547.76 | 0.39936 | 433769895 | 3838672
6047668 | 713.067 | 0.0805765 | 87183827 | 771538
6047956 | 351.466 | 0.0382943 | 42972383 | 380287
6048139 | 834.5 | 0.0942985 | 102030977 | 902929
6048206 | 834.5 | 0.0942985 | 102030977 | 902929
9288396 | 1208.65 | 0.136578 | 147777107 | 1307762
9288773 | 806 | 0.091078 | 98546396 | 872092
9386472 | 1768 | 0.199784 | 216166288 | 1912976
11556387 | 9975.22 | 1.1272 | 1219630184 | 10793187
11556529 | 900 | 0.1017 | 110039400 | 973800

# IfcWallStandardCase: Basic Wall:NLRS_21_WA_HSB-wand onder podium 2 (4)
In: 00 begane grond
Type - PredefinedType: STANDARD; Material: NLRS_i4_hout_underlayment 2 9 mm, NLRS_m1_isolatie 89 mm, NLRS_i4_hout_underlayment 2 12 mm
Type - Pset_ConcreteElementGeneral - FireRating: -
Type - Pset_ElementShading - Roughness: 304.8 mm
Type - Pset_ProductRequirements - Category: Walls
Type - Pset_QuantityTakeOff - Reference: Basic Wall:NLRS_21_WA_HSB-wand onder podium 2
Type - Pset_ReinforcementBarPitchOfWall - Description: Hsb-wand Rc=2,8m²K/W; Reference: Basic Wall:NLRS_21_WA_HSB-wand onder podium 2
Type - Pset_WallCommon - IsExternal: no; Reference: Basic Wall:NLRS_21_WA_HSB-wand onder podium 2; FireRating: -
Classification: 21.23 buitenwanden; constructief, systeemwanden (Uniformat)
BaseQuantities - Height: 1082 mm; Width: 110 mm
Pset_WallCommon - ExtendToStructure: no; LoadBearing: no
Name (Basic Wall:NLRS_21_WA_HSB-wand onder podium 2:...) | Length (mm) | GrossFootprintArea (m2) | NetVolume (m3) | NetSideArea (m2)
4622349 | 8096.74 | 0.890641 | 963673777 | 8760671
6046721 | 329.01 | 0.0334322 | 39158720 | 355988
6047441 | 3561.46 | 0.390346 | 423884762 | 3853498
6048057 | 251.651 | 0.0263784 | 29951485 | 272286

# IfcWallStandardCase: Basic Wall:NLRS_21_WA_HSB-wand onderaansluiting sandwichpaneel, Basic Wall:NLRS_21_WA_HSB-wand onderaansluiting sandwichpaneel:7947747
In: 01 eerste verdieping
Type - PredefinedType: STANDARD; Material: NLRS_i4_hout_multiplex 10 mm, NLRS_m1_isolatie 235 mm, NLRS_i4_hout_multiplex 10 mm
Type - Pset_ConcreteElementGeneral - FireRating: -
Type - Pset_ElementShading - Roughness: 304.8 mm
Type - Pset_ProductRequirements - Category: Walls
Type - Pset_QuantityTakeOff - Reference: Basic Wall:NLRS_21_WA_HSB-wand onderaansluiting sandwichpaneel
Type - Pset_ReinforcementBarPitchOfWall - Description: Hsb-wand Rc=4,4m²K/W; Reference: Basic Wall:NLRS_21_WA_HSB-wand onderaansluiting sandwichpaneel
Type - Pset_WallCommon - IsExternal: no; Reference: Basic Wall:NLRS_21_WA_HSB-wand onderaansluiting sandwichpaneel; FireRating: -
Classification: 21.23 buitenwanden; constructief, systeemwanden (Uniformat)
BaseQuantities - Height: 662.282 mm; Length: 4528.93 mm; Width: 255 mm; GrossFootprintArea: 1.15488 m2; NetVolume: 764855559 m3; NetSideArea: 2999434 m2
Pset_WallCommon - ExtendToStructure: no; LoadBearing: no

# IfcWallStandardCase: Basic Wall:NLRS_21_WA_HSB-wand_101mm ongeisoleert (2)
In: 00 begane grond
Type - PredefinedType: STANDARD; Material: NLRS_m1_isolatie 89 mm, NLRS_f7_gipsplaat_gen 12.5 mm
Type - Pset_ConcreteElementGeneral - FireRating: -
Type - Pset_ElementShading - Roughness: 304.8 mm
Type - Pset_ProductRequirements - Category: Walls
Type - Pset_QuantityTakeOff - Reference: Basic Wall:NLRS_21_WA_HSB-wand_101mm ongeisoleert
Type - Pset_ReinforcementBarPitchOfWall - Description: Hsb-wand Rc=2,8m²K/W; Reference: Basic Wall:NLRS_21_WA_HSB-wand_101mm ongeisoleert
Type - Pset_WallCommon - IsExternal: no; Reference: Basic Wall:NLRS_21_WA_HSB-wand_101mm ongeisoleert; FireRating: -
Classification: 21.23 buitenwanden; constructief, systeemwanden (Uniformat)
BaseQuantities - Width: 101.5 mm
Pset_WallCommon - ExtendToStructure: no; LoadBearing: no
Name (Basic Wall:NLRS_21_WA_HSB-wand_101mm ongeisoleert:...) | Height (mm) | Length (mm) | GrossFootprintArea (m2) | NetVolume (m3) | NetSideArea (m2)
5713032 | 1470 | 7000 | 0.7105 | 1044435000 | 10290000
6017071 | 1082 | 5350 | 0.543025 | 587553050 | 5788700

# IfcWallStandardCase: Basic Wall:NLRS_21_WA_HSB-wand_102mm (2)
Type - PredefinedType: STANDARD; Material: NLRS_f7_gipsplaat_gen 12.5 mm, NLRS_m1_isolatie 89 mm
Type - Pset_ConcreteElementGeneral - FireRating: -
Type - Pset_ElementShading - Roughness: 304.8 mm
Type - Pset_ProductRequirements - Category: Walls
Type - Pset_QuantityTakeOff - Reference: Basic Wall:NLRS_21_WA_HSB-wand_102mm
Type - Pset_ReinforcementBarPitchOfWall - Description: Hsb-wand Rc=2,8m²K/W; Reference: Basic Wall:NLRS_21_WA_HSB-wand_102mm
Type - Pset_WallCommon - IsExternal: no; Reference: Basic Wall:NLRS_21_WA_HSB-wand_102mm; FireRating: -
Classification: 21.23 buitenwanden; constructief, systeemwanden (Uniformat)
BaseQuantities - Width: 101.5 mm
Pset_WallCommon - ExtendToStructure: no; LoadBearing: no
Name (Basic Wall:NLRS_21_WA_HSB-wand_102mm:...) | In | Height (mm) | Length (mm) | GrossFootprintArea (m2) | NetVolume (m3) | NetSideArea (m2)
7449066 | 00 begane grond | 2882 | 3441 | 0.349261 | 1006571643 | 9916962
7504125 | 01 eerste verdieping | 2238.3 | 1063.14 | 0.107908 | 241531907 | 2379625

# IfcWallStandardCase: Basic Wall:NLRS_21_WA_HSB-wand_110mm (74)
Type - PredefinedType: STANDARD; Material: NLRS_i4_hout_multiplex 9 mm, NLRS_m1_isolatie 89 mm, NLRS_i4_hout_multiplex 9 mm
Type - Pset_ConcreteElementGeneral - FireRating: -
Type - Pset_ElementShading - Roughness: 304.8 mm
Type - Pset_ProductRequirements - Category: Walls
Type - Pset_QuantityTakeOff - Reference: Basic Wall:NLRS_21_WA_HSB-wand_110mm
Type - Pset_ReinforcementBarPitchOfWall - Description: Hsb-wand Rc=2,8m²K/W; Reference: Basic Wall:NLRS_21_WA_HSB-wand_110mm
Type - Pset_WallCommon - IsExternal: no; Reference: Basic Wall:NLRS_21_WA_HSB-wand_110mm; FireRating: -
Classification: 21.23 buitenwanden; constructief, systeemwanden (Uniformat)
BaseQuantities - Width: 107 mm
Pset_WallCommon - ExtendToStructure: no; LoadBearing: no
Name (Basic Wall:NLRS_21_WA_HSB-wand_110mm:...) | In | Height (mm) | Length (mm) | GrossFootprintArea (m2) | NetVolume (m3) | NetSideArea (m2)
2891238 | 01 eerste verdieping | 2714 | 632.099 | 0.0676346 | 183560310 | 1715517
2891669 | 01 eerste verdieping | 2714 | 632.099 | 0.0676346 | 183560310 | 1715517
2892911 | 01 eerste verdieping | 345.359 | 9815.08 | 1.05021 | 362700652 | 3389726
3324069 | 01 eerste verdieping | 220 | 1717.63 | 0.183186 | 40432991 | 377878
3324235 | 01 eerste verdieping | 220 | 1730.93 | 0.18495 | 40746094 | 380805
3324326 | 01 eerste verdieping | 220 | 1733 | 0.184911 | 40794869 | 381260
3324376 | 01 eerste verdieping | 220 | 1733.07 | 0.184918 | 40796382 | 381275
3324966 | 01 eerste verdieping | 220 | 1725.11 | 0.184053 | 40609167 | 379525
3325021 | 01 eerste verdieping | 220 | 1718.39 | 0.183362 | 40450878 | 378046
3325070 | 01 eerste verdieping | 220 | 1714.46 | 0.182988 | 40358326 | 377181
3325127 | 01 eerste verdieping | 234.3 | 1123.4 | 0.119998 | 28163864 | 263214
3331827 | 00 begane grond | 181 | 1012.51 | 0.108339 | 19609318 | 183265
3396195 | 01 eerste verdieping | 2453.98 | 3884 | 0.415588 | 1019845508 | 9531266
3396602 | 01 eerste verdieping | 2482.97 | 3828 | 0.409596 | 1017012632 | 9504791
3396647 | 01 eerste verdieping | 2454.31 | 3892 | 0.416444 | 1022082046 | 9552169
3397181 | 01 eerste verdieping | 2633.53 | 3660 | 0.39162 | 1031341428 | 9638705
3397391 | 01 eerste verdieping | 2633.53 | 3645 | 0.390015 | 1027114619 | 9599202
3397489 | 01 eerste verdieping | 2533.53 | 1595.5 | 0.170719 | 432519748 | 4042241
3397604 | 01 eerste verdieping | 2355.15 | 3885 | 0.415695 | 979023746 | 9149755
3398180 | 01 eerste verdieping | 1682.53 | 1596.4 | 0.170814 | 287399730 | 2685979
3398418 | 01 eerste verdieping | 1682.53 | 3646 | 0.390122 | 656390384 | 6134490
3398466 | 01 eerste verdieping | 2637.53 | 4848 | 0.518736 | 1368179655 | 12786726
3398714 | 01 eerste verdieping | 2637.53 | 4830 | 0.51681 | 1363099780 | 12739250
3398765 | 01 eerste verdieping | 2637.53 | 3647.04 | 0.390233 | 1029249639 | 9619156
3398792 | 01 eerste verdieping | 2537.53 | 1610.96 | 0.172373 | 437400977 | 4087860
5699033 | 00 begane grond | 81 | 2976.89 | 0.318528 | 25800730 | 241128
5699204 | 00 begane grond | 156 | 3795.57 | 0.406126 | 63355691 | 592109
5709172 | 00 begane grond | 231 | 2920 | 0.31244 | 72173640 | 674520
5735404 | 01 eerste verdieping | 220 | 1714.46 | 0.182988 | 40358326 | 377181
5735495 | 01 eerste verdieping | 220 | 1720.37 | 0.183573 | 40497424 | 378481
5735598 | 01 eerste verdieping | 220 | 1723.31 | 0.18386 | 40566792 | 379129
5735709 | 01 eerste verdieping | 220 | 1848.03 | 0.197212 | 43502590 | 406566
5735792 | 01 eerste verdieping | 220 | 1819.83 | 0.194215 | 42838712 | 400362
5735888 | 01 eerste verdieping | 220 | 1735.51 | 0.185179 | 40853823 | 381811
5735982 | 01 eerste verdieping | 220 | 1733.07 | 0.184918 | 40796382 | 381275
5736067 | 01 eerste verdieping | 220 | 1733.07 | 0.184919 | 40796476 | 381275
5736175 | 01 eerste verdieping | 220 | 1835.36 | 0.195864 | 43204391 | 403779
5736575 | 01 eerste verdieping | 220 | 1716.76 | 0.183433 | 40412456 | 377687
5736665 | 01 eerste verdieping | 220 | 1735.51 | 0.185179 | 40853823 | 381811
5736721 | 01 eerste verdieping | 220 | 1733.07 | 0.184918 | 40796382 | 381275
5736775 | 01 eerste verdieping | 220 | 1733.07 | 0.184919 | 40796476 | 381275
5736836 | 01 eerste verdieping | 220 | 1835.36 | 0.195864 | 43204391 | 403779
5736928 | 01 eerste verdieping | 220 | 1981.54 | 0.211725 | 46645446 | 435939
5737051 | 01 eerste verdieping | 220 | 1980.7 | 0.211635 | 46625786 | 435755
5737441 | 01 eerste verdieping | 220 | 1733.07 | 0.184919 | 40796476 | 381275
5737923 | 01 eerste verdieping | 220 | 1848.2 | 0.197229 | 43506599 | 406604
5737972 | 01 eerste verdieping | 220 | 1819.83 | 0.194215 | 42838712 | 400362
5738020 | 01 eerste verdieping | 220 | 1735.51 | 0.185179 | 40853823 | 381811
5738066 | 01 eerste verdieping | 220 | 1733.07 | 0.184918 | 40796382 | 381275
5738116 | 01 eerste verdieping | 220 | 1733.07 | 0.184919 | 40796476 | 381275
5738167 | 01 eerste verdieping | 220 | 1835.36 | 0.195864 | 43204391 | 403779
5738231 | 01 eerste verdieping | 220 | 1835.36 | 0.195864 | 43204391 | 403779
5885274 | 00 begane grond | 269.701 | 1980 | 0.21186 | 57138756 | 534007
5953032 | 01 eerste verdieping | 2533.53 | 1610.96 | 0.172373 | 436711485 | 4081416
5963877 | 01 eerste verdieping | 2355.2 | 3884 | 0.415588 | 978792000 | 9147589
5968555 | 01 eerste verdieping | 1570 | 2450.74 | 0.262229 | 411699169 | 3847656
5968872 | 01 eerste verdieping | 1570 | 3646 | 0.390122 | 612491540 | 5724220
5968881 | 01 eerste verdieping | 855 | 1596.4 | 0.170814 | 146046348 | 1364919
6017076 | 00 begane grond | 1082 | 3806.5 | 0.407295 | 440693731 | 4118633
6068666 | 01 eerste verdieping | 985.814 | 839.166 | 0.0897907 | 88516925 | 827261
6068695 | 01 eerste verdieping | 985.814 | 839.166 | 0.0897907 | 88516925 | 827261
6363928 | Podium | 349 | 9444.52 | 1.01056 | 352686859 | 3296139
6400496 | 01 eerste verdieping | 735.222 | 4856 | 0.519592 | 382015587 | 3570239
6400764 | 01 eerste verdieping | 735.222 | 4812 | 0.514884 | 378554161 | 3537889
8082190 | 02 tweede verdieping | 455 | 12580 | 1.34606 | 612457300 | 5723900
9317163 | 01 eerste verdieping | 2707.65 | 7506.3 | 0.803174 | 2174718378 | 20324471
9571837 | 00 begane grond | 231 | 1330 | 0.14231 | 32873610 | 307230
11307192 | 00 begane grond | 593.168 | 1034.18 | 0.110657 | 65638007 | 613439
11560524 | 00 begane grond | 1082 | 3378.38 | 0.361487 | 391128738 | 3655409
11560601 | 00 begane grond | 1082 | 3378.38 | 0.361487 | 391128738 | 3655409
11560610 | 00 begane grond | 1082 | 3378.38 | 0.361487 | 391128738 | 3655409
11846751 | 00 begane grond | 1082 | 3806.5 | 0.407295 | 440693731 | 4118633
12781466 | 00 begane grond | 2931 | 1271.01 | 0.135282 | 398610634 | 3725333
12781557 | 00 begane grond | 2931 | 1263.47 | 0.134475 | 396244913 | 3703223

# IfcWallStandardCase: Basic Wall:NLRS_21_WA_HSB-wand_110mm ongeisoleerd (3)
In: 00 begane grond
Type - PredefinedType: STANDARD; Material: NLRS_i4_hout_multiplex 9 mm, AL_31_Naaldhout (vuren) 89 mm, NLRS_i4_hout_multiplex 9 mm
Type - Pset_ConcreteElementGeneral - FireRating: -
Type - Pset_ElementShading - Roughness: 304.8 mm
Type - Pset_ProductRequirements - Category: Walls
Type - Pset_QuantityTakeOff - Reference: Basic Wall:NLRS_21_WA_HSB-wand_110mm ongeisoleerd
Type - Pset_ReinforcementBarPitchOfWall - Description: Hsb-wand Rc=2,8m²K/W; Reference: Basic Wall:NLRS_21_WA_HSB-wand_110mm ongeisoleerd
Type - Pset_WallCommon - IsExternal: no; Reference: Basic Wall:NLRS_21_WA_HSB-wand_110mm ongeisoleerd; FireRating: -
Classification: 21.23 buitenwanden; constructief, systeemwanden (Uniformat)
BaseQuantities - Height: 1400 mm; Width: 107 mm
Pset_WallCommon - ExtendToStructure: no; LoadBearing: no
Name (Basic Wall:NLRS_21_WA_HSB-wand_110mm ongeisoleerd:...) | Length (mm) | GrossFootprintArea (m2) | NetVolume (m3) | NetSideArea (m2)
6051366 | 1007.45 | 0.107797 | 150916389 | 1410434
6051716 | 7093 | 0.758951 | 1062531400 | 9930200
6051775 | 900.453 | 0.0963484 | 134887789 | 1260634

# IfcWallStandardCase: Basic Wall:NLRS_21_WA_HSB-wand_114mm (35)
Type - PredefinedType: STANDARD; Material: NLRS_f7_gipsplaat_gen 12.5 mm, NLRS_m1_isolatie 89 mm, NLRS_f7_gipsplaat_gen 12.5 mm
Type - Pset_ConcreteElementGeneral - FireRating: -
Type - Pset_ElementShading - Roughness: 304.8 mm
Type - Pset_ProductRequirements - Category: Walls
Type - Pset_QuantityTakeOff - Reference: Basic Wall:NLRS_21_WA_HSB-wand_114mm
Type - Pset_ReinforcementBarPitchOfWall - Description: Hsb-wand Rc=2,8m²K/W; Reference: Basic Wall:NLRS_21_WA_HSB-wand_114mm
Type - Pset_WallCommon - IsExternal: no; Reference: Basic Wall:NLRS_21_WA_HSB-wand_114mm; FireRating: -
Classification: 21.23 buitenwanden; constructief, systeemwanden (Uniformat)
BaseQuantities - Width: 114 mm
Pset_WallCommon - ExtendToStructure: no; LoadBearing: no
Name (Basic Wall:NLRS_21_WA_HSB-wand_114mm:...) | In | Height (mm) | Length (mm) | GrossFootprintArea (m2) | NetVolume (m3) | NetSideArea (m2)
3061582 | 01 eerste verdieping | 2613.04 | 1156.5 | 0.131841 | 344506207 | 3021984
3066474 | 01 eerste verdieping | 2770.36 | 2246.14 | 0.25606 | 709378664 | 6222620
3320291 | 01 eerste verdieping | 1722.17 | 10385.2 | 1.18391 | 2038898030 | 17885070
3456225 | 01 eerste verdieping | 3057.25 | 1369.64 | 0.156139 | 477354376 | 4187319
3648170 | 01 eerste verdieping | 273.562 | 1980 | 0.22572 | 61748476 | 541653
5260380 | 00 begane grond | 231 | 2735 | 0.31179 | 72023490 | 631785
5260414 | 00 begane grond | 231 | 3543.5 | 0.403959 | 93314529 | 818549
5646211 | 00 begane grond | 2882 | 3555 | 0.40527 | 1167988140 | 10245510
5698885 | 00 begane grond | 156 | 1890 | 0.21546 | 33611760 | 294840
5699081 | 00 begane grond | 137 | 1720.01 | 0.196081 | 26863123 | 235641
5700558 | 00 begane grond | 439 | 1691 | 0.192774 | 84627786 | 742349
5701357 | 00 begane grond | 156 | 3984.83 | 0.45427 | 70866161 | 621633
5755753 | 00 begane grond | 2877 | 2516.5 | 0.286881 | 825356637 | 7239971
5778654 | 00 begane grond | 2890.26 | 1274.91 | 0.145339 | 420069147 | 3684817
5818165 | 01 eerste verdieping | 2059.28 | 2235.5 | 0.254847 | 524801711 | 4603524
5859409 | 00 begane grond | 3140 | 2219 | 0.252966 | 794313240 | 6967660
5900205 | 00 begane grond | 212 | 1662 | 0.189468 | 40167216 | 352344
5963638 | 01 eerste verdieping | 2835 | 12012.4 | 1.36941 | 3882277442 | 34055065
5973540 | 00 begane grond | 452 | 1825 | 0.20235 | 94038600 | 824900
5973614 | 00 begane grond | 452 | 3255 | 0.37107 | 167723640 | 1471260
5986114 | 00 begane grond | 231 | 2001.03 | 0.228118 | 52695144 | 462238
6029508 | 00 begane grond | 161 | 3350 | 0.3819 | 61485900 | 539350
6029645 | 00 begane grond | 161 | 3350 | 0.3819 | 61485900 | 539350
6156943 | 00 begane grond | 156 | 1887.01 | 0.215119 | 33558593 | 294374
6191247 | 00 begane grond | 156 | 1786.13 | 0.203618 | 31764479 | 278636
6294416 | Podium | 370 | 1747.51 | 0.199216 | 73709796 | 646577
6440975 | 01 eerste verdieping | 352 | 3500 | 0.399 | 140448000 | 1232000
6440976 | 01 eerste verdieping | 352 | 3500 | 0.399 | 140448000 | 1232000
6514039 | 00 begane grond | 2982 | 485 | 0.05529 | 164874780 | 1446270
6592328 | 00 begane grond | 3152 | 225.162 | 0.0256685 | 80906961 | 709710
6990327 | 00 begane grond | 2951 | 236.5 | 0.026961 | 79561911 | 697911
7515228 | 00 begane grond | 231 | 3215.08 | 0.365077 | 84665953 | 742684
8936495 | 00 begane grond | 2845.9 | 1240 | 0.14136 | 402296144 | 3528914
9575438 | 00 begane grond | 131 | 1991 | 0.226974 | 29733594 | 260821
9575595 | 00 begane grond | 122 | 2920 | 0.33288 | 40611360 | 356240

# IfcWallStandardCase: Basic Wall:NLRS_21_WA_HSB-wand_120mm, Basic Wall:NLRS_21_WA_HSB-wand_120mm:8422757
In: 00 begane grond
Type - PredefinedType: STANDARD; Material: NLRS_f7_gipsplaat_gen 12.5 mm, NLRS_m1_isolatie 89 mm, AL_Multiplex 18 mm
Type - Pset_ConcreteElementGeneral - FireRating: -
Type - Pset_ElementShading - Roughness: 304.8 mm
Type - Pset_ProductRequirements - Category: Walls
Type - Pset_QuantityTakeOff - Reference: Basic Wall:NLRS_21_WA_HSB-wand_120mm
Type - Pset_ReinforcementBarPitchOfWall - Description: Hsb-wand Rc=2,8m²K/W; Reference: Basic Wall:NLRS_21_WA_HSB-wand_120mm
Type - Pset_WallCommon - IsExternal: no; Reference: Basic Wall:NLRS_21_WA_HSB-wand_120mm; FireRating: -
Classification: 21.23 buitenwanden; constructief, systeemwanden (Uniformat)
BaseQuantities - Height: 751 mm; Length: 3984.18 mm; Width: 119.5 mm; GrossFootprintArea: 0.47611 m2; NetVolume: 357558421 m3; NetSideArea: 2992121 m2
Pset_WallCommon - ExtendToStructure: no; LoadBearing: no

# IfcWallStandardCase: Basic Wall:NLRS_21_WA_HSB-wand_123mm (conform opgaaf constructeur) (3)
In: 00 begane grond
Type - PredefinedType: STANDARD; Material: NLRS_f7_gipsplaat_gen 12.5 mm, NLRS_i4_hout_underlayment 9 mm, NLRS_m1_isolatie 89 mm, NLRS_f7_gipsplaat_gen 12.5 mm
Type - Pset_ConcreteElementGeneral - FireRating: -
Type - Pset_ElementShading - Roughness: 304.8 mm
Type - Pset_ProductRequirements - Category: Walls
Type - Pset_QuantityTakeOff - Reference: Basic Wall:NLRS_21_WA_HSB-wand_123mm (conform opgaaf constructeur)
Type - Pset_ReinforcementBarPitchOfWall - Description: Hsb-wand Rc=2,8m²K/W; Reference: Basic Wall:NLRS_21_WA_HSB-wand_123mm (conform opgaaf constructeur)
Type - Pset_WallCommon - IsExternal: no; Reference: Basic Wall:NLRS_21_WA_HSB-wand_123mm (conform opgaaf constructeur); FireRating: -
Classification: 21.23 buitenwanden; constructief, systeemwanden (Uniformat)
BaseQuantities - Width: 123 mm
Pset_WallCommon - ExtendToStructure: no; LoadBearing: no
Name (Basic Wall:NLRS_21_WA_HSB-wand_123mm (conform opgaaf constructeur):...) | Height (mm) | Length (mm) | GrossFootprintArea (m2) | NetVolume (m3) | NetSideArea (m2)
2997817 | 3240 | 453.306 | 0.0557566 | 180651420 | 1468711
5632281 | 2926 | 4738.22 | 0.582802 | 1705277603 | 13864046
5636550 | 2926 | 4226.14 | 0.519816 | 1520980436 | 12365695

# IfcWallStandardCase: Basic Wall:NLRS_21_WA_HSB-wand_149 (conform opgaaf constructeur) (5)
In: 01 eerste verdieping
Type - PredefinedType: STANDARD; Material: NLRS_i4_hout_underlayment 9 mm, NLRS_m1_isolatie 140 mm
Type - Pset_ConcreteElementGeneral - FireRating: -
Type - Pset_ElementShading - Roughness: 304.8 mm
Type - Pset_ProductRequirements - Category: Walls
Type - Pset_QuantityTakeOff - Reference: Basic Wall:NLRS_21_WA_HSB-wand_149 (conform opgaaf constructeur)
Type - Pset_ReinforcementBarPitchOfWall - Description: Hsb-wand Rc=2,8m²K/W; Reference: Basic Wall:NLRS_21_WA_HSB-wand_149 (conform opgaaf constructeur)
Type - Pset_WallCommon - IsExternal: no; Reference: Basic Wall:NLRS_21_WA_HSB-wand_149 (conform opgaaf constructeur); FireRating: -
Classification: 21.23 buitenwanden; constructief, systeemwanden (Uniformat)
BaseQuantities - Width: 149 mm
Pset_WallCommon - ExtendToStructure: no; LoadBearing: no
Name (Basic Wall:NLRS_21_WA_HSB-wand_149 (conform opgaaf constructeur):...) | Height (mm) | Length (mm) | GrossFootprintArea (m2) | NetVolume (m3) | NetSideArea (m2)
3275035 | 453.208 | 7191.41 | 1.07152 | 485621520 | 3259205
3844575 | 339.043 | 15250 | 2.27225 | 770390937 | 5170409
6634306 | 3000.72 | 9235.27 | 1.37605 | 4129154231 | 27712445
8374064 | 339 | 713.373 | 0.106293 | 36033158 | 241833
8374508 | 339 | 730 | 0.10877 | 36873030 | 247470

# IfcWallStandardCase: Basic Wall:NLRS_21_WA_HSB-wand_160mm zonder iso, Basic Wall:NLRS_21_WA_HSB-wand_160mm zonder iso:12230423
In: 00 begane grond
Type - PredefinedType: STANDARD; Material: NLRS_i4_hout_multiplex 10 mm, NLRS_j9_lucht_gen 140 mm, NLRS_i4_hout_multiplex 10 mm
Type - Pset_ConcreteElementGeneral - FireRating: -
Type - Pset_ElementShading - Roughness: 304.8 mm
Type - Pset_ProductRequirements - Category: Walls
Type - Pset_QuantityTakeOff - Reference: Basic Wall:NLRS_21_WA_HSB-wand_160mm zonder iso
Type - Pset_ReinforcementBarPitchOfWall - Description: Hsb-wand Rc=4,4m²K/W; Reference: Basic Wall:NLRS_21_WA_HSB-wand_160mm zonder iso
Type - Pset_WallCommon - IsExternal: no; Reference: Basic Wall:NLRS_21_WA_HSB-wand_160mm zonder iso; FireRating: -
Classification: 21.23 buitenwanden; constructief, systeemwanden (Uniformat)
BaseQuantities - Height: 140 mm; Length: 7652.25 mm; Width: 160 mm; GrossFootprintArea: 1.22436 m2; NetVolume: 171410400 m3; NetSideArea: 1071315 m2
Pset_WallCommon - ExtendToStructure: no; LoadBearing: no

# IfcWallStandardCase: Basic Wall:NLRS_21_WA_HSB-wand_174mm (conform opgaaf constructeur), Basic Wall:NLRS_21_WA_HSB-wand_174mm (conform opgaaf constructeur):2971908
In: 00 begane grond
Type - PredefinedType: STANDARD; Material: NLRS_f7_gipsplaat_gen 12.5 mm, NLRS_i4_hout_underlayment 9 mm, NLRS_m1_isolatie 140 mm, NLRS_f7_gipsplaat_gen 12.5 mm
Type - Pset_ConcreteElementGeneral - FireRating: -
Type - Pset_ElementShading - Roughness: 304.8 mm
Type - Pset_ProductRequirements - Category: Walls
Type - Pset_QuantityTakeOff - Reference: Basic Wall:NLRS_21_WA_HSB-wand_174mm (conform opgaaf constructeur)
Type - Pset_ReinforcementBarPitchOfWall - Description: Hsb-wand Rc=2,8m²K/W; Reference: Basic Wall:NLRS_21_WA_HSB-wand_174mm (conform opgaaf constructeur)
Type - Pset_WallCommon - IsExternal: no; Reference: Basic Wall:NLRS_21_WA_HSB-wand_174mm (conform opgaaf constructeur); FireRating: -
Classification: 21.23 buitenwanden; constructief, systeemwanden (Uniformat)
BaseQuantities - Height: 2926 mm; Length: 4499.14 mm; Width: 174 mm; GrossFootprintArea: 0.782851 m2; NetVolume: 2290621713 m3; NetSideArea: 13164493 m2
Pset_WallCommon - ExtendToStructure: no; LoadBearing: no

# IfcWallStandardCase: Basic Wall:NLRS_21_WA_HSB-wand_217mm, Basic Wall:NLRS_21_WA_HSB-wand_217mm:6567780
In: 01 eerste verdieping
Type - PredefinedType: STANDARD; Material: NLRS_i4_hout_multiplex 10 mm, NLRS_m1_isolatie 184 mm, NLRS_i4_hout_multiplex 10 mm, NLRS_f7_gipsplaten 12.5 mm
Type - Pset_ConcreteElementGeneral - FireRating: -
Type - Pset_ElementShading - Roughness: 304.8 mm
Type - Pset_ProductRequirements - Category: Walls
Type - Pset_QuantityTakeOff - Reference: Basic Wall:NLRS_21_WA_HSB-wand_217mm
Type - Pset_ReinforcementBarPitchOfWall - Description: Hsb-wand Rc=4,4m²K/W; Reference: Basic Wall:NLRS_21_WA_HSB-wand_217mm
Type - Pset_WallCommon - IsExternal: no; Reference: Basic Wall:NLRS_21_WA_HSB-wand_217mm; FireRating: -
Classification: 21.23 buitenwanden; constructief, systeemwanden (Uniformat)
BaseQuantities - Height: 2534.43 mm; Length: 454.028 mm; Width: 216.5 mm; GrossFootprintArea: 0.0982971 m2; NetVolume: 249127393 m3; NetSideArea: 1150704 m2
Pset_WallCommon - ExtendToStructure: no; LoadBearing: no

# IfcWallStandardCase: Basic Wall:NLRS_21_WA_HSB-wand_217mm ongeisoleerd, Basic Wall:NLRS_21_WA_HSB-wand_217mm ongeisoleerd:4565776
In: 01 eerste verdieping
Type - PredefinedType: STANDARD; Material: NLRS_i4_hout_multiplex 10 mm, AL_31_Naaldhout (vuren) 184 mm, NLRS_i4_hout_multiplex 10 mm, NLRS_f7_gipsplaten 12.5 mm
Type - Pset_ConcreteElementGeneral - FireRating: -
Type - Pset_ElementShading - Roughness: 304.8 mm
Type - Pset_ProductRequirements - Category: Walls
Type - Pset_QuantityTakeOff - Reference: Basic Wall:NLRS_21_WA_HSB-wand_217mm ongeisoleerd
Type - Pset_ReinforcementBarPitchOfWall - Description: Hsb-wand Rc=4,4m²K/W; Reference: Basic Wall:NLRS_21_WA_HSB-wand_217mm ongeisoleerd
Type - Pset_WallCommon - IsExternal: no; Reference: Basic Wall:NLRS_21_WA_HSB-wand_217mm ongeisoleerd; FireRating: -
Classification: 21.23 buitenwanden; constructief, systeemwanden (Uniformat)
BaseQuantities - Height: 1458.02 mm; Length: 12012.4 mm; Width: 216.5 mm; GrossFootprintArea: 2.60068 m2; NetVolume: 3791833813 m3; NetSideArea: 17514244 m2
Pset_WallCommon - ExtendToStructure: no; LoadBearing: no

# IfcWallStandardCase: Basic Wall:NLRS_21_WA_HSB-wand_268mm (12)
In: 01 eerste verdieping
Type - PredefinedType: STANDARD; Material: NLRS_i4_hout_multiplex 10 mm, NLRS_m1_isolatie 235 mm, NLRS_i4_hout_multiplex 10 mm, NLRS_f7_gipsplaat_gen 12.5 mm
Type - Pset_ConcreteElementGeneral - FireRating: -
Type - Pset_ElementShading - Roughness: 304.8 mm
Type - Pset_ProductRequirements - Category: Walls
Type - Pset_QuantityTakeOff - Reference: Basic Wall:NLRS_21_WA_HSB-wand_268mm
Type - Pset_ReinforcementBarPitchOfWall - Description: Hsb-wand Rc=4,4m²K/W; Reference: Basic Wall:NLRS_21_WA_HSB-wand_268mm
Type - Pset_WallCommon - IsExternal: no; Reference: Basic Wall:NLRS_21_WA_HSB-wand_268mm; FireRating: -
Classification: 21.23 buitenwanden; constructief, systeemwanden (Uniformat)
BaseQuantities - Width: 267.5 mm
Pset_WallCommon - ExtendToStructure: no; LoadBearing: no
Name (Basic Wall:NLRS_21_WA_HSB-wand_268mm:...) | Height (mm) | Length (mm) | GrossFootprintArea (m2) | NetVolume (m3) | NetSideArea (m2)
3274311 | 1060 | 8198.55 | 2.19311 | 2324699868 | 8690467
5329484 | 2945 | 1425.85 | 0.381415 | 1123265801 | 4199124
5475590 | 1060 | 941.037 | 0.251727 | 266831073 | 997499
5675717 | 2945 | 1974.19 | 0.528097 | 1555244107 | 5813997
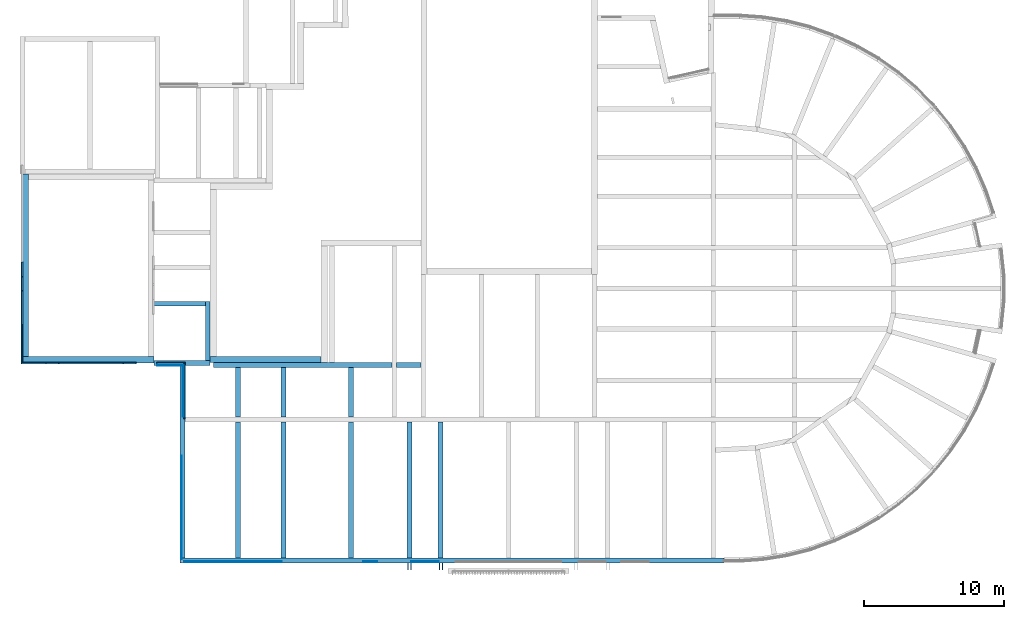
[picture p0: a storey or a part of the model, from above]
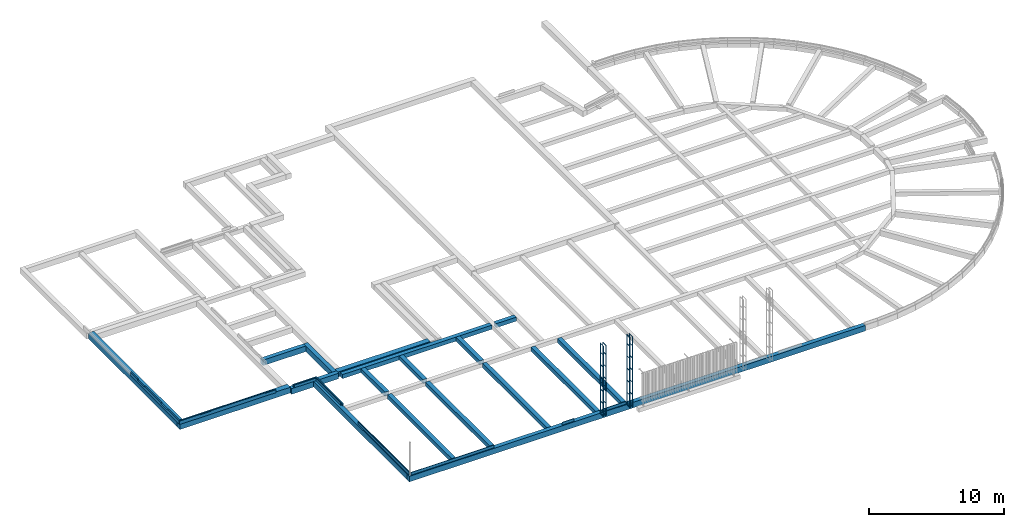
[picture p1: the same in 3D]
Properties of the parts of a building model (IFC2X3), part 11 of 13

# IfcWallStandardCase: Basic Wall:NLRS_21_WA_HSB-wand_268mm (12)
Name (Basic Wall:NLRS_21_WA_HSB-wand_268mm:...) | Height (mm) | Length (mm) | GrossFootprintArea (m2) | NetVolume (m3) | NetSideArea (m2)
5677773 | 2945 | 1425.95 | 0.381443 | 1123347836 | 4199431
5677948 | 2945 | 1974.33 | 0.528135 | 1555353820 | 5814407
5885887 | 3085.18 | 4748.54 | 1.27023 | 3918895104 | 14650075
5886679 | 3088.36 | 4752.5 | 1.27129 | 3926214317 | 14677437
5886974 | 3088.29 | 4752.59 | 1.27132 | 3926196575 | 14677370
5892327 | 3088.29 | 4752.59 | 1.27132 | 3926196575 | 14677370
6536547 | 1060 | 3926.69 | 1.05039 | 1113412804 | 4162291
6536808 | 1060 | 3347.64 | 0.895495 | 949224736 | 3548504

# IfcWallStandardCase: Basic Wall:NLRS_21_WA_HSB-wand_268mm (zonder gips) (22)
In: 01 eerste verdieping
Type - PredefinedType: STANDARD; Material: NLRS_i4_hout_multiplex 10 mm, NLRS_m1_isolatie 235 mm, NLRS_i4_hout_multiplex 10 mm
Type - Pset_ConcreteElementGeneral - FireRating: -
Type - Pset_ElementShading - Roughness: 304.8 mm
Type - Pset_ProductRequirements - Category: Walls
Type - Pset_QuantityTakeOff - Reference: Basic Wall:NLRS_21_WA_HSB-wand_268mm (zonder gips)
Type - Pset_ReinforcementBarPitchOfWall - Description: Hsb-wand Rc=4,4m²K/W; Reference: Basic Wall:NLRS_21_WA_HSB-wand_268mm (zonder gips)
Type - Pset_WallCommon - IsExternal: no; Reference: Basic Wall:NLRS_21_WA_HSB-wand_268mm (zonder gips); FireRating: -
Classification: 21.23 buitenwanden; constructief, systeemwanden (Uniformat)
BaseQuantities - Width: 255 mm
Pset_WallCommon - ExtendToStructure: no; LoadBearing: no
Name (Basic Wall:NLRS_21_WA_HSB-wand_268mm (zonder gips):...) | Height (mm) | Length (mm) | GrossFootprintArea (m2) | NetVolume (m3) | NetSideArea (m2)
3677517 | 3093.3 | 3682.82 | 0.939119 | 2904975538 | 11392061
5674594 | 1709.2 | 3926.75 | 1.00132 | 1711459825 | 6711607
5674813 | 1655 | 3347.64 | 0.853649 | 1412789875 | 5540352
5675889 | 2945 | 1972.68 | 0.503035 | 1481435539 | 5809551
5676042 | 2999 | 1971.75 | 0.502798 | 1507888912 | 5913290
5676191 | 2945 | 1973.65 | 0.503282 | 1482164539 | 5812410
5676343 | 3013.07 | 1974.1 | 0.503397 | 1516769040 | 5948114
5676514 | 2945 | 1021.25 | 0.260419 | 766933762 | 3007583
5677193 | 2945 | 1266.75 | 0.323021 | 951297809 | 3730580
5677322 | 2945 | 1265.19 | 0.322623 | 950125790 | 3725983
5678102 | 2945 | 1972.75 | 0.503051 | 1481484155 | 5809742
5678263 | 2945 | 1975.53 | 0.503761 | 1483572731 | 5817932
5678292 | 2945 | 1974.28 | 0.503443 | 1482638039 | 5814267
5678336 | 2945 | 1971.87 | 0.502827 | 1480823439 | 5807151
5678351 | 2945 | 1020.14 | 0.260136 | 766101030 | 3004318
5741522 | 3045 | 4007.5 | 1.02191 | 3111723562 | 12202838
5741788 | 3093.3 | 4712.15 | 1.2016 | 3716904964 | 14576098
5741943 | 3093.3 | 3106.18 | 0.792077 | 2450131857 | 9608360
8269525 | 1845 | 564.376 | 0.143916 | 265524673 | 1041273
9638986 | 2760 | 4050 | 1.03275 | 2850390387 | 11178002
9639067 | 2760 | 3133.87 | 0.799138 | 2205619962 | 8649490
11083462 | 2760 | 1778.72 | 0.453573 | 1251861176 | 4909260

# IfcWallStandardCase: Basic Wall:NLRS_21_WA_HSB-wand_78mm (4)
In: 02 tweede verdieping
Type - PredefinedType: STANDARD; Material: NLRS_i4_hout_multiplex 10 mm, NLRS_m1_isolatie 58 mm, NLRS_i4_hout_multiplex 10 mm
Type - Pset_ConcreteElementGeneral - FireRating: -
Type - Pset_ElementShading - Roughness: 304.8 mm
Type - Pset_ProductRequirements - Category: Walls
Type - Pset_QuantityTakeOff - Reference: Basic Wall:NLRS_21_WA_HSB-wand_78mm
Type - Pset_ReinforcementBarPitchOfWall - Description: Hsb-wand Rc=2,8m²K/W; Reference: Basic Wall:NLRS_21_WA_HSB-wand_78mm
Type - Pset_WallCommon - IsExternal: no; Reference: Basic Wall:NLRS_21_WA_HSB-wand_78mm; FireRating: -
Classification: 21.23 buitenwanden; constructief, systeemwanden (Uniformat)
BaseQuantities - Width: 78 mm
Pset_WallCommon - ExtendToStructure: no; LoadBearing: no
Name (Basic Wall:NLRS_21_WA_HSB-wand_78mm:...) | Height (mm) | Length (mm) | GrossFootprintArea (m2) | NetVolume (m3) | NetSideArea (m2)
7913874 | 400.8 | 8295 | 0.64701 | 259321608 | 3324636
8082299 | 406.7 | 18910 | 1.47498 | 599874366 | 7690697
9374245 | 594.123 | 10099.8 | 0.787784 | 468040306 | 6000517
9374675 | 148.418 | 14078.5 | 1.09813 | 162981317 | 2089504

# IfcWallStandardCase: Basic Wall:NLRS_21_WA_HSB-wand_98mm (18)
Type - PredefinedType: STANDARD; Material: NLRS_m1_isolatie 89 mm, NLRS_i4_hout_multiplex 9 mm
Type - Pset_ConcreteElementGeneral - FireRating: -
Type - Pset_ElementShading - Roughness: 304.8 mm
Type - Pset_ProductRequirements - Category: Walls
Type - Pset_QuantityTakeOff - Reference: Basic Wall:NLRS_21_WA_HSB-wand_98mm
Type - Pset_ReinforcementBarPitchOfWall - Description: Hsb-wand Rc=2,8m²K/W; Reference: Basic Wall:NLRS_21_WA_HSB-wand_98mm
Type - Pset_WallCommon - IsExternal: no; Reference: Basic Wall:NLRS_21_WA_HSB-wand_98mm; FireRating: -
Classification: 21.23 buitenwanden; constructief, systeemwanden (Uniformat)
BaseQuantities - Width: 98 mm
Pset_WallCommon - ExtendToStructure: no; LoadBearing: no
Name (Basic Wall:NLRS_21_WA_HSB-wand_98mm:...) | In | Height (mm) | Length (mm) | GrossFootprintArea (m2) | NetVolume (m3) | NetSideArea (m2)
3250677 | 01 eerste verdieping | 469.1 | 12033.2 | 1.17926 | 553189249 | 5644788
3254027 | 01 eerste verdieping | 397.1 | 3700.23 | 0.361556 | 143997422 | 1469361
3254151 | 01 eerste verdieping | 369.1 | 3171.83 | 0.30974 | 114730774 | 1170722
4236074 | 01 eerste verdieping | 469.1 | 4038.77 | 0.395799 | 185669415 | 1894586
4448829 | 01 eerste verdieping | 469.1 | 6427 | 0.629846 | 295460759 | 3014906
4618100 | 01 eerste verdieping | 369.1 | 3400.51 | 0.333218 | 123002726 | 1255130
6622358 | 01 eerste verdieping | 2999.69 | 9238.57 | 0.90538 | 2715859298 | 27712850
6622737 | 01 eerste verdieping | 2999.95 | 9239.38 | 0.905459 | 2716335407 | 27717708
6622786 | 01 eerste verdieping | 2999.89 | 9239.19 | 0.90544 | 2716223118 | 27716562
7792746 | 00 begane grond | 2852 | 231.5 | 0.022687 | 64703324 | 660238
8151511 | 00 begane grond | 2926 | 152.842 | 0.0149785 | 43827106 | 447215
8195426 | 00 begane grond | 2856 | 95.25 | 0.0093345 | 26659332 | 272034
8195499 | 00 begane grond | 2822 | 96.4344 | 0.00945057 | 26669513 | 272138
9436062 | 01 eerste verdieping | 469.1 | 3934.2 | 0.385551 | 180862079 | 1845531
10196961 | 01 eerste verdieping | 469.1 | 6354 | 0.622692 | 292104817 | 2980661
11323590 | 00 begane grond | 283.51 | 7552.44 | 0.740139 | 209836555 | 2141189
11356294 | 00 begane grond | 322 | 1330.34 | 0.130373 | 41980166 | 428369
11359887 | 00 begane grond | 231 | 2600 | 0.2548 | 58858800 | 600600

# IfcWallStandardCase: Basic Wall:NLRS_21_WA_HSB-zijwand erker (2)
In: 00 begane grond
Type - PredefinedType: STANDARD; Material: NLRS_m1_isolatie 184 mm, NLRS_i4_hout_multiplex 9 mm
Type - Pset_ConcreteElementGeneral - FireRating: -
Type - Pset_ElementShading - Roughness: 304.8 mm
Type - Pset_ProductRequirements - Category: Walls
Type - Pset_QuantityTakeOff - Reference: Basic Wall:NLRS_21_WA_HSB-zijwand erker
Type - Pset_ReinforcementBarPitchOfWall - Description: Hsb-wand Rc=2,8m²K/W; Reference: Basic Wall:NLRS_21_WA_HSB-zijwand erker
Type - Pset_WallCommon - IsExternal: no; Reference: Basic Wall:NLRS_21_WA_HSB-zijwand erker; FireRating: -
Classification: 21.23 buitenwanden; constructief, systeemwanden (Uniformat)
BaseQuantities - Height: 1208 mm; Width: 193 mm
Pset_WallCommon - ExtendToStructure: no; LoadBearing: no
Name (Basic Wall:NLRS_21_WA_HSB-zijwand erker:...) | Length (mm) | GrossFootprintArea (m2) | NetVolume (m3) | NetSideArea (m2)
6304131 | 679 | 0.131047 | 158304776 | 820232
6304509 | 706 | 0.136258 | 164599664 | 852848

# IfcWallStandardCase: Basic Wall:NLRS_21_WA_Metalstud 100mm (108)
Type - PredefinedType: STANDARD; Material: NLRS_f7_gipsplaat_gen 12.5 mm, NLRS_m1_isolatie 75 mm, NLRS_f7_gipsplaat_gen 12.5 mm
Type - Pset_ConcreteElementGeneral - FireRating: -
Type - Pset_ElementShading - Roughness: 304.8 mm
Type - Pset_ProductRequirements - Category: Walls
Type - Pset_QuantityTakeOff - Reference: Basic Wall:NLRS_21_WA_Metalstud 100mm
Type - Pset_ReinforcementBarPitchOfWall - Description: Hsb-wand Rc=2,8m²K/W; Reference: Basic Wall:NLRS_21_WA_Metalstud 100mm
Type - Pset_WallCommon - IsExternal: no; Reference: Basic Wall:NLRS_21_WA_Metalstud 100mm; FireRating: -
Classification: 21.23 buitenwanden; constructief, systeemwanden (Uniformat)
BaseQuantities - Width: 100 mm
Pset_WallCommon - ExtendToStructure: no; LoadBearing: no
Name (Basic Wall:NLRS_21_WA_Metalstud 100mm:...) | In | Height (mm) | Length (mm) | GrossFootprintArea (m2) | NetVolume (m3) | NetSideArea (m2)
2969631 | 00 begane grond | 2926 | 4874.09 | 0.487409 | 1426157461 | 14261575
2970832 | 00 begane grond | 2926 | 1007.87 | 0.100787 | 294902382 | 2949024
2971807 | 00 begane grond | 2926 | 4733 | 0.4733 | 1384875800 | 13848758
2980122 | 00 begane grond | 2901 | 1791 | 0.1791 | 519569100 | 5195691
2980367 | 00 begane grond | 2979 | 514 | 0.0514 | 153120600 | 1531206
2989586 | 00 begane grond | 2901 | 3390 | 0.339 | 983439000 | 9834390
2990075 | 00 begane grond | 2901 | 3390 | 0.339 | 983439000 | 9834390
2991146 | 00 begane grond | 2901 | 3555 | 0.3555 | 1031305500 | 10313055
2991150 | 00 begane grond | 2901 | 3390 | 0.339 | 983439000 | 9834390
2991235 | 00 begane grond | 4942.51 | 6285.61 | 0.628561 | 3106669326 | 31066693
2991729 | 00 begane grond | 3122 | 3088.69 | 0.308869 | 964288839 | 9642888
2992060 | 00 begane grond | 2901 | 1680 | 0.168 | 487368000 | 4873680
2995243 | 00 begane grond | 2951 | 4480.38 | 0.448038 | 1322161014 | 13221610
2996920 | 00 begane grond | 3001 | 888.469 | 0.0888469 | 266629579 | 2666296
2998373 | 00 begane grond | 3725.75 | 907.994 | 0.0907994 | 338295840 | 3382958
2998459 | 00 begane grond | 4336.3 | 867.25 | 0.086725 | 376066054 | 3760661
2998999 | 00 begane grond | 3001 | 907.994 | 0.0907994 | 272488896 | 2724889
3000354 | 00 begane grond | 3082 | 1209.17 | 0.120917 | 372666988 | 3726670
3000409 | 00 begane grond | 3001 | 4893.9 | 0.48939 | 1468658836 | 14686588
3002822 | 00 begane grond | 3001 | 3500.29 | 0.350029 | 1050436603 | 10504366
3003277 | 00 begane grond | 3001 | 3773.42 | 0.376232 | 1132402278 | 11324023
3003344 | 00 begane grond | 3001 | 2973.73 | 0.296262 | 892415049 | 8924150
3005591 | 00 begane grond | 3001 | 2553.68 | 0.255368 | 766359576 | 7663596
3012707 | 00 begane grond | 3001 | 2614.55 | 0.258973 | 784625764 | 7846258
3062275 | 01 eerste verdieping | 3166.17 | 3522.9 | 0.35229 | 1115407849 | 11154078
3067136 | 01 eerste verdieping | 3148.17 | 4041.5 | 0.40415 | 1272331954 | 12723320
3067399 | 01 eerste verdieping | 2595.8 | 2341.5 | 0.23415 | 607807544 | 6078075
3067491 | 01 eerste verdieping | 2595.8 | 2341.5 | 0.23415 | 607807544 | 6078075
3077262 | 01 eerste verdieping | 3201.47 | 9837.43 | 0.983743 | 3149419990 | 31494200
3078042 | 00 begane grond | 2977 | 3269.64 | 0.326964 | 973371796 | 9733718
3078199 | 00 begane grond | 4109.95 | 3104.64 | 0.310464 | 1275991635 | 12759916
3080521 | 00 begane grond | 3001 | 550 | 0.055 | 165055000 | 1650550
3080601 | 00 begane grond | 3001 | 3355.16 | 0.335516 | 1006884074 | 10068841
3082943 | 01 eerste verdieping | 2040.43 | 794.219 | 0.0794219 | 162054712 | 1620547
3083577 | 01 eerste verdieping | 1508.42 | 3437.66 | 0.343766 | 518543008 | 5185430
3646183 | 01 eerste verdieping | 2003.51 | 518.604 | 0.0518604 | 103902854 | 1039029
3648882 | 01 eerste verdieping | 1186.56 | 3651.86 | 0.365186 | 433316306 | 4333163
3672428 | 00 begane grond | 2977 | 2057.56 | 0.205756 | 612536499 | 6125365
4284177 | 00 begane grond | 2952 | 7000 | 0.7 | 2066400000 | 20664000
4284925 | 00 begane grond | 2622 | 658 | 0.0658 | 172527600 | 1725276
4286560 | 00 begane grond | 4422 | 2250 | 0.225 | 994950000 | 9949500
4315867 | 00 begane grond | 2951 | 4920 | 0.492 | 1451892000 | 14518920
4315869 | 00 begane grond | 2951 | 4436 | 0.4436 | 1309063600 | 13090636
4315870 | 00 begane grond | 2951 | 3302 | 0.3302 | 974420200 | 9744202
4547293 | 00 begane grond | 2926 | 4212.13 | 0.421213 | 1232468300 | 12324683
5482652 | 00 begane grond | 1406.88 | 849.5 | 0.08495 | 119514031 | 1195140
5603887 | 00 begane grond | 2982 | 3184.51 | 0.318451 | 949620763 | 9496208
5605097 | 00 begane grond | 2951 | 3930 | 0.393 | 1159743000 | 11597430
5605277 | 00 begane grond | 2951 | 4789.69 | 0.478969 | 1413438946 | 14134389
5619059 | 00 begane grond | 3222 | 3070.39 | 0.307039 | 989280212 | 9892802
5626761 | 00 begane grond | 4748.41 | 5573 | 0.5573 | 2646286829 | 26462868
5633811 | 00 begane grond | 2926 | 1230.16 | 0.123016 | 359945105 | 3599451
5635943 | 00 begane grond | 2877 | 1230.16 | 0.123016 | 353917316 | 3539173
5636638 | 00 begane grond | 2877 | 1237.16 | 0.123716 | 355931216 | 3559312
5642295 | 00 begane grond | 2901 | 1357 | 0.1357 | 393665700 | 3936657
5642385 | 00 begane grond | 2901 | 1357 | 0.1357 | 393665700 | 3936657
5644343 | 00 begane grond | 2901 | 1357 | 0.1357 | 393665700 | 3936657
5644439 | 00 begane grond | 2901 | 1357 | 0.1357 | 393665700 | 3936657
5666736 | 00 begane grond | 3001 | 3481.49 | 0.277505 | 1044793735 | 10447937
5672866 | 00 begane grond | 3001 | 2076.42 | 0.207642 | 623134426 | 6231344
5715135 | 00 begane grond | 3001 | 963.789 | 0.0963789 | 289232953 | 2892330
5715252 | 00 begane grond | 3001 | 1810.34 | 0.181034 | 543282915 | 5432829
5762138 | 00 begane grond | 2931 | 2518.94 | 0.251894 | 738300034 | 7383000
5762150 | 00 begane grond | 2931 | 2518.94 | 0.251894 | 738300034 | 7383000
5764710 | 00 begane grond | 2951 | 3754.38 | 0.375438 | 1107918611 | 11079186
5765120 | 00 begane grond | 2951 | 4621.32 | 0.462132 | 1363751895 | 13637519
5765692 | 00 begane grond | 4422 | 3008 | 0.3008 | 1330137600 | 13301376
5766116 | 00 begane grond | 4422 | 3008 | 0.3008 | 1330137600 | 13301376
5855143 | 00 begane grond | 3051 | 1718.34 | 0.171834 | 524265413 | 5242654
5855333 | 01 eerste verdieping | 2159.67 | 1716.8 | 0.171146 | 370771940 | 3707719
5891459 | 01 eerste verdieping | 1887.63 | 5809.54 | 0.580954 | 1096628888 | 10966289
5892837 | 01 eerste verdieping | 2054 | 1015.85 | 0.101585 | 208655447 | 2086554
5895433 | 00 begane grond | 3001 | 1099.92 | 0.109992 | 330085161 | 3300852
5895752 | 01 eerste verdieping | 1337.53 | 1750 | 0.175 | 234068349 | 2340683
5904193 | 00 begane grond | 2951 | 4920 | 0.492 | 1451892000 | 14518920
5904197 | 00 begane grond | 2951 | 2840 | 0.284 | 838084000 | 8380840
5928267 | 01 eerste verdieping | 2990.48 | 1089.26 | 0.108926 | 325740401 | 3257404
5941090 | 01 eerste verdieping | 2749.3 | 1064 | 0.1064 | 292525257 | 2925253
6042908 | 00 begane grond | 2877 | 414 | 0.0414 | 119107800 | 1191078
6515476 | 00 begane grond | 1605 | 850 | 0.085 | 136425000 | 1364250
7798160 | 00 begane grond | 2926 | 115 | 0.0115 | 33649000 | 336490
7798636 | 01 eerste verdieping | 2839.65 | 1738.47 | 0.173847 | 493665119 | 4936651
7828640 | 00 begane grond | 2807 | 1308.82 | 0.130882 | 367386902 | 3673869
8156363 | 00 begane grond | 3001 | 1388.68 | 0.138868 | 416743076 | 4167431
8996790 | 00 begane grond | 412 | 1680 | 0.168 | 69216000 | 692160
9002261 | 00 begane grond | 3001 | 2560.07 | 0.256007 | 768277187 | 7682772
9411969 | 00 begane grond | 3240 | 1618.34 | 0.161834 | 524342032 | 5243420
9534640 | 00 begane grond | 181 | 1862 | 0.1862 | 33702200 | 337022
9573203 | 00 begane grond | 312 | 1850 | 0.185 | 57720000 | 577200
10057221 | 00 begane grond | 4422 | 2250 | 0.225 | 994950000 | 9949500
10062329 | 00 begane grond | 3001 | 3380 | 0.338 | 1014338000 | 10143380
10064300 | 00 begane grond | 2807 | 1600 | 0.16 | 449120000 | 4491200
10064322 | 00 begane grond | 2807 | 1600 | 0.16 | 449120000 | 4491200
10064644 | 00 begane grond | 2807 | 500 | 0.05 | 140350000 | 1403500
10064662 | 00 begane grond | 2807 | 1100 | 0.11 | 308770000 | 3087700
10065413 | 00 begane grond | 2807 | 2208.35 | 0.220835 | 619884694 | 6198847
10242454 | 00 begane grond | 4093.56 | 800 | 0.08 | 327484982 | 3274850
10271512 | 00 begane grond | 3001 | 492.5 | 0.04925 | 147799250 | 1477993
11021005 | 01 eerste verdieping | 281 | 3925.05 | 0.391623 | 110293775 | 1102938
11040295 | 01 eerste verdieping | 281 | 5135.94 | 0.511285 | 144319957 | 1443200
11040431 | 01 eerste verdieping | 231 | 5158.85 | 0.513576 | 119169425 | 1191694
11040498 | 01 eerste verdieping | 231 | 5300.12 | 0.517365 | 122432704 | 1224327
11040524 | 01 eerste verdieping | 231 | 5135.91 | 0.511282 | 118639407 | 1186394
11040867 | 01 eerste verdieping | 231 | 3927.42 | 0.390781 | 90723423 | 907234
11265033 | Podium | 1000 | 707.5 | 0.07075 | 70750000 | 707500
11265228 | Podium | 1000 | 707.5 | 0.07075 | 70750000 | 707500
11737139 | 00 begane grond | 3001 | 3727.28 | 0.373538 | 1118556389 | 11185564
11737249 | 00 begane grond | 3001 | 3727.28 | 0.373538 | 1118556389 | 11185564

# IfcWallStandardCase: Basic Wall:NLRS_21_WA_Metalstud 100mm (achter sierbekleding) (7)
Type - PredefinedType: STANDARD; Material: NLRS_i4_hout_multiplex zwart 15 mm, NLRS_m1_isolatie 75 mm, NLRS_f7_gipsplaat_gen 12.5 mm
Type - Pset_ConcreteElementGeneral - FireRating: -
Type - Pset_ElementShading - Roughness: 304.8 mm
Type - Pset_ProductRequirements - Category: Walls
Type - Pset_QuantityTakeOff - Reference: Basic Wall:NLRS_21_WA_Metalstud 100mm (achter sierbekleding)
Type - Pset_ReinforcementBarPitchOfWall - Description: Hsb-wand Rc=2,8m²K/W; Reference: Basic Wall:NLRS_21_WA_Metalstud 100mm (achter sierbekleding)
Type - Pset_WallCommon - IsExternal: no; Reference: Basic Wall:NLRS_21_WA_Metalstud 100mm (achter sierbekleding); FireRating: -
Classification: 21.23 buitenwanden; constructief, systeemwanden (Uniformat)
BaseQuantities - Width: 102.5 mm
Pset_WallCommon - ExtendToStructure: no; LoadBearing: no
Name (Basic Wall:NLRS_21_WA_Metalstud 100mm (achter sierbekleding):...) | In | Height (mm) | Length (mm) | GrossFootprintArea (m2) | NetVolume (m3) | NetSideArea (m2)
3061201 | 01 eerste verdieping | 2278 | 3803.85 | 0.389895 | 888179956 | 8665170
5805913 | 01 eerste verdieping | 2393.89 | 3034.13 | 0.310999 | 744498313 | 7263398
5818638 | 01 eerste verdieping | 2191.05 | 4142.9 | 0.424648 | 930422437 | 9077292
7857113 | 01 eerste verdieping | 777.901 | 2394.34 | 0.24542 | 190912687 | 1862563
9576281 | 00 begane grond | 102 | 6279.11 | 0.643608 | 65648065 | 640469
10004450 | 01 eerste verdieping | 102 | 3683.5 | 0.377559 | 38510992 | 375717
10004602 | 01 eerste verdieping | 102 | 3098.93 | 0.317641 | 32399359 | 316091

# IfcWallStandardCase: Basic Wall:NLRS_21_WA_Metalstud 100mm 2 (2)
In: 00 begane grond
Type - PredefinedType: STANDARD; Material: Materiaal voor filmpje 12.5 mm, NLRS_m1_isolatie 75 mm, Materiaal voor filmpje 12.5 mm
Type - Pset_ConcreteElementGeneral - FireRating: -
Type - Pset_ElementShading - Roughness: 304.8 mm
Type - Pset_ProductRequirements - Category: Walls
Type - Pset_QuantityTakeOff - Reference: Basic Wall:NLRS_21_WA_Metalstud 100mm 2
Type - Pset_ReinforcementBarPitchOfWall - Description: Hsb-wand Rc=2,8m²K/W; Reference: Basic Wall:NLRS_21_WA_Metalstud 100mm 2
Type - Pset_WallCommon - IsExternal: no; Reference: Basic Wall:NLRS_21_WA_Metalstud 100mm 2; FireRating: -
Classification: 21.23 buitenwanden; constructief, systeemwanden (Uniformat)
BaseQuantities - Width: 100 mm
Pset_WallCommon - ExtendToStructure: no; LoadBearing: no
Name (Basic Wall:NLRS_21_WA_Metalstud 100mm 2:...) | Height (mm) | Length (mm) | GrossFootprintArea (m2) | NetVolume (m3) | NetSideArea (m2)
7790468 | 2907 | 13178.7 | 1.31787 | 3831046588 | 38310466
7790875 | 2926 | 181.696 | 0.0181696 | 53164261 | 531643

# IfcWallStandardCase: Basic Wall:NLRS_21_WA_Metalstud 110mm (rand staalconstructie) (3)
In: 01 eerste verdieping
Type - PredefinedType: STANDARD; Material: NLRS_f7_gipsplaat_gen 12.5 mm, NLRS_i4_hout_underlayment 10 mm, NLRS_m1_isolatie 75 mm, NLRS_f7_gipsplaat_gen 12.5 mm
Type - Pset_ConcreteElementGeneral - FireRating: -
Type - Pset_ElementShading - Roughness: 304.8 mm
Type - Pset_ProductRequirements - Category: Walls
Type - Pset_QuantityTakeOff - Reference: Basic Wall:NLRS_21_WA_Metalstud 110mm (rand staalconstructie)
Type - Pset_ReinforcementBarPitchOfWall - Description: Hsb-wand Rc=2,8m²K/W; Reference: Basic Wall:NLRS_21_WA_Metalstud 110mm (rand staalconstructie)
Type - Pset_WallCommon - IsExternal: no; Reference: Basic Wall:NLRS_21_WA_Metalstud 110mm (rand staalconstructie); FireRating: -
Classification: 21.23 buitenwanden; constructief, systeemwanden (Uniformat)
BaseQuantities - Width: 110 mm
Pset_WallCommon - ExtendToStructure: no; LoadBearing: no
Name (Basic Wall:NLRS_21_WA_Metalstud 110mm (rand staalconstructie):...) | Height (mm) | Length (mm) | GrossFootprintArea (m2) | NetVolume (m3) | NetSideArea (m2)
3062215 | 1864.25 | 618.604 | 0.0680465 | 126855664 | 1153233
3073311 | 1663.27 | 5119.47 | 0.563142 | 936657926 | 8515072
3649830 | 1529.66 | 4004.17 | 0.440459 | 673750509 | 6125005

# IfcWallStandardCase: Basic Wall:NLRS_21_WA_Metalstud 150mm (2)
In: 00 begane grond
Type - PredefinedType: STANDARD; Material: NLRS_f7_gipsplaat_gen 12.5 mm, NLRS_m1_isolatie 125 mm, NLRS_f7_gipsplaat_gen 12.5 mm
Type - Pset_ConcreteElementGeneral - FireRating: -
Type - Pset_ElementShading - Roughness: 304.8 mm
Type - Pset_ProductRequirements - Category: Walls
Type - Pset_QuantityTakeOff - Reference: Basic Wall:NLRS_21_WA_Metalstud 150mm
Type - Pset_ReinforcementBarPitchOfWall - Description: Hsb-wand Rc=2,8m²K/W; Reference: Basic Wall:NLRS_21_WA_Metalstud 150mm
Type - Pset_WallCommon - IsExternal: no; Reference: Basic Wall:NLRS_21_WA_Metalstud 150mm; FireRating: -
Classification: 21.23 buitenwanden; constructief, systeemwanden (Uniformat)
BaseQuantities - Width: 150 mm
Pset_WallCommon - ExtendToStructure: no; LoadBearing: no
Name (Basic Wall:NLRS_21_WA_Metalstud 150mm:...) | Height (mm) | Length (mm) | GrossFootprintArea (m2) | NetVolume (m3) | NetSideArea (m2)
5633532 | 2926 | 4730.55 | 0.709582 | 2076237733 | 13841585
10686603 | 3001 | 2140.24 | 0.321037 | 963431120 | 6422874

# IfcWallStandardCase: Basic Wall:NLRS_21_WA_Metalstud 165 (5)
In: 00 begane grond
Type - PredefinedType: STANDARD; Material: NLRS_f7_gipsplaat_gen 12.5 mm, NLRS_m1_isolatie 50 mm, NLRS_j9_lucht_gen 40 mm, NLRS_m1_isolatie 50 mm, NLRS_f7_gipsplaat_gen 12.5 mm
Type - Pset_ConcreteElementGeneral - FireRating: -
Type - Pset_ElementShading - Roughness: 304.8 mm
Type - Pset_ProductRequirements - Category: Walls
Type - Pset_QuantityTakeOff - Reference: Basic Wall:NLRS_21_WA_Metalstud 165
Type - Pset_ReinforcementBarPitchOfWall - Description: Hsb-wand Rc=2,8m²K/W; Reference: Basic Wall:NLRS_21_WA_Metalstud 165
Type - Pset_WallCommon - IsExternal: no; Reference: Basic Wall:NLRS_21_WA_Metalstud 165; FireRating: -
Classification: 21.23 buitenwanden; constructief, systeemwanden (Uniformat)
BaseQuantities - Width: 165 mm
Pset_WallCommon - ExtendToStructure: no; LoadBearing: no
Name (Basic Wall:NLRS_21_WA_Metalstud 165:...) | Height (mm) | Length (mm) | GrossFootprintArea (m2) | NetVolume (m3) | NetSideArea (m2)
2991190 | 3967.85 | 5818 | 0.95997 | 3809020100 | 23084970
5859411 | 2901 | 941.849 | 0.155405 | 450829965 | 2732303
7968948 | 2882 | 2964 | 0.48906 | 1409470920 | 8542248
7969953 | 2892 | 5397 | 0.890505 | 2575340460 | 15608124
8648470 | 2901 | 6866.15 | 1.13291 | 3286586355 | 19918705

# IfcWallStandardCase: Basic Wall:NLRS_21_WA_Metalstud 200mm (gang school) (2)
In: 00 begane grond
Type - PredefinedType: STANDARD; Material: NLRS_f7_gipsplaten 12.5 mm, AL_Multiplex 10 mm, NLRS_m1_isolatie 45 mm, NLRS_j9_lucht_gen 35 mm, NLRS_m1_isolatie 75 mm, AL_Multiplex 10 mm, NLRS_f7_gipsplaten 12.5 mm
Type - Pset_ConcreteElementGeneral - FireRating: -
Type - Pset_ElementShading - Roughness: 304.8 mm
Type - Pset_ProductRequirements - Category: Walls
Type - Pset_QuantityTakeOff - Reference: Basic Wall:NLRS_21_WA_Metalstud 200mm (gang school)
Type - Pset_ReinforcementBarPitchOfWall - Description: Hsb-wand Rc=2,8m²K/W; Reference: Basic Wall:NLRS_21_WA_Metalstud 200mm (gang school)
Type - Pset_WallCommon - IsExternal: no; Reference: Basic Wall:NLRS_21_WA_Metalstud 200mm (gang school); FireRating: -
Classification: 21.23 buitenwanden; constructief, systeemwanden (Uniformat)
BaseQuantities - Width: 200 mm
Pset_WallCommon - ExtendToStructure: no; LoadBearing: no
Name (Basic Wall:NLRS_21_WA_Metalstud 200mm (gang school):...) | Height (mm) | Length (mm) | GrossFootprintArea (m2) | NetVolume (m3) | NetSideArea (m2)
7750672 | 5530.06 | 6232.04 | 1.24641 | 6892711126 | 34463556
7751134 | 5523.87 | 6264.04 | 1.25281 | 6920347924 | 34601740

# IfcWallStandardCase: Basic Wall:NLRS_21_WA_Metalstud 205mm (2)
In: 00 begane grond
Type - PredefinedType: STANDARD; Material: NLRS_f7_gipsplaten 12.5 mm, AL_Multiplex 10 mm, NLRS_m1_isolatie 50 mm, NLRS_j9_lucht_gen 35 mm, NLRS_m1_isolatie 75 mm, AL_Multiplex 10 mm, NLRS_f7_gipsplaten 12.5 mm
Type - Pset_ConcreteElementGeneral - FireRating: -
Type - Pset_ElementShading - Roughness: 304.8 mm
Type - Pset_ProductRequirements - Category: Walls
Type - Pset_QuantityTakeOff - Reference: Basic Wall:NLRS_21_WA_Metalstud 205mm
Type - Pset_ReinforcementBarPitchOfWall - Description: Hsb-wand Rc=2,8m²K/W; Reference: Basic Wall:NLRS_21_WA_Metalstud 205mm
Type - Pset_WallCommon - IsExternal: no; Reference: Basic Wall:NLRS_21_WA_Metalstud 205mm; FireRating: -
Classification: 21.23 buitenwanden; constructief, systeemwanden (Uniformat)
BaseQuantities - Width: 205 mm
Pset_WallCommon - ExtendToStructure: no; LoadBearing: no
Name (Basic Wall:NLRS_21_WA_Metalstud 205mm:...) | Height (mm) | Length (mm) | GrossFootprintArea (m2) | NetVolume (m3) | NetSideArea (m2)
4309669 | 5529.46 | 6236.84 | 1.27855 | 7069707987 | 34486380
7755072 | 5493.97 | 6283.95 | 1.28821 | 7077387869 | 34523843

# IfcWallStandardCase: Basic Wall:NLRS_21_WA_Metalstud 215 (6)
In: 00 begane grond
Type - PredefinedType: STANDARD; Material: NLRS_f7_gipsplaat_gen 12.5 mm, NLRS_m1_isolatie 75 mm, NLRS_j9_lucht_gen 40 mm, NLRS_m1_isolatie 75 mm, NLRS_f7_gipsplaat_gen 12.5 mm
Type - Pset_ConcreteElementGeneral - FireRating: -
Type - Pset_ElementShading - Roughness: 304.8 mm
Type - Pset_ProductRequirements - Category: Walls
Type - Pset_QuantityTakeOff - Reference: Basic Wall:NLRS_21_WA_Metalstud 215
Type - Pset_ReinforcementBarPitchOfWall - Description: Hsb-wand Rc=2,8m²K/W; Reference: Basic Wall:NLRS_21_WA_Metalstud 215
Type - Pset_WallCommon - IsExternal: no; Reference: Basic Wall:NLRS_21_WA_Metalstud 215; FireRating: -
Classification: 21.23 buitenwanden; constructief, systeemwanden (Uniformat)
BaseQuantities - Width: 215 mm
Pset_WallCommon - ExtendToStructure: no; LoadBearing: no
Name (Basic Wall:NLRS_21_WA_Metalstud 215:...) | Height (mm) | Length (mm) | GrossFootprintArea (m2) | NetVolume (m3) | NetSideArea (m2)
3078879 | 3001 | 2915.31 | 0.626791 | 1881000380 | 8748839
3080451 | 3001 | 3355.16 | 0.710033 | 2164800760 | 10068841
5762125 | 2931 | 3600 | 0.774 | 2268594000 | 10551600
5762153 | 2952 | 3600 | 0.774 | 2284848000 | 10627200
6515065 | 2992 | 668.34 | 0.143693 | 429929500 | 1999672
7767140 | 2992 | 668.34 | 0.143693 | 429929500 | 1999672

# IfcWallStandardCase: Basic Wall:NLRS_21_WA_Metalstud 235mm (4)
In: 00 begane grond
Type - PredefinedType: STANDARD; Material: NLRS_f7_gipsplaat_gen 12.5 mm, AL_Multiplex 10 mm, NLRS_m1_isolatie 75 mm, NLRS_j9_lucht_gen 40 mm, NLRS_m1_isolatie 75 mm, AL_Multiplex 10 mm, NLRS_f7_gipsplaat_gen 12.5 mm
Type - Pset_ConcreteElementGeneral - FireRating: -
Type - Pset_ElementShading - Roughness: 304.8 mm
Type - Pset_ProductRequirements - Category: Walls
Type - Pset_QuantityTakeOff - Reference: Basic Wall:NLRS_21_WA_Metalstud 235mm
Type - Pset_ReinforcementBarPitchOfWall - Description: Hsb-wand Rc=2,8m²K/W; Reference: Basic Wall:NLRS_21_WA_Metalstud 235mm
Type - Pset_WallCommon - IsExternal: no; Reference: Basic Wall:NLRS_21_WA_Metalstud 235mm; FireRating: -
Classification: 21.23 buitenwanden; constructief, systeemwanden (Uniformat)
BaseQuantities - Width: 235 mm
Pset_WallCommon - ExtendToStructure: no; LoadBearing: no
Name (Basic Wall:NLRS_21_WA_Metalstud 235mm:...) | Height (mm) | Length (mm) | GrossFootprintArea (m2) | NetVolume (m3) | NetSideArea (m2)
3004677 | 5519.72 | 7911.66 | 1.85924 | 10262485242 | 43670150
3004838 | 5520.85 | 7911.63 | 1.85923 | 10264544957 | 43678915
3005159 | 5519.46 | 7901.86 | 1.85694 | 10249284043 | 43613975
3005288 | 5520.45 | 7903.72 | 1.85737 | 10253539109 | 43632081

# IfcWallStandardCase: Basic Wall:NLRS_21_WA_Metalstud 240mm (8)
Type - PredefinedType: STANDARD; Material: NLRS_f7_gipsplaat_gen 12.5 mm, NLRS_f7_gipsplaten 12.5 mm, NLRS_m1_isolatie 75 mm, NLRS_j9_lucht_gen 40 mm, NLRS_m1_isolatie 75 mm, NLRS_f7_gipsplaten 12.5 mm, NLRS_f7_gipsplaat_gen 12.5 mm
Type - Pset_ConcreteElementGeneral - FireRating: -
Type - Pset_ElementShading - Roughness: 304.8 mm
Type - Pset_ProductRequirements - Category: Walls
Type - Pset_QuantityTakeOff - Reference: Basic Wall:NLRS_21_WA_Metalstud 240mm
Type - Pset_ReinforcementBarPitchOfWall - Description: Hsb-wand Rc=2,8m²K/W; Reference: Basic Wall:NLRS_21_WA_Metalstud 240mm
Type - Pset_WallCommon - IsExternal: no; Reference: Basic Wall:NLRS_21_WA_Metalstud 240mm; FireRating: -
Classification: 21.23 buitenwanden; constructief, systeemwanden (Uniformat)
BaseQuantities - Width: 240 mm
Pset_WallCommon - ExtendToStructure: no; LoadBearing: no
Name (Basic Wall:NLRS_21_WA_Metalstud 240mm:...) | In | Height (mm) | Length (mm) | GrossFootprintArea (m2) | NetVolume (m3) | NetSideArea (m2)
3532119 | 00 begane grond | 2770 | 10199.6 | 2.4479 | 6780688687 | 28252870
4324754 | 00 begane grond | 2926 | 2931.56 | 0.703575 | 2058661209 | 8577755
4450865 | 00 begane grond | 2982 | 4491.55 | 1.07797 | 3214515066 | 13393813
4621716 | Podium | 3148.35 | 713.067 | 0.171136 | 538796095 | 2244984
4621949 | Podium | 3148.35 | 699.571 | 0.167897 | 528598609 | 2202494
5760074 | 00 begane grond | 3001 | 5093.86 | 1.22253 | 3668803872 | 15286683
8037642 | 00 begane grond | 2852 | 3104.64 | 0.745114 | 2125064055 | 8854434
10357999 | 00 begane grond | 2881 | 3302 | 0.79248 | 2283134880 | 9513062

# IfcWallStandardCase: Basic Wall:NLRS_21_WA_Metalstud 300mm, Basic Wall:NLRS_21_WA_Metalstud 300mm:5946912
In: 00 begane grond
Type - PredefinedType: STANDARD; Material: NLRS_f7_gipsplaat_gen 12.5 mm, NLRS_f7_gipsplaat_gen 12.5 mm, NLRS_m1_isolatie 100 mm, NLRS_j9_lucht_gen 50 mm, NLRS_m1_isolatie 100 mm, NLRS_f7_gipsplaat_gen 12.5 mm, NLRS_f7_gipsplaat_gen 12.5 mm
Type - Pset_ConcreteElementGeneral - FireRating: -
Type - Pset_ElementShading - Roughness: 304.8 mm
Type - Pset_ProductRequirements - Category: Walls
Type - Pset_QuantityTakeOff - Reference: Basic Wall:NLRS_21_WA_Metalstud 300mm
Type - Pset_ReinforcementBarPitchOfWall - Description: Hsb-wand Rc=2,8m²K/W; Reference: Basic Wall:NLRS_21_WA_Metalstud 300mm
Type - Pset_WallCommon - IsExternal: no; Reference: Basic Wall:NLRS_21_WA_Metalstud 300mm; FireRating: -
Classification: 21.23 buitenwanden; constructief, systeemwanden (Uniformat)
BaseQuantities - Height: 4422 mm; Length: 10191.7 mm; Width: 300 mm; GrossFootprintArea: 3.05751 m2; NetVolume: 13520304119 m3; NetSideArea: 45067680 m2
Pset_WallCommon - ExtendToStructure: no; LoadBearing: no

# IfcWallStandardCase: Basic Wall:NLRS_21_WA_Metalstud 63mm (eenzijdig) (12)
Type - PredefinedType: STANDARD; Material: NLRS_m1_isolatie 50 mm, NLRS_f7_gipsplaat_gen 12.5 mm
Type - Pset_ConcreteElementGeneral - FireRating: -
Type - Pset_ElementShading - Roughness: 304.8 mm
Type - Pset_ProductRequirements - Category: Walls
Type - Pset_QuantityTakeOff - Reference: Basic Wall:NLRS_21_WA_Metalstud 63mm (eenzijdig)
Type - Pset_ReinforcementBarPitchOfWall - Description: Hsb-wand Rc=2,8m²K/W; Reference: Basic Wall:NLRS_21_WA_Metalstud 63mm (eenzijdig)
Type - Pset_WallCommon - IsExternal: no; Reference: Basic Wall:NLRS_21_WA_Metalstud 63mm (eenzijdig); FireRating: -
Classification: 21.23 buitenwanden; constructief, systeemwanden (Uniformat)
BaseQuantities - Width: 62.5 mm
Pset_WallCommon - ExtendToStructure: no; LoadBearing: no
Name (Basic Wall:NLRS_21_WA_Metalstud 63mm (eenzijdig):...) | In | Height (mm) | Length (mm) | GrossFootprintArea (m2) | NetVolume (m3) | NetSideArea (m2)
6520510 | 01 eerste verdieping | 2955.01 | 2543.97 | 0.158998 | 469841305 | 7517461
7501371 | 00 begane grond | 2882 | 3441 | 0.215062 | 619810125 | 9916962
7813927 | 00 begane grond | 2951 | 1523.91 | 0.0952441 | 281065440 | 4497047
7814285 | 00 begane grond | 2926 | 731.959 | 0.0457474 | 133856976 | 2141712
7814453 | 00 begane grond | 2926 | 2356.25 | 0.147266 | 430899962 | 6894399
7814800 | 00 begane grond | 2926 | 4894.7 | 0.305919 | 895118886 | 14321902
7815020 | 00 begane grond | 2162 | 177.729 | 0.0111081 | 24015666 | 384251
7815146 | 00 begane grond | 2926 | 4164.23 | 0.260264 | 761533430 | 12184535
7815147 | 00 begane grond | 2162 | 177.729 | 0.0111081 | 24015666 | 384251
7815499 | 00 begane grond | 2856 | 1310.72 | 0.0819198 | 233962962 | 3743407
8941779 | 00 begane grond | 3001 | 915.511 | 0.0547194 | 171715492 | 2747448
8941780 | 00 begane grond | 2936 | 337.661 | 0.0211038 | 61960882 | 991374

# IfcWallStandardCase: Basic Wall:NLRS_21_WA_Metalstud 88mm (eenzijdig) (2)
In: 00 begane grond
Type - PredefinedType: STANDARD; Material: NLRS_m1_isolatie 75 mm, NLRS_f7_gipsplaat_gen 12.5 mm
Type - Pset_ConcreteElementGeneral - FireRating: -
Type - Pset_ElementShading - Roughness: 304.8 mm
Type - Pset_ProductRequirements - Category: Walls
Type - Pset_QuantityTakeOff - Reference: Basic Wall:NLRS_21_WA_Metalstud 88mm (eenzijdig)
Type - Pset_ReinforcementBarPitchOfWall - Description: Hsb-wand Rc=2,8m²K/W; Reference: Basic Wall:NLRS_21_WA_Metalstud 88mm (eenzijdig)
Type - Pset_WallCommon - IsExternal: no; Reference: Basic Wall:NLRS_21_WA_Metalstud 88mm (eenzijdig); FireRating: -
Classification: 21.23 buitenwanden; constructief, systeemwanden (Uniformat)
BaseQuantities - Height: 2807 mm; Length: 4645.92 mm; Width: 87.5 mm; GrossFootprintArea: 0.406489 m2; NetVolume: 1141096690 m3; NetSideArea: 13041105 m2
Pset_WallCommon - ExtendToStructure: no; LoadBearing: no
Name (Basic Wall:NLRS_21_WA_Metalstud 88mm (eenzijdig):...)
10358507
10358515

# IfcWallStandardCase: Basic Wall:NLRS_21_WA_Metalstud 90mm (achter sierbekleding) (4)
Type - PredefinedType: STANDARD; Material: NLRS_i4_hout_multiplex zwart 15 mm, NLRS_m1_isolatie 75 mm
Type - Pset_ConcreteElementGeneral - FireRating: -
Type - Pset_ElementShading - Roughness: 304.8 mm
Type - Pset_ProductRequirements - Category: Walls
Type - Pset_QuantityTakeOff - Reference: Basic Wall:NLRS_21_WA_Metalstud 90mm (achter sierbekleding)
Type - Pset_ReinforcementBarPitchOfWall - Description: Hsb-wand Rc=2,8m²K/W; Reference: Basic Wall:NLRS_21_WA_Metalstud 90mm (achter sierbekleding)
Type - Pset_WallCommon - IsExternal: no; Reference: Basic Wall:NLRS_21_WA_Metalstud 90mm (achter sierbekleding); FireRating: -
Classification: 21.23 buitenwanden; constructief, systeemwanden (Uniformat)
BaseQuantities - Width: 90 mm
Pset_WallCommon - ExtendToStructure: no; LoadBearing: no
Name (Basic Wall:NLRS_21_WA_Metalstud 90mm (achter sierbekleding):...) | In | Height (mm) | Length (mm) | GrossFootprintArea (m2) | NetVolume (m3) | NetSideArea (m2)
5606421 | 00 begane grond | 2982 | 4096.29 | 0.368666 | 1099361695 | 12215130
5617124 | 00 begane grond | 3996.65 | 3240.42 | 0.291638 | 1165573072 | 12950812
5650183 | 00 begane grond | 2912 | 223.564 | 0.0201207 | 58591543 | 651017
5664358 | 01 eerste verdieping | 2223.87 | 4020.29 | 0.361826 | 804653047 | 8940589

# IfcWallStandardCase: Basic Wall:NLRS_21_WA_isolatie glaswol_160mm_gen_aly, Basic Wall:NLRS_21_WA_isolatie glaswol_160mm_gen_aly:3656493
In: 00 begane grond
Type - PredefinedType: STANDARD; Material: NLRS_m1_isolatie 160 mm
Type - Pset_ConcreteElementGeneral - FireRating: -
Type - Pset_ElementShading - Roughness: 304.8 mm
Type - Pset_ProductRequirements - Category: Walls
Type - Pset_QuantityTakeOff - Reference: Basic Wall:NLRS_21_WA_isolatie glaswol_160mm_gen_aly
Type - Pset_ReinforcementBarPitchOfWall - Description: Glaswol isolatie 140mm; Reference: Basic Wall:NLRS_21_WA_isolatie glaswol_160mm_gen_aly
Type - Pset_WallCommon - IsExternal: no; Reference: Basic Wall:NLRS_21_WA_isolatie glaswol_160mm_gen_aly; FireRating: -
Classification: 21.10 buitenwanden; niet constructief, algemeen (verzamelniveau) (Uniformat)
BaseQuantities - Height: 5560.17 mm; Length: 5359.74 mm; Width: 160 mm; GrossFootprintArea: 0.857558 m2; NetVolume: 4768166715 m3; NetSideArea: 29801042 m2
Pset_WallCommon - IsExternal: yes; ExtendToStructure: no; LoadBearing: no

# IfcWallStandardCase: Basic Wall:NLRS_21_WA_isolatie glaswol_200mm_gen_aly (3)
Type - PredefinedType: STANDARD; Material: NLRS_m1_isolatie 200 mm
Type - Pset_ConcreteElementGeneral - FireRating: -
Type - Pset_ElementShading - Roughness: 304.8 mm
Type - Pset_ProductRequirements - Category: Walls
Type - Pset_QuantityTakeOff - Reference: Basic Wall:NLRS_21_WA_isolatie glaswol_200mm_gen_aly
Type - Pset_ReinforcementBarPitchOfWall - Description: Glaswol isolatie 140mm; Reference: Basic Wall:NLRS_21_WA_isolatie glaswol_200mm_gen_aly
Type - Pset_WallCommon - IsExternal: no; Reference: Basic Wall:NLRS_21_WA_isolatie glaswol_200mm_gen_aly; FireRating: -
Classification: 21.10 buitenwanden; niet constructief, algemeen (verzamelniveau) (Uniformat)
BaseQuantities - Width: 200 mm
Pset_WallCommon - IsExternal: yes; ExtendToStructure: no; LoadBearing: no
Name (Basic Wall:NLRS_21_WA_isolatie glaswol_200mm_gen_aly:...) | In | Height (mm) | Length (mm) | GrossFootprintArea (m2) | NetVolume (m3) | NetSideArea (m2)
4551962 | 01 eerste verdieping | 2382.84 | 7333.61 | 1.46672 | 3494959413 | 17474797
9176637 | 00 begane grond | 806.1 | 1386 | 0.2772 | 223450920 | 1117255
11610821 | 00 begane grond | 2360 | 7775.53 | 1.55511 | 3670048329 | 18350242

# IfcWallStandardCase: Basic Wall:NLRS_21_WA_kalkzandsteen_100mm_CS12_gen_aly (10)
In: 00 begane grond
Type - PredefinedType: STANDARD; Material: NLRS_f1_kalkzandsteen_CS12 100 mm
Type - Pset_ConcreteElementGeneral - FireRating: -
Type - Pset_ElementShading - Roughness: 304.8 mm
Type - Pset_ManufacturerTypeInformation - Manufacturer: De RuwBouw Groep
Type - Pset_ProductRequirements - Category: Walls
Type - Pset_QuantityTakeOff - Reference: Basic Wall:NLRS_21_WA_kalkzandsteen_100mm_CS12_gen_aly
Type - Pset_ReinforcementBarPitchOfWall - Description: Kalkzandsteen 100mm CS12; Reference: Basic Wall:NLRS_21_WA_kalkzandsteen_100mm_CS12_gen_aly
Type - Pset_WallCommon - IsExternal: no; Reference: Basic Wall:NLRS_21_WA_kalkzandsteen_100mm_CS12_gen_aly; FireRating: -
Classification: 21.22 buitenwanden; constructief, spouwwanden (Uniformat)
BaseQuantities - Width: 100 mm
Pset_WallCommon - IsExternal: yes; ExtendToStructure: no; LoadBearing: no
Name (Basic Wall:NLRS_21_WA_kalkzandsteen_100mm_CS12_gen_aly:...) | Height (mm) | Length (mm) | GrossFootprintArea (m2) | NetVolume (m3) | NetSideArea (m2)
3150840 | 2532 | 1025.01 | 0.102501 | 259532985 | 2595330
3150985 | 2532 | 1958 | 0.1958 | 495765600 | 4957656
3151067 | 2462 | 1945 | 0.1945 | 478859000 | 4788590
3151230 | 2070 | 590 | 0.059 | 122130000 | 1221300
3473372 | 2395 | 805.383 | 0.0805383 | 192889110 | 1928891
3473689 | 1960 | 1056.54 | 0.105654 | 207080909 | 2070809
3833788 | 475.473 | 805.711 | 0.0805606 | 38309363 | 383094
3833789 | 921 | 1056.56 | 0.105656 | 97309491 | 973095
4446463 | 2395 | 1366.57 | 0.136657 | 327293565 | 3272936
4446791 | 486 | 1366.38 | 0.136638 | 66406091 | 664061

# IfcWallStandardCase: Basic Wall:NLRS_21_WA_kalkzandsteen_100mm_gen_aly (66)
In: 00 begane grond
Type - PredefinedType: STANDARD; Material: NLRS_f1_kalkzandsteen_CS20 100 mm
Type - Pset_ConcreteElementGeneral - FireRating: -
Type - Pset_ElementShading - Roughness: 304.8 mm
Type - Pset_ManufacturerTypeInformation - Manufacturer: De RuwBouw Groep
Type - Pset_ProductRequirements - Category: Walls
Type - Pset_QuantityTakeOff - Reference: Basic Wall:NLRS_21_WA_kalkzandsteen_100mm_gen_aly
Type - Pset_ReinforcementBarPitchOfWall - Description: Kalkzandsteen 120mm CS20; Reference: Basic Wall:NLRS_21_WA_kalkzandsteen_100mm_gen_aly
Type - Pset_WallCommon - Reference: Basic Wall:NLRS_21_WA_kalkzandsteen_100mm_gen_aly; FireRating: -; IsExternal: no
Classification: 21.22 buitenwanden; constructief, spouwwanden (Uniformat)
BaseQuantities - Width: 100 mm
Pset_WallCommon - IsExternal: yes; ExtendToStructure: no; LoadBearing: no
Name (Basic Wall:NLRS_21_WA_kalkzandsteen_100mm_gen_aly:...) | Height (mm) | Length (mm) | GrossFootprintArea (m2) | NetVolume (m3) | NetSideArea (m2)
2832943 | 2532 | 866.886 | 0.0865133 | 219495477 | 2194955
2833115 | 2532 | 312.275 | 0.0311399 | 79068085 | 790681
2833616 | 2532 | 2389.41 | 0.238907 | 604998753 | 6049988
2833920 | 2532 | 1278.64 | 0.127838 | 323751922 | 3237519
2835225 | 2532 | 1302.43 | 0.130243 | 329776485 | 3297765
2835339 | 2532 | 1912.54 | 0.191254 | 484254067 | 4842541
2835913 | 2532 | 5282.32 | 0.528214 | 1337482890 | 13374829
2836107 | 2532 | 2078.32 | 0.207611 | 526230407 | 5262304
2836291 | 2070 | 579.251 | 0.0577139 | 119904955 | 1199050
2850593 | 2532 | 834.852 | 0.0834852 | 211384543 | 2113845
2852220 | 2532 | 2110.34 | 0.211001 | 534339273 | 5343393
2852494 | 2532 | 1080.17 | 0.108011 | 273498339 | 2734983
2852651 | 2532 | 2110.21 | 0.211 | 534306182 | 5343062
2853077 | 2532 | 1079.14 | 0.107886 | 273237268 | 2732373
2853360 | 2532 | 1081.62 | 0.108135 | 273866398 | 2738664
2853494 | 2532 | 683.99 | 0.0683669 | 173186174 | 1731862
2853688 | 2532 | 694.062 | 0.0693884 | 175736441 | 1757364
2853739 | 2532 | 3438.72 | 0.343799 | 870684503 | 8706845
2853859 | 2532 | 1006.19 | 0.100547 | 254766642 | 2547666
2853993 | 2532 | 1007.85 | 0.100706 | 255187782 | 2551878
2854090 | 2532 | 1173.28 | 0.11738 | 297074875 | 2970749
2977125 | 2532 | 3678.77 | 0.367877 | 931464753 | 9314648
3312264 | 2077 | 834 | 0.0834 | 173221800 | 1732218
3368997 | 2532 | 9058.26 | 0.905823 | 2293552531 | 22935525
3369528 | 1960 | 6034.99 | 0.603499 | 1182858947 | 11828589
3372851 | 1980 | 1709.7 | 0.170956 | 338520345 | 3385203
3373257 | 2532 | 1103.78 | 0.110378 | 279477923 | 2794779
3374404 | 2532 | 1501.84 | 0.150184 | 380265976 | 3802660
3375766 | 2532 | 4575.26 | 0.457526 | 1158454773 | 11584548
3376937 | 1960 | 1615.64 | 0.161564 | 316665359 | 3166654
3833721 | 349 | 2474.08 | 0.247401 | 86345358 | 863454
3833722 | 349 | 866.886 | 0.0865133 | 30254313 | 302543
3833723 | 349 | 312.275 | 0.0311399 | 10898405 | 108984
3833724 | 349 | 2389.41 | 0.238907 | 83390428 | 833904
3833726 | 349 | 1278.64 | 0.127838 | 44624574 | 446246
3833727 | 349 | 2731.36 | 0.273136 | 95324464 | 953245
3833728 | 349 | 1302.43 | 0.130243 | 45454974 | 454550
3833729 | 349 | 1912.54 | 0.191254 | 66747500 | 667475
3833731 | 349 | 5282.32 | 0.528214 | 184352894 | 1843529
3833732 | 349 | 2078.32 | 0.207611 | 72533338 | 725333
3833739 | 349 | 2110.34 | 0.211001 | 73651029 | 736510
3833740 | 349 | 1080.17 | 0.108011 | 37697836 | 376978
3833741 | 349 | 2110.21 | 0.211 | 73646468 | 736465
3833742 | 349 | 1081.62 | 0.108135 | 37748567 | 377486
3833744 | 349 | 683.99 | 0.0683669 | 23871238 | 238712
3833745 | 349 | 694.062 | 0.0693884 | 24222756 | 242228
3833746 | 349 | 3438.72 | 0.343799 | 120011411 | 1200114
3833747 | 349 | 1006.19 | 0.100547 | 35115939 | 351159
3833748 | 349 | 1007.85 | 0.100706 | 35173987 | 351740
3833749 | 349 | 1173.28 | 0.11738 | 40947524 | 409475
3833750 | 349 | 3678.77 | 0.367877 | 128389099 | 1283891
3833751 | 349 | 1025.01 | 0.102501 | 35772911 | 357729
3833752 | 349 | 1958 | 0.1958 | 68334200 | 683342
3833753 | 419 | 1945 | 0.1945 | 81495500 | 814955
3833759 | 349 | 9074.05 | 0.907384 | 316684470 | 3166845
3833760 | 921 | 6034.99 | 0.603499 | 555823005 | 5558230
3833763 | 349 | 1003.78 | 0.100378 | 35032036 | 350320
3833765 | 349 | 1499.55 | 0.149955 | 52334329 | 523343
3833766 | 349 | 4495.1 | 0.44951 | 156878990 | 1568790
3833787 | 921 | 1615 | 0.1615 | 148741500 | 1487415
3834418 | 349 | 884.732 | 0.0884732 | 30877144 | 308771
3834662 | 349 | 1079.14 | 0.107886 | 37661851 | 376619
4798426 | 2077 | 834 | 0.0834 | 173221800 | 1732218
7763608 | 2077 | 834 | 0.0834 | 173221800 | 1732218
7813584 | 1550 | 830.183 | 0.0830183 | 128678355 | 1286784
12811710 | 1600 | 831.193 | 0.0831193 | 132990854 | 1329909

# IfcWallStandardCase: Basic Wall:NLRS_21_WA_kalkzandsteen_120mm_CS20_gen_aly (36)
Type - PredefinedType: STANDARD; Material: NLRS_f1_kalkzandsteen_CS20 120 mm
Type - Pset_ConcreteElementGeneral - FireRating: -
Type - Pset_ElementShading - Roughness: 304.8 mm
Type - Pset_ManufacturerTypeInformation - Manufacturer: De RuwBouw Groep
Type - Pset_ProductRequirements - Category: Walls
Type - Pset_QuantityTakeOff - Reference: Basic Wall:NLRS_21_WA_kalkzandsteen_120mm_CS20_gen_aly
Type - Pset_ReinforcementBarPitchOfWall - Description: Kalkzandsteen 120mm CS20; Reference: Basic Wall:NLRS_21_WA_kalkzandsteen_120mm_CS20_gen_aly
Type - Pset_WallCommon - IsExternal: no; Reference: Basic Wall:NLRS_21_WA_kalkzandsteen_120mm_CS20_gen_aly; FireRating: -
Classification: 21.22 buitenwanden; constructief, spouwwanden (Uniformat)
BaseQuantities - Width: 120 mm
Pset_WallCommon - IsExternal: yes; ExtendToStructure: no; LoadBearing: no
Name (Basic Wall:NLRS_21_WA_kalkzandsteen_120mm_CS20_gen_aly:...) | In | Height (mm) | Length (mm) | GrossFootprintArea (m2) | NetVolume (m3) | NetSideArea (m2)
2835614 | 00 begane grond | 2532 | 2881.53 | 0.345784 | 875524695 | 7296039
3197575 | 00 begane grond | 2770 | 4706.15 | 0.564738 | 1564324722 | 13036039
3199514 | 00 begane grond | 3069 | 1846.5 | 0.22158 | 680030164 | 5666918
3214728 | 00 begane grond | 2982 | 3726.83 | 0.447219 | 1333607997 | 11113400
3457916 | 00 begane grond | 2770 | 1041.85 | 0.125022 | 346309984 | 2885917
3458095 | 00 begane grond | 2770 | 921.5 | 0.11058 | 306306612 | 2552555
3833730 | 00 begane grond | 349 | 2781.53 | 0.333784 | 116490562 | 970755
4203402 | 00 begane grond | 3140 | 2377.9 | 0.285348 | 895993544 | 7466613
4204239 | 01 eerste verdieping | 3004.17 | 2377.9 | 0.285348 | 857234508 | 7143621
4219976 | 00 begane grond | 4022.37 | 3337.53 | 0.400503 | 1610972505 | 13424771
4259768 | 01 eerste verdieping | 925.596 | 2833.48 | 0.340018 | 314718951 | 2622658
4262419 | 00 begane grond | 2982 | 3648.92 | 0.43787 | 1305728689 | 10881072
4310765 | 00 begane grond | 3571.08 | 1420.43 | 0.170452 | 608696152 | 5072468
4545791 | 00 begane grond | 2906 | 3188.37 | 0.382605 | 1111849504 | 9265413
5604309 | 00 begane grond | 2770 | 1810.68 | 0.217282 | 601870695 | 5015589
5626331 | 00 begane grond | 2770 | 3347.48 | 0.401698 | 1112702307 | 9272519
5626561 | 00 begane grond | 2770 | 1058.99 | 0.127079 | 352008469 | 2933404
5627975 | 00 begane grond | 1015 | 4006 | 0.48072 | 487930800 | 4066090
5628161 | 00 begane grond | 2906 | 1673.47 | 0.200816 | 583572364 | 4863103
5631826 | 00 begane grond | 2926 | 6768.33 | 0.812199 | 2376495161 | 19804126
5670980 | 00 begane grond | 3001 | 2947.15 | 0.353658 | 1061327753 | 8844398
5671183 | 00 begane grond | 3002 | 3305 | 0.3966 | 1190593200 | 9921610
5734004 | 00 begane grond | 2770 | 1041.49 | 0.124979 | 346192479 | 2884937
5734268 | 00 begane grond | 2770 | 2243.18 | 0.269182 | 745632803 | 6213607
5897613 | 01 eerste verdieping | 2176.5 | 3646.5 | 0.43758 | 952390919 | 7936591
5897757 | 01 eerste verdieping | 2909.29 | 2144.45 | 0.257334 | 748658386 | 6238820
6022590 | 01 eerste verdieping | 2332.78 | 4036.68 | 0.484402 | 1130004250 | 9416702
6022730 | 01 eerste verdieping | 2918.84 | 1692.79 | 0.203135 | 592917456 | 4940979
6675911 | 00 begane grond | 2911 | 4560.09 | 0.547211 | 1592931298 | 13274427
7273886 | 00 begane grond | 2911 | 4552.51 | 0.546301 | 1590282134 | 13252351
7741589 | 00 begane grond | 3575.97 | 1434.92 | 0.172191 | 615749458 | 5131245
7744322 | 00 begane grond | 3573.08 | 1424.29 | 0.170914 | 610690536 | 5089088
7756386 | 00 begane grond | 3570.88 | 1419.91 | 0.170389 | 608440098 | 5070334
8163262 | 00 begane grond | 2770 | 733.848 | 0.0880617 | 243930928 | 2032758
10122038 | 00 begane grond | 2926 | 6801.64 | 0.816197 | 2388192112 | 19901601
10124902 | 00 begane grond | 2926 | 4930.01 | 0.591602 | 1731026416 | 14425220

# IfcWallStandardCase: Basic Wall:NLRS_21_WA_kalkzandsteen_130mm (4)
In: 00 begane grond
Type - PredefinedType: STANDARD; Material: NLRS_f1_kalkzandsteen_CS20 130 mm
Type - Pset_ConcreteElementGeneral - FireRating: -
Type - Pset_ElementShading - Roughness: 304.8 mm
Type - Pset_ManufacturerTypeInformation - Manufacturer: De RuwBouw Groep
Type - Pset_ProductRequirements - Category: Walls
Type - Pset_QuantityTakeOff - Reference: Basic Wall:NLRS_21_WA_kalkzandsteen_130mm
Type - Pset_ReinforcementBarPitchOfWall - Description: Kalkzandsteen 120mm CS20; Reference: Basic Wall:NLRS_21_WA_kalkzandsteen_130mm
Type - Pset_WallCommon - IsExternal: no; Reference: Basic Wall:NLRS_21_WA_kalkzandsteen_130mm; FireRating: -
Classification: 21.12 buitenwanden; niet constructief, spouwwanden (Uniformat)
BaseQuantities - Width: 130 mm
Pset_WallCommon - IsExternal: yes; ExtendToStructure: no; LoadBearing: no
Name (Basic Wall:NLRS_21_WA_kalkzandsteen_130mm:...) | Height (mm) | Length (mm) | GrossFootprintArea (m2) | NetVolume (m3) | NetSideArea (m2)
2833725 | 2532 | 1142.92 | 0.147339 | 376203409 | 2893872
2852122 | 2532 | 3125.07 | 0.406231 | 1028648372 | 7912680
3833725 | 349 | 1142.92 | 0.148547 | 51854261 | 398879
3833738 | 349 | 3125.07 | 0.406231 | 141784471 | 1090650

# IfcWallStandardCase: Basic Wall:NLRS_22_WA_LB_isolatie Kooltherm K8 105mm_Kingspan_BO (27)
Type - PredefinedType: STANDARD; Material: NLRS_n7_Kooltherm Resol hardschuim 0.02 (0.1)_Kingspan 105 mm
Type - Pset_ElementShading - Roughness: 304.8 mm
Type - Pset_ManufacturerTypeInformation - Manufacturer: Kingspan
Type - Pset_ProductRequirements - Category: Walls
Type - Pset_QuantityTakeOff - Reference: Basic Wall:NLRS_22_WA_LB_isolatie Kooltherm K8 105mm_Kingspan_BO
Type - Pset_ReinforcementBarPitchOfWall - Description: Hoogwaardige isolatie voor spouwmuren.; Reference: Basic Wall:NLRS_22_WA_LB_isolatie Kooltherm K8 105mm_Kingspan_BO
Type - Pset_WallCommon - IsExternal: no; Reference: Basic Wall:NLRS_22_WA_LB_isolatie Kooltherm K8 105mm_Kingspan_BO; ThermalTransmittance: 0.190476 kg/K/s3
Classification: 21.12 buitenwanden; niet constructief, spouwwanden (Uniformat)
BaseQuantities - Width: 105 mm
Pset_WallCommon - IsExternal: yes; ExtendToStructure: no; LoadBearing: no
Name (Basic Wall:NLRS_22_WA_LB_isolatie Kooltherm K8 105mm_Kingspan_BO:...) | In | Height (mm) | Length (mm) | GrossFootprintArea (m2) | NetVolume (m3) | NetSideArea (m2)
3214729 | 00 begane grond | 3330 | 3761.57 | 0.394965 | 1315232220 | 12526021
4203403 | 00 begane grond | 3330 | 2620.9 | 0.275195 | 916398450 | 8727604
5202519 | 00 begane grond | 3116 | 3298.87 | 0.346382 | 1079325335 | 10279289
5203073 | 00 begane grond | 3067 | 112 | 0.01176 | 36067920 | 343504
5203169 | 00 begane grond | 3038.89 | 3411.91 | 0.35825 | 1088683984 | 10368419
5208412 | 00 begane grond | 3256.94 | 224 | 0.02352 | 76603137 | 729554
5208605 | 00 begane grond | 3167 | 196.654 | 0.0206486 | 65394237 | 622802
5208884 | 00 begane grond | 3167 | 199 | 0.020895 | 66174465 | 630233
5211088 | 00 begane grond | 3067 | 142.661 | 0.0149794 | 45941943 | 437542
5214674 | 00 begane grond | 3062.47 | 230.552 | 0.024208 | 74136375 | 706061
5630371 | 00 begane grond | 970 | 9070 | 0.95235 | 923779500 | 8797900
5631009 | 00 begane grond | 974.017 | 7575.53 | 0.79543 | 774762517 | 7378691
5631010 | 00 begane grond | 6380.76 | 2053.4 | 0.215607 | 1375737115 | 13102258
5751795 | 01 eerste verdieping | 3203.54 | 2632.7 | 0.276433 | 885566201 | 8433964
5897580 | 01 eerste verdieping | 3046.46 | 9470.09 | 0.994359 | 3029277555 | 28850262
5909267 | 00 begane grond | 182 | 7124.18 | 0.748039 | 136143164 | 1296602
5910004 | 00 begane grond | 182 | 7477.8 | 0.785169 | 142900698 | 1360959
6028511 | ok. fundering | 182 | 4028.3 | 0.422972 | 76980886 | 733151
6028830 | ok. fundering | 182 | 1945 | 0.204225 | 37168950 | 353990
6028964 | ok. fundering | 202 | 2726.09 | 0.28624 | 57820451 | 550671
6240277 | 00 begane grond | 3138.68 | 262.699 | 0.0275834 | 86575544 | 824529
6614048 | 00 begane grond | 6321.73 | 1581.78 | 0.166087 | 1049959063 | 9999610
7372341 | 00 begane grond | 3470 | 7082.93 | 0.743708 | 2580667353 | 24577784
7745295 | 00 begane grond | 3510 | 261.447 | 0.0270854 | 96356154 | 917678
7758250 | 00 begane grond | 3727.2 | 260.77 | 0.0270355 | 102054007 | 971943
7758257 | 00 begane grond | 3727.2 | 260.767 | 0.027034 | 102052679 | 971930
10122141 | 00 begane grond | 3470 | 6921.64 | 0.726772 | 2521899820 | 24018094

# IfcWallStandardCase: Basic Wall:NLRS_22_WA_LB_isolatie PIR 100mm (8)
Type - PredefinedType: STANDARD; Material: NLRS_n7_isolatie PIR_gen 100 mm
Type - Pset_ElementShading - Roughness: 304.8 mm
Type - Pset_ManufacturerTypeInformation - Manufacturer: Kingspan
Type - Pset_ProductRequirements - Category: Walls
Type - Pset_QuantityTakeOff - Reference: Basic Wall:NLRS_22_WA_LB_isolatie PIR 100mm
Type - Pset_ReinforcementBarPitchOfWall - Description: Hoogwaardige isolatie voor spouwmuren.; Reference: Basic Wall:NLRS_22_WA_LB_isolatie PIR 100mm
Type - Pset_WallCommon - IsExternal: no; Reference: Basic Wall:NLRS_22_WA_LB_isolatie PIR 100mm
Classification: 21.12 buitenwanden; niet constructief, spouwwanden (Uniformat)
BaseQuantities - Width: 100 mm
Pset_WallCommon - IsExternal: yes; ExtendToStructure: no; LoadBearing: no
Name (Basic Wall:NLRS_22_WA_LB_isolatie PIR 100mm:...) | In | Height (mm) | Length (mm) | GrossFootprintArea (m2) | NetVolume (m3) | NetSideArea (m2)
5995758 | 01 eerste verdieping | 2860 | 140 | 0.014 | 40040000 | 400400
5995767 | 01 eerste verdieping | 2760 | 140 | 0.014 | 38640000 | 386400
5995788 | 01 eerste verdieping | 2666.86 | 130 | 0.013 | 34669213 | 346692
5996195 | 01 eerste verdieping | 202.724 | 9515 | 0.9515 | 192891652 | 1928917
6934666 | ok. fundering | 310 | 8206.22 | 0.820622 | 254392719 | 2543927
9237074 | ok. fundering | 310 | 7181.26 | 0.718126 | 222619004 | 2226190
9237421 | ok. fundering | 330 | 6893.99 | 0.689399 | 227501823 | 2275018
11083601 | 01 eerste verdieping | 2760 | 140 | 0.014 | 38640000 | 386400

# IfcWallStandardCase: Basic Wall:NLRS_22_WA_LB_isolatie PIR 40mm (6)
Type - PredefinedType: STANDARD; Material: NLRS_n7_isolatie PIR_gen 40 mm
Type - Pset_ElementShading - Roughness: 304.8 mm
Type - Pset_ManufacturerTypeInformation - Manufacturer: Kingspan
Type - Pset_ProductRequirements - Category: Walls
Type - Pset_QuantityTakeOff - Reference: Basic Wall:NLRS_22_WA_LB_isolatie PIR 40mm
Type - Pset_ReinforcementBarPitchOfWall - Description: Hoogwaardige isolatie voor spouwmuren.; Reference: Basic Wall:NLRS_22_WA_LB_isolatie PIR 40mm
Type - Pset_WallCommon - IsExternal: no; Reference: Basic Wall:NLRS_22_WA_LB_isolatie PIR 40mm
Classification: 21.12 buitenwanden; niet constructief, spouwwanden (Uniformat)
BaseQuantities - Width: 40 mm
Pset_WallCommon - IsExternal: yes; ExtendToStructure: no; LoadBearing: no
Name (Basic Wall:NLRS_22_WA_LB_isolatie PIR 40mm:...) | In | Height (mm) | Length (mm) | GrossFootprintArea (m2) | NetVolume (m3) | NetSideArea (m2)
6408756 | 02 tweede verdieping | 213 | 21385.1 | 0.855404 | 182200965 | 4555024
6408757 | 02 tweede verdieping | 208.976 | 10219.4 | 0.408777 | 85424690 | 2135617
6408965 | 02 tweede verdieping | 209.397 | 10219.4 | 0.408777 | 85596610 | 2139915
6409107 | 02 tweede verdieping | 213 | 12291.5 | 0.491662 | 104723984 | 2618100
6409477 | 02 tweede verdieping | 213 | 21385.1 | 0.855404 | 182200965 | 4555024
8153460 | 00 begane grond | 2856 | 100 | 0.004 | 11424000 | 285600

# IfcWallStandardCase: Basic Wall:NLRS_22_WA_LB_isolatie PIR 60mm (55)
Type - PredefinedType: STANDARD; Material: NLRS_n7_isolatie PIR_gen 60 mm
Type - Pset_ElementShading - Roughness: 304.8 mm
Type - Pset_ManufacturerTypeInformation - Manufacturer: Kingspan
Type - Pset_ProductRequirements - Category: Walls
Type - Pset_QuantityTakeOff - Reference: Basic Wall:NLRS_22_WA_LB_isolatie PIR 60mm
Type - Pset_ReinforcementBarPitchOfWall - Description: Hoogwaardige isolatie voor spouwmuren.; Reference: Basic Wall:NLRS_22_WA_LB_isolatie PIR 60mm
Type - Pset_WallCommon - IsExternal: no; Reference: Basic Wall:NLRS_22_WA_LB_isolatie PIR 60mm
Classification: 21.12 buitenwanden; niet constructief, spouwwanden (Uniformat)
BaseQuantities - Width: 60 mm
Pset_WallCommon - IsExternal: yes; ExtendToStructure: no; LoadBearing: no
Name (Basic Wall:NLRS_22_WA_LB_isolatie PIR 60mm:...) | In | Height (mm) | Length (mm) | GrossFootprintArea (m2) | NetVolume (m3) | NetSideArea (m2)
5751485 | 01 eerste verdieping | 3045 | 140 | 0.0084 | 25578000 | 426300
5751494 | 01 eerste verdieping | 3045 | 140 | 0.0084 | 25578000 | 426300
5751503 | 01 eerste verdieping | 3045 | 140 | 0.0084 | 25578000 | 426300
5751514 | 01 eerste verdieping | 3045 | 140 | 0.0084 | 25578000 | 426300
5751523 | 01 eerste verdieping | 3045 | 231.5 | 0.01389 | 42295050 | 704918
6056799 | ok. fundering | 202 | 1131.59 | 0.0678303 | 13714811 | 228580
6056899 | ok. fundering | 202 | 1710.41 | 0.10248 | 20730123 | 345502
6056948 | ok. fundering | 202 | 1715.9 | 0.102795 | 20796712 | 346612
6056991 | ok. fundering | 202 | 1718.6 | 0.102948 | 20829414 | 347157
6057035 | ok. fundering | 202 | 1843.38 | 0.110437 | 22341709 | 372362
6057078 | ok. fundering | 202 | 1815.36 | 0.108762 | 22002166 | 366703
6057121 | ok. fundering | 202 | 1730.92 | 0.103692 | 20978735 | 349646
6057164 | ok. fundering | 202 | 1728.48 | 0.103545 | 20949161 | 349153
6057209 | ok. fundering | 202 | 1728.48 | 0.103546 | 20949226 | 349154
6057295 | ok. fundering | 202 | 1830.78 | 0.109683 | 22189018 | 369817
6057338 | ok. fundering | 202 | 1728.48 | 0.103546 | 20949226 | 349154
6057381 | ok. fundering | 202 | 1728.48 | 0.103545 | 20949161 | 349153
6057424 | ok. fundering | 202 | 1730.92 | 0.103692 | 20978735 | 349646
6057467 | ok. fundering | 202 | 1714.85 | 0.10281 | 20784033 | 346401
6058102 | ok. fundering | 202 | 1830.78 | 0.109683 | 22189018 | 369817
6058737 | ok. fundering | 212 | 1622.85 | 0.097371 | 20642651 | 344044
6060496 | ok. fundering | 202 | 1964.21 | 0.117758 | 23806267 | 396771
6060561 | ok. fundering | 202 | 1712.34 | 0.102551 | 20753512 | 345892
6060623 | ok. fundering | 202 | 1964.98 | 0.117804 | 23815553 | 396926
6060668 | ok. fundering | 202 | 1708.23 | 0.102412 | 20703769 | 345063
6060764 | ok. fundering | 202 | 1730.92 | 0.103692 | 20978735 | 349646
6060858 | ok. fundering | 202 | 1728.48 | 0.103545 | 20949161 | 349153
6060923 | ok. fundering | 202 | 1728.48 | 0.103546 | 20949226 | 349154
6060987 | ok. fundering | 202 | 1830.78 | 0.109683 | 22189018 | 369817
6061057 | ok. fundering | 202 | 1830.78 | 0.109683 | 22189018 | 369817
6061144 | ok. fundering | 202 | 1728.48 | 0.103546 | 20949226 | 349154
6061200 | ok. fundering | 202 | 1728.48 | 0.103545 | 20949161 | 349153
6061273 | ok. fundering | 202 | 1730.92 | 0.103692 | 20978735 | 349646
6061357 | ok. fundering | 202 | 1815.36 | 0.108762 | 22002166 | 366703
6061414 | ok. fundering | 202 | 1843.38 | 0.110437 | 22341709 | 372362
6061473 | ok. fundering | 202 | 1718.6 | 0.102948 | 20829414 | 347157
6061562 | ok. fundering | 202 | 1715.9 | 0.102795 | 20796712 | 346612
6061646 | ok. fundering | 202 | 1710.41 | 0.10248 | 20730123 | 345502
6061768 | ok. fundering | 202 | 1842.25 | 0.11047 | 22328077 | 372135
6155220 | 01 eerste verdieping | 240 | 585.23 | 0.0350743 | 8427316 | 140455
6527026 | 01 eerste verdieping | 240 | 2002.81 | 0.119919 | 28840426 | 480674
6527174 | 01 eerste verdieping | 240 | 2109.52 | 0.126156 | 30377067 | 506284
6527187 | 01 eerste verdieping | 240 | 2118.78 | 0.126715 | 30510387 | 508506
6527198 | 01 eerste verdieping | 240 | 2113.31 | 0.126387 | 30431718 | 507195
6527209 | 01 eerste verdieping | 240 | 2111.19 | 0.126262 | 30401078 | 506685
6527220 | 01 eerste verdieping | 240 | 2070.01 | 0.123839 | 29808085 | 496801
6527229 | 01 eerste verdieping | 240 | 1202.45 | 0.0718611 | 17315297 | 288588
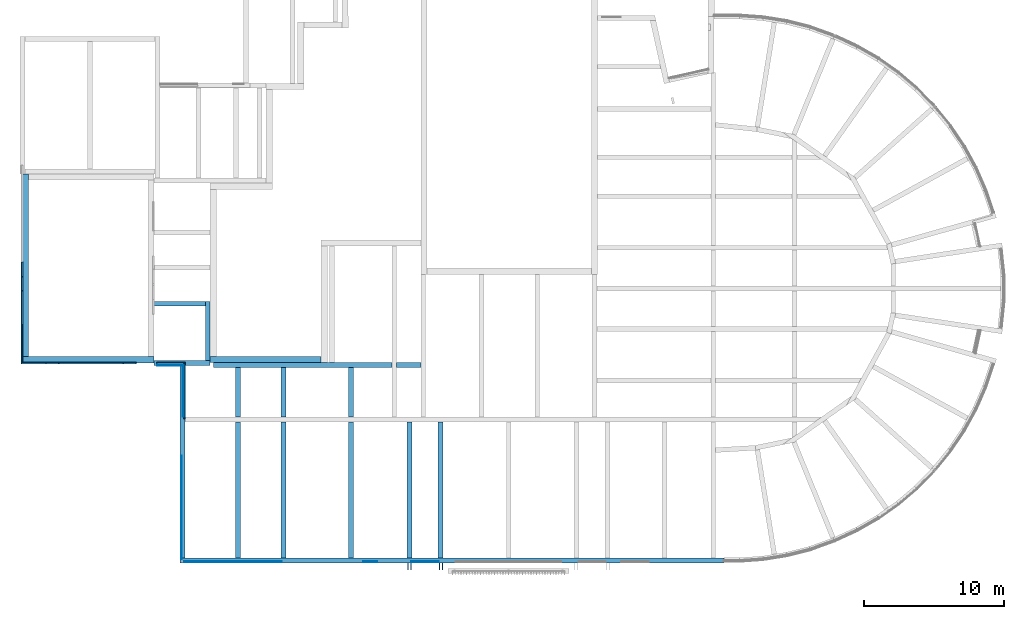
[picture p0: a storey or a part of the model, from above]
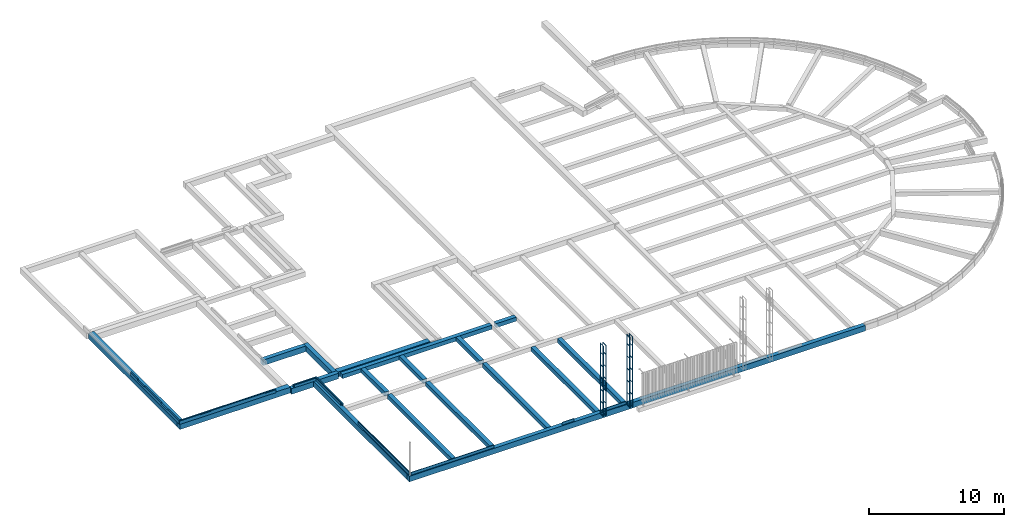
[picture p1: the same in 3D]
Properties of the parts of a building model (IFC2X3), part 12 of 13

# IfcWallStandardCase: Basic Wall:NLRS_22_WA_LB_isolatie PIR 60mm (55)
Name (Basic Wall:NLRS_22_WA_LB_isolatie PIR 60mm:...) | In | Height (mm) | Length (mm) | GrossFootprintArea (m2) | NetVolume (m3) | NetSideArea (m2)
6527638 | 01 eerste verdieping | 240 | 1413.32 | 0.084533 | 20351848 | 339197
6527647 | 01 eerste verdieping | 240 | 1429.13 | 0.0854746 | 20579463 | 342991
6527656 | 01 eerste verdieping | 240 | 1223.15 | 0.0732547 | 17613392 | 293557
6527683 | 01 eerste verdieping | 133 | 1658.53 | 0.0995118 | 13235072 | 220585
6527692 | 01 eerste verdieping | 240 | 1661.45 | 0.0996872 | 23924918 | 398749
6528061 | 01 eerste verdieping | 240 | 1662.36 | 0.0997416 | 23937979 | 398966
6528070 | 01 eerste verdieping | 240 | 2149.88 | 0.128993 | 30958265 | 515971
9191596 | 00 begane grond | 194 | 3005 | 0.1803 | 34978200 | 582970

# IfcWallStandardCase: Basic Wall:NLRS_22_WA_LB_isolatie PIR 70mm (9)
Type - PredefinedType: STANDARD; Material: NLRS_n7_isolatie PIR_gen 70 mm
Type - Pset_ElementShading - Roughness: 304.8 mm
Type - Pset_ManufacturerTypeInformation - Manufacturer: Kingspan
Type - Pset_ProductRequirements - Category: Walls
Type - Pset_QuantityTakeOff - Reference: Basic Wall:NLRS_22_WA_LB_isolatie PIR 70mm
Type - Pset_ReinforcementBarPitchOfWall - Description: Hoogwaardige isolatie voor spouwmuren.; Reference: Basic Wall:NLRS_22_WA_LB_isolatie PIR 70mm
Type - Pset_WallCommon - IsExternal: no; Reference: Basic Wall:NLRS_22_WA_LB_isolatie PIR 70mm
Classification: 21.12 buitenwanden; niet constructief, spouwwanden (Uniformat)
BaseQuantities - Width: 70 mm
Pset_WallCommon - IsExternal: yes; ExtendToStructure: no; LoadBearing: no
Name (Basic Wall:NLRS_22_WA_LB_isolatie PIR 70mm:...) | In | Height (mm) | Length (mm) | GrossFootprintArea (m2) | NetVolume (m3) | NetSideArea (m2)
5545902 | 01 eerste verdieping | 140 | 7571.46 | 0.530002 | 74200338 | 1060005
5751015 | 01 eerste verdieping | 1655 | 140 | 0.0098 | 16219000 | 231700
5751458 | 01 eerste verdieping | 1655 | 140 | 0.0098 | 16219000 | 231700
5751467 | 01 eerste verdieping | 1655 | 140 | 0.0098 | 16219000 | 231700
6381474 | 01 eerste verdieping | 268 | 15250 | 1.0675 | 286090000 | 4087000
9258235 | 00 begane grond | 3470 | 5646.29 | 0.39524 | 1371482689 | 19592610
9258866 | 00 begane grond | 3675 | 986.566 | 0.0690596 | 253794128 | 3625630
9258959 | 00 begane grond | 3675 | 12289.1 | 0.860235 | 3161362437 | 45162321
9259394 | 00 begane grond | 3675 | 3158.25 | 0.221078 | 812459889 | 11606570

# IfcWallStandardCase: Basic Wall:NLRS_22_WA_LB_isolatie PIR 90mm (15)
In: 01 eerste verdieping
Type - PredefinedType: STANDARD; Material: NLRS_n7_isolatie PIR_gen 90 mm
Type - Pset_ElementShading - Roughness: 304.8 mm
Type - Pset_ManufacturerTypeInformation - Manufacturer: Kingspan
Type - Pset_ProductRequirements - Category: Walls
Type - Pset_QuantityTakeOff - Reference: Basic Wall:NLRS_22_WA_LB_isolatie PIR 90mm
Type - Pset_ReinforcementBarPitchOfWall - Description: Hoogwaardige isolatie voor spouwmuren.; Reference: Basic Wall:NLRS_22_WA_LB_isolatie PIR 90mm
Type - Pset_WallCommon - IsExternal: no; Reference: Basic Wall:NLRS_22_WA_LB_isolatie PIR 90mm
Classification: 21.12 buitenwanden; niet constructief, spouwwanden (Uniformat)
BaseQuantities - Height: 2625.74 mm; Width: 90 mm
Pset_WallCommon - IsExternal: yes; ExtendToStructure: no; LoadBearing: no
Name (Basic Wall:NLRS_22_WA_LB_isolatie PIR 90mm:...) | Length (mm) | GrossFootprintArea (m2) | NetVolume (m3) | NetSideArea (m2)
5814686 | 139.208 | 0.0125287 | 32897126 | 365524
5814950 | 138.966 | 0.0125069 | 32839933 | 364888
5814959 | 138.654 | 0.0124789 | 32766225 | 364069
5815034 | 138.777 | 0.01249 | 32795326 | 364393
5815213 | 139.196 | 0.0125276 | 32894196 | 365491
5815222 | 140 | 0.0126 | 33084274 | 367603
5815294 | 140 | 0.0126 | 33084274 | 367603
5815303 | 139.074 | 0.0125166 | 32865400 | 365171
5815832 | 139.246 | 0.0125321 | 32906052 | 365623
5815841 | 139.445 | 0.01255 | 32953004 | 366144
5815850 | 139.864 | 0.0125877 | 33052054 | 367245
5815859 | 137.288 | 0.0123559 | 32443330 | 360481
5815868 | 137.805 | 0.0124024 | 32565466 | 361839
5815877 | 140.496 | 0.0126447 | 33201522 | 368906
5815886 | 137.235 | 0.0123512 | 32430960 | 360344

# IfcWallStandardCase: Basic Wall:NLRS_22_WA_gasbeton 100mm_Ytong G4/600_gen_aly, Basic Wall:NLRS_22_WA_gasbeton 100mm_Ytong G4/600_gen_aly:5897629
In: 01 eerste verdieping
Type - PredefinedType: STANDARD; Material: NLRS_f4_gasbeton_Ytong G4 600 100 mm
Type - Pset_ConcreteElementGeneral - FireRating: -
Type - Pset_ElementShading - Roughness: 304.8 mm
Type - Pset_ManufacturerTypeInformation - Manufacturer: Ytong
Type - Pset_ProductRequirements - Category: Walls
Type - Pset_QuantityTakeOff - Reference: Basic Wall:NLRS_22_WA_gasbeton 100mm_Ytong G4/600_gen_aly
Type - Pset_ReinforcementBarPitchOfWall - Reference: Basic Wall:NLRS_22_WA_gasbeton 100mm_Ytong G4/600_gen_aly
Type - Pset_WallCommon - IsExternal: no; Reference: Basic Wall:NLRS_22_WA_gasbeton 100mm_Ytong G4/600_gen_aly; FireRating: -
Classification: 22.11 binnenwanden; niet constructief, massieve wanden (Uniformat)
BaseQuantities - Height: 140 mm; Length: 7396.22 mm; Width: 100 mm; GrossFootprintArea: 0.739622 m2; NetVolume: 103547132 m3; NetSideArea: 1035471 m2
Pset_QuantityTakeOff - sets with these values: 2
Pset_WallCommon - ExtendToStructure: no; LoadBearing: no

# IfcWallStandardCase: Basic Wall:NLRS_41_WA_Bekleding kolommen (24)
Type - PredefinedType: STANDARD; Material: NLRS_f7_gipsplaat_gen 12.5 mm, NLRS_i4_hout_multiplex 10 mm
Type - Pset_ConcreteElementGeneral - FireRating: -
Type - Pset_ElementShading - Roughness: 304.8 mm
Type - Pset_ManufacturerTypeInformation - Manufacturer: NTB
Type - Pset_ProductRequirements - Category: Walls
Type - Pset_QuantityTakeOff - Reference: Basic Wall:NLRS_41_WA_Bekleding kolommen
Type - Pset_ReinforcementBarPitchOfWall - Description: Plaatmateriaal 18mm; Reference: Basic Wall:NLRS_41_WA_Bekleding kolommen
Type - Pset_WallCommon - IsExternal: no; Reference: Basic Wall:NLRS_41_WA_Bekleding kolommen; FireRating: -
Classification: 41.12 buitenwandafwerkingen; bekledingen (Uniformat)
BaseQuantities - Width: 22.5 mm
Pset_WallCommon - IsExternal: yes; ExtendToStructure: no; LoadBearing: no
Name (Basic Wall:NLRS_41_WA_Bekleding kolommen:...) | In | Height (mm) | Length (mm) | GrossFootprintArea (m2) | NetVolume (m3) | NetSideArea (m2)
6197391 | 01 eerste verdieping | 2870 | 143.883 | 0.00323736 | 9291226 | 412943
6198600 | 01 eerste verdieping | 2870 | 144.15 | 0.00324337 | 9308465 | 413710
6216278 | 01 eerste verdieping | 1572 | 8388.55 | 0.188742 | 296703140 | 13186806
6229087 | Podium | 291 | 6202.44 | 0.139555 | 40610447 | 1804909
6229368 | Podium | 291 | 6151.44 | 0.138407 | 40276525 | 1790068
6229707 | Podium | 291 | 4110 | 0.092475 | 26910225 | 1196010
6229746 | Podium | 270 | 1696 | 0.03816 | 10303200 | 457920
6281470 | 00 begane grond | 2700 | 18.908 | 0.00042543 | 1148660 | 51051.6
6293553 | 01 eerste verdieping | 5177.94 | 6753.5 | 0.151954 | 786806839 | 34969193
6442466 | 01 eerste verdieping | 140 | 3014.17 | 0.0678189 | 9494644 | 421984
6575164 | Podium | 258 | 2246.14 | 0.0505381 | 13038828 | 579503
6575445 | Podium | 258 | 2246.14 | 0.0505381 | 13038828 | 579503
6595714 | 01 eerste verdieping | 370 | 9834.46 | 0.221275 | 81871871 | 3638750
6596945 | 01 eerste verdieping | 1281 | 235.092 | 0.00528957 | 6775936 | 301153
6597090 | 01 eerste verdieping | 1281 | 218.182 | 0.00490909 | 6288551 | 279491
6597473 | 01 eerste verdieping | 1060 | 140 | 0.00315 | 3339000 | 148400
6598954 | 01 eerste verdieping | 100 | 1697.51 | 0.0381939 | 3819388 | 169751
6599456 | 01 eerste verdieping | 1060 | 140 | 0.00315 | 3339000 | 148400
6604983 | 01 eerste verdieping | 1351 | 194 | 0.004365 | 5897115 | 262094
6605024 | 01 eerste verdieping | 1491 | 1120 | 0.0252 | 37573200 | 1669920
6620893 | 01 eerste verdieping | 1351 | 267.5 | 0.00601875 | 8131331 | 361393
6621099 | 01 eerste verdieping | 1389 | 1110 | 0.024975 | 34690275 | 1541790
8393133 | Podium | 160 | 18647.9 | 0.419577 | 67132337 | 2983659
10826285 | 01 eerste verdieping | 239 | 3437.66 | 0.0773474 | 18486027 | 821601

# IfcWallStandardCase: Basic Wall:NLRS_41_WA_Geperforeerde plaat (4)
In: 01 eerste verdieping
Type - PredefinedType: STANDARD; Material: NLRS_f7_fermacel plaat 18 mm
Type - Pset_ConcreteElementGeneral - FireRating: -
Type - Pset_ElementShading - Roughness: 304.8 mm
Type - Pset_ManufacturerTypeInformation - Manufacturer: NTB
Type - Pset_ProductRequirements - Category: Walls
Type - Pset_QuantityTakeOff - Reference: Basic Wall:NLRS_41_WA_Geperforeerde plaat
Type - Pset_ReinforcementBarPitchOfWall - Description: Plaatmateriaal 18mm; Reference: Basic Wall:NLRS_41_WA_Geperforeerde plaat
Type - Pset_WallCommon - IsExternal: no; Reference: Basic Wall:NLRS_41_WA_Geperforeerde plaat; FireRating: -
Classification: 41.12 buitenwandafwerkingen; bekledingen (Uniformat)
BaseQuantities - Width: 18 mm
Pset_WallCommon - IsExternal: yes; ExtendToStructure: no; LoadBearing: no
Name (Basic Wall:NLRS_41_WA_Geperforeerde plaat:...) | Height (mm) | Length (mm) | GrossFootprintArea (m2) | NetVolume (m3) | NetSideArea (m2)
9495919 | 2830.3 | 11952.8 | 0.21515 | 608938435 | 33829913
9496502 | 3364.53 | 20949.5 | 0.377091 | 1268732450 | 70485136
9496919 | 2895 | 20949.5 | 0.377091 | 1091678445 | 60648803
9496982 | 2830.3 | 11913.5 | 0.214444 | 606940288 | 33718905

# IfcWallStandardCase: Basic Wall:NLRS_41_WA_Kantplank (3)
In: 00 begane grond
Type - PredefinedType: STANDARD; Material: NLRS_e_natuursteen 10 mm
Type - Pset_ConcreteElementGeneral - FireRating: -
Type - Pset_ElementShading - Roughness: 304.8 mm
Type - Pset_ManufacturerTypeInformation - Manufacturer: NTB
Type - Pset_ProductRequirements - Category: Walls
Type - Pset_QuantityTakeOff - Reference: Basic Wall:NLRS_41_WA_Kantplank
Type - Pset_ReinforcementBarPitchOfWall - Description: Plaatmateriaal 18mm; Reference: Basic Wall:NLRS_41_WA_Kantplank
Type - Pset_WallCommon - IsExternal: no; Reference: Basic Wall:NLRS_41_WA_Kantplank; FireRating: -
Classification: 41.12 buitenwandafwerkingen; bekledingen (Uniformat)
BaseQuantities - Width: 10 mm
Pset_WallCommon - IsExternal: yes; ExtendToStructure: no; LoadBearing: no
Name (Basic Wall:NLRS_41_WA_Kantplank:...) | Height (mm) | Length (mm) | GrossFootprintArea (m2) | NetVolume (m3) | NetSideArea (m2)
9231761 | 310 | 8215.48 | 0.0821548 | 25468000 | 2546800
9237888 | 310 | 7322.95 | 0.0732295 | 22701132 | 2270113
9237988 | 330 | 6944.76 | 0.0694476 | 22917717 | 2291772

# IfcWallStandardCase: Basic Wall:NLRS_41_WA_meubelpanelen (13)
In: 00 begane grond
Type - PredefinedType: STANDARD; Material: NLRS_i4_hout_underlayment 12 mm
Type - Pset_ConcreteElementGeneral - FireRating: -
Type - Pset_ElementShading - Roughness: 304.8 mm
Type - Pset_ManufacturerTypeInformation - Manufacturer: NTB
Type - Pset_ProductRequirements - Category: Walls
Type - Pset_QuantityTakeOff - Reference: Basic Wall:NLRS_41_WA_meubelpanelen
Type - Pset_ReinforcementBarPitchOfWall - Description: Plaatmateriaal 18mm; Reference: Basic Wall:NLRS_41_WA_meubelpanelen
Type - Pset_WallCommon - IsExternal: no; Reference: Basic Wall:NLRS_41_WA_meubelpanelen; FireRating: -
Classification: 41.12 buitenwandafwerkingen; bekledingen (Uniformat)
BaseQuantities - Height: 1010 mm; Width: 12 mm
Pset_WallCommon - IsExternal: yes; ExtendToStructure: no; LoadBearing: no
Name (Basic Wall:NLRS_41_WA_meubelpanelen:...) | Length (mm) | GrossFootprintArea (m2) | NetVolume (m3) | NetSideArea (m2)
12214798 | 68 | 0.000816 | 824160 | 68680
12215061 | 908.956 | 0.0109075 | 11016551 | 918046
12215260 | 158 | 0.001896 | 1914960 | 159580
12215518 | 908.75 | 0.010905 | 11014050 | 917838
12215578 | 183.072 | 0.00219686 | 2218829 | 184902
12215633 | 908.75 | 0.010905 | 11014050 | 917838
12215758 | 158 | 0.001896 | 1914960 | 159580
12215801 | 908.956 | 0.0109075 | 11016551 | 918046
12215939 | 78 | 0.000936 | 945360 | 78780
12228474 | 922 | 0.011064 | 11174640 | 931220
12228596 | 922.206 | 0.0110665 | 11177141 | 931428
12228690 | 922.206 | 0.0110665 | 11177141 | 931428
12228799 | 922 | 0.011064 | 11174640 | 931220

# IfcWallStandardCase: Basic Wall:NLRS_41_WA_plaatmateriaal 15mm RAL 9002 (36)
Type - PredefinedType: STANDARD; Material: AL_Multiplex RAL 9002 15 mm
Type - Pset_ConcreteElementGeneral - FireRating: -
Type - Pset_ElementShading - Roughness: 304.8 mm
Type - Pset_ManufacturerTypeInformation - Manufacturer: NTB
Type - Pset_ProductRequirements - Category: Walls
Type - Pset_QuantityTakeOff - Reference: Basic Wall:NLRS_41_WA_plaatmateriaal 15mm RAL 9002
Type - Pset_ReinforcementBarPitchOfWall - Description: Plaatmateriaal 18mm; Reference: Basic Wall:NLRS_41_WA_plaatmateriaal 15mm RAL 9002
Type - Pset_WallCommon - IsExternal: no; Reference: Basic Wall:NLRS_41_WA_plaatmateriaal 15mm RAL 9002; FireRating: -
Classification: 41.12 buitenwandafwerkingen; bekledingen (Uniformat)
BaseQuantities - Width: 15 mm
Pset_WallCommon - IsExternal: yes; ExtendToStructure: no; LoadBearing: no
Name (Basic Wall:NLRS_41_WA_plaatmateriaal 15mm RAL 9002:...) | In | Height (mm) | Length (mm) | GrossFootprintArea (m2) | NetVolume (m3) | NetSideArea (m2)
5749925 | 00 begane grond | 2700 | 374.909 | 0.00562364 | 15183829 | 1012255 | Group: Model Group:Bekleding kozijnen bestaande gebouw:5749187
7254015 | 00 begane grond | 1122 | 667 | 0.010005 | 11225610 | 748374
7746924 | 00 begane grond | 3364.63 | 167.274 | 0.00250911 | 8442245 | 562816
7746999 | 00 begane grond | 3368.44 | 171.307 | 0.00256961 | 8655591 | 577039
7760685 | 00 begane grond | 3436.6 | 162.365 | 0.00243547 | 8369737 | 557982
7856441 | 00 begane grond | 2462 | 194 | 0.00291 | 7164420 | 477628
7859261 | Podium | 368.098 | 7552.44 | 0.113287 | 41700569 | 2780038
7868151 | 00 begane grond | 2690 | 226.15 | 0.00339225 | 9125139 | 608343
7868395 | 00 begane grond | 2690 | 224.648 | 0.00336973 | 9064564 | 604304
7868966 | 00 begane grond | 2677.08 | 239.035 | 0.00358553 | 9598762 | 639917
7872161 | 00 begane grond | 2677.08 | 77.8809 | 0.00116821 | 3127405 | 208494
7879520 | 00 begane grond | 3432.39 | 162.421 | 0.00243631 | 8362358 | 557491
8116890 | 01 eerste verdieping | 1193 | 220 | 0.0033 | 3936900 | 262460
9114847 | 00 begane grond | 1640 | 279.578 | 0.00419367 | 6877619 | 458508
9488499 | 00 begane grond | 3245 | 221.305 | 0.00331958 | 10772037 | 718136
9489624 | 00 begane grond | 3245 | 221.305 | 0.00331958 | 10772037 | 718136
9490208 | 00 begane grond | 3245 | 22.6527 | 0.00033979 | 1102618 | 73507.9
9490459 | 00 begane grond | 3245 | 22.6527 | 0.00033979 | 1102618 | 73507.9
9490468 | 00 begane grond | 3245 | 22.6527 | 0.00033979 | 1102618 | 73507.9
9490477 | 00 begane grond | 3245 | 22.6527 | 0.00033979 | 1102618 | 73507.9
9765701 | 00 begane grond | 3315 | 221.305 | 0.00331958 | 11004407 | 733627
9766930 | 00 begane grond | 2700 | 18.3053 | 0.00027458 | 741366 | 49424.4
9767110 | 00 begane grond | 2700 | 19 | 0.000285 | 769500 | 51300
11272366 | 00 begane grond | 374.098 | 1980 | 0.0297 | 11110716 | 740714
11306904 | 00 begane grond | 461 | 1033.92 | 0.0155088 | 7149540 | 476636 | Group: Model Group:Bekleding kozijnen bestaande gebouw:5749187
11352361 | 00 begane grond | 2672 | 185 | 0.002775 | 7414800 | 494320
11352362 | 00 begane grond | 2685 | 185 | 0.002775 | 7450875 | 496725
11364007 | 00 begane grond | 2755 | 168 | 0.00252 | 6942600 | 462840
11365970 | 00 begane grond | 2755 | 228 | 0.00342 | 9422100 | 628140
11753117 | 00 begane grond | 2447 | 218 | 0.00327 | 8001690 | 533446
11753535 | 00 begane grond | 2447 | 233 | 0.003495 | 8552265 | 570151
11753723 | 00 begane grond | 2447 | 3243.58 | 0.0486537 | 119055507 | 7937034
11757676 | 00 begane grond | 1164 | 140 | 0.0021 | 2444400 | 162960
11758013 | 00 begane grond | 1164 | 140 | 0.0021 | 2444400 | 162960
11758067 | 00 begane grond | 1164 | 140 | 0.0021 | 2444400 | 162960
11758083 | 00 begane grond | 1164 | 140 | 0.0021 | 2444400 | 162960

# IfcWallStandardCase: Basic Wall:NLRS_41_WA_plaatmateriaal 15mm zwart, Basic Wall:NLRS_41_WA_plaatmateriaal 15mm zwart:6210043
In: 01 eerste verdieping
Type - PredefinedType: STANDARD; Material: NLRS_i4_hout_multiplex zwart 15 mm
Type - Pset_ConcreteElementGeneral - FireRating: -
Type - Pset_ElementShading - Roughness: 304.8 mm
Type - Pset_ManufacturerTypeInformation - Manufacturer: NTB
Type - Pset_ProductRequirements - Category: Walls
Type - Pset_QuantityTakeOff - Reference: Basic Wall:NLRS_41_WA_plaatmateriaal 15mm zwart
Type - Pset_ReinforcementBarPitchOfWall - Description: Plaatmateriaal 18mm; Reference: Basic Wall:NLRS_41_WA_plaatmateriaal 15mm zwart
Type - Pset_WallCommon - IsExternal: no; Reference: Basic Wall:NLRS_41_WA_plaatmateriaal 15mm zwart; FireRating: -
Classification: 41.12 buitenwandafwerkingen; bekledingen (Uniformat)
BaseQuantities - Height: 337.842 mm; Length: 4385 mm; Width: 15 mm; GrossFootprintArea: 0.065775 m2; NetVolume: 22221571 m3; NetSideArea: 1481438 m2
Pset_WallCommon - IsExternal: yes; ExtendToStructure: no; LoadBearing: no

# IfcWallStandardCase: Basic Wall:NLRS_41_WA_plaatmateriaal 18mm RAL 9002 (96)
Type - PredefinedType: STANDARD; Material: AL_Multiplex RAL 9002 18 mm
Type - Pset_ConcreteElementGeneral - FireRating: -
Type - Pset_ElementShading - Roughness: 304.8 mm
Type - Pset_ManufacturerTypeInformation - Manufacturer: NTB
Type - Pset_ProductRequirements - Category: Walls
Type - Pset_QuantityTakeOff - Reference: Basic Wall:NLRS_41_WA_plaatmateriaal 18mm RAL 9002
Type - Pset_ReinforcementBarPitchOfWall - Description: Plaatmateriaal 18mm; Reference: Basic Wall:NLRS_41_WA_plaatmateriaal 18mm RAL 9002
Type - Pset_WallCommon - IsExternal: no; Reference: Basic Wall:NLRS_41_WA_plaatmateriaal 18mm RAL 9002; FireRating: -
Classification: 41.12 buitenwandafwerkingen; bekledingen (Uniformat)
BaseQuantities - Width: 18 mm
Pset_WallCommon - IsExternal: yes; ExtendToStructure: no; LoadBearing: no
Name (Basic Wall:NLRS_41_WA_plaatmateriaal 18mm RAL 9002:...) | In | Height (mm) | Length (mm) | GrossFootprintArea (m2) | NetVolume (m3) | NetSideArea (m2)
7748081 | 00 begane grond | 3240 | 186.754 | 0.00336157 | 10891479 | 605082
7748146 | 00 begane grond | 3240 | 193.708 | 0.00348674 | 11297026 | 627613
7761570 | 00 begane grond | 3320 | 187 | 0.003366 | 11175120 | 620840
7761635 | 00 begane grond | 3280 | 187 | 0.003366 | 11040480 | 613360
7822071 | 00 begane grond | 1122 | 667 | 0.012006 | 13470732 | 748374
7856054 | 00 begane grond | 2757 | 231.5 | 0.004167 | 11488419 | 638246
7856257 | 00 begane grond | 2770 | 231.5 | 0.004167 | 11542590 | 641255
7856448 | 00 begane grond | 2462 | 194 | 0.003492 | 8597304 | 477628
7856683 | 00 begane grond | 2770 | 219 | 0.003942 | 10919340 | 606630
7858273 | 00 begane grond | 2757 | 228.5 | 0.004113 | 11339541 | 629975
7858429 | 00 begane grond | 2770 | 228.5 | 0.004113 | 11393010 | 632945
7858603 | 00 begane grond | 6032.93 | 193.751 | 0.00348752 | 21039941 | 1168886
7859984 | 00 begane grond | 6033.31 | 193.751 | 0.00348752 | 21041267 | 1168959
7868481 | 00 begane grond | 2690 | 229.268 | 0.00412683 | 11101163 | 616731
7868614 | 00 begane grond | 2690 | 228.748 | 0.00411747 | 11075996 | 615333
7930459 | 00 begane grond | 1192 | 194 | 0.003492 | 4162464 | 231248
7930460 | 00 begane grond | 1192 | 194 | 0.003492 | 4162464 | 231248
7930483 | 00 begane grond | 1192 | 194 | 0.003492 | 4162464 | 231248
7930484 | 00 begane grond | 1192 | 194 | 0.003492 | 4162464 | 231248
8036534 | 00 begane grond | 2690 | 213.239 | 0.00383829 | 10325010 | 573612
8116998 | 01 eerste verdieping | 1193 | 220 | 0.00396 | 4724280 | 262460
8117057 | 01 eerste verdieping | 1174 | 220 | 0.00396 | 4649040 | 258280
8117058 | 01 eerste verdieping | 1174 | 220 | 0.00396 | 4649040 | 258280
8117067 | 01 eerste verdieping | 1593 | 220 | 0.00396 | 6308280 | 350460
8117068 | 01 eerste verdieping | 1593 | 220 | 0.00396 | 6308280 | 350460
8117077 | 01 eerste verdieping | 1177 | 220 | 0.00396 | 4660920 | 258940
8117078 | 01 eerste verdieping | 1177 | 220 | 0.00396 | 4660920 | 258940
8117087 | 01 eerste verdieping | 1174 | 220 | 0.00396 | 4649040 | 258280
8117088 | 01 eerste verdieping | 1174 | 220 | 0.00396 | 4649040 | 258280
8151858 | 00 begane grond | 2856 | 75 | 0.00135 | 3855600 | 214200
8152725 | 00 begane grond | 2812 | 158.797 | 0.00285834 | 8037661 | 446537
8152861 | 00 begane grond | 2700 | 224.693 | 0.00404447 | 10920071 | 606671
8153038 | 00 begane grond | 2856 | 228 | 0.004104 | 11721024 | 651168
9114370 | 00 begane grond | 1221 | 279.578 | 0.0050324 | 6144565 | 341365
9114552 | 00 begane grond | 1203 | 279.578 | 0.0050324 | 6053982 | 336332
9114714 | 00 begane grond | 1233 | 279.578 | 0.0050324 | 6204954 | 344720
9114722 | 00 begane grond | 1233 | 279.578 | 0.0050324 | 6204954 | 344720
9114739 | 00 begane grond | 1640 | 279.578 | 0.0050324 | 8253142 | 458508
9114747 | 00 begane grond | 1640 | 279.578 | 0.0050324 | 8253142 | 458508
9114764 | 00 begane grond | 682 | 279.578 | 0.0050324 | 3432099 | 190672
9114772 | 00 begane grond | 682 | 279.578 | 0.0050324 | 3432099 | 190672
9114789 | 00 begane grond | 1236 | 279.578 | 0.0050324 | 6220051 | 345558
9114797 | 00 begane grond | 1236 | 279.578 | 0.0050324 | 6220051 | 345558
9114814 | 00 begane grond | 1640 | 279.578 | 0.0050324 | 8253142 | 458508
9114822 | 00 begane grond | 1640 | 279.578 | 0.0050324 | 8253142 | 458508
9114839 | 00 begane grond | 1640 | 279.578 | 0.0050324 | 8253142 | 458508
9115372 | 00 begane grond | 664 | 279.578 | 0.0050324 | 3341516 | 185640
9115380 | 00 begane grond | 664 | 279.578 | 0.0050324 | 3341516 | 185640
9312987 | 00 begane grond | 1415 | 194 | 0.003492 | 4941180 | 274510
9312988 | 00 begane grond | 1415 | 194 | 0.003492 | 4941180 | 274510
9313253 | 00 begane grond | 1415 | 194 | 0.003492 | 4941180 | 274510
9313254 | 00 begane grond | 1415 | 194 | 0.003492 | 4941180 | 274510
9313307 | 00 begane grond | 1415 | 194 | 0.003492 | 4941180 | 274510
9313308 | 00 begane grond | 1415 | 194 | 0.003492 | 4941180 | 274510
9313337 | 00 begane grond | 1415 | 194 | 0.003492 | 4941180 | 274510
9313338 | 00 begane grond | 1415 | 194 | 0.003492 | 4941180 | 274510
9453578 | 00 begane grond | 1415.6 | 194 | 0.003492 | 4943275 | 274626
9453579 | 00 begane grond | 1415.6 | 194 | 0.003492 | 4943275 | 274626
9673748 | 00 begane grond | 2690 | 218.583 | 0.00393449 | 10583774 | 587987
9673749 | 00 begane grond | 2690 | 216.041 | 0.00388874 | 10460704 | 581150
9673883 | 00 begane grond | 2690 | 218.582 | 0.00393448 | 10583750 | 587986
9673884 | 00 begane grond | 2690 | 217.533 | 0.00391559 | 10532940 | 585163
9725241 | Podium | 2429.86 | 187.5 | 0.003375 | 8200773 | 455598
9821176 | 01 eerste verdieping | 2640.08 | 7279.59 | 0.131033 | 345937052 | 19218725
9822941 | 00 begane grond | 2690 | 221.608 | 0.00398894 | 10730257 | 596125
9823116 | 00 begane grond | 2690 | 204 | 0.003672 | 9877680 | 548760
9823237 | 00 begane grond | 2690 | 37 | 0.000666 | 1791540 | 99530
9823447 | 00 begane grond | 2690 | 230 | 0.00414 | 11136600 | 618700
9823587 | 00 begane grond | 2690 | 61.3445 | 0.0011042 | 2970300 | 165017
9823724 | 00 begane grond | 2690 | 222.118 | 0.00399812 | 10754942 | 597497
9823842 | 00 begane grond | 2690 | 51.1161 | 0.00092009 | 2475042 | 137502
9830160 | 00 begane grond | 334 | 4826.81 | 0.0868825 | 29018767 | 1612154
9830195 | 00 begane grond | 456 | 2219.9 | 0.0399581 | 18220904 | 1012272
9830633 | 00 begane grond | 456 | 625.873 | 0.0112657 | 5137167 | 285398
10235795 | 00 begane grond | 2770 | 194 | 0.003492 | 9672840 | 537380
10235901 | 00 begane grond | 2770 | 194 | 0.003492 | 9672840 | 537380
10239522 | 00 begane grond | 2770 | 194 | 0.003492 | 9672840 | 537380
10239533 | 00 begane grond | 2770 | 194 | 0.003492 | 9672840 | 537380
10269606 | 00 begane grond | 1207.9 | 194 | 0.003492 | 4217987 | 234333
10269607 | 00 begane grond | 1207.9 | 194 | 0.003492 | 4217987 | 234333
10269973 | 00 begane grond | 1208 | 194 | 0.003492 | 4218336 | 234352
10269974 | 00 begane grond | 1208 | 194 | 0.003492 | 4218336 | 234352
10270000 | 00 begane grond | 1207.9 | 194 | 0.003492 | 4217987 | 234333
10270001 | 00 begane grond | 1207.9 | 194 | 0.003492 | 4217987 | 234333
10270027 | 00 begane grond | 1207.9 | 194 | 0.003492 | 4217987 | 234333
10270028 | 00 begane grond | 1207.9 | 194 | 0.003492 | 4217987 | 234333
11245673 | 00 begane grond | 354 | 4526.81 | 0.0814825 | 28844817 | 1602490
11245809 | 00 begane grond | 354 | 1529.83 | 0.027537 | 9748091 | 541561
11364008 | 00 begane grond | 2755 | 168 | 0.003024 | 8331120 | 462840
11365971 | 00 begane grond | 2755 | 228 | 0.004104 | 11306520 | 628140
12000220 | 00 begane grond | 1210 | 194 | 0.003492 | 4225320 | 234740
12000221 | 00 begane grond | 1210 | 194 | 0.003492 | 4225320 | 234740
12000447 | 00 begane grond | 1210.18 | 194 | 0.003492 | 4225951 | 234775
12000448 | 00 begane grond | 1210 | 194 | 0.003492 | 4225320 | 234740
12000477 | 00 begane grond | 1210 | 194 | 0.003492 | 4225320 | 234740
12000478 | 00 begane grond | 1210 | 194 | 0.003492 | 4225320 | 234740

# IfcWallStandardCase: Basic Wall:NLRS_41_WA_plaatmateriaal 18mm zwart (2)
In: 01 eerste verdieping
Type - PredefinedType: STANDARD; Material: NLRS_i4_hout_multiplex zwart 18 mm
Type - Pset_ConcreteElementGeneral - FireRating: -
Type - Pset_ElementShading - Roughness: 304.8 mm
Type - Pset_ManufacturerTypeInformation - Manufacturer: NTB
Type - Pset_ProductRequirements - Category: Walls
Type - Pset_QuantityTakeOff - Reference: Basic Wall:NLRS_41_WA_plaatmateriaal 18mm zwart
Type - Pset_ReinforcementBarPitchOfWall - Description: Plaatmateriaal 18mm; Reference: Basic Wall:NLRS_41_WA_plaatmateriaal 18mm zwart
Type - Pset_WallCommon - IsExternal: no; Reference: Basic Wall:NLRS_41_WA_plaatmateriaal 18mm zwart; FireRating: -
Classification: 41.12 buitenwandafwerkingen; bekledingen (Uniformat)
BaseQuantities - Width: 18 mm
Pset_WallCommon - IsExternal: yes; ExtendToStructure: no; LoadBearing: no
Name (Basic Wall:NLRS_41_WA_plaatmateriaal 18mm zwart:...) | Height (mm) | Length (mm) | GrossFootprintArea (m2) | NetVolume (m3) | NetSideArea (m2)
6209216 | 2398 | 6863.68 | 0.123546 | 296264074 | 16459115
10005763 | 2704 | 7307.3 | 0.131531 | 355660946 | 19758941

# IfcWallStandardCase: Basic Wall:NLRS_41_WA_plaatmateriaal 18mm_gen_aly (55)
Type - PredefinedType: STANDARD; Material: NLRS_i4_hout_multiplex 18 mm
Type - Pset_ConcreteElementGeneral - FireRating: -
Type - Pset_ElementShading - Roughness: 304.8 mm
Type - Pset_ManufacturerTypeInformation - Manufacturer: NTB
Type - Pset_ProductRequirements - Category: Walls
Type - Pset_QuantityTakeOff - Reference: Basic Wall:NLRS_41_WA_plaatmateriaal 18mm_gen_aly
Type - Pset_ReinforcementBarPitchOfWall - Description: Plaatmateriaal 18mm; Reference: Basic Wall:NLRS_41_WA_plaatmateriaal 18mm_gen_aly
Type - Pset_WallCommon - IsExternal: no; Reference: Basic Wall:NLRS_41_WA_plaatmateriaal 18mm_gen_aly; FireRating: -
Classification: 41.12 buitenwandafwerkingen; bekledingen (Uniformat)
BaseQuantities - Width: 18 mm
Pset_WallCommon - IsExternal: yes; ExtendToStructure: no; LoadBearing: no
Name (Basic Wall:NLRS_41_WA_plaatmateriaal 18mm_gen_aly:...) | In | Height (mm) | Length (mm) | GrossFootprintArea (m2) | NetVolume (m3) | NetSideArea (m2)
3413605 | 00 begane grond | 2807 | 920 | 0.01656 | 46483920 | 2582440
4608787 | 00 begane grond | 1190 | 1104.25 | 0.0198765 | 23653083 | 1314060
4608857 | 00 begane grond | 1190 | 181 | 0.003258 | 3877020 | 215390
4620759 | 00 begane grond | 1190 | 999.917 | 0.0179985 | 21418227 | 1189902
4620905 | 00 begane grond | 1190 | 909.917 | 0.0163785 | 19490427 | 1082802
5012279 | 00 begane grond | 1190 | 1043.24 | 0.0187784 | 22346266 | 1241459
5012413 | 00 begane grond | 1190 | 1043.24 | 0.0187784 | 22346266 | 1241459
5012452 | 00 begane grond | 1190 | 909.929 | 0.0163787 | 19490678 | 1082815
5012556 | 00 begane grond | 1190 | 909.102 | 0.0163638 | 19472970 | 1081832
5748083 | 00 begane grond | 2700 | 367 | 0.006606 | 17836200 | 990900 | Group: Model Group:Bekleding kozijnen bestaande gebouw:5749187
5748450 | 00 begane grond | 2700 | 367 | 0.006606 | 17836200 | 990900 | Group: Model Group:Bekleding kozijnen bestaande gebouw:5749187
5748891 | 00 begane grond | 2405 | 315 | 0.00567 | 13636350 | 757575 | Group: Model Group:Bekleding kozijnen bestaande gebouw:5749187
5748900 | 00 begane grond | 2405 | 315 | 0.00567 | 13636350 | 757575 | Group: Model Group:Bekleding kozijnen bestaande gebouw:5749187
5749227 | 00 begane grond | 2700 | 376.628 | 0.00677931 | 18304138 | 1016897 | Group: Model Group:Bekleding kozijnen bestaande gebouw:5749187
5749603 | 00 begane grond | 2700 | 376.628 | 0.00677931 | 18304138 | 1016897 | Group: Model Group:Bekleding kozijnen bestaande gebouw:5749187
5749934 | 00 begane grond | 2700 | 380.696 | 0.00685252 | 18501814 | 1027879 | Group: Model Group:Bekleding kozijnen bestaande gebouw:5749187
6153595 | 01 eerste verdieping | 1965.3 | 802.408 | 0.0144433 | 28385554 | 1576975
6153655 | 01 eerste verdieping | 1965.3 | 803.408 | 0.0144613 | 28420929 | 1578941
6197604 | 01 eerste verdieping | 2870 | 147.038 | 0.00264669 | 7596008 | 422000
6569468 | 01 eerste verdieping | 2970 | 140 | 0.00252 | 7484400 | 415800
7317443 | 00 begane grond | 822.114 | 6893.56 | 0.124084 | 102011186 | 5667288
7769374 | 00 begane grond | 2807 | 140 | 0.00252 | 7073640 | 392980
7769680 | 00 begane grond | 2807 | 140 | 0.00252 | 7073640 | 392980
7769791 | 00 begane grond | 2807 | 140 | 0.00252 | 7073640 | 392980
7795925 | 00 begane grond | 1190 | 1070 | 0.01926 | 22919400 | 1273300
7796057 | 00 begane grond | 1190 | 1060 | 0.01908 | 22705200 | 1261400
7796066 | 00 begane grond | 1190 | 1060 | 0.01908 | 22705200 | 1261400
7796615 | 00 begane grond | 1190 | 1060 | 0.01908 | 22705200 | 1261400
7796864 | 00 begane grond | 1190 | 1060 | 0.01908 | 22705200 | 1261400
7796873 | 00 begane grond | 1190 | 1070 | 0.01926 | 22919400 | 1273300
8027803 | 01 eerste verdieping | 2970 | 140 | 0.00252 | 7484400 | 415800
8027988 | 01 eerste verdieping | 2970 | 140 | 0.00252 | 7484400 | 415800
8028473 | 01 eerste verdieping | 2970 | 140 | 0.00252 | 7484400 | 415800
8028889 | 01 eerste verdieping | 2970 | 140 | 0.00252 | 7484400 | 415800
8028977 | 01 eerste verdieping | 2970 | 140 | 0.00252 | 7484400 | 415800
8029141 | 01 eerste verdieping | 2970 | 90.682 | 0.00163228 | 4847859 | 269326
8067872 | 01 eerste verdieping | 248 | 3926.75 | 0.0706816 | 17529028 | 973835
8067962 | 01 eerste verdieping | 248 | 3346.96 | 0.0602453 | 14940843 | 830047
8068078 | 01 eerste verdieping | 248 | 844.219 | 0.0151959 | 3768594 | 209366
8160169 | 00 begane grond | 2977 | 123.5 | 0.002223 | 6617871 | 367660
8160434 | 00 begane grond | 2977 | 123.5 | 0.002223 | 6617871 | 367660
8160485 | 00 begane grond | 2977 | 100.162 | 0.00180291 | 5367273 | 298182
8160893 | 00 begane grond | 2760 | 135 | 0.00243 | 6706800 | 372600
9247836 | 00 begane grond | 1120 | 1075.32 | 0.0193558 | 21678479 | 1204360
9248012 | 00 begane grond | 1120 | 1078.58 | 0.0194145 | 21744199 | 1208011
10061745 | 00 begane grond | 1190 | 1104.25 | 0.0198765 | 23653083 | 1314060
10061753 | 00 begane grond | 1190 | 181 | 0.003258 | 3877020 | 215390
10358848 | 00 begane grond | 1190 | 1063.25 | 0.0191385 | 22774863 | 1265270
10358912 | 00 begane grond | 1190 | 1063.25 | 0.0191385 | 22774863 | 1265270
10358932 | 00 begane grond | 1190 | 1063.25 | 0.0191385 | 22774863 | 1265270
10358952 | 00 begane grond | 1190 | 1063.25 | 0.0191385 | 22774863 | 1265270
10359006 | 00 begane grond | 1190 | 1034 | 0.018612 | 22148280 | 1230460
10359046 | 00 begane grond | 1190 | 1063.25 | 0.0191385 | 22774863 | 1265270
10359066 | 00 begane grond | 1190 | 1063.25 | 0.0191385 | 22774863 | 1265270
11344278 | 00 begane grond | 181 | 1033.92 | 0.0186105 | 3368504 | 187139 | Group: Model Group:Bekleding kozijnen bestaande gebouw:5749187

# IfcWallStandardCase: Basic Wall:NLRS_41_WA_plaatmateriaal 22mm RAL 9002 (6)
In: 00 begane grond
Type - PredefinedType: STANDARD; Material: AL_Multiplex RAL 9002 22 mm
Type - Pset_ConcreteElementGeneral - FireRating: -
Type - Pset_ElementShading - Roughness: 304.8 mm
Type - Pset_ManufacturerTypeInformation - Manufacturer: NTB
Type - Pset_ProductRequirements - Category: Walls
Type - Pset_QuantityTakeOff - Reference: Basic Wall:NLRS_41_WA_plaatmateriaal 22mm RAL 9002
Type - Pset_ReinforcementBarPitchOfWall - Description: Plaatmateriaal 18mm; Reference: Basic Wall:NLRS_41_WA_plaatmateriaal 22mm RAL 9002
Type - Pset_WallCommon - IsExternal: no; Reference: Basic Wall:NLRS_41_WA_plaatmateriaal 22mm RAL 9002; FireRating: -
Classification: 41.12 buitenwandafwerkingen; bekledingen (Uniformat)
BaseQuantities - Width: 22 mm
Pset_WallCommon - IsExternal: yes; ExtendToStructure: no; LoadBearing: no
Name (Basic Wall:NLRS_41_WA_plaatmateriaal 22mm RAL 9002:...) | Height (mm) | Length (mm) | GrossFootprintArea (m2) | NetVolume (m3) | NetSideArea (m2)
9487321 | 3245 | 143 | 0.003146 | 10208770 | 464035
9488264 | 3245 | 143 | 0.003146 | 10208770 | 464035
9489622 | 3245 | 143 | 0.003146 | 10208770 | 464035
9489623 | 3245 | 143 | 0.003146 | 10208770 | 464035
9765699 | 3315 | 138 | 0.003036 | 10064340 | 457470
9765700 | 3315 | 138 | 0.003036 | 10064340 | 457470

# IfcWallStandardCase: Basic Wall:NLRS_41_WA_plaatmateriaal 9mm RAL 9002 (8)
In: 00 begane grond
Type - PredefinedType: STANDARD; Material: ZZ_00_Kleur_RAL 9002 9 mm
Type - Pset_ConcreteElementGeneral - FireRating: -
Type - Pset_ElementShading - Roughness: 304.8 mm
Type - Pset_ManufacturerTypeInformation - Manufacturer: NTB
Type - Pset_ProductRequirements - Category: Walls
Type - Pset_QuantityTakeOff - Reference: Basic Wall:NLRS_41_WA_plaatmateriaal 9mm RAL 9002
Type - Pset_ReinforcementBarPitchOfWall - Description: Plaatmateriaal 18mm; Reference: Basic Wall:NLRS_41_WA_plaatmateriaal 9mm RAL 9002
Type - Pset_WallCommon - IsExternal: no; Reference: Basic Wall:NLRS_41_WA_plaatmateriaal 9mm RAL 9002; FireRating: -
Classification: 41.12 buitenwandafwerkingen; bekledingen (Uniformat)
BaseQuantities - Width: 9 mm
Pset_WallCommon - IsExternal: yes; ExtendToStructure: no; LoadBearing: no
Name (Basic Wall:NLRS_41_WA_plaatmateriaal 9mm RAL 9002:...) | Height (mm) | Length (mm) | GrossFootprintArea (m2) | NetVolume (m3) | NetSideArea (m2)
7856797 | 362.092 | 3051.87 | 0.0274668 | 9945508 | 1105056
7856847 | 337.011 | 3870.32 | 0.0348329 | 11739043 | 1304338
9052939 | 2807 | 154.5 | 0.0013905 | 3903133 | 433681
9052957 | 2807 | 145.5 | 0.0013095 | 3675767 | 408419
9054559 | 2926 | 334.5 | 0.0030105 | 8808723 | 978747
9054560 | 2926 | 165.5 | 0.0014895 | 4358277 | 484253
9490557 | 3245 | 206 | 0.001854 | 6016230 | 668470
9490650 | 3245 | 206 | 0.001854 | 6016230 | 668470

# IfcWallStandardCase: Basic Wall:NLRS_41_WA_plaatmateriaal 9mm zwart, Basic Wall:NLRS_41_WA_plaatmateriaal 9mm zwart:9448329
In: 00 begane grond
Type - PredefinedType: STANDARD; Material: ZZ_00_Kleur_RAL 9005 9 mm
Type - Pset_ConcreteElementGeneral - FireRating: -
Type - Pset_ElementShading - Roughness: 304.8 mm
Type - Pset_ManufacturerTypeInformation - Manufacturer: NTB
Type - Pset_ProductRequirements - Category: Walls
Type - Pset_QuantityTakeOff - Reference: Basic Wall:NLRS_41_WA_plaatmateriaal 9mm zwart
Type - Pset_ReinforcementBarPitchOfWall - Description: Plaatmateriaal 18mm; Reference: Basic Wall:NLRS_41_WA_plaatmateriaal 9mm zwart
Type - Pset_WallCommon - IsExternal: no; Reference: Basic Wall:NLRS_41_WA_plaatmateriaal 9mm zwart; FireRating: -
Classification: 41.12 buitenwandafwerkingen; bekledingen (Uniformat)
BaseQuantities - Height: 1377.55 mm; Length: 922.469 mm; Width: 9 mm; GrossFootprintArea: 0.00830222 m2; NetVolume: 11436729 m3; NetSideArea: 1270748 m2
Pset_WallCommon - IsExternal: yes; ExtendToStructure: no; LoadBearing: no

# IfcWallStandardCase: Basic Wall:NLRS_41_WA_plaatmateriaal 9mm zwart 2, Basic Wall:NLRS_41_WA_plaatmateriaal 9mm zwart 2:8940893
In: 00 begane grond
Type - PredefinedType: STANDARD; Material: ZZ_00_Kleur_RAL 9005 (2) 9 mm
Type - Pset_ConcreteElementGeneral - FireRating: -
Type - Pset_ElementShading - Roughness: 304.8 mm
Type - Pset_ManufacturerTypeInformation - Manufacturer: NTB
Type - Pset_ProductRequirements - Category: Walls
Type - Pset_QuantityTakeOff - Reference: Basic Wall:NLRS_41_WA_plaatmateriaal 9mm zwart 2
Type - Pset_ReinforcementBarPitchOfWall - Description: Plaatmateriaal 18mm; Reference: Basic Wall:NLRS_41_WA_plaatmateriaal 9mm zwart 2
Type - Pset_WallCommon - IsExternal: no; Reference: Basic Wall:NLRS_41_WA_plaatmateriaal 9mm zwart 2; FireRating: -
Classification: 41.12 buitenwandafwerkingen; bekledingen (Uniformat)
BaseQuantities - Height: 2400 mm; Length: 5350 mm; Width: 9 mm; GrossFootprintArea: 0.04815 m2; NetVolume: 115560000 m3; NetSideArea: 12840000 m2
Pset_WallCommon - IsExternal: yes; ExtendToStructure: no; LoadBearing: no

# IfcWallStandardCase: Basic Wall:NLRS_41_WA_plaatmateriaal 9mm_gen_aly (33)
Type - PredefinedType: STANDARD; Material: NLRS_i4_hout_multiplex wit 9 mm
Type - Pset_ConcreteElementGeneral - FireRating: -
Type - Pset_ElementShading - Roughness: 304.8 mm
Type - Pset_ManufacturerTypeInformation - Manufacturer: NTB
Type - Pset_ProductRequirements - Category: Walls
Type - Pset_QuantityTakeOff - Reference: Basic Wall:NLRS_41_WA_plaatmateriaal 9mm_gen_aly
Type - Pset_ReinforcementBarPitchOfWall - Description: Plaatmateriaal 18mm; Reference: Basic Wall:NLRS_41_WA_plaatmateriaal 9mm_gen_aly
Type - Pset_WallCommon - IsExternal: no; Reference: Basic Wall:NLRS_41_WA_plaatmateriaal 9mm_gen_aly; FireRating: -
Classification: 41.12 buitenwandafwerkingen; bekledingen (Uniformat)
BaseQuantities - Width: 9 mm
Pset_WallCommon - IsExternal: yes; ExtendToStructure: no; LoadBearing: no
Name (Basic Wall:NLRS_41_WA_plaatmateriaal 9mm_gen_aly:...) | In | Height (mm) | Length (mm) | GrossFootprintArea (m2) | NetVolume (m3) | NetSideArea (m2)
6197673 | 01 eerste verdieping | 2870 | 146.016 | 0.00131415 | 3771596 | 419066
6197746 | 01 eerste verdieping | 2870 | 145.996 | 0.00131396 | 3771067 | 419007
6197819 | 01 eerste verdieping | 2870 | 143.933 | 0.0012954 | 3717802 | 413089
6197911 | 01 eerste verdieping | 2870 | 144.496 | 0.00130046 | 3732331 | 414703
6198014 | 01 eerste verdieping | 2870 | 145.704 | 0.00131134 | 3763539 | 418171
6198128 | 01 eerste verdieping | 2870 | 145 | 0.001305 | 3745350 | 416150
6198193 | 01 eerste verdieping | 2870 | 146.559 | 0.00131903 | 3785612 | 420624
6198272 | 01 eerste verdieping | 2870 | 145.808 | 0.00131227 | 3766217 | 418469
6198338 | 01 eerste verdieping | 2870 | 146.376 | 0.00131738 | 3780881 | 420098
6198402 | 01 eerste verdieping | 2870 | 143.291 | 0.00128962 | 3701217 | 411246
6198462 | 01 eerste verdieping | 2870 | 143.852 | 0.00129467 | 3715690 | 412854
6198546 | 01 eerste verdieping | 2870 | 147.093 | 0.00132384 | 3799422 | 422158
7818683 | 00 begane grond | 2924.6 | 140 | 0.00126 | 3684999 | 409444
7821973 | 00 begane grond | 1140 | 226 | 0.002034 | 2318760 | 257640
7822279 | 00 begane grond | 3999.06 | 140 | 0.00126 | 5038817 | 559869
7822726 | 00 begane grond | 140 | 3985 | 0.035865 | 5021100 | 557900
7853044 | 00 begane grond | 2758.32 | 182.318 | 0.00164086 | 4526029 | 502892
7853380 | 00 begane grond | 2758.32 | 140 | 0.00126 | 3475488 | 386165
7853733 | 00 begane grond | 2828.32 | 140.682 | 0.00126614 | 3581049 | 397894
7893544 | 00 begane grond | 1140 | 238.75 | 0.00214875 | 2449575 | 272175
8187902 | 00 begane grond | 3077 | 122.5 | 0.0011025 | 3392393 | 376933
8188084 | 00 begane grond | 3077 | 137.5 | 0.0012375 | 3807788 | 423088
8194947 | 00 begane grond | 2856 | 197.184 | 0.00177466 | 5068428 | 563159
8195066 | 00 begane grond | 2856 | 197.184 | 0.00177466 | 5068428 | 563159
8195195 | 00 begane grond | 2856 | 53 | 0.000477 | 1362312 | 151368
8195353 | 00 begane grond | 2856 | 53 | 0.000477 | 1362312 | 151368
8939360 | 00 begane grond | 4212 | 18442.6 | 0.165983 | 699121425 | 77680158
8941143 | 00 begane grond | 2700 | 220 | 0.00198 | 5346000 | 594000
8941271 | 00 begane grond | 2700 | 220 | 0.00198 | 5346000 | 594000
8996396 | 00 begane grond | 2786.21 | 186.151 | 0.00167536 | 4667916 | 518657
8996474 | 00 begane grond | 2786.21 | 186.506 | 0.00167856 | 4676817 | 519646
9445491 | 01 eerste verdieping | 3063 | 1750.51 | 0.0157546 | 48256321 | 5361813
9446395 | 01 eerste verdieping | 2436.79 | 337.807 | 0.00304026 | 7408490 | 823166

# IfcWallStandardCase: Basic Wall:NLRS_41_geïsoleerde kantplank (3)
In: 01 eerste verdieping
Type - PredefinedType: STANDARD; Material: NLRS_n7_isolatie PIR_gen 140 mm, NLRS_e_natuursteen 10 mm
Type - Pset_ConcreteElementGeneral - FireRating: -
Type - Pset_ElementShading - Roughness: 304.8 mm
Type - Pset_ManufacturerTypeInformation - Manufacturer: NTB
Type - Pset_ProductRequirements - Category: Walls
Type - Pset_QuantityTakeOff - Reference: Basic Wall:NLRS_41_geïsoleerde kantplank
Type - Pset_ReinforcementBarPitchOfWall - Description: Plaatmateriaal 18mm; Reference: Basic Wall:NLRS_41_geïsoleerde kantplank
Type - Pset_WallCommon - IsExternal: no; Reference: Basic Wall:NLRS_41_geïsoleerde kantplank; FireRating: -
Classification: 41.12 buitenwandafwerkingen; bekledingen (Uniformat)
BaseQuantities - Width: 150 mm
Pset_WallCommon - IsExternal: yes; ExtendToStructure: no; LoadBearing: no
Name (Basic Wall:NLRS_41_geïsoleerde kantplank:...) | Height (mm) | Length (mm) | GrossFootprintArea (m2) | NetVolume (m3) | NetSideArea (m2)
6425837 | 637.889 | 16071.9 | 2.41078 | 1537809752 | 10252065
10541799 | 429.576 | 18535.4 | 2.78031 | 1194355961 | 7962373
10542297 | 492.5 | 9634.36 | 1.44515 | 711738579 | 4744924

# IfcWallStandardCase: Basic Wall:NLRS_42_WA_Houten gevelbekleding liggend 26mm (6)
Type - PredefinedType: STANDARD; Material: AL Houten gevelbekleding liggend 26 mm
Type - Pset_ConcreteElementGeneral - FireRating: -
Type - Pset_ElementShading - Roughness: 304.8 mm
Type - Pset_ManufacturerTypeInformation - Manufacturer: NTB
Type - Pset_ProductRequirements - Category: Walls
Type - Pset_QuantityTakeOff - Reference: Basic Wall:NLRS_42_WA_Houten gevelbekleding liggend 26mm
Type - Pset_ReinforcementBarPitchOfWall - Description: Plaatmateriaal 18mm; Reference: Basic Wall:NLRS_42_WA_Houten gevelbekleding liggend 26mm
Type - Pset_WallCommon - IsExternal: no; Reference: Basic Wall:NLRS_42_WA_Houten gevelbekleding liggend 26mm; FireRating: -
Classification: 42.12 binnenwandafwerkingen; bekledingen (Uniformat)
BaseQuantities - Width: 26 mm
Pset_WallCommon - ExtendToStructure: no; LoadBearing: no
Name (Basic Wall:NLRS_42_WA_Houten gevelbekleding liggend 26mm:...) | In | Height (mm) | Length (mm) | GrossFootprintArea (m2) | NetVolume (m3) | NetSideArea (m2)
3178170 | 00 begane grond | 1672 | 8737.5 | 0.227175 | 379836600 | 14609100
3481206 | 00 begane grond | 370 | 970.04 | 0.025221 | 9331787 | 358915
3481452 | 00 begane grond | 370 | 969.46 | 0.025206 | 9326206 | 358700
4243777 | 01 eerste verdieping | 2516.6 | 969.46 | 0.025206 | 63433329 | 2439743
4247159 | 01 eerste verdieping | 730.434 | 970.041 | 0.0252211 | 18422313 | 708550
4552235 | 00 begane grond | 1672 | 3811.53 | 0.0990997 | 165694664 | 6372872

# IfcWallStandardCase: Basic Wall:NLRS_42_WA_Houten gevelbekleding staand 18mm, Basic Wall:NLRS_42_WA_Houten gevelbekleding staand 18mm:4445643
In: 00 begane grond
Type - PredefinedType: STANDARD; Material: AL Houten gevelbekleding staand 18 mm
Type - Pset_ConcreteElementGeneral - FireRating: -
Type - Pset_ElementShading - Roughness: 304.8 mm
Type - Pset_ManufacturerTypeInformation - Manufacturer: NTB
Type - Pset_ProductRequirements - Category: Walls
Type - Pset_QuantityTakeOff - Reference: Basic Wall:NLRS_42_WA_Houten gevelbekleding staand 18mm
Type - Pset_ReinforcementBarPitchOfWall - Description: Plaatmateriaal 18mm; Reference: Basic Wall:NLRS_42_WA_Houten gevelbekleding staand 18mm
Type - Pset_WallCommon - IsExternal: no; Reference: Basic Wall:NLRS_42_WA_Houten gevelbekleding staand 18mm; FireRating: -
Classification: 42.12 binnenwandafwerkingen; bekledingen (Uniformat)
BaseQuantities - Height: 2841.15 mm; Length: 2875.65 mm; Width: 18 mm; GrossFootprintArea: 0.0517617 m2; NetVolume: 147062582 m3; NetSideArea: 8170143 m2
Pset_WallCommon - ExtendToStructure: no; LoadBearing: no

# IfcWallStandardCase: Basic Wall:NLRS_42_WA_Houten gevelbekleding staand 20mm (39)
Type - PredefinedType: STANDARD; Material: AL Houten gevelbekleding staand 20 mm
Type - Pset_ConcreteElementGeneral - FireRating: -
Type - Pset_ElementShading - Roughness: 304.8 mm
Type - Pset_ManufacturerTypeInformation - Manufacturer: NTB
Type - Pset_ProductRequirements - Category: Walls
Type - Pset_QuantityTakeOff - Reference: Basic Wall:NLRS_42_WA_Houten gevelbekleding staand 20mm
Type - Pset_ReinforcementBarPitchOfWall - Description: Plaatmateriaal 18mm; Reference: Basic Wall:NLRS_42_WA_Houten gevelbekleding staand 20mm
Type - Pset_WallCommon - IsExternal: no; Reference: Basic Wall:NLRS_42_WA_Houten gevelbekleding staand 20mm; FireRating: -
Classification: 42.12 binnenwandafwerkingen; bekledingen (Uniformat)
BaseQuantities - Width: 20 mm
Pset_WallCommon - ExtendToStructure: no; LoadBearing: no
Name (Basic Wall:NLRS_42_WA_Houten gevelbekleding staand 20mm:...) | In | Height (mm) | Length (mm) | GrossFootprintArea (m2) | NetVolume (m3) | NetSideArea (m2)
3159194 | 01 eerste verdieping | 2973 | 18950.2 | 0.379004 | 1126777577 | 56338879
3160219 | 01 eerste verdieping | 3425.9 | 2622 | 0.05244 | 179654362 | 8982718
3274684 | 01 eerste verdieping | 2483.2 | 7559.47 | 0.151189 | 375432916 | 18771646
3844539 | 01 eerste verdieping | 1275 | 15132 | 0.30264 | 385866000 | 19293300
4233356 | 01 eerste verdieping | 2210.14 | 4539.7 | 0.090794 | 200667546 | 10033377
4260786 | 01 eerste verdieping | 3344 | 2020.16 | 0.0404033 | 135108609 | 6755430
4555035 | 01 eerste verdieping | 415.759 | 1279.58 | 0.0255915 | 10639912 | 531996
4558071 | 00 begane grond | 3340 | 313.5 | 0.00627 | 20941800 | 1047090
4560763 | 00 begane grond | 3340 | 340.5 | 0.00681 | 22745400 | 1137270
4563017 | 01 eerste verdieping | 3425.9 | 2612.49 | 0.0522499 | 179003003 | 8950150
4563067 | 00 begane grond | 3340 | 333.994 | 0.00667987 | 22310774 | 1115539
4563070 | 00 begane grond | 3340 | 593.887 | 0.0118777 | 39671642 | 1983582
4563107 | 00 begane grond | 3340 | 313.506 | 0.00627013 | 20942226 | 1047111
4563109 | 01 eerste verdieping | 3082.88 | 594.887 | 0.0118977 | 36679259 | 1833963
4929754 | 01 eerste verdieping | 1733 | 9702.77 | 0.194055 | 336298103 | 16814905
5329845 | 01 eerste verdieping | 3080 | 28725.1 | 0.574517 | 1769466195 | 88473310
5844309 | 01 eerste verdieping | 3760.01 | 24278.8 | 0.485576 | 1825770545 | 91288527
5886027 | 01 eerste verdieping | 3372.11 | 5297.64 | 0.105953 | 357283895 | 17864195
5886277 | 01 eerste verdieping | 3372.15 | 5276.4 | 0.105528 | 355856420 | 17792821
5886800 | 01 eerste verdieping | 3359.25 | 5279.64 | 0.105593 | 354712422 | 17735621
5887124 | 01 eerste verdieping | 3358.05 | 5280.11 | 0.105602 | 354617643 | 17730882
5887430 | 00 begane grond | 3396.86 | 544.638 | 0.0108928 | 37001110 | 1850055
5887486 | 00 begane grond | 3402.75 | 524.638 | 0.0104928 | 35704179 | 1785209
5888922 | 00 begane grond | 3340 | 613.887 | 0.0122777 | 41007642 | 2050382
5889175 | 01 eerste verdieping | 3082.88 | 614.887 | 0.0122977 | 37912410 | 1895620
5890063 | 00 begane grond | 3340 | 613.638 | 0.0122728 | 40991000 | 2049550
5890135 | 00 begane grond | 3340 | 608.887 | 0.0121777 | 40673642 | 2033682
5890338 | 01 eerste verdieping | 3082.85 | 608.887 | 0.0121777 | 37542167 | 1877108
5890481 | 01 eerste verdieping | 3082.87 | 613.638 | 0.0122728 | 37835329 | 1891766
5890664 | 00 begane grond | 3409.76 | 543.638 | 0.0108728 | 37073472 | 1853674
5890868 | 00 begane grond | 3421.28 | 513.857 | 0.0102771 | 35160907 | 1758045
6974024 | 01 eerste verdieping | 3067.96 | 7851.61 | 0.157032 | 481767732 | 24088387
8267564 | 01 eerste verdieping | 1395.82 | 409.211 | 0.00818423 | 11423686 | 571184
8374370 | 01 eerste verdieping | 1275 | 622.371 | 0.0124474 | 15870455 | 793523
8374520 | 01 eerste verdieping | 1275 | 615 | 0.0123 | 15682500 | 784125
9231122 | 00 begane grond | 2841.15 | 20628.3 | 0.412566 | 1172161409 | 58608070
9317692 | 00 begane grond | 2331 | 899.999 | 0.018 | 41957954 | 2097898
9320008 | 01 eerste verdieping | 2299.68 | 896.877 | 0.0179375 | 41250558 | 2062528
9320974 | 01 eerste verdieping | 2303 | 894.955 | 0.0178991 | 41221627 | 2061081

# IfcWallStandardCase: Basic Wall:NLRS_42_WA_Trespa RAL 7035 - 10mm (10)
Type - PredefinedType: STANDARD; Material: n6_kunststof_RAL 7035 10 mm
Type - Pset_ConcreteElementGeneral - FireRating: -
Type - Pset_ElementShading - Roughness: 304.8 mm
Type - Pset_ManufacturerTypeInformation - Manufacturer: NTB
Type - Pset_ProductRequirements - Category: Walls
Type - Pset_QuantityTakeOff - Reference: Basic Wall:NLRS_42_WA_Trespa RAL 7035 - 10mm
Type - Pset_ReinforcementBarPitchOfWall - Description: Trespa 10mm; Reference: Basic Wall:NLRS_42_WA_Trespa RAL 7035 - 10mm
Type - Pset_WallCommon - IsExternal: no; Reference: Basic Wall:NLRS_42_WA_Trespa RAL 7035 - 10mm; FireRating: -
Classification: 42.12 binnenwandafwerkingen; bekledingen (Uniformat)
BaseQuantities - Width: 10 mm
Pset_WallCommon - ExtendToStructure: no; LoadBearing: no
Name (Basic Wall:NLRS_42_WA_Trespa RAL 7035 - 10mm:...) | In | Height (mm) | Length (mm) | GrossFootprintArea (m2) | NetVolume (m3) | NetSideArea (m2)
3249027 | 01 eerste verdieping | 849.1 | 3283.69 | 0.0328369 | 27881836 | 2788184
4239610 | 01 eerste verdieping | 839.1 | 6070 | 0.0607 | 50933370 | 5093337
4616823 | 01 eerste verdieping | 839.1 | 3188.14 | 0.0318814 | 26751699 | 2675170
6306898 | 00 begane grond | 1696.33 | 334.449 | 0.00334449 | 5673369 | 567337
6307155 | 00 begane grond | 1695.67 | 337.172 | 0.00337172 | 5717322 | 571732
6307212 | 00 begane grond | 1683 | 257 | 0.00257 | 4325310 | 432531
6307331 | 00 begane grond | 257 | 3554.25 | 0.0355425 | 9134422 | 913442
6308520 | 00 begane grond | 257 | 3554.25 | 0.0355425 | 9134422 | 913442
6322052 | 00 begane grond | 1683 | 257.085 | 0.00257085 | 4326741 | 432674
9006755 | 00 begane grond | 839.1 | 1330 | 0.0133 | 11160030 | 1116003

# IfcWallStandardCase: Basic Wall:NLRS_42_WA_Trespa bruin (2)
In: 01 eerste verdieping
Type - PredefinedType: STANDARD; Material: AL Houten beplating gevel 18 mm
Type - Pset_ConcreteElementGeneral - FireRating: -
Type - Pset_ElementShading - Roughness: 304.8 mm
Type - Pset_ManufacturerTypeInformation - Manufacturer: NTB
Type - Pset_ProductRequirements - Category: Walls
Type - Pset_QuantityTakeOff - Reference: Basic Wall:NLRS_42_WA_Trespa bruin
Type - Pset_ReinforcementBarPitchOfWall - Description: Plaatmateriaal 18mm; Reference: Basic Wall:NLRS_42_WA_Trespa bruin
Type - Pset_WallCommon - IsExternal: no; Reference: Basic Wall:NLRS_42_WA_Trespa bruin; FireRating: -
Classification: 42.12 binnenwandafwerkingen; bekledingen (Uniformat)
BaseQuantities - Height: 1189.65 mm; Width: 18 mm
Pset_WallCommon - ExtendToStructure: no; LoadBearing: no
Name (Basic Wall:NLRS_42_WA_Trespa bruin:...) | Length (mm) | GrossFootprintArea (m2) | NetVolume (m3) | NetSideArea (m2)
4306161 | 1088.48 | 0.0195927 | 23308506 | 1294917
6317960 | 1070.48 | 0.0192687 | 22923058 | 1273503

# IfcWallStandardCase: Basic Wall:NLRS_42_WA_beplating_zijkant hellend dak (10)
In: 01 eerste verdieping
Type - PredefinedType: STANDARD; Material: h7_zink zwart 3 mm
Type - Pset_ConcreteElementGeneral - FireRating: -
Type - Pset_ElementShading - Roughness: 304.8 mm
Type - Pset_ManufacturerTypeInformation - Manufacturer: NTB
Type - Pset_ProductRequirements - Category: Walls
Type - Pset_QuantityTakeOff - Reference: Basic Wall:NLRS_42_WA_beplating_zijkant hellend dak
Type - Pset_ReinforcementBarPitchOfWall - Description: Plaatmateriaal 18mm; Reference: Basic Wall:NLRS_42_WA_beplating_zijkant hellend dak
Type - Pset_WallCommon - IsExternal: no; Reference: Basic Wall:NLRS_42_WA_beplating_zijkant hellend dak; FireRating: -; ThermalTransmittance: 37666.7 kg/K/s3
Classification: 41.12 buitenwandafwerkingen; bekledingen (Uniformat)
BaseQuantities - Width: 3 mm
Pset_WallCommon - ExtendToStructure: no; LoadBearing: no
Name (Basic Wall:NLRS_42_WA_beplating_zijkant hellend dak:...) | Height (mm) | Length (mm) | GrossFootprintArea (m2) | NetVolume (m3) | NetSideArea (m2)
3196827 | 3465.22 | 1743.02 | 0.00522906 | 18119824 | 6039941
4269666 | 3924.82 | 10993.4 | 0.0329803 | 129441550 | 43147183
4269959 | 359.156 | 422 | 0.001266 | 454691 | 151564
4848765 | 3321.08 | 341.307 | 0.00102392 | 3400529 | 1133510
4945661 | 3777.04 | 10537.4 | 0.0316123 | 119400883 | 39800294
5844555 | 3760.77 | 10532.7 | 0.031598 | 118832587 | 39610862
5844567 | 3315.34 | 386.616 | 0.00115985 | 3845281 | 1281760
9376562 | 196.664 | 121.274 | 0.000363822 | 71550.8 | 23850.3
9376780 | 197.045 | 155 | 0.000465 | 91625.9 | 30542
9440817 | 990 | 147.508 | 0.000442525 | 438099 | 146033

# IfcWindow: Bevestiging kozijn gymzaal:Bevestiging kozijn gymzaal, Bevestiging kozijn gymzaal:Bevestiging kozijn gymzaal:5913082
In: 01 eerste verdieping
Type - ParameterTakesPrecedence: no; Sizeable: no; Material: AL_31_Naaldhout (vuren)
Type - Pset_ProductRequirements - Category: Windows
Type - Pset_QuantityTakeOff - Reference: Bevestiging kozijn gymzaal:Bevestiging kozijn gymzaal
Type - Pset_WindowCommon - IsExternal: no; Reference: Bevestiging kozijn gymzaal:Bevestiging kozijn gymzaal
OverallHeight: 38 mm; OverallWidth: 216.942 mm
BaseQuantities - Area: 0.0080956 m2

# IfcWindow: Bevestiging overhead deur1:Bevestiging overhead deur, Bevestiging overhead deur1:Bevestiging overhead deur:10122655
In: 00 begane grond
Type - ParameterTakesPrecedence: no; Sizeable: no; Material: AL_31_Naaldhout (vuren)
Type - Pset_ProductRequirements - Category: Windows
Type - Pset_QuantityTakeOff - Reference: Bevestiging overhead deur1:Bevestiging overhead deur
Type - Pset_WindowCommon - IsExternal: no; Reference: Bevestiging overhead deur1:Bevestiging overhead deur
OverallHeight: 2695 mm; OverallWidth: 2676 mm
BaseQuantities - Area: 0.00912 m2

# IfcWindow: Hardstenen dorpel1:Hardstenen dorpel, Hardstenen dorpel1:Hardstenen dorpel:9768064
In: 00 begane grond
Type - ParameterTakesPrecedence: no; Sizeable: no; Material: NLRS_e_natuursteen
Type - Pset_ProductRequirements - Category: Windows
Type - Pset_QuantityTakeOff - Reference: Hardstenen dorpel1:Hardstenen dorpel
Type - Pset_WindowCommon - IsExternal: no; Reference: Hardstenen dorpel1:Hardstenen dorpel
OverallHeight: 70 mm; OverallWidth: 47 mm
BaseQuantities - Area: 0.086527 m2

# IfcWindow: Hardstenen dorpel2:Hardstenen dorpel, Hardstenen dorpel2:Hardstenen dorpel:9769047
In: 00 begane grond
Type - ParameterTakesPrecedence: no; Sizeable: no; Material: NLRS_e_natuursteen
Type - Pset_ProductRequirements - Category: Windows
Type - Pset_QuantityTakeOff - Reference: Hardstenen dorpel2:Hardstenen dorpel
Type - Pset_WindowCommon - IsExternal: no; Reference: Hardstenen dorpel2:Hardstenen dorpel
OverallHeight: 70 mm; OverallWidth: 47 mm
BaseQuantities - Area: 0.068479 m2

# IfcWindow: Hardstenen dorpel3:Hardstenen dorpel, Hardstenen dorpel3:Hardstenen dorpel:9769145
In: 00 begane grond
Type - ParameterTakesPrecedence: no; Sizeable: no; Material: NLRS_e_natuursteen
Type - Pset_ProductRequirements - Category: Windows
Type - Pset_QuantityTakeOff - Reference: Hardstenen dorpel3:Hardstenen dorpel
Type - Pset_WindowCommon - IsExternal: no; Reference: Hardstenen dorpel3:Hardstenen dorpel
OverallHeight: 70 mm; OverallWidth: 750 mm
BaseQuantities - Area: 0.03525 m2

# IfcWindow: Hardstenen dorpel4:Hardstenen dorpel, Hardstenen dorpel4:Hardstenen dorpel:9770139
In: 00 begane grond
Type - ParameterTakesPrecedence: no; Sizeable: no; Material: NLRS_e_natuursteen
Type - Pset_ProductRequirements - Category: Windows
Type - Pset_QuantityTakeOff - Reference: Hardstenen dorpel4:Hardstenen dorpel
Type - Pset_WindowCommon - IsExternal: no; Reference: Hardstenen dorpel4:Hardstenen dorpel
OverallHeight: 70 mm; OverallWidth: 47 mm
BaseQuantities - Area: 0.0423 m2

# IfcWindow: Hardstenen dorpel5:Hardstenen dorpel, Hardstenen dorpel5:Hardstenen dorpel:9771272
In: 00 begane grond
Type - ParameterTakesPrecedence: no; Sizeable: no; Material: NLRS_e_natuursteen
Type - Pset_ProductRequirements - Category: Windows
Type - Pset_QuantityTakeOff - Reference: Hardstenen dorpel5:Hardstenen dorpel
Type - Pset_WindowCommon - IsExternal: no; Reference: Hardstenen dorpel5:Hardstenen dorpel
OverallHeight: 70 mm; OverallWidth: 114 mm
BaseQuantities - Area: 0.262868 m2

# IfcWindow: Hardstenen dorpel:Hardstenen dorpel, Hardstenen dorpel:Hardstenen dorpel:9768007
In: 00 begane grond
Type - ParameterTakesPrecedence: no; Sizeable: no; Material: NLRS_e_natuursteen
Type - Pset_ProductRequirements - Category: Windows
Type - Pset_QuantityTakeOff - Reference: Hardstenen dorpel:Hardstenen dorpel
Type - Pset_WindowCommon - IsExternal: no; Reference: Hardstenen dorpel:Hardstenen dorpel
OverallHeight: 70 mm; OverallWidth: 47 mm
BaseQuantities - Area: 0.086527 m2

# IfcWindow: Hoek glazen pui2:Hoek glazen pui, Hoek glazen pui2:Hoek glazen pui:5883020
In: 00 begane grond
Type - ParameterTakesPrecedence: no; Sizeable: no; Material: NLRS_i3_hout_Loofhout (hardhout) RAL 9002
Type - Pset_ProductRequirements - Category: Windows
Type - Pset_QuantityTakeOff - Reference: Hoek glazen pui2:Hoek glazen pui
Type - Pset_WindowCommon - IsExternal: no; Reference: Hoek glazen pui2:Hoek glazen pui
OverallHeight: 2926 mm; OverallWidth: 120 mm
BaseQuantities - Area: 0.01368 m2

# IfcWindow: Hoek glazen pui:Hoek glazen pui, Hoek glazen pui:Hoek glazen pui:4201073
In: ok. fundering
Type - ParameterTakesPrecedence: no; Sizeable: no; Material: NLRS_i3_hout_Loofhout (hardhout) RAL 7035
Type - Pset_ProductRequirements - Category: Windows
Type - Pset_QuantityTakeOff - Reference: Hoek glazen pui:Hoek glazen pui
Type - Pset_WindowCommon - IsExternal: no; Reference: Hoek glazen pui:Hoek glazen pui
OverallHeight: 2980 mm; OverallWidth: 120 mm
BaseQuantities - Area: 0.0144 m2

# IfcWindow: NLRS_41_GM_UN_Aluminium waterslag Roval 305170:41.12_Aluminium waterslag Roval 305150 (14)
Type - ParameterTakesPrecedence: no; Sizeable: no; Classification: 41.12 buitenwandafwerkingen; bekledingen (Uniformat); Material: <Unnamed>
Type - Pset_ManufacturerTypeInformation - Manufacturer: Roval Aluminium
Type - Pset_ProductRequirements - Category: Windows
Type - Pset_QuantityTakeOff - Reference: NLRS_41_GM_UN_Aluminium waterslag Roval 305170:41.12_Aluminium waterslag Roval 305150
Type - Pset_WindowCommon - IsExternal: no; Reference: NLRS_41_GM_UN_Aluminium waterslag Roval 305170:41.12_Aluminium waterslag Roval 305150
OverallHeight: 75.7956 mm; OverallWidth: 450 mm; Material: f2_beton_grijs
BaseQuantities - Area: 0.114687 m2
Name (NLRS_41_GM_UN_Aluminium waterslag Roval 305170:41.12_Aluminium waterslag Roval 305150:...) | In
4381985 | 00 begane grond
4382550 | 00 begane grond
9890141 | 00 begane grond
9890149 | 00 begane grond
9890571 | 00 begane grond
9890581 | ok. fundering
9937851 | 00 begane grond
9937859 | 00 begane grond
9937873 | 00 begane grond
9937881 | ok. fundering
10268999 | 00 begane grond
10269075 | 00 begane grond
10269083 | 00 begane grond
10269091 | 00 begane grond

# IfcWindow: NLRS_41_GM_UN_Aluminium waterslag Roval 410075_gen_aly:41.12_Aluminium waterslag Roval 305150 (5)
Type - ParameterTakesPrecedence: no; Sizeable: no; Classification: 41.12 buitenwandafwerkingen; bekledingen (Uniformat); Material: <Unnamed>
Type - Pset_ManufacturerTypeInformation - Manufacturer: Roval Aluminium
Type - Pset_ProductRequirements - Category: Windows
Type - Pset_QuantityTakeOff - Reference: NLRS_41_GM_UN_Aluminium waterslag Roval 410075_gen_aly:41.12_Aluminium waterslag Roval 305150
Type - Pset_WindowCommon - IsExternal: no; Reference: NLRS_41_GM_UN_Aluminium waterslag Roval 410075_gen_aly:41.12_Aluminium waterslag Roval 305150
OverallHeight: 70.8562 mm; OverallWidth: 450 mm; Material: f2_beton_grijs
BaseQuantities - Area: 0.0639972 m2
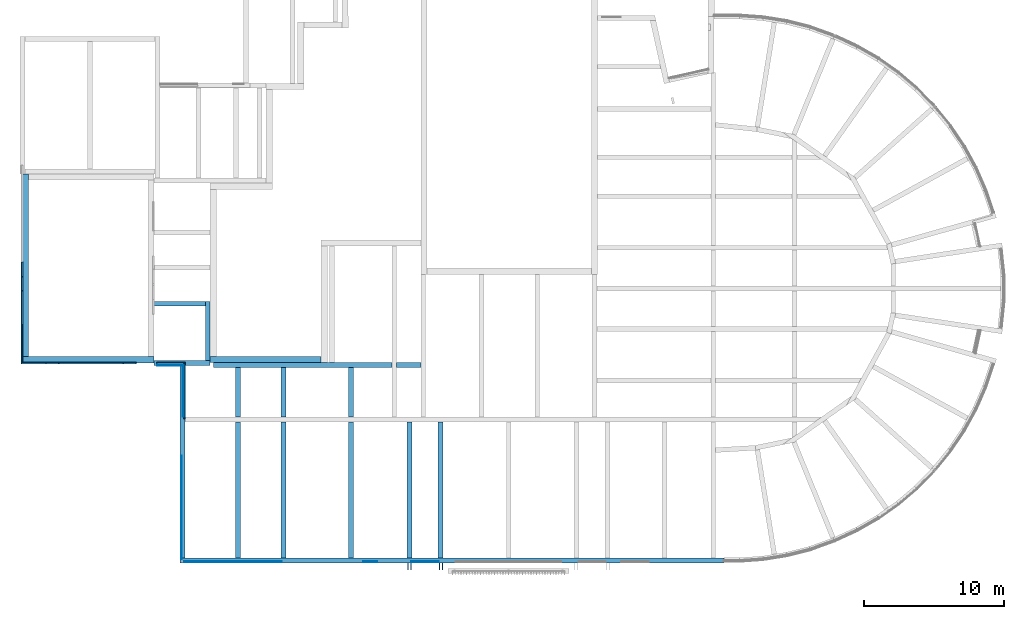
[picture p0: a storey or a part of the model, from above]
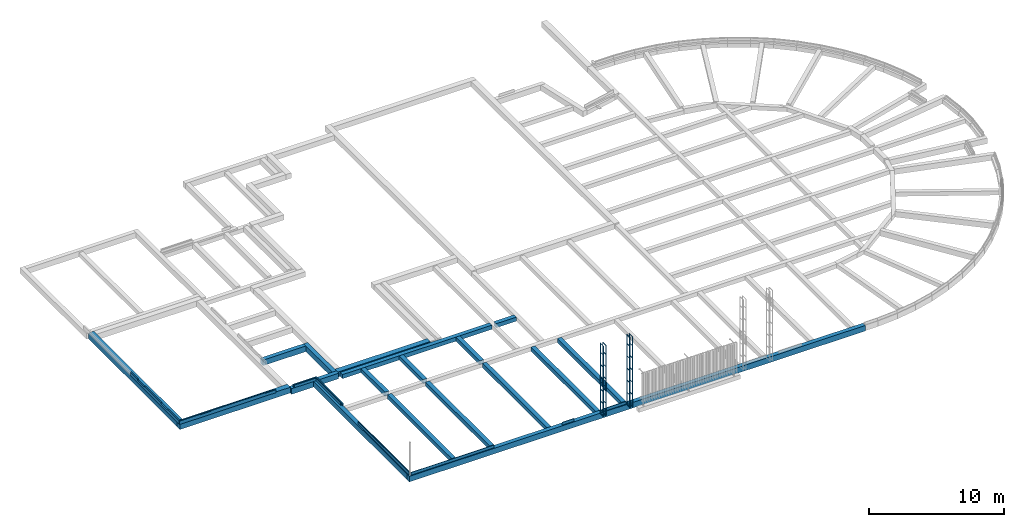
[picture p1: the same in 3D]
Properties of the parts of a building model (IFC2X3), part 13 of 13

# IfcWindow: NLRS_41_GM_UN_Aluminium waterslag Roval 410075_gen_aly:41.12_Aluminium waterslag Roval 305150 (5)
Name (NLRS_41_GM_UN_Aluminium waterslag Roval 410075_gen_aly:41.12_Aluminium waterslag Roval 305150:...) | In
9946222 | 01 eerste verdieping
9949793 | Podium
9949801 | Podium
9949811 | Podium
9949819 | 01 eerste verdieping

# IfcWindow: Selkozijn entree school:Selkozijn entree school, Selkozijn entree school:Selkozijn entree school:9191098
In: 00 begane grond
Type - ParameterTakesPrecedence: no; Sizeable: no; Material: AL_31_Naaldhout (vuren)
Type - Pset_ProductRequirements - Category: Windows
Type - Pset_QuantityTakeOff - Reference: Selkozijn entree school:Selkozijn entree school
Type - Pset_WindowCommon - IsExternal: no; Reference: Selkozijn entree school:Selkozijn entree school
OverallHeight: 3017 mm; OverallWidth: 2941.22 mm
BaseQuantities - Area: 0.699966 m2

# IfcWindow: Stelkozijn 10:Stelkozijn 1, Stelkozijn 10:Stelkozijn 1:5795874
In: 00 begane grond
Type - ParameterTakesPrecedence: no; Sizeable: no; Material: NLRS_i2_hout_naaldhout (vuren)
Type - Pset_ProductRequirements - Category: Windows
Type - Pset_QuantityTakeOff - Reference: Stelkozijn 10:Stelkozijn 1
Type - Pset_WindowCommon - IsExternal: no; Reference: Stelkozijn 10:Stelkozijn 1
OverallHeight: 2887.04 mm; OverallWidth: 7588.44 mm
BaseQuantities - Area: 0.490407 m2

# IfcWindow: Stelkozijn 11:Stelkozijn 1, Stelkozijn 11:Stelkozijn 1:5796082
In: 00 begane grond
Type - ParameterTakesPrecedence: no; Sizeable: no; Material: NLRS_i2_hout_naaldhout (vuren)
Type - Pset_ProductRequirements - Category: Windows
Type - Pset_QuantityTakeOff - Reference: Stelkozijn 11:Stelkozijn 1
Type - Pset_WindowCommon - IsExternal: no; Reference: Stelkozijn 11:Stelkozijn 1
OverallHeight: 2895.04 mm; OverallWidth: 2046 mm
BaseQuantities - Area: 0.340484 m2

# IfcWindow: Stelkozijn 12:Stelkozijn 1, Stelkozijn 12:Stelkozijn 1:5796142
In: 00 begane grond
Type - ParameterTakesPrecedence: no; Sizeable: no; Material: NLRS_i2_hout_naaldhout (vuren)
Type - Pset_ProductRequirements - Category: Windows
Type - Pset_QuantityTakeOff - Reference: Stelkozijn 12:Stelkozijn 1
Type - Pset_WindowCommon - IsExternal: no; Reference: Stelkozijn 12:Stelkozijn 1
OverallHeight: 2778 mm; OverallWidth: 2041 mm
BaseQuantities - Area: 0.329638 m2

# IfcWindow: Stelkozijn 13:Stelkozijn 1, Stelkozijn 13:Stelkozijn 1:10268223
In: 00 begane grond
Type - ParameterTakesPrecedence: no; Sizeable: no; Material: NLRS_i2_hout_naaldhout (vuren)
Type - Pset_ProductRequirements - Category: Windows
Type - Pset_QuantityTakeOff - Reference: Stelkozijn 13:Stelkozijn 1
Type - Pset_WindowCommon - IsExternal: no; Reference: Stelkozijn 13:Stelkozijn 1
OverallHeight: 1314.9 mm; OverallWidth: 516 mm
BaseQuantities - Area: 0.170966 m2

# IfcWindow: Stelkozijn 14:Stelkozijn 1, Stelkozijn 14:Stelkozijn 1:5944951
In: 00 begane grond
Type - ParameterTakesPrecedence: no; Sizeable: no; Material: NLRS_i2_hout_naaldhout (vuren)
Type - Pset_ProductRequirements - Category: Windows
Type - Pset_QuantityTakeOff - Reference: Stelkozijn 14:Stelkozijn 1
Type - Pset_WindowCommon - IsExternal: no; Reference: Stelkozijn 14:Stelkozijn 1
OverallHeight: 2778 mm; OverallWidth: 7778.91 mm
BaseQuantities - Area: 0.442943 m2

# IfcWindow: Stelkozijn 15:Stelkozijn 1, Stelkozijn 15:Stelkozijn 1:5808914
In: 00 begane grond
Type - ParameterTakesPrecedence: no; Sizeable: no; Material: NLRS_i2_hout_naaldhout (vuren)
Type - Pset_ProductRequirements - Category: Windows
Type - Pset_QuantityTakeOff - Reference: Stelkozijn 15:Stelkozijn 1
Type - Pset_WindowCommon - IsExternal: no; Reference: Stelkozijn 15:Stelkozijn 1
OverallHeight: 1561 mm; OverallWidth: 228.989 mm
BaseQuantities - Area: 0.196068 m2

# IfcWindow: Stelkozijn 16:Stelkozijn 1, Stelkozijn 16:Stelkozijn 1:5809552
In: 00 begane grond
Type - ParameterTakesPrecedence: no; Sizeable: no; Material: NLRS_i2_hout_naaldhout (vuren)
Type - Pset_ProductRequirements - Category: Windows
Type - Pset_QuantityTakeOff - Reference: Stelkozijn 16:Stelkozijn 1
Type - Pset_WindowCommon - IsExternal: no; Reference: Stelkozijn 16:Stelkozijn 1
OverallHeight: 1560.9 mm; OverallWidth: 228.989 mm
BaseQuantities - Area: 0.196058 m2

# IfcWindow: Stelkozijn 17:Stelkozijn 1, Stelkozijn 17:Stelkozijn 1:9453941
In: 00 begane grond
Type - ParameterTakesPrecedence: no; Sizeable: no; Material: NLRS_i2_hout_naaldhout (vuren)
Type - Pset_ProductRequirements - Category: Windows
Type - Pset_QuantityTakeOff - Reference: Stelkozijn 17:Stelkozijn 1
Type - Pset_WindowCommon - IsExternal: no; Reference: Stelkozijn 17:Stelkozijn 1
OverallHeight: 1561.6 mm; OverallWidth: 228.989 mm
BaseQuantities - Area: 0.196129 m2

# IfcWindow: Stelkozijn 18:Stelkozijn 1, Stelkozijn 18:Stelkozijn 1:5809956
In: 00 begane grond
Type - ParameterTakesPrecedence: no; Sizeable: no; Material: NLRS_i2_hout_naaldhout (vuren)
Type - Pset_ProductRequirements - Category: Windows
Type - Pset_QuantityTakeOff - Reference: Stelkozijn 18:Stelkozijn 1
Type - Pset_WindowCommon - IsExternal: no; Reference: Stelkozijn 18:Stelkozijn 1
OverallHeight: 1561 mm; OverallWidth: 228.989 mm
BaseQuantities - Area: 0.196068 m2

# IfcWindow: Stelkozijn 19:Stelkozijn 1, Stelkozijn 19:Stelkozijn 1:5809994
In: 00 begane grond
Type - ParameterTakesPrecedence: no; Sizeable: no; Material: NLRS_i2_hout_naaldhout (vuren)
Type - Pset_ProductRequirements - Category: Windows
Type - Pset_QuantityTakeOff - Reference: Stelkozijn 19:Stelkozijn 1
Type - Pset_WindowCommon - IsExternal: no; Reference: Stelkozijn 19:Stelkozijn 1
OverallHeight: 1561 mm; OverallWidth: 228.989 mm
BaseQuantities - Area: 0.196068 m2

# IfcWindow: Stelkozijn 1:Stelkozijn 1, Stelkozijn 1:Stelkozijn 1:10239120
In: 00 begane grond
Type - ParameterTakesPrecedence: no; Sizeable: no; Material: NLRS_i2_hout_naaldhout (vuren)
Type - Pset_ProductRequirements - Category: Windows
Type - Pset_QuantityTakeOff - Reference: Stelkozijn 1:Stelkozijn 1
Type - Pset_WindowCommon - IsExternal: no; Reference: Stelkozijn 1:Stelkozijn 1
OverallHeight: 2811 mm; OverallWidth: 802 mm
BaseQuantities - Area: 0.318252 m2

# IfcWindow: Stelkozijn 20:Stelkozijn 1, Stelkozijn 20:Stelkozijn 1:11999767
In: 00 begane grond
Type - ParameterTakesPrecedence: no; Sizeable: no; Material: NLRS_i2_hout_naaldhout (vuren)
Type - Pset_ProductRequirements - Category: Windows
Type - Pset_QuantityTakeOff - Reference: Stelkozijn 20:Stelkozijn 1
Type - Pset_WindowCommon - IsExternal: no; Reference: Stelkozijn 20:Stelkozijn 1
OverallHeight: 1302 mm; OverallWidth: 120 mm
BaseQuantities - Area: 0.157872 m2

# IfcWindow: Stelkozijn 21:Stelkozijn 1, Stelkozijn 21:Stelkozijn 1:11999818
In: 00 begane grond
Type - ParameterTakesPrecedence: no; Sizeable: no; Material: NLRS_i2_hout_naaldhout (vuren)
Type - Pset_ProductRequirements - Category: Windows
Type - Pset_QuantityTakeOff - Reference: Stelkozijn 21:Stelkozijn 1
Type - Pset_WindowCommon - IsExternal: no; Reference: Stelkozijn 21:Stelkozijn 1
OverallHeight: 1302 mm; OverallWidth: 120 mm
BaseQuantities - Area: 0.157872 m2

# IfcWindow: Stelkozijn 22:Stelkozijn 1, Stelkozijn 22:Stelkozijn 1:5812292
In: 00 begane grond
Type - ParameterTakesPrecedence: no; Sizeable: no; Material: NLRS_i2_hout_naaldhout (vuren)
Type - Pset_ProductRequirements - Category: Windows
Type - Pset_QuantityTakeOff - Reference: Stelkozijn 22:Stelkozijn 1
Type - Pset_WindowCommon - IsExternal: no; Reference: Stelkozijn 22:Stelkozijn 1
OverallHeight: 1302 mm; OverallWidth: 120 mm
BaseQuantities - Area: 0.157872 m2

# IfcWindow: Stelkozijn 23:Stelkozijn 1, Stelkozijn 23:Stelkozijn 1:5812760
In: 00 begane grond
Type - ParameterTakesPrecedence: no; Sizeable: no; Material: NLRS_i2_hout_naaldhout (vuren)
Type - Pset_ProductRequirements - Category: Windows
Type - Pset_QuantityTakeOff - Reference: Stelkozijn 23:Stelkozijn 1
Type - Pset_WindowCommon - IsExternal: no; Reference: Stelkozijn 23:Stelkozijn 1
OverallHeight: 2811 mm; OverallWidth: 1386 mm
BaseQuantities - Area: 0.367308 m2

# IfcWindow: Stelkozijn 24:Stelkozijn 1, Stelkozijn 24:Stelkozijn 1:5831046
In: 00 begane grond
Type - ParameterTakesPrecedence: no; Sizeable: no; Material: NLRS_i2_hout_naaldhout (vuren)
Type - Pset_ProductRequirements - Category: Windows
Type - Pset_QuantityTakeOff - Reference: Stelkozijn 24:Stelkozijn 1
Type - Pset_WindowCommon - IsExternal: no; Reference: Stelkozijn 24:Stelkozijn 1
OverallHeight: 2934 mm; OverallWidth: 1872 mm
BaseQuantities - Area: 0.181184 m2

# IfcWindow: Stelkozijn 25:Stelkozijn 1, Stelkozijn 25:Stelkozijn 1:5831703
In: 00 begane grond
Type - ParameterTakesPrecedence: no; Sizeable: no; Material: NLRS_i2_hout_naaldhout (vuren)
Type - Pset_ProductRequirements - Category: Windows
Type - Pset_QuantityTakeOff - Reference: Stelkozijn 25:Stelkozijn 1
Type - Pset_WindowCommon - IsExternal: no; Reference: Stelkozijn 25:Stelkozijn 1
OverallHeight: 38 mm; OverallWidth: 125 mm
BaseQuantities - Area: 0.141876 m2

# IfcWindow: Stelkozijn 26:Stelkozijn 1, Stelkozijn 26:Stelkozijn 1:5908912
In: 00 begane grond
Type - ParameterTakesPrecedence: no; Sizeable: no; Material: NLRS_i2_hout_naaldhout (vuren)
Type - Pset_ProductRequirements - Category: Windows
Type - Pset_QuantityTakeOff - Reference: Stelkozijn 26:Stelkozijn 1
Type - Pset_WindowCommon - IsExternal: no; Reference: Stelkozijn 26:Stelkozijn 1
OverallHeight: 2778 mm; OverallWidth: 7124.18 mm
BaseQuantities - Area: 0.391279 m2

# IfcWindow: Stelkozijn 27:Stelkozijn 1, Stelkozijn 27:Stelkozijn 1:5909764
In: 00 begane grond
Type - ParameterTakesPrecedence: no; Sizeable: no; Material: NLRS_i2_hout_naaldhout (vuren)
Type - Pset_ProductRequirements - Category: Windows
Type - Pset_QuantityTakeOff - Reference: Stelkozijn 27:Stelkozijn 1
Type - Pset_WindowCommon - IsExternal: no; Reference: Stelkozijn 27:Stelkozijn 1
OverallHeight: 5345.22 mm; OverallWidth: 120 mm
BaseQuantities - Area: 0.51976 m2

# IfcWindow: Stelkozijn 28:Stelkozijn 1, Stelkozijn 28:Stelkozijn 1:6046665
In: 00 begane grond
Type - ParameterTakesPrecedence: no; Sizeable: no; Material: NLRS_i2_hout_naaldhout (vuren)
Type - Pset_ProductRequirements - Category: Windows
Type - Pset_QuantityTakeOff - Reference: Stelkozijn 28:Stelkozijn 1
Type - Pset_WindowCommon - IsExternal: no; Reference: Stelkozijn 28:Stelkozijn 1
OverallHeight: 3283 mm; OverallWidth: 7876 mm
BaseQuantities - Area: 0.545908 m2

# IfcWindow: Stelkozijn 29:Stelkozijn 1, Stelkozijn 29:Stelkozijn 1:5975213
In: 00 begane grond
Type - ParameterTakesPrecedence: no; Sizeable: no; Material: NLRS_i2_hout_naaldhout (vuren)
Type - Pset_ProductRequirements - Category: Windows
Type - Pset_QuantityTakeOff - Reference: Stelkozijn 29:Stelkozijn 1
Type - Pset_WindowCommon - IsExternal: no; Reference: Stelkozijn 29:Stelkozijn 1
OverallHeight: 2808 mm; OverallWidth: 110 mm
BaseQuantities - Area: 0.371006 m2

# IfcWindow: Stelkozijn 2:Stelkozijn 1, Stelkozijn 2:Stelkozijn 1:10268028
In: 00 begane grond
Type - ParameterTakesPrecedence: no; Sizeable: no; Material: NLRS_i2_hout_naaldhout (vuren)
Type - Pset_ProductRequirements - Category: Windows
Type - Pset_QuantityTakeOff - Reference: Stelkozijn 2:Stelkozijn 1
Type - Pset_WindowCommon - IsExternal: no; Reference: Stelkozijn 2:Stelkozijn 1
OverallHeight: 1314.9 mm; OverallWidth: 516 mm
BaseQuantities - Area: 0.170966 m2

# IfcWindow: Stelkozijn 30:Stelkozijn 1, Stelkozijn 30:Stelkozijn 1:6065430
In: 00 begane grond
Type - ParameterTakesPrecedence: no; Sizeable: no; Material: NLRS_i2_hout_naaldhout (vuren)
Type - Pset_ProductRequirements - Category: Windows
Type - Pset_QuantityTakeOff - Reference: Stelkozijn 30:Stelkozijn 1
Type - Pset_WindowCommon - IsExternal: no; Reference: Stelkozijn 30:Stelkozijn 1
OverallHeight: 2778 mm; OverallWidth: 327.19 mm
BaseQuantities - Area: 0.343567 m2

# IfcWindow: Stelkozijn 31:Stelkozijn 1, Stelkozijn 31:Stelkozijn 1:6064421
In: 00 begane grond
Type - ParameterTakesPrecedence: no; Sizeable: no; Material: NLRS_i2_hout_naaldhout (vuren)
Type - Pset_ProductRequirements - Category: Windows
Type - Pset_QuantityTakeOff - Reference: Stelkozijn 31:Stelkozijn 1
Type - Pset_WindowCommon - IsExternal: no; Reference: Stelkozijn 31:Stelkozijn 1
OverallHeight: 38 mm; OverallWidth: 6999.24 mm
BaseQuantities - Area: 0.51564 m2

# IfcWindow: Stelkozijn 32:Stelkozijn 1, Stelkozijn 32:Stelkozijn 1:6064579
In: 00 begane grond
Type - ParameterTakesPrecedence: no; Sizeable: no; Material: NLRS_i2_hout_naaldhout (vuren)
Type - Pset_ProductRequirements - Category: Windows
Type - Pset_QuantityTakeOff - Reference: Stelkozijn 32:Stelkozijn 1
Type - Pset_WindowCommon - IsExternal: no; Reference: Stelkozijn 32:Stelkozijn 1
OverallHeight: 2778 mm; OverallWidth: 4153.26 mm
BaseQuantities - Area: 0.519098 m2

# IfcWindow: Stelkozijn 33:Stelkozijn 1, Stelkozijn 33:Stelkozijn 1:6065064
In: 00 begane grond
Type - ParameterTakesPrecedence: no; Sizeable: no; Material: NLRS_i2_hout_naaldhout (vuren)
Type - Pset_ProductRequirements - Category: Windows
Type - Pset_QuantityTakeOff - Reference: Stelkozijn 33:Stelkozijn 1
Type - Pset_WindowCommon - IsExternal: no; Reference: Stelkozijn 33:Stelkozijn 1
OverallHeight: 2778 mm; OverallWidth: 8504.58 mm
BaseQuantities - Area: 0.525395 m2

# IfcWindow: Stelkozijn 34:Stelkozijn 1, Stelkozijn 34:Stelkozijn 1:6065087
In: 00 begane grond
Type - ParameterTakesPrecedence: no; Sizeable: no; Material: NLRS_i2_hout_naaldhout (vuren)
Type - Pset_ProductRequirements - Category: Windows
Type - Pset_QuantityTakeOff - Reference: Stelkozijn 34:Stelkozijn 1
Type - Pset_WindowCommon - IsExternal: no; Reference: Stelkozijn 34:Stelkozijn 1
OverallHeight: 38 mm; OverallWidth: 6999.24 mm
BaseQuantities - Area: 0.51564 m2

# IfcWindow: Stelkozijn 35:Stelkozijn 1, Stelkozijn 35:Stelkozijn 1:6065110
In: 00 begane grond
Type - ParameterTakesPrecedence: no; Sizeable: no; Material: NLRS_i2_hout_naaldhout (vuren)
Type - Pset_ProductRequirements - Category: Windows
Type - Pset_QuantityTakeOff - Reference: Stelkozijn 35:Stelkozijn 1
Type - Pset_WindowCommon - IsExternal: no; Reference: Stelkozijn 35:Stelkozijn 1
OverallHeight: 2768 mm; OverallWidth: 4151.54 mm
BaseQuantities - Area: 0.517598 m2

# IfcWindow: Stelkozijn 36:Stelkozijn 1, Stelkozijn 36:Stelkozijn 1:7566342
In: 00 begane grond
Type - ParameterTakesPrecedence: no; Sizeable: no; Material: NLRS_i2_hout_naaldhout (vuren)
Type - Pset_ProductRequirements - Category: Windows
Type - Pset_QuantityTakeOff - Reference: Stelkozijn 36:Stelkozijn 1
Type - Pset_WindowCommon - IsExternal: no; Reference: Stelkozijn 36:Stelkozijn 1
OverallHeight: 2653 mm; OverallWidth: 110 mm
BaseQuantities - Area: 0.235828 m2

# IfcWindow: Stelkozijn 37:Stelkozijn 1, Stelkozijn 37:Stelkozijn 1:10268263
In: 00 begane grond
Type - ParameterTakesPrecedence: no; Sizeable: no; Material: NLRS_i2_hout_naaldhout (vuren)
Type - Pset_ProductRequirements - Category: Windows
Type - Pset_QuantityTakeOff - Reference: Stelkozijn 37:Stelkozijn 1
Type - Pset_WindowCommon - IsExternal: no; Reference: Stelkozijn 37:Stelkozijn 1
OverallHeight: 1314.9 mm; OverallWidth: 516 mm
BaseQuantities - Area: 0.170966 m2

# IfcWindow: Stelkozijn 38:Stelkozijn 1, Stelkozijn 38:Stelkozijn 1:6861031
In: 00 begane grond
Type - ParameterTakesPrecedence: no; Sizeable: no; Material: NLRS_i2_hout_naaldhout (vuren)
Type - Pset_ProductRequirements - Category: Windows
Type - Pset_QuantityTakeOff - Reference: Stelkozijn 38:Stelkozijn 1
Type - Pset_WindowCommon - IsExternal: no; Reference: Stelkozijn 38:Stelkozijn 1
OverallHeight: 2653 mm; OverallWidth: 110 mm
BaseQuantities - Area: 0.235828 m2

# IfcWindow: Stelkozijn 39:Stelkozijn 1, Stelkozijn 39:Stelkozijn 1:11997504
In: Podium
Type - ParameterTakesPrecedence: no; Sizeable: no; Material: NLRS_i2_hout_naaldhout (vuren)
Type - Pset_ProductRequirements - Category: Windows
Type - Pset_QuantityTakeOff - Reference: Stelkozijn 39:Stelkozijn 1
Type - Pset_WindowCommon - IsExternal: no; Reference: Stelkozijn 39:Stelkozijn 1
OverallHeight: 1302 mm; OverallWidth: 506 mm
BaseQuantities - Area: 0.157872 m2

# IfcWindow: Stelkozijn 3:Stelkozijn 1, Stelkozijn 3:Stelkozijn 1:8104303
In: Podium
Type - ParameterTakesPrecedence: no; Sizeable: no; Material: NLRS_i2_hout_naaldhout (vuren)
Type - Pset_ProductRequirements - Category: Windows
Type - Pset_QuantityTakeOff - Reference: Stelkozijn 3:Stelkozijn 1
Type - Pset_WindowCommon - IsExternal: no; Reference: Stelkozijn 3:Stelkozijn 1
OverallHeight: 1302 mm; OverallWidth: 506 mm
BaseQuantities - Area: 0.157872 m2

# IfcWindow: Stelkozijn 5:Stelkozijn 1, Stelkozijn 5:Stelkozijn 1:10268183
In: 00 begane grond
Type - ParameterTakesPrecedence: no; Sizeable: no; Material: NLRS_i2_hout_naaldhout (vuren)
Type - Pset_ProductRequirements - Category: Windows
Type - Pset_QuantityTakeOff - Reference: Stelkozijn 5:Stelkozijn 1
Type - Pset_WindowCommon - IsExternal: no; Reference: Stelkozijn 5:Stelkozijn 1
OverallHeight: 1314.9 mm; OverallWidth: 516 mm
BaseQuantities - Area: 0.170966 m2

# IfcWindow: Stelkozijn 6:Stelkozijn 1, Stelkozijn 6:Stelkozijn 1:7566304
In: 00 begane grond
Type - ParameterTakesPrecedence: no; Sizeable: no; Material: NLRS_i2_hout_naaldhout (vuren)
Type - Pset_ProductRequirements - Category: Windows
Type - Pset_QuantityTakeOff - Reference: Stelkozijn 6:Stelkozijn 1
Type - Pset_WindowCommon - IsExternal: no; Reference: Stelkozijn 6:Stelkozijn 1
OverallHeight: 2653 mm; OverallWidth: 110 mm
BaseQuantities - Area: 0.235828 m2

# IfcWindow: Stelkozijn 7:Stelkozijn 1, Stelkozijn 7:Stelkozijn 1:5794324
In: 00 begane grond
Type - ParameterTakesPrecedence: no; Sizeable: no; Material: NLRS_i2_hout_naaldhout (vuren)
Type - Pset_ProductRequirements - Category: Windows
Type - Pset_QuantityTakeOff - Reference: Stelkozijn 7:Stelkozijn 1
Type - Pset_WindowCommon - IsExternal: no; Reference: Stelkozijn 7:Stelkozijn 1
OverallHeight: 2805 mm; OverallWidth: 2726.09 mm
BaseQuantities - Area: 0.358156 m2

# IfcWindow: Stelkozijn 8:Stelkozijn 1, Stelkozijn 8:Stelkozijn 1:5942783
In: 00 begane grond
Type - ParameterTakesPrecedence: no; Sizeable: no; Material: NLRS_i2_hout_naaldhout (vuren)
Type - Pset_ProductRequirements - Category: Windows
Type - Pset_QuantityTakeOff - Reference: Stelkozijn 8:Stelkozijn 1
Type - Pset_WindowCommon - IsExternal: no; Reference: Stelkozijn 8:Stelkozijn 1
OverallHeight: 2519 mm; OverallWidth: 1124 mm
BaseQuantities - Area: 0.267516 m2

# IfcWindow: Stelkozijn 9:Stelkozijn 1, Stelkozijn 9:Stelkozijn 1:5795604
In: 00 begane grond
Type - ParameterTakesPrecedence: no; Sizeable: no; Material: NLRS_i2_hout_naaldhout (vuren)
Type - Pset_ProductRequirements - Category: Windows
Type - Pset_QuantityTakeOff - Reference: Stelkozijn 9:Stelkozijn 1
Type - Pset_WindowCommon - IsExternal: no; Reference: Stelkozijn 9:Stelkozijn 1
OverallHeight: 2895.04 mm; OverallWidth: 2046 mm
BaseQuantities - Area: 0.340502 m2

# IfcWindow: Verbinding ronde pui10:Verbinding ronde pui, Verbinding ronde pui10:Verbinding ronde pui:5567244
In: 00 begane grond
Type - ParameterTakesPrecedence: no; Sizeable: no; Material: NLRS_n6_kunststof_DTS-basis black
Type - Pset_ProductRequirements - Category: Windows
Type - Pset_QuantityTakeOff - Reference: Verbinding ronde pui10:Verbinding ronde pui
Type - Pset_WindowCommon - IsExternal: no; Reference: Verbinding ronde pui10:Verbinding ronde pui
OverallHeight: 2740 mm; OverallWidth: 100.733 mm; Material: NLRS_n6_kunststof_DTS-basis black, NLRS_i3_hout_Loofhout (hardhout) RAL 7035
BaseQuantities - Area: 0.010285 m2

# IfcWindow: Verbinding ronde pui11:Verbinding ronde pui, Verbinding ronde pui11:Verbinding ronde pui:5567264
In: 00 begane grond
Type - ParameterTakesPrecedence: no; Sizeable: no; Material: NLRS_n6_kunststof_DTS-basis black
Type - Pset_ProductRequirements - Category: Windows
Type - Pset_QuantityTakeOff - Reference: Verbinding ronde pui11:Verbinding ronde pui
Type - Pset_WindowCommon - IsExternal: no; Reference: Verbinding ronde pui11:Verbinding ronde pui
OverallHeight: 2740 mm; OverallWidth: 107.38 mm; Material: NLRS_n6_kunststof_DTS-basis black, NLRS_i3_hout_Loofhout (hardhout) RAL 7035
BaseQuantities - Area: 0.010285 m2

# IfcWindow: Verbinding ronde pui12:Verbinding ronde pui, Verbinding ronde pui12:Verbinding ronde pui:3115667
In: 00 begane grond
Type - ParameterTakesPrecedence: no; Sizeable: no; Material: NLRS_n6_kunststof_DTS-basis black
Type - Pset_ProductRequirements - Category: Windows
Type - Pset_QuantityTakeOff - Reference: Verbinding ronde pui12:Verbinding ronde pui
Type - Pset_WindowCommon - IsExternal: no; Reference: Verbinding ronde pui12:Verbinding ronde pui
OverallHeight: 2740 mm; OverallWidth: 121.962 mm; Material: NLRS_n6_kunststof_DTS-basis black, NLRS_i3_hout_Loofhout (hardhout) RAL 7035
BaseQuantities - Area: 0.0104624 m2

# IfcWindow: Verbinding ronde pui13:Verbinding ronde pui, Verbinding ronde pui13:Verbinding ronde pui:5580039
In: 00 begane grond
Type - ParameterTakesPrecedence: no; Sizeable: no; Material: NLRS_n6_kunststof_DTS-basis black
Type - Pset_ProductRequirements - Category: Windows
Type - Pset_QuantityTakeOff - Reference: Verbinding ronde pui13:Verbinding ronde pui
Type - Pset_WindowCommon - IsExternal: no; Reference: Verbinding ronde pui13:Verbinding ronde pui
OverallHeight: 2740 mm; OverallWidth: 121.954 mm; Material: NLRS_n6_kunststof_DTS-basis black, NLRS_i3_hout_Loofhout (hardhout) RAL 7035
BaseQuantities - Area: 0.010462 m2

# IfcWindow: Verbinding ronde pui14:Verbinding ronde pui, Verbinding ronde pui14:Verbinding ronde pui:5567284
In: 00 begane grond
Type - ParameterTakesPrecedence: no; Sizeable: no; Material: NLRS_n6_kunststof_DTS-basis black
Type - Pset_ProductRequirements - Category: Windows
Type - Pset_QuantityTakeOff - Reference: Verbinding ronde pui14:Verbinding ronde pui
Type - Pset_WindowCommon - IsExternal: no; Reference: Verbinding ronde pui14:Verbinding ronde pui
OverallHeight: 2740 mm; OverallWidth: 113.139 mm; Material: NLRS_n6_kunststof_DTS-basis black, NLRS_i3_hout_Loofhout (hardhout) RAL 7035
BaseQuantities - Area: 0.0102851 m2

# IfcWindow: Verbinding ronde pui15:Verbinding ronde pui, Verbinding ronde pui15:Verbinding ronde pui:5567442
In: 00 begane grond
Type - ParameterTakesPrecedence: no; Sizeable: no; Material: NLRS_n6_kunststof_DTS-basis black
Type - Pset_ProductRequirements - Category: Windows
Type - Pset_QuantityTakeOff - Reference: Verbinding ronde pui15:Verbinding ronde pui
Type - Pset_WindowCommon - IsExternal: no; Reference: Verbinding ronde pui15:Verbinding ronde pui
OverallHeight: 2740 mm; OverallWidth: 127.288 mm; Material: NLRS_n6_kunststof_DTS-basis black, NLRS_i3_hout_Loofhout (hardhout) RAL 7035
BaseQuantities - Area: 0.010285 m2

# IfcWindow: Verbinding ronde pui16:Verbinding ronde pui, Verbinding ronde pui16:Verbinding ronde pui:5567463
In: 00 begane grond
Type - ParameterTakesPrecedence: no; Sizeable: no; Material: NLRS_n6_kunststof_DTS-basis black
Type - Pset_ProductRequirements - Category: Windows
Type - Pset_QuantityTakeOff - Reference: Verbinding ronde pui16:Verbinding ronde pui
Type - Pset_WindowCommon - IsExternal: no; Reference: Verbinding ronde pui16:Verbinding ronde pui
OverallHeight: 2740 mm; OverallWidth: 126.502 mm; Material: NLRS_n6_kunststof_DTS-basis black, NLRS_i3_hout_Loofhout (hardhout) RAL 7035
BaseQuantities - Area: 0.010285 m2

# IfcWindow: Verbinding ronde pui17:Verbinding ronde pui, Verbinding ronde pui17:Verbinding ronde pui:5567483
In: 00 begane grond
Type - ParameterTakesPrecedence: no; Sizeable: no; Material: NLRS_n6_kunststof_DTS-basis black
Type - Pset_ProductRequirements - Category: Windows
Type - Pset_QuantityTakeOff - Reference: Verbinding ronde pui17:Verbinding ronde pui
Type - Pset_WindowCommon - IsExternal: no; Reference: Verbinding ronde pui17:Verbinding ronde pui
OverallHeight: 2740 mm; OverallWidth: 124.672 mm; Material: NLRS_n6_kunststof_DTS-basis black, NLRS_i3_hout_Loofhout (hardhout) RAL 7035
BaseQuantities - Area: 0.010285 m2

# IfcWindow: Verbinding ronde pui18:Verbinding ronde pui, Verbinding ronde pui18:Verbinding ronde pui:5567503
In: 00 begane grond
Type - ParameterTakesPrecedence: no; Sizeable: no; Material: NLRS_n6_kunststof_DTS-basis black
Type - Pset_ProductRequirements - Category: Windows
Type - Pset_QuantityTakeOff - Reference: Verbinding ronde pui18:Verbinding ronde pui
Type - Pset_WindowCommon - IsExternal: no; Reference: Verbinding ronde pui18:Verbinding ronde pui
OverallHeight: 2740 mm; OverallWidth: 121.818 mm; Material: NLRS_n6_kunststof_DTS-basis black, NLRS_i3_hout_Loofhout (hardhout) RAL 7035
BaseQuantities - Area: 0.010285 m2

# IfcWindow: Verbinding ronde pui19:Verbinding ronde pui, Verbinding ronde pui19:Verbinding ronde pui:7537651
In: 00 begane grond
Type - ParameterTakesPrecedence: no; Sizeable: no; Material: NLRS_n6_kunststof_DTS-basis black
Type - Pset_ProductRequirements - Category: Windows
Type - Pset_QuantityTakeOff - Reference: Verbinding ronde pui19:Verbinding ronde pui
Type - Pset_WindowCommon - IsExternal: no; Reference: Verbinding ronde pui19:Verbinding ronde pui
OverallHeight: 2740 mm; OverallWidth: 68.7427 mm; Material: NLRS_n6_kunststof_DTS-basis black, NLRS_i3_hout_Loofhout (hardhout) RAL 7035
BaseQuantities - Area: 0.0108103 m2

# IfcWindow: Verbinding ronde pui1:Verbinding ronde pui, Verbinding ronde pui1:Verbinding ronde pui:3109402
In: 00 begane grond
Type - ParameterTakesPrecedence: no; Sizeable: no; Material: NLRS_n6_kunststof_DTS-basis black
Type - Pset_ProductRequirements - Category: Windows
Type - Pset_QuantityTakeOff - Reference: Verbinding ronde pui1:Verbinding ronde pui
Type - Pset_WindowCommon - IsExternal: no; Reference: Verbinding ronde pui1:Verbinding ronde pui
OverallHeight: 2740 mm; OverallWidth: 59.9477 mm; Material: NLRS_n6_kunststof_DTS-basis black, NLRS_i3_hout_Loofhout (hardhout) RAL 7035
BaseQuantities - Area: 0.0111166 m2

# IfcWindow: Verbinding ronde pui20:Verbinding ronde pui, Verbinding ronde pui20:Verbinding ronde pui:7537865
In: 00 begane grond
Type - ParameterTakesPrecedence: no; Sizeable: no; Material: NLRS_n6_kunststof_DTS-basis black
Type - Pset_ProductRequirements - Category: Windows
Type - Pset_QuantityTakeOff - Reference: Verbinding ronde pui20:Verbinding ronde pui
Type - Pset_WindowCommon - IsExternal: no; Reference: Verbinding ronde pui20:Verbinding ronde pui
OverallHeight: 2740 mm; OverallWidth: 58.2551 mm; Material: NLRS_n6_kunststof_DTS-basis black, NLRS_i3_hout_Loofhout (hardhout) RAL 7035
BaseQuantities - Area: 0.0108102 m2

# IfcWindow: Verbinding ronde pui21:Verbinding ronde pui, Verbinding ronde pui21:Verbinding ronde pui:7537998
In: 00 begane grond
Type - ParameterTakesPrecedence: no; Sizeable: no; Material: NLRS_n6_kunststof_DTS-basis black
Type - Pset_ProductRequirements - Category: Windows
Type - Pset_QuantityTakeOff - Reference: Verbinding ronde pui21:Verbinding ronde pui
Type - Pset_WindowCommon - IsExternal: no; Reference: Verbinding ronde pui21:Verbinding ronde pui
OverallHeight: 2740 mm; OverallWidth: 47.4244 mm; Material: NLRS_n6_kunststof_DTS-basis black, NLRS_i3_hout_Loofhout (hardhout) RAL 7035
BaseQuantities - Area: 0.0104365 m2

# IfcWindow: Verbinding ronde pui22:Verbinding ronde pui, Verbinding ronde pui22:Verbinding ronde pui:5568103
In: 00 begane grond
Type - ParameterTakesPrecedence: no; Sizeable: no; Material: NLRS_n6_kunststof_DTS-basis black
Type - Pset_ProductRequirements - Category: Windows
Type - Pset_QuantityTakeOff - Reference: Verbinding ronde pui22:Verbinding ronde pui
Type - Pset_WindowCommon - IsExternal: no; Reference: Verbinding ronde pui22:Verbinding ronde pui
OverallHeight: 2740 mm; OverallWidth: 78.5011 mm; Material: NLRS_n6_kunststof_DTS-basis black, NLRS_i3_hout_Loofhout (hardhout) RAL 7035
BaseQuantities - Area: 0.0108102 m2

# IfcWindow: Verbinding ronde pui26:Verbinding ronde pui, Verbinding ronde pui26:Verbinding ronde pui:3111797
In: 00 begane grond
Type - ParameterTakesPrecedence: no; Sizeable: no; Material: NLRS_n6_kunststof_DTS-basis black
Type - Pset_ProductRequirements - Category: Windows
Type - Pset_QuantityTakeOff - Reference: Verbinding ronde pui26:Verbinding ronde pui
Type - Pset_WindowCommon - IsExternal: no; Reference: Verbinding ronde pui26:Verbinding ronde pui
OverallHeight: 2740 mm; OverallWidth: 95.5351 mm; Material: NLRS_n6_kunststof_DTS-basis black, NLRS_i3_hout_Loofhout (hardhout) RAL 7035
BaseQuantities - Area: 0.0108921 m2

# IfcWindow: Verbinding ronde pui27:Verbinding ronde pui, Verbinding ronde pui27:Verbinding ronde pui:5560610
In: 00 begane grond
Type - ParameterTakesPrecedence: no; Sizeable: no; Material: NLRS_n6_kunststof_DTS-basis black
Type - Pset_ProductRequirements - Category: Windows
Type - Pset_QuantityTakeOff - Reference: Verbinding ronde pui27:Verbinding ronde pui
Type - Pset_WindowCommon - IsExternal: no; Reference: Verbinding ronde pui27:Verbinding ronde pui
OverallHeight: 2740 mm; OverallWidth: 100.73 mm; Material: NLRS_n6_kunststof_DTS-basis black, NLRS_i3_hout_Loofhout (hardhout) RAL 7035
BaseQuantities - Area: 0.0102845 m2

# IfcWindow: Verbinding ronde pui28:Verbinding ronde pui, Verbinding ronde pui28:Verbinding ronde pui:5560757
In: 00 begane grond
Type - ParameterTakesPrecedence: no; Sizeable: no; Material: NLRS_n6_kunststof_DTS-basis black
Type - Pset_ProductRequirements - Category: Windows
Type - Pset_QuantityTakeOff - Reference: Verbinding ronde pui28:Verbinding ronde pui
Type - Pset_WindowCommon - IsExternal: no; Reference: Verbinding ronde pui28:Verbinding ronde pui
OverallHeight: 2740 mm; OverallWidth: 107.376 mm; Material: NLRS_n6_kunststof_DTS-basis black, NLRS_i3_hout_Loofhout (hardhout) RAL 7035
BaseQuantities - Area: 0.0102845 m2

# IfcWindow: Verbinding ronde pui29:Verbinding ronde pui, Verbinding ronde pui29:Verbinding ronde pui:5560889
In: 00 begane grond
Type - ParameterTakesPrecedence: no; Sizeable: no; Material: NLRS_n6_kunststof_DTS-basis black
Type - Pset_ProductRequirements - Category: Windows
Type - Pset_QuantityTakeOff - Reference: Verbinding ronde pui29:Verbinding ronde pui
Type - Pset_WindowCommon - IsExternal: no; Reference: Verbinding ronde pui29:Verbinding ronde pui
OverallHeight: 2740 mm; OverallWidth: 113.134 mm; Material: NLRS_n6_kunststof_DTS-basis black, NLRS_i3_hout_Loofhout (hardhout) RAL 7035
BaseQuantities - Area: 0.0102845 m2

# IfcWindow: Verbinding ronde pui2:Verbinding ronde pui, Verbinding ronde pui2:Verbinding ronde pui:3110074
In: 00 begane grond
Type - ParameterTakesPrecedence: no; Sizeable: no; Material: NLRS_n6_kunststof_DTS-basis black
Type - Pset_ProductRequirements - Category: Windows
Type - Pset_QuantityTakeOff - Reference: Verbinding ronde pui2:Verbinding ronde pui
Type - Pset_WindowCommon - IsExternal: no; Reference: Verbinding ronde pui2:Verbinding ronde pui
OverallHeight: 2740 mm; OverallWidth: 70.5087 mm; Material: NLRS_n6_kunststof_DTS-basis black, NLRS_i3_hout_Loofhout (hardhout) RAL 7035
BaseQuantities - Area: 0.0113023 m2

# IfcWindow: Verbinding ronde pui3:Verbinding ronde pui, Verbinding ronde pui3:Verbinding ronde pui:3110170
In: 00 begane grond
Type - ParameterTakesPrecedence: no; Sizeable: no; Material: NLRS_n6_kunststof_DTS-basis black
Type - Pset_ProductRequirements - Category: Windows
Type - Pset_QuantityTakeOff - Reference: Verbinding ronde pui3:Verbinding ronde pui
Type - Pset_WindowCommon - IsExternal: no; Reference: Verbinding ronde pui3:Verbinding ronde pui
OverallHeight: 2740 mm; OverallWidth: 80.3229 mm; Material: NLRS_n6_kunststof_DTS-basis black, NLRS_i3_hout_Loofhout (hardhout) RAL 7035
BaseQuantities - Area: 0.011289 m2

# IfcWindow: Verbinding ronde pui5:Verbinding ronde pui, Verbinding ronde pui5:Verbinding ronde pui:5598036
In: 00 begane grond
Type - ParameterTakesPrecedence: no; Sizeable: no; Material: NLRS_n6_kunststof_DTS-basis black
Type - Pset_ProductRequirements - Category: Windows
Type - Pset_QuantityTakeOff - Reference: Verbinding ronde pui5:Verbinding ronde pui
Type - Pset_WindowCommon - IsExternal: no; Reference: Verbinding ronde pui5:Verbinding ronde pui
OverallHeight: 2740 mm; OverallWidth: 127.285 mm; Material: NLRS_n6_kunststof_DTS-basis black, NLRS_i3_hout_Loofhout (hardhout) RAL 7035
BaseQuantities - Area: 0.0102848 m2

# IfcWindow: Verbinding ronde pui6:Verbinding ronde pui, Verbinding ronde pui6:Verbinding ronde pui:5565263
In: 00 begane grond
Type - ParameterTakesPrecedence: no; Sizeable: no; Material: NLRS_n6_kunststof_DTS-basis black
Type - Pset_ProductRequirements - Category: Windows
Type - Pset_QuantityTakeOff - Reference: Verbinding ronde pui6:Verbinding ronde pui
Type - Pset_WindowCommon - IsExternal: no; Reference: Verbinding ronde pui6:Verbinding ronde pui
OverallHeight: 2740 mm; OverallWidth: 126.495 mm; Material: NLRS_n6_kunststof_DTS-basis black, NLRS_i3_hout_Loofhout (hardhout) RAL 7035
BaseQuantities - Area: 0.0102845 m2

# IfcWindow: Verbinding ronde pui7:Verbinding ronde pui, Verbinding ronde pui7:Verbinding ronde pui:5565283
In: 00 begane grond
Type - ParameterTakesPrecedence: no; Sizeable: no; Material: NLRS_n6_kunststof_DTS-basis black
Type - Pset_ProductRequirements - Category: Windows
Type - Pset_QuantityTakeOff - Reference: Verbinding ronde pui7:Verbinding ronde pui
Type - Pset_WindowCommon - IsExternal: no; Reference: Verbinding ronde pui7:Verbinding ronde pui
OverallHeight: 2740 mm; OverallWidth: 124.666 mm; Material: NLRS_n6_kunststof_DTS-basis black, NLRS_i3_hout_Loofhout (hardhout) RAL 7035
BaseQuantities - Area: 0.0102845 m2

# IfcWindow: Verbinding ronde pui8:Verbinding ronde pui, Verbinding ronde pui8:Verbinding ronde pui:5565303
In: 00 begane grond
Type - ParameterTakesPrecedence: no; Sizeable: no; Material: NLRS_n6_kunststof_DTS-basis black
Type - Pset_ProductRequirements - Category: Windows
Type - Pset_QuantityTakeOff - Reference: Verbinding ronde pui8:Verbinding ronde pui
Type - Pset_WindowCommon - IsExternal: no; Reference: Verbinding ronde pui8:Verbinding ronde pui
OverallHeight: 2740 mm; OverallWidth: 121.811 mm; Material: NLRS_n6_kunststof_DTS-basis black, NLRS_i3_hout_Loofhout (hardhout) RAL 7035
BaseQuantities - Area: 0.0102845 m2

# IfcWindow: Verbinding ronde pui9:Verbinding ronde pui, Verbinding ronde pui9:Verbinding ronde pui:5567223
In: 00 begane grond
Type - ParameterTakesPrecedence: no; Sizeable: no; Material: NLRS_n6_kunststof_DTS-basis black
Type - Pset_ProductRequirements - Category: Windows
Type - Pset_QuantityTakeOff - Reference: Verbinding ronde pui9:Verbinding ronde pui
Type - Pset_WindowCommon - IsExternal: no; Reference: Verbinding ronde pui9:Verbinding ronde pui
OverallHeight: 2740 mm; OverallWidth: 93.2615 mm; Material: NLRS_n6_kunststof_DTS-basis black, NLRS_i3_hout_Loofhout (hardhout) RAL 7035
BaseQuantities - Area: 0.010285 m2

# IfcWindow: Verbinding ronde pui:Verbinding ronde pui, Verbinding ronde pui:Verbinding ronde pui:3108943
In: 00 begane grond
Type - ParameterTakesPrecedence: no; Sizeable: no; Material: NLRS_n6_kunststof_DTS-basis black
Type - Pset_ProductRequirements - Category: Windows
Type - Pset_QuantityTakeOff - Reference: Verbinding ronde pui:Verbinding ronde pui
Type - Pset_WindowCommon - IsExternal: no; Reference: Verbinding ronde pui:Verbinding ronde pui
OverallHeight: 2740 mm; OverallWidth: 49.0855 mm; Material: NLRS_n6_kunststof_DTS-basis black, NLRS_i3_hout_Loofhout (hardhout) RAL 7035
BaseQuantities - Area: 0.0107412 m2

# IfcWindow: Zinken dakbedekking erkerkozijn:Zinken dakbedekking erkerkozijn, Zinken dakbedekking erkerkozijn:Zinken dakbedekking erkerkozijn:6309272
In: Podium
Type - ParameterTakesPrecedence: no; Sizeable: no; Material: AL_Aluminium RAL 7035
Type - Pset_ProductRequirements - Category: Windows
Type - Pset_QuantityTakeOff - Reference: Zinken dakbedekking erkerkozijn:Zinken dakbedekking erkerkozijn
Type - Pset_WindowCommon - IsExternal: no; Reference: Zinken dakbedekking erkerkozijn:Zinken dakbedekking erkerkozijn
OverallHeight: 98.0476 mm; OverallWidth: 4050 mm
BaseQuantities - Area: 1.83791 m2

# IfcWindow: Zonwering zijgevel:Zonwering zijgevel, Zonwering zijgevel:Zonwering zijgevel:3257388
In: ok. fundering
Type - ParameterTakesPrecedence: no; Sizeable: no; Material: AL Houten beplating gevel erker sportkantine, NLRS_h3_staal_verzinkt
Type - Pset_ProductRequirements - Category: Windows
Type - Pset_QuantityTakeOff - Reference: Zonwering zijgevel:Zonwering zijgevel
Type - Pset_WindowCommon - IsExternal: no; Reference: Zonwering zijgevel:Zonwering zijgevel
OverallHeight: 3055.51 mm; OverallWidth: 8075 mm
BaseQuantities - Area: 2.54604 m2

# IfcStairFlightType, no part of this type: Non-Monolithic Run:50 mm Tread 10 mm Nosing 13 mm Riser
Pset_ProductRequirements - Category: Runs
Pset_QuantityTakeOff - Reference: Non-Monolithic Run:50 mm Tread 10 mm Nosing 13 mm Riser
Pset_StairFlightCommon - Reference: Non-Monolithic Run:50 mm Tread 10 mm Nosing 13 mm Riser; NosingLength: 10 mm

# IfcStairFlightType, no part of this type: Non-Monolithic Run:50 mm Tread 10 mm Nosing 13 mm Riser
Pset_ProductRequirements - Category: Runs
Pset_QuantityTakeOff - Reference: Non-Monolithic Run:50 mm Tread 10 mm Nosing 13 mm Riser
Pset_StairFlightCommon - Reference: Non-Monolithic Run:50 mm Tread 10 mm Nosing 13 mm Riser; NosingLength: 10 mm
